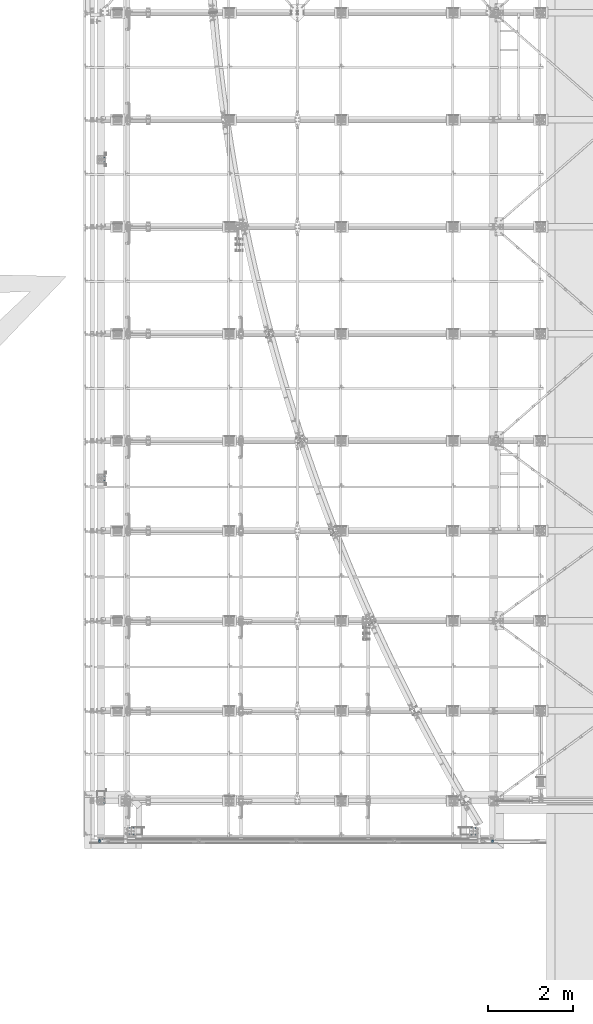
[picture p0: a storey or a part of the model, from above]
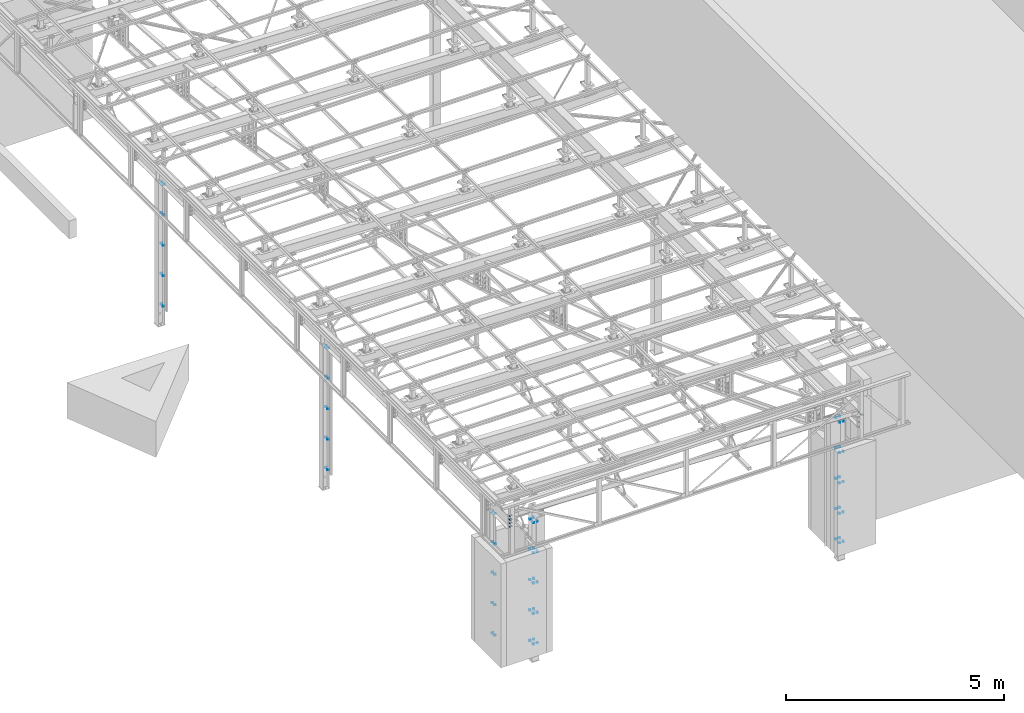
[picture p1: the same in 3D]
Properties of the parts of a building model (IFC2X3), part 1 of 13

# File
Description: ViewDefinition[CoordinationView_V2.0, QuantityTakeOffAddOnView], ExchangeRequirement[Structural, SurfaceGeometry], Option [BaseQuantities:On], Option [GridExport:On], Option [Assemblies:On], Option [Bolts:On], Option [Rebars:On], Option [PourObjects:Off], Option [Welds:On], Option [SurfaceTreatments:On], Option [LocationBy:0], Option [ViewColors:On], Option [SectionedSpine:Off], Option [PropertySets:On], Option [Export all:Off]
File name: VILQUIN_2021.ifc
Time: 2022-09-29T22:21:54
Author: BOINEAUP\Administrateur
Organization: Structural Designer
Written by: IFC Database Version: Work
Made in: Tekla Structures Educational 2021 Service Pack 6, IFC Export Version: 4.0.0.0 Dec 9 2021

# IfcBuildingStorey, Undefined
In: Undefined
Elevation: 0 mm

# IfcBeam: BLL100*50*2, LISSE
In: Undefined
Description: BLL100*50*2; Material: STEEL/E24-2
Tekla Commun - Finition: GALVA; Repère de pièce: L121; Repère d'assemblage: L121; Phase: 7; Profil: BLL100*50*2; Nom: LISSE; sets with these values: 2
Tekla Quantités - Poids: 4.6 kg; Volume: 0 m3; Surface supérieure totale: 0 m2; Surface par tonne: 129.2 m2; Surface nette: 0.6 m2; Hauteur: 100 mm; Largeur: 50 mm; Longueur: 2000 mm; sets with these values: 2
Pset_BeamCommon - LoadBearing: no; Reference: L121
BaseQuantities - Length: 2000 mm; OuterSurfaceArea: 0.600592 m2; NetVolume: 0.000592 m3; NetWeight: 4.6472 kg

# IfcBeam: BLL300*60*1.5 (2)
In: Undefined
Description: BLL300*60*1.5; Material: STEEL/E24-2
Tekla Commun - Finition: GALVA; Phase: 7; Profil: BLL300*60*1.5; Nom: LISSE; sets with these values: 2
Tekla Quantités - Volume: 0 m3; Surface supérieure totale: 0 m2; Hauteur: 300 mm; Largeur: 60 mm; sets with these values: 2
Pset_BeamCommon - LoadBearing: no
Name | Repère de pièce = Repère d'assemblage = Reference | Poids (kg) | Surface par tonne (m2) | Surface nette (m2) | Longueur (mm) | Length (mm) | OuterSurfaceArea (m2) | NetVolume (m3) | NetWeight (kg)
LISSE | L120 | 12.7 | 170.6 | 2.2 | 3000 | 3000 | 2.16108 | 0.00161325 | 12.664
LISSE | L119 | 14.4 | 170.8 | 2.5 | 3781.8 | 3781.82 | 2.46101 | 0.0018357 | 14.4102

# IfcBeam: BLU300*80*5 (6)
In: Undefined
Description: BLU300*80*5; Material: STEEL/E24-2
Tekla Commun - Finition: GRENAILLE-PEINT; Phase: 1; Profil: BLU300*80*5; sets with these values: 2
Tekla Quantités - Volume: 0 m3; Surface supérieure totale: 0 m2; Surface par tonne: 51.6 m2; Hauteur: 300 mm; Largeur: 80 mm; sets with these values: 2
Pset_BeamCommon - LoadBearing: no
Name | Repère de pièce = Reference | Repère d'assemblage | Nom | Poids (kg) | Surface nette (m2) | Longueur (mm) | Length (mm) | OuterSurfaceArea (m2) | NetVolume (m3) | NetWeight (kg)
LINTEAU | 889 | L5 | LINTEAU | 61.6 | 3.2 | 3488 | 3488 | 3.17858 | 0.007848 | 61.6068
LINTEAU | 888 | L4 | LINTEAU | 49.2 | 2.5 | 2788 | 2788 | 2.54158 | 0.006273 | 49.243
POTEAUX | 887 | P112 | POTEAUX | 87.9 | 4.4 | 4978.5 | 4978.52 | 4.53495 | 0.0112017 | 87.9331
POTEAUX | 886 | P111 | POTEAUX | 89.5 | 4.6 | 5067 | 5067.02 | 4.61549 | 0.0114008 | 89.4962
POTEAUX | 885 | P109 | POTEAUX | 89.7 | 4.6 | 5076.4 | 5076.4 | 4.62402 | 0.0114219 | 89.6619
POTEAUX | 884 | P110 | POTEAUX | 90.1 | 4.6 | 5099.1 | 5099.11 | 4.64469 | 0.011473 | 90.063

# IfcBeam: FPL255*8 (4)
In: Undefined
Description: FPL255*8; Material: STEEL/E24-2
Tekla Commun - Finition: GRENAILLE-PEINT; Phase: 1; Profil: FPL255*8; Nom: ATTACHE; sets with these values: 2
Tekla Quantités - Volume: 0 m3; Surface supérieure totale: 0 m2; Surface nette: 0.1 m2; Hauteur: 8 mm; Largeur: 255 mm; sets with these values: 2
Pset_BeamCommon - LoadBearing: no
Name | Repère de pièce = Repère d'assemblage = Reference | Poids (kg) | Surface par tonne (m2) | Longueur (mm) | Length (mm) | OuterSurfaceArea (m2) | NetVolume (m3) | NetWeight (kg)
ATTACHE | H54 | 3.2 | 34.1 | 78.3 | 78.2518 | 0.109281 | 0.000408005 | 3.20284
ATTACHE | H53 | 3 | 34.3 | 112.4 | 112.412 | 0.0987614 | 0.000367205 | 2.88256
ATTACHE | H52 | 3.2 | 34.1 | 132.4 | 132.412 | 0.109281 | 0.000408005 | 3.20284
ATTACHE | H51 | 3.4 | 34.1 | 132.4 | 132.376 | 0.114888 | 0.00042975 | 3.37354

# IfcBeam: FPL3*3600 (6)
In: Undefined
Description: FPL3*3600; Material: STEEL/S235JR
Tekla Commun - Finition: TOLGALVA; Phase: 5; Profil: FPL3*3600; Nom: FEUILLURE; sets with these values: 2
Tekla Quantités - Volume: 0 m3; Surface supérieure totale: 0 m2; Hauteur: 3 mm; Largeur: 3600 mm; sets with these values: 2
Pset_BeamCommon - LoadBearing: no
Name | Repère de pièce = Reference | Repère d'assemblage | Poids (kg) | Surface par tonne (m2) | Surface nette (m2) | Longueur (mm) = Length (mm) | OuterSurfaceArea (m2) | NetVolume (m3) | NetWeight (kg)
FEUILLURE | 1373 | F2 | 39.5 | 85.5 | 3.4 | 275 | 3.3796 | 0.0050328 | 39.5075
FEUILLURE | 1374 | F1 | 36.1 | 85.6 | 3.1 | 235 | 3.09136 | 0.0046008 | 36.1163
FEUILLURE | 1376 | F3 | 19.2 | 86.1 | 1.7 | 207 | 1.65736 | 0.0024516 | 19.2451
FEUILLURE | 1375 | F3 | 39.9 | 85.5 | 3.4 | 260 | 3.41563 | 0.0050868 | 39.9314
2 x FEUILLURE | F4 | F4 | 41.5 | 85.5 | 3.4 | 320 | 3.53813 | 0.0052704 | 41.3726

# IfcBeam: FPL370*6, ATTACHE
In: Undefined
Description: FPL370*6; Material: STEEL/E24-2
Tekla Commun - Finition: GRENAILLE-PEINT; Repère de pièce: H48; Repère d'assemblage: H48; Phase: 7; Profil: FPL370*6; Nom: ATTACHE; sets with these values: 2
Tekla Quantités - Poids: 3.4 kg; Volume: 0 m3; Surface supérieure totale: 0 m2; Surface par tonne: 44.5 m2; Surface nette: 0.2 m2; Hauteur: 6 mm; Largeur: 370 mm; Longueur: 83.9 mm; sets with these values: 2
Pset_BeamCommon - LoadBearing: no; Reference: H48
BaseQuantities - Length: 83.9094 mm; OuterSurfaceArea: 0.150577 m2; NetVolume: 0.000431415 m3; NetWeight: 3.38661 kg

# IfcBeam: FPL6*1050 (3)
In: Undefined
Description: FPL6*1050; Material: STEEL/E24-2
Tekla Commun - Finition: GRENAILLE-PEINT; Profil: FPL6*1050; sets with these values: 2
Tekla Quantités - Poids: 4.8 kg; Volume: 0 m3; Surface supérieure totale: 0 m2; Surface par tonne: 45.3 m2; Surface nette: 0.2 m2; Hauteur: 6 mm; Largeur: 1050 mm; Longueur: 55 mm; sets with these values: 2
Pset_BeamCommon - LoadBearing: no
BaseQuantities - Length: 55 mm; OuterSurfaceArea: 0.21852 m2; NetVolume: 0.00061425 m3; NetWeight: 4.82186 kg
Name | Repère de pièce = Reference | Repère d'assemblage | Phase
Unnamed | 862 | P32 | 3
2 x Unnamed | 863 | P36 | 1

# IfcBeam: FPL6*120 (18)
In: Undefined
Description: FPL6*120; Material: STEEL/E24-2
Tekla Commun - Finition: GRENAILLE-PEINT; Profil: FPL6*120; Nom: ATTACHE; sets with these values: 2
Tekla Quantités - Poids: 0.9 kg; Volume: 0 m3; Surface supérieure totale: 0 m2; Surface par tonne: 46.4 m2; Surface nette: 0 m2; Hauteur: 6 mm; Largeur: 120 mm; Longueur: 75 mm; sets with these values: 2
Pset_BeamCommon - LoadBearing: no
BaseQuantities - Length: 75.0488 mm
Name | Repère de pièce = Repère d'assemblage = Reference | Phase | OuterSurfaceArea (m2) | NetVolume (m3) | NetWeight (kg)
7 x ATTACHE | H49 | 3 | 0.0367986 | 0.000101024 | 0.793042
10 x ATTACHE | H49 | 1 | 0.0367986 | 0.000101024 | 0.793042
ATTACHE | H46 | 1 | 0.0361478 | 0.0000993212 | 0.779671

# IfcBeam: FPL6*50 (92)
In: Undefined
Description: FPL6*50; Material: STEEL/E24-2
Tekla Commun - Finition: GRENAILLE-PEINT; Repère de pièce: H47; Repère d'assemblage: H47; Profil: FPL6*50; Nom: ATTACHE; sets with these values: 2
Tekla Quantités - Poids: 0.3 kg; Volume: 0 m3; Surface supérieure totale: 0 m2; Surface par tonne: 49.1 m2; Surface nette: 0 m2; Hauteur: 6 mm; Largeur: 50 mm; sets with these values: 2
Pset_BeamCommon - LoadBearing: no; Reference: H47
BaseQuantities - OuterSurfaceArea: 0.0192984 m2; NetVolume: 0.000050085 m3; NetWeight: 0.393167 kg
Name | Phase | Longueur (mm) | Length (mm)
14 x ATTACHE | 2 | 111.9 | 111.95
14 x ATTACHE | 2 | 61 | 61
32 x ATTACHE | 1 | 61 | 61
32 x ATTACHE | 1 | 111.9 | 111.95

# IfcBeam: FPL6*86 (16)
In: Undefined
Description: FPL6*86; Material: STEEL/S235JR
Tekla Commun - Finition: GRENAILLE-PEINT; Repère de pièce: 861; Profil: FPL6*86; Nom: PLAT; sets with these values: 2
Tekla Quantités - Poids: 0.6 kg; Volume: 0 m3; Surface supérieure totale: 0 m2; Surface par tonne: 47 m2; Surface nette: 0 m2; Hauteur: 6 mm; Largeur: 86 mm; Longueur: 101 mm; sets with these values: 2
Pset_BeamCommon - LoadBearing: no; Reference: 861
BaseQuantities - Length: 101 mm; OuterSurfaceArea: 0.030656 m2; NetVolume: 0.000083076 m3; NetWeight: 0.652147 kg
Name | Repère d'assemblage | Phase
2 x PLAT | L22 | 3
2 x PLAT | L23 | 1
4 x PLAT | L22 | 1
2 x PLAT | L24 | 3
4 x PLAT | L21 | 1
2 x PLAT | L21 | 3

# IfcBeam: FPL6*90 (32)
In: Undefined
Description: FPL6*90; Material: STEEL/E24-2
Tekla Commun - Finition: GRENAILLE-PEINT; Repère de pièce: H45; Repère d'assemblage: H45; Phase: 1; Profil: FPL6*90; Nom: ATTACHE; sets with these values: 2
Tekla Quantités - Poids: 0.6 kg; Volume: 0 m3; Surface supérieure totale: 0 m2; Surface par tonne: 46.8 m2; Surface nette: 0 m2; Hauteur: 6 mm; Largeur: 90 mm; sets with these values: 2
Pset_BeamCommon - LoadBearing: no; Reference: H45
BaseQuantities - OuterSurfaceArea: 0.0331344 m2; NetVolume: 0.000090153 m3; NetWeight: 0.707701 kg
Name | Longueur (mm) | Length (mm)
16 x ATTACHE | 61 | 61
16 x ATTACHE | 111.9 | 111.95

# IfcBeam: FPL60*5 (8)
In: Undefined
Description: FPL60*5; Material: STEEL/S235JR
Tekla Commun - Finition: GRENAILLE-PEINT; Repère de pièce: H93; Repère d'assemblage: H93; Phase: 3; Profil: FPL60*5; Nom: ATTACHE; sets with these values: 2
Tekla Quantités - Poids: 0.5 kg; Volume: 0 m3; Surface supérieure totale: 0 m2; Surface par tonne: 56.4 m2; Surface nette: 0 m2; Hauteur: 5 mm; Largeur: 60 mm; Longueur: 110 mm; sets with these values: 2
Pset_BeamCommon - LoadBearing: no; Reference: H93
BaseQuantities - Length: 110 mm; OuterSurfaceArea: 0.02855 m2; NetVolume: 0.0000645 m3; NetWeight: 0.506325 kg

# IfcBeam: FPL8*140 (2)
In: Undefined
Description: FPL8*140; Material: STEEL/E24-2
Tekla Commun - Finition: GRENAILLE-PEINT; Repère de pièce: 1020; Phase: 1; Profil: FPL8*140; Nom: ATTACHE; sets with these values: 2
Tekla Quantités - Poids: 1.2 kg; Volume: 0 m3; Surface supérieure totale: 0 m2; Surface par tonne: 35.3 m2; Surface nette: 0 m2; Hauteur: 8 mm; Largeur: 140 mm; Longueur: 100 mm; sets with these values: 2
Pset_BeamCommon - LoadBearing: no; Reference: 1020
BaseQuantities - Length: 99.9683 mm; OuterSurfaceArea: 0.0445821 m2; NetVolume: 0.000160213 m3; NetWeight: 1.25767 kg
Name | Repère d'assemblage
ATTACHE | M13
ATTACHE | M14

# IfcBeam: FPL8*210 (15)
In: Undefined
Description: FPL8*210; Material: STEEL/S235JR
Tekla Commun - Finition: GRENAILLE-PEINT; Phase: 2; Profil: FPL8*210; Nom: GOUSSET; sets with these values: 2
Tekla Quantités - Volume: 0 m3; Surface supérieure totale: 0 m2; Surface nette: 0.1 m2; Hauteur: 8 mm; Largeur: 210 mm; sets with these values: 2
Pset_BeamCommon - LoadBearing: no
Name | Repère de pièce = Repère d'assemblage = Reference | Poids (kg) | Surface par tonne (m2) | Longueur (mm) | Length (mm) | OuterSurfaceArea (m2) | NetVolume (m3) | NetWeight (kg)
GOUSSET | G83 | 3.1 | 34.3 | 292.1 | 292.114 | 0.1071 | 0.000397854 | 3.12316
GOUSSET | G69 | 2.4 | 34.3 | 200.5 | 200.457 | 0.0822747 | 0.000304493 | 2.39027
GOUSSET | G80 | 2.1 | 34.9 | 200.5 | 200.457 | 0.0746716 | 0.000272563 | 2.13962
GOUSSET | G79 | 2.1 | 34.9 | 200.5 | 200.457 | 0.0746716 | 0.000272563 | 2.13962
GOUSSET | G82 | 2.1 | 34.9 | 200.5 | 200.457 | 0.0736308 | 0.000268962 | 2.11135
GOUSSET | G81 | 2.4 | 34.3 | 200.5 | 200.457 | 0.0812341 | 0.000300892 | 2.362
GOUSSET | G70 | 2.4 | 34.3 | 200.5 | 200.457 | 0.0822747 | 0.000304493 | 2.39027
GOUSSET | G78 | 2.1 | 34.9 | 200.5 | 200.457 | 0.0746716 | 0.000272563 | 2.13962
GOUSSET | G77 | 2.1 | 34.9 | 200.5 | 200.457 | 0.0746716 | 0.000272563 | 2.13962
GOUSSET | G71 | 2.4 | 34.3 | 200.5 | 200.457 | 0.0822747 | 0.000304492 | 2.39026
GOUSSET | G72 | 2.4 | 34.3 | 200.5 | 200.457 | 0.0822747 | 0.000304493 | 2.39027
GOUSSET | G73 | 2.4 | 34.3 | 200.5 | 200.457 | 0.0822747 | 0.000304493 | 2.39027
GOUSSET | G74 | 2.4 | 34.3 | 200.5 | 200.457 | 0.0822747 | 0.000304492 | 2.39026
GOUSSET | G76 | 2.1 | 34.9 | 200.5 | 200.457 | 0.0746716 | 0.000272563 | 2.13962
GOUSSET | G75 | 2.1 | 34.9 | 200.5 | 200.457 | 0.0746716 | 0.000272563 | 2.13962

# IfcBeam: FPL8*366, GOUSSET
In: Undefined
Description: FPL8*366; Material: STEEL/E24-2
Tekla Commun - Finition: GRENAILLE-PEINT; Repère de pièce: 1038; Repère d'assemblage: N36; Phase: 1; Profil: FPL8*366; Nom: GOUSSET; sets with these values: 2
Tekla Quantités - Poids: 4.8 kg; Volume: 0 m3; Surface supérieure totale: 0 m2; Surface par tonne: 33.8 m2; Surface nette: 0.2 m2; Hauteur: 8 mm; Largeur: 366 mm; Longueur: 210.1 mm; sets with these values: 2
Pset_BeamCommon - LoadBearing: no; Reference: 1038
BaseQuantities - Length: 210.089 mm; OuterSurfaceArea: 0.162949 m2; NetVolume: 0.000614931 m3; NetWeight: 4.8272 kg

# IfcBeam: HEA100 (70)
In: Undefined
Description: HEA100; Material: STEEL/E24-2
Tekla Commun - Finition: GRENAILLE-PEINT; Profil: HEA100; sets with these values: 2
Tekla Quantités - Volume: 0 m3; Surface supérieure totale: 0 m2; Surface par tonne: 33.7 m2; Largeur: 100 mm; sets with these values: 2
Pset_BeamCommon - LoadBearing: no
Name | Repère de pièce = Reference | Repère d'assemblage | Phase | Nom | Poids (kg) | Surface nette (m2) | Hauteur (mm) | Longueur (mm) | Length (mm) | OuterSurfaceArea (m2) | NetVolume (m3) | NetWeight (kg)
LISSE | 1322 | L32 | 5 | LISSE | 21.4 | 0.8 | 96 | 1286 | 1286 | 0.721446 | 0.002572 | 20.1902
LISSE | 1322 | L117 | 5 | LISSE | 21.4 | 0.8 | 96 | 1286 | 1286 | 0.721446 | 0.002572 | 20.1902
2 x SUPPORT | 1323 | E6 | 4 | SUPPORT | 12.7 | 0.3 | 96 | 758.4 | 758.381 | 0.425452 | 0.00150504 | 11.8145
2 x SUPPORT | 1324 | E7 | 4 | SUPPORT | 28.7 | 1 | 96 | 1724.6 | 1724.64 | 0.967523 | 0.00343756 | 26.9848
12 x ATTACHE | H79 | H79 | 2 | ATTACHE | 5 | 0.1 | 76 | 300 | 299.999 | 0.168299 | 0.000341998 | 2.68469
9 x LISSE | 1327 | L118 | 2 | LISSE | 21.4 | 0.8 | 96 | 1286 | 1286 | 0.721446 | 0.002572 | 20.1902
9 x ATTACHE | H80 | H80 | 2 | ATTACHE | 5 | 0.2 | 96 | 300 | 299.999 | 0.168299 | 0.000599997 | 4.70998
TRAVERSE | N62 | N62 | 2 | TRAVERSE | 34.9 | 1.2 | 96 | 2095 | 2095 | 1.1753 | 0.00404585 | 31.7599
TRAVERSE | N61 | N61 | 2 | TRAVERSE | 45.3 | 1.6 | 96 | 2723.3 | 2723.33 | 1.52779 | 0.00530257 | 41.6251
3 x TRAVERSE | N60 | N60 | 2 | TRAVERSE | 44.4 | 1.5 | 96 | 2669.3 | 2669.3 | 1.49748 | 0.00518293 | 40.686
4 x TRAVERSE | N56 | N56 | 2 | TRAVERSE | 44.4 | 1.5 | 96 | 2669.3 | 2669.3 | 1.49748 | 0.00518293 | 40.686
TRAVERSE | N59 | N59 | 2 | TRAVERSE | 43.6 | 1.5 | 96 | 2619.3 | 2619.3 | 1.46943 | 0.00508293 | 39.901
TRAVERSE | N58 | N58 | 2 | TRAVERSE | 44.4 | 1.5 | 96 | 2669.3 | 2669.3 | 1.49748 | 0.00518293 | 40.686
TRAVERSE | N57 | N57 | 2 | TRAVERSE | 43.6 | 1.5 | 96 | 2619.3 | 2619.3 | 1.46943 | 0.00508293 | 39.901
LISSE | 1343 | L52 | 2 | LISSE | 21.7 | 0.8 | 96 | 1310 | 1310 | 0.73491 | 0.00262 | 20.567
4 x LISSE | 1326 | L52 | 2 | LISSE | 21.7 | 0.8 | 96 | 1310 | 1310 | 0.73491 | 0.00262 | 20.567
LISSE | 1342 | L52 | 2 | LISSE | 21.7 | 0.8 | 96 | 1310 | 1310 | 0.73491 | 0.00262 | 20.567
TRAVERSE | N55 | N55 | 1 | TRAVERSE | 42.8 | 1.5 | 96 | 2570 | 2570 | 1.44177 | 0.00500001 | 39.2501
3 x TRAVERSE | N54 | N54 | 1 | TRAVERSE | 19.5 | 0.6 | 96 | 1170 | 1170 | 0.65637 | 0.00220876 | 17.3388
3 x TRAVERSE | N54 | N54 | 1 | TRAVERSE | 19.5 | 0.6 | 96 | 1170 | 1170 | 0.65637 | 0.00220876 | 17.3387
TRAVERSE | N53 | N53 | 1 | TRAVERSE | 42.8 | 1.5 | 96 | 2570 | 2570 | 1.44177 | 0.00500877 | 39.3188
TRAVERSE | N52 | N52 | 1 | TRAVERSE | 42.8 | 1.5 | 96 | 2570 | 2570 | 1.44177 | 0.00500877 | 39.3188
TRAVERSE | N51 | N51 | 1 | TRAVERSE | 35.9 | 1.2 | 96 | 2152.1 | 2152.05 | 1.2073 | 0.00417783 | 32.7959
TRAVERSE | N51 | N51 | 1 | TRAVERSE | 35.9 | 1.2 | 96 | 2152.1 | 2152.05 | 1.2073 | 0.00417764 | 32.7945
4 x TRAVERSE | N50 | N50 | 1 | TRAVERSE | 41.9 | 1.5 | 96 | 2520 | 2520 | 1.41372 | 0.00490877 | 38.5339
TRAVERSE | N50 | N50 | 1 | TRAVERSE | 41.9 | 1.5 | 96 | 2520 | 2520 | 1.41372 | 0.00490878 | 38.5339

# IfcBeam: HEA120 (24)
In: Undefined
Description: HEA120; Material: STEEL/E24-2
Tekla Commun - Finition: GRENAILLE-PEINT; Profil: HEA120; sets with these values: 2
Tekla Quantités - Volume: 0 m3; Surface supérieure totale: 0 m2; Surface par tonne: 33.6 m2; Hauteur: 114 mm; Largeur: 120 mm; sets with these values: 2
Pset_BeamCommon - LoadBearing: no
Name | Repère de pièce = Reference | Repère d'assemblage | Phase | Nom | Poids (kg) | Surface nette (m2) | Longueur (mm) | Length (mm) | OuterSurfaceArea (m2) | NetVolume (m3) | NetWeight (kg)
LISSE | 590 | L1 | 3 | LISSE | 28.3 | 1 | 1424.2 | 1424.21 | 0.949948 | 0.00343234 | 26.9439
LISSE | 591 | L2 | 3 | LISSE | 23.3 | 0.8 | 1175 | 1175.05 | 0.783758 | 0.00283187 | 22.2302
LISSE | 592 | L3 | 3 | LISSE | 33.2 | 1.2 | 1673.4 | 1673.38 | 1.11614 | 0.00403284 | 31.6578
LISSE | 589 | L116 | 3 | LISSE | 9.7 | 0.3 | 490 | 490 | 0.32683 | 0.0011809 | 9.27006
2 x LISSE | 584 | L80 | 3 | LISSE | 9.7 | 0.3 | 490 | 490 | 0.32683 | 0.0011809 | 9.27006
2 x LISSE | 584 | L80 | 3 | LISSE | 9.7 | 0.3 | 490 | 490 | 0.32683 | 0.0011809 | 9.27007
3 x LISSE | 584 | L115 | 3 | LISSE | 9.7 | 0.3 | 490 | 490 | 0.32683 | 0.0011809 | 9.27007
LISSE | 588 | L80 | 3 | LISSE | 9.7 | 0.3 | 490 | 490 | 0.32683 | 0.0011809 | 9.27007
LISSE | 587 | L80 | 3 | LISSE | 9.7 | 0.3 | 490 | 490 | 0.32683 | 0.0011809 | 9.27006
LISSE | 586 | L115 | 3 | LISSE | 9.7 | 0.3 | 490 | 490 | 0.32683 | 0.0011809 | 9.27007
LISSE | 585 | L115 | 3 | LISSE | 9.7 | 0.3 | 490 | 490 | 0.32683 | 0.0011809 | 9.27007
LISSE | 585 | L115 | 3 | LISSE | 9.7 | 0.3 | 490 | 490 | 0.32683 | 0.0011809 | 9.27006
MONTANT | 583 | M13 | 1 | MONTANT | 29.9 | 1.1 | 1509.5 | 1509.49 | 1.00683 | 0.00363787 | 28.5573
MONTANT | 580 | M14 | 1 | MONTANT | 37.3 | 1.2 | 1878 | 1878 | 1.25263 | 0.00452598 | 35.5289
MONTANT | 579 | M5 | 1 | MONTANT | 38.3 | 1.5 | 1930.7 | 1930.71 | 1.28778 | 0.00464853 | 36.4909
MONTANT | 581 | M3 | 1 | MONTANT | 37.3 | 1.2 | 1878 | 1878 | 1.25263 | 0.00452598 | 35.5289
MONTANT | 581 | M2 | 1 | MONTANT | 37.3 | 1.2 | 1878 | 1878 | 1.25263 | 0.00452598 | 35.5289
2 x MONTANT | 582 | M4 | 1 | MONTANT | 37.3 | 1.2 | 1878 | 1878 | 1.25263 | 0.00452598 | 35.5289
MONTANT | 581 | M1 | 1 | MONTANT | 37.3 | 1.2 | 1878 | 1878 | 1.25263 | 0.00452598 | 35.5289

# IfcBeam: HEA140 (18)
In: Undefined
Description: HEA140; Material: STEEL/E24-2
Tekla Commun - Finition: GRENAILLE-PEINT; Profil: HEA140; sets with these values: 2
Tekla Quantités - Volume: 0 m3; Surface supérieure totale: 0 m2; Surface par tonne: 32.2 m2; Hauteur: 133 mm; Largeur: 140 mm; sets with these values: 2
Pset_BeamCommon - LoadBearing: no
Name | Repère de pièce = Reference | Repère d'assemblage | Phase | Nom | Poids (kg) | Surface nette (m2) | Longueur (mm) | Length (mm) | OuterSurfaceArea (m2) | NetVolume (m3) | NetWeight (kg)
ATTACHE | 873 | P21 | 3 | ATTACHE | 29.9 | 1 | 1215.4 | 1215.43 | 0.965051 | 0.00366817 | 28.7951
ATTACHE | 873 | P18 | 1 | ATTACHE | 29.9 | 1 | 1215.4 | 1215.43 | 0.965051 | 0.00366817 | 28.7951
TRAVERSE | N32 | N32 | 1 | TRAVERSE | 50.6 | 1.6 | 2053.3 | 2053.33 | 1.63034 | 0.00600637 | 47.15
TRAVERSE | N33 | N33 | 1 | TRAVERSE | 50.6 | 1.6 | 2053.3 | 2053.34 | 1.63035 | 0.00600639 | 47.1502
TRAVERSE | N34 | N34 | 1 | TRAVERSE | 50.6 | 1.6 | 2053.3 | 2053.33 | 1.63034 | 0.00600639 | 47.1502
TRAVERSE | N34 | N34 | 1 | TRAVERSE | 50.6 | 1.6 | 2053.3 | 2053.33 | 1.63034 | 0.00600627 | 47.1492
TRAVERSE | N32 | N32 | 1 | TRAVERSE | 50.6 | 1.6 | 2053.3 | 2053.33 | 1.63034 | 0.0060062 | 47.1487
2 x TRAVERSE | N35 | N35 | 1 | TRAVERSE | 50.6 | 1.6 | 2053.3 | 2053.33 | 1.63034 | 0.00600627 | 47.1492
TRAVERSE | N33 | N33 | 1 | TRAVERSE | 50.6 | 1.6 | 2053.3 | 2053.34 | 1.63035 | 0.00600622 | 47.1488
ATTACHE | 873 | P20 | 1 | ATTACHE | 29.9 | 1 | 1215.4 | 1215.43 | 0.965051 | 0.00366817 | 28.7951
ATTACHE | 873 | P19 | 1 | ATTACHE | 29.9 | 1 | 1215.4 | 1215.43 | 0.965051 | 0.00366817 | 28.7951
ATTACHE | 871 | P120 | 3 | ATTACHE | 24.1 | 0.8 | 977.8 | 977.8 | 0.776373 | 0.002951 | 23.1654
ATTACHE | 870 | P121 | 3 | ATTACHE | 35.9 | 1.2 | 1453.1 | 1453.06 | 1.15373 | 0.00438534 | 34.4249
ATTACHE | 869 | P114 | 3 | ATTACHE | 29.9 | 1 | 1215.4 | 1215.43 | 0.965051 | 0.00366817 | 28.7951
ATTACHE | 873 | P115 | 1 | ATTACHE | 29.9 | 1 | 1215.4 | 1215.43 | 0.965051 | 0.00366817 | 28.7951
ATTACHE | 873 | P116 | 1 | ATTACHE | 29.9 | 1 | 1215.4 | 1215.43 | 0.965051 | 0.00366817 | 28.7951
ATTACHE | 872 | P117 | 1 | ATTACHE | 24.7 | 0.8 | 1003.4 | 1003.37 | 0.796676 | 0.00302817 | 23.7711

# IfcBeam: HEA160 (26)
In: Undefined
Description: HEA160
Tekla Commun - Profil: HEA160; sets with these values: 2
Tekla Quantités - Volume: 0 m3; Surface supérieure totale: 0 m2; Surface par tonne: 29.8 m2; Hauteur: 152 mm; Largeur: 160 mm; sets with these values: 2
Pset_BeamCommon - LoadBearing: no
Name | Material | Finition | Repère de pièce = Reference | Repère d'assemblage | Phase | Nom | Poids (kg) | Surface nette (m2) | Longueur (mm) | Length (mm) | OuterSurfaceArea (m2) | NetVolume (m3) | NetWeight (kg)
2 x SUPPORT | STEEL/S235JR | GALVANISE | 1361 | E3 | 4 | SUPPORT | 49.9 | 1.5 | 1640 | 1640 | 1.48584 | 0.00604176 | 47.4278
ATTACHE | STEEL/E24-2 | GRENAILLE-PEINT | 1352 | H83 | 2 | ATTACHE | 12.7 | 0.3 | 415.7 | 415.659 | 0.376587 | 0.00151743 | 11.9118
ATTACHE | STEEL/E24-2 | GRENAILLE-PEINT | 1353 | H84 | 2 | ATTACHE | 13.9 | 0.3 | 456.7 | 456.712 | 0.413781 | 0.00166887 | 13.1006
ATTACHE | STEEL/E24-2 | GRENAILLE-PEINT | 1354 | H85 | 2 | ATTACHE | 15 | 0.5 | 492.7 | 492.651 | 0.446342 | 0.0018015 | 14.1417
ATTACHE | STEEL/E24-2 | GRENAILLE-PEINT | 1355 | H86 | 2 | ATTACHE | 16 | 0.5 | 523.9 | 523.858 | 0.474615 | 0.00191672 | 15.0463
ATTACHE | STEEL/E24-2 | GRENAILLE-PEINT | 1356 | H87 | 2 | ATTACHE | 17.6 | 0.5 | 577 | 577.015 | 0.522775 | 0.00211323 | 16.5888
ATTACHE | STEEL/E24-2 | GRENAILLE-PEINT | 1357 | H88 | 2 | ATTACHE | 18.2 | 0.6 | 597.8 | 597.781 | 0.54159 | 0.00219015 | 17.1927
ATTACHE | STEEL/E24-2 | GRENAILLE-PEINT | 1358 | H89 | 2 | ATTACHE | 18.7 | 0.6 | 613.2 | 613.162 | 0.555524 | 0.00224727 | 17.6411
ATTACHE | STEEL/E24-2 | GRENAILLE-PEINT | 1351 | H82 | 2 | ATTACHE | 19 | 0.6 | 625.2 | 625.188 | 0.56642 | 0.00228025 | 17.9
ATTACHE | STEEL/E24-2 | GRENAILLE-PEINT | 1359 | H90 | 2 | ATTACHE | 19 | 0.6 | 623.3 | 623.317 | 0.564725 | 0.00228517 | 17.9386
ATTACHE | STEEL/E24-2 | GRENAILLE-PEINT | 1350 | H81 | 2 | ATTACHE | 19.1 | 0.6 | 628.2 | 628.185 | 0.569136 | 0.0023036 | 18.0832
ATTACHE | STEEL/E24-2 | GRENAILLE-PEINT | 1360 | H91 | 2 | ATTACHE | 16.8 | 0.5 | 550.9 | 550.925 | 0.499138 | 0.00201674 | 15.8314
2 x EMPANNON | STEEL/E24-2 | GRENAILLE-PEINT | 1349 | N46 | 2 | EMPANNON | 13.6 | 0.3 | 446.2 | 446.169 | 0.404229 | 0.00164369 | 12.9029
2 x EMPANNON | STEEL/E24-2 | GRENAILLE-PEINT | 1349 | N44 | 2 | EMPANNON | 13.6 | 0.3 | 446.2 | 446.169 | 0.404229 | 0.00164369 | 12.9029
4 x EMPANNON | STEEL/E24-2 | GRENAILLE-PEINT | 1349 | N49 | 2 | EMPANNON | 13.6 | 0.3 | 446.2 | 446.169 | 0.404229 | 0.00164369 | 12.9029
3 x EMPANNON | STEEL/E24-2 | GRENAILLE-PEINT | 1349 | N45 | 2 | EMPANNON | 13.6 | 0.3 | 446.2 | 446.169 | 0.404229 | 0.00164369 | 12.9029
2 x EMPANNON | STEEL/E24-2 | GRENAILLE-PEINT | 1348 | N44 | 2 | EMPANNON | 13.9 | 0.3 | 451.7 | 451.669 | 0.409212 | 0.00166395 | 13.062

# IfcBeam: HEA180 (11)
In: Undefined
Description: HEA180; Material: STEEL/E24-2
Tekla Commun - Finition: GRENAILLE-PEINT; Profil: HEA180; sets with these values: 2
Tekla Quantités - Volume: 0 m3; Surface supérieure totale: 0 m2; Surface par tonne: 28.8 m2; Hauteur: 171 mm; Largeur: 180 mm; sets with these values: 2
Pset_BeamCommon - LoadBearing: no
Name | Repère de pièce = Reference | Repère d'assemblage | Phase | Nom | Poids (kg) | Surface nette (m2) | Longueur (mm) | Length (mm) | OuterSurfaceArea (m2) | NetVolume (m3) | NetWeight (kg)
POTEAUX | 382 | P130 | 2 | POTEAUX | 143.2 | 4.1 | 4028 | 4028 | 4.10856 | 0.0174493 | 136.977
POTEAUX | 383 | P131 | 2 | POTEAUX | 153.5 | 4.4 | 4316 | 4316 | 4.40232 | 0.0186969 | 146.771
3 x POTEAUX | 384 | P125 | 2 | POTEAUX | 142.8 | 4.1 | 4016 | 4016 | 4.09632 | 0.0173973 | 136.569
2 x ATTACHE | H10 | H10 | 1 | ATTACHE | 5 | 0.2 | 140 | 140 | 0.1428 | 0.00060648 | 4.76087
POTEAUX | 380 | P129 | 2 | POTEAUX | 127.7 | 3.8 | 3590.7 | 3590.67 | 3.66248 | 0.0155548 | 122.105
POTEAUX | 379 | P128 | 2 | POTEAUX | 127.7 | 3.8 | 3590.7 | 3590.67 | 3.66248 | 0.0155548 | 122.105
POTEAUX | 378 | P127 | 2 | POTEAUX | 142.8 | 4.1 | 4016 | 4016 | 4.09632 | 0.0173973 | 136.569
POTEAUX | 377 | P126 | 2 | POTEAUX | 142.8 | 4.1 | 4016 | 4016 | 4.09632 | 0.0173973 | 136.569

# IfcBeam: HEA200 (3)
In: Undefined
Description: HEA200; Material: STEEL/E24-2
Tekla Commun - Finition: GRENAILLE-PEINT; Repère de pièce: 376; Repère d'assemblage: P124; Phase: 2; Profil: HEA200; Nom: POTEAUX; sets with these values: 2
Tekla Quantités - Poids: 151.6 kg; Volume: 0 m3; Surface supérieure totale: 0 m2; Surface par tonne: 27 m2; Surface nette: 4.1 m2; Hauteur: 190 mm; Largeur: 200 mm; Longueur: 3590.7 mm; sets with these values: 2
Pset_BeamCommon - LoadBearing: no; Reference: 376
BaseQuantities - Length: 3590.67 mm; OuterSurfaceArea: 4.09336 m2; NetVolume: 0.0183304 m3; NetWeight: 143.893 kg

# IfcBeam: HEA220 (3)
In: Undefined
Description: HEA220; Material: STEEL/E24-2
Tekla Commun - Finition: GRENAILLE-PEINT; Phase: 1; Profil: HEA220; Nom: POTEAUX; sets with these values: 2
Tekla Quantités - Volume: 0 m3; Surface supérieure totale: 0 m2; Surface par tonne: 25 m2; Hauteur: 210 mm; Largeur: 220 mm; sets with these values: 2
Pset_BeamCommon - LoadBearing: no
Name | Repère de pièce = Reference | Repère d'assemblage | Poids (kg) | Surface nette (m2) | Longueur (mm) = Length (mm) | OuterSurfaceArea (m2) | NetVolume (m3) | NetWeight (kg)
POTEAUX | 131 | P118 | 195.6 | 5 | 3876 | 4.88376 | 0.0238607 | 187.306
POTEAUX | 130 | N5 | 91.3 | 2.3 | 1808 | 2.27808 | 0.01113 | 87.3709
POTEAUX | 129 | P123 | 316.8 | 8.1 | 6276 | 7.90776 | 0.038032 | 298.551

# IfcBeam: IPE120 (5)
In: Undefined
Description: IPE120; Material: STEEL/E24-2
Tekla Commun - Finition: GRENAILLE-PEINT; Phase: 3; Profil: IPE120; Nom: PANNE; sets with these values: 2
Tekla Quantités - Volume: 0 m3; Surface supérieure totale: 0 m2; Surface par tonne: 45.8 m2; Hauteur: 120 mm; Largeur: 64 mm; sets with these values: 2
Pset_BeamCommon - LoadBearing: no
Name | Repère de pièce = Repère d'assemblage = Reference | Poids (kg) | Surface nette (m2) | Longueur (mm) | Length (mm) | OuterSurfaceArea (m2) | NetVolume (m3) | NetWeight (kg)
2 x PANNE | K106 | 60.2 | 2.8 | 5811.4 | 5811.41 | 2.76042 | 0.00736395 | 57.807
2 x PANNE | K107 | 40.1 | 1.9 | 3865.9 | 3865.91 | 1.83631 | 0.00487574 | 38.2745
PANNE | K107 | 39.9 | 1.9 | 3864.9 | 3864.91 | 1.83583 | 0.00487446 | 38.2645

# IfcBeam: IPE200 (18)
In: Undefined
Description: IPE200; Material: STEEL/E24-2
Tekla Commun - Finition: GRENAILLE-PEINT; Profil: IPE200; Nom: POTEAUX; sets with these values: 2
Tekla Quantités - Volume: 0 m3; Surface supérieure totale: 0 m2; Surface par tonne: 34.3 m2; Hauteur: 200 mm; Largeur: 100 mm; sets with these values: 2
Pset_BeamCommon - LoadBearing: no
Name | Repère de pièce = Reference | Repère d'assemblage | Phase | Poids (kg) | Surface nette (m2) | Longueur (mm) | Length (mm) | OuterSurfaceArea (m2) | NetVolume (m3) | NetWeight (kg)
POTEAUX | 113 | P21 | 3 | 114.7 | 4.1 | 5127.6 | 5127.57 | 3.93798 | 0.0139716 | 109.677
POTEAUX | 112 | P20 | 1 | 114.7 | 4.1 | 5127.6 | 5127.57 | 3.93798 | 0.0139716 | 109.677
POTEAUX | 111 | P19 | 1 | 114.7 | 4.1 | 5127.6 | 5127.57 | 3.93798 | 0.0139716 | 109.677
POTEAUX | 110 | P18 | 1 | 105.8 | 3.7 | 4727.6 | 4727.57 | 3.63078 | 0.0128817 | 101.121
POTEAUX | 109 | P17 | 1 | 134.6 | 4.8 | 6018 | 6018 | 4.62182 | 0.0163978 | 128.723
POTEAUX | 108 | P15 | 1 | 132.5 | 4.6 | 5923 | 5923 | 4.54886 | 0.016139 | 126.691
POTEAUX | 108 | P14 | 1 | 132.5 | 4.6 | 5923 | 5923 | 4.54886 | 0.016139 | 126.691
POTEAUX | 108 | P16 | 1 | 132.5 | 4.6 | 5923 | 5923 | 4.54886 | 0.016139 | 126.691
3 x POTEAUX | 107 | P13 | 1 | 140.1 | 4.8 | 6263 | 6263 | 4.80998 | 0.0170654 | 133.964
POTEAUX | 106 | P12 | 1 | 140.1 | 4.8 | 6263 | 6263 | 4.80998 | 0.0170654 | 133.964
POTEAUX | 105 | P11 | 1 | 140.1 | 4.8 | 6263 | 6263 | 4.80998 | 0.0170654 | 133.964
POTEAUX | 104 | P10 | 1 | 140.1 | 4.8 | 6263 | 6263 | 4.80998 | 0.0170654 | 133.964
POTEAUX | 103 | P9 | 1 | 140.1 | 4.8 | 6263 | 6263 | 4.80998 | 0.0170654 | 133.964
POTEAUX | 102 | P8 | 1 | 140.1 | 4.8 | 6263 | 6263 | 4.80998 | 0.0170654 | 133.964
POTEAUX | 101 | P7 | 1 | 140.1 | 4.8 | 6263 | 6263 | 4.80998 | 0.0170654 | 133.964
POTEAUX | 100 | P6 | 1 | 140.1 | 4.8 | 6263 | 6263 | 4.80998 | 0.0170654 | 133.964

# IfcBeam: IPE220 (6)
In: Undefined
Description: IPE220; Material: STEEL/S235JR
Tekla Commun - Finition: GALVANISE; Phase: 2; Profil: IPE220; Nom: SOLIVE; sets with these values: 2
Tekla Quantités - Volume: 0 m3; Surface supérieure totale: 0.4 m2; Surface par tonne: 32.3 m2; Hauteur: 220 mm; Largeur: 110 mm; sets with these values: 2
Pset_BeamCommon - LoadBearing: no
Name | Repère de pièce = Repère d'assemblage = Reference | Poids (kg) | Surface nette (m2) | Longueur (mm) = Length (mm) | OuterSurfaceArea (m2) | NetVolume (m3) | NetWeight (kg)
3 x SOLIVE | S95 | 64.6 | 2.1 | 2465 | 2.09032 | 0.00792113 | 62.1809
SOLIVE | S97 | 100.5 | 3.3 | 3832.5 | 3.24996 | 0.012205 | 95.8091
SOLIVE | S98 | 100.9 | 3.3 | 3847.5 | 3.26268 | 0.0121427 | 95.3199
SOLIVE | S96 | 129.7 | 4.3 | 4945 | 4.19336 | 0.0157799 | 123.873

# IfcBeam: IPE240 (8)
In: Undefined
Description: IPE240; Material: STEEL/E24-2
Tekla Commun - Finition: GRENAILLE-PEINT; Profil: IPE240; Nom: EMPANNON; sets with these values: 2
Tekla Quantités - Volume: 0 m3; Surface supérieure totale: 0 m2; Surface par tonne: 30 m2; Hauteur: 240 mm; Largeur: 120 mm; sets with these values: 2
Pset_BeamCommon - LoadBearing: no
Name | Repère de pièce = Reference | Repère d'assemblage | Phase | Poids (kg) | Surface nette (m2) | Longueur (mm) | Length (mm) | OuterSurfaceArea (m2) | NetVolume (m3) | NetWeight (kg)
EMPANNON | 375 | K86 | 2 | 284.7 | 8.7 | 9278.3 | 9278.27 | 8.55457 | 0.0342159 | 268.595
EMPANNON | K92 | K92 | 1 | 230 | 7.1 | 7496 | 7496.01 | 6.91132 | 0.0277686 | 217.983
EMPANNON | 373 | K89 | 1 | 230.4 | 7.1 | 7507.2 | 7507.21 | 6.92165 | 0.0277775 | 218.053
EMPANNON | K91 | K91 | 1 | 230 | 7.1 | 7496 | 7496.01 | 6.91132 | 0.0277686 | 217.983
EMPANNON | 371 | K88 | 1 | 230.4 | 7.1 | 7507.2 | 7507.21 | 6.92165 | 0.0277775 | 218.053
EMPANNON | 369 | K58 | 1 | 230 | 7.1 | 7496 | 7496.01 | 6.91132 | 0.0277686 | 217.983
EMPANNON | 368 | K57 | 1 | 223.8 | 6.8 | 7293.4 | 7293.4 | 6.72452 | 0.0269986 | 211.939
EMPANNON | 370 | K87 | 1 | 230.4 | 7.1 | 7507.2 | 7507.21 | 6.92165 | 0.0277775 | 218.053

# IfcBeam: IPE270 (7)
In: Undefined
Description: IPE270
Tekla Commun - Finition: GRENAILLE-PEINT; Profil: IPE270; sets with these values: 2
Tekla Quantités - Volume: 0 m3; Surface supérieure totale: 0 m2; Surface par tonne: 28.9 m2; Hauteur: 270 mm; Largeur: 135 mm; sets with these values: 2
Pset_BeamCommon - LoadBearing: no
Name | Material | Repère de pièce = Reference | Repère d'assemblage | Phase | Nom | Poids (kg) | Surface nette (m2) | Longueur (mm) | Length (mm) | OuterSurfaceArea (m2) | NetVolume (m3) | NetWeight (kg)
SUPPORT | STEEL/S235JR | 1014 | L32 | 5 | SUPPORT | 5.2 | 0.2 | 144.7 | 144.7 | 0.150633 | 0.000636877 | 4.99948
PANNE | STEEL/E24-2 | 1015 | K94 | 3 | PANNE | 5.5 | 0.1 | 152.1 | 152.07 | 0.158305 | 0.000564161 | 4.42867
EMPANNON | STEEL/E24-2 | 1016 | K95 | 1 | EMPANNON | 268.6 | 8.1 | 7454.5 | 7454.47 | 7.7601 | 0.0327979 | 257.464
EMPANNON | STEEL/E24-2 | K96 | K96 | 1 | EMPANNON | 344 | 10.1 | 9548.4 | 9548.44 | 9.93992 | 0.0418122 | 328.226
2 x EMPANNON | STEEL/E24-2 | K97 | K97 | 1 | EMPANNON | 344 | 10.1 | 9548.4 | 9548.44 | 9.93992 | 0.0418122 | 328.226
EMPANNON | STEEL/E24-2 | K98 | K98 | 1 | EMPANNON | 344 | 10.1 | 9548.4 | 9548.44 | 9.93992 | 0.0418122 | 328.226

# IfcBeam: IPE330 (13)
In: Undefined
Description: IPE330
Tekla Commun - Profil: IPE330; sets with these values: 2
Tekla Quantités - Surface par tonne: 25.5 m2; Hauteur: 330 mm; Largeur: 160 mm; sets with these values: 2
Pset_BeamCommon - LoadBearing: no
Name | Material | Finition | Repère de pièce = Reference | Repère d'assemblage | Phase | Nom | Poids (kg) | Volume (m3) | Surface supérieure totale (m2) | Surface nette (m2) | Longueur (mm) = Length (mm) | OuterSurfaceArea (m2) | NetVolume (m3) | NetWeight (kg)
2 x SUPPORT | STEEL/S235JR | GALVANISE | 170 | E3 | 4 | SUPPORT | 19.9 | 0 | 0.1 | 0.5 | 407.5 | 0.511005 | 0.00243787 | 19.1373
EMPANNON | STEEL/S235JR | GRENAILLE-PEINT | 169 | K36 | 2 | EMPANNON | 633.5 | 0.1 | 0 | 16.6 | 12891.4 | 16.1658 | 0.0770617 | 604.934
EMPANNON | STEEL/S235JR | GRENAILLE-PEINT | 169 | K35 | 2 | EMPANNON | 633.5 | 0.1 | 0 | 16.6 | 12891.4 | 16.1658 | 0.0770617 | 604.934
2 x EMPANNON | STEEL/S235JR | GRENAILLE-PEINT | 168 | K33 | 2 | EMPANNON | 633.5 | 0.1 | 0 | 16.6 | 12891.4 | 16.1658 | 0.0770617 | 604.934
EMPANNON | STEEL/S235JR | GRENAILLE-PEINT | 168 | K34 | 2 | EMPANNON | 633.5 | 0.1 | 0 | 16.6 | 12891.4 | 16.1658 | 0.0770617 | 604.934
EMPANNON | STEEL/E24-2 | GRENAILLE-PEINT | K32 | K32 | 3 | EMPANNON | 564.9 | 0.1 | 0 | 14.7 | 11494.8 | 14.4145 | 0.0685265 | 537.933
EMPANNON | STEEL/E24-2 | GRENAILLE-PEINT | K31 | K31 | 3 | EMPANNON | 564.7 | 0.1 | 0 | 14.7 | 11491.1 | 14.4099 | 0.0683817 | 536.797
3 x EMPANNON | STEEL/E24-2 | GRENAILLE-PEINT | K30 | K30 | 3 | EMPANNON | 564.9 | 0.1 | 0 | 14.7 | 11494.8 | 14.4145 | 0.0685265 | 537.933
EMPANNON | STEEL/E24-2 | GRENAILLE-PEINT | K29 | K29 | 3 | EMPANNON | 564.9 | 0.1 | 0 | 14.7 | 11494.8 | 14.4145 | 0.0685265 | 537.933

# IfcBeam: IPE360, EMPANNON
In: Undefined
Description: IPE360; Material: STEEL/E24-2
Tekla Commun - Finition: GRENAILLE-PEINT; Repère de pièce: 578; Repère d'assemblage: K99; Phase: 1; Profil: IPE360; Nom: EMPANNON; sets with these values: 2
Tekla Quantités - Poids: 672.6 kg; Volume: 0.1 m3; Surface supérieure totale: 0 m2; Surface par tonne: 23.8 m2; Surface nette: 16.1 m2; Hauteur: 360 mm; Largeur: 170 mm; Longueur: 11786.1 mm; sets with these values: 2
Pset_BeamCommon - LoadBearing: no; Reference: 578
BaseQuantities - Length: 11786.1 mm; OuterSurfaceArea: 15.9466 m2; NetVolume: 0.0811331 m3; NetWeight: 636.895 kg

# IfcBeam: IPE400 (13)
In: Undefined
Description: IPE400; Material: STEEL/E24-2
Tekla Commun - Finition: GRENAILLE-PEINT; Profil: IPE400; sets with these values: 2
Tekla Quantités - Volume: 0.1 m3; Surface par tonne: 22.1 m2; Hauteur: 400 mm; Largeur: 180 mm; sets with these values: 2
Pset_BeamCommon - LoadBearing: no
Name | Repère de pièce = Reference | Repère d'assemblage | Phase | Nom | Poids (kg) | Surface supérieure totale (m2) | Surface nette (m2) | Longueur (mm) = Length (mm) | OuterSurfaceArea (m2) | NetVolume (m3) | NetWeight (kg)
POTEAUX | 13 | P5 | 3 | POTEAUX | 415.6 | 0 | 9.4 | 6265 | 9.19076 | 0.0501375 | 393.579
POTEAUX | 12 | P4 | 1 | POTEAUX | 415.6 | 0 | 9.4 | 6265 | 9.19076 | 0.0501375 | 393.579
POTEAUX | 8 | P38 | 1 | POTEAUX | 415.6 | 0 | 9.1 | 6265 | 9.19076 | 0.0488011 | 383.088
POTEAUX | 7 | P37 | 1 | POTEAUX | 398.7 | 0 | 8.9 | 6010 | 8.81667 | 0.0477629 | 374.939
POUTRES | 6 | N22 | 2 | POUTRES | 609.3 | 1.8 | 13.7 | 9185 | 13.4744 | 0.0741027 | 581.707
POUTRES | 5 | N21 | 2 | POUTRES | 937.9 | 2.5 | 21.3 | 14140 | 20.7434 | 0.114079 | 895.518
POUTRES | 4 | N19 | 2 | POUTRES | 499.5 | 1.4 | 11.3 | 7530 | 11.0465 | 0.0607505 | 476.892
POUTRES | 3 | N20 | 2 | POUTRES | 565.1 | 1.4 | 12.8 | 8519 | 12.4974 | 0.0687296 | 539.527
EMPANNON | 2 | K1 | 3 | EMPANNON | 757 | 0 | 17.1 | 11412.7 | 16.7424 | 0.0916811 | 719.697
POTEAUX | 1 | P39 | 2 | POTEAUX | 415.6 | 0 | 9.4 | 6265 | 9.19076 | 0.0501375 | 393.579
POTEAUX | 11 | P3 | 1 | POTEAUX | 428.7 | 0 | 9.6 | 6465 | 9.48416 | 0.0517511 | 406.246
POTEAUX | 10 | P2 | 1 | POTEAUX | 421.2 | 0 | 9.4 | 6350 | 9.31545 | 0.050506 | 396.472
POTEAUX | 9 | P1 | 1 | POTEAUX | 421.2 | 0 | 9.4 | 6350 | 9.31545 | 0.050506 | 396.472

# IfcBeam: IPE450 (8)
In: Undefined
Description: IPE450; Material: STEEL/E24-2
Tekla Commun - Finition: GRENAILLE-PEINT; Repère de pièce: 868; Profil: IPE450; Nom: EMPANNON; sets with these values: 2
Tekla Quantités - Poids: 873.5 kg; Volume: 0.1 m3; Surface supérieure totale: 0 m2; Surface par tonne: 20.7 m2; Surface nette: 18.4 m2; Hauteur: 450 mm; Largeur: 190 mm; Longueur: 11262.6 mm; sets with these values: 2
Pset_BeamCommon - LoadBearing: no; Reference: 868
BaseQuantities - Length: 11262.6 mm; OuterSurfaceArea: 18.0765 m2; NetVolume: 0.106512 m3; NetWeight: 836.122 kg
Name | Repère d'assemblage | Phase
2 x EMPANNON | K21 | 1
EMPANNON | K22 | 1
EMPANNON | K24 | 1
EMPANNON | K22 | 3
EMPANNON | K23 | 3
2 x EMPANNON | K21 | 3

# IfcBeam: IPE500 (23)
In: Undefined
Description: IPE500; Material: STEEL/E24-2
Tekla Commun - Finition: GRENAILLE-PEINT; Profil: IPE500; sets with these values: 2
Tekla Quantités - Surface par tonne: 19.2 m2; Hauteur: 500 mm; Largeur: 200 mm; sets with these values: 2
Pset_BeamCommon - LoadBearing: no
Name | Repère de pièce = Reference | Repère d'assemblage | Phase | Nom | Poids (kg) | Volume (m3) | Surface supérieure totale (m2) | Surface nette (m2) | Longueur (mm) = Length (mm) | OuterSurfaceArea (m2) | NetVolume (m3) | NetWeight (kg)
POTEAUX | P34 | P34 | 1 | POTEAUX | 570.5 | 0.1 | 0 | 11.1 | 6265 | 10.9262 | 0.0692992 | 543.998
POTEAUX | 127 | P33 | 1 | POTEAUX | 570.5 | 0.1 | 0 | 11.1 | 6265 | 10.9262 | 0.0692992 | 543.998
2 x POTEAUX | 128 | P35 | 1 | POTEAUX | 570.5 | 0.1 | 0 | 11.1 | 6265 | 10.9262 | 0.0692992 | 543.998
POUTRES | 125 | N5 | 1 | POUTRES | 1227.5 | 0.2 | 2.7 | 23.9 | 13480 | 23.5091 | 0.15062 | 1182.37
POUTRES | 124 | N4 | 2 | POUTRES | 856.8 | 0.1 | 1.8 | 16.4 | 9409 | 16.4093 | 0.103192 | 810.057
POUTRES | 123 | N3 | 2 | POUTRES | 921.1 | 0.1 | 1.9 | 18 | 10115 | 17.6406 | 0.113021 | 887.215
POUTRES | 122 | N2 | 2 | POUTRES | 971.2 | 0.1 | 2.1 | 19 | 10665 | 18.5998 | 0.119166 | 935.457
POUTRES | 121 | N1 | 2 | POUTRES | 836.4 | 0.1 | 1.8 | 16.1 | 9185 | 16.0186 | 0.100639 | 790.014
POTEAUX | 120 | P33 | 1 | POTEAUX | 570.5 | 0.1 | 0 | 11.1 | 6265 | 10.9262 | 0.0692992 | 543.998
POTEAUX | 119 | P31 | 3 | POTEAUX | 570.5 | 0.1 | 0 | 11.1 | 6265 | 10.9262 | 0.0692992 | 543.998
POTEAUX | 118 | P30 | 2 | POTEAUX | 570.5 | 0.1 | 0 | 11.1 | 6265 | 10.9262 | 0.0692992 | 543.998
POTEAUX | 117 | P28 | 1 | POTEAUX | 570.5 | 0.1 | 0 | 11.1 | 6265 | 10.9262 | 0.0692992 | 543.998
2 x POTEAUX | 128 | P36 | 1 | POTEAUX | 570.5 | 0.1 | 0 | 11.1 | 6265 | 10.9262 | 0.0692992 | 543.998
POTEAUX | 118 | P29 | 2 | POTEAUX | 570.5 | 0.1 | 0 | 11.1 | 6265 | 10.9262 | 0.0692992 | 543.998
POTEAUX | 119 | P32 | 3 | POTEAUX | 570.5 | 0.1 | 0 | 11.1 | 6265 | 10.9262 | 0.0692992 | 543.998
POTEAUX | 116 | P24 | 1 | POTEAUX | 569.6 | 0.1 | 0 | 11.1 | 6255 | 10.9087 | 0.0698909 | 548.643
POTEAUX | 116 | P25 | 1 | POTEAUX | 569.6 | 0.1 | 0 | 11.1 | 6255 | 10.9087 | 0.0698909 | 548.643
POTEAUX | 114 | P22 | 1 | POTEAUX | 587.8 | 0.1 | 0 | 11.5 | 6455 | 11.2575 | 0.0721256 | 566.186
POTEAUX | 116 | P26 | 1 | POTEAUX | 569.6 | 0.1 | 0 | 11.1 | 6255 | 10.9087 | 0.0698909 | 548.643
POTEAUX | 116 | P27 | 1 | POTEAUX | 569.6 | 0.1 | 0 | 11.1 | 6255 | 10.9087 | 0.0698909 | 548.643
POTEAUX | 115 | P23 | 1 | POTEAUX | 538.6 | 0.1 | 0 | 10.5 | 5915 | 10.3158 | 0.0660918 | 518.821

# IfcBeam: IPEA300 (323)
In: Undefined
Description: IPEA300; Material: STEEL/E36-3
Tekla Commun - Finition: GRENAILLE-PEINT; Profil: IPEA300; sets with these values: 2
Tekla Quantités - Surface par tonne: 31.8 m2; Hauteur: 297 mm; Largeur: 150 mm; sets with these values: 2
Pset_BeamCommon - LoadBearing: no
Name | Repère de pièce = Reference | Repère d'assemblage | Phase | Nom | Poids (kg) | Volume (m3) | Surface supérieure totale (m2) | Surface nette (m2) | Longueur (mm) | Length (mm) | OuterSurfaceArea (m2) | NetVolume (m3) | NetWeight (kg)
EMPANNON | 96 | K51 | 3 | EMPANNON | 40.7 | 0 | 0 | 1.2 | 1114.2 | 1114.23 | 1.29251 | 0.00490849 | 38.5316
EMPANNON | 97 | K52 | 3 | EMPANNON | 66.6 | 0 | 0 | 2.2 | 1824.6 | 1824.57 | 2.1165 | 0.00809481 | 63.5442
EMPANNON | 94 | K50 | 3 | EMPANNON | 71.5 | 0 | 0 | 2.3 | 1958.2 | 1958.17 | 2.27147 | 0.00869797 | 68.2791
EMPANNON | 98 | K53 | 3 | EMPANNON | 58.6 | 0 | 0 | 1.9 | 1605.1 | 1605.09 | 1.8619 | 0.00710864 | 55.8028
EMPANNON | 95 | K94 | 3 | EMPANNON | 73.2 | 0 | 0 | 2.5 | 2006.2 | 2006.15 | 2.32714 | 0.00891924 | 70.016
4 x EMPANNON | 93 | K83 | 2 | EMPANNON | 338.8 | 0 | 0 | 10.9 | 9280.3 | 9280.27 | 10.7651 | 0.0410468 | 322.217
EMPANNON | 91 | K67 | 2 | EMPANNON | 418.4 | 0.1 | 0 | 13.5 | 11462.7 | 11462.7 | 13.2968 | 0.0508556 | 399.217
EMPANNON | 89 | K64 | 2 | EMPANNON | 416.3 | 0.1 | 0 | 13.5 | 11403.7 | 11403.7 | 13.2283 | 0.0505924 | 397.15
EMPANNON | 91 | K70 | 2 | EMPANNON | 418.4 | 0.1 | 0 | 13.5 | 11462.7 | 11462.7 | 13.2968 | 0.0508556 | 399.217
EMPANNON | 88 | K63 | 2 | EMPANNON | 418.4 | 0.1 | 0 | 13.5 | 11462.7 | 11462.7 | 13.2968 | 0.0508556 | 399.217
EMPANNON | 86 | K81 | 2 | EMPANNON | 338.8 | 0 | 0 | 10.9 | 9280.3 | 9280.27 | 10.7651 | 0.0410468 | 322.217
EMPANNON | 91(?) | K68(?) | 2 | EMPANNON | 418.4 | 0.1 | 0 | 13.5 | 11462.7 | 11462.7 | 13.2968 | 0.0508556 | 399.217
EMPANNON | 85 | K80 | 2 | EMPANNON | 338.8 | 0 | 0 | 10.9 | 9280.3 | 9280.27 | 10.7651 | 0.0410468 | 322.217
EMPANNON | 89 | K66 | 2 | EMPANNON | 416.3 | 0.1 | 0 | 13.5 | 11403.7 | 11403.7 | 13.2283 | 0.0505924 | 397.15
EMPANNON | 84 | K79 | 2 | EMPANNON | 338.8 | 0 | 0 | 10.9 | 9280.3 | 9280.27 | 10.7651 | 0.0410468 | 322.217
2 x EMPANNON | 91 | K71 | 2 | EMPANNON | 418.4 | 0.1 | 0 | 13.5 | 11462.7 | 11462.7 | 13.2968 | 0.0508556 | 399.217
EMPANNON | 83 | K78 | 2 | EMPANNON | 338.8 | 0 | 0 | 10.9 | 9280.3 | 9280.27 | 10.7651 | 0.0410468 | 322.217
EMPANNON | 82 | K77 | 2 | EMPANNON | 338.8 | 0 | 0 | 10.9 | 9280.3 | 9280.27 | 10.7651 | 0.0410468 | 322.217
EMPANNON | 81 | K76 | 2 | EMPANNON | 338.8 | 0 | 0 | 10.9 | 9280.3 | 9280.27 | 10.7651 | 0.0410468 | 322.217
EMPANNON | 88 | K65 | 2 | EMPANNON | 418.4 | 0.1 | 0 | 13.5 | 11462.7 | 11462.7 | 13.2968 | 0.0508556 | 399.217
EMPANNON | 91 | K69 | 2 | EMPANNON | 418.4 | 0.1 | 0 | 13.5 | 11462.7 | 11462.7 | 13.2968 | 0.0508556 | 399.217
EMPANNON | 78 | K73 | 2 | EMPANNON | 338.8 | 0 | 0 | 10.9 | 9280.3 | 9280.27 | 10.7651 | 0.0410468 | 322.217
EMPANNON | 77 | K85 | 2 | EMPANNON | 338.8 | 0 | 0 | 10.9 | 9280.3 | 9280.27 | 10.7651 | 0.0410468 | 322.217
EMPANNON | 75 | K61 | 2 | EMPANNON | 418.4 | 0.1 | 0 | 13.5 | 11462.7 | 11462.7 | 13.2968 | 0.0508556 | 399.217
EMPANNON | K19 | K19 | 3 | EMPANNON | 424.3 | 0.1 | 0 | 13.7 | 11623.7 | 11623.7 | 13.4835 | 0.051445 | 403.844
EMPANNON | K17 | K17 | 3 | EMPANNON | 424.4 | 0.1 | 0 | 13.7 | 11626.8 | 11626.8 | 13.4871 | 0.0516874 | 405.746
EMPANNON | 99 | K20 | 3 | EMPANNON | 15.6 | 0 | 0 | 0.5 | 427.8 | 427.796 | 0.496244 | 0.00183622 | 14.4143
EMPANNON | 73 | K27 | 3 | EMPANNON | 423.3 | 0.1 | 0 | 13.7 | 11597.7 | 11597.7 | 13.4534 | 0.0513514 | 403.108
14 x EMPANNON | K16 | K16 | 3 | EMPANNON | 424.4 | 0.1 | 0 | 13.7 | 11626.8 | 11626.8 | 13.4871 | 0.0516874 | 405.746
11 x EMPANNON | K14 | K14 | 3 | EMPANNON | 424.4 | 0.1 | 0 | 13.7 | 11626.8 | 11626.8 | 13.4871 | 0.0515757 | 404.869
2 x EMPANNON | 67 | K42 | 3 | EMPANNON | 415.2 | 0.1 | 0 | 13.5 | 11374.9 | 11374.9 | 13.1949 | 0.0505642 | 396.929
2 x EMPANNON | K12 | K12 | 3 | EMPANNON | 424.3 | 0.1 | 0 | 13.7 | 11623.7 | 11623.7 | 13.4835 | 0.0514674 | 404.019
2 x EMPANNON | K11 | K11 | 3 | EMPANNON | 424.4 | 0.1 | 0 | 13.7 | 11626.8 | 11626.8 | 13.4871 | 0.0516874 | 405.746
2 x EMPANNON | K18 | K18 | 1 | EMPANNON | 422.5 | 0.1 | 0 | 13.7 | 11573.4 | 11573.4 | 13.4251 | 0.0512427 | 402.256
4 x EMPANNON | K11 | K11 | 1 | EMPANNON | 424.4 | 0.1 | 0 | 13.7 | 11626.8 | 11626.8 | 13.4871 | 0.0516874 | 405.746
2 x EMPANNON | K12 | K12 | 1 | EMPANNON | 424.3 | 0.1 | 0 | 13.7 | 11623.7 | 11623.7 | 13.4835 | 0.0514674 | 404.019
15 x EMPANNON | K14 | K14 | 1 | EMPANNON | 424.4 | 0.1 | 0 | 13.7 | 11626.8 | 11626.8 | 13.4871 | 0.0515757 | 404.869
20 x EMPANNON | K16 | K16 | 1 | EMPANNON | 424.4 | 0.1 | 0 | 13.7 | 11626.8 | 11626.8 | 13.4871 | 0.0516874 | 405.746
EMPANNON | K15 | K15 | 1 | EMPANNON | 424.4 | 0.1 | 0 | 13.7 | 11626.8 | 11626.8 | 13.4871 | 0.0515757 | 404.869
2 x EMPANNON | K13 | K13 | 1 | EMPANNON | 424.3 | 0.1 | 0 | 13.7 | 11623.7 | 11623.7 | 13.4835 | 0.0514674 | 404.019
2 x EMPANNON | 67 | K42 | 1 | EMPANNON | 415.2 | 0.1 | 0 | 13.5 | 11374.9 | 11374.9 | 13.1949 | 0.0505642 | 396.929
2 x EMPANNON | 62 | K41 | 1 | EMPANNON | 415.2 | 0.1 | 0 | 13.5 | 11374.9 | 11374.9 | 13.1949 | 0.0505642 | 396.929
EMPANNON | 61 | K43 | 1 | EMPANNON | 141.9 | 0 | 0 | 4.6 | 3887.7 | 3887.69 | 4.50972 | 0.0171752 | 134.825
EMPANNON | 60 | K49 | 1 | EMPANNON | 154.5 | 0 | 0 | 5 | 4233.7 | 4233.74 | 4.91114 | 0.0186067 | 146.063
EMPANNON | 58 | K48 | 1 | EMPANNON | 152.6 | 0 | 0 | 5 | 4179.8 | 4179.84 | 4.84862 | 0.0183664 | 144.176
EMPANNON | 57 | K47 | 1 | EMPANNON | 152.6 | 0 | 0 | 5 | 4179.8 | 4179.84 | 4.84862 | 0.0184781 | 145.053
EMPANNON | K10 | K10 | 1 | EMPANNON | 78.8 | 0 | 0 | 2.5 | 2159.6 | 2159.65 | 2.50519 | 0.00915153 | 71.8395
EMPANNON | K9 | K9 | 1 | EMPANNON | 430.2 | 0.1 | 0 | 13.9 | 11786.1 | 11786.1 | 13.6719 | 0.0524789 | 411.959
EMPANNON | 54 | K8 | 1 | EMPANNON | 430.2 | 0.1 | 0 | 13.9 | 11786.1 | 11786.1 | 13.6719 | 0.0523672 | 411.082
EMPANNON | 53 | K40 | 1 | EMPANNON | 416.9 | 0.1 | 0 | 13.5 | 11420.3 | 11420.3 | 13.2475 | 0.0507664 | 398.516
5 x EMPANNON | K7 | K7 | 1 | EMPANNON | 430.2 | 0.1 | 0 | 13.9 | 11786.1 | 11786.1 | 13.6719 | 0.0524789 | 411.959
3 x EMPANNON | K6 | K6 | 1 | EMPANNON | 423.9 | 0.1 | 0 | 13.7 | 11611.7 | 11611.7 | 13.4695 | 0.0515083 | 404.34
EMPANNON | 52 | K39 | 1 | EMPANNON | 413.2 | 0.1 | 0 | 13.2 | 11319.5 | 11319.5 | 13.1306 | 0.0503171 | 394.989
EMPANNON | K5 | K5 | 1 | EMPANNON | 423.9 | 0.1 | 0 | 13.7 | 11611.7 | 11611.7 | 13.4695 | 0.0515083 | 404.34
POUTRES | 47 | N36 | 1 | POUTRES | 188.1 | 0 | 0.7 | 6 | 5152.9 | 5152.94 | 5.97741 | 0.0224264 | 176.047
EMPANNON | 80 | K75 | 2 | EMPANNON | 338.8 | 0 | 0 | 10.9 | 9280.3 | 9280.27 | 10.7651 | 0.0410468 | 322.217
EMPANNON | 90 | K102 | 2 | EMPANNON | 418.4 | 0.1 | 0 | 13.5 | 11462.7 | 11462.7 | 13.2968 | 0.0508556 | 399.217
EMPANNON | 79 | K74 | 2 | EMPANNON | 338.8 | 0 | 0 | 10.9 | 9280.3 | 9280.27 | 10.7651 | 0.0410468 | 322.217
EMPANNON | 87 | K72 | 2 | EMPANNON | 418.4 | 0.1 | 0 | 13.5 | 11462.7 | 11462.7 | 13.2968 | 0.0508556 | 399.217
EMPANNON | 46 | K60 | 2 | EMPANNON | 418.4 | 0.1 | 0 | 13.5 | 11462.7 | 11462.7 | 13.2968 | 0.0508556 | 399.217
EMPANNON | 59 | K101 | 2 | EMPANNON | 409.5 | 0.1 | 0 | 13.2 | 11218.5 | 11218.5 | 13.0135 | 0.0497665 | 390.667
EMPANNON | 92 | K82 | 2 | EMPANNON | 338.8 | 0 | 0 | 10.9 | 9280.3 | 9280.27 | 10.7651 | 0.0410468 | 322.217
EMPANNON | 76 | K84 | 2 | EMPANNON | 338.8 | 0 | 0 | 10.9 | 9280.3 | 9280.27 | 10.7651 | 0.0410468 | 322.217
EMPANNON | 75 | K62 | 2 | EMPANNON | 418.4 | 0.1 | 0 | 13.5 | 11462.7 | 11462.7 | 13.2968 | 0.0508556 | 399.217
EMPANNON | 45 | K54 | 1 | EMPANNON | 429.3 | 0.1 | 0 | 13.7 | 11760.9 | 11760.9 | 13.6427 | 0.0520395 | 408.51
EMPANNON | 72 | K55 | 1 | EMPANNON | 422.5 | 0.1 | 0 | 13.7 | 11573.4 | 11573.4 | 13.4251 | 0.0512427 | 402.256
EMPANNON | K4 | K4 | 3 | EMPANNON | 418.4 | 0.1 | 0 | 13.5 | 11462.5 | 11462.5 | 13.2965 | 0.0508603 | 399.253
EMPANNON | 48 | K46 | 1 | EMPANNON | 153 | 0 | 0 | 5 | 4191.2 | 4191.17 | 4.86175 | 0.0185088 | 145.294
EMPANNON | 64 | K44 | 1 | EMPANNON | 153.2 | 0 | 0 | 5 | 4196.2 | 4196.17 | 4.86755 | 0.0186716 | 146.572
EMPANNON | 43 | K45 | 1 | EMPANNON | 429.9 | 0.1 | 0 | 13.9 | 11777.6 | 11777.6 | 13.662 | 0.052501 | 412.133
EMPANNON | 42 | K59 | 1 | EMPANNON | 429.7 | 0.1 | 0 | 13.9 | 11772.6 | 11772.6 | 13.6562 | 0.0523382 | 410.855
EMPANNON | 41 | K28 | 1 | EMPANNON | 422.9 | 0.1 | 0 | 13.7 | 11584.7 | 11584.7 | 13.4382 | 0.0514798 | 404.116
EMPANNON | 40 | K38 | 1 | EMPANNON | 429.9 | 0.1 | 0 | 13.9 | 11777.6 | 11777.6 | 13.662 | 0.052501 | 412.133
EMPANNON | 39 | K3 | 1 | EMPANNON | 429.7 | 0.1 | 0 | 13.9 | 11772.6 | 11772.6 | 13.6562 | 0.0523382 | 410.855
EMPANNON | 38 | K37 | 1 | EMPANNON | 413 | 0.1 | 0 | 13.5 | 11314.6 | 11314.6 | 13.125 | 0.0504161 | 395.766
POUTRES | 37 | N46 | 2 | POUTRES | 207.7 | 0 | 1 | 6.6 | 5691.3 | 5691.34 | 6.60195 | 0.0253803 | 199.235
2 x POUTRES | 34 | N46 | 2 | POUTRES | 49.5 | 0 | 0 | 1.6 | 1356 | 1356 | 1.57296 | 0.00604703 | 47.4692
POUTRES | 36 | N46 | 2 | POUTRES | 285.6 | 0 | 1.3 | 9.2 | 7825 | 7824.9 | 9.07688 | 0.0348948 | 273.924
POUTRES | 29 | N43 | 3 | POUTRES | 347.1 | 0 | 1.4 | 11.1 | 9509.9 | 9509.9 | 11.0315 | 0.042409 | 332.911
POUTRES | 28 | N43 | 3 | POUTRES | 343.8 | 0 | 1.4 | 11.1 | 9419.9 | 9419.9 | 10.9271 | 0.0420077 | 329.76
3 x POUTRES | 34 | N43 | 3 | POUTRES | 49.5 | 0 | 0 | 1.6 | 1356 | 1356 | 1.57296 | 0.00604703 | 47.4692
POUTRES | 31 | N49 | 2 | POUTRES | 428.9 | 0.1 | 1.8 | 13.9 | 11750.6 | 11750.6 | 13.6307 | 0.0524013 | 411.35
POUTRES | 32 | N49 | 2 | POUTRES | 428.7 | 0.1 | 1.8 | 13.9 | 11745.6 | 11745.6 | 13.6249 | 0.052379 | 411.175
POUTRES | 24 | N45 | 2 | POUTRES | 322.9 | 0 | 1.3 | 10.5 | 8844.8 | 8844.8 | 10.26 | 0.039443 | 309.628
POUTRES | 25 | N44 | 2 | POUTRES | 434.2 | 0.1 | 1.8 | 14.1 | 11895 | 11895 | 13.7982 | 0.0530453 | 416.405
POUTRES | 26 | N44 | 2 | POUTRES | 434 | 0.1 | 1.8 | 14.1 | 11890 | 11890 | 13.7924 | 0.053023 | 416.23
POUTRES | 27 | N45 | 2 | POUTRES | 322.7 | 0 | 1.3 | 10.5 | 8839.8 | 8839.8 | 10.2542 | 0.0394207 | 309.453
4 x POUTRES | 34 | N44 | 2 | POUTRES | 49.5 | 0 | 0 | 1.6 | 1356 | 1356 | 1.57296 | 0.00604703 | 47.4692
3 x POUTRES | 34 | N45 | 2 | POUTRES | 49.5 | 0 | 0 | 1.6 | 1356 | 1356 | 1.57296 | 0.00604703 | 47.4692
4 x POUTRES | 34 | N49 | 2 | POUTRES | 49.5 | 0 | 0 | 1.6 | 1356 | 1356 | 1.57296 | 0.00604703 | 47.4692
2 x POUTRES | 30 | N14 | 1 | POUTRES | 267.6 | 0 | 1.1 | 8.7 | 7330.7 | 7330.7 | 8.50361 | 0.032691 | 256.624
POUTRES | 31 | N12 | 1 | POUTRES | 428.9 | 0.1 | 1.8 | 13.9 | 11750.6 | 11750.6 | 13.6307 | 0.0524013 | 411.35
POUTRES | 32 | N12 | 1 | POUTRES | 428.7 | 0.1 | 1.8 | 13.9 | 11745.6 | 11745.6 | 13.6249 | 0.052379 | 411.175
POUTRES | 24 | N11 | 1 | POUTRES | 322.9 | 0 | 1.3 | 10.5 | 8844.8 | 8844.8 | 10.26 | 0.039443 | 309.628
POUTRES | 25 | N6 | 1 | POUTRES | 434.2 | 0.1 | 1.8 | 14.1 | 11895 | 11895 | 13.7982 | 0.0530453 | 416.405
POUTRES | 25 | N7 | 1 | POUTRES | 434.2 | 0.1 | 1.8 | 14.1 | 11895 | 11895 | 13.7982 | 0.0530453 | 416.405
POUTRES | 26 | N7 | 1 | POUTRES | 434 | 0.1 | 1.8 | 14.1 | 11890 | 11890 | 13.7924 | 0.053023 | 416.23
POUTRES | 27 | N11 | 1 | POUTRES | 322.7 | 0 | 1.3 | 10.5 | 8839.8 | 8839.8 | 10.2542 | 0.0394207 | 309.453
POUTRES | 26 | N6 | 1 | POUTRES | 434 | 0.1 | 1.8 | 14.1 | 11890 | 11890 | 13.7924 | 0.053023 | 416.23
2 x POUTRES | 33 | N17 | 1 | POUTRES | 284 | 0 | 1.3 | 9.2 | 7780.7 | 7780.7 | 9.02561 | 0.0346977 | 272.377
4 x POUTRES | 24 | N13 | 1 | POUTRES | 322.9 | 0 | 1.3 | 10.5 | 8845.6 | 8845.6 | 10.2609 | 0.0394466 | 309.656
2 x POUTRES | 34 | N17 | 1 | POUTRES | 49.5 | 0 | 0 | 1.6 | 1356 | 1356 | 1.57296 | 0.00604703 | 47.4692
6 x POUTRES | 34 | N13 | 1 | POUTRES | 49.5 | 0 | 0 | 1.6 | 1356 | 1356 | 1.57296 | 0.00604703 | 47.4692
4 x POUTRES | 34 | N6 | 1 | POUTRES | 49.5 | 0 | 0 | 1.6 | 1356 | 1356 | 1.57296 | 0.00604703 | 47.4692
4 x POUTRES | 34 | N7 | 1 | POUTRES | 49.5 | 0 | 0 | 1.6 | 1356 | 1356 | 1.57296 | 0.00604703 | 47.4692
3 x POUTRES | 34 | N11 | 1 | POUTRES | 49.5 | 0 | 0 | 1.6 | 1356 | 1356 | 1.57296 | 0.00604703 | 47.4692
2 x POUTRES | 23 | N12 | 1 | POUTRES | 49.5 | 0 | 0 | 1.6 | 1356 | 1356 | 1.57296 | 0.00604703 | 47.4692
2 x POUTRES | 34 | N12 | 1 | POUTRES | 49.5 | 0 | 0 | 1.6 | 1356 | 1356 | 1.57296 | 0.00604703 | 47.4692
POUTRES | 34 | N14 | 1 | POUTRES | 49.5 | 0 | 0 | 1.6 | 1356 | 1356 | 1.57296 | 0.00604703 | 47.4692
POUTRES | 23 | N14 | 1 | POUTRES | 49.5 | 0 | 0 | 1.6 | 1356 | 1356 | 1.57296 | 0.00604703 | 47.4692
4 x POUTRES | 30 | N16 | 1 | POUTRES | 267.6 | 0 | 1.1 | 8.7 | 7330.7 | 7330.7 | 8.50361 | 0.032691 | 256.624
2 x POUTRES | 31 | N47 | 1 | POUTRES | 428.9 | 0.1 | 1.8 | 13.9 | 11750.6 | 11750.6 | 13.6307 | 0.0524013 | 411.35
2 x POUTRES | 32 | N47 | 1 | POUTRES | 428.7 | 0.1 | 1.8 | 13.9 | 11745.6 | 11745.6 | 13.6249 | 0.052379 | 411.175
2 x POUTRES | 24 | N10 | 1 | POUTRES | 322.9 | 0 | 1.3 | 10.5 | 8844.8 | 8844.8 | 10.26 | 0.039443 | 309.628
2 x POUTRES | 25 | N41 | 1 | POUTRES | 434.2 | 0.1 | 1.8 | 14.1 | 11895 | 11895 | 13.7982 | 0.0530453 | 416.405
2 x POUTRES | 25 | N8 | 1 | POUTRES | 434.2 | 0.1 | 1.8 | 14.1 | 11895 | 11895 | 13.7982 | 0.0530453 | 416.405
2 x POUTRES | 26 | N8 | 1 | POUTRES | 434 | 0.1 | 1.8 | 14.1 | 11890 | 11890 | 13.7924 | 0.053023 | 416.23
2 x POUTRES | 27 | N10 | 1 | POUTRES | 322.7 | 0 | 1.3 | 10.5 | 8839.8 | 8839.8 | 10.2542 | 0.0394207 | 309.453
2 x POUTRES | 26 | N41 | 1 | POUTRES | 434 | 0.1 | 1.8 | 14.1 | 11890 | 11890 | 13.7924 | 0.053023 | 416.23
2 x POUTRES | 33 | N38 | 1 | POUTRES | 284 | 0 | 1.3 | 9.2 | 7780.7 | 7780.7 | 9.02561 | 0.0346977 | 272.377
2 x POUTRES | 34 | N38 | 1 | POUTRES | 49.5 | 0 | 0 | 1.6 | 1356 | 1356 | 1.57296 | 0.00604703 | 47.4692
8 x POUTRES | 34 | N41 | 1 | POUTRES | 49.5 | 0 | 0 | 1.6 | 1356 | 1356 | 1.57296 | 0.00604703 | 47.4692
8 x POUTRES | 34 | N8 | 1 | POUTRES | 49.5 | 0 | 0 | 1.6 | 1356 | 1356 | 1.57296 | 0.00604703 | 47.4692
6 x POUTRES | 34 | N10 | 1 | POUTRES | 49.5 | 0 | 0 | 1.6 | 1356 | 1356 | 1.57296 | 0.00604703 | 47.4692
8 x POUTRES | 34 | N47 | 1 | POUTRES | 49.5 | 0 | 0 | 1.6 | 1356 | 1356 | 1.57296 | 0.00604703 | 47.4692
4 x POUTRES | 34 | N16 | 1 | POUTRES | 49.5 | 0 | 0 | 1.6 | 1356 | 1356 | 1.57296 | 0.00604703 | 47.4692
POUTRES | 31 | N48 | 3 | POUTRES | 428.9 | 0.1 | 1.8 | 13.9 | 11750.6 | 11750.6 | 13.6307 | 0.0524013 | 411.35
POUTRES | 32 | N48 | 3 | POUTRES | 428.7 | 0.1 | 1.8 | 13.9 | 11745.6 | 11745.6 | 13.6249 | 0.052379 | 411.175
POUTRES | 24 | N9 | 3 | POUTRES | 322.9 | 0 | 1.3 | 10.5 | 8844.8 | 8844.8 | 10.26 | 0.039443 | 309.628
POUTRES | 25 | N40 | 3 | POUTRES | 434.2 | 0.1 | 1.8 | 14.1 | 11895 | 11895 | 13.7982 | 0.0530453 | 416.405
POUTRES | 26 | N40 | 3 | POUTRES | 434 | 0.1 | 1.8 | 14.1 | 11890 | 11890 | 13.7924 | 0.053023 | 416.23
POUTRES | 27 | N9 | 3 | POUTRES | 322.7 | 0 | 1.3 | 10.5 | 8839.8 | 8839.8 | 10.2542 | 0.0394207 | 309.453
4 x POUTRES | 34 | N40 | 3 | POUTRES | 49.5 | 0 | 0 | 1.6 | 1356 | 1356 | 1.57296 | 0.00604703 | 47.4692
3 x POUTRES | 34 | N9 | 3 | POUTRES | 49.5 | 0 | 0 | 1.6 | 1356 | 1356 | 1.57296 | 0.00604703 | 47.4692
4 x POUTRES | 34 | N48 | 3 | POUTRES | 49.5 | 0 | 0 | 1.6 | 1356 | 1356 | 1.57296 | 0.00604703 | 47.4692
2 x POUTRES | 34 | N15 | 3 | POUTRES | 49.5 | 0 | 0 | 1.6 | 1356 | 1356 | 1.57296 | 0.00604703 | 47.4692
2 x POUTRES | 35 | N15 | 3 | POUTRES | 275 | 0 | 1.1 | 8.9 | 7533.7 | 7533.7 | 8.73909 | 0.0335962 | 263.73
EMPANNON | K2 | K2 | 3 | EMPANNON | 424.4 | 0.1 | 0 | 13.7 | 11626.8 | 11626.8 | 13.4871 | 0.0515757 | 404.869
2 x POUTRES | 35 | N18 | 2 | POUTRES | 275 | 0 | 1.1 | 8.9 | 7533.7 | 7533.7 | 8.73909 | 0.0335962 | 263.73
2 x POUTRES | 34 | N18 | 2 | POUTRES | 49.5 | 0 | 0 | 1.6 | 1356 | 1356 | 1.57296 | 0.00604703 | 47.4692
3 x POUTRES | 34 | N42 | 1 | POUTRES | 49.5 | 0 | 0 | 1.6 | 1356 | 1356 | 1.57296 | 0.00604703 | 47.4692
2 x POUTRES | 34 | N39 | 1 | POUTRES | 49.5 | 0 | 0 | 1.6 | 1356 | 1356 | 1.57296 | 0.00604703 | 47.4692
2 x POUTRES | 24 | N42 | 1 | POUTRES | 322.9 | 0 | 1.3 | 10.5 | 8845.6 | 8845.6 | 10.2609 | 0.0394466 | 309.656
2 x POUTRES | 33 | N39 | 1 | POUTRES | 284 | 0 | 1.3 | 9.2 | 7780.7 | 7780.7 | 9.02561 | 0.0346977 | 272.377
EMPANNON | 72 | K26 | 1 | EMPANNON | 422.5 | 0.1 | 0 | 13.7 | 11573.4 | 11573.4 | 13.4251 | 0.0512427 | 402.256
EMPANNON | 21 | K25 | 3 | EMPANNON | 423.3 | 0.1 | 0 | 13.7 | 11597.7 | 11597.7 | 13.4534 | 0.0513514 | 403.108
POTEAUX | 20 | P122 | 1 | POTEAUX | 228.8 | 0 | 0 | 7.4 | 6268 | 6268 | 7.27088 | 0.0279519 | 219.422
POTEAUX | 19 | P117 | 1 | POTEAUX | 191.6 | 0 | 0 | 6.2 | 5249.6 | 5249.63 | 6.08957 | 0.0234105 | 183.773
POTEAUX | 18 | P116 | 1 | POTEAUX | 187.2 | 0 | 0 | 6.2 | 5127.6 | 5127.57 | 5.94798 | 0.0228662 | 179.5
POTEAUX | 18 | P115 | 1 | POTEAUX | 187.2 | 0 | 0 | 6.2 | 5127.6 | 5127.57 | 5.94798 | 0.0228662 | 179.5
POTEAUX | 17 | P114 | 3 | POTEAUX | 187.2 | 0 | 0 | 6.2 | 5127.6 | 5127.57 | 5.94798 | 0.0228662 | 179.5
POTEAUX | 14 | P113 | 3 | POTEAUX | 228.8 | 0 | 0 | 7.4 | 6268 | 6268 | 7.27088 | 0.0279519 | 219.422
POTEAUX | 16 | P121 | 3 | POTEAUX | 178.5 | 0 | 0 | 5.8 | 4889.9 | 4889.94 | 5.67233 | 0.0218065 | 171.181
POTEAUX | 15 | P120 | 3 | POTEAUX | 195.8 | 0 | 0 | 6.3 | 5365.2 | 5365.2 | 6.22364 | 0.0239259 | 187.818
POTEAUX | 14 | P119 | 2 | POTEAUX | 228.8 | 0 | 0 | 7.4 | 6268 | 6268 | 7.27088 | 0.0279519 | 219.422

# IfcBeam: L100*10 (41)
In: Undefined
Description: L100*10
Tekla Commun - Finition: GRENAILLE-PEINT; Profil: L100*10; sets with these values: 2
Tekla Quantités - Volume: 0 m3; Surface supérieure totale: 0 m2; Surface par tonne: 187.1 m2; Surface nette: 0.1 m2; Hauteur: 100 mm; Largeur: 100 mm; sets with these values: 2
Pset_BeamCommon - LoadBearing: no
Name | Material | Repère de pièce = Reference | Repère d'assemblage | Phase | Nom | Poids (kg) | Longueur (mm) | Length (mm) | OuterSurfaceArea (m2) | NetVolume (m3) | NetWeight (kg)
ATTACHE | STEEL/E24-2 | H72 | H72 | 2 | ATTACHE | 3.2 | 210 | 210 | 0.5922 | 0.000399 | 3.13215
14 x ATTACHE | STEEL/E24-2 | H71 | H71 | 3 | ATTACHE | 3.2 | 210 | 210 | 0.5922 | 0.000399 | 3.13215
2 x ATTACHE | STEEL/E24-2 | 1229 | L52 | 2 | ATTACHE | 2.7 | 180.1 | 180.11 | 0.507911 | 0.000342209 | 2.68634
12 x ATTACHE | STEEL/S235JR | H73 | H73 | 2 | ATTACHE | 3.2 | 210 | 210 | 0.5922 | 0.000399 | 3.13215
2 x Unnamed | STEEL/E24-2 | 1232 | B12 | 1 |  | 1.7 | 120 | 119.998 | 0.338396 | 0.000227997 | 1.78978
2 x Unnamed | STEEL/E24-2 | 1232 | B13 | 1 |  | 1.7 | 120 | 119.998 | 0.338396 | 0.000227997 | 1.78978
2 x Unnamed | STEEL/E24-2 | 1232 | B15 | 1 |  | 1.7 | 120 | 119.998 | 0.338396 | 0.000227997 | 1.78978
2 x Unnamed | STEEL/E24-2 | 1232 | B14 | 1 |  | 1.7 | 120 | 119.998 | 0.338396 | 0.000227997 | 1.78978
Unnamed | STEEL/E24-2 | 1230 | P40 | 1 |  | 2 | 130 | 130 | 0.3666 | 0.000247 | 1.93895
Unnamed | STEEL/E24-2 | 1230 | P41 | 1 |  | 2 | 130 | 130 | 0.3666 | 0.000247 | 1.93895
Unnamed | STEEL/E24-2 | 1230 | P49 | 1 |  | 2 | 130 | 130 | 0.3666 | 0.000247 | 1.93895
Unnamed | STEEL/E24-2 | 1230 | P48 | 1 |  | 2 | 130 | 130 | 0.3666 | 0.000247 | 1.93895

# IfcBeam: L120*12, Unnamed
In: Undefined
Description: L120*12; Material: STEEL/E24-2
Tekla Commun - Finition: GRENAILLE-PEINT; Repère de pièce: 1159; Repère d'assemblage: K99; Phase: 1; Profil: L120*12; sets with these values: 2
Tekla Quantités - Poids: 3.7 kg; Volume: 0 m3; Surface supérieure totale: 0 m2; Surface par tonne: 21.7 m2; Surface nette: 0.1 m2; Hauteur: 75 mm; Largeur: 120 mm; Longueur: 170 mm; sets with these values: 2
Pset_BeamCommon - LoadBearing: no; Reference: 1159
BaseQuantities - Length: 170 mm; OuterSurfaceArea: 0.07973 m2; NetVolume: 0.00037332 m3; NetWeight: 2.93056 kg

# IfcBeam: L40*4 (24)
In: Undefined
Description: L40*4; Material: STEEL/S235JR
Tekla Commun - Finition: GALVANISE; Profil: L40*4; sets with these values: 2
Tekla Quantités - Volume: 0 m3; Surface supérieure totale: 0 m2; Surface par tonne: 64.1 m2; Hauteur: 40 mm; Largeur: 40 mm; sets with these values: 2
Pset_BeamCommon - LoadBearing: no
Name | Repère de pièce = Repère d'assemblage = Reference | Phase | Nom | Poids (kg) | Surface nette (m2) | Longueur (mm) = Length (mm) | OuterSurfaceArea (m2) | NetVolume (m3) | NetWeight (kg)
4 x CV | W3 | 4 | CV | 10 | 0.6 | 4149.9 | 0.643234 | 0.00126278 | 9.91286
2 x CV | W2 | 4 | CV | 1.2 | 0.1 | 526 | 0.08153 | 0.00016112 | 1.26479
18 x ATTACHE | H55 | 1 | ATTACHE | 1.6 | 0.1 | 660 | 0.1023 | 0.00020064 | 1.57502

# IfcBeam: L50*5 (437)
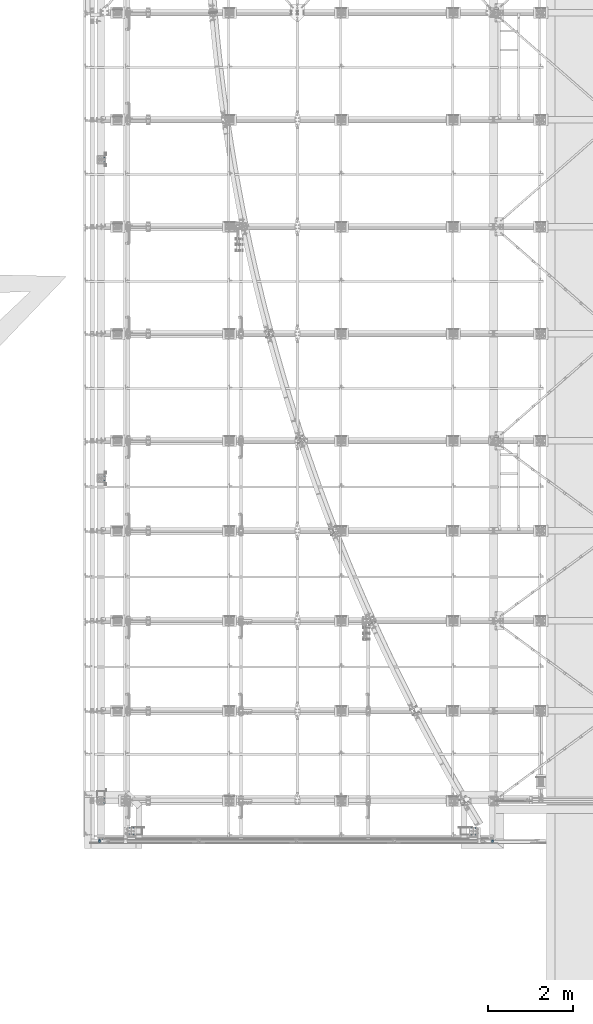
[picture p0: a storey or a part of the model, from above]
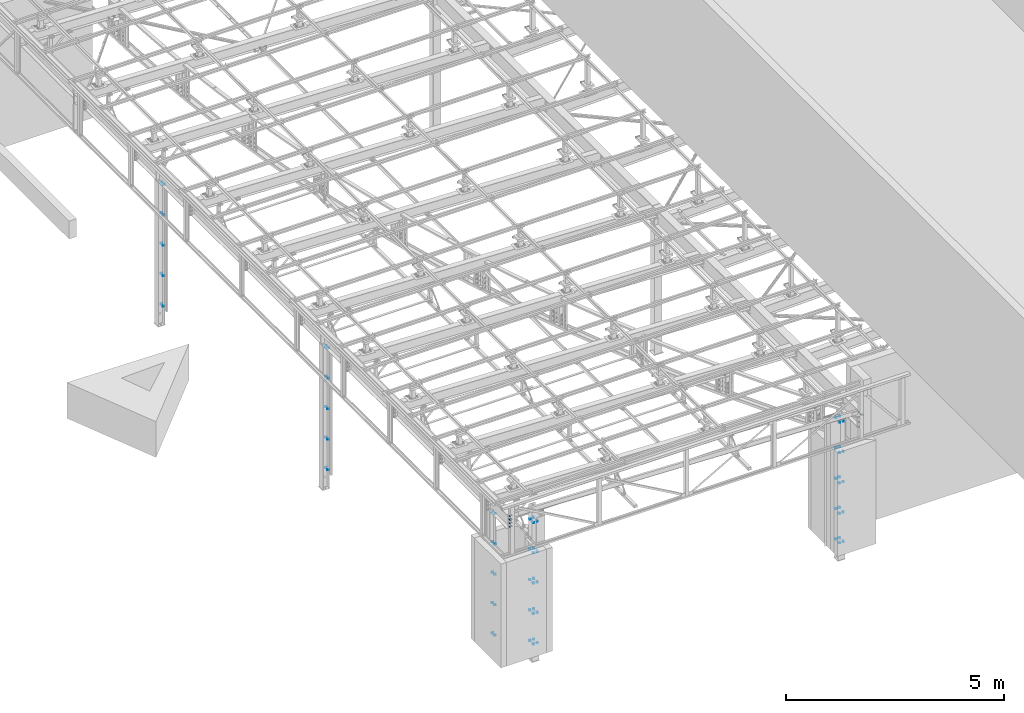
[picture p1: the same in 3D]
Properties of the parts of a building model (IFC2X3), part 2 of 13

# IfcBeam: L50*5 (437)
In: Undefined
Description: L50*5; Material: STEEL/E24-2
Tekla Commun - Finition: GRENAILLE-PEINT; Profil: L50*5; sets with these values: 2
Tekla Quantités - Volume: 0 m3; Surface supérieure totale: 0 m2; Surface par tonne: 51.5 m2; Hauteur: 50 mm; Largeur: 50 mm; sets with these values: 2
Pset_BeamCommon - LoadBearing: no
Name | Repère de pièce = Reference | Repère d'assemblage | Phase | Nom | Poids (kg) | Surface nette (m2) | Longueur (mm) | Length (mm) | OuterSurfaceArea (m2) | NetVolume (m3) | NetWeight (kg)
LISSE | 497 | K20 | 3 | LISSE | 0.9 | 0 | 201.6 | 201.614 | 0.0391132 | 0.0000957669 | 0.75177
CSV | C42 | C42 | 3 | CSV | 13.5 | 0.6 | 3578.7 | 3578.74 | 0.694276 | 0.0017018 | 13.3592
2 x CSV | C43 | C43 | 3 | CSV | 13.5 | 0.6 | 3575.8 | 3575.83 | 0.693711 | 0.00170042 | 13.3483
CSV | C44 | C44 | 3 | CSV | 13.5 | 0.6 | 3580.8 | 3580.83 | 0.694681 | 0.00170279 | 13.3669
CSV | C45 | C45 | 3 | CSV | 23.3 | 1.2 | 6188.4 | 6188.41 | 1.20055 | 0.0029414 | 23.09
CSV | C46 | C46 | 3 | CSV | 22.9 | 1.2 | 6088.4 | 6088.41 | 1.18115 | 0.0028939 | 22.7171
CSV | C47 | C47 | 3 | CSV | 23.3 | 1.2 | 6156.2 | 6156.21 | 1.1943 | 0.0029261 | 22.9699
CSV | C48 | C48 | 3 | CSV | 23.5 | 1.2 | 6225.9 | 6225.94 | 1.20783 | 0.00295922 | 23.2299
14 x CSV | C25 | C25 | 3 | CSV | 13.6 | 0.6 | 3601.1 | 3601.07 | 0.698608 | 0.00171241 | 13.4424
5 x CSV | C29 | C29 | 3 | CSV | 13.9 | 0.6 | 3661.1 | 3661.07 | 0.710248 | 0.00174091 | 13.6661
14 x CSV | C28 | C28 | 3 | CSV | 13.9 | 0.6 | 3671.1 | 3671.07 | 0.712188 | 0.00174566 | 13.7034
5 x CSV | C36 | C36 | 3 | CSV | 13.6 | 0.6 | 3636.1 | 3636.07 | 0.705398 | 0.00172903 | 13.5729
10 x CSV | C24 | C24 | 3 | CSV | 13.1 | 0.6 | 3496.4 | 3496.38 | 0.678298 | 0.00166268 | 13.0521
8 x CSV | C30 | C30 | 3 | CSV | 12.9 | 0.6 | 3426.4 | 3426.38 | 0.664718 | 0.00162943 | 12.791
2 x CSV | C35 | C35 | 3 | CSV | 13.1 | 0.6 | 3471.4 | 3471.38 | 0.673448 | 0.00165081 | 12.9588
6 x CSV | C23 | C23 | 3 | CSV | 13.3 | 0.6 | 3568.1 | 3568.13 | 0.692218 | 0.00169676 | 13.3196
6 x CSV | C22 | C22 | 3 | CSV | 13.6 | 0.6 | 3638.1 | 3638.13 | 0.705798 | 0.00173001 | 13.5806
8 x CSV | C54 | C54 | 3 | CSV | 13.3 | 0.6 | 3568.1 | 3568.13 | 0.692218 | 0.00169676 | 13.3196
2 x CSV | C70 | C70 | 3 | CSV | 13.3 | 0.6 | 3568.1 | 3568.13 | 0.692218 | 0.00169676 | 13.3196
4 x CSV | C56 | C56 | 3 | CSV | 13.6 | 0.6 | 3608.1 | 3608.13 | 0.699978 | 0.00171576 | 13.4687
2 x CSV | C49 | C49 | 2 | CSV | 14.2 | 0.8 | 3789.8 | 3789.84 | 0.73523 | 0.00180208 | 14.1463
2 x CSV | C50 | C50 | 2 | CSV | 13.9 | 0.6 | 3679.8 | 3679.84 | 0.71389 | 0.00174983 | 13.7361
8 x CSV | C71 | C71 | 2 | CSV | 12.3 | 0.6 | 3255.6 | 3255.58 | 0.631583 | 0.0015483 | 12.1542
4 x CSV | C51 | C51 | 2 | CSV | 12.3 | 0.6 | 3255.6 | 3255.58 | 0.631583 | 0.0015483 | 12.1542
8 x CSV | C72 | C72 | 2 | CSV | 14.2 | 0.8 | 3789.8 | 3789.84 | 0.73523 | 0.00180208 | 14.1463
4 x CSV | C73 | C73 | 2 | CSV | 14.2 | 0.6 | 3739.8 | 3739.84 | 0.72553 | 0.00177833 | 13.9599
2 x CSV | C81 | C81 | 2 | CSV | 22.9 | 1.2 | 6080.7 | 6080.68 | 1.17965 | 0.00289022 | 22.6883
4 x CSV | C74 | C74 | 2 | CSV | 14.2 | 0.6 | 3741.2 | 3741.16 | 0.725786 | 0.00177895 | 13.9648
2 x CSV | C75 | C75 | 2 | CSV | 14.4 | 0.8 | 3851.2 | 3851.16 | 0.747126 | 0.0018312 | 14.3749
4 x CSV | C76 | C76 | 2 | CSV | 13.9 | 0.6 | 3679.8 | 3679.84 | 0.71389 | 0.00174983 | 13.7361
2 x CSV | C52 | C52 | 2 | CSV | 13.5 | 0.6 | 3587.9 | 3587.89 | 0.696051 | 0.00170615 | 13.3933
2 x CSV | C53 | C53 | 2 | CSV | 13.9 | 0.6 | 3697.9 | 3697.89 | 0.717391 | 0.0017584 | 13.8034
4 x CSV | C77 | C77 | 2 | CSV | 13.5 | 0.6 | 3587.9 | 3587.89 | 0.696051 | 0.00170615 | 13.3933
4 x CSV | C78 | C78 | 2 | CSV | 13.9 | 0.6 | 3697.9 | 3697.89 | 0.717391 | 0.0017584 | 13.8034
8 x CSV | C79 | C79 | 2 | CSV | 12.7 | 0.6 | 3356.2 | 3356.24 | 0.65111 | 0.00159611 | 12.5295
6 x CSV | C80 | C80 | 2 | CSV | 12.9 | 0.6 | 3446.2 | 3446.24 | 0.66857 | 0.00163886 | 12.8651
2 x CSV | C69 | C69 | 1 | CSV | 11.3 | 0.6 | 2995.6 | 2995.57 | 0.58114 | 0.00142479 | 11.1846
CSV | C68 | C68 | 1 | CSV | 12.1 | 0.6 | 3227.3 | 3227.28 | 0.626093 | 0.00153486 | 12.0486
CSV | C67 | C67 | 1 | CSV | 12.1 | 0.6 | 3227.3 | 3227.28 | 0.626093 | 0.00153486 | 12.0486
CSV | C66 | C66 | 1 | CSV | 12 | 0.6 | 3178.7 | 3178.74 | 0.616676 | 0.0015118 | 11.8677
CSV | C65 | C65 | 1 | CSV | 12 | 0.6 | 3178.7 | 3178.74 | 0.616676 | 0.0015118 | 11.8677
CSV | C64 | C64 | 1 | CSV | 11.8 | 0.6 | 3120.6 | 3120.62 | 0.605401 | 0.0014842 | 11.6509
CSV | C63 | C63 | 1 | CSV | 11.8 | 0.6 | 3120.6 | 3120.62 | 0.605401 | 0.0014842 | 11.6509
CSV | C62 | C62 | 1 | CSV | 11.8 | 0.6 | 3130.6 | 3130.62 | 0.607341 | 0.00148895 | 11.6882
CSV | C61 | C61 | 1 | CSV | 11.8 | 0.6 | 3130.6 | 3130.62 | 0.607341 | 0.00148895 | 11.6882
CSV | C83 | C83 | 1 | CSV | 15.8 | 0.8 | 4222.7 | 4222.69 | 0.819203 | 0.00200768 | 15.7603
CSV | C82 | C82 | 1 | CSV | 15.8 | 0.8 | 4222.7 | 4222.69 | 0.819203 | 0.00200768 | 15.7603
2 x CSV | C92 | C92 | 1 | CSV | 5.8 | 0.3 | 1571.6 | 1571.63 | 0.304897 | 0.000748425 | 5.87514
2 x CSV | C91 | C91 | 1 | CSV | 5.8 | 0.3 | 1561.6 | 1561.65 | 0.30296 | 0.000743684 | 5.83792
2 x CSV | C90 | C90 | 1 | CSV | 6 | 0.3 | 1604.1 | 1604.14 | 0.311203 | 0.000763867 | 5.99636
2 x CSV | C89 | C89 | 1 | CSV | 5.8 | 0.3 | 1529.1 | 1529.14 | 0.296653 | 0.000728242 | 5.7167
4 x CSV | C88 | C88 | 1 | CSV | 5.5 | 0.3 | 1450.8 | 1450.78 | 0.281452 | 0.000691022 | 5.42452
2 x CSV | C87 | C87 | 1 | CSV | 5.8 | 0.3 | 1546.9 | 1546.86 | 0.30009 | 0.000736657 | 5.78276
2 x CSV | C86 | C86 | 1 | CSV | 5.8 | 0.3 | 1537.9 | 1537.89 | 0.29835 | 0.000732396 | 5.74931
2 x CSV | C85 | C85 | 1 | CSV | 5.8 | 0.3 | 1553.3 | 1553.31 | 0.301342 | 0.000739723 | 5.80682
2 x CSV | C84 | C84 | 1 | CSV | 5.7 | 0.3 | 1473.3 | 1473.31 | 0.285822 | 0.000701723 | 5.50852
2 x CSV | C94 | C94 | 1 | CSV | 7.8 | 0.3 | 2071.8 | 2071.85 | 0.401938 | 0.000986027 | 7.74032
2 x CSV | C93 | C93 | 1 | CSV | 7.8 | 0.3 | 2056.8 | 2056.85 | 0.399028 | 0.000978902 | 7.68438
12 x CSV | C41 | C41 | 1 | CSV | 14.4 | 0.8 | 3817.2 | 3817.16 | 0.74053 | 0.00181505 | 14.2482
2 x CSV | C59 | C59 | 1 | CSV | 13.9 | 0.6 | 3711.1 | 3711.07 | 0.719948 | 0.00176466 | 13.8526
12 x CSV | C58 | C58 | 1 | CSV | 13.6 | 0.6 | 3601.1 | 3601.07 | 0.698608 | 0.00171241 | 13.4424
6 x CSV | C57 | C57 | 1 | CSV | 13.9 | 0.6 | 3671.1 | 3671.07 | 0.712188 | 0.00174566 | 13.7034
4 x CSV | C60 | C60 | 1 | CSV | 13.6 | 0.6 | 3636.1 | 3636.07 | 0.705398 | 0.00172903 | 13.5729
30 x CSV | C25 | C25 | 1 | CSV | 13.6 | 0.6 | 3601.1 | 3601.07 | 0.698608 | 0.00171241 | 13.4424
28 x CSV | C28 | C28 | 1 | CSV | 13.9 | 0.6 | 3671.1 | 3671.07 | 0.712188 | 0.00174566 | 13.7034
3 x CSV | C95 | C95 | 1 | CSV | 23.1 | 1.2 | 6127.1 | 6127.08 | 1.18865 | 0.00291226 | 22.8613
3 x CSV | C96 | C96 | 1 | CSV | 22.4 | 1.2 | 5947.1 | 5947.07 | 1.15373 | 0.00282676 | 22.1901
2 x CSV | C40 | C40 | 1 | CSV | 13.5 | 0.6 | 3578 | 3578.02 | 0.694135 | 0.00170146 | 13.3564
12 x CSV | C27 | C27 | 1 | CSV | 13.9 | 0.6 | 3668 | 3668.02 | 0.711595 | 0.00174421 | 13.692
10 x CSV | C26 | C26 | 1 | CSV | 14.2 | 0.6 | 3738 | 3738.02 | 0.725175 | 0.00177746 | 13.953
CSV | C39 | C39 | 3 | CSV | 12.9 | 0.6 | 3433.3 | 3433.25 | 0.666051 | 0.00163269 | 12.8167
CSV | C38 | C38 | 3 | CSV | 13.6 | 0.6 | 3596.1 | 3596.07 | 0.697638 | 0.00171003 | 13.4238
2 x CSV | C55 | C55 | 3 | CSV | 13.6 | 0.6 | 3638.1 | 3638.13 | 0.705798 | 0.00173001 | 13.5806
6 x CSV | C22 | C22 | 1 | CSV | 13.6 | 0.6 | 3638.1 | 3638.13 | 0.705798 | 0.00173001 | 13.5806
6 x CSV | C23 | C23 | 1 | CSV | 13.3 | 0.6 | 3568.1 | 3568.13 | 0.692218 | 0.00169676 | 13.3196
10 x CSV | C24 | C24 | 1 | CSV | 13.1 | 0.6 | 3496.4 | 3496.38 | 0.678298 | 0.00166268 | 13.0521
6 x CSV | C29 | C29 | 1 | CSV | 13.9 | 0.6 | 3661.1 | 3661.07 | 0.710248 | 0.00174091 | 13.6661
8 x CSV | C30 | C30 | 1 | CSV | 12.9 | 0.6 | 3426.4 | 3426.38 | 0.664718 | 0.00162943 | 12.791
8 x CSV | C54 | C54 | 1 | CSV | 13.3 | 0.6 | 3568.1 | 3568.13 | 0.692218 | 0.00169676 | 13.3196
8 x CSV | C55 | C55 | 1 | CSV | 13.6 | 0.6 | 3638.1 | 3638.13 | 0.705798 | 0.00173001 | 13.5806
2 x CSV | C35 | C35 | 1 | CSV | 13.1 | 0.6 | 3471.4 | 3471.38 | 0.673448 | 0.00165081 | 12.9588
6 x CSV | C36 | C36 | 1 | CSV | 13.6 | 0.6 | 3636.1 | 3636.07 | 0.705398 | 0.00172903 | 13.5729
2 x CSV | C37 | C37 | 1 | CSV | 13.9 | 0.6 | 3711.1 | 3711.07 | 0.719948 | 0.00176466 | 13.8526
6 x CSV | C20 | C20 | 1 | CSV | 11.6 | 0.6 | 3072.1 | 3072.11 | 0.59599 | 0.00146115 | 11.47
2 x CSV | C21 | C21 | 1 | CSV | 11.8 | 0.6 | 3142.1 | 3142.11 | 0.60957 | 0.0014944 | 11.7311
CSV | C9 | C9 | 1 | CSV | 16.4 | 0.8 | 4368.1 | 4368.13 | 0.847418 | 0.00207676 | 16.3026
CSV | C8 | C8 | 1 | CSV | 16.4 | 0.8 | 4368.1 | 4368.13 | 0.847418 | 0.00207676 | 16.3026
8 x CSV | C13 | C13 | 1 | CSV | 10.8 | 0.6 | 2861.3 | 2861.27 | 0.555086 | 0.001361 | 10.6839
8 x CSV | C11 | C11 | 1 | CSV | 11.1 | 0.6 | 2936.3 | 2936.27 | 0.569635 | 0.00139663 | 10.9635
2 x CSV | C19 | C19 | 1 | CSV | 11.3 | 0.6 | 3012.6 | 3012.6 | 0.584445 | 0.00143289 | 11.2482
2 x CSV | C18 | C18 | 1 | CSV | 12 | 0.6 | 3194.2 | 3194.19 | 0.619673 | 0.00151914 | 11.9253
2 x CSV | C17 | C17 | 1 | CSV | 11.6 | 0.6 | 3089.2 | 3089.19 | 0.599303 | 0.00146927 | 11.5337
2 x CSV | C16 | C16 | 1 | CSV | 11.6 | 0.6 | 3089.2 | 3089.19 | 0.599303 | 0.00146927 | 11.5337
2 x CSV | C15 | C15 | 1 | CSV | 11.3 | 0.6 | 3034.2 | 3034.16 | 0.588627 | 0.00144313 | 11.3285
2 x CSV | C14 | C14 | 1 | CSV | 11.6 | 0.6 | 3080.8 | 3080.78 | 0.597672 | 0.00146527 | 11.5024
2 x CSV | C12 | C12 | 1 | CSV | 11.1 | 0.6 | 2971.3 | 2971.27 | 0.576426 | 0.00141325 | 11.094
2 x CSV | C10 | C10 | 1 | CSV | 10.8 | 0.6 | 2871.3 | 2871.27 | 0.557026 | 0.00136575 | 10.7211
2 x CSV | C7 | C7 | 1 | CSV | 15.6 | 0.8 | 4149.6 | 4149.64 | 0.805031 | 0.00197298 | 15.4879
CSV | C5 | C5 | 1 | CSV | 15.4 | 0.8 | 4089.6 | 4089.64 | 0.793391 | 0.00194448 | 15.2642
CSV | C4 | C4 | 1 | CSV | 15.4 | 0.8 | 4089.6 | 4089.64 | 0.793391 | 0.00194448 | 15.2642
2 x CSV | C6 | C6 | 1 | CSV | 15.4 | 0.8 | 4089.6 | 4089.65 | 0.793393 | 0.00194449 | 15.2642
CSV | C34 | C34 | 3 | CSV | 13.9 | 0.6 | 3658 | 3658.02 | 0.709655 | 0.00173946 | 13.6547
CSV | C33 | C33 | 3 | CSV | 14.2 | 0.6 | 3733 | 3733.02 | 0.724205 | 0.00177508 | 13.9344
CSV | C32 | C32 | 3 | CSV | 13.9 | 0.6 | 3663 | 3663.02 | 0.710625 | 0.00174183 | 13.6734
CSV | C31 | C31 | 3 | CSV | 14.2 | 0.6 | 3736 | 3736.02 | 0.724787 | 0.00177651 | 13.9456

# IfcBeam: L60*6 (938)
In: Undefined
Description: L60*6
Tekla Commun - Profil: L60*6; sets with these values: 2
Tekla Quantités - Volume: 0 m3; Surface par tonne: 43 m2; Hauteur: 60 mm; Largeur: 60 mm; sets with these values: 2
Pset_BeamCommon - LoadBearing: no
Name | Material | Finition | Repère de pièce = Reference | Repère d'assemblage | Phase | Nom | Poids (kg) | Surface supérieure totale (m2) | Surface nette (m2) | Longueur (mm) | Length (mm) | OuterSurfaceArea (m2) | NetVolume (m3) | NetWeight (kg)
2 x ATTACHE | STEEL/E24-2 | GRENAILLE-PEINT | H16 | H16 | 7 | ATTACHE | 0.9 | 0 | 0 | 150 | 150 | 0.03495 | 0.0001026 | 0.80541
ATTACHE | STEEL/E24-2 | GRENAILLE-PEINT | 398 | L40 | 7 | ATTACHE | 0.3 | 0 | 0 | 80 | 80 | 0.01864 | 0.00005472 | 0.429552
2 x ATTACHE | STEEL/E24-2 | GRENAILLE-PEINT | 399 | P53 | 7 | ATTACHE | 0.3 | 0 | 0 | 50 | 50 | 0.01165 | 0.0000342 | 0.26847
6 x ATTACHE | STEEL/E24-2 | GRENAILLE-PEINT | 399 | P52 | 7 | ATTACHE | 0.3 | 0 | 0 | 50 | 50 | 0.01165 | 0.0000342 | 0.26847
LIEN | STEEL/E24-2 | GRENAILLE-PEINT | L17 | L17 | 6 | LIEN | 14.4 | 0.2 | 0.6 | 2635 | 2635 | 0.613955 | 0.00180234 | 14.1484
3 x LIEN | STEEL/E24-2 | GRENAILLE-PEINT | L16 | L16 | 6 | LIEN | 14.7 | 0.2 | 0.6 | 2715 | 2715 | 0.632595 | 0.00185706 | 14.5779
LIEN | STEEL/E24-2 | GRENAILLE-PEINT | L14 | L14 | 6 | LIEN | 15.2 | 0.2 | 0.6 | 2800 | 2800 | 0.6524 | 0.0019152 | 15.0343
3 x LIEN | STEEL/E24-2 | GRENAILLE-PEINT | L13 | L13 | 6 | LIEN | 15.4 | 0.2 | 0.6 | 2840 | 2840 | 0.66172 | 0.00194256 | 15.2491
2 x LIEN | STEEL/E24-2 | GRENAILLE-PEINT | L15 | L15 | 6 | LIEN | 15.6 | 0.2 | 0.6 | 2880 | 2880 | 0.67104 | 0.00196992 | 15.4639
ATTACHE | STEEL/E24-2 | GRENAILLE-PEINT | 402 | L18 | 4 | ATTACHE | 0.9 | 0 | 0 | 165 | 165 | 0.0384449 | 0.00011286 | 0.885949
ATTACHE | STEEL/E24-2 | GRENAILLE-PEINT | 401 | L18 | 4 | ATTACHE | 0.9 | 0 | 0 | 165 | 165 | 0.0384449 | 0.00011286 | 0.885949
2 x ATTACHE | STEEL/E24-2 | GRENAILLE-PEINT | H15 | H15 | 4 | ATTACHE | 1.7 | 0 | 0.1 | 330 | 330 | 0.07689 | 0.00022572 | 1.7719
2 x ATTACHE | STEEL/E24-2 | GRENAILLE-PEINT | H14 | H14 | 4 | ATTACHE | 1.7 | 0 | 0.1 | 330 | 330 | 0.07689 | 0.00022572 | 1.7719
2 x ATTACHE | STEEL/E24-2 | GRENAILLE-PEINT | 400 | L18 | 4 | ATTACHE | 0.3 | 0 | 0 | 60 | 60.0001 | 0.01398 | 0.00004104 | 0.322164
2 x ATTACHE | STEEL/E24-2 | GRENAILLE-PEINT | 400 | L19 | 4 | ATTACHE | 0.3 | 0 | 0 | 60 | 60.0001 | 0.01398 | 0.00004104 | 0.322164
ATTACHE | STEEL/E24-2 | GRENAILLE-PEINT | H13 | H13 | 4 | ATTACHE | 2 | 0 | 0.1 | 345 | 345 | 0.080385 | 0.00023598 | 1.85244
2 x MONTANT | STEEL/E24-2 | GRENAILLE-PEINT | 404 | M6 | 4 | MONTANT | 3.3 | 0 | 0.1 | 600 | 600 | 0.1398 | 0.0004104 | 3.22164
57 x ATTACHE | STEEL/E24-2 | GRENAILLE-PEINT | H17 | H17 | 4 | ATTACHE | 1.4 | 0 | 0.1 | 265 | 265 | 0.061745 | 0.00018126 | 1.42289
MONTANT | STEEL/E24-2 | GRENAILLE-PEINT | 407 | M6 | 4 | MONTANT | 9.4 | 0 | 0.3 | 1728 | 1728 | 0.402624 | 0.00118195 | 9.27832
57 x ATTACHE | STEEL/E24-2 | GRENAILLE-PEINT | H18 | H18 | 4 | ATTACHE | 1.4 | 0 | 0.1 | 265 | 265 | 0.061745 | 0.00018126 | 1.42289
MONTANT | STEEL/E24-2 | GRENAILLE-PEINT | 408 | M6 | 4 | MONTANT | 9.4 | 0 | 0.3 | 1728 | 1728 | 0.402624 | 0.00118195 | 9.27832
13 x MONTANT | STEEL/E24-2 | GRENAILLE-PEINT | M9 | M9 | 4 | MONTANT | 0.6 | 0 | 0 | 136 | 136 | 0.0316879 | 0.0000930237 | 0.730236
MONTANT | STEEL/E24-2 | GRENAILLE-PEINT | M10 | M10 | 4 | MONTANT | 3.8 | 0 | 0.2 | 707 | 707 | 0.164731 | 0.000483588 | 3.79616
7 x MONTANT | STEEL/E24-2 | GRENAILLE-PEINT | M8 | M8 | 4 | MONTANT | 3.8 | 0 | 0.2 | 707 | 707 | 0.164731 | 0.000483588 | 3.79616
12 x MONTANT | STEEL/E24-2 | GRENAILLE-PEINT | M11 | M11 | 4 | MONTANT | 4.2 | 0 | 0.2 | 777 | 777 | 0.181041 | 0.000531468 | 4.17202
34 x MONTANT | STEEL/E24-2 | GRENAILLE-PEINT | M7 | M7 | 4 | MONTANT | 4.2 | 0 | 0.2 | 777 | 777 | 0.181041 | 0.000531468 | 4.17202
2 x Unnamed | STEEL/E24-2 | GRENAILLE-PEINT | 414 | L46 | 3 |  | 0.6 | 0 | 0 | 120 | 120 | 0.02796 | 0.00008208 | 0.644328
26 x ATTACHE | STEEL/S235JR | GALVANISE | H20 | H20 | 2 | ATTACHE | 1.1 | 0 | 0.1 | 210 | 210 | 0.04893 | 0.00014364 | 1.12757
8 x ATTACHE | STEEL/S235JR | GALVANISE | H28 | H28 | 2 | ATTACHE | 0.9 | 0 | 0 | 170 | 170 | 0.03961 | 0.00011628 | 0.912798
ATTACHE | STEEL/S235JR | GRENAILLE-PEINT | H30 | H30 | 2 | ATTACHE | 0.9 | 0 | 0 | 190 | 190 | 0.04427 | 0.00012996 | 1.02019
14 x ATTACHE | STEEL/S235JR | GRENAILLE-PEINT | H31 | H31 | 2 | ATTACHE | 0.6 | 0 | 0 | 110 | 110 | 0.02563 | 0.00007524 | 0.590634
7 x ATTACHE | STEEL/S235JR | GALVANISE | 430 | S53 | 2 | ATTACHE | 0.5 | 0 | 0 | 96 | 96 | 0.022368 | 0.000065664 | 0.515462
64 x ATTACHE | STEEL/S235JR | GALVANISE | H24 | H24 | 2 | ATTACHE | 1.1 | 0 | 0.1 | 210 | 210 | 0.04893 | 0.00014364 | 1.12757
69 x ATTACHE | STEEL/S235JR | GALVANISE | H26 | H26 | 2 | ATTACHE | 0.5 | 0 | 0 | 92 | 92 | 0.021436 | 0.000062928 | 0.493985
33 x ATTACHE | STEEL/S235JR | GALVANISE | H21 | H21 | 2 | ATTACHE | 0.9 | 0 | 0 | 192 | 192 | 0.044736 | 0.000131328 | 1.03092
103 x ATTACHE | STEEL/S235JR | GALVANISE | H25 | H25 | 2 | ATTACHE | 0.9 | 0 | 0 | 192 | 192 | 0.044736 | 0.000131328 | 1.03092
2 x ATTACHE | STEEL/S235JR | GALVANISE | 429 | S65 | 2 | ATTACHE | 0.5 | 0 | 0 | 100 | 100 | 0.0233 | 0.0000684 | 0.53694
4 x ATTACHE | STEEL/S235JR | GALVANISE | 429 | S67 | 2 | ATTACHE | 0.5 | 0 | 0 | 100 | 100 | 0.0233 | 0.0000684 | 0.53694
ATTACHE | STEEL/S235JR | GALVANISE | 429 | S44 | 2 | ATTACHE | 0.5 | 0 | 0 | 100 | 100 | 0.0233 | 0.0000684 | 0.53694
4 x ATTACHE | STEEL/S235JR | GALVANISE | 429 | S66 | 2 | ATTACHE | 0.5 | 0 | 0 | 100 | 100 | 0.0233 | 0.0000684 | 0.53694
2 x ATTACHE | STEEL/S235JR | GALVANISE | 429 | S68 | 2 | ATTACHE | 0.5 | 0 | 0 | 100 | 100 | 0.0233 | 0.0000684 | 0.53694
ATTACHE | STEEL/S235JR | GALVANISE | 429 | S49 | 2 | ATTACHE | 0.5 | 0 | 0 | 100 | 100 | 0.0233 | 0.0000684 | 0.53694
2 x ATTACHE | STEEL/S235JR | GALVANISE | 428 | P94 | 2 | ATTACHE | 1.1 | 0 | 0.1 | 210 | 210 | 0.04893 | 0.00014364 | 1.12757
17 x ATTACHE | STEEL/S235JR | GALVANISE | H27 | H27 | 2 | ATTACHE | 0.9 | 0 | 0 | 192 | 192 | 0.044736 | 0.000131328 | 1.03092
15 x CSV | STEEL/E24-2 | GRENAILLE-PEINT | C1 | C1 | 2 | CSV | 21.9 | 0 | 1 | 4059 | 4058.96 | 0.945737 | 0.00277906 | 21.8156
CSV | STEEL/E24-2 | GRENAILLE-PEINT | C2 | C2 | 2 | CSV | 21.6 | 0 | 1 | 3982.7 | 3982.68 | 0.927966 | 0.00272689 | 21.4061
8 x CSV | STEEL/E24-2 | GRENAILLE-PEINT | C3 | C3 | 2 | CSV | 22.2 | 0 | 1 | 4084 | 4083.97 | 0.951564 | 0.00279617 | 21.9499
ATTACHE | STEEL/S235JR | GALVANISE | 428 | P108 | 2 | ATTACHE | 1.1 | 0 | 0.1 | 210 | 210 | 0.04893 | 0.00014364 | 1.12757
ATTACHE | STEEL/S235JR | GALVANISE | 428 | P107 | 2 | ATTACHE | 1.1 | 0 | 0.1 | 210 | 210 | 0.04893 | 0.00014364 | 1.12757
3 x ATTACHE | STEEL/S235JR | GALVANISE | H22 | H22 | 2 | ATTACHE | 0.9 | 0 | 0 | 192 | 192 | 0.044736 | 0.000131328 | 1.03092
5 x ATTACHE | STEEL/S235JR | GALVANISE | 428 | P95 | 2 | ATTACHE | 1.1 | 0 | 0.1 | 210 | 210 | 0.04893 | 0.00014364 | 1.12757
ATTACHE | STEEL/S235JR | GALVANISE | 428 | P100 | 2 | ATTACHE | 1.1 | 0 | 0.1 | 210 | 210 | 0.04893 | 0.00014364 | 1.12757
ATTACHE | STEEL/S235JR | GALVANISE | 428 | P101 | 2 | ATTACHE | 1.1 | 0 | 0.1 | 210 | 210 | 0.04893 | 0.00014364 | 1.12757
14 x ATTACHE | STEEL/S235JR | GALVANISE | 428 | P96 | 2 | ATTACHE | 1.1 | 0 | 0.1 | 210 | 210 | 0.04893 | 0.00014364 | 1.12757
ATTACHE | STEEL/E24-2 | GRENAILLE-PEINT | 399 | L90 | 1 | ATTACHE | 0.3 | 0 | 0 | 50 | 50 | 0.01165 | 0.0000342 | 0.26847
ATTACHE | STEEL/E24-2 | GRENAILLE-PEINT | 434 | L88 | 1 | ATTACHE | 0.9 | 0 | 0 | 165 | 164.98 | 0.0384403 | 0.000104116 | 0.817313
ATTACHE | STEEL/E24-2 | GRENAILLE-PEINT | 399 | L88 | 1 | ATTACHE | 0.3 | 0 | 0 | 50 | 50 | 0.01165 | 0.0000342 | 0.26847
ATTACHE | STEEL/E24-2 | GRENAILLE-PEINT | 399 | L89 | 1 | ATTACHE | 0.3 | 0 | 0 | 50 | 50 | 0.01165 | 0.0000342 | 0.26847
POTEAUX | STEEL/E24-2 | GRENAILLE-PEINT | 435 | P15 | 1 | POTEAUX | 12.9 | 0 | 0.6 | 2395 | 2395 | 0.558035 | 0.00163818 | 12.8597
POTEAUX | STEEL/E24-2 | GRENAILLE-PEINT | 435 | P14 | 1 | POTEAUX | 12.9 | 0 | 0.6 | 2395 | 2395 | 0.558035 | 0.00163818 | 12.8597
6 x ATTACHE | STEEL/S235JR | GALVANISE | H29 | H29 | 1 | ATTACHE | 1.2 | 0 | 0.1 | 226 | 226 | 0.052658 | 0.000154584 | 1.21348
2 x ATTACHE | STEEL/S235JR | GALVANISE | 428 | P103 | 1 | ATTACHE | 1.1 | 0 | 0.1 | 210 | 210 | 0.04893 | 0.00014364 | 1.12757
19 x ATTACHE | STEEL/S235JR | GALVANISE | H26 | H26 | 1 | ATTACHE | 0.5 | 0 | 0 | 92 | 92 | 0.021436 | 0.000062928 | 0.493985
45 x ATTACHE | STEEL/S235JR | GALVANISE | H25 | H25 | 1 | ATTACHE | 0.9 | 0 | 0 | 192 | 192 | 0.044736 | 0.000131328 | 1.03092
2 x ATTACHE | STEEL/S235JR | GALVANISE | H23 | H23 | 1 | ATTACHE | 1.2 | 0 | 0.1 | 226 | 226 | 0.052658 | 0.000154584 | 1.21348
5 x ATTACHE | STEEL/S235JR | GALVANISE | H27 | H27 | 1 | ATTACHE | 0.9 | 0 | 0 | 192 | 192 | 0.044736 | 0.000131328 | 1.03092
2 x Unnamed | STEEL/E24-2 | GRENAILLE-PEINT | 436 | N17 | 1 |  | 8 | 0 | 0.3 | 1473 | 1473 | 0.343209 | 0.00100753 | 7.90913
4 x Unnamed | STEEL/E24-2 | GRENAILLE-PEINT | 436 | N43 | 3 |  | 8 | 0 | 0.3 | 1473 | 1473 | 0.343209 | 0.00100753 | 7.90913
4 x Unnamed | STEEL/E24-2 | GRENAILLE-PEINT | 436 | N40 | 3 |  | 8 | 0 | 0.3 | 1473 | 1473 | 0.343209 | 0.00100753 | 7.90913
3 x Unnamed | STEEL/E24-2 | GRENAILLE-PEINT | 436 | N9 | 3 |  | 8 | 0 | 0.3 | 1473 | 1473 | 0.343209 | 0.00100753 | 7.90913
2 x Unnamed | STEEL/E24-2 | GRENAILLE-PEINT | 441 | P32 | 3 |  | 0.3 | 0 | 0 | 50 | 50 | 0.01165 | 0.0000342 | 0.26847
4 x Unnamed | STEEL/E24-2 | GRENAILLE-PEINT | 441 | N9 | 3 |  | 0.3 | 0 | 0 | 50 | 50 | 0.01165 | 0.0000342 | 0.26847
4 x Unnamed | STEEL/E24-2 | GRENAILLE-PEINT | 436 | N48 | 3 |  | 8 | 0 | 0.3 | 1473 | 1473 | 0.343209 | 0.00100753 | 7.90913
2 x Unnamed | STEEL/E24-2 | GRENAILLE-PEINT | 440 | N39 | 1 |  | 0.3 | 0 | 0 | 50 | 50 | 0.01165 | 0.0000342 | 0.26847
2 x Unnamed | STEEL/E24-2 | GRENAILLE-PEINT | 436 | N39 | 1 |  | 8 | 0 | 0.3 | 1473 | 1473 | 0.343209 | 0.00100753 | 7.90913
8 x Unnamed | STEEL/E24-2 | GRENAILLE-PEINT | 436 | N41 | 1 |  | 8 | 0 | 0.3 | 1473 | 1473 | 0.343209 | 0.00100753 | 7.90913
6 x Unnamed | STEEL/E24-2 | GRENAILLE-PEINT | 436 | N10 | 1 |  | 8 | 0 | 0.3 | 1473 | 1473 | 0.343209 | 0.00100753 | 7.90913
8 x Unnamed | STEEL/E24-2 | GRENAILLE-PEINT | 436 | N8 | 1 |  | 8 | 0 | 0.3 | 1473 | 1473 | 0.343209 | 0.00100753 | 7.90913
4 x Unnamed | STEEL/E24-2 | GRENAILLE-PEINT | 442 | N8 | 1 |  | 0.3 | 0 | 0 | 50 | 50 | 0.01165 | 0.0000342 | 0.26847
8 x Unnamed | STEEL/E24-2 | GRENAILLE-PEINT | 442 | N10 | 1 |  | 0.3 | 0 | 0 | 50 | 50 | 0.01165 | 0.0000342 | 0.26847
4 x Unnamed | STEEL/E24-2 | GRENAILLE-PEINT | 442 | P36 | 1 |  | 0.3 | 0 | 0 | 50 | 50 | 0.01165 | 0.0000342 | 0.26847
8 x Unnamed | STEEL/E24-2 | GRENAILLE-PEINT | 436 | N47 | 1 |  | 8 | 0 | 0.3 | 1473 | 1473 | 0.343209 | 0.00100753 | 7.90913
2 x Unnamed | STEEL/E24-2 | GRENAILLE-PEINT | 436 | N38 | 1 |  | 8 | 0 | 0.3 | 1473 | 1473 | 0.343209 | 0.00100753 | 7.90913
2 x Unnamed | STEEL/E24-2 | GRENAILLE-PEINT | 440 | N38 | 1 |  | 0.3 | 0 | 0 | 50 | 50 | 0.01165 | 0.0000342 | 0.26847
2 x ATTACHE | STEEL/S235JR | GALVANISE | 428 | P106 | 1 | ATTACHE | 1.1 | 0 | 0.1 | 210 | 210 | 0.04893 | 0.00014364 | 1.12757
3 x ATTACHE | STEEL/S235JR | GALVANISE | 428 | P99 | 1 | ATTACHE | 1.1 | 0 | 0.1 | 210 | 210 | 0.04893 | 0.00014364 | 1.12757
2 x ATTACHE | STEEL/S235JR | GALVANISE | 428 | P105 | 1 | ATTACHE | 1.1 | 0 | 0.1 | 210 | 210 | 0.04893 | 0.00014364 | 1.12757
3 x ATTACHE | STEEL/S235JR | GALVANISE | 428 | P98 | 1 | ATTACHE | 1.1 | 0 | 0.1 | 210 | 210 | 0.04893 | 0.00014364 | 1.12757
2 x ATTACHE | STEEL/S235JR | GALVANISE | 428 | P104 | 1 | ATTACHE | 1.1 | 0 | 0.1 | 210 | 210 | 0.04893 | 0.00014364 | 1.12757
3 x ATTACHE | STEEL/S235JR | GALVANISE | 428 | P97 | 1 | ATTACHE | 1.1 | 0 | 0.1 | 210 | 210 | 0.04893 | 0.00014364 | 1.12757
33 x ATTACHE | STEEL/S235JR | GALVANISE | H24 | H24 | 1 | ATTACHE | 1.1 | 0 | 0.1 | 210 | 210 | 0.04893 | 0.00014364 | 1.12757
2 x ATTACHE | STEEL/S235JR | GALVANISE | 428 | P102 | 1 | ATTACHE | 1.1 | 0 | 0.1 | 210 | 210 | 0.04893 | 0.00014364 | 1.12757
ATTACHE | STEEL/S235JR | GALVANISE | H32 | H32 | 1 | ATTACHE | 1.1 | 0 | 0.1 | 210 | 210 | 0.04893 | 0.00014364 | 1.12757
6 x ATTACHE | STEEL/S235JR | GALVANISE | H21 | H21 | 1 | ATTACHE | 0.9 | 0 | 0 | 192 | 192 | 0.044736 | 0.000131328 | 1.03092
ATTACHE | STEEL/S235JR | GALVANISE | H22 | H22 | 1 | ATTACHE | 0.9 | 0 | 0 | 192 | 192 | 0.044736 | 0.000131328 | 1.03092
4 x ATTACHE | STEEL/S235JR | GALVANISE | H20 | H20 | 1 | ATTACHE | 1.1 | 0 | 0.1 | 210 | 210 | 0.04893 | 0.00014364 | 1.12757
Unnamed | STEEL/E24-2 | GRENAILLE-PEINT | 445 | P15 | 1 |  | 1.1 | 0 | 0 | 198.7 | 198.741 | 0.0463065 | 0.000130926 | 1.02777
Unnamed | STEEL/E24-2 | GRENAILLE-PEINT | 444 | P15 | 1 |  | 1.1 | 0 | 0 | 198.7 | 198.741 | 0.0463065 | 0.000130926 | 1.02777
Unnamed | STEEL/E24-2 | GRENAILLE-PEINT | 445 | P14 | 1 |  | 1.1 | 0 | 0 | 198.7 | 198.741 | 0.0463065 | 0.000130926 | 1.02777
Unnamed | STEEL/E24-2 | GRENAILLE-PEINT | 444 | P14 | 1 |  | 1.1 | 0 | 0 | 198.7 | 198.741 | 0.0463065 | 0.000130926 | 1.02777
Unnamed | STEEL/E24-2 | GRENAILLE-PEINT | 445 | P16 | 1 |  | 1.1 | 0 | 0 | 198.7 | 198.741 | 0.0463065 | 0.000130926 | 1.02777
Unnamed | STEEL/E24-2 | GRENAILLE-PEINT | 444 | P16 | 1 |  | 1.1 | 0 | 0 | 198.7 | 198.741 | 0.0463065 | 0.000130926 | 1.02777
3 x Unnamed | STEEL/E24-2 | GRENAILLE-PEINT | 445 | P13 | 1 |  | 1.1 | 0 | 0 | 198.7 | 198.741 | 0.0463065 | 0.000130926 | 1.02777
3 x Unnamed | STEEL/E24-2 | GRENAILLE-PEINT | 444 | P13 | 1 |  | 1.1 | 0 | 0 | 198.7 | 198.741 | 0.0463065 | 0.000130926 | 1.02777
ATTACHE | STEEL/E24-2 | GRENAILLE-PEINT | H33 | H33 | 1 | ATTACHE | 1.1 | 0 | 0 | 195 | 195 | 0.045435 | 0.00013338 | 1.04703
2 x Unnamed | STEEL/E24-2 | GRENAILLE-PEINT | 439 | P7 | 1 |  | 0.9 | 0 | 0 | 190.1 | 190.096 | 0.0442924 | 0.000130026 | 1.0207
Unnamed | STEEL/E24-2 | GRENAILLE-PEINT | 445 | P12 | 1 |  | 1.1 | 0 | 0 | 198.7 | 198.741 | 0.0463065 | 0.000130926 | 1.02777
Unnamed | STEEL/E24-2 | GRENAILLE-PEINT | 444 | P12 | 1 |  | 1.1 | 0 | 0 | 198.7 | 198.741 | 0.0463065 | 0.000130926 | 1.02777
2 x Unnamed | STEEL/E24-2 | GRENAILLE-PEINT | 439 | P11 | 1 |  | 0.9 | 0 | 0 | 190 | 190.04 | 0.0442793 | 0.000129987 | 1.0204
2 x Unnamed | STEEL/E24-2 | GRENAILLE-PEINT | 439 | P10 | 1 |  | 0.9 | 0 | 0 | 190.1 | 190.096 | 0.0442924 | 0.000130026 | 1.0207
2 x Unnamed | STEEL/E24-2 | GRENAILLE-PEINT | 439 | P9 | 1 |  | 0.9 | 0 | 0 | 190.1 | 190.096 | 0.0442924 | 0.000130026 | 1.0207
Unnamed | STEEL/E24-2 | GRENAILLE-PEINT | 439 | P8 | 1 |  | 0.9 | 0 | 0 | 190.1 | 190.096 | 0.0442924 | 0.000130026 | 1.0207
2 x Unnamed | STEEL/E24-2 | GRENAILLE-PEINT | 439 | P6 | 1 |  | 0.9 | 0 | 0 | 190.1 | 190.096 | 0.0442924 | 0.000130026 | 1.0207
3 x Unnamed | STEEL/E24-2 | GRENAILLE-PEINT | 436 | N11 | 1 |  | 8 | 0 | 0.3 | 1473 | 1473 | 0.343209 | 0.00100753 | 7.90913
2 x Unnamed | STEEL/E24-2 | GRENAILLE-PEINT | 436 | N14 | 1 |  | 8 | 0 | 0.3 | 1473 | 1473 | 0.343209 | 0.00100753 | 7.90913
4 x Unnamed | STEEL/E24-2 | GRENAILLE-PEINT | 436 | N12 | 1 |  | 8 | 0 | 0.3 | 1473 | 1473 | 0.343209 | 0.00100753 | 7.90913
4 x Unnamed | STEEL/E24-2 | GRENAILLE-PEINT | 436 | N7 | 1 |  | 8 | 0 | 0.3 | 1473 | 1473 | 0.343209 | 0.00100753 | 7.90913
4 x Unnamed | STEEL/E24-2 | GRENAILLE-PEINT | 436 | N6 | 1 |  | 8 | 0 | 0.3 | 1473 | 1473 | 0.343209 | 0.00100753 | 7.90913
6 x Unnamed | STEEL/E24-2 | GRENAILLE-PEINT | 436 | N13 | 1 |  | 8 | 0 | 0.3 | 1473 | 1473 | 0.343209 | 0.00100753 | 7.90913
2 x ATTACHE | STEEL/E24-2 | GRENAILLE-PEINT | H12 | H12 | 1 | ATTACHE | 0.5 | 0 | 0 | 100 | 100 | 0.0233 | 0.0000684 | 0.53694
2 x ATTACHE | STEEL/E24-2 | GRENAILLE-PEINT | H11 | H11 | 1 | ATTACHE | 1.2 | 0 | 0.1 | 240 | 240 | 0.05592 | 0.00016416 | 1.28866
Unnamed | STEEL/E24-2 | GRENAILLE-PEINT | 436 | P113 | 3 |  | 8 | 0 | 0.3 | 1473 | 1473 | 0.343209 | 0.00100753 | 7.90913
2 x Unnamed | STEEL/E24-2 | GRENAILLE-PEINT | 441 | N40 | 3 |  | 0.3 | 0 | 0 | 50 | 50 | 0.01165 | 0.0000342 | 0.26847
2 x Unnamed | STEEL/E24-2 | GRENAILLE-PEINT | 441 | P30 | 2 |  | 0.3 | 0 | 0 | 50 | 50 | 0.01165 | 0.0000342 | 0.26847
4 x Unnamed | STEEL/E24-2 | GRENAILLE-PEINT | 441 | N44 | 2 |  | 0.3 | 0 | 0 | 50 | 50 | 0.01165 | 0.0000342 | 0.26847
2 x Unnamed | STEEL/E24-2 | GRENAILLE-PEINT | 441 | N45 | 2 |  | 0.3 | 0 | 0 | 50 | 50 | 0.01165 | 0.0000342 | 0.26847
3 x Unnamed | STEEL/E24-2 | GRENAILLE-PEINT | 437 | N45 | 2 |  | 11.1 | 0 | 0.5 | 2073 | 2073 | 0.483009 | 0.00141793 | 11.1308
4 x Unnamed | STEEL/E24-2 | GRENAILLE-PEINT | 437 | N44 | 2 |  | 11.1 | 0 | 0.5 | 2073 | 2073 | 0.483009 | 0.00141793 | 11.1308
3 x Unnamed | STEEL/E24-2 | GRENAILLE-PEINT | 437 | N49 | 2 |  | 11.1 | 0 | 0.5 | 2073 | 2073 | 0.483009 | 0.00141793 | 11.1308
2 x Unnamed | STEEL/E24-2 | GRENAILLE-PEINT | 437 | N46 | 2 |  | 11.1 | 0 | 0.5 | 2073 | 2073 | 0.483009 | 0.00141793 | 11.1308
Unnamed | STEEL/E24-2 | GRENAILLE-PEINT | 438 | P30 | 2 |  | 5.7 | 0 | 0.3 | 1050 | 1050 | 0.24465 | 0.0007182 | 5.63787
2 x Unnamed | STEEL/E24-2 | GRENAILLE-PEINT | 436 | N15 | 3 |  | 8 | 0 | 0.3 | 1473 | 1473 | 0.343209 | 0.00100753 | 7.90913
4 x Unnamed | STEEL/E24-2 | GRENAILLE-PEINT | 436 | N16 | 1 |  | 8 | 0 | 0.3 | 1473 | 1473 | 0.343209 | 0.00100753 | 7.90913
3 x Unnamed | STEEL/E24-2 | GRENAILLE-PEINT | 436 | N42 | 1 |  | 8 | 0 | 0.3 | 1473 | 1473 | 0.343209 | 0.00100753 | 7.90913
LISSE | STEEL/S235JR | GRENAILLE-PEINT | L12 | L12 | 1 | LISSE | 9.2 | 0 | 0.3 | 1718.1 | 1718.06 | 0.400308 | 0.00117515 | 9.22495

# IfcBeam: L60*80*7, LISSE
In: Undefined
Description: L60*80*7; Material: STEEL/S235JR
Tekla Commun - Finition: GRENAILLE-PEINT; Repère de pièce: 893; Repère d'assemblage: P123; Phase: 1; Profil: L60*80*7; Nom: LISSE; sets with these values: 2
Tekla Quantités - Poids: 13.1 kg; Volume: 0 m3; Surface supérieure totale: 0 m2; Surface par tonne: 38.5 m2; Surface nette: 0.5 m2; Hauteur: 60 mm; Largeur: 80 mm; Longueur: 1792.1 mm; sets with these values: 2
Pset_BeamCommon - LoadBearing: no; Reference: 893
BaseQuantities - Length: 1792.07 mm; OuterSurfaceArea: 0.503642 m2; NetVolume: 0.00166842 m3; NetWeight: 13.0971 kg

# IfcBeam: L70*50*6 (12)
In: Undefined
Description: L70*50*6; Material: STEEL/E24-2
Tekla Commun - Finition: GRENAILLE-PEINT; Repère de pièce: H92; Repère d'assemblage: H92; Phase: 2; Profil: L70*50*6; Nom: ATTACHE; sets with these values: 2
Tekla Quantités - Poids: 1.6 kg; Volume: 0 m3; Surface supérieure totale: 0 m2; Surface par tonne: 42.6 m2; Surface nette: 0.1 m2; Hauteur: 70 mm; Largeur: 50 mm; Longueur: 300 mm; sets with these values: 2
Pset_BeamCommon - LoadBearing: no; Reference: H92
BaseQuantities - Length: 299.999 mm; OuterSurfaceArea: 0.0689997 m2; NetVolume: 0.000205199 m3; NetWeight: 1.61081 kg

# IfcBeam: L70*7 (401)
In: Undefined
Description: L70*7
Tekla Commun - Profil: L70*7; sets with these values: 2
Tekla Quantités - Volume: 0 m3; Surface supérieure totale: 0 m2; Surface par tonne: 36.9 m2; Hauteur: 70 mm; sets with these values: 2
Pset_BeamCommon - LoadBearing: no
Name | Material | Finition | Repère de pièce = Reference | Repère d'assemblage | Phase | Nom | Poids (kg) | Surface nette (m2) | Largeur (mm) | Longueur (mm) | Length (mm) | OuterSurfaceArea (m2) | NetVolume (m3) | NetWeight (kg)
2 x ATTACHE | STEEL/E24-2 | GRENAILLE-PEINT | H43 | H43 | 7 | ATTACHE | 1.7 | 0.1 | 70 | 250 | 250 | 0.068 | 0.00023275 | 1.82709
ATTACHE | STEEL/E24-2 | GRENAILLE-PEINT | 671 | L109 | 7 | ATTACHE | 0.9 | 0 | 70 | 120 | 120 | 0.03264 | 0.00011172 | 0.877002
3 x ATTACHE | STEEL/E24-2 | GRENAILLE-PEINT | 670 | P132 | 7 | ATTACHE | 1.6 | 0.1 | 70 | 217.5 | 217.5 | 0.05916 | 0.000171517 | 1.34641
Unnamed | STEEL/E24-2 | GRENAILLE-PEINT | 668 | S87 | 6 |  | 0.3 | 0 | 70 | 60 | 60 | 0.01632 | 0.00005586 | 0.438501
2 x Unnamed | STEEL/E24-2 | GRENAILLE-PEINT | 668 | S88 | 6 |  | 0.3 | 0 | 70 | 60 | 60 | 0.01632 | 0.00005586 | 0.438501
10 x Unnamed | STEEL/E24-2 | GRENAILLE-PEINT | 669 | H42 | 6 |  | 0.6 | 0 | 70 | 80 | 80 | 0.02176 | 0.00007448 | 0.584668
4 x Unnamed | STEEL/E24-2 | GRENAILLE-PEINT | 668 | S10 | 6 |  | 0.3 | 0 | 70 | 60 | 60 | 0.01632 | 0.00005586 | 0.438501
Unnamed | STEEL/E24-2 | GRENAILLE-PEINT | 668 | L81 | 6 |  | 0.3 | 0 | 70 | 60 | 60 | 0.01632 | 0.00005586 | 0.438501
4 x Unnamed | STEEL/E24-2 | GRENAILLE-PEINT | 668 | L85 | 6 |  | 0.3 | 0 | 70 | 60 | 60 | 0.01632 | 0.00005586 | 0.438501
2 x Unnamed | STEEL/E24-2 | GRENAILLE-PEINT | 668 | S9 | 6 |  | 0.3 | 0 | 70 | 60 | 60 | 0.01632 | 0.00005586 | 0.438501
8 x Unnamed | STEEL/E24-2 | GRENAILLE-PEINT | 668 | S8 | 6 |  | 0.3 | 0 | 70 | 60 | 60 | 0.01632 | 0.00005586 | 0.438501
Unnamed | STEEL/E24-2 | GRENAILLE-PEINT | 668 | L83 | 6 |  | 0.3 | 0 | 70 | 60 | 60 | 0.01632 | 0.00005586 | 0.438501
3 x Unnamed | STEEL/E24-2 | GRENAILLE-PEINT | 668 | S5 | 6 |  | 0.3 | 0 | 70 | 60 | 60 | 0.01632 | 0.00005586 | 0.438501
6 x Unnamed | STEEL/E24-2 | GRENAILLE-PEINT | 668 | S7 | 6 |  | 0.3 | 0 | 70 | 60 | 60 | 0.01632 | 0.00005586 | 0.438501
4 x Unnamed | STEEL/E24-2 | GRENAILLE-PEINT | 668 | L84 | 6 |  | 0.3 | 0 | 70 | 60 | 60 | 0.01632 | 0.00005586 | 0.438501
3 x Unnamed | STEEL/E24-2 | GRENAILLE-PEINT | 668 | S6 | 6 |  | 0.3 | 0 | 70 | 60 | 60 | 0.01632 | 0.00005586 | 0.438501
3 x ATTACHE | STEEL/E24-2 | GRENAILLE-PEINT | H40 | H40 | 6 | ATTACHE | 1.4 | 0.1 | 70 | 205 | 205 | 0.05576 | 0.000190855 | 1.49821
3 x Unnamed | STEEL/E24-2 | GRENAILLE-PEINT | 668 | L86 | 6 |  | 0.3 | 0 | 70 | 60 | 60 | 0.01632 | 0.00005586 | 0.438501
3 x Unnamed | STEEL/E24-2 | GRENAILLE-PEINT | 668 | L87 | 6 |  | 0.3 | 0 | 70 | 60 | 60 | 0.01632 | 0.00005586 | 0.438501
2 x Unnamed | STEEL/E24-2 | GRENAILLE-PEINT | 668 | L82 | 6 |  | 0.3 | 0 | 70 | 60 | 60 | 0.01632 | 0.00005586 | 0.438501
2 x ATTACHE | STEEL/E24-2 | GRENAILLE-PEINT | 673 | L19 | 4 | ATTACHE | 0.3 | 0 | 70 | 60 | 60 | 0.01632 | 0.00005586 | 0.438501
ATTACHE | STEEL/E24-2 | GRENAILLE-PEINT | H41 | H41 | 4 | ATTACHE | 2.1 | 0.1 | 70 | 285 | 285 | 0.07752 | 0.000265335 | 2.08288
3 x CV | STEEL/E24-2 | GRENAILLE-PEINT | 675 | W6 | 3 | CV | 0.5 | 0 | 70 | 70 | 70 | 0.01904 | 0.00006517 | 0.511584
LISSE | STEEL/E24-2 | GRENAILLE-PEINT | 664 | L80 | 3 | LISSE | 14.4 | 0.6 | 70 | 1965.4 | 1965.43 | 0.534596 | 0.00182981 | 14.364
4 x LISSE | STEEL/E24-2 | GRENAILLE-PEINT | 661 | L80 | 3 | LISSE | 14.2 | 0.5 | 70 | 1926.6 | 1926.58 | 0.52403 | 0.00179365 | 14.0801
LISSE | STEEL/E24-2 | GRENAILLE-PEINT | 663 | L80 | 3 | LISSE | 14.4 | 0.5 | 70 | 1946.4 | 1946.41 | 0.529423 | 0.00181211 | 14.225
LISSE | STEEL/E24-2 | GRENAILLE-PEINT | 662 | L115 | 3 | LISSE | 14.2 | 0.5 | 70 | 1931.3 | 1931.29 | 0.525311 | 0.00179803 | 14.1145
LISSE | STEEL/E24-2 | GRENAILLE-PEINT | 661 | L115 | 3 | LISSE | 14.2 | 0.5 | 70 | 1926.6 | 1926.58 | 0.52403 | 0.00179365 | 14.0801
LISSE | STEEL/E24-2 | GRENAILLE-PEINT | 661 | L115 | 3 | LISSE | 14.2 | 0.5 | 70 | 1927.1 | 1927.06 | 0.52416 | 0.00179409 | 14.0836
LISSE | STEEL/E24-2 | GRENAILLE-PEINT | 660 | L115 | 3 | LISSE | 14.2 | 0.5 | 70 | 1926.6 | 1926.58 | 0.52403 | 0.00179365 | 14.0801
LISSE | STEEL/E24-2 | GRENAILLE-PEINT | 660 | L115 | 3 | LISSE | 14.2 | 0.5 | 70 | 1926 | 1926.02 | 0.523876 | 0.00179312 | 14.076
LISSE | STEEL/E24-2 | GRENAILLE-PEINT | 659 | L115 | 3 | LISSE | 15.4 | 0.6 | 70 | 2086.6 | 2086.58 | 0.567548 | 0.0019426 | 15.2494
ATTACHE | STEEL/E24-2 | GRENAILLE-PEINT | 658 | L52 | 2 | ATTACHE | 2.7 | 0.1 | 70 | 365.5 | 365.5 | 0.099416 | 0.00034028 | 2.6712
ATTACHE | STEEL/E24-2 | GRENAILLE-PEINT | 656 | L52 | 2 | ATTACHE | 2.7 | 0.1 | 70 | 365.5 | 365.5 | 0.099416 | 0.00034028 | 2.6712
SOLIVE | STEEL/S235JR | GALVANISE | 655 | S2 | 2 | SOLIVE | 0.9 | 0 | 70 | 110 | 110 | 0.02992 | 0.00010241 | 0.803918
20 x SOLIVE | STEEL/S235JR | GALVANISE | 655 | S1 | 2 | SOLIVE | 0.9 | 0 | 70 | 110 | 110 | 0.02992 | 0.00010241 | 0.803918
7 x ATTACHE | STEEL/E24-2 | GRENAILLE-PEINT | H39 | H39 | 3 | ATTACHE | 0.9 | 0 | 70 | 120 | 120 | 0.03264 | 0.00011172 | 0.877002
CSV | STEEL/E24-2 | GRENAILLE-PEINT | C128 | C128 | 3 | CSV | 19 | 0.6 | 70 | 2563 | 2563 | 0.697136 | 0.00238615 | 18.7313
4 x CSV | STEEL/E24-2 | GRENAILLE-PEINT | C117 | C117 | 3 | CSV | 37.6 | 1.5 | 70 | 5100 | 5100 | 1.3872 | 0.0047481 | 37.2726
4 x CSV | STEEL/E24-2 | GRENAILLE-PEINT | C118 | C118 | 3 | CSV | 37.1 | 1.5 | 70 | 5030 | 5030 | 1.36816 | 0.00468293 | 36.761
2 x CSV | STEEL/E24-2 | GRENAILLE-PEINT | C119 | C119 | 3 | CSV | 37.6 | 1.5 | 70 | 5100 | 5100 | 1.3872 | 0.0047481 | 37.2726
2 x CSV | STEEL/E24-2 | GRENAILLE-PEINT | C116 | C116 | 3 | CSV | 34.1 | 1.2 | 70 | 4620 | 4620 | 1.25664 | 0.00430122 | 33.7646
2 x CSV | STEEL/E24-2 | GRENAILLE-PEINT | C115 | C115 | 3 | CSV | 33.6 | 1.2 | 70 | 4550 | 4550 | 1.2376 | 0.00423605 | 33.253
2 x CSV | STEEL/E24-2 | GRENAILLE-PEINT | C113 | C113 | 3 | CSV | 35 | 1.2 | 70 | 4740 | 4740 | 1.28928 | 0.00441294 | 34.6416
8 x CSV | STEEL/E24-2 | GRENAILLE-PEINT | C103 | C103 | 3 | CSV | 17.6 | 0.6 | 70 | 2380 | 2380 | 0.64736 | 0.00221578 | 17.3939
2 x ATTACHE | STEEL/S235JR | GRENAILLE-PEINT | H37 | H37 | 2 | ATTACHE | 1.2 | 0 | 70 | 160 | 160.003 | 0.0435207 | 0.000148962 | 1.16936
54 x ATTACHE | STEEL/S235JR | GRENAILLE-PEINT | H35 | H35 | 2 | ATTACHE | 1.2 | 0.1 | 70 | 180 | 180.003 | 0.0489607 | 0.000167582 | 1.31552
2 x CSV | STEEL/E24-2 | GRENAILLE-PEINT | C129 | C129 | 2 | CSV | 19.1 | 0.6 | 70 | 2588.3 | 2588.33 | 0.704026 | 0.00240974 | 18.9164
CSV | STEEL/E24-2 | GRENAILLE-PEINT | C129 | C129 | 2 | CSV | 19.1 | 0.6 | 70 | 2588.3 | 2588.34 | 0.704029 | 0.00240974 | 18.9165
2 x CSV | STEEL/E24-2 | GRENAILLE-PEINT | C130 | C130 | 2 | CSV | 18.4 | 0.6 | 70 | 2498.8 | 2498.75 | 0.67966 | 0.00232634 | 18.2617
4 x CSV | STEEL/E24-2 | GRENAILLE-PEINT | C110 | C110 | 2 | CSV | 18.4 | 0.6 | 70 | 2498.8 | 2498.75 | 0.67966 | 0.00232634 | 18.2617
4 x CSV | STEEL/E24-2 | GRENAILLE-PEINT | C131 | C131 | 2 | CSV | 17.4 | 0.6 | 70 | 2361.3 | 2361.25 | 0.64226 | 0.00219832 | 17.2568
4 x CSV | STEEL/E24-2 | GRENAILLE-PEINT | C132 | C132 | 2 | CSV | 14.4 | 0.6 | 70 | 1960 | 1960 | 0.53312 | 0.00182476 | 14.3244
8 x CSV | STEEL/E24-2 | GRENAILLE-PEINT | C111 | C111 | 2 | CSV | 19.5 | 0.6 | 70 | 2638.8 | 2638.75 | 0.71774 | 0.00245668 | 19.2849
CSV | STEEL/E24-2 | GRENAILLE-PEINT | C133 | C133 | 2 | CSV | 20.1 | 0.8 | 70 | 2728.3 | 2728.33 | 0.742106 | 0.00254008 | 19.9396
CSV | STEEL/E24-2 | GRENAILLE-PEINT | C133 | C133 | 2 | CSV | 20.1 | 0.8 | 70 | 2728.3 | 2728.34 | 0.742109 | 0.00254008 | 19.9397
8 x CSV | STEEL/E24-2 | GRENAILLE-PEINT | C112 | C112 | 2 | CSV | 18.4 | 0.6 | 70 | 2501.3 | 2501.25 | 0.68034 | 0.00232866 | 18.28
3 x CSV | STEEL/E24-2 | GRENAILLE-PEINT | C134 | C134 | 2 | CSV | 15.4 | 0.6 | 70 | 2100 | 2100 | 0.5712 | 0.0019551 | 15.3475
ATTACHE | STEEL/E24-2 | GRENAILLE-PEINT | 674 | M5 | 1 | ATTACHE | 0.9 | 0 | 70 | 104 | 104 | 0.028288 | 0.000096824 | 0.760068
Unnamed | STEEL/E24-2 | GRENAILLE-PEINT | 614 | L45 | 3 |  | 0.9 | 0 | 70 | 116.9 | 116.891 | 0.0317942 | 0.000108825 | 0.854277
Unnamed | STEEL/E24-2 | GRENAILLE-PEINT | 613 | P26 | 1 |  | 2 | 0.1 | 70 | 274 | 274 | 0.074528 | 0.000255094 | 2.00249
6 x CSV | STEEL/E24-2 | GRENAILLE-PEINT | C107 | C107 | 1 | CSV | 17.9 | 0.6 | 70 | 2430 | 2430 | 0.66096 | 0.00226233 | 17.7593
4 x CSV | STEEL/E24-2 | GRENAILLE-PEINT | C109 | C109 | 1 | CSV | 17.9 | 0.6 | 70 | 2420 | 2420 | 0.65824 | 0.00225302 | 17.6862
2 x CSV | STEEL/E24-2 | GRENAILLE-PEINT | C102 | C102 | 1 | CSV | 24.2 | 0.8 | 70 | 3294.8 | 3294.77 | 0.896178 | 0.00306743 | 24.0794
20 x CSV | STEEL/E24-2 | GRENAILLE-PEINT | C108 | C108 | 1 | CSV | 17.9 | 0.6 | 70 | 2430 | 2430 | 0.66096 | 0.00226233 | 17.7593
14 x CSV | STEEL/E24-2 | GRENAILLE-PEINT | C104 | C104 | 1 | CSV | 18.7 | 0.6 | 70 | 2530 | 2530 | 0.68816 | 0.00235543 | 18.4901
2 x ATTACHE | STEEL/E24-2 | GRENAILLE-PEINT | H38 | H38 | 1 | ATTACHE | 0.9 | 0 | 70 | 120 | 120 | 0.03264 | 0.00011172 | 0.877002
Unnamed | STEEL/E24-2 | GRENAILLE-PEINT | 616 | P109 | 1 |  | 0.9 | 0 | 30 | 123.6 | 123.6 | 0.0336192 | 0.0000804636 | 0.631639
3 x Unnamed | STEEL/E24-2 | GRENAILLE-PEINT | 615 | K28 | 1 |  | 2.1 | 0.1 | 70 | 278 | 277.902 | 0.0755895 | 0.000256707 | 2.01515
2 x STABILITE | STEEL/E24-2 | GRENAILLE-PEINT | V12 | V12 | 1 | STABILITE | 43.3 | 1.6 | 70 | 5871.6 | 5871.65 | 1.59709 | 0.00547023 | 42.9413
Unnamed | STEEL/E24-2 | GRENAILLE-PEINT | 613 | P27 | 1 |  | 2 | 0.1 | 70 | 274 | 274 | 0.074528 | 0.000255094 | 2.00249
2 x Unnamed | STEEL/E24-2 | GRENAILLE-PEINT | 614 | L44 | 1 |  | 0.9 | 0 | 70 | 116.9 | 116.891 | 0.0317942 | 0.000108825 | 0.854277
Unnamed | STEEL/E24-2 | GRENAILLE-PEINT | 613 | P23 | 1 |  | 2 | 0.1 | 70 | 274 | 274 | 0.074528 | 0.000255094 | 2.00249
Unnamed | STEEL/E24-2 | GRENAILLE-PEINT | 613 | P24 | 1 |  | 2 | 0.1 | 70 | 274 | 274 | 0.074528 | 0.000255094 | 2.00249
2 x Unnamed | STEEL/E24-2 | GRENAILLE-PEINT | 614 | L42 | 1 |  | 0.9 | 0 | 70 | 116.9 | 116.891 | 0.0317942 | 0.000108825 | 0.854277
Unnamed | STEEL/E24-2 | GRENAILLE-PEINT | 613 | P25 | 1 |  | 2 | 0.1 | 70 | 274 | 274 | 0.074528 | 0.000255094 | 2.00249
Unnamed | STEEL/E24-2 | GRENAILLE-PEINT | 614 | L43 | 3 |  | 0.9 | 0 | 70 | 116.9 | 116.891 | 0.0317942 | 0.000108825 | 0.854277
Unnamed | STEEL/E24-2 | GRENAILLE-PEINT | 613 | P22 | 1 |  | 2 | 0.1 | 70 | 274 | 274 | 0.074528 | 0.000255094 | 2.00249
FEUILLURE | STEEL/E24-2 | GRENAILLE-PEINT | L20 | L20 | 2 | FEUILLURE | 6.2 | 0.2 | 70 | 833 | 833 | 0.226576 | 0.000775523 | 6.08786
16 x ATTACHE | STEEL/S235JR | GRENAILLE-PEINT | H36 | H36 | 1 | ATTACHE | 1.6 | 0.1 | 70 | 220 | 220 | 0.05984 | 0.00020482 | 1.60784
LISSE | STEEL/S235JR | GRENAILLE-PEINT | 601 | L11 | 1 | LISSE | 13.6 | 0.5 | 70 | 1841.2 | 1841.17 | 0.500798 | 0.00171413 | 13.4559
CSV | STEEL/E24-2 | GRENAILLE-PEINT | C120 | C120 | 3 | CSV | 37.1 | 1.5 | 70 | 5025 | 5025 | 1.3668 | 0.00467828 | 36.7245
2 x STABILITE | STEEL/E24-2 | GRENAILLE-PEINT | V4 | V4 | 1 | STABILITE | 43.3 | 1.6 | 70 | 5871.6 | 5871.65 | 1.59709 | 0.00547023 | 42.9413
2 x CSV | STEEL/E24-2 | GRENAILLE-PEINT | C113 | C113 | 1 | CSV | 35 | 1.2 | 70 | 4740 | 4740 | 1.28928 | 0.00441294 | 34.6416
2 x CSV | STEEL/E24-2 | GRENAILLE-PEINT | C121 | C121 | 1 | CSV | 18.7 | 0.6 | 70 | 2530 | 2530 | 0.68816 | 0.00235543 | 18.4901
12 x CSV | STEEL/E24-2 | GRENAILLE-PEINT | C103 | C103 | 1 | CSV | 17.6 | 0.6 | 70 | 2380 | 2380 | 0.64736 | 0.00221578 | 17.3939
2 x CSV | STEEL/E24-2 | GRENAILLE-PEINT | C115 | C115 | 1 | CSV | 33.6 | 1.2 | 70 | 4550 | 4550 | 1.2376 | 0.00423605 | 33.253
2 x CSV | STEEL/E24-2 | GRENAILLE-PEINT | C116 | C116 | 1 | CSV | 34.1 | 1.2 | 70 | 4620 | 4620 | 1.25664 | 0.00430122 | 33.7646
4 x CSV | STEEL/E24-2 | GRENAILLE-PEINT | C117 | C117 | 1 | CSV | 37.6 | 1.5 | 70 | 5100 | 5100 | 1.3872 | 0.0047481 | 37.2726
10 x CSV | STEEL/E24-2 | GRENAILLE-PEINT | C118 | C118 | 1 | CSV | 37.1 | 1.5 | 70 | 5030 | 5030 | 1.36816 | 0.00468293 | 36.761
2 x CSV | STEEL/E24-2 | GRENAILLE-PEINT | C119 | C119 | 1 | CSV | 37.6 | 1.5 | 70 | 5100 | 5100 | 1.3872 | 0.0047481 | 37.2726
9 x ATTACHE | STEEL/E24-2 | GRENAILLE-PEINT | H39 | H39 | 1 | ATTACHE | 0.9 | 0 | 70 | 120 | 120 | 0.03264 | 0.00011172 | 0.877002
2 x CSV | STEEL/E24-2 | GRENAILLE-PEINT | C100 | C100 | 1 | CSV | 25.8 | 1 | 70 | 3490.9 | 3490.85 | 0.949512 | 0.00324998 | 25.5124
CSV | STEEL/E24-2 | GRENAILLE-PEINT | C99 | C99 | 1 | CSV | 17.6 | 0.6 | 70 | 2395 | 2395 | 0.65144 | 0.00222975 | 17.5035
CSV | STEEL/E24-2 | GRENAILLE-PEINT | C98 | C98 | 1 | CSV | 17.6 | 0.6 | 70 | 2395 | 2395 | 0.65144 | 0.00222975 | 17.5035
8 x CSV | STEEL/E24-2 | GRENAILLE-PEINT | C106 | C106 | 1 | CSV | 16.2 | 0.6 | 70 | 2190 | 2190 | 0.59568 | 0.00203889 | 16.0053
4 x CSV | STEEL/E24-2 | GRENAILLE-PEINT | C97 | C97 | 1 | CSV | 7.2 | 0.3 | 70 | 975 | 975 | 0.2652 | 0.000907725 | 7.12564
2 x CSV | STEEL/E24-2 | GRENAILLE-PEINT | C105 | C105 | 1 | CSV | 17.8 | 0.6 | 70 | 2410 | 2410 | 0.65552 | 0.00224371 | 17.6131
4 x CSV | STEEL/E24-2 | GRENAILLE-PEINT | C127 | C127 | 3 | CSV | 18.4 | 0.6 | 70 | 2512 | 2512 | 0.683265 | 0.00233868 | 18.3586
2 x CSV | STEEL/E24-2 | GRENAILLE-PEINT | C101 | C101 | 1 | CSV | 24.2 | 0.8 | 70 | 3297.7 | 3297.66 | 0.896963 | 0.00307012 | 24.1004
2 x CSV | STEEL/E24-2 | GRENAILLE-PEINT | C114 | C114 | 1 | CSV | 16.2 | 0.6 | 70 | 2202.1 | 2202.07 | 0.598963 | 0.00205013 | 16.0935
CSV | STEEL/E24-2 | GRENAILLE-PEINT | C126 | C126 | 3 | CSV | 18.7 | 0.6 | 70 | 2525 | 2525 | 0.6868 | 0.00235078 | 18.4536
CSV | STEEL/E24-2 | GRENAILLE-PEINT | C126 | C126 | 3 | CSV | 18.7 | 0.6 | 70 | 2525 | 2525 | 0.6868 | 0.00235077 | 18.4536
2 x CSV | STEEL/E24-2 | GRENAILLE-PEINT | C125 | C125 | 3 | CSV | 18.7 | 0.6 | 70 | 2520 | 2520 | 0.68544 | 0.00234612 | 18.417
CSV | STEEL/E24-2 | GRENAILLE-PEINT | C124 | C124 | 3 | CSV | 18.7 | 0.6 | 70 | 2515 | 2515 | 0.68408 | 0.00234147 | 18.3805
CSV | STEEL/E24-2 | GRENAILLE-PEINT | C123 | C123 | 3 | CSV | 17.8 | 0.6 | 70 | 2415 | 2415 | 0.65688 | 0.00224837 | 17.6497
3 x CSV | STEEL/E24-2 | GRENAILLE-PEINT | C122 | C122 | 3 | CSV | 17.9 | 0.6 | 70 | 2420 | 2420 | 0.65824 | 0.00225302 | 17.6862

# IfcBeam: L80*8 (238)
In: Undefined
Description: L80*8; Material: STEEL/E24-2
Tekla Commun - Finition: GRENAILLE-PEINT; Profil: L80*8; sets with these values: 2
Tekla Quantités - Volume: 0 m3; Surface supérieure totale: 0 m2; Surface par tonne: 32.2 m2; sets with these values: 2
Pset_BeamCommon - LoadBearing: no
Name | Repère de pièce = Reference | Repère d'assemblage | Phase | Nom | Poids (kg) | Surface nette (m2) | Hauteur (mm) | Largeur (mm) | Longueur (mm) | Length (mm) | OuterSurfaceArea (m2) | NetVolume (m3) | NetWeight (kg)
2 x ATTACHE | 1211 | M15 | 7 | ATTACHE | 1.4 | 0.1 | 80 | 80 | 150 | 150 | 0.04665 | 0.0001824 | 1.43184
2 x ATTACHE | H62 | H62 | 7 | ATTACHE | 0.9 | 0 | 17.8 | 80 | 100 | 100 | 0.0311 | 0.0000718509 | 0.56403
2 x ATTACHE | H60 | H60 | 7 | ATTACHE | 0.9 | 0 | 80 | 80 | 100 | 100 | 0.0311 | 0.0001216 | 0.95456
2 x ATTACHE | H57 | H57 | 7 | ATTACHE | 0.9 | 0 | 80 | 80 | 100 | 100 | 0.0311 | 0.0001216 | 0.95456
60 x CRAPAUD | H56 | H56 | 6 | CRAPAUD | 1.1 | 0 | 17.2 | 80 | 110 | 110 | 0.03421 | 0.000078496 | 0.616193
61 x CRAPAUD | C136 | C136 | 4 | CRAPAUD | 0.9 | 0 | 80 | 18 | 90 | 90.0003 | 0.0279901 | 0.0000648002 | 0.508682
58 x ATTACHE | H63 | H63 | 4 | ATTACHE | 0.9 | 0 | 80 | 18 | 90 | 90.0003 | 0.0279901 | 0.0000648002 | 0.508682
8 x ATTACHE | H61 | H61 | 4 | ATTACHE | 1.2 | 0 | 18 | 80 | 120 | 120 | 0.03732 | 0.0000864 | 0.67824
ATTACHE | H64 | H64 | 4 | ATTACHE | 1.2 | 0 | 80 | 80 | 129 | 129 | 0.040119 | 0.000151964 | 1.19292
ATTACHE | H66 | H66 | 4 | ATTACHE | 0.9 | 0 | 80 | 80 | 105 | 105 | 0.032655 | 0.00012768 | 1.00229
ATTACHE | H67 | H67 | 4 | ATTACHE | 0.9 | 0 | 80 | 80 | 105 | 105 | 0.032655 | 0.00012768 | 1.00229
ATTACHE | H65 | H65 | 4 | ATTACHE | 1.2 | 0 | 80 | 80 | 129 | 129 | 0.040119 | 0.000151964 | 1.19292
8 x ATTACHE | H68 | H68 | 4 | ATTACHE | 1.4 | 0 | 80 | 80 | 140 | 140 | 0.04354 | 0.00017024 | 1.33638
8 x ATTACHE | H69 | H69 | 4 | ATTACHE | 1.4 | 0 | 80 | 80 | 140 | 140 | 0.04354 | 0.00017024 | 1.33638
Unnamed | 1219 | W7 | 3 |  | 0.9 | 0 | 80 | 80 | 80 | 80 | 0.02488 | 0.00009228 | 0.724398
Unnamed | 1220 | W7 | 3 |  | 0.9 | 0 | 80 | 80 | 80 | 80 | 0.02488 | 0.00009178 | 0.720473
Unnamed | 1221 | M16 | 3 |  | 0.9 | 0 | 80 | 80 | 100 | 100 | 0.0311 | 0.0001216 | 0.95456
ATTACHE | H59 | H59 | 2 | ATTACHE | 1.4 | 0.1 | 80 | 80 | 150 | 150 | 0.04665 | 0.0001824 | 1.43184
ATTACHE | H58 | H58 | 1 | ATTACHE | 1.4 | 0.1 | 80 | 80 | 150 | 150 | 0.04665 | 0.0001824 | 1.43184
ATTACHE | H70 | H70 | 1 | ATTACHE | 1.7 | 0.1 | 80 | 80 | 177 | 177 | 0.055047 | 0.000215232 | 1.68957
Unnamed | 1226 | L45 | 3 |  | 1.1 | 0 | 80 | 80 | 116.9 | 116.891 | 0.036353 | 0.000142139 | 1.11579
Unnamed | 1227 | P17 | 1 |  | 2.7 | 0.1 | 80 | 80 | 278 | 278 | 0.086458 | 0.000338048 | 2.65368
Unnamed | 1221 | P49 | 1 |  | 0.9 | 0 | 80 | 80 | 100 | 100 | 0.0311 | 0.0001216 | 0.95456
Unnamed | 1221 | P48 | 1 |  | 0.9 | 0 | 80 | 80 | 100 | 100 | 0.0311 | 0.0001216 | 0.95456
Unnamed | 1221 | P112 | 1 |  | 0.9 | 0 | 80 | 80 | 100 | 100 | 0.0311 | 0.0001216 | 0.95456
Unnamed | 1221 | P111 | 1 |  | 0.9 | 0 | 80 | 80 | 100 | 100 | 0.0311 | 0.0001216 | 0.95456
Unnamed | 1221 | P110 | 1 |  | 0.9 | 0 | 80 | 80 | 100 | 100 | 0.0311 | 0.0001216 | 0.95456
Unnamed | 1221 | P109 | 1 |  | 0.9 | 0 | 80 | 80 | 100 | 100 | 0.0311 | 0.0001216 | 0.95456
Unnamed | 1221 | P45 | 1 |  | 0.9 | 0 | 80 | 80 | 100 | 100 | 0.0311 | 0.0001216 | 0.95456
Unnamed | 1221 | P44 | 1 |  | 0.9 | 0 | 80 | 80 | 100 | 100 | 0.0311 | 0.0001216 | 0.95456
2 x Unnamed | 1226 | L44 | 1 |  | 1.1 | 0 | 80 | 80 | 116.9 | 116.891 | 0.036353 | 0.000142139 | 1.11579
Unnamed | 1225 | L55 | 1 |  | 0.9 | 0 | 80 | 80 | 95.1 | 95.09 | 0.029573 | 0.000115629 | 0.907691
Unnamed | 1224 | P113 | 3 |  | 1.2 | 0 | 80 | 80 | 127 | 126.951 | 0.0394816 | 0.000154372 | 1.21182
2 x Unnamed | 1223 | L42 | 1 |  | 1.1 | 0 | 80 | 80 | 116.9 | 116.891 | 0.036353 | 0.000142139 | 1.11579
Unnamed | 1223 | L43 | 3 |  | 1.1 | 0 | 80 | 80 | 116.9 | 116.891 | 0.036353 | 0.000142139 | 1.11579

# IfcBeam: L90*9 (3)
In: Undefined
Description: L90*9; Material: STEEL/E24-2
Tekla Commun - Finition: GRENAILLE-PEINT; Phase: 1; Profil: L90*9; sets with these values: 2
Tekla Quantités - Volume: 0 m3; Surface supérieure totale: 0 m2; Surface par tonne: 28.8 m2; Surface nette: 0.1 m2; Hauteur: 90 mm; Largeur: 90 mm; sets with these values: 2
Pset_BeamCommon - LoadBearing: no
Name | Repère de pièce = Reference | Repère d'assemblage | Nom | Poids (kg) | Longueur (mm) = Length (mm) | OuterSurfaceArea (m2) | NetVolume (m3) | NetWeight (kg)
PLATINE | 1236 | P17 | PLATINE | 2.6 | 216 | 0.075816 | 0.000332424 | 2.60953
ATTACHE | H75 | H75 | ATTACHE | 3.3 | 270 | 0.09477 | 0.00041553 | 3.26191
ATTACHE | H74 | H74 | ATTACHE | 3.3 | 270 | 0.09477 | 0.00041553 | 3.26191

# IfcBeam: PL10*120 (17)
In: Undefined
Description: PL10*120
Tekla Commun - Phase: 1; Profil: PL10*120; Nom: PLAT; sets with these values: 2
Tekla Quantités - Volume: 0 m3; Surface supérieure totale: 0 m2; Surface nette: 0.1 m2; Hauteur: 120 mm; Largeur: 10 mm; sets with these values: 2
Pset_BeamCommon - LoadBearing: no
Name | Material | Finition | Repère de pièce = Reference | Repère d'assemblage | Poids (kg) | Surface par tonne (m2) | Longueur (mm) = Length (mm) | OuterSurfaceArea (m2) | NetVolume (m3) | NetWeight (kg)
PLAT | STEEL/E24-2 | GRENAILLE-PEINT | 177 | K95 | 2 | 28.8 | 210 | 0.057 | 0.000252 | 1.9782
2 x PLAT | STEEL/S235JR | GALVANISE | 234 | P56 | 2.1 | 28.8 | 220 | 0.0596 | 0.000264 | 2.0724
2 x PLAT | STEEL/S235JR | GALVANISE | 234 | P57 | 2.1 | 28.8 | 220 | 0.0596 | 0.000264 | 2.0724
2 x PLAT | STEEL/S235JR | GALVANISE | 234 | P55 | 2.1 | 28.8 | 220 | 0.0596 | 0.000264 | 2.0724
2 x PLAT | STEEL/S235JR | GALVANISE | 234 | P54 | 2.1 | 28.8 | 220 | 0.0596 | 0.000264 | 2.0724
PLAT | STEEL/E24-2 | GRENAILLE-PEINT | 280 | K87 | 1.7 | 28.9 | 195 | 0.0531 | 0.000234 | 1.8369
PLAT | STEEL/E24-2 | GRENAILLE-PEINT | 280 | K88 | 1.7 | 28.9 | 195 | 0.0531 | 0.000234 | 1.8369
PLAT | STEEL/E24-2 | GRENAILLE-PEINT | 280 | K89 | 1.7 | 28.9 | 195 | 0.0531 | 0.000234 | 1.8369
PLAT | STEEL/E24-2 | GRENAILLE-PEINT | 177 | K48 | 2 | 28.8 | 210 | 0.057 | 0.000252 | 1.9782
PLAT | STEEL/E24-2 | GRENAILLE-PEINT | 177 | K43 | 2 | 28.8 | 210 | 0.057 | 0.000252 | 1.9782
PLAT | STEEL/E24-2 | GRENAILLE-PEINT | 177 | K46 | 2 | 28.8 | 210 | 0.057 | 0.000252 | 1.9782
PLAT | STEEL/E24-2 | GRENAILLE-PEINT | 177 | K47 | 2 | 28.8 | 210 | 0.057 | 0.000252 | 1.9782
PLAT | STEEL/E24-2 | GRENAILLE-PEINT | 177 | K44 | 2 | 28.8 | 210 | 0.057 | 0.000252 | 1.9782

# IfcBeam: PL10*130 (4)
In: Undefined
Description: PL10*130; Material: STEEL/S235JR
Tekla Commun - Finition: GALVANISE; Repère de pièce: 235; Phase: 1; Profil: PL10*130; Nom: PLAT; sets with these values: 2
Tekla Quantités - Poids: 2.2 kg; Volume: 0 m3; Surface supérieure totale: 0 m2; Surface par tonne: 28.6 m2; Surface nette: 0.1 m2; Hauteur: 130 mm; Largeur: 10 mm; Longueur: 220 mm; sets with these values: 2
Pset_BeamCommon - LoadBearing: no; Reference: 235
BaseQuantities - Length: 220 mm; OuterSurfaceArea: 0.0642 m2; NetVolume: 0.000286 m3; NetWeight: 2.2451 kg
Name | Repère d'assemblage
PLAT | P59
PLAT | P61
PLAT | P58
PLAT | P60

# IfcBeam: PL10*150 (75)
In: Undefined
Description: PL10*150
Tekla Commun - Finition: GRENAILLE-PEINT; Profil: PL10*150; sets with these values: 2
Tekla Quantités - Volume: 0 m3; Hauteur: 150 mm; Largeur: 10 mm; sets with these values: 2
Pset_BeamCommon - LoadBearing: no
Name | Material | Repère de pièce = Reference | Repère d'assemblage | Phase | Nom | Poids (kg) | Surface supérieure totale (m2) | Surface par tonne (m2) | Surface nette (m2) | Longueur (mm) | Length (mm) | OuterSurfaceArea (m2) | NetVolume (m3) | NetWeight (kg)
PLATINE | STEEL/E24-2 | 226 | N43 | 3 | PLATINE | 3.4 | 0 | 28.1 | 0.1 | 287 | 287 | 0.09484 | 0.0004305 | 3.37942
4 x PLAT | STEEL/E24-2 | 176 | K42 | 3 | PLAT | 2.4 | 0 | 28.5 | 0.1 | 210 | 210 | 0.0702 | 0.000315 | 2.47275
PLAT | STEEL/E24-2 | 178 | K49 | 1 | PLAT | 2.4 | 0 | 28.5 | 0.1 | 210 | 210 | 0.0702 | 0.000315 | 2.47275
TOLE | STEEL/E36-3 | 208 | P119 | 2 | TOLE | 3.4 | 0 | 28.1 | 0.1 | 287 | 287 | 0.09484 | 0.0004305 | 3.37942
TOLE | STEEL/E36-3 | 209 | P113 | 3 | TOLE | 3.4 | 0 | 28.1 | 0.1 | 287 | 287 | 0.09484 | 0.0004305 | 3.37942
4 x PLAT | STEEL/E24-2 | 176 | K41 | 1 | PLAT | 2.4 | 0 | 28.5 | 0.1 | 210 | 210 | 0.0702 | 0.000315 | 2.47275
4 x PLAT | STEEL/E24-2 | 176 | K42 | 1 | PLAT | 2.4 | 0 | 28.5 | 0.1 | 210 | 210 | 0.0702 | 0.000315 | 2.47275
PLAT | STEEL/E24-2 | 176 | K39 | 1 | PLAT | 2.4 | 0 | 28.5 | 0.1 | 210 | 210 | 0.0702 | 0.000315 | 2.47275
PLAT | STEEL/E24-2 | 176 | K43 | 1 | PLAT | 2.4 | 0 | 28.5 | 0.1 | 210 | 210 | 0.0702 | 0.000315 | 2.47275
PLAT | STEEL/E24-2 | 176 | K40 | 1 | PLAT | 2.4 | 0 | 28.5 | 0.1 | 210 | 210 | 0.0702 | 0.000315 | 2.47275
PLAT | STEEL/E24-2 | 176 | K44 | 1 | PLAT | 2.4 | 0 | 28.5 | 0.1 | 210 | 210 | 0.0702 | 0.000315 | 2.47275
PLAT | STEEL/E24-2 | 176 | K45 | 1 | PLAT | 2.4 | 0 | 28.5 | 0.1 | 210 | 210 | 0.0702 | 0.000315 | 2.47275
PLAT | STEEL/E24-2 | 176 | K38 | 1 | PLAT | 2.4 | 0 | 28.5 | 0.1 | 210 | 210 | 0.0702 | 0.000315 | 2.47275
PLAT | STEEL/E24-2 | 176 | K37 | 1 | PLAT | 2.4 | 0 | 28.5 | 0.1 | 210 | 210 | 0.0702 | 0.000315 | 2.47275
PLAT | STEEL/E36-3 | 298 | N46 | 2 | PLAT | 9.7 | 0 | 27.4 | 0.3 | 815.6 | 815.584 | 0.263987 | 0.00122338 | 9.60351
PLAT | STEEL/E36-3 | 301 | N43 | 3 | PLAT | 9.7 | 0 | 27.4 | 0.3 | 815.6 | 815.584 | 0.263987 | 0.00122338 | 9.60351
4 x ECLISSE | STEEL/E36-3 | H3 | H3 | 2 | ECLISSE | 6 | 0.1 | 27.8 | 0.2 | 510 | 510 | 0.1662 | 0.000765 | 6.00525
PLAT | STEEL/E36-3 | 298 | N44 | 2 | PLAT | 9.7 | 0 | 27.4 | 0.3 | 815.6 | 815.584 | 0.263987 | 0.00122338 | 9.60351
PLAT | STEEL/E36-3 | 298 | N45 | 2 | PLAT | 9.7 | 0 | 27.4 | 0.3 | 815.6 | 815.584 | 0.263987 | 0.00122338 | 9.60351
PLAT | STEEL/E36-3 | 298 | N49 | 2 | PLAT | 9.7 | 0 | 27.4 | 0.3 | 815.6 | 815.584 | 0.263987 | 0.00122338 | 9.60351
24 x ECLISSE | STEEL/E36-3 | H3 | H3 | 1 | ECLISSE | 6 | 0.1 | 27.8 | 0.2 | 510 | 510 | 0.1662 | 0.000765 | 6.00525
PLAT | STEEL/E36-3 | 298 | N7 | 1 | PLAT | 9.7 | 0 | 27.4 | 0.3 | 815.6 | 815.584 | 0.263987 | 0.00122338 | 9.60351
PLAT | STEEL/E36-3 | 298 | N6 | 1 | PLAT | 9.7 | 0 | 27.4 | 0.3 | 815.6 | 815.584 | 0.263987 | 0.00122338 | 9.60351
PLAT | STEEL/E36-3 | 298 | N11 | 1 | PLAT | 9.7 | 0 | 27.4 | 0.3 | 815.6 | 815.584 | 0.263987 | 0.00122338 | 9.60351
PLAT | STEEL/E36-3 | 298 | N12 | 1 | PLAT | 9.7 | 0 | 27.4 | 0.3 | 815.6 | 815.584 | 0.263987 | 0.00122338 | 9.60351
2 x PLAT | STEEL/E36-3 | 298 | N8 | 1 | PLAT | 9.7 | 0 | 27.4 | 0.3 | 815.6 | 815.584 | 0.263987 | 0.00122338 | 9.60351
2 x PLAT | STEEL/E36-3 | 298 | N41 | 1 | PLAT | 9.7 | 0 | 27.4 | 0.3 | 815.6 | 815.584 | 0.263987 | 0.00122338 | 9.60351
2 x PLAT | STEEL/E36-3 | 298 | N10 | 1 | PLAT | 9.7 | 0 | 27.4 | 0.3 | 815.6 | 815.584 | 0.263987 | 0.00122338 | 9.60351
2 x PLAT | STEEL/E36-3 | 298 | N47 | 1 | PLAT | 9.7 | 0 | 27.4 | 0.3 | 815.6 | 815.584 | 0.263987 | 0.00122338 | 9.60351
4 x ECLISSE | STEEL/E36-3 | H3 | H3 | 3 | ECLISSE | 6 | 0.1 | 27.8 | 0.2 | 510 | 510 | 0.1662 | 0.000765 | 6.00525
PLAT | STEEL/E36-3 | 298 | N40 | 3 | PLAT | 9.7 | 0 | 27.4 | 0.3 | 815.6 | 815.584 | 0.263987 | 0.00122338 | 9.60351
PLAT | STEEL/E36-3 | 298 | N9 | 3 | PLAT | 9.7 | 0 | 27.4 | 0.3 | 815.6 | 815.584 | 0.263987 | 0.00122338 | 9.60351
PLAT | STEEL/E36-3 | 298 | N48 | 3 | PLAT | 9.7 | 0 | 27.4 | 0.3 | 815.6 | 815.584 | 0.263987 | 0.00122338 | 9.60351

# IfcBeam: PL10*180 (8)
In: Undefined
Description: PL10*180; Material: STEEL/E24-2
Tekla Commun - Finition: GRENAILLE-PEINT; Profil: PL10*180; Nom: POUTRE; sets with these values: 2
Tekla Quantités - Poids: 2.2 kg; Volume: 0 m3; Surface supérieure totale: 0 m2; Surface par tonne: 28.5 m2; Surface nette: 0.1 m2; Hauteur: 180 mm; Largeur: 10 mm; sets with these values: 2
Pset_BeamCommon - LoadBearing: no
Name | Repère de pièce = Reference | Repère d'assemblage | Phase | Longueur (mm) | Length (mm) | OuterSurfaceArea (m2) | NetVolume (m3) | NetWeight (kg)
POUTRE | 297 | P39 | 2 | 156.2 | 156.227 | 0.0629662 | 0.000281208 | 2.20748
POUTRE | 297 | P5 | 3 | 156.2 | 156.227 | 0.0629662 | 0.000281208 | 2.20748
POUTRE | 203 | P1 | 1 | 156.2 | 156.227 | 0.0629662 | 0.000281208 | 2.20748
POUTRE | 203 | P3 | 1 | 156.2 | 156.227 | 0.0629662 | 0.000281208 | 2.20748
POUTRE | 204 | P38 | 1 | 155.1 | 155.079 | 0.0625301 | 0.000279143 | 2.19127
POUTRE | 203 | P4 | 1 | 156.2 | 156.227 | 0.0629662 | 0.000281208 | 2.20748
POUTRE | 203 | P37 | 1 | 156.2 | 156.227 | 0.0629662 | 0.000281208 | 2.20748
POUTRE | 203 | P2 | 1 | 156.2 | 156.227 | 0.0629662 | 0.000281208 | 2.20748

# IfcBeam: PL10*200 (18)
In: Undefined
Description: PL10*200
Tekla Commun - Phase: 1; Profil: PL10*200; Nom: TOLE; sets with these values: 2
Tekla Quantités - Volume: 0 m3; Hauteur: 200 mm; Largeur: 10 mm; sets with these values: 2
Pset_BeamCommon - LoadBearing: no
Name | Material | Finition | Repère de pièce = Reference | Repère d'assemblage | Poids (kg) | Surface supérieure totale (m2) | Surface par tonne (m2) | Surface nette (m2) | Longueur (mm) = Length (mm) | OuterSurfaceArea (m2) | NetVolume (m3) | NetWeight (kg)
2 x TOLE | STEEL/S235JR | GALVANISE | 232 | P56 | 3.1 | 0 | 28 | 0.1 | 200 | 0.088 | 0.0004 | 3.14
2 x TOLE | STEEL/S235JR | GALVANISE | 232 | P57 | 3.1 | 0 | 28 | 0.1 | 200 | 0.088 | 0.0004 | 3.14
2 x TOLE | STEEL/S235JR | GALVANISE | 232 | P55 | 3.1 | 0 | 28 | 0.1 | 200 | 0.088 | 0.0004 | 3.14
2 x TOLE | STEEL/S235JR | GALVANISE | 232 | P54 | 3.1 | 0 | 28 | 0.1 | 200 | 0.088 | 0.0004 | 3.14
TOLE | STEEL/S235JR | GALVANISE | 233 | P59 | 3.1 | 0 | 28 | 0.1 | 200 | 0.088 | 0.0004 | 3.14
TOLE | STEEL/S235JR | GALVANISE | 233 | P61 | 3.1 | 0 | 28 | 0.1 | 200 | 0.088 | 0.0004 | 3.14
TOLE | STEEL/S235JR | GALVANISE | 233 | P58 | 3.1 | 0 | 28 | 0.1 | 200 | 0.088 | 0.0004 | 3.14
TOLE | STEEL/S235JR | GALVANISE | 233 | P60 | 3.1 | 0 | 28 | 0.1 | 200 | 0.088 | 0.0004 | 3.14
TOLE | STEEL/E36-3 | GRENAILLE-PEINT | 207 | P26 | 7.5 | 0.1 | 27.3 | 0.2 | 480 | 0.2056 | 0.00096 | 7.536
TOLE | STEEL/E36-3 | GRENAILLE-PEINT | 207 | P27 | 7.5 | 0.1 | 27.3 | 0.2 | 480 | 0.2056 | 0.00096 | 7.536
TOLE | STEEL/E36-3 | GRENAILLE-PEINT | 207 | P23 | 7.5 | 0.1 | 27.3 | 0.2 | 480 | 0.2056 | 0.00096 | 7.536
TOLE | STEEL/E36-3 | GRENAILLE-PEINT | 207 | P22 | 7.5 | 0.1 | 27.3 | 0.2 | 480 | 0.2056 | 0.00096 | 7.536
TOLE | STEEL/E36-3 | GRENAILLE-PEINT | 207 | P25 | 7.5 | 0.1 | 27.3 | 0.2 | 480 | 0.2056 | 0.00096 | 7.536
TOLE | STEEL/E36-3 | GRENAILLE-PEINT | 207 | P24 | 7.5 | 0.1 | 27.3 | 0.2 | 480 | 0.2056 | 0.00096 | 7.536

# IfcBeam: PL10*225 (7)
In: Undefined
Description: PL10*225; Material: STEEL/E24-2
Tekla Commun - Finition: GRENAILLE-PEINT; Repère de pièce: 172; Phase: 1; Profil: PL10*225; Nom: PLATINE; sets with these values: 2
Tekla Quantités - Poids: 3 kg; Volume: 0 m3; Surface supérieure totale: 0 m2; Surface par tonne: 28.1 m2; Surface nette: 0.1 m2; Hauteur: 225 mm; Largeur: 10 mm; Longueur: 170 mm; sets with these values: 2
Pset_BeamCommon - LoadBearing: no; Reference: 172
BaseQuantities - Length: 170 mm; OuterSurfaceArea: 0.0844 m2; NetVolume: 0.0003825 m3; NetWeight: 3.00263 kg
Name | Repère d'assemblage
PLATINE | P47
PLATINE | P46
PLATINE | P42
PLATINE | P43
PLATINE | P41
PLATINE | P50
PLATINE | P40

# IfcBeam: PL10*55 (64)
In: Undefined
Description: PL10*55; Material: STEEL/E36-3
Tekla Commun - Finition: GRENAILLE-PEINT; Repère de pièce: H4; Repère d'assemblage: H4; Profil: PL10*55; Nom: ECLISSE; sets with these values: 2
Tekla Quantités - Poids: 2.2 kg; Volume: 0 m3; Surface supérieure totale: 0 m2; Surface par tonne: 30.6 m2; Surface nette: 0.1 m2; Hauteur: 55 mm; Largeur: 10 mm; Longueur: 510 mm; sets with these values: 2
Pset_BeamCommon - LoadBearing: no; Reference: H4
BaseQuantities - Length: 510 mm; OuterSurfaceArea: 0.0674 m2; NetVolume: 0.0002805 m3; NetWeight: 2.20193 kg
Name | Phase
8 x ECLISSE | 2
48 x ECLISSE | 1
8 x ECLISSE | 3

# IfcBeam: PL10*80, PLATINE
In: Undefined
Description: PL10*80; Material: STEEL/E24-2
Tekla Commun - Finition: GRENAILLE-PEINT; Repère de pièce: 173; Repère d'assemblage: P51; Phase: 1; Profil: PL10*80; Nom: PLATINE; sets with these values: 2
Tekla Quantités - Poids: 1.1 kg; Volume: 0 m3; Surface supérieure totale: 0 m2; Surface par tonne: 30.3 m2; Surface nette: 0 m2; Hauteur: 80 mm; Largeur: 10 mm; Longueur: 170 mm; sets with these values: 2
Pset_BeamCommon - LoadBearing: no; Reference: 173
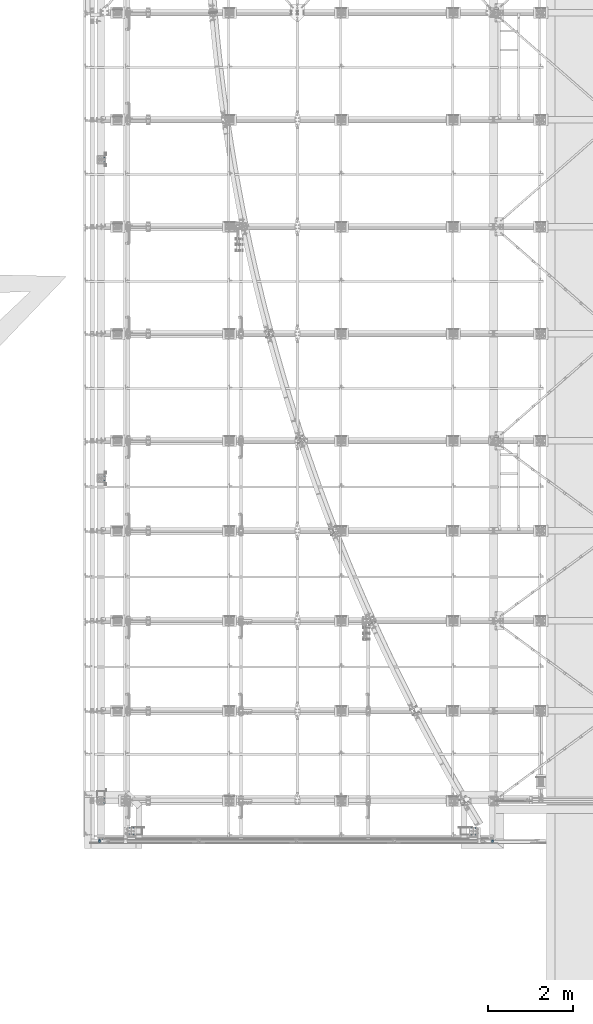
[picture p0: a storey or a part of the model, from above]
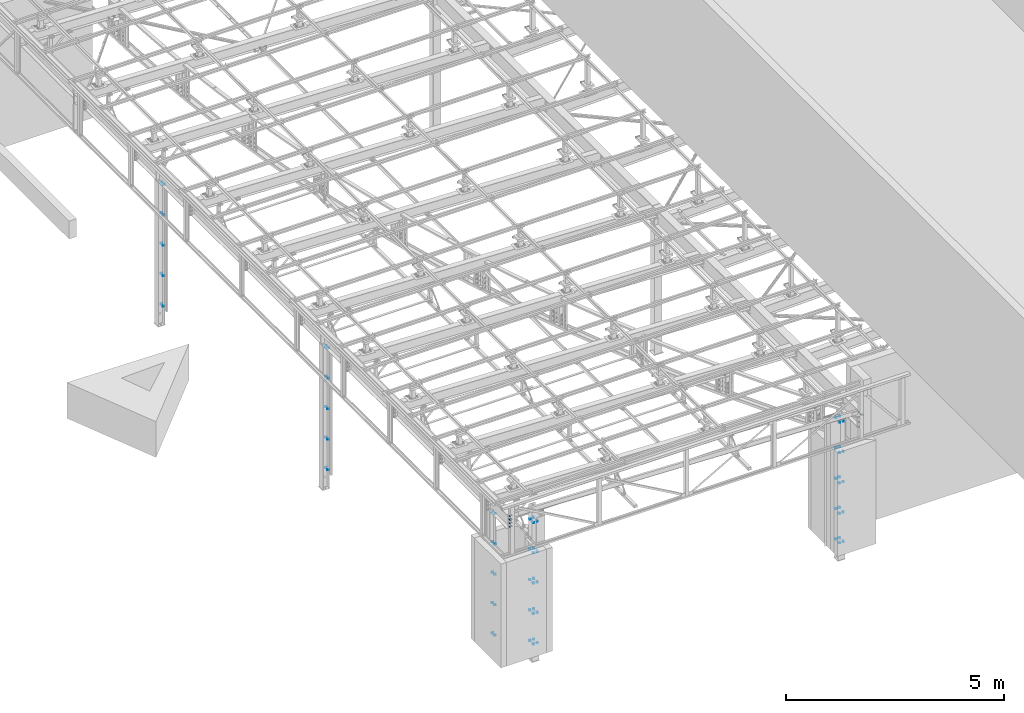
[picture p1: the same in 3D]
Properties of the parts of a building model (IFC2X3), part 3 of 13

# IfcBeam: PL10*80, PLATINE
BaseQuantities - Length: 170 mm; OuterSurfaceArea: 0.0322 m2; NetVolume: 0.000136 m3; NetWeight: 1.0676 kg

# IfcBeam: PL100*10 (11)
In: Undefined
Description: PL100*10; Material: STEEL/E24-2
Tekla Commun - Finition: GRENAILLE-PEINT; Profil: PL100*10; sets with these values: 2
Tekla Quantités - Volume: 0 m3; Surface supérieure totale: 0 m2; Surface nette: 0 m2; Hauteur: 100 mm; Largeur: 10 mm; sets with these values: 2
Pset_BeamCommon - LoadBearing: no
Name | Repère de pièce = Reference | Repère d'assemblage | Phase | Poids (kg) | Surface par tonne (m2) | Longueur (mm) = Length (mm) | OuterSurfaceArea (m2) | NetVolume (m3) | NetWeight (kg)
Unnamed | 190 | M16 | 3 | 0.9 | 30.6 | 100 | 0.024 | 0.0001 | 0.785
2 x PLATINE | 243 | B4 | 1 | 1.6 | 29.2 | 200 | 0.046 | 0.0002 | 1.57 | Tekla Commun - Nom: PLATINE
Unnamed | 190 | P49 | 1 | 0.9 | 30.6 | 100 | 0.024 | 0.0001 | 0.785
Unnamed | 190 | P48 | 1 | 0.9 | 30.6 | 100 | 0.024 | 0.0001 | 0.785
Unnamed | 190 | P112 | 1 | 0.9 | 30.6 | 100 | 0.024 | 0.0001 | 0.785
Unnamed | 190 | P111 | 1 | 0.9 | 30.6 | 100 | 0.024 | 0.0001 | 0.785
Unnamed | 190 | P110 | 1 | 0.9 | 30.6 | 100 | 0.024 | 0.0001 | 0.785
Unnamed | 190 | P109 | 1 | 0.9 | 30.6 | 100 | 0.024 | 0.0001 | 0.785
Unnamed | 190 | P45 | 1 | 0.9 | 30.6 | 100 | 0.024 | 0.0001 | 0.785
Unnamed | 190 | P44 | 1 | 0.9 | 30.6 | 100 | 0.024 | 0.0001 | 0.785

# IfcBeam: PL100*5 (22)
In: Undefined
Description: PL100*5; Material: STEEL/S235JR
Tekla Commun - Finition: GALVANISE; Repère de pièce: 1201; Phase: 4; Profil: PL100*5; Nom: SUPPORT; sets with these values: 2
Tekla Quantités - Poids: 0.6 kg; Volume: 0 m3; Surface supérieure totale: 0 m2; Surface par tonne: 57.1 m2; Surface nette: 0 m2; Hauteur: 100 mm; Largeur: 5 mm; Longueur: 200 mm; sets with these values: 2
Pset_BeamCommon - LoadBearing: no; Reference: 1201
BaseQuantities - Length: 200 mm; OuterSurfaceArea: 0.04069 m2; NetVolume: 0.000090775 m3; NetWeight: 0.712584 kg
Name | Repère d'assemblage
6 x SUPPORT | E1
16 x SUPPORT | E2

# IfcBeam: PL100*6 (10)
In: Undefined
Description: PL100*6
Tekla Commun - Phase: 1; Profil: PL100*6; sets with these values: 2
Tekla Quantités - Volume: 0 m3; Surface supérieure totale: 0 m2; Surface nette: 0 m2; Hauteur: 100 mm; Largeur: 6 mm; sets with these values: 2
Pset_BeamCommon - LoadBearing: no
Name | Material | Finition | Repère de pièce = Reference | Repère d'assemblage | Poids (kg) | Surface par tonne (m2) | Longueur (mm) = Length (mm) | OuterSurfaceArea (m2) | NetVolume (m3) | NetWeight (kg)
8 x Unnamed | STEEL/S235JR | GALVANISE | 343 | S29 | 0.3 | 47.7 | 90 | 0.0197246 | 0.00005265 | 0.413302
Unnamed | STEEL/E24-2 | GRENAILLE-PEINT | 338 | M2 | 0.6 | 47.1 | 120 | 0.02664 | 0.000072 | 0.5652
Unnamed | STEEL/E24-2 | GRENAILLE-PEINT | 338 | M1 | 0.6 | 47.1 | 120 | 0.02664 | 0.000072 | 0.5652

# IfcBeam: PL100*8 (12)
In: Undefined
Description: PL100*8; Material: STEEL/E24-2
Tekla Commun - Finition: GRENAILLE-PEINT; Phase: 2; Profil: PL100*8; sets with these values: 2
Tekla Quantités - Volume: 0 m3; Surface supérieure totale: 0 m2; Surface nette: 0 m2; Hauteur: 100 mm; Largeur: 8 mm; sets with these values: 2
Pset_BeamCommon - LoadBearing: no
Name | Repère de pièce = Reference | Repère d'assemblage | Poids (kg) | Surface par tonne (m2) | Longueur (mm) = Length (mm) | OuterSurfaceArea (m2) | NetVolume (m3) | NetWeight (kg)
8 x Unnamed | 677 | L52 | 0.6 | 36.9 | 100 | 0.0232 | 0.00008 | 0.628
2 x Unnamed | 678 | L52 | 0.9 | 36 | 160 | 0.03616 | 0.000128 | 1.0048
2 x GOUSSET | 728 | B6 | 0.9 | 36.5 | 120 | 0.02752 | 0.000096 | 0.7536 | Tekla Commun - Nom: GOUSSET

# IfcBeam: PL1000*2353, GOUSSET
In: Undefined
Description: PL1000*2353; Material: STEEL/S235JR
Tekla Commun - Repère de pièce: G99; Repère d'assemblage: G99; Phase: 1; Profil: PL1000*2353; Nom: GOUSSET; sets with these values: 2
Tekla Quantités - Poids: 25878.2 kg; Volume: 3.3 m3; Surface supérieure totale: 3.3 m2; Surface par tonne: 0.7 m2; Surface nette: 18.8 m2; Hauteur: 2353.3 mm; Largeur: 1000 mm; Longueur: 3193.1 mm; sets with these values: 2
Pset_BeamCommon - LoadBearing: no; Reference: G99
BaseQuantities - Length: 3193.1 mm; OuterSurfaceArea: 18.7658 m2; NetVolume: 3.29659 m3; NetWeight: 25878.2 kg

# IfcBeam: PL110*6 (44)
In: Undefined
Description: PL110*6; Material: STEEL/E24-2
Tekla Commun - Finition: GRENAILLE-PEINT; Profil: PL110*6; Nom: PLAT; sets with these values: 2
Tekla Quantités - Volume: 0 m3; Surface supérieure totale: 0 m2; Surface nette: 0 m2; Hauteur: 110 mm; Largeur: 6 mm; sets with these values: 2
Pset_BeamCommon - LoadBearing: no
Name | Repère de pièce = Reference | Repère d'assemblage | Phase | Poids (kg) | Surface par tonne (m2) | Longueur (mm) = Length (mm) | OuterSurfaceArea (m2) | NetVolume (m3) | NetWeight (kg)
6 x PLAT | 348 | L54 | 5 | 0.5 | 47.6 | 90 | 0.0222 | 0.0000594 | 0.46629
2 x PLAT | 347 | L32 | 5 | 0.3 | 47.7 | 86 | 0.021272 | 0.00005676 | 0.445566
2 x PLAT | 347 | L53 | 5 | 0.3 | 47.7 | 86 | 0.021272 | 0.00005676 | 0.445566
2 x PLAT | 347 | L117 | 5 | 0.3 | 47.7 | 86 | 0.021272 | 0.00005676 | 0.445566
18 x PLAT | 347 | L118 | 2 | 0.3 | 47.7 | 86 | 0.021272 | 0.00005676 | 0.445566
4 x PLAT | 348 | L51 | 2 | 0.5 | 47.6 | 90 | 0.0222 | 0.0000594 | 0.46629
4 x PLAT | 348 | L50 | 2 | 0.5 | 47.6 | 90 | 0.0222 | 0.0000594 | 0.46629
6 x PLAT | 348 | L49 | 2 | 0.5 | 47.6 | 90 | 0.0222 | 0.0000594 | 0.46629

# IfcBeam: PL110*8 (2)
In: Undefined
Description: PL110*8; Material: STEEL/S235JR
Tekla Commun - Finition: GALVANISE; Repère de pièce: 721; Repère d'assemblage: S99; Phase: 2; Profil: PL110*8; Nom: SOLIVE; sets with these values: 2
Tekla Quantités - Poids: 0.9 kg; Volume: 0 m3; Surface supérieure totale: 0 m2; Surface par tonne: 36.5 m2; Surface nette: 0 m2; Hauteur: 110 mm; Largeur: 8 mm; Longueur: 110 mm; sets with these values: 2
Pset_BeamCommon - LoadBearing: no; Reference: 721
BaseQuantities - Length: 110 mm; OuterSurfaceArea: 0.02772 m2; NetVolume: 0.0000968 m3; NetWeight: 0.75988 kg

# IfcBeam: PL114*6, PLAT
In: Undefined
Description: PL114*6; Material: STEEL/S235JR
Tekla Commun - Finition: GRENAILLE-PEINT; Repère de pièce: 354; Repère d'assemblage: L11; Phase: 1; Profil: PL114*6; Nom: PLAT; sets with these values: 2
Tekla Quantités - Poids: 0.3 kg; Volume: 0 m3; Surface supérieure totale: 0 m2; Surface par tonne: 48.4 m2; Surface nette: 0 m2; Hauteur: 114 mm; Largeur: 6 mm; Longueur: 67 mm; sets with these values: 2
Pset_BeamCommon - LoadBearing: no; Reference: 354
BaseQuantities - Length: 67 mm; OuterSurfaceArea: 0.017448 m2; NetVolume: 0.000045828 m3; NetWeight: 0.35975 kg

# IfcBeam: PL115*8 (11)
In: Undefined
Description: PL115*8; Material: STEEL/S235JR
Tekla Commun - Finition: GALVANISE; Phase: 2; Profil: PL115*8; Nom: SOLIVE; sets with these values: 2
Tekla Quantités - Volume: 0 m3; Surface supérieure totale: 0 m2; Hauteur: 115 mm; Largeur: 8 mm; sets with these values: 2
Pset_BeamCommon - LoadBearing: no
Name | Repère de pièce = Reference | Repère d'assemblage | Poids (kg) | Surface par tonne (m2) | Surface nette (m2) | Longueur (mm) = Length (mm) | OuterSurfaceArea (m2) | NetVolume (m3) | NetWeight (kg)
10 x SOLIVE | 722 | S1 | 1.7 | 35.1 | 0.1 | 240 | 0.06088 | 0.0002208 | 1.73328
SOLIVE | 828 | S2 | 1.2 | 35.3 | 0 | 185 | 0.04735 | 0.0001702 | 1.33607

# IfcBeam: PL12*130, PLATINE
In: Undefined
Description: PL12*130; Material: STEEL/E24-2
Tekla Commun - Finition: GRENAILLE-PEINT; Repère de pièce: 1257; Repère d'assemblage: H76; Phase: 3; Profil: PL12*130; Nom: PLATINE; sets with these values: 2
Tekla Quantités - Poids: 3.9 kg; Volume: 0 m3; Surface supérieure totale: 0 m2; Surface par tonne: 23.9 m2; Surface nette: 0.1 m2; Hauteur: 130 mm; Largeur: 12 mm; Longueur: 320 mm; sets with these values: 2
Pset_BeamCommon - LoadBearing: no; Reference: 1257
BaseQuantities - Length: 320 mm; OuterSurfaceArea: 0.094 m2; NetVolume: 0.0004992 m3; NetWeight: 3.91872 kg

# IfcBeam: PL12*160 (2)
In: Undefined
Description: PL12*160; Material: STEEL/E24-2
Tekla Commun - Finition: GRENAILLE-PEINT; Repère de pièce: 1275; Phase: 2; Profil: PL12*160; Nom: PLATINE; sets with these values: 2
Tekla Quantités - Poids: 2.7 kg; Volume: 0 m3; Surface supérieure totale: 0 m2; Surface par tonne: 24.2 m2; Surface nette: 0.1 m2; Hauteur: 160 mm; Largeur: 12 mm; Longueur: 180 mm; sets with these values: 2
Pset_BeamCommon - LoadBearing: no; Reference: 1275
BaseQuantities - Length: 180 mm; OuterSurfaceArea: 0.06576 m2; NetVolume: 0.0003456 m3; NetWeight: 2.71296 kg
Name | Repère d'assemblage
PLATINE | P129
PLATINE | P128

# IfcBeam: PL12*180 (35)
In: Undefined
Description: PL12*180; Material: STEEL/E24-2
Tekla Commun - Finition: GRENAILLE-PEINT; Profil: PL12*180; Nom: PLATINE; sets with these values: 2
Tekla Quantités - Volume: 0 m3; Surface nette: 0.1 m2; Hauteur: 180 mm; Largeur: 12 mm; sets with these values: 2
Pset_BeamCommon - LoadBearing: no
Name | Repère de pièce = Reference | Repère d'assemblage | Phase | Poids (kg) | Surface supérieure totale (m2) | Surface par tonne (m2) | Longueur (mm) = Length (mm) | OuterSurfaceArea (m2) | NetVolume (m3) | NetWeight (kg)
PLATINE | 1254 | P21 | 3 | 3.7 | 0 | 23.8 | 220 | 0.0888 | 0.0004752 | 3.73032
3 x PLATINE | 1276 | P124 | 2 | 3.1 | 0 | 24.1 | 180 | 0.07344 | 0.0003888 | 3.05208
3 x PLATINE | 1275 | P125 | 2 | 2.7 | 0 | 24.2 | 160 | 0.06576 | 0.0003456 | 2.71296
PLATINE | 1275 | P126 | 2 | 2.7 | 0 | 24.2 | 160 | 0.06576 | 0.0003456 | 2.71296
PLATINE | 1275 | P127 | 2 | 2.7 | 0 | 24.2 | 160 | 0.06576 | 0.0003456 | 2.71296
PLATINE | 1256 | P15 | 1 | 3.7 | 0 | 23.8 | 220 | 0.0888 | 0.0004752 | 3.73032
PLATINE | 1274 | P17 | 1 | 3.7 | 0 | 23.8 | 220 | 0.0888 | 0.0004752 | 3.73032
PLATINE | 1254 | P18 | 1 | 3.7 | 0 | 23.8 | 220 | 0.0888 | 0.0004752 | 3.73032
PLATINE | 1254 | P20 | 1 | 3.7 | 0 | 23.8 | 220 | 0.0888 | 0.0004752 | 3.73032
PLATINE | 1256 | P14 | 1 | 3.7 | 0 | 23.8 | 220 | 0.0888 | 0.0004752 | 3.73032
PLATINE | 1256 | P16 | 1 | 3.7 | 0 | 23.8 | 220 | 0.0888 | 0.0004752 | 3.73032
3 x PLATINE | 1256 | P13 | 1 | 3.7 | 0 | 23.8 | 220 | 0.0888 | 0.0004752 | 3.73032
PLATINE | 1256 | P12 | 1 | 3.7 | 0 | 23.8 | 220 | 0.0888 | 0.0004752 | 3.73032
PLATINE | 1271 | P11 | 1 | 3.7 | 0 | 23.8 | 220 | 0.0888 | 0.0004752 | 3.73032
PLATINE | 1271 | P10 | 1 | 3.7 | 0 | 23.8 | 220 | 0.0888 | 0.0004752 | 3.73032
PLATINE | 1271 | P9 | 1 | 3.7 | 0 | 23.8 | 220 | 0.0888 | 0.0004752 | 3.73032
PLATINE | 1277 | P8 | 1 | 3.7 | 0 | 23.8 | 220 | 0.0888 | 0.0004752 | 3.73032
PLATINE | 1277 | P6 | 1 | 3.7 | 0 | 23.8 | 220 | 0.0888 | 0.0004752 | 3.73032
PLATINE | 1270 | P122 | 1 | 5.5 | 0.1 | 23.4 | 320 | 0.1272 | 0.0006912 | 5.42592
PLATINE | 1255 | P117 | 1 | 5.5 | 0.1 | 23.4 | 320 | 0.1272 | 0.0006912 | 5.42592
PLATINE | 1255 | P116 | 1 | 5.5 | 0.1 | 23.4 | 320 | 0.1272 | 0.0006912 | 5.42592
PLATINE | 1255 | P115 | 1 | 5.5 | 0.1 | 23.4 | 320 | 0.1272 | 0.0006912 | 5.42592
PLATINE | 1255 | P114 | 3 | 5.5 | 0.1 | 23.4 | 320 | 0.1272 | 0.0006912 | 5.42592
PLATINE | 1270 | P113 | 3 | 5.5 | 0.1 | 23.4 | 320 | 0.1272 | 0.0006912 | 5.42592
PLATINE | 1270 | P121 | 3 | 5.5 | 0.1 | 23.4 | 320 | 0.1272 | 0.0006912 | 5.42592
PLATINE | 1270 | P120 | 3 | 5.5 | 0.1 | 23.4 | 320 | 0.1272 | 0.0006912 | 5.42592
PLATINE | 1254 | P19 | 1 | 3.7 | 0 | 23.8 | 220 | 0.0888 | 0.0004752 | 3.73032
PLATINE | 1271 | P7 | 1 | 3.7 | 0 | 23.8 | 220 | 0.0888 | 0.0004752 | 3.73032
PLATINE | 1270 | P119 | 2 | 5.5 | 0.1 | 23.4 | 320 | 0.1272 | 0.0006912 | 5.42592

# IfcBeam: PL12*200 (8)
In: Undefined
Description: PL12*200; Material: STEEL/E24-2
Tekla Commun - Finition: GRENAILLE-PEINT; Phase: 2; Profil: PL12*200; Nom: PLATINE; sets with these values: 2
Tekla Quantités - Poids: 3.8 kg; Volume: 0 m3; Surface supérieure totale: 0 m2; Surface par tonne: 23.8 m2; Surface nette: 0.1 m2; Hauteur: 200 mm; Largeur: 12 mm; Longueur: 200 mm; sets with these values: 2
Pset_BeamCommon - LoadBearing: no
BaseQuantities - Length: 200 mm; OuterSurfaceArea: 0.0896 m2; NetVolume: 0.00048 m3; NetWeight: 3.768 kg
Name | Repère de pièce = Reference | Repère d'assemblage
PLATINE | 1278 | P128
PLATINE | 1280 | P130
3 x PLATINE | 1273 | P125
PLATINE | 1280 | P131
PLATINE | 1278 | P127
PLATINE | 1278 | P126

# IfcBeam: PL12*220, PLATINE
In: Undefined
Description: PL12*220; Material: STEEL/E24-2
Tekla Commun - Finition: GRENAILLE-PEINT; Repère de pièce: 1265; Repère d'assemblage: P118; Phase: 1; Profil: PL12*220; Nom: PLATINE; sets with these values: 2
Tekla Quantités - Poids: 4.8 kg; Volume: 0 m3; Surface supérieure totale: 0.1 m2; Surface par tonne: 23.4 m2; Surface nette: 0.1 m2; Hauteur: 220 mm; Largeur: 12 mm; Longueur: 230 mm; sets with these values: 2
Pset_BeamCommon - LoadBearing: no; Reference: 1265
BaseQuantities - Length: 230 mm; OuterSurfaceArea: 0.112 m2; NetVolume: 0.0006072 m3; NetWeight: 4.76652 kg

# IfcBeam: PL12*250 (6)
In: Undefined
Description: PL12*250; Material: STEEL/E24-2
Tekla Commun - Finition: GRENAILLE-PEINT; Profil: PL12*250; Nom: PLATINE; sets with these values: 2
Tekla Quantités - Poids: 5.5 kg; Volume: 0 m3; Surface supérieure totale: 0.1 m2; Surface par tonne: 23.4 m2; Surface nette: 0.1 m2; Hauteur: 250 mm; Largeur: 12 mm; Longueur: 230 mm; sets with these values: 2
Pset_BeamCommon - LoadBearing: no
BaseQuantities - Length: 230 mm; OuterSurfaceArea: 0.12652 m2; NetVolume: 0.00069 m3; NetWeight: 5.4165 kg
Name | Repère de pièce = Reference | Repère d'assemblage | Phase
PLATINE | 1279 | P129 | 2
3 x PLATINE | 1272 | P124 | 2
PLATINE | 1272 | P118 | 1
PLATINE | 1272 | P123 | 1

# IfcBeam: PL12*80, PLATINE
In: Undefined
Description: PL12*80; Material: STEEL/E24-2
Tekla Commun - Finition: GRENAILLE-PEINT; Repère de pièce: H77; Repère d'assemblage: H77; Phase: 3; Profil: PL12*80; Nom: PLATINE; sets with these values: 2
Tekla Quantités - Poids: 2.4 kg; Volume: 0 m3; Surface supérieure totale: 0 m2; Surface par tonne: 25.2 m2; Surface nette: 0.1 m2; Hauteur: 80 mm; Largeur: 12 mm; Longueur: 320 mm; sets with these values: 2
Pset_BeamCommon - LoadBearing: no; Reference: H77
BaseQuantities - Length: 320 mm; OuterSurfaceArea: 0.0608 m2; NetVolume: 0.0003072 m3; NetWeight: 2.41152 kg

# IfcBeam: PL120*10 (28)
In: Undefined
Description: PL120*10; Material: STEEL/E24-2
Tekla Commun - Finition: GRENAILLE-PEINT; Profil: PL120*10; sets with these values: 2
Tekla Quantités - Volume: 0 m3; Surface supérieure totale: 0 m2; Hauteur: 120 mm; Largeur: 10 mm; sets with these values: 2
Pset_BeamCommon - LoadBearing: no
Name | Repère de pièce = Reference | Repère d'assemblage | Phase | Poids (kg) | Surface par tonne (m2) | Surface nette (m2) | Longueur (mm) | Length (mm) | OuterSurfaceArea (m2) | NetVolume (m3) | NetWeight (kg) | Nom
Unnamed | 228 | K94 | 3 | 2.4 | 28.6 | 0.1 | 260 | 260.048 | 0.0700125 | 0.000312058 | 2.44965
PLAT | 293 | N4 | 2 | 4.5 | 28.1 | 0.1 | 480 | 480 | 0.1272 | 0.000576 | 4.5216 | PLAT
5 x PLAT | 294 | N20 | 2 | 3.6 | 28.3 | 0.1 | 380 | 380 | 0.1012 | 0.000456 | 3.5796 | PLAT
9 x PLAT | 294 | L118 | 2 | 3.6 | 28.3 | 0.1 | 380 | 380 | 0.1012 | 0.000456 | 3.5796 | PLAT
3 x PLAT | 294 | N19 | 2 | 3.6 | 28.3 | 0.1 | 380 | 380 | 0.1012 | 0.000456 | 3.5796 | PLAT
2 x PLAT | 294 | N21 | 2 | 3.6 | 28.3 | 0.1 | 380 | 380 | 0.1012 | 0.000456 | 3.5796 | PLAT
2 x PLATINE | 242 | B1 | 1 | 2.3 | 28.8 | 0.1 | 240 | 240 | 0.0648 | 0.000288 | 2.2608 | PLATINE
2 x PLATINE | 242 | B2 | 1 | 2.3 | 28.8 | 0.1 | 240 | 240 | 0.0648 | 0.000288 | 2.2608 | PLATINE
2 x PLATINE | 242 | B3 | 1 | 2.3 | 28.8 | 0.1 | 240 | 240 | 0.0648 | 0.000288 | 2.2608 | PLATINE
Unnamed | 229 | M13 | 1 | 0.9 | 30.1 | 0 | 104 | 104 | 0.02944 | 0.0001248 | 0.97968

# IfcBeam: PL120*12 (22)
In: Undefined
Description: PL120*12; Material: STEEL/S235JR
Tekla Commun - Finition: GALVANISE; Phase: 4; Profil: PL120*12; Nom: SUPPORT; sets with these values: 2
Tekla Quantités - Volume: 0 m3; Surface supérieure totale: 0 m2; Surface nette: 0.1 m2; Hauteur: 120 mm; Largeur: 12 mm; sets with these values: 2
Pset_BeamCommon - LoadBearing: no
Name | Repère de pièce = Reference | Repère d'assemblage | Poids (kg) | Surface par tonne (m2) | Longueur (mm) = Length (mm) | OuterSurfaceArea (m2) | NetVolume (m3) | NetWeight (kg)
6 x SUPPORT | 1261 | E1 | 5.5 | 23.9 | 490 | 0.13224 | 0.0007056 | 5.53896
16 x SUPPORT | 1262 | E2 | 6.2 | 23.8 | 550 | 0.14808 | 0.000792 | 6.2172

# IfcBeam: PL120*8 (10)
In: Undefined
Description: PL120*8; Material: STEEL/E24-2
Tekla Commun - Finition: GRENAILLE-PEINT; Repère de pièce: 819; Phase: 2; Profil: PL120*8; Nom: PLAT; sets with these values: 2
Tekla Quantités - Poids: 1.6 kg; Volume: 0 m3; Surface supérieure totale: 0 m2; Surface par tonne: 35.2 m2; Surface nette: 0.1 m2; Hauteur: 120 mm; Largeur: 8 mm; Longueur: 210 mm; sets with these values: 2
Pset_BeamCommon - LoadBearing: no; Reference: 819
BaseQuantities - Length: 210 mm; OuterSurfaceArea: 0.05568 m2; NetVolume: 0.0002016 m3; NetWeight: 1.58256 kg
Name | Repère d'assemblage
2 x PLAT | B6
8 x PLAT | B9

# IfcBeam: PL140*10 (24)
In: Undefined
Description: PL140*10
Tekla Commun - Finition: GRENAILLE-PEINT; Profil: PL140*10; sets with these values: 2
Tekla Quantités - Volume: 0 m3; Surface supérieure totale: 0 m2; Surface nette: 0.1 m2; Hauteur: 140 mm; Largeur: 10 mm; sets with these values: 2
Pset_BeamCommon - LoadBearing: no
Name | Material | Repère de pièce = Reference | Repère d'assemblage | Phase | Nom | Poids (kg) | Surface par tonne (m2) | Longueur (mm) | Length (mm) | OuterSurfaceArea (m2) | NetVolume (m3) | NetWeight (kg)
2 x ATTACHE | STEEL/E24-2 | 183 | H1 | 3 | ATTACHE | 2 | 28.8 | 170 | 169.997 | 0.0537992 | 0.000237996 | 1.86827
PLAT | STEEL/E24-2 | 184 | P21 | 3 | PLAT | 2.1 | 28.6 | 190 | 190 | 0.0598 | 0.000266 | 2.0881
12 x ATTACHE | STEEL/S235JR | 210 | H6 | 1 | ATTACHE | 2 | 28.8 | 170 | 169.997 | 0.0537992 | 0.000237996 | 1.86827
PLAT | STEEL/S235JR | 212 | P18 | 1 | PLAT | 2.1 | 28.6 | 190 | 190 | 0.0598 | 0.000266 | 2.0881
PLAT | STEEL/S235JR | 212 | P20 | 1 | PLAT | 2.1 | 28.6 | 190 | 190 | 0.0598 | 0.000266 | 2.0881
PLAT | STEEL/S235JR | 212 | P19 | 1 | PLAT | 2.1 | 28.6 | 190 | 190 | 0.0598 | 0.000266 | 2.0881
6 x ATTACHE | STEEL/S235JR | 202 | H5 | 3 | ATTACHE | 2 | 28.8 | 170 | 169.997 | 0.0537992 | 0.000237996 | 1.86827

# IfcBeam: PL15*190 (16)
In: Undefined
Description: PL15*190; Material: STEEL/E24-2
Tekla Commun - Finition: GRENAILLE-PEINT; Profil: PL15*190; Nom: POUTRE; sets with these values: 2
Tekla Quantités - Volume: 0 m3; Surface supérieure totale: 0 m2; Hauteur: 190 mm; Largeur: 15 mm; sets with these values: 2
Pset_BeamCommon - LoadBearing: no
Name | Repère de pièce = Reference | Repère d'assemblage | Phase | Poids (kg) | Surface par tonne (m2) | Surface nette (m2) | Longueur (mm) | Length (mm) | OuterSurfaceArea (m2) | NetVolume (m3) | NetWeight (kg)
2 x POUTRE | 152 | K21 | 1 | 44.2 | 18.5 | 0.8 | 1976.6 | 1976.57 | 0.816095 | 0.00563323 | 44.2209
2 x POUTRE | 150 | K21 | 1 | 11.3 | 18.8 | 0.2 | 510.5 | 510.352 | 0.214944 | 0.0014545 | 11.4178
POUTRE | 152 | K22 | 1 | 44.2 | 18.5 | 0.8 | 1976.6 | 1976.57 | 0.816095 | 0.00563323 | 44.2209
POUTRE | 150 | K22 | 1 | 11.3 | 18.8 | 0.2 | 510.5 | 510.352 | 0.214944 | 0.0014545 | 11.4178
POUTRE | 150 | K24 | 1 | 11.3 | 18.8 | 0.2 | 510.5 | 510.352 | 0.214944 | 0.0014545 | 11.4178
POUTRE | 152 | K24 | 1 | 44.2 | 18.5 | 0.8 | 1976.6 | 1976.57 | 0.816095 | 0.00563323 | 44.2209
POUTRE | 150 | K22 | 3 | 11.3 | 18.8 | 0.2 | 510.5 | 510.352 | 0.214944 | 0.0014545 | 11.4178
POUTRE | 152 | K22 | 3 | 44.2 | 18.5 | 0.8 | 1976.6 | 1976.57 | 0.816095 | 0.00563323 | 44.2209
POUTRE | 150 | K23 | 3 | 11.3 | 18.8 | 0.2 | 510.5 | 510.352 | 0.214944 | 0.0014545 | 11.4178
POUTRE | 152 | K23 | 3 | 44.2 | 18.5 | 0.8 | 1976.6 | 1976.57 | 0.816095 | 0.00563323 | 44.2209
2 x POUTRE | 152 | K21 | 3 | 44.2 | 18.5 | 0.8 | 1976.6 | 1976.57 | 0.816095 | 0.00563323 | 44.2209
2 x POUTRE | 150 | K21 | 3 | 11.3 | 18.8 | 0.2 | 510.5 | 510.352 | 0.214944 | 0.0014545 | 11.4178

# IfcBeam: PL15*200 (10)
In: Undefined
Description: PL15*200; Material: STEEL/E24-2
Tekla Commun - Finition: GRENAILLE-PEINT; Profil: PL15*200; Nom: POUTRE; sets with these values: 2
Tekla Quantités - Poids: 6.2 kg; Volume: 0 m3; Surface supérieure totale: 0 m2; Surface par tonne: 19.2 m2; Surface nette: 0.1 m2; Hauteur: 200 mm; Largeur: 15 mm; Longueur: 257 mm; sets with these values: 2
Pset_BeamCommon - LoadBearing: no
BaseQuantities - Length: 256.969 mm; OuterSurfaceArea: 0.116497 m2; NetVolume: 0.000770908 m3; NetWeight: 6.05163 kg
Name | Repère de pièce = Reference | Repère d'assemblage | Phase
POUTRE | 151 | P33 | 1
2 x POUTRE | 151 | P35 | 1
POUTRE | 162 | P31 | 3
POUTRE | 162 | P30 | 2
POUTRE | 151 | P28 | 1
2 x POUTRE | 151 | P36 | 1
POUTRE | 162 | P29 | 2
POUTRE | 162 | P32 | 3

# IfcBeam: PL15*230, PLATINE
In: Undefined
Description: PL15*230; Material: STEEL/E24-2
Tekla Commun - Finition: GRENAILLE-PEINT; Repère de pièce: 153; Repère d'assemblage: P122; Phase: 1; Profil: PL15*230; Nom: PLATINE; sets with these values: 2
Tekla Quantités - Poids: 7.7 kg; Volume: 0 m3; Surface supérieure totale: 0 m2; Surface par tonne: 19 m2; Surface nette: 0.1 m2; Hauteur: 230 mm; Largeur: 15 mm; Longueur: 283 mm; sets with these values: 2
Pset_BeamCommon - LoadBearing: no; Reference: 153
BaseQuantities - Length: 283 mm; OuterSurfaceArea: 0.14557 m2; NetVolume: 0.00097635 m3; NetWeight: 7.66435 kg

# IfcBeam: PL150*10 (52)
In: Undefined
Description: PL150*10
Tekla Commun - Finition: GRENAILLE-PEINT; Profil: PL150*10; sets with these values: 2
Tekla Quantités - Volume: 0 m3; Surface supérieure totale: 0 m2; Hauteur: 150 mm; Largeur: 10 mm; sets with these values: 2
Pset_BeamCommon - LoadBearing: no
Name | Material | Repère de pièce = Reference | Repère d'assemblage | Phase | Poids (kg) | Surface par tonne (m2) | Surface nette (m2) | Longueur (mm) | Length (mm) | OuterSurfaceArea (m2) | NetVolume (m3) | NetWeight (kg) | Nom
Unnamed | STEEL/E24-2 | 194 | P132 | 7 | 2.3 | 28.5 | 0.1 | 195 | 195 | 0.0654 | 0.0002925 | 2.29612
Unnamed | STEEL/E24-2 | 194 | P133 | 7 | 2.3 | 28.5 | 0.1 | 195 | 195 | 0.0654 | 0.0002925 | 2.29612
Unnamed | STEEL/E24-2 | 227 | K53 | 3 | 3.4 | 28.1 | 0.1 | 287.1 | 287.059 | 0.094859 | 0.000430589 | 3.38012
Unnamed | STEEL/E24-2 | 227 | K20 | 3 | 3.4 | 28.1 | 0.1 | 287.1 | 287.059 | 0.094859 | 0.000430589 | 3.38012
Unnamed | STEEL/E24-2 | 227 | K51 | 3 | 3.4 | 28.1 | 0.1 | 287.1 | 287.059 | 0.094859 | 0.000430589 | 3.38012
Unnamed | STEEL/E24-2 | 227 | K52 | 3 | 3.4 | 28.1 | 0.1 | 287.1 | 287.059 | 0.094859 | 0.000430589 | 3.38012
Unnamed | STEEL/E24-2 | 227 | K94 | 3 | 3.4 | 28.1 | 0.1 | 287.1 | 287.059 | 0.094859 | 0.000430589 | 3.38012
Unnamed | STEEL/E24-2 | 227 | K50 | 3 | 3.4 | 28.1 | 0.1 | 287.1 | 287.059 | 0.094859 | 0.000430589 | 3.38012
PLAT | STEEL/S235JR | 279 | K86 | 2 | 2.3 | 28.5 | 0.1 | 192.9 | 192.973 | 0.0647515 | 0.00028946 | 2.27226 | PLAT
PLAT | STEEL/S235JR | 258 | K101 | 2 | 3 | 28.3 | 0.1 | 256 | 255.999 | 0.0849198 | 0.000383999 | 3.01439 | PLAT
PLAT | STEEL/S235JR | 259 | K82 | 2 | 3 | 28.3 | 0.1 | 250 | 249.953 | 0.0829851 | 0.00037493 | 2.9432 | PLAT
PLAT | STEEL/S235JR | 258 | K60 | 2 | 3 | 28.3 | 0.1 | 256 | 255.999 | 0.0849198 | 0.000383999 | 3.01439 | PLAT
4 x PLAT | STEEL/S235JR | 259 | K83 | 2 | 3 | 28.3 | 0.1 | 250 | 249.953 | 0.0829851 | 0.00037493 | 2.9432 | PLAT
PLAT | STEEL/S235JR | 258 | K67 | 2 | 3 | 28.3 | 0.1 | 256 | 255.999 | 0.0849198 | 0.000383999 | 3.01439 | PLAT
PLAT | STEEL/S235JR | 258 | K64 | 2 | 3 | 28.3 | 0.1 | 256 | 255.999 | 0.0849198 | 0.000383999 | 3.01439 | PLAT
PLAT | STEEL/S235JR | 258 | K70 | 2 | 3 | 28.3 | 0.1 | 256 | 255.999 | 0.0849198 | 0.000383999 | 3.01439 | PLAT
PLAT | STEEL/S235JR | 259 | K75 | 2 | 3 | 28.3 | 0.1 | 250 | 249.953 | 0.0829851 | 0.00037493 | 2.9432 | PLAT
PLAT | STEEL/S235JR | 258 | K102 | 2 | 3 | 28.3 | 0.1 | 256 | 255.999 | 0.0849198 | 0.000383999 | 3.01439 | PLAT
PLAT | STEEL/S235JR | 259 | K74 | 2 | 3 | 28.3 | 0.1 | 250 | 249.953 | 0.0829851 | 0.00037493 | 2.9432 | PLAT
PLAT | STEEL/S235JR | 258 | K72 | 2 | 3 | 28.3 | 0.1 | 256 | 255.999 | 0.0849198 | 0.000383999 | 3.01439 | PLAT
PLAT | STEEL/S235JR | 259 | K81 | 2 | 3 | 28.3 | 0.1 | 250 | 249.953 | 0.0829851 | 0.00037493 | 2.9432 | PLAT
PLAT | STEEL/S235JR | 258 | K63 | 2 | 3 | 28.3 | 0.1 | 256 | 255.999 | 0.0849198 | 0.000383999 | 3.01439 | PLAT
PLAT | STEEL/S235JR | 259 | K80 | 2 | 3 | 28.3 | 0.1 | 250 | 249.953 | 0.0829851 | 0.00037493 | 2.9432 | PLAT
PLAT | STEEL/S235JR | 258 | K68(?) | 2 | 3 | 28.3 | 0.1 | 256 | 255.999 | 0.0849198 | 0.000383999 | 3.01439 | PLAT
PLAT | STEEL/S235JR | 259 | K79 | 2 | 3 | 28.3 | 0.1 | 250 | 249.953 | 0.0829851 | 0.00037493 | 2.9432 | PLAT
PLAT | STEEL/S235JR | 258 | K66 | 2 | 3 | 28.3 | 0.1 | 256 | 255.999 | 0.0849198 | 0.000383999 | 3.01439 | PLAT
PLAT | STEEL/S235JR | 259 | K78 | 2 | 3 | 28.3 | 0.1 | 250 | 249.953 | 0.0829851 | 0.00037493 | 2.9432 | PLAT
2 x PLAT | STEEL/S235JR | 258 | K71 | 2 | 3 | 28.3 | 0.1 | 256 | 255.999 | 0.0849198 | 0.000383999 | 3.01439 | PLAT
PLAT | STEEL/S235JR | 259 | K76 | 2 | 3 | 28.3 | 0.1 | 250 | 249.953 | 0.0829851 | 0.00037493 | 2.9432 | PLAT
PLAT | STEEL/S235JR | 259 | K77 | 2 | 3 | 28.3 | 0.1 | 250 | 249.953 | 0.0829851 | 0.00037493 | 2.9432 | PLAT
PLAT | STEEL/S235JR | 258 | K65 | 2 | 3 | 28.3 | 0.1 | 256 | 255.999 | 0.0849198 | 0.000383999 | 3.01439 | PLAT
PLAT | STEEL/S235JR | 258 | K69 | 2 | 3 | 28.3 | 0.1 | 256 | 255.999 | 0.0849198 | 0.000383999 | 3.01439 | PLAT
PLAT | STEEL/S235JR | 259 | K73 | 2 | 3 | 28.3 | 0.1 | 250 | 249.953 | 0.0829851 | 0.00037493 | 2.9432 | PLAT
PLAT | STEEL/S235JR | 261 | K85 | 2 | 3 | 28.3 | 0.1 | 250 | 249.953 | 0.0829851 | 0.00037493 | 2.9432 | PLAT
PLAT | STEEL/S235JR | 261 | K84 | 2 | 3 | 28.3 | 0.1 | 250 | 249.953 | 0.0829851 | 0.00037493 | 2.9432 | PLAT
PLAT | STEEL/S235JR | 259 | K85 | 2 | 3 | 28.3 | 0.1 | 250 | 249.953 | 0.0829851 | 0.00037493 | 2.9432 | PLAT
PLAT | STEEL/S235JR | 258 | K61 | 2 | 3 | 28.3 | 0.1 | 256 | 255.999 | 0.0849198 | 0.000383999 | 3.01439 | PLAT
PLAT | STEEL/S235JR | 260 | K61 | 2 | 2.4 | 28.5 | 0.1 | 210 | 210 | 0.0702 | 0.000315 | 2.47275 | PLAT
PLAT | STEEL/S235JR | 260 | K62 | 2 | 2.4 | 28.5 | 0.1 | 210 | 210 | 0.0702 | 0.000315 | 2.47275 | PLAT
PLAT | STEEL/S235JR | 259 | K84 | 2 | 3 | 28.3 | 0.1 | 250 | 249.953 | 0.0829851 | 0.00037493 | 2.9432 | PLAT
PLAT | STEEL/S235JR | 258 | K62 | 2 | 3 | 28.3 | 0.1 | 256 | 255.999 | 0.0849198 | 0.000383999 | 3.01439 | PLAT
Unnamed | STEEL/E24-2 | 246 | K28 | 1 | 1.2 | 29.8 | 0 | 100 | 100.002 | 0.0350005 | 0.000150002 | 1.17752
PLAT | STEEL/S235JR | 201 | P120 | 3 | 3.4 | 28.1 | 0.1 | 287 | 287 | 0.09484 | 0.0004305 | 3.37942 | PLAT
PLAT | STEEL/S235JR | 201 | P121 | 3 | 3.4 | 28.1 | 0.1 | 287 | 287 | 0.09484 | 0.0004305 | 3.37942 | PLAT
PLAT | STEEL/S235JR | 201 | P114 | 3 | 3.4 | 28.1 | 0.1 | 287 | 287 | 0.09484 | 0.0004305 | 3.37942 | PLAT
PLAT | STEEL/S235JR | 211 | P115 | 1 | 3.4 | 28.1 | 0.1 | 287 | 287 | 0.09484 | 0.0004305 | 3.37942 | PLAT
PLAT | STEEL/S235JR | 211 | P117 | 1 | 3.4 | 28.1 | 0.1 | 287 | 287 | 0.09484 | 0.0004305 | 3.37942 | PLAT
PLAT | STEEL/S235JR | 211 | P116 | 1 | 3.4 | 28.1 | 0.1 | 287 | 287 | 0.09484 | 0.0004305 | 3.37942 | PLAT

# IfcBeam: PL150*6 (11)
In: Undefined
Description: PL150*6; Material: STEEL/E24-2
Tekla Commun - Finition: GRENAILLE-PEINT; Profil: PL150*6; sets with these values: 2
Tekla Quantités - Volume: 0 m3; Surface supérieure totale: 0 m2; Hauteur: 150 mm; Largeur: 6 mm; sets with these values: 2
Pset_BeamCommon - LoadBearing: no
Name | Repère de pièce = Reference | Repère d'assemblage | Phase | Poids (kg) | Surface par tonne (m2) | Surface nette (m2) | Longueur (mm) = Length (mm) | OuterSurfaceArea (m2) | NetVolume (m3) | NetWeight (kg)
Unnamed | 341 | L113 | 7 | 0.3 | 48.4 | 0 | 60 | 0.02052 | 0.000054 | 0.4239
Unnamed | 339 | M15 | 7 | 0.3 | 48.4 | 0 | 60 | 0.02052 | 0.000054 | 0.4239
Unnamed | 341 | M15 | 7 | 0.3 | 48.4 | 0 | 60 | 0.02052 | 0.000054 | 0.4239
Unnamed | 339 | P133 | 7 | 0.3 | 48.4 | 0 | 60 | 0.02052 | 0.000054 | 0.4239
2 x Unnamed | 339 | M23 | 7 | 0.3 | 48.4 | 0 | 60 | 0.02052 | 0.000054 | 0.4239
2 x Unnamed | 339 | L113 | 7 | 0.3 | 48.4 | 0 | 60 | 0.02052 | 0.000054 | 0.4239
Unnamed | 339 | L114 | 7 | 0.3 | 48.4 | 0 | 60 | 0.02052 | 0.000054 | 0.4239
Unnamed | 327 | L106 | 3 | 1.4 | 45.5 | 0.1 | 200 | 0.0642 | 0.00018 | 1.413
Unnamed | 339 | M16 | 3 | 0.3 | 48.4 | 0 | 60 | 0.02052 | 0.000054 | 0.4239

# IfcBeam: PL160*10 (3)
In: Undefined
Description: PL160*10; Material: STEEL/E24-2
Tekla Commun - Finition: GRENAILLE-PEINT; Profil: PL160*10; sets with these values: 2
Tekla Quantités - Volume: 0 m3; Surface supérieure totale: 0 m2; Surface nette: 0.1 m2; Hauteur: 160 mm; Largeur: 10 mm; sets with these values: 2
Pset_BeamCommon - LoadBearing: no
Name | Repère de pièce = Reference | Repère d'assemblage | Phase | Nom | Poids (kg) | Surface par tonne (m2) | Longueur (mm) = Length (mm) | OuterSurfaceArea (m2) | NetVolume (m3) | NetWeight (kg)
PLAT | 237 | L32 | 5 | PLAT | 3.3 | 28 | 260 | 0.0916 | 0.000416 | 3.2656
PLAT | 238 | L53 | 5 | PLAT | 3.1 | 28.1 | 250 | 0.0882 | 0.0004 | 3.14
Unnamed | 249 | M5 | 1 |  | 1.7 | 28.9 | 140 | 0.0508 | 0.000224 | 1.7584

# IfcBeam: PL160*12 (2)
In: Undefined
Description: PL160*12; Material: STEEL/S235JR
Tekla Commun - Finition: GALVANISE; Repère de pièce: 1260; Repère d'assemblage: E3; Phase: 4; Profil: PL160*12; Nom: SUPPORT; sets with these values: 2
Tekla Quantités - Poids: 4.8 kg; Volume: 0 m3; Surface supérieure totale: 0 m2; Surface par tonne: 23.6 m2; Surface nette: 0.1 m2; Hauteur: 160 mm; Largeur: 12 mm; Longueur: 318 mm; sets with these values: 2
Pset_BeamCommon - LoadBearing: no; Reference: 1260
BaseQuantities - Length: 318 mm; OuterSurfaceArea: 0.113232 m2; NetVolume: 0.00061056 m3; NetWeight: 4.7929 kg

# IfcBeam: PL160*20 (6)
In: Undefined
Description: PL160*20; Material: STEEL/E36-3
Tekla Commun - Finition: GRENAILLE-PEINT; Repère de pièce: 306; Phase: 3; Profil: PL160*20; sets with these values: 2
Tekla Quantités - Poids: 7.2 kg; Volume: 0 m3; Surface supérieure totale: 0 m2; Surface par tonne: 15.2 m2; Surface nette: 0.1 m2; Hauteur: 160 mm; Largeur: 20 mm; Longueur: 287.1 mm; sets with these values: 2
Pset_BeamCommon - LoadBearing: no; Reference: 306
BaseQuantities - Length: 287.059 mm; OuterSurfaceArea: 0.109741 m2; NetVolume: 0.00091859 m3; NetWeight: 7.21093 kg
Name | Repère d'assemblage
Unnamed | K20
Unnamed | K51
Unnamed | K53
Unnamed | K52
Unnamed | K50
Unnamed | K94

# IfcBeam: PL1620*200 (2)
In: Undefined
Description: PL1620*200; Material: CONCRETE/BETON COURANT
Tekla Commun - Phase: 10; Profil: PL1620*200; Nom: MACONNERIE; sets with these values: 2
Tekla Quantités - Hauteur: 1620 mm; Largeur: 200 mm; sets with these values: 2
Pset_BeamCommon - LoadBearing: no
Name | Repère de pièce = Repère d'assemblage = Reference | Poids (kg) | Volume (m3) | Surface supérieure totale (m2) | Surface par tonne (m2) | Surface nette (m2) | Longueur (mm) = Length (mm) | OuterSurfaceArea (m2) | NetVolume (m3) | NetWeight (kg)
MACONNERIE | Z24 | 1928.9 | 0.9 | 0.7 | 5.7 | 10.9 | 2835 | 10.9674 | 0.91854 | 1928.93
MACONNERIE | Z44 | 7768.3 | 3.7 | 1.1 | 5.4 | 42.9 | 13165 | 42.9058 | 3.69918 | 7768.28

# IfcBeam: PL170*10, PLAT
In: Undefined
Description: PL170*10; Material: STEEL/E24-2
Tekla Commun - Finition: GRENAILLE-PEINT; Repère de pièce: 270; Repère d'assemblage: K99; Phase: 1; Profil: PL170*10; Nom: PLAT; sets with these values: 2
Tekla Quantités - Poids: 0.9 kg; Volume: 0 m3; Surface supérieure totale: 0 m2; Surface par tonne: 30.5 m2; Surface nette: 0 m2; Hauteur: 170 mm; Largeur: 10 mm; Longueur: 75 mm; sets with these values: 2
Pset_BeamCommon - LoadBearing: no; Reference: 270
BaseQuantities - Length: 75 mm; OuterSurfaceArea: 0.0304 m2; NetVolume: 0.0001275 m3; NetWeight: 1.00087 kg

# IfcBeam: PL170*6 (16)
In: Undefined
Description: PL170*6; Material: STEEL/E24-2
Tekla Commun - Finition: GRENAILLE-PEINT; Phase: 1; Profil: PL170*6; sets with these values: 2
Tekla Quantités - Volume: 0 m3; Surface supérieure totale: 0 m2; Surface nette: 0 m2; Hauteur: 170 mm; Largeur: 6 mm; sets with these values: 2
Pset_BeamCommon - LoadBearing: no
Name | Repère de pièce = Reference | Repère d'assemblage | Poids (kg) | Surface par tonne (m2) | Longueur (mm) = Length (mm) | OuterSurfaceArea (m2) | NetVolume (m3) | NetWeight (kg)
2 x Unnamed | 322 | L28 | 0.5 | 48.2 | 60 | 0.02316 | 0.0000612 | 0.48042
Unnamed | 322 | L27 | 0.5 | 48.2 | 60 | 0.02316 | 0.0000612 | 0.48042
Unnamed | 322 | L26 | 0.5 | 48.2 | 60 | 0.02316 | 0.0000612 | 0.48042
Unnamed | 320 | L27 | 0.6 | 47.6 | 70 | 0.02668 | 0.0000714 | 0.56049
Unnamed | 320 | L26 | 0.6 | 47.6 | 70 | 0.02668 | 0.0000714 | 0.56049
Unnamed | 320 | P51 | 0.6 | 47.6 | 70 | 0.02668 | 0.0000714 | 0.56049
Unnamed | 320 | P50 | 0.6 | 47.6 | 70 | 0.02668 | 0.0000714 | 0.56049
2 x Unnamed | 320 | L25 | 0.6 | 47.6 | 70 | 0.02668 | 0.0000714 | 0.56049
Unnamed | 320 | P43 | 0.6 | 47.6 | 70 | 0.02668 | 0.0000714 | 0.56049
Unnamed | 320 | P42 | 0.6 | 47.6 | 70 | 0.02668 | 0.0000714 | 0.56049
Unnamed | 320 | P47 | 0.6 | 47.6 | 70 | 0.02668 | 0.0000714 | 0.56049
Unnamed | 320 | P46 | 0.6 | 47.6 | 70 | 0.02668 | 0.0000714 | 0.56049
Unnamed | 320 | P45 | 0.6 | 47.6 | 70 | 0.02668 | 0.0000714 | 0.56049
Unnamed | 320 | P44 | 0.6 | 47.6 | 70 | 0.02668 | 0.0000714 | 0.56049

# IfcBeam: PL1760*400, MACONNERIE
In: Undefined
Description: PL1760*400; Material: CONCRETE/BETON COURANT
Tekla Commun - Repère de pièce: Z80; Repère d'assemblage: Z80; Phase: 10; Profil: PL1760*400; Nom: MACONNERIE; sets with these values: 2
Tekla Quantités - Poids: 5144.8 kg; Volume: 2.4 m3; Surface supérieure totale: 1.4 m2; Surface par tonne: 3.2 m2; Surface nette: 16.4 m2; Hauteur: 1760 mm; Largeur: 400 mm; Longueur: 3480 mm; sets with these values: 2
Pset_BeamCommon - LoadBearing: no; Reference: Z80
BaseQuantities - Length: 3480 mm; OuterSurfaceArea: 16.4416 m2; NetVolume: 2.44992 m3; NetWeight: 5144.83 kg

# IfcBeam: PL180*12 (4)
In: Undefined
Description: PL180*12; Material: STEEL/E24-2
Tekla Commun - Finition: GRENAILLE-PEINT; Repère de pièce: 1267; Repère d'assemblage: B18; Phase: 2; Profil: PL180*12; Nom: ATTACHE; sets with these values: 2
Tekla Quantités - Poids: 2.3 kg; Volume: 0 m3; Surface supérieure totale: 0 m2; Surface par tonne: 24.5 m2; Surface nette: 0.1 m2; Hauteur: 180 mm; Largeur: 12 mm; Longueur: 135 mm; sets with these values: 2
Pset_BeamCommon - LoadBearing: no; Reference: 1267
BaseQuantities - Length: 135 mm; OuterSurfaceArea: 0.05616 m2; NetVolume: 0.0002916 m3; NetWeight: 2.28906 kg

# IfcBeam: PL2*240 (8)
In: Undefined
Description: PL2*240; Material: STEEL/S235JR
Tekla Commun - Finition: GALVANISE; Repère de pièce: Y8; Repère d'assemblage: Y8; Phase: 1; Profil: PL2*240; Nom: CALE; sets with these values: 2
Tekla Quantités - Poids: 1.2 kg; Volume: 0 m3; Surface supérieure totale: 0 m2; Surface par tonne: 129.2 m2; Surface nette: 0.2 m2; Hauteur: 240 mm; Largeur: 2 mm; Longueur: 340 mm; sets with these values: 2
Pset_BeamCommon - LoadBearing: no; Reference: Y8
BaseQuantities - Length: 340 mm; OuterSurfaceArea: 0.16552 m2; NetVolume: 0.0001632 m3; NetWeight: 1.28112 kg

# IfcBeam: PL2*250 (4)
In: Undefined
Description: PL2*250; Material: STEEL/S235JR
Tekla Commun - Finition: GALVANISE; Repère de pièce: Y9; Repère d'assemblage: Y9; Phase: 1; Profil: PL2*250; Nom: CALE; sets with these values: 2
Tekla Quantités - Poids: 1.2 kg; Volume: 0 m3; Surface supérieure totale: 0 m2; Surface par tonne: 129.2 m2; Surface nette: 0.2 m2; Hauteur: 250 mm; Largeur: 2 mm; Longueur: 340 mm; sets with these values: 2
Pset_BeamCommon - LoadBearing: no; Reference: Y9
BaseQuantities - Length: 340 mm; OuterSurfaceArea: 0.17236 m2; NetVolume: 0.00017 m3; NetWeight: 1.3345 kg

# IfcBeam: PL2*340 (171)
In: Undefined
Description: PL2*340; Material: STEEL/S235JR
Tekla Commun - Finition: GALVANISE; Profil: PL2*340; Nom: CALE; sets with these values: 2
Tekla Quantités - Volume: 0 m3; Surface supérieure totale: 0 m2; Surface nette: 0.2 m2; Hauteur: 340 mm; Largeur: 2 mm; sets with these values: 2
Pset_BeamCommon - LoadBearing: no
Name | Repère de pièce = Repère d'assemblage = Reference | Phase | Poids (kg) | Surface par tonne (m2) | Longueur (mm) = Length (mm) | OuterSurfaceArea (m2) | NetVolume (m3) | NetWeight (kg)
12 x CALE | Y7 | 2 | 1.2 | 129.2 | 236 | 0.162784 | 0.00016048 | 1.25977
103 x CALE | Y6 | 2 | 1.4 | 129.1 | 270 | 0.18604 | 0.0001836 | 1.44126
16 x CALE | Y7 | 1 | 1.2 | 129.2 | 236 | 0.162784 | 0.00016048 | 1.25977
40 x CALE | Y6 | 1 | 1.4 | 129.1 | 270 | 0.18604 | 0.0001836 | 1.44126

# IfcBeam: PL20*110, CALAGE
In: Undefined
Description: PL20*110; Material: STEEL/E24-2
Tekla Commun - Finition: GRENAILLE-PEINT; Repère de pièce: Y1; Repère d'assemblage: Y1; Phase: 1; Profil: PL20*110; Nom: CALAGE; sets with these values: 2
Tekla Quantités - Poids: 3.6 kg; Volume: 0 m3; Surface supérieure totale: 0 m2; Surface par tonne: 16.3 m2; Surface nette: 0.1 m2; Hauteur: 110 mm; Largeur: 20 mm; Longueur: 210 mm; sets with these values: 2
Pset_BeamCommon - LoadBearing: no; Reference: Y1
BaseQuantities - Length: 210 mm; OuterSurfaceArea: 0.059 m2; NetVolume: 0.000462 m3; NetWeight: 3.6267 kg

# IfcBeam: PL20*160 (68)
In: Undefined
Description: PL20*160; Material: STEEL/E36-3
Tekla Commun - Finition: GRENAILLE-PEINT; Profil: PL20*160; Nom: PLATINE; sets with these values: 2
Tekla Quantités - Volume: 0 m3; Surface supérieure totale: 0 m2; Hauteur: 160 mm; Largeur: 20 mm; sets with these values: 2
Pset_BeamCommon - LoadBearing: no
Name | Repère de pièce = Reference | Repère d'assemblage | Phase | Poids (kg) | Surface par tonne (m2) | Surface nette (m2) | Longueur (mm) = Length (mm) | OuterSurfaceArea (m2) | NetVolume (m3) | NetWeight (kg)
PLATINE | 315 | N46 | 2 | 11.1 | 14.9 | 0.2 | 440 | 0.1648 | 0.001408 | 11.0528
PLATINE | 316 | N43 | 3 | 11.1 | 14.9 | 0.2 | 440 | 0.1648 | 0.001408 | 11.0528
PLATINE | 314 | N49 | 2 | 11.3 | 14.9 | 0.2 | 450 | 0.1684 | 0.00144 | 11.304
PLATINE | 315 | N49 | 2 | 11.1 | 14.9 | 0.2 | 440 | 0.1648 | 0.001408 | 11.0528
PLATINE | 315 | N45 | 2 | 11.1 | 14.9 | 0.2 | 440 | 0.1648 | 0.001408 | 11.0528
PLATINE | 315 | N44 | 2 | 11.1 | 14.9 | 0.2 | 440 | 0.1648 | 0.001408 | 11.0528
PLATINE | 308 | N49 | 2 | 8 | 15.2 | 0.1 | 320 | 0.1216 | 0.001024 | 8.0384
2 x PLATINE | 308 | N14 | 1 | 8 | 15.2 | 0.1 | 320 | 0.1216 | 0.001024 | 8.0384
2 x PLATINE | 314 | N14 | 1 | 11.3 | 14.9 | 0.2 | 450 | 0.1684 | 0.00144 | 11.304
PLATINE | 314 | N12 | 1 | 11.3 | 14.9 | 0.2 | 450 | 0.1684 | 0.00144 | 11.304
PLATINE | 315 | N12 | 1 | 11.1 | 14.9 | 0.2 | 440 | 0.1648 | 0.001408 | 11.0528
PLATINE | 315 | N11 | 1 | 11.1 | 14.9 | 0.2 | 440 | 0.1648 | 0.001408 | 11.0528
PLATINE | 309 | N7 | 1 | 11.1 | 14.9 | 0.2 | 440 | 0.1648 | 0.001408 | 11.0528
PLATINE | 309 | N6 | 1 | 11.1 | 14.9 | 0.2 | 440 | 0.1648 | 0.001408 | 11.0528
2 x PLATINE | 308 | N17 | 1 | 8 | 15.2 | 0.1 | 320 | 0.1216 | 0.001024 | 8.0384
2 x PLATINE | 314 | N17 | 1 | 11.3 | 14.9 | 0.2 | 450 | 0.1684 | 0.00144 | 11.304
2 x PLATINE | 314 | N13 | 1 | 11.3 | 14.9 | 0.2 | 450 | 0.1684 | 0.00144 | 11.304
2 x PLATINE | 308 | N13 | 1 | 8 | 15.2 | 0.1 | 320 | 0.1216 | 0.001024 | 8.0384
PLATINE | 308 | N12 | 1 | 8 | 15.2 | 0.1 | 320 | 0.1216 | 0.001024 | 8.0384
4 x PLATINE | 308 | N16 | 1 | 8 | 15.2 | 0.1 | 320 | 0.1216 | 0.001024 | 8.0384
4 x PLATINE | 314 | N16 | 1 | 11.3 | 14.9 | 0.2 | 450 | 0.1684 | 0.00144 | 11.304
2 x PLATINE | 314 | N47 | 1 | 11.3 | 14.9 | 0.2 | 450 | 0.1684 | 0.00144 | 11.304
2 x PLATINE | 315 | N47 | 1 | 11.1 | 14.9 | 0.2 | 440 | 0.1648 | 0.001408 | 11.0528
2 x PLATINE | 315 | N10 | 1 | 11.1 | 14.9 | 0.2 | 440 | 0.1648 | 0.001408 | 11.0528
2 x PLATINE | 315 | N8 | 1 | 11.1 | 14.9 | 0.2 | 440 | 0.1648 | 0.001408 | 11.0528
2 x PLATINE | 315 | N41 | 1 | 11.1 | 14.9 | 0.2 | 440 | 0.1648 | 0.001408 | 11.0528
2 x PLATINE | 308 | N38 | 1 | 8 | 15.2 | 0.1 | 320 | 0.1216 | 0.001024 | 8.0384
2 x PLATINE | 314 | N38 | 1 | 11.3 | 14.9 | 0.2 | 450 | 0.1684 | 0.00144 | 11.304
2 x PLATINE | 308 | N47 | 1 | 8 | 15.2 | 0.1 | 320 | 0.1216 | 0.001024 | 8.0384
PLATINE | 314 | N48 | 3 | 11.3 | 14.9 | 0.2 | 450 | 0.1684 | 0.00144 | 11.304
PLATINE | 315 | N48 | 3 | 11.1 | 14.9 | 0.2 | 440 | 0.1648 | 0.001408 | 11.0528
PLATINE | 315 | N9 | 3 | 11.1 | 14.9 | 0.2 | 440 | 0.1648 | 0.001408 | 11.0528
PLATINE | 315 | N40 | 3 | 11.1 | 14.9 | 0.2 | 440 | 0.1648 | 0.001408 | 11.0528
PLATINE | 308 | N48 | 3 | 8 | 15.2 | 0.1 | 320 | 0.1216 | 0.001024 | 8.0384
PLATINE | 307 | N15 | 3 | 8 | 15.2 | 0.1 | 320 | 0.1216 | 0.001024 | 8.0384
PLATINE | 313 | N15 | 3 | 11.3 | 14.9 | 0.2 | 450 | 0.1684 | 0.00144 | 11.304
PLATINE | 314 | N15 | 3 | 11.3 | 14.9 | 0.2 | 450 | 0.1684 | 0.00144 | 11.304
PLATINE | 308 | N15 | 3 | 8 | 15.2 | 0.1 | 320 | 0.1216 | 0.001024 | 8.0384
PLATINE | 308 | N18 | 2 | 8 | 15.2 | 0.1 | 320 | 0.1216 | 0.001024 | 8.0384
PLATINE | 314 | N18 | 2 | 11.3 | 14.9 | 0.2 | 450 | 0.1684 | 0.00144 | 11.304
2 x PLATINE | 308 | N39 | 1 | 8 | 15.2 | 0.1 | 320 | 0.1216 | 0.001024 | 8.0384
PLATINE | 308 | N42 | 1 | 8 | 15.2 | 0.1 | 320 | 0.1216 | 0.001024 | 8.0384
PLATINE | 314 | N42 | 1 | 11.3 | 14.9 | 0.2 | 450 | 0.1684 | 0.00144 | 11.304
2 x PLATINE | 314 | N39 | 1 | 11.3 | 14.9 | 0.2 | 450 | 0.1684 | 0.00144 | 11.304
PLATINE | 313 | N18 | 2 | 11.3 | 14.9 | 0.2 | 450 | 0.1684 | 0.00144 | 11.304
PLATINE | 307 | N18 | 2 | 8 | 15.2 | 0.1 | 320 | 0.1216 | 0.001024 | 8.0384

# IfcBeam: PL20*200, PLATINE
In: Undefined
Description: PL20*200; Material: STEEL/E24-2
Tekla Commun - Finition: GRENAILLE-PEINT; Repère de pièce: 304; Repère d'assemblage: K1; Phase: 3; Profil: PL20*200; Nom: PLATINE; sets with these values: 2
Tekla Quantités - Poids: 13.3 kg; Volume: 0 m3; Surface supérieure totale: 0 m2; Surface par tonne: 14.6 m2; Surface nette: 0.2 m2; Hauteur: 200 mm; Largeur: 20 mm; Longueur: 423 mm; sets with these values: 2
Pset_BeamCommon - LoadBearing: no; Reference: 304
BaseQuantities - Length: 422.973 mm; OuterSurfaceArea: 0.194108 m2; NetVolume: 0.00169189 m3; NetWeight: 13.2813 kg

# IfcBeam: PL20*300, PLATINE
In: Undefined
Description: PL20*300; Material: STEEL/E24-2
Tekla Commun - Finition: GRENAILLE-PEINT; Repère de pièce: 305; Repère d'assemblage: H76; Phase: 3; Profil: PL20*300; Nom: PLATINE; sets with these values: 2
Tekla Quantités - Poids: 18.8 kg; Volume: 0 m3; Surface supérieure totale: 0 m2; Surface par tonne: 14.2 m2; Surface nette: 0.3 m2; Hauteur: 300 mm; Largeur: 20 mm; Longueur: 400 mm; sets with these values: 2
Pset_BeamCommon - LoadBearing: no; Reference: 305
BaseQuantities - Length: 400 mm; OuterSurfaceArea: 0.268 m2; NetVolume: 0.0024 m3; NetWeight: 18.84 kg

# IfcBeam: PL200*20 (2)
In: Undefined
Description: PL200*20; Material: STEEL/E24-2
Tekla Commun - Finition: GRENAILLE-PEINT; Repère de pièce: 312; Repère d'assemblage: H78; Phase: 2; Profil: PL200*20; Nom: ATTACHE; sets with these values: 2
Tekla Quantités - Poids: 15.6 kg; Volume: 0 m3; Surface supérieure totale: 0.1 m2; Surface par tonne: 14.5 m2; Surface nette: 0.2 m2; Hauteur: 200 mm; Largeur: 20 mm; Longueur: 496 mm; sets with these values: 2
Pset_BeamCommon - LoadBearing: no; Reference: 312
BaseQuantities - Length: 496 mm; OuterSurfaceArea: 0.22624 m2; NetVolume: 0.001984 m3; NetWeight: 15.5744 kg

# IfcBeam: PL200*300, CHEMIN_CABLES
In: Undefined
Description: PL200*300; Material: STEEL/E24-2
Tekla Commun - Repère de pièce: Z13; Repère d'assemblage: Z13; Phase: 7; Profil: PL200*300; Nom: CHEMIN_CABLES; sets with these values: 2
Tekla Quantités - Poids: 3053.9 kg; Volume: 0.5 m3; Surface supérieure totale: 1.9 m2; Surface par tonne: 2.2 m2; Surface nette: 6.6 m2; Hauteur: 300 mm; Largeur: 200 mm; Longueur: 6483.9 mm; sets with these values: 2
Pset_BeamCommon - LoadBearing: no; Reference: Z13
BaseQuantities - Length: 6483.94 mm; OuterSurfaceArea: 6.60394 m2; NetVolume: 0.389036 m3; NetWeight: 3053.94 kg

# IfcBeam: PL200*6, Unnamed
In: Undefined
Description: PL200*6; Material: STEEL/S235JR
Tekla Commun - Finition: GRENAILLE-PEINT; Repère de pièce: 352; Repère d'assemblage: P123; Phase: 1; Profil: PL200*6; sets with these values: 2
Tekla Quantités - Poids: 1.1 kg; Volume: 0 m3; Surface supérieure totale: 0 m2; Surface par tonne: 46 m2; Surface nette: 0 m2; Hauteur: 200 mm; Largeur: 6 mm; Longueur: 114 mm; sets with these values: 2
Pset_BeamCommon - LoadBearing: no; Reference: 352
BaseQuantities - Length: 114 mm; OuterSurfaceArea: 0.049368 m2; NetVolume: 0.0001368 m3; NetWeight: 1.07388 kg

# IfcBeam: PL210*10 (3)
In: Undefined
Description: PL210*10; Material: STEEL/E24-2
Tekla Commun - Finition: GRENAILLE-PEINT; Repère de pièce: 224; Phase: 3; Profil: PL210*10; Nom: LISSE; sets with these values: 2
Tekla Quantités - Poids: 3.4 kg; Volume: 0 m3; Surface supérieure totale: 0 m2; Surface par tonne: 28 m2; Surface nette: 0.1 m2; Hauteur: 210 mm; Largeur: 10 mm; Longueur: 210 mm; sets with these values: 2
Pset_BeamCommon - LoadBearing: no; Reference: 224
BaseQuantities - Length: 210 mm; OuterSurfaceArea: 0.0966 m2; NetVolume: 0.000441 m3; NetWeight: 3.46185 kg
Name | Repère d'assemblage
LISSE | L3
LISSE | L1
LISSE | L2

# IfcBeam: PL210*6 (11)
In: Undefined
Description: PL210*6
Tekla Commun - Finition: GRENAILLE-PEINT; Phase: 1; Profil: PL210*6; sets with these values: 2
Tekla Quantités - Volume: 0 m3; Surface supérieure totale: 0 m2; Hauteur: 210 mm; Largeur: 6 mm; sets with these values: 2
Pset_BeamCommon - LoadBearing: no
Name | Material | Repère de pièce = Reference | Repère d'assemblage | Poids (kg) | Surface par tonne (m2) | Surface nette (m2) | Longueur (mm) = Length (mm) | OuterSurfaceArea (m2) | NetVolume (m3) | NetWeight (kg)
2 x Unnamed | STEEL/S235JR | 342 | L8 | 1.1 | 46 | 0.1 | 116 | 0.052632 | 0.00014616 | 1.14736
Unnamed | STEEL/E24-2 | 326 | M14 | 0.9 | 46.1 | 0 | 104 | 0.047448 | 0.00013104 | 1.02866
Unnamed | STEEL/E24-2 | 326 | M5 | 0.9 | 46.1 | 0 | 104 | 0.047448 | 0.00013104 | 1.02866
2 x Unnamed | STEEL/E24-2 | 326 | M4 | 0.9 | 46.1 | 0 | 104 | 0.047448 | 0.00013104 | 1.02866
Unnamed | STEEL/S235JR | 342 | L10 | 1.1 | 46 | 0.1 | 116 | 0.052632 | 0.00014616 | 1.14736
Unnamed | STEEL/E24-2 | 326 | M3 | 0.9 | 46.1 | 0 | 104 | 0.047448 | 0.00013104 | 1.02866
Unnamed | STEEL/E24-2 | 326 | M1 | 0.9 | 46.1 | 0 | 104 | 0.047448 | 0.00013104 | 1.02866
Unnamed | STEEL/E24-2 | 326 | M2 | 0.9 | 46.1 | 0 | 104 | 0.047448 | 0.00013104 | 1.02866
Unnamed | STEEL/S235JR | 342 | L9 | 1.1 | 46 | 0.1 | 116 | 0.052632 | 0.00014616 | 1.14736

# IfcBeam: PL220*20 (5)
In: Undefined
Description: PL220*20; Material: STEEL/S235JR
Tekla Commun - Finition: GRENAILLE-PEINT; Repère de pièce: 311; Phase: 2; Profil: PL220*20; Nom: PLAT; sets with these values: 2
Tekla Quantités - Poids: 15.2 kg; Volume: 0 m3; Surface supérieure totale: 0 m2; Surface par tonne: 14.5 m2; Surface nette: 0.2 m2; Hauteur: 220 mm; Largeur: 20 mm; Longueur: 443.2 mm; sets with these values: 2
Pset_BeamCommon - LoadBearing: no; Reference: 311
BaseQuantities - Length: 443.221 mm; OuterSurfaceArea: 0.221546 m2; NetVolume: 0.00195017 m3; NetWeight: 15.3089 kg
Name | Repère d'assemblage
PLAT | K36
2 x PLAT | K33
PLAT | K34
PLAT | K35

# IfcBeam: PL220*5 (183)
In: Undefined
Description: PL220*5; Material: STEEL/S235JR
Tekla Commun - Finition: GALVANISE; Profil: PL220*5; Nom: COLLERETTE; sets with these values: 2
Tekla Quantités - Poids: 3.9 kg; Volume: 0 m3; Surface supérieure totale: 0 m2; Surface par tonne: 52.1 m2; Surface nette: 0.2 m2; Hauteur: 220 mm; Largeur: 65 mm; Longueur: 220 mm; sets with these values: 2
Pset_BeamCommon - LoadBearing: no
BaseQuantities - Length: 220 mm; OuterSurfaceArea: 0.2044 m2; NetVolume: 0.0005 m3; NetWeight: 3.925 kg
Name | Repère de pièce = Reference | Repère d'assemblage | Phase
2 x COLLERETTE | 1196 | P83 | 2
14 x COLLERETTE | 1196 | P76 | 2
2 x COLLERETTE | 1198 | P94 | 2
2 x COLLERETTE | 1196 | P77 | 2
14 x COLLERETTE | 1196 | P62 | 2
COLLERETTE | 1199 | P108 | 2
COLLERETTE | 1199 | P107 | 2
COLLERETTE | 1197 | P91 | 2
COLLERETTE | 1197 | P92 | 2
COLLERETTE | 1197 | P93 | 2
5 x COLLERETTE | 1198 | P95 | 2
5 x COLLERETTE | 1196 | P63 | 2
5 x COLLERETTE | 1196 | P64 | 2
5 x COLLERETTE | 1196 | P72 | 2
5 x COLLERETTE | 1196 | P65 | 2
COLLERETTE | 1196 | P84 | 2
COLLERETTE | 1196 | P85 | 2
COLLERETTE | 1196 | P86 | 2
COLLERETTE | 1198 | P100 | 2
COLLERETTE | 1198 | P101 | 2
2 x COLLERETTE | 1196 | P78 | 2
2 x COLLERETTE | 1196 | P79 | 2
14 x COLLERETTE | 1196 | P67 | 2
14 x COLLERETTE | 1198 | P96 | 2
14 x COLLERETTE | 1196 | P66 | 2
2 x COLLERETTE | 1196 | P56 | 1
2 x COLLERETTE | 1196 | P57 | 1
2 x COLLERETTE | 1196 | P55 | 1
2 x COLLERETTE | 1196 | P54 | 1
COLLERETTE | 1196 | P59 | 1
COLLERETTE | 1196 | P61 | 1
COLLERETTE | 1196 | P58 | 1
COLLERETTE | 1196 | P60 | 1
2 x COLLERETTE | 1198 | P103 | 1
2 x COLLERETTE | 1198 | P106 | 1
3 x COLLERETTE | 1198 | P99 | 1
3 x COLLERETTE | 1198 | P98 | 1
2 x COLLERETTE | 1198 | P105 | 1
2 x COLLERETTE | 1198 | P104 | 1
3 x COLLERETTE | 1198 | P97 | 1
COLLERETTE | 1196 | P75 | 1
2 x COLLERETTE | 1196 | P74 | 1
2 x COLLERETTE | 1198 | P102 | 1
2 x COLLERETTE | 1196 | P87 | 1
7 x COLLERETTE | 1196 | P71 | 1
7 x COLLERETTE | 1196 | P73 | 1
COLLERETTE | 1196 | P90 | 1
COLLERETTE | 1196 | P89 | 1
COLLERETTE | 1196 | P88 | 1
COLLERETTE | 1196 | P82 | 1
COLLERETTE | 1196 | P81 | 1
COLLERETTE | 1196 | P80 | 1
4 x COLLERETTE | 1196 | P68 | 1
4 x COLLERETTE | 1196 | P69 | 1
4 x COLLERETTE | 1196 | P70 | 1

# IfcBeam: PL2270*200, MACONNERIE
In: Undefined
Description: PL2270*200; Material: CONCRETE/BETON COURANT
Tekla Commun - Repère de pièce: Z30; Repère d'assemblage: Z30; Phase: 10; Profil: PL2270*200; Nom: MACONNERIE; sets with these values: 2
Tekla Quantités - Poids: 2702.9 kg; Volume: 1.3 m3; Surface supérieure totale: 0.7 m2; Surface par tonne: 5.4 m2; Surface nette: 14.9 m2; Hauteur: 2270 mm; Largeur: 200 mm; Longueur: 2835 mm; sets with these values: 2
Pset_BeamCommon - LoadBearing: no; Reference: Z30
BaseQuantities - Length: 2835 mm; OuterSurfaceArea: 14.9129 m2; NetVolume: 1.28709 m3; NetWeight: 2702.89 kg

# IfcBeam: PL240*10 (7)
In: Undefined
Description: PL240*10; Material: STEEL/E24-2
Tekla Commun - Finition: GRENAILLE-PEINT; Repère de pièce: 230; Phase: 1; Profil: PL240*10; sets with these values: 2
Tekla Quantités - Poids: 2.8 kg; Volume: 0 m3; Surface supérieure totale: 0 m2; Surface par tonne: 28.3 m2; Surface nette: 0.1 m2; Hauteur: 240 mm; Largeur: 10 mm; Longueur: 150 mm; sets with these values: 2
Pset_BeamCommon - LoadBearing: no; Reference: 230
BaseQuantities - Length: 150 mm; OuterSurfaceArea: 0.0798 m2; NetVolume: 0.00036 m3; NetWeight: 2.826 kg
Name | Repère d'assemblage
Unnamed | M13
Unnamed | M14
Unnamed | M3
Unnamed | M2
Unnamed | M1
2 x Unnamed | M4

# IfcBeam: PL240*8 (30)
In: Undefined
Description: PL240*8; Material: STEEL/E24-2
Tekla Commun - Finition: GRENAILLE-PEINT; Phase: 6; Profil: PL240*8; sets with these values: 2
Tekla Quantités - Poids: 1.7 kg; Volume: 0 m3; Surface supérieure totale: 0 m2; Surface par tonne: 35.2 m2; Surface nette: 0.1 m2; Hauteur: 240 mm; Largeur: 8 mm; Longueur: 110 mm; sets with these values: 2
Pset_BeamCommon - LoadBearing: no
BaseQuantities - Length: 110 mm; OuterSurfaceArea: 0.0584 m2; NetVolume: 0.0002112 m3; NetWeight: 1.65792 kg
Name | Repère de pièce = Reference | Repère d'assemblage | Nom
SUSPENTE | 736 | S88 | SUSPENTE
SUSPENTE | 736 | S87 | SUSPENTE
10 x ATTACHE | 737 | H42 | ATTACHE
2 x SUSPENTE | 736 | S10 | SUSPENTE
SUSPENTE | 736 | S9 | SUSPENTE
4 x SUSPENTE | 736 | S8 | SUSPENTE
3 x SUSPENTE | 736 | S5 | SUSPENTE
3 x SUSPENTE | 736 | S7 | SUSPENTE
3 x SUSPENTE | 736 | S6 | SUSPENTE
SUSPENTE | 736 | S4 | SUSPENTE
SUSPENTE | 736 | S3 | SUSPENTE

# IfcBeam: PL25*160 (20)
In: Undefined
Description: PL25*160; Material: STEEL/E36-3
Tekla Commun - Finition: GRENAILLE-PEINT; Profil: PL25*160; Nom: PLAT; sets with these values: 2
Tekla Quantités - Poids: 16.6 kg; Volume: 0 m3; Surface supérieure totale: 0 m2; Surface par tonne: 12.3 m2; Surface nette: 0.2 m2; Hauteur: 160 mm; Largeur: 25 mm; Longueur: 530 mm; sets with these values: 2
Pset_BeamCommon - LoadBearing: no
BaseQuantities - Length: 530 mm; OuterSurfaceArea: 0.2041 m2; NetVolume: 0.00212 m3; NetWeight: 16.642 kg
Name | Repère de pièce = Reference | Repère d'assemblage | Phase
PLAT | 142 | N46 | 2
PLAT | 143 | N43 | 3
PLAT | 142 | N44 | 2
PLAT | 142 | N45 | 2
PLAT | 142 | N49 | 2
PLAT | 132 | N7 | 1
PLAT | 132 | N6 | 1
PLAT | 142 | N11 | 1
PLAT | 142 | N12 | 1
2 x PLAT | 142 | N8 | 1
2 x PLAT | 142 | N41 | 1
2 x PLAT | 142 | N10 | 1
2 x PLAT | 142 | N47 | 1
PLAT | 142 | N40 | 3
PLAT | 142 | N9 | 3
PLAT | 142 | N48 | 3

# IfcBeam: PL25*190 (16)
In: Undefined
Description: PL25*190; Material: STEEL/E24-2
Tekla Commun - Finition: GRENAILLE-PEINT; Profil: PL25*190; Nom: PLATINE; sets with these values: 2
Tekla Quantités - Volume: 0 m3; Surface supérieure totale: 0 m2; Surface par tonne: 11.9 m2; Surface nette: 0.3 m2; Hauteur: 190 mm; Largeur: 25 mm; sets with these values: 2
Pset_BeamCommon - LoadBearing: no
Name | Repère de pièce = Reference | Repère d'assemblage | Phase | Poids (kg) | Longueur (mm) = Length (mm) | OuterSurfaceArea (m2) | NetVolume (m3) | NetWeight (kg)
2 x PLATINE | 134 | K21 | 1 | 29.1 | 780 | 0.3449 | 0.003705 | 29.0843
2 x PLATINE | 133 | K21 | 1 | 27.2 | 730 | 0.3234 | 0.0034675 | 27.2199
PLATINE | 134 | K22 | 1 | 29.1 | 780 | 0.3449 | 0.003705 | 29.0843
PLATINE | 133 | K22 | 1 | 27.2 | 730 | 0.3234 | 0.0034675 | 27.2199
PLATINE | 135 | K24 | 1 | 27.2 | 730 | 0.3234 | 0.0034675 | 27.2199
PLATINE | 134 | K24 | 1 | 29.1 | 780 | 0.3449 | 0.003705 | 29.0843
PLATINE | 133 | K22 | 3 | 27.2 | 730 | 0.3234 | 0.0034675 | 27.2199
PLATINE | 134 | K22 | 3 | 29.1 | 780 | 0.3449 | 0.003705 | 29.0843
PLATINE | 133 | K23 | 3 | 27.2 | 730 | 0.3234 | 0.0034675 | 27.2199
PLATINE | 134 | K23 | 3 | 29.1 | 780 | 0.3449 | 0.003705 | 29.0843
2 x PLATINE | 134 | K21 | 3 | 29.1 | 780 | 0.3449 | 0.003705 | 29.0843
2 x PLATINE | 133 | K21 | 3 | 27.2 | 730 | 0.3234 | 0.0034675 | 27.2199

# IfcBeam: PL25*200 (8)
In: Undefined
Description: PL25*200; Material: STEEL/E24-2
Tekla Commun - Finition: GRENAILLE-PEINT; Profil: PL25*200; sets with these values: 2
Tekla Quantités - Poids: 8.7 kg; Volume: 0 m3; Surface supérieure totale: 0 m2; Surface par tonne: 12.6 m2; Surface nette: 0.1 m2; Hauteur: 200 mm; Largeur: 25 mm; Longueur: 225 mm; sets with these values: 2
Pset_BeamCommon - LoadBearing: no
BaseQuantities - Length: 225 mm; OuterSurfaceArea: 0.11125 m2; NetVolume: 0.001125 m3; NetWeight: 8.83125 kg
Name | Repère de pièce = Reference | Repère d'assemblage | Phase | Nom
PLATINE | 138 | P37 | 1 | PLATINE
PLATINE | 138 | P2 | 1 | PLATINE
PLATINE | 138 | P1 | 1 | PLATINE
PLAT | 139 | P38 | 1 | PLAT
PLATINE | 138 | P3 | 1 | PLATINE
PLATINE | 140 | P5 | 3 | PLATINE
PLATINE | 140 | P39 | 2 | PLATINE
PLAT | 139 | P4 | 1 | PLAT

# IfcBeam: PL25*250 (16)
In: Undefined
Description: PL25*250; Material: STEEL/E24-2
Tekla Commun - Finition: GRENAILLE-PEINT; Profil: PL25*250; Nom: PLATINE; sets with these values: 2
Tekla Quantités - Volume: 0 m3; Surface supérieure totale: 0.1 m2; Surface par tonne: 12.3 m2; Surface nette: 0.2 m2; Hauteur: 250 mm; Largeur: 25 mm; sets with these values: 2
Pset_BeamCommon - LoadBearing: no
Name | Repère de pièce = Reference | Repère d'assemblage | Phase | Poids (kg) | Longueur (mm) = Length (mm) | OuterSurfaceArea (m2) | NetVolume (m3) | NetWeight (kg)
PLATINE | 136 | P33 | 1 | 12.3 | 250 | 0.15 | 0.0015625 | 12.2656
2 x PLATINE | 136 | P35 | 1 | 12.3 | 250 | 0.15 | 0.0015625 | 12.2656
PLATINE | 137 | P31 | 3 | 12.3 | 250 | 0.15 | 0.0015625 | 12.2656
PLATINE | 137 | P30 | 2 | 12.3 | 250 | 0.15 | 0.0015625 | 12.2656
PLATINE | 136 | P28 | 1 | 12.3 | 250 | 0.15 | 0.0015625 | 12.2656
2 x PLATINE | 136 | P36 | 1 | 12.3 | 250 | 0.15 | 0.0015625 | 12.2656
PLATINE | 137 | P29 | 2 | 12.3 | 250 | 0.15 | 0.0015625 | 12.2656
PLATINE | 137 | P32 | 3 | 12.3 | 250 | 0.15 | 0.0015625 | 12.2656
PLATINE | 141 | P23 | 1 | 13.1 | 270 | 0.161 | 0.0016875 | 13.2469
PLATINE | 141 | P26 | 1 | 13.1 | 270 | 0.161 | 0.0016875 | 13.2469
PLATINE | 141 | P27 | 1 | 13.1 | 270 | 0.161 | 0.0016875 | 13.2469
PLATINE | 141 | P24 | 1 | 13.1 | 270 | 0.161 | 0.0016875 | 13.2469
PLATINE | 141 | P22 | 1 | 13.1 | 270 | 0.161 | 0.0016875 | 13.2469
PLATINE | 141 | P25 | 1 | 13.1 | 270 | 0.161 | 0.0016875 | 13.2469

# IfcBeam: PL250*10 (4)
In: Undefined
Description: PL250*10; Material: STEEL/E24-2
Tekla Commun - Finition: GRENAILLE-PEINT; Repère de pièce: 236; Phase: 4; Profil: PL250*10; Nom: ATTACHE; sets with these values: 2
Tekla Quantités - Poids: 2.4 kg; Volume: 0 m3; Surface supérieure totale: 0 m2; Surface par tonne: 28.6 m2; Surface nette: 0.1 m2; Hauteur: 250 mm; Largeur: 10 mm; Longueur: 120 mm; sets with these values: 2
Pset_BeamCommon - LoadBearing: no; Reference: 236
BaseQuantities - Length: 120 mm; OuterSurfaceArea: 0.0674 m2; NetVolume: 0.0003 m3; NetWeight: 2.355 kg
Name | Repère d'assemblage
2 x ATTACHE | E6
2 x ATTACHE | E7

# IfcBeam: PL260*10 (22)
In: Undefined
Description: PL260*10; Material: STEEL/S235JR
Tekla Commun - Phase: 2; Profil: PL260*10; Nom: PLAT; sets with these values: 2
Tekla Quantités - Volume: 0 m3; Surface supérieure totale: 0 m2; Surface nette: 0.2 m2; Hauteur: 260 mm; Largeur: 10 mm; sets with these values: 2
Pset_BeamCommon - LoadBearing: no
Name | Finition | Repère de pièce = Reference | Repère d'assemblage | Poids (kg) | Surface par tonne (m2) | Longueur (mm) = Length (mm) | OuterSurfaceArea (m2) | NetVolume (m3) | NetWeight (kg)
PLAT | GALVANISE | 257 | S2 | 5.7 | 27.4 | 278.6 | 0.155644 | 0.00072436 | 5.68623
2 x PLAT | GRENAILLE-PEINT | 262 | N18 | 6 | 27.3 | 288.6 | 0.161044 | 0.00075036 | 5.89033
10 x PLAT | GALVANISE | 257 | S1 | 5.7 | 27.4 | 278.6 | 0.155644 | 0.00072436 | 5.68623
2 x PLAT | GRENAILLE-PEINT | 262 | N46 | 6 | 27.3 | 288.6 | 0.161044 | 0.00075036 | 5.89033
2 x PLAT | GRENAILLE-PEINT | 262 | N44 | 6 | 27.3 | 288.6 | 0.161044 | 0.00075036 | 5.89033
2 x PLAT | GRENAILLE-PEINT | 262 | N45 | 6 | 27.3 | 288.6 | 0.161044 | 0.00075036 | 5.89033
3 x PLAT | GRENAILLE-PEINT | 262 | N49 | 6 | 27.3 | 288.6 | 0.161044 | 0.00075036 | 5.89033

# IfcBeam: PL2600*150 (5)
In: Undefined
Description: PL2600*150; Material: CONCRETE/BETON COURANT
Tekla Commun - Phase: 10; Profil: PL2600*150; Nom: MACONNERIE; sets with these values: 2
Tekla Quantités - Hauteur: 2600 mm; Largeur: 150 mm; sets with these values: 2
Pset_BeamCommon - LoadBearing: no
Name | Repère de pièce = Repère d'assemblage = Reference | Poids (kg) | Volume (m3) | Surface supérieure totale (m2) | Surface par tonne (m2) | Surface nette (m2) | Longueur (mm) = Length (mm) | OuterSurfaceArea (m2) | NetVolume (m3) | NetWeight (kg)
MACONNERIE | Z72 | 4884.2 | 2.3 | 1 | 7 | 34.4 | 6680 | 34.425 | 2.32583 | 4884.24
MACONNERIE | Z73 | 1721.6 | 0.9 | 0.4 | 7.6 | 13.2 | 2820 | 13.1866 | 0.819796 | 1721.57
MACONNERIE | Z74 | 3054.9 | 1.5 | 0.7 | 7 | 21.3 | 3730 | 21.295 | 1.4547 | 3054.87
MACONNERIE | Z75 | 397.2 | 0.2 | 0.1 | 8.8 | 3.4 | 485 | 3.4475 | 0.18915 | 397.215
MACONNERIE | Z76 | 1122 | 0.5 | 0.2 | 7.4 | 8.3 | 1370 | 8.315 | 0.5343 | 1122.03

# IfcBeam: PL2600*200 (6)
In: Undefined
Description: PL2600*200; Material: CONCRETE/BETON COURANT
Tekla Commun - Phase: 10; Profil: PL2600*200; Nom: MACONNERIE; sets with these values: 2
Tekla Quantités - Hauteur: 2600 mm; Largeur: 200 mm; sets with these values: 2
Pset_BeamCommon - LoadBearing: no
Name | Repère de pièce = Repère d'assemblage = Reference | Poids (kg) | Volume (m3) | Surface supérieure totale (m2) | Surface par tonne (m2) | Surface nette (m2) | Longueur (mm) = Length (mm) | OuterSurfaceArea (m2) | NetVolume (m3) | NetWeight (kg)
2 x MACONNERIE | Z22 | 3718.3 | 1.8 | 0.7 | 5.4 | 20.1 | 3405 | 20.108 | 1.7706 | 3718.26
MACONNERIE | Z26 | 1381.4 | 0.6 | 0.4 | 5.9 | 8.1 | 1265 | 8.124 | 0.6578 | 1381.38
MACONNERIE | Z27 | 1310.4 | 0.6 | 0.2 | 5.9 | 7.8 | 1200 | 7.76 | 0.624 | 1310.4
MACONNERIE | Z28 | 1796.3 | 0.9 | 0.4 | 5.7 | 10.3 | 1645 | 10.252 | 0.8554 | 1796.34
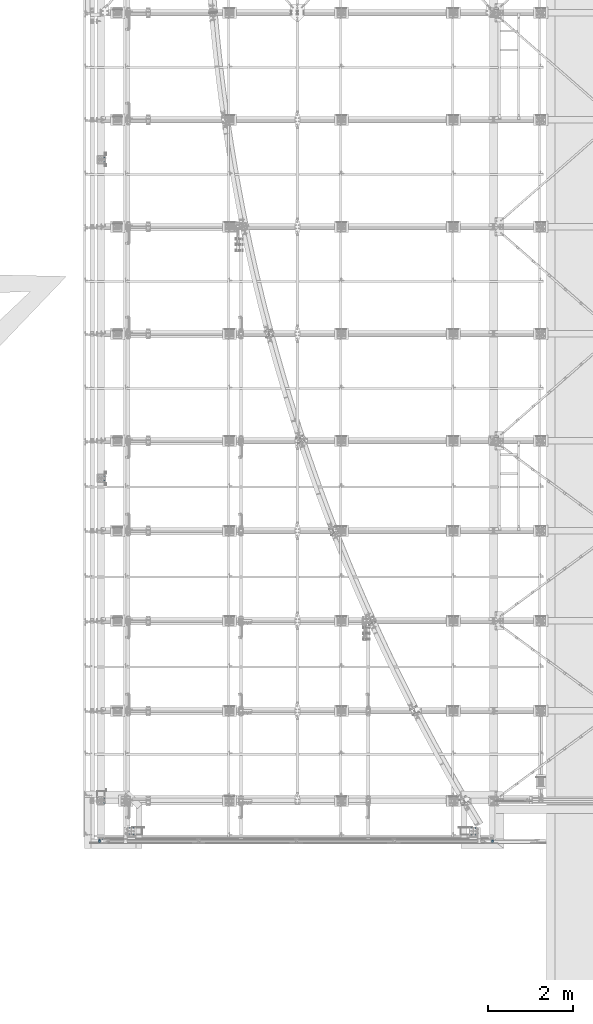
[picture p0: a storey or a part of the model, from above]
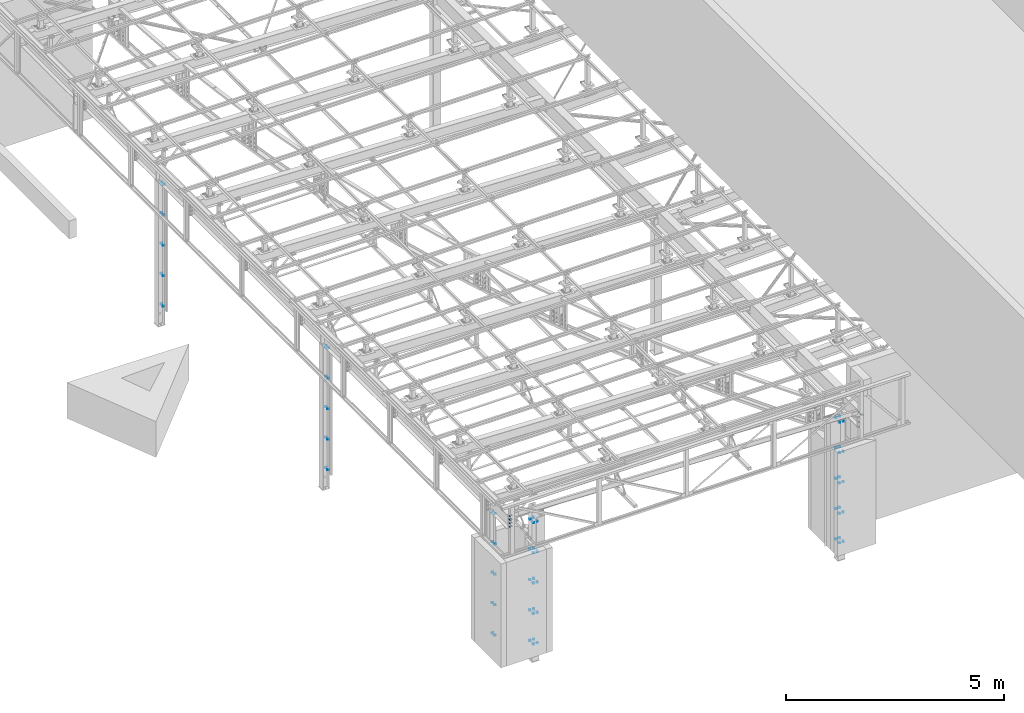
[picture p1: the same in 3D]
Properties of the parts of a building model (IFC2X3), part 4 of 13

# IfcBeam: PL2600*200 (6)
Name | Repère de pièce = Repère d'assemblage = Reference | Poids (kg) | Volume (m3) | Surface supérieure totale (m2) | Surface par tonne (m2) | Surface nette (m2) | Longueur (mm) = Length (mm) | OuterSurfaceArea (m2) | NetVolume (m3) | NetWeight (kg)
MACONNERIE | Z29 | 2140.3 | 0.9 | 0.4 | 5.7 | 12 | 1960 | 12.016 | 1.0192 | 2140.32

# IfcBeam: PL2780*200 (3)
In: Undefined
Description: PL2780*200; Material: CONCRETE/BETON COURANT
Tekla Commun - Phase: 10; Profil: PL2780*200; Nom: MACONNERIE; sets with these values: 2
Tekla Quantités - Hauteur: 2780 mm; Largeur: 200 mm; sets with these values: 2
Pset_BeamCommon - LoadBearing: no
Name | Repère de pièce = Repère d'assemblage = Reference | Poids (kg) | Volume (m3) | Surface supérieure totale (m2) | Surface par tonne (m2) | Surface nette (m2) | Longueur (mm) = Length (mm) | OuterSurfaceArea (m2) | NetVolume (m3) | NetWeight (kg)
MACONNERIE | Z31 | 2784.7 | 1.3 | 0.4 | 5.4 | 15.3 | 2385 | 15.3266 | 1.32606 | 2784.73
MACONNERIE | Z32 | 2055.1 | 0.9 | 0.4 | 5.7 | 11.6 | 1760.1 | 11.6022 | 0.978616 | 2055.09
MACONNERIE | Z33 | 4933.1 | 2.3 | 0.7 | 5.4 | 26.3 | 4225 | 26.293 | 2.3491 | 4933.11

# IfcBeam: PL2800*200, MACONNERIE
In: Undefined
Description: PL2800*200; Material: CONCRETE/BETON COURANT
Tekla Commun - Repère de pièce: Z58; Repère d'assemblage: Z58; Phase: 10; Profil: PL2800*200; Nom: MACONNERIE; sets with these values: 2
Tekla Quantités - Poids: 23629.2 kg; Volume: 11.3 m3; Surface supérieure totale: 4.3 m2; Surface par tonne: 5.4 m2; Surface nette: 124.7 m2; Hauteur: 2800 mm; Largeur: 200 mm; Longueur: 21250 mm; sets with these values: 2
Pset_BeamCommon - LoadBearing: no; Reference: Z58
BaseQuantities - Length: 21250 mm; OuterSurfaceArea: 124.66 m2; NetVolume: 11.252 m3; NetWeight: 23629.2 kg

# IfcBeam: PL2900*150 (8)
In: Undefined
Description: PL2900*150; Material: CONCRETE/BETON COURANT
Tekla Commun - Phase: 10; Profil: PL2900*150; Nom: PREFA; sets with these values: 2
Tekla Quantités - Hauteur: 2900 mm; Largeur: 150 mm; sets with these values: 2
Pset_BeamCommon - LoadBearing: no
Name | Repère de pièce = Repère d'assemblage = Reference | Poids (kg) | Volume (m3) | Surface supérieure totale (m2) | Surface par tonne (m2) | Surface nette (m2) | Longueur (mm) | Length (mm) | OuterSurfaceArea (m2) | NetVolume (m3) | NetWeight (kg)
3 x PREFA | Z68 | 1242.4 | 0.6 | 0.2 | 7.4 | 9.2 | 1360 | 1360 | 9.166 | 0.5916 | 1242.36
2 x PREFA | Z70 | 959.2 | 0.5 | 0.2 | 7.6 | 7.4 | 1050 | 1050 | 7.275 | 0.45675 | 959.175
PREFA | Z71 | 400.5 | 0.2 | 0.1 | 8.8 | 3.4 | 438.4 | 438.406 | 3.54428 | 0.190707 | 400.484
PREFA | Z69 | 794.7 | 0.5 | 0.1 | 7.8 | 6.2 | 870 | 870 | 6.177 | 0.37845 | 794.745
PREFA | Z67 | 845 | 0.5 | 0.1 | 8.1 | 6.8 | 1025 | 1025 | 6.8025 | 0.402375 | 844.987

# IfcBeam: PL2920*200, MACONNERIE
In: Undefined
Description: PL2920*200; Material: CONCRETE/BETON COURANT
Tekla Commun - Repère de pièce: Z34; Repère d'assemblage: Z34; Phase: 10; Profil: PL2920*200; Nom: MACONNERIE; sets with these values: 2
Tekla Quantités - Poids: 2403.7 kg; Volume: 1.1 m3; Surface supérieure totale: 0.4 m2; Surface par tonne: 5.7 m2; Surface nette: 13.5 m2; Hauteur: 2920 mm; Largeur: 200 mm; Longueur: 1960 mm; sets with these values: 2
Pset_BeamCommon - LoadBearing: no; Reference: Z34
BaseQuantities - Length: 1960 mm; OuterSurfaceArea: 13.3984 m2; NetVolume: 1.14464 m3; NetWeight: 2403.74 kg

# IfcBeam: PL3*116 (2)
In: Undefined
Description: PL3*116; Material: STEEL/S235JR
Tekla Commun - Finition: GRENAILLE-PEINT; Repère de pièce: 1249; Repère d'assemblage: L104; Phase: 1; Profil: PL3*116; Nom: TOLE; sets with these values: 2
Tekla Quantités - Poids: 0.3 kg; Volume: 0 m3; Surface supérieure totale: 0 m2; Surface par tonne: 89.3 m2; Surface nette: 0 m2; Hauteur: 116 mm; Largeur: 3 mm; Longueur: 116 mm; sets with these values: 2
Pset_BeamCommon - LoadBearing: no; Reference: 1249
BaseQuantities - Length: 116 mm; OuterSurfaceArea: 0.028304 m2; NetVolume: 0.000040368 m3; NetWeight: 0.316889 kg

# IfcBeam: PL3*3600 (5)
In: Undefined
Description: PL3*3600; Material: STEEL/S235JR
Tekla Commun - Finition: TOLGALVA; Phase: 5; Profil: PL3*3600; Nom: FEUILLURE; sets with these values: 2
Tekla Quantités - Volume: 0 m3; Surface supérieure totale: 0 m2; Hauteur: 3600 mm; Largeur: 3 mm; sets with these values: 2
Pset_BeamCommon - LoadBearing: no
Name | Repère de pièce = Reference | Repère d'assemblage | Poids (kg) | Surface par tonne (m2) | Surface nette (m2) | Longueur (mm) = Length (mm) | OuterSurfaceArea (m2) | NetVolume (m3) | NetWeight (kg)
FEUILLURE | 1237 | F2 | 14.4 | 86.5 | 1.2 | 171 | 1.25383 | 0.0018468 | 14.4974
FEUILLURE | 1239 | F2 | 27.6 | 85.8 | 2.5 | 325 | 2.36355 | 0.00351 | 27.5535
FEUILLURE | 1237 | F1 | 14.4 | 86.5 | 1.2 | 171 | 1.25383 | 0.0018468 | 14.4974
FEUILLURE | 1238 | F1 | 24.2 | 85.8 | 2.1 | 285 | 2.07531 | 0.003078 | 24.1623
FEUILLURE | 1237 | F3 | 14.4 | 86.5 | 1.2 | 171 | 1.25383 | 0.0018468 | 14.4974

# IfcBeam: PL3*50, Unnamed
In: Undefined
Description: PL3*50; Material: STEEL/E24-2
Tekla Commun - Finition: GRENAILLE-PEINT; Repère de pièce: 1244; Repère d'assemblage: L80; Phase: 3; Profil: PL3*50; sets with these values: 2
Tekla Quantités - Poids: 0.1 kg; Volume: 0 m3; Surface supérieure totale: 0 m2; Surface par tonne: 92.3 m2; Surface nette: 0 m2; Hauteur: 50 mm; Largeur: 3 mm; Longueur: 111.1 mm; sets with these values: 2
Pset_BeamCommon - LoadBearing: no; Reference: 1244
BaseQuantities - Length: 111.085 mm; OuterSurfaceArea: 0.012075 m2; NetVolume: 0.0000166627 m3; NetWeight: 0.130803 kg

# IfcBeam: PL3*56 (28)
In: Undefined
Description: PL3*56; Material: STEEL/S235JR
Tekla Commun - Finition: GRENAILLE-PEINT; Profil: PL3*56; Nom: TOLE; sets with these values: 2
Tekla Quantités - Poids: 0.1 kg; Volume: 0 m3; Surface supérieure totale: 0 m2; Surface par tonne: 94 m2; Surface nette: 0 m2; Hauteur: 56 mm; Largeur: 3 mm; Longueur: 56 mm; sets with these values: 2
Pset_BeamCommon - LoadBearing: no
BaseQuantities - Length: 56 mm; OuterSurfaceArea: 0.006944 m2; NetVolume: 0.000009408 m3; NetWeight: 0.0738528 kg
Name | Repère de pièce = Reference | Repère d'assemblage | Phase
TOLE | 1251 | P52 | 7
TOLE | 1251 | P53 | 7
4 x TOLE | 1251 | L41 | 7
2 x TOLE | 1251 | L39 | 7
2 x TOLE | 1251 | L38 | 7
2 x TOLE | 1251 | L40 | 7
2 x TOLE | 1251 | L45 | 3
2 x TOLE | 1251 | N39 | 1
2 x TOLE | 1251 | N38 | 1
4 x TOLE | 1246 | L44 | 1
4 x TOLE | 1246 | L42 | 1
2 x TOLE | 1251 | L43 | 3

# IfcBeam: PL3*66 (8)
In: Undefined
Description: PL3*66; Material: STEEL/S235JR
Tekla Commun - Finition: GRENAILLE-PEINT; Repère de pièce: 1253; Phase: 7; Profil: PL3*66; Nom: TOLE; sets with these values: 2
Tekla Quantités - Poids: 0.1 kg; Volume: 0 m3; Surface supérieure totale: 0 m2; Surface par tonne: 92.6 m2; Surface nette: 0 m2; Hauteur: 66 mm; Largeur: 3 mm; Longueur: 66 mm; sets with these values: 2
Pset_BeamCommon - LoadBearing: no; Reference: 1253
BaseQuantities - Length: 66 mm; OuterSurfaceArea: 0.00950399 m2; NetVolume: 0.000013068 m3; NetWeight: 0.102584 kg
Name | Repère d'assemblage
6 x TOLE | L110
2 x TOLE | L109

# IfcBeam: PL3*76 (20)
In: Undefined
Description: PL3*76; Material: STEEL/E24-2
Tekla Commun - Finition: GRENAILLE-PEINT; Repère de pièce: 1245; Phase: 6; Profil: PL3*76; Nom: TOLE; sets with these values: 2
Tekla Quantités - Poids: 0.1 kg; Volume: 0 m3; Surface supérieure totale: 0 m2; Surface par tonne: 91.6 m2; Surface nette: 0 m2; Hauteur: 76 mm; Largeur: 3 mm; Longueur: 76 mm; sets with these values: 2
Pset_BeamCommon - LoadBearing: no; Reference: 1245
BaseQuantities - Length: 76 mm; OuterSurfaceArea: 0.012464 m2; NetVolume: 0.000017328 m3; NetWeight: 0.136025 kg
Name | Repère d'assemblage
2 x TOLE | L82
TOLE | S87
2 x TOLE | L83
4 x TOLE | L84
2 x TOLE | L86
TOLE | S88
2 x TOLE | L81
4 x TOLE | L85
2 x TOLE | L87

# IfcBeam: PL3*86 (41)
In: Undefined
Description: PL3*86; Material: STEEL/S235JR
Tekla Commun - Finition: GRENAILLE-PEINT; Profil: PL3*86; Nom: TOLE; sets with these values: 2
Tekla Quantités - Poids: 0.2 kg; Volume: 0 m3; Surface supérieure totale: 0 m2; Surface par tonne: 90.9 m2; Surface nette: 0 m2; Hauteur: 86 mm; Largeur: 3 mm; Longueur: 86 mm; sets with these values: 2
Pset_BeamCommon - LoadBearing: no
BaseQuantities - Length: 86 mm; OuterSurfaceArea: 0.015824 m2; NetVolume: 0.000022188 m3; NetWeight: 0.174176 kg
Name | Repère de pièce = Reference | Repère d'assemblage | Phase
2 x TOLE | 1247 | L91 | 1
2 x TOLE | 1247 | L90 | 1
2 x TOLE | 1247 | L88 | 1
2 x TOLE | 1247 | L89 | 1
2 x TOLE | 1247 | L92 | 1
2 x TOLE | 1247 | L95 | 1
2 x TOLE | 1252 | L106 | 3
2 x TOLE | 1247 | L96 | 1
4 x TOLE | 1247 | L98 | 1
6 x TOLE | 1247 | L94 | 1
2 x TOLE | 1247 | L99 | 1
4 x TOLE | 1247 | L93 | 1
TOLE | 1247 | L55 | 1
2 x TOLE | 1252 | L108 | 3
4 x TOLE | 1247 | L97 | 1
2 x TOLE | 1252 | L107 | 3

# IfcBeam: PL3*96 (8)
In: Undefined
Description: PL3*96; Material: STEEL/S235JR
Tekla Quantités - Poids: 0.2 kg; Volume: 0 m3; Surface supérieure totale: 0 m2; Surface par tonne: 90.2 m2; Surface nette: 0 m2; Hauteur: 96 mm; Largeur: 3 mm; Longueur: 96 mm; sets with these values: 2
BaseQuantities - Length: 96 mm; OuterSurfaceArea: 0.019584 m2; NetVolume: 0.000027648 m3; NetWeight: 0.217037 kg
Tekla Commun - Finition: GRENAILLE-PEINT; Repère de pièce: 1248; Phase: 1; Profil: PL3*96; Nom: TOLE; sets with these values: 2
Pset_BeamCommon - LoadBearing: no; Reference: 1248
Name | Repère d'assemblage
2 x TOLE | L103
2 x TOLE | L101
4 x TOLE | L102

# IfcBeam: PL30*152, GOUSSET
In: Undefined
Description: PL30*152; Material: STEEL/S235JR
Tekla Commun - Repère de pièce: G84; Repère d'assemblage: G84; Phase: 1; Profil: PL30*152; Nom: GOUSSET; sets with these values: 2
Tekla Quantités - Poids: 2.3 kg; Volume: 0 m3; Surface supérieure totale: 0 m2; Surface par tonne: 26.2 m2; Surface nette: 0.1 m2; Hauteur: 151.7 mm; Largeur: 30 mm; Longueur: 177.5 mm; sets with these values: 2
Pset_BeamCommon - LoadBearing: no; Reference: G84
BaseQuantities - Length: 177.47 mm; OuterSurfaceArea: 0.0596052 m2; NetVolume: 0.000290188 m3; NetWeight: 2.27797 kg

# IfcBeam: PL30*158, GOUSSET
In: Undefined
Description: PL30*158; Material: STEEL/S235JR
Tekla Commun - Repère de pièce: G88; Repère d'assemblage: G88; Phase: 1; Profil: PL30*158; Nom: GOUSSET; sets with these values: 2
Tekla Quantités - Poids: 2 kg; Volume: 0 m3; Surface supérieure totale: 0 m2; Surface par tonne: 26 m2; Surface nette: 0.1 m2; Hauteur: 158.4 mm; Largeur: 30 mm; Longueur: 177.5 mm; sets with these values: 2
Pset_BeamCommon - LoadBearing: no; Reference: G88
BaseQuantities - Length: 177.47 mm; OuterSurfaceArea: 0.0518057 m2; NetVolume: 0.000253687 m3; NetWeight: 1.99145 kg

# IfcBeam: PL30*16 (12)
In: Undefined
Description: PL30*16; Material: STEEL/S235JR
Tekla Commun - Phase: 1; Profil: PL30*16; Nom: GOUSSET; sets with these values: 2
Tekla Quantités - Volume: 0 m3; Surface supérieure totale: 0 m2; Surface par tonne: 27.3 m2; Surface nette: 0 m2; Hauteur: 16 mm; Largeur: 30 mm; sets with these values: 2
Pset_BeamCommon - LoadBearing: no
Name | Repère de pièce = Repère d'assemblage = Reference | Poids (kg) | Longueur (mm) | Length (mm) | OuterSurfaceArea (m2) | NetVolume (m3) | NetWeight (kg)
GOUSSET | G98(?) | 0.6 | 162.2 | 162.22 | 0.0157486 | 0.0000734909 | 0.576904
10 x GOUSSET | G94 | 0.3 | 81.1 | 81.11 | 0.00787429 | 0.0000367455 | 0.288452
GOUSSET | G98 | 0.6 | 162.2 | 162.22 | 0.0157486 | 0.0000734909 | 0.576904

# IfcBeam: PL30*160 (2)
In: Undefined
Description: PL30*160; Material: STEEL/S235JR
Tekla Commun - Phase: 1; Profil: PL30*160; Nom: GOUSSET; sets with these values: 2
Tekla Quantités - Volume: 0 m3; Surface supérieure totale: 0 m2; Hauteur: 160.3 mm; Largeur: 30 mm; sets with these values: 2
Pset_BeamCommon - LoadBearing: no
Name | Repère de pièce = Repère d'assemblage = Reference | Poids (kg) | Surface par tonne (m2) | Surface nette (m2) | Longueur (mm) | Length (mm) | OuterSurfaceArea (m2) | NetVolume (m3) | NetWeight (kg)
GOUSSET | G90 | 1.4 | 26.4 | 0 | 162.9 | 162.88 | 0.0377011 | 0.000181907 | 1.42797
GOUSSET | G87 | 2 | 26 | 0.1 | 177.5 | 177.47 | 0.0517826 | 0.000253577 | 1.99058

# IfcBeam: PL30*170, GOUSSET
In: Undefined
Description: PL30*170; Material: STEEL/S235JR
Tekla Commun - Repère de pièce: G92; Repère d'assemblage: G92; Phase: 1; Profil: PL30*170; Nom: GOUSSET; sets with these values: 2
Tekla Quantités - Poids: 0.9 kg; Volume: 0 m3; Surface supérieure totale: 0 m2; Surface par tonne: 26.6 m2; Surface nette: 0 m2; Hauteur: 170.1 mm; Largeur: 30 mm; Longueur: 89.1 mm; sets with these values: 2
Pset_BeamCommon - LoadBearing: no; Reference: G92
BaseQuantities - Length: 89.1069 mm; OuterSurfaceArea: 0.0228084 m2; NetVolume: 0.000109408 m3; NetWeight: 0.858856 kg

# IfcBeam: PL30*177 (5)
In: Undefined
Description: PL30*177; Material: STEEL/S235JR
Tekla Commun - Phase: 1; Profil: PL30*177; Nom: GOUSSET; sets with these values: 2
Tekla Quantités - Volume: 0 m3; Surface supérieure totale: 0 m2; Hauteur: 177.5 mm; Largeur: 30 mm; sets with these values: 2
Pset_BeamCommon - LoadBearing: no
Name | Repère de pièce = Repère d'assemblage = Reference | Poids (kg) | Surface par tonne (m2) | Surface nette (m2) | Longueur (mm) | Length (mm) | OuterSurfaceArea (m2) | NetVolume (m3) | NetWeight (kg)
GOUSSET | G97(?) | 1.7 | 25 | 0 | 97.1 | 97.11 | 0.0422921 | 0.000215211 | 1.68941
GOUSSET | G96 | 1.7 | 25 | 0 | 96.7 | 96.74 | 0.0422267 | 0.000214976 | 1.68756
GOUSSET | G89 | 2 | 27.3 | 0.1 | 96.9 | 96.9 | 0.05512 | 0.000257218 | 2.01916
GOUSSET | G97 | 1.7 | 25 | 0 | 97.1 | 97.11 | 0.0422921 | 0.000215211 | 1.68941
GOUSSET | G91 | 1.4 | 25.5 | 0 | 96.9 | 96.79 | 0.036006 | 0.000180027 | 1.41321

# IfcBeam: PL30*97, GOUSSET
In: Undefined
Description: PL30*97; Material: STEEL/S235JR
Tekla Commun - Repère de pièce: G93; Repère d'assemblage: G93; Phase: 1; Profil: PL30*97; Nom: GOUSSET; sets with these values: 2
Tekla Quantités - Poids: 0.9 kg; Volume: 0 m3; Surface supérieure totale: 0 m2; Surface par tonne: 25.8 m2; Surface nette: 0 m2; Hauteur: 96.8 mm; Largeur: 30 mm; Longueur: 162 mm; sets with these values: 2
Pset_BeamCommon - LoadBearing: no; Reference: G93
BaseQuantities - Length: 162.04 mm; OuterSurfaceArea: 0.0219605 m2; NetVolume: 0.000108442 m3; NetWeight: 0.851267 kg

# IfcBeam: PL30*99, GOUSSET
In: Undefined
Description: PL30*99; Material: STEEL/S235JR
Tekla Commun - Repère de pièce: G95; Repère d'assemblage: G95; Phase: 1; Profil: PL30*99; Nom: GOUSSET; sets with these values: 2
Tekla Quantités - Poids: 1.2 kg; Volume: 0 m3; Surface supérieure totale: 0 m2; Surface par tonne: 27.3 m2; Surface nette: 0 m2; Hauteur: 99.3 mm; Largeur: 30 mm; Longueur: 162.2 mm; sets with these values: 2
Pset_BeamCommon - LoadBearing: no; Reference: G95
BaseQuantities - Length: 162.22 mm; OuterSurfaceArea: 0.0314971 m2; NetVolume: 0.000146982 m3; NetWeight: 1.15381 kg

# IfcBeam: PL300*250, CHEMIN_CABLES
In: Undefined
Description: PL300*250; Material: STEEL/E24-2
Tekla Commun - Repère de pièce: Z59; Repère d'assemblage: Z59; Phase: 7; Profil: PL300*250; Nom: CHEMIN_CABLES; sets with these values: 2
Tekla Quantités - Poids: 3893.5 kg; Volume: 0.5 m3; Surface supérieure totale: 0 m2; Surface par tonne: 1.9 m2; Surface nette: 7.4 m2; Hauteur: 300 mm; Largeur: 250 mm; Longueur: 6613.2 mm; sets with these values: 2
Pset_BeamCommon - LoadBearing: no; Reference: Z59
BaseQuantities - Length: 6613.18 mm; OuterSurfaceArea: 7.42449 m2; NetVolume: 0.495988 m3; NetWeight: 3893.51 kg

# IfcBeam: PL300*6 (16)
In: Undefined
Description: PL300*6
Tekla Commun - Phase: 1; Profil: PL300*6; sets with these values: 2
Tekla Quantités - Volume: 0 m3; Surface supérieure totale: 0 m2; Hauteur: 300 mm; Largeur: 6 mm; sets with these values: 2
Pset_BeamCommon - LoadBearing: no
Name | Material | Finition | Repère de pièce = Reference | Repère d'assemblage | Nom | Poids (kg) | Surface par tonne (m2) | Surface nette (m2) | Longueur (mm) | Length (mm) | OuterSurfaceArea (m2) | NetVolume (m3) | NetWeight (kg)
4 x PLAT | STEEL/S235JR | GALVANISE | 357 | S39 | PLAT | 6.8 | 43.8 | 0.3 | 483.9 | 483.923 | 0.299761 | 0.000871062 | 6.83783
PLAT | STEEL/S235JR | GALVANISE | 357 | S11 | PLAT | 6.8 | 43.8 | 0.3 | 483.9 | 483.923 | 0.299761 | 0.000871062 | 6.83783
4 x PLAT | STEEL/S235JR | GALVANISE | 357 | S38 | PLAT | 6.8 | 43.8 | 0.3 | 483.9 | 483.923 | 0.299761 | 0.000871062 | 6.83783
2 x PLAT | STEEL/S235JR | GALVANISE | 357 | S37 | PLAT | 6.8 | 43.8 | 0.3 | 483.9 | 483.923 | 0.299761 | 0.000871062 | 6.83783
PLAT | STEEL/S235JR | GALVANISE | 357 | S28 | PLAT | 6.8 | 43.8 | 0.3 | 483.9 | 483.923 | 0.299761 | 0.000871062 | 6.83783
2 x Unnamed | STEEL/E24-2 | GRENAILLE-PEINT | 321 | L5 |  | 1.1 | 46.4 | 0.1 | 80 | 80 | 0.05256 | 0.000144 | 1.1304
2 x Unnamed | STEEL/E24-2 | GRENAILLE-PEINT | 321 | L4 |  | 1.1 | 46.4 | 0.1 | 80 | 80 | 0.05256 | 0.000144 | 1.1304

# IfcBeam: PL320*6 (11)
In: Undefined
Description: PL320*6; Material: STEEL/S235JR
Tekla Commun - Finition: GALVANISE; Repère de pièce: 356; Phase: 2; Profil: PL320*6; Nom: PLAT; sets with these values: 2
Tekla Quantités - Poids: 4.2 kg; Volume: 0 m3; Surface supérieure totale: 0 m2; Surface par tonne: 45.1 m2; Surface nette: 0.2 m2; Hauteur: 320 mm; Largeur: 6 mm; Longueur: 320 mm; sets with these values: 2
Pset_BeamCommon - LoadBearing: no; Reference: 356
BaseQuantities - Length: 320 mm; OuterSurfaceArea: 0.184704 m2; NetVolume: 0.000522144 m3; NetWeight: 4.09883 kg
Name | Repère d'assemblage
PLAT | S2
10 x PLAT | S1

# IfcBeam: PL3450*200 (2)
In: Undefined
Description: PL3450*200; Material: CONCRETE/BETON COURANT
Tekla Commun - Phase: 10; Profil: PL3450*200; Nom: MACONNERIE; sets with these values: 2
Tekla Quantités - Surface supérieure totale: 1.4 m2; Surface par tonne: 5.1 m2; Hauteur: 3450 mm; Largeur: 200 mm; sets with these values: 2
Pset_BeamCommon - LoadBearing: no
Name | Repère de pièce = Repère d'assemblage = Reference | Poids (kg) = NetWeight (kg) | Volume (m3) | Surface nette (m2) | Longueur (mm) = Length (mm) | OuterSurfaceArea (m2) | NetVolume (m3)
MACONNERIE | Z20 | 10461.8 | 5 | 54.1 | 7220 | 54.086 | 4.9818
MACONNERIE | Z18 | 10751.6 | 5.1 | 55.5 | 7420 | 55.546 | 5.1198

# IfcBeam: PL3860*200, MACONNERIE
In: Undefined
Description: PL3860*200; Material: CONCRETE/BETON COURANT
Tekla Commun - Repère de pièce: Z48; Repère d'assemblage: Z48; Phase: 10; Profil: PL3860*200; Nom: MACONNERIE; sets with these values: 2
Tekla Quantités - Poids: 10740.9 kg; Volume: 5.1 m3; Surface supérieure totale: 1.4 m2; Surface par tonne: 5.1 m2; Surface nette: 56.3 m2; Hauteur: 3860 mm; Largeur: 200 mm; Longueur: 6905.1 mm; sets with these values: 2
Pset_BeamCommon - LoadBearing: no; Reference: Z48
BaseQuantities - Length: 6905.1 mm; OuterSurfaceArea: 56.2934 m2; NetVolume: 5.11474 m3; NetWeight: 10740.9 kg

# IfcBeam: PL3920*180, MACONNERIE
In: Undefined
Description: PL3920*180; Material: CONCRETE/BETON COURANT
Tekla Commun - Repère de pièce: Z3; Repère d'assemblage: Z3; Phase: 10; Profil: PL3920*180; Nom: MACONNERIE; sets with these values: 2
Tekla Quantités - Poids: 29287.1 kg; Volume: 13.9 m3; Surface supérieure totale: 3.6 m2; Surface par tonne: 5.7 m2; Surface nette: 163.5 m2; Hauteur: 3920 mm; Largeur: 180 mm; Longueur: 19765.1 mm; sets with these values: 2
Pset_BeamCommon - LoadBearing: no; Reference: Z3
BaseQuantities - Length: 19765.1 mm; OuterSurfaceArea: 163.485 m2; NetVolume: 13.9462 m3; NetWeight: 29287.1 kg

# IfcBeam: PL3920*200, MACONNERIE
In: Undefined
Description: PL3920*200; Material: CONCRETE/BETON COURANT
Tekla Commun - Repère de pièce: Z21; Repère d'assemblage: Z21; Phase: 10; Profil: PL3920*200; Nom: MACONNERIE; sets with these values: 2
Tekla Quantités - Poids: 12841.9 kg; Volume: 6.1 m3; Surface supérieure totale: 1.6 m2; Surface par tonne: 5.1 m2; Surface nette: 65.8 m2; Hauteur: 3920 mm; Largeur: 200 mm; Longueur: 7800 mm; sets with these values: 2
Pset_BeamCommon - LoadBearing: no; Reference: Z21
BaseQuantities - Length: 7800 mm; OuterSurfaceArea: 65.84 m2; NetVolume: 6.1152 m3; NetWeight: 12841.9 kg

# IfcBeam: PL4340*200, PREFA
In: Undefined
Description: PL4340*200; Material: CONCRETE/BETON COURANT
Tekla Commun - Repère de pièce: Z38; Repère d'assemblage: Z38; Phase: 10; Profil: PL4340*200; Nom: PREFA; sets with these values: 2
Tekla Quantités - Poids: 29916.1 kg; Volume: 14.2 m3; Surface supérieure totale: 3.2 m2; Surface par tonne: 5.1 m2; Surface nette: 152.1 m2; Hauteur: 4340 mm; Largeur: 200 mm; Longueur: 19885 mm; sets with these values: 2
Pset_BeamCommon - LoadBearing: no; Reference: Z38
BaseQuantities - Length: 19885 mm; OuterSurfaceArea: 152.148 m2; NetVolume: 14.2458 m3; NetWeight: 29916.1 kg

# IfcBeam: PL4450*200, MACONNERIE
In: Undefined
Description: PL4450*200; Material: CONCRETE/BETON COURANT
Tekla Commun - Repère de pièce: Z19; Repère d'assemblage: Z19; Phase: 10; Profil: PL4450*200; Nom: MACONNERIE; sets with these values: 2
Tekla Quantités - Poids: 18176 kg; Volume: 8.7 m3; Surface supérieure totale: 1.9 m2; Surface par tonne: 5.1 m2; Surface nette: 92.2 m2; Hauteur: 4450 mm; Largeur: 200 mm; Longueur: 9725 mm; sets with these values: 2
Pset_BeamCommon - LoadBearing: no; Reference: Z19
BaseQuantities - Length: 9725 mm; OuterSurfaceArea: 92.2225 m2; NetVolume: 8.65525 m3; NetWeight: 18176 kg

# IfcBeam: PL4500*200 (4)
In: Undefined
Description: PL4500*200; Material: CONCRETE/BETON COURANT
Tekla Commun - Phase: 10; Profil: PL4500*200; sets with these values: 2
Tekla Quantités - Hauteur: 4500 mm; Largeur: 200 mm; sets with these values: 2
Pset_BeamCommon - LoadBearing: no
Name | Repère de pièce = Repère d'assemblage = Reference | Nom | Poids (kg) | Volume (m3) | Surface supérieure totale (m2) | Surface par tonne (m2) | Surface nette (m2) | Longueur (mm) = Length (mm) | OuterSurfaceArea (m2) | NetVolume (m3) | NetWeight (kg)
2 x PREFA | Z54 | PREFA | 137150 | 65.3 | 14.5 | 4.9 | 683.9 | 72566.4 | 683.924 | 65.3098 | 137150
PREFA | Z39 | PREFA | 1423.6 | 0.6 | 0.1 | 6.3 | 8.9 | 835 | 8.913 | 0.6779 | 1423.59
MACONNERIE | Z16 | MACONNERIE | 1597.1 | 0.9 | 0.2 | 6.1 | 9.6 | 845 | 9.743 | 0.7605 | 1597.05

# IfcBeam: PL4860*200 (3)
In: Undefined
Description: PL4860*200; Material: CONCRETE/BETON COURANT
Tekla Commun - Phase: 10; Profil: PL4860*200; Nom: MACONNERIE; sets with these values: 2
Tekla Quantités - Surface par tonne: 5.1 m2; Hauteur: 4860 mm; Largeur: 200 mm; sets with these values: 2
Pset_BeamCommon - LoadBearing: no
Name | Repère de pièce = Repère d'assemblage = Reference | Poids (kg) = NetWeight (kg) | Volume (m3) | Surface supérieure totale (m2) | Surface nette (m2) | Longueur (mm) = Length (mm) | OuterSurfaceArea (m2) | NetVolume (m3)
MACONNERIE | Z17 | 14686.4 | 7 | 1.4 | 74.8 | 7195 | 74.7574 | 6.99354
MACONNERIE | Z49 | 33490.8 | 15.9 | 3.4 | 169.7 | 17000 | 169.664 | 15.948
MACONNERIE | Z45 | 25593.7 | 12.2 | 2.6 | 130.4 | 12915 | 130.435 | 12.1875

# IfcBeam: PL4860*250 (2)
In: Undefined
Description: PL4860*250; Material: CONCRETE/BETON COURANT
Tekla Commun - Phase: 10; Profil: PL4860*250; Nom: MACONNERIE; sets with these values: 2
Tekla Quantités - Hauteur: 4860 mm; Largeur: 250 mm; sets with these values: 2
Pset_BeamCommon - LoadBearing: no
Name | Repère de pièce = Repère d'assemblage = Reference | Poids (kg) = NetWeight (kg) | Volume (m3) | Surface supérieure totale (m2) | Surface par tonne (m2) | Surface nette (m2) | Longueur (mm) = Length (mm) | OuterSurfaceArea (m2) | NetVolume (m3)
MACONNERIE | Z60 | 11943 | 5.7 | 1.4 | 4.5 | 54 | 5720 | 53.9943 | 5.68714
MACONNERIE | Z61 | 25836.6 | 12.4 | 4.3 | 4.9 | 123 | 17000 | 123.003 | 12.3031

# IfcBeam: PL5*200 (12)
In: Undefined
Description: PL5*200; Material: STEEL/S235JR
Tekla Commun - Finition: GALVANISE; Repère de pièce: Y5; Repère d'assemblage: Y5; Phase: 1; Profil: PL5*200; Nom: CALE; sets with these values: 2
Tekla Quantités - Poids: 1.6 kg; Volume: 0 m3; Surface supérieure totale: 0 m2; Surface par tonne: 53.5 m2; Surface nette: 0.1 m2; Hauteur: 200 mm; Largeur: 5 mm; Longueur: 200 mm; sets with these values: 2
Pset_BeamCommon - LoadBearing: no; Reference: Y5
BaseQuantities - Length: 200 mm; OuterSurfaceArea: 0.084 m2; NetVolume: 0.0002 m3; NetWeight: 1.57 kg

# IfcBeam: PL50*5 (14)
In: Undefined
Description: PL50*5; Material: STEEL/S235JR
Tekla Commun - Finition: GALVANISE; Repère de pièce: Y4; Repère d'assemblage: Y4; Phase: 4; Profil: PL50*5; Nom: CALLE; sets with these values: 2
Tekla Quantités - Poids: 0.1 kg; Volume: 0 m3; Surface supérieure totale: 0 m2; Surface par tonne: 61.1 m2; Surface nette: 0 m2; Hauteur: 50 mm; Largeur: 5 mm; Longueur: 50 mm; sets with these values: 2
Pset_BeamCommon - LoadBearing: no; Reference: Y4
BaseQuantities - Length: 50 mm; OuterSurfaceArea: 0.006 m2; NetVolume: 0.0000125 m3; NetWeight: 0.098125 kg

# IfcBeam: PL50*6 (8)
In: Undefined
Description: PL50*6; Material: STEEL/E24-2
Tekla Commun - Finition: GRENAILLE-PEINT; Repère de pièce: 330; Phase: 2; Profil: PL50*6; Nom: PLAT; sets with these values: 2
Tekla Quantités - Poids: 0.2 kg; Volume: 0 m3; Surface supérieure totale: 0 m2; Surface par tonne: 50.4 m2; Surface nette: 0 m2; Hauteur: 50 mm; Largeur: 6 mm; Longueur: 90 mm; sets with these values: 2
Pset_BeamCommon - LoadBearing: no; Reference: 330
BaseQuantities - Length: 90 mm; OuterSurfaceArea: 0.01068 m2; NetVolume: 0.000027 m3; NetWeight: 0.21195 kg
Name | Repère d'assemblage
2 x PLAT | L49
4 x PLAT | L50
2 x PLAT | L51

# IfcBeam: PL50*8 (518)
In: Undefined
Description: PL50*8; Material: STEEL/E24-2
Tekla Commun - Finition: GRENAILLE-PEINT; Repère de pièce: Y3; Repère d'assemblage: Y3; Profil: PL50*8; Nom: CALE; sets with these values: 2
Tekla Quantités - Poids: 0.2 kg; Volume: 0 m3; Surface supérieure totale: 0 m2; Surface par tonne: 42 m2; Surface nette: 0 m2; Hauteur: 50 mm; Largeur: 8 mm; Longueur: 50 mm; sets with these values: 2
Pset_BeamCommon - LoadBearing: no; Reference: Y3
BaseQuantities - Length: 50 mm; OuterSurfaceArea: 0.0066 m2; NetVolume: 0.00002 m3; NetWeight: 0.157 kg
Name | Phase
48 x CALE | 3
167 x CALE | 2
303 x CALE | 1

# IfcBeam: PL56*3 (33)
In: Undefined
Description: PL56*3; Material: STEEL/E24-2
BaseQuantities - Length: 56 mm; OuterSurfaceArea: 0.006944 m2; NetVolume: 0.000009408 m3; NetWeight: 0.0738528 kg
Tekla Commun - Finition: GRENAILLE-PEINT; Repère de pièce: 1241; Profil: PL56*3; sets with these values: 2
Tekla Quantités - Poids: 0.1 kg; Volume: 0 m3; Surface supérieure totale: 0 m2; Surface par tonne: 94 m2; Surface nette: 0 m2; Hauteur: 56 mm; Largeur: 3 mm; Longueur: 56 mm; sets with these values: 2
Pset_BeamCommon - LoadBearing: no; Reference: 1241
Name | Repère d'assemblage | Phase
Unnamed | N46 | 2
8 x Unnamed | L47 | 3
16 x Unnamed | L47 | 1
4 x Unnamed | L48 | 2
4 x Unnamed | L47 | 2

# IfcBeam: PL5680*200 (2)
In: Undefined
Description: PL5680*200; Material: CONCRETE/BETON COURANT
Tekla Commun - Phase: 10; Profil: PL5680*200; sets with these values: 2
Tekla Quantités - Surface supérieure totale: 0.2 m2; Surface par tonne: 5.1 m2; Hauteur: 5680 mm; Largeur: 200 mm; sets with these values: 2
Pset_BeamCommon - LoadBearing: no
Name | Repère de pièce = Repère d'assemblage = Reference | Nom | Poids (kg) = NetWeight (kg) | Volume (m3) | Surface nette (m2) | Longueur (mm) = Length (mm) | OuterSurfaceArea (m2) | NetVolume (m3)
MACONNERIE | Z40 | MACONNERIE | 21663.4 | 10.3 | 109.9 | 11199.9 | 109.911 | 10.3159
PREFA | Z37 | PREFA | 22080.8 | 10.5 | 112 | 11374.9 | 111.969 | 10.5147

# IfcBeam: PL5920*200, MACONNERIE
In: Undefined
Description: PL5920*200; Material: CONCRETE/BETON COURANT
Tekla Commun - Repère de pièce: Z47; Repère d'assemblage: Z47; Phase: 10; Profil: PL5920*200; Nom: MACONNERIE; sets with these values: 2
Tekla Quantités - Poids: 15126.3 kg; Volume: 7.2 m3; Surface supérieure totale: 1 m2; Surface par tonne: 5.1 m2; Surface nette: 78.1 m2; Hauteur: 5920 mm; Largeur: 200 mm; Longueur: 6630 mm; sets with these values: 2
Pset_BeamCommon - LoadBearing: no; Reference: Z47
BaseQuantities - Length: 6630 mm; OuterSurfaceArea: 78.1176 m2; NetVolume: 7.203 m3; NetWeight: 15126.3 kg

# IfcBeam: PL5940*200, MACONNERIE
In: Undefined
Description: PL5940*200; Material: CONCRETE/BETON COURANT
Tekla Commun - Repère de pièce: Z15; Repère d'assemblage: Z15; Phase: 10; Profil: PL5940*200; Nom: MACONNERIE; sets with these values: 2
Tekla Quantités - Poids: 52889.8 kg; Volume: 25.2 m3; Surface supérieure totale: 4.3 m2; Surface par tonne: 4.9 m2; Surface nette: 262.7 m2; Hauteur: 5940 mm; Largeur: 200 mm; Longueur: 21200 mm; sets with these values: 2
Pset_BeamCommon - LoadBearing: no; Reference: Z15
BaseQuantities - Length: 21200 mm; OuterSurfaceArea: 262.712 m2; NetVolume: 25.1856 m3; NetWeight: 52889.8 kg

# IfcBeam: PL5950*200 (4)
In: Undefined
Description: PL5950*200; Material: CONCRETE/BETON COURANT
Tekla Commun - Phase: 10; Profil: PL5950*200; Nom: MACONNERIE; sets with these values: 2
Tekla Quantités - Largeur: 200 mm; sets with these values: 2
Pset_BeamCommon - LoadBearing: no
Name | Repère de pièce = Repère d'assemblage = Reference | Poids (kg) | Volume (m3) | Surface supérieure totale (m2) | Surface par tonne (m2) | Surface nette (m2) | Hauteur (mm) | Longueur (mm) | Length (mm) | OuterSurfaceArea (m2) | NetVolume (m3) | NetWeight (kg)
MACONNERIE | Z50 | 4499.1 | 2.1 | 0 | 5.7 | 25.4 | 5573.8 | 2270.2 | 2270.2 | 25.393 | 2.14244 | 4499.12
MACONNERIE | Z42 | 8119.2 | 3.9 | 0.4 | 5.4 | 42.8 | 5950 | 4324.4 | 4324.37 | 42.7725 | 3.86628 | 8119.18
MACONNERIE | Z51 | 25773.3 | 12.4 | 0 | 5.1 | 131.6 | 5528.4 | 13620 | 13620 | 131.589 | 12.273 | 25773.3
MACONNERIE | Z41 | 64027.7 | 30.5 | 0 | 4.9 | 318.2 | 5560.7 | 27680 | 27680 | 318.221 | 30.4894 | 64027.7

# IfcBeam: PL5960*200, MACONNERIE
In: Undefined
Description: PL5960*200; Material: CONCRETE/BETON COURANT
Tekla Commun - Repère de pièce: Z14; Repère d'assemblage: Z14; Phase: 10; Profil: PL5960*200; Nom: MACONNERIE; sets with these values: 2
Tekla Quantités - Poids: 28999.8 kg; Volume: 13.9 m3; Surface supérieure totale: 2.3 m2; Surface par tonne: 4.9 m2; Surface nette: 145.1 m2; Hauteur: 5960 mm; Largeur: 200 mm; Longueur: 11585.1 mm; sets with these values: 2
Pset_BeamCommon - LoadBearing: no; Reference: Z14
BaseQuantities - Length: 11585.1 mm; OuterSurfaceArea: 145.112 m2; NetVolume: 13.8094 m3; NetWeight: 28999.8 kg

# IfcBeam: PL6*115, CV
In: Undefined
Description: PL6*115; Material: STEEL/S235JR
Tekla Commun - Finition: GALVANISE; Repère de pièce: 323; Repère d'assemblage: L6; Phase: 4; Profil: PL6*115; Nom: CV; sets with these values: 2
Tekla Quantités - Poids: 0.5 kg; Volume: 0 m3; Surface supérieure totale: 0 m2; Surface par tonne: 47.5 m2; Surface nette: 0 m2; Hauteur: 115 mm; Largeur: 6 mm; Longueur: 150 mm; sets with these values: 2
Pset_BeamCommon - LoadBearing: no; Reference: 323
BaseQuantities - Length: 150 mm; OuterSurfaceArea: 0.0257048 m2; NetVolume: 0.000069 m3; NetWeight: 0.54165 kg

# IfcBeam: PL6*210 (127)
In: Undefined
Description: PL6*210; Material: STEEL/S235JR
Tekla Commun - Finition: GALVANISE; Repère de pièce: 334; Profil: PL6*210; Nom: TOLE; sets with these values: 2
Tekla Quantités - Poids: 1.2 kg; Volume: 0 m3; Surface supérieure totale: 0 m2; Surface par tonne: 45.8 m2; Surface nette: 0.1 m2; Hauteur: 210 mm; Largeur: 6 mm; Longueur: 120 mm; sets with these values: 2
Pset_BeamCommon - LoadBearing: no; Reference: 334
BaseQuantities - Length: 120 mm; OuterSurfaceArea: 0.05436 m2; NetVolume: 0.0001512 m3; NetWeight: 1.18692 kg
Name | Repère d'assemblage | Phase
2 x TOLE | P83 | 2
14 x TOLE | P76 | 2
2 x TOLE | P77 | 2
14 x TOLE | P62 | 2
TOLE | P91 | 2
TOLE | P92 | 2
TOLE | P93 | 2
5 x TOLE | P63 | 2
5 x TOLE | P64 | 2
5 x TOLE | P72 | 2
5 x TOLE | P65 | 2
TOLE | P84 | 2
TOLE | P85 | 2
TOLE | P86 | 2
2 x TOLE | P78 | 2
2 x TOLE | P79 | 2
14 x TOLE | P66 | 2
14 x TOLE | P67 | 2
TOLE | P75 | 1
2 x TOLE | P74 | 1
2 x TOLE | P87 | 1
7 x TOLE | P71 | 1
7 x TOLE | P73 | 1
TOLE | P80 | 1
TOLE | P81 | 1
TOLE | P82 | 1
TOLE | P90 | 1
TOLE | P89 | 1
TOLE | P88 | 1
4 x TOLE | P68 | 1
4 x TOLE | P69 | 1
4 x TOLE | P70 | 1

# IfcBeam: PL6*240 (32)
In: Undefined
Description: PL6*240; Material: STEEL/E36-3
Tekla Commun - Finition: GRENAILLE-PEINT; Repère de pièce: H8; Repère d'assemblage: H8; Profil: PL6*240; Nom: ECLISSE; sets with these values: 2
Tekla Quantités - Poids: 3.7 kg; Volume: 0 m3; Surface supérieure totale: 0 m2; Surface par tonne: 44.3 m2; Surface nette: 0.2 m2; Hauteur: 240 mm; Largeur: 6 mm; Longueur: 330 mm; sets with these values: 2
Pset_BeamCommon - LoadBearing: no; Reference: H8
BaseQuantities - Length: 330 mm; OuterSurfaceArea: 0.16524 m2; NetVolume: 0.0004752 m3; NetWeight: 3.73032 kg
Name | Phase
4 x ECLISSE | 2
24 x ECLISSE | 1
4 x ECLISSE | 3

# IfcBeam: PL6*86, TOLE
In: Undefined
Description: PL6*86; Material: STEEL/S235JR
Tekla Commun - Finition: GRENAILLE-PEINT; Repère de pièce: 333; Repère d'assemblage: L55; Phase: 1; Profil: PL6*86; Nom: TOLE; sets with these values: 2
Tekla Quantités - Poids: 0.3 kg; Volume: 0 m3; Surface supérieure totale: 0 m2; Surface par tonne: 48.4 m2; Surface nette: 0 m2; Hauteur: 86 mm; Largeur: 6 mm; Longueur: 86 mm; sets with these values: 2
Pset_BeamCommon - LoadBearing: no; Reference: 333
BaseQuantities - Length: 86 mm; OuterSurfaceArea: 0.016856 m2; NetVolume: 0.000044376 m3; NetWeight: 0.348352 kg

# IfcBeam: PL60*10 (6)
In: Undefined
Description: PL60*10; Material: STEEL/E24-2
Tekla Commun - Finition: GRENAILLE-PEINT; Phase: 2; Profil: PL60*10; sets with these values: 2
Tekla Quantités - Volume: 0 m3; Surface supérieure totale: 0 m2; Surface nette: 0 m2; Hauteur: 60 mm; Largeur: 10 mm; sets with these values: 2
Pset_BeamCommon - LoadBearing: no
Name | Repère de pièce = Reference | Repère d'assemblage | Nom | Poids (kg) | Surface par tonne (m2) | Longueur (mm) = Length (mm) | OuterSurfaceArea (m2) | NetVolume (m3) | NetWeight (kg)
2 x PLAT | 291 | N19 | PLAT | 0.3 | 34 | 60 | 0.0096 | 0.000036 | 0.2826
2 x ATTACHE | H7 | H7 | ATTACHE | 0.6 | 31.5 | 142 | 0.02108 | 0.0000852 | 0.66882
PLAT | 291 | N20 | PLAT | 0.3 | 34 | 60 | 0.0096 | 0.000036 | 0.2826
PLAT | 291 | N21 | PLAT | 0.3 | 34 | 60 | 0.0096 | 0.000036 | 0.2826

# IfcBeam: PL60*6 (114)
In: Undefined
Description: PL60*6
Tekla Commun - Finition: GRENAILLE-PEINT; Profil: PL60*6; sets with these values: 2
Tekla Quantités - Volume: 0 m3; Surface supérieure totale: 0 m2; Surface nette: 0 m2; Hauteur: 60 mm; Largeur: 6 mm; sets with these values: 2
Pset_BeamCommon - LoadBearing: no
Name | Material | Repère de pièce = Reference | Repère d'assemblage | Phase | Nom | Poids (kg) | Surface par tonne (m2) | Longueur (mm) = Length (mm) | OuterSurfaceArea (m2) | NetVolume (m3) | NetWeight (kg)
4 x PLAT | STEEL/E24-2 | 346 | U7 | 4 | PLAT | 0.3 | 48.8 | 120 | 0.01656 | 0.0000432 | 0.33912
8 x ATTACHE | STEEL/S235JR | H9 | H9 | 3 | ATTACHE | 0.5 | 48.2 | 175 | 0.02382 | 0.000063 | 0.49455
8 x PLAT | STEEL/S235JR | 336 | U11 | 3 | PLAT | 0.3 | 48.8 | 120 | 0.01656 | 0.0000432 | 0.33912
16 x PLAT | STEEL/S235JR | 336 | U12 | 3 | PLAT | 0.3 | 48.8 | 120 | 0.01656 | 0.0000432 | 0.33912
4 x PLAT | STEEL/S235JR | 336 | U13 | 3 | PLAT | 0.3 | 48.8 | 120 | 0.01656 | 0.0000432 | 0.33912
4 x PLAT | STEEL/E24-2 | 346 | U6 | 2 | PLAT | 0.3 | 48.8 | 120 | 0.01656 | 0.0000432 | 0.33912
4 x PLAT | STEEL/E24-2 | 346 | U5 | 2 | PLAT | 0.3 | 48.8 | 120 | 0.01656 | 0.0000432 | 0.33912
4 x PLAT | STEEL/E24-2 | 346 | U1 | 2 | PLAT | 0.3 | 48.8 | 120 | 0.01656 | 0.0000432 | 0.33912
4 x PLAT | STEEL/E24-2 | 346 | U16 | 2 | PLAT | 0.3 | 48.8 | 120 | 0.01656 | 0.0000432 | 0.33912
4 x PLAT | STEEL/E24-2 | 346 | U15 | 2 | PLAT | 0.3 | 48.8 | 120 | 0.01656 | 0.0000432 | 0.33912
4 x PLAT | STEEL/E24-2 | 346 | U14 | 2 | PLAT | 0.3 | 48.8 | 120 | 0.01656 | 0.0000432 | 0.33912
12 x PLAT | STEEL/E24-2 | 346 | U2 | 1 | PLAT | 0.3 | 48.8 | 120 | 0.01656 | 0.0000432 | 0.33912
16 x PLAT | STEEL/E24-2 | 346 | U3 | 1 | PLAT | 0.3 | 48.8 | 120 | 0.01656 | 0.0000432 | 0.33912
16 x PLAT | STEEL/E24-2 | 346 | U4 | 1 | PLAT | 0.3 | 48.8 | 120 | 0.01656 | 0.0000432 | 0.33912
Unnamed | STEEL/S235JR | 351 | L10 | 1 |  | 0.3 | 48.9 | 116 | 0.016032 | 0.00004176 | 0.327816
Unnamed | STEEL/E24-2 | 345 | M1 | 1 |  | 0.3 | 48.8 | 120 | 0.01656 | 0.0000432 | 0.33912
2 x Unnamed | STEEL/S235JR | 350 | L9 | 1 |  | 0.3 | 48.9 | 116 | 0.016032 | 0.00004176 | 0.327816
Unnamed | STEEL/S235JR | 350 | L8 | 1 |  | 0.3 | 48.9 | 116 | 0.016032 | 0.00004176 | 0.327816
Unnamed | STEEL/S235JR | 350 | L10 | 1 |  | 0.3 | 48.9 | 116 | 0.016032 | 0.00004176 | 0.327816

# IfcBeam: PL60*8 (177)
In: Undefined
Description: PL60*8
Tekla Commun - Finition: GRENAILLE-PEINT; Profil: PL60*8; sets with these values: 2
Tekla Quantités - Volume: 0 m3; Surface supérieure totale: 0 m2; Surface nette: 0 m2; Hauteur: 60 mm; Largeur: 8 mm; sets with these values: 2
Pset_BeamCommon - LoadBearing: no
Name | Material | Repère de pièce = Reference | Repère d'assemblage | Phase | Nom | Poids (kg) | Surface par tonne (m2) | Longueur (mm) = Length (mm) | OuterSurfaceArea (m2) | NetVolume (m3) | NetWeight (kg)
12 x CALE | STEEL/E24-2 | Y2 | Y2 | 3 | CALE | 0.2 | 40.3 | 60 | 0.00912 | 0.0000288 | 0.22608
30 x CALE | STEEL/E24-2 | Y2 | Y2 | 2 | CALE | 0.2 | 40.3 | 60 | 0.00912 | 0.0000288 | 0.22608
2 x Unnamed | STEEL/S235JR | 801 | P123 | 1 |  | 0.9 | 37.4 | 200 | 0.02816 | 0.000096 | 0.7536
133 x CALE | STEEL/E24-2 | Y2 | Y2 | 1 | CALE | 0.2 | 40.3 | 60 | 0.00912 | 0.0000288 | 0.22608

# IfcBeam: PL6000*180 (3)
In: Undefined
Description: PL6000*180; Material: CONCRETE/BETON COURANT
Tekla Commun - Phase: 10; Profil: PL6000*180; Nom: PREFA; sets with these values: 2
Tekla Quantités - Hauteur: 6000 mm; Largeur: 180 mm; sets with these values: 2
Pset_BeamCommon - LoadBearing: no
Name | Repère de pièce = Repère d'assemblage = Reference | Poids (kg) | Volume (m3) | Surface supérieure totale (m2) | Surface par tonne (m2) | Surface nette (m2) | Longueur (mm) = Length (mm) | OuterSurfaceArea (m2) | NetVolume (m3) | NetWeight (kg)
PREFA | Z12 | 105712 | 50.3 | 8.4 | 5.4 | 578.3 | 46610 | 578.26 | 50.3388 | 105711
PREFA | Z1 | 156946 | 74.7 | 12.6 | 5.4 | 859.5 | 70000 | 859.488 | 74.736 | 156946
PREFA | Z2 | 109855 | 52.3 | 10.6 | 5.7 | 609.9 | 59030 | 609.911 | 52.312 | 109855

# IfcBeam: PL6000*200 (4)
In: Undefined
Description: PL6000*200; Material: CONCRETE/BETON COURANT
Tekla Commun - Phase: 10; Profil: PL6000*200; Nom: PREFA; sets with these values: 2
Tekla Quantités - Largeur: 200 mm; sets with these values: 2
Pset_BeamCommon - LoadBearing: no
Name | Repère de pièce = Repère d'assemblage = Reference | Poids (kg) | Volume (m3) | Surface supérieure totale (m2) | Surface par tonne (m2) | Surface nette (m2) | Hauteur (mm) | Longueur (mm) = Length (mm) | OuterSurfaceArea (m2) | NetVolume (m3) | NetWeight (kg)
PREFA | Z55 | 4501.9 | 2.1 | 0 | 5.4 | 24.1 | 4046.5 | 2680 | 24.1099 | 2.14377 | 4501.92
PREFA | Z56 | 17196.8 | 8.2 | 0 | 5.1 | 87.6 | 3959.7 | 10349.6 | 87.6132 | 8.18896 | 17196.8
PREFA | Z57 | 4842.1 | 2.3 | 0 | 5.4 | 25.8 | 4053.5 | 2880 | 25.8113 | 2.30577 | 4842.12
PREFA | Z52 | 27417.6 | 13.1 | 2.2 | 4.9 | 137.3 | 6000 | 10880 | 137.312 | 13.056 | 27417.6

# IfcBeam: PL6140*200 (4)
In: Undefined
Description: PL6140*200; Material: CONCRETE/BETON COURANT
Tekla Commun - Phase: 10; Profil: PL6140*200; Nom: MACONNERIE; sets with these values: 2
Tekla Quantités - Hauteur: 6140 mm; Largeur: 200 mm; sets with these values: 2
Pset_BeamCommon - LoadBearing: no
Name | Repère de pièce = Repère d'assemblage = Reference | Poids (kg) | Volume (m3) | Surface supérieure totale (m2) | Surface par tonne (m2) | Surface nette (m2) | Longueur (mm) = Length (mm) | OuterSurfaceArea (m2) | NetVolume (m3) | NetWeight (kg)
3 x MACONNERIE | Z35 | 2063 | 0.9 | 0.2 | 6.1 | 12.6 | 800 | 12.6 | 0.9824 | 2063.04
MACONNERIE | Z36 | 4492.5 | 2.1 | 0.4 | 5.4 | 24.5 | 1742.1 | 24.5458 | 2.1393 | 4492.53

# IfcBeam: PL6140*400 (3)
In: Undefined
Description: PL6140*400; Material: CONCRETE/BETON COURANT
Tekla Commun - Phase: 10; Profil: PL6140*400; Nom: MACONNERIE; sets with these values: 2
Tekla Quantités - Hauteur: 6140 mm; Largeur: 400 mm; sets with these values: 2
Pset_BeamCommon - LoadBearing: no
Name | Repère de pièce = Repère d'assemblage = Reference | Poids (kg) | Volume (m3) | Surface supérieure totale (m2) | Surface par tonne (m2) | Surface nette (m2) | Longueur (mm) = Length (mm) | OuterSurfaceArea (m2) | NetVolume (m3) | NetWeight (kg)
2 x MACONNERIE | Z77 | 2063 | 0.9 | 0.2 | 4.9 | 10.1 | 400 | 10.144 | 0.9824 | 2063.04
MACONNERIE | Z78 | 4126.1 | 1.9 | 0.4 | 3.7 | 15.3 | 800 | 15.376 | 1.9648 | 4126.08

# IfcBeam: PL66*3 (92)
In: Undefined
Description: PL66*3; Material: STEEL/E24-2
Tekla Commun - Finition: GRENAILLE-PEINT; Repère de pièce: 1242; Phase: 4; Profil: PL66*3; sets with these values: 2
Tekla Quantités - Poids: 0.1 kg; Volume: 0 m3; Surface supérieure totale: 0 m2; Surface par tonne: 92.6 m2; Surface nette: 0 m2; Hauteur: 66 mm; Largeur: 3 mm; Longueur: 66 mm; sets with these values: 2
Pset_BeamCommon - LoadBearing: no; Reference: 1242
BaseQuantities - Length: 66 mm; OuterSurfaceArea: 0.00950399 m2; NetVolume: 0.000013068 m3; NetWeight: 0.102584 kg
Name | Repère d'assemblage
Unnamed | M18
2 x Unnamed | M21
4 x Unnamed | M19
2 x Unnamed | M22
Unnamed | M17
2 x Unnamed | L79
2 x Unnamed | L78
2 x Unnamed | L77
2 x Unnamed | L76
24 x Unnamed | L72
2 x Unnamed | L75
2 x Unnamed | L74
2 x Unnamed | L73
2 x Unnamed | L71
6 x Unnamed | L70
2 x Unnamed | L65
2 x Unnamed | L64
4 x Unnamed | L62
8 x Unnamed | L61
2 x Unnamed | L63
2 x Unnamed | L60
2 x Unnamed | L59
2 x Unnamed | L58
2 x Unnamed | L57
2 x Unnamed | L69
2 x Unnamed | L68
2 x Unnamed | L67
2 x Unnamed | L66
2 x Unnamed | L56

# IfcBeam: PL70*10 (8)
In: Undefined
Description: PL70*10; Material: STEEL/E24-2
Tekla Commun - Finition: GRENAILLE-PEINT; Repère de pièce: 195; Phase: 2; Profil: PL70*10; Nom: PLAT; sets with these values: 2
Tekla Quantités - Poids: 0.9 kg; Volume: 0 m3; Surface supérieure totale: 0 m2; Surface par tonne: 30.5 m2; Surface nette: 0 m2; Hauteur: 70 mm; Largeur: 10 mm; Longueur: 190 mm; sets with these values: 2
Pset_BeamCommon - LoadBearing: no; Reference: 195
BaseQuantities - Length: 190 mm; OuterSurfaceArea: 0.0318 m2; NetVolume: 0.000133 m3; NetWeight: 1.04405 kg
Name | Repère d'assemblage
PLAT | L35
2 x PLAT | L36
2 x PLAT | L34
2 x PLAT | L37
PLAT | L33

# IfcBeam: PL70*6 (187)
In: Undefined
Description: PL70*6
Tekla Commun - Profil: PL70*6; sets with these values: 2
Tekla Quantités - Volume: 0 m3; Surface supérieure totale: 0 m2; Surface nette: 0 m2; Hauteur: 70 mm; Largeur: 6 mm; sets with these values: 2
Pset_BeamCommon - LoadBearing: no
Name | Material | Finition | Repère de pièce = Reference | Repère d'assemblage | Phase | Poids (kg) | Surface par tonne (m2) | Longueur (mm) = Length (mm) | OuterSurfaceArea (m2) | NetVolume (m3) | NetWeight (kg) | Nom
Unnamed | STEEL/E24-2 | GRENAILLE-PEINT | 332 | S87 | 6 | 0.2 | 49.7 | 70 | 0.01148 | 0.0000294 | 0.23079
Unnamed | STEEL/E24-2 | GRENAILLE-PEINT | 332 | S4 | 6 | 0.2 | 49.7 | 70 | 0.01148 | 0.0000294 | 0.23079
Unnamed | STEEL/E24-2 | GRENAILLE-PEINT | 332 | S3 | 6 | 0.2 | 49.7 | 70 | 0.01148 | 0.0000294 | 0.23079
MONTANT | STEEL/E24-2 | GRENAILLE-PEINT | 328 | M18 | 4 | 0.3 | 48.3 | 115 | 0.01832 | 0.0000483 | 0.379155 | MONTANT
MONTANT | STEEL/E24-2 | GRENAILLE-PEINT | 328 | M17 | 4 | 0.3 | 48.3 | 115 | 0.01832 | 0.0000483 | 0.379155 | MONTANT
28 x ATTACHE | STEEL/S235JR | GALVANISE | 331 | P62 | 2 | 0.3 | 48.8 | 94 | 0.0150854 | 0.000039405 | 0.309329 | ATTACHE
6 x ATTACHE | STEEL/S235JR | GALVANISE | 355 | P72 | 2 | 0.3 | 48.7 | 94 | 0.0150429 | 0.00003933 | 0.30874 | ATTACHE
10 x ATTACHE | STEEL/S235JR | GALVANISE | 331 | P64 | 2 | 0.3 | 48.8 | 94 | 0.0150854 | 0.000039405 | 0.309329 | ATTACHE
10 x ATTACHE | STEEL/S235JR | GALVANISE | 331 | P65 | 2 | 0.3 | 48.8 | 94 | 0.0150854 | 0.000039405 | 0.309329 | ATTACHE
10 x ATTACHE | STEEL/S235JR | GALVANISE | 331 | P63 | 2 | 0.3 | 48.8 | 94 | 0.0150854 | 0.000039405 | 0.309329 | ATTACHE
4 x ATTACHE | STEEL/S235JR | GALVANISE | 355 | P72 | 2 | 0.3 | 48.7 | 94 | 0.0150429 | 0.00003933 | 0.308741 | ATTACHE
28 x ATTACHE | STEEL/S235JR | GALVANISE | 331 | P66 | 2 | 0.3 | 48.8 | 94 | 0.0150854 | 0.000039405 | 0.309329 | ATTACHE
28 x ATTACHE | STEEL/S235JR | GALVANISE | 331 | P67 | 2 | 0.3 | 48.8 | 94 | 0.0150854 | 0.000039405 | 0.309329 | ATTACHE
2 x ATTACHE | STEEL/S235JR | GALVANISE | 355 | P75 | 1 | 0.3 | 48.7 | 94 | 0.0150429 | 0.00003933 | 0.30874 | ATTACHE
4 x ATTACHE | STEEL/S235JR | GALVANISE | 355 | P74 | 1 | 0.3 | 48.7 | 94 | 0.0150429 | 0.00003933 | 0.30874 | ATTACHE
14 x ATTACHE | STEEL/S235JR | GALVANISE | 331 | P71 | 1 | 0.3 | 48.8 | 94 | 0.0150854 | 0.000039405 | 0.309329 | ATTACHE
14 x ATTACHE | STEEL/S235JR | GALVANISE | 355 | P73 | 1 | 0.3 | 48.7 | 94 | 0.0150429 | 0.00003933 | 0.30874 | ATTACHE
8 x ATTACHE | STEEL/S235JR | GALVANISE | 331 | P70 | 1 | 0.3 | 48.8 | 94 | 0.0150854 | 0.000039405 | 0.309329 | ATTACHE
8 x ATTACHE | STEEL/S235JR | GALVANISE | 331 | P69 | 1 | 0.3 | 48.8 | 94 | 0.0150854 | 0.000039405 | 0.309329 | ATTACHE
8 x ATTACHE | STEEL/S235JR | GALVANISE | 331 | P68 | 1 | 0.3 | 48.8 | 94 | 0.0150854 | 0.000039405 | 0.309329 | ATTACHE

# IfcBeam: PL70*8 (4)
In: Undefined
Description: PL70*8; Material: STEEL/E24-2
Tekla Commun - Finition: GRENAILLE-PEINT; Phase: 3; Profil: PL70*8; sets with these values: 2
Tekla Quantités - Volume: 0 m3; Surface supérieure totale: 0 m2; Surface par tonne: 37 m2; Surface nette: 0 m2; Hauteur: 70 mm; Largeur: 8 mm; sets with these values: 2
Pset_BeamCommon - LoadBearing: no
Name | Repère de pièce = Reference | Repère d'assemblage | Nom | Poids (kg) | Longueur (mm) | Length (mm) | OuterSurfaceArea (m2) | NetVolume (m3) | NetWeight (kg)
3 x CV | 743 | W6 | CV | 0.6 | 170 | 169.997 | 0.0276395 | 0.0000951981 | 0.747305
LISSE | 759 | K93 | LISSE | 0.9 | 171.3 | 171.338 | 0.0278487 | 0.0000959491 | 0.7532

# IfcBeam: PL75*8, PLAT
In: Undefined
Description: PL75*8; Material: STEEL/E24-2
Tekla Commun - Finition: GRENAILLE-PEINT; Repère de pièce: 851; Repère d'assemblage: K100; Phase: 1; Profil: PL75*8; Nom: PLAT; sets with these values: 2
Tekla Quantités - Poids: 0.9 kg; Volume: 0 m3; Surface supérieure totale: 0 m2; Surface par tonne: 36.5 m2; Surface nette: 0 m2; Hauteur: 75 mm; Largeur: 8 mm; Longueur: 210 mm; sets with these values: 2
Pset_BeamCommon - LoadBearing: no; Reference: 851
BaseQuantities - Length: 210.044 mm; OuterSurfaceArea: 0.0360673 m2; NetVolume: 0.000126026 m3; NetWeight: 0.989307 kg

# IfcBeam: PL8*220 (171)
In: Undefined
Description: PL8*220; Material: STEEL/S235JR
Tekla Commun - Finition: GALVANISE; Profil: PL8*220; Nom: PLAT; sets with these values: 2
Tekla Quantités - Volume: 0 m3; Surface supérieure totale: 0 m2; Surface nette: 0.1 m2; Hauteur: 220 mm; Largeur: 8 mm; sets with these values: 2
Pset_BeamCommon - LoadBearing: no
Name | Repère de pièce = Reference | Repère d'assemblage | Phase | Poids (kg) | Surface par tonne (m2) | Longueur (mm) = Length (mm) | OuterSurfaceArea (m2) | NetVolume (m3) | NetWeight (kg)
2 x PLAT | 740 | P83 | 2 | 1.6 | 35.2 | 116 | 0.056416 | 0.00020416 | 1.60266
14 x PLAT | 739 | P76 | 2 | 2.1 | 34.7 | 150 | 0.07192 | 0.000264 | 2.0724
2 x PLAT | 739 | P94 | 2 | 2.1 | 34.7 | 150 | 0.07192 | 0.000264 | 2.0724
14 x PLAT | 739 | P62 | 2 | 2.1 | 34.7 | 150 | 0.07192 | 0.000264 | 2.0724
2 x PLAT | 739 | P77 | 2 | 2.1 | 34.7 | 150 | 0.07192 | 0.000264 | 2.0724
PLAT | 740 | P108 | 2 | 1.6 | 35.2 | 116 | 0.056416 | 0.00020416 | 1.60266
PLAT | 740 | P107 | 2 | 1.6 | 35.2 | 116 | 0.056416 | 0.00020416 | 1.60266
PLAT | 740 | P91 | 2 | 1.6 | 35.2 | 116 | 0.056416 | 0.00020416 | 1.60266
PLAT | 740 | P92 | 2 | 1.6 | 35.2 | 116 | 0.056416 | 0.00020416 | 1.60266
PLAT | 740 | P93 | 2 | 1.6 | 35.2 | 116 | 0.056416 | 0.00020416 | 1.60266
5 x PLAT | 739 | P95 | 2 | 2.1 | 34.7 | 150 | 0.07192 | 0.000264 | 2.0724
5 x PLAT | 739 | P63 | 2 | 2.1 | 34.7 | 150 | 0.07192 | 0.000264 | 2.0724
5 x PLAT | 739 | P65 | 2 | 2.1 | 34.7 | 150 | 0.07192 | 0.000264 | 2.0724
5 x PLAT | 739 | P64 | 2 | 2.1 | 34.7 | 150 | 0.07192 | 0.000264 | 2.0724
5 x PLAT | 739 | P72 | 2 | 2.1 | 34.7 | 150 | 0.07192 | 0.000264 | 2.0724
PLAT | 740 | P86 | 2 | 1.6 | 35.2 | 116 | 0.056416 | 0.00020416 | 1.60266
PLAT | 740 | P85 | 2 | 1.6 | 35.2 | 116 | 0.056416 | 0.00020416 | 1.60266
PLAT | 740 | P84 | 2 | 1.6 | 35.2 | 116 | 0.056416 | 0.00020416 | 1.60266
PLAT | 740 | P100 | 2 | 1.6 | 35.2 | 116 | 0.056416 | 0.00020416 | 1.60266
PLAT | 740 | P101 | 2 | 1.6 | 35.2 | 116 | 0.056416 | 0.00020416 | 1.60266
2 x PLAT | 739 | P78 | 2 | 2.1 | 34.7 | 150 | 0.07192 | 0.000264 | 2.0724
2 x PLAT | 739 | P79 | 2 | 2.1 | 34.7 | 150 | 0.07192 | 0.000264 | 2.0724
14 x PLAT | 739 | P96 | 2 | 2.1 | 34.7 | 150 | 0.07192 | 0.000264 | 2.0724
14 x PLAT | 739 | P66 | 2 | 2.1 | 34.7 | 150 | 0.07192 | 0.000264 | 2.0724
14 x PLAT | 739 | P67 | 2 | 2.1 | 34.7 | 150 | 0.07192 | 0.000264 | 2.0724
2 x PLAT | 740 | P103 | 1 | 1.6 | 35.2 | 116 | 0.056416 | 0.00020416 | 1.60266
2 x PLAT | 740 | P106 | 1 | 1.6 | 35.2 | 116 | 0.056416 | 0.00020416 | 1.60266
3 x PLAT | 739 | P99 | 1 | 2.1 | 34.7 | 150 | 0.07192 | 0.000264 | 2.0724
2 x PLAT | 740 | P105 | 1 | 1.6 | 35.2 | 116 | 0.056416 | 0.00020416 | 1.60266
3 x PLAT | 739 | P98 | 1 | 2.1 | 34.7 | 150 | 0.07192 | 0.000264 | 2.0724
2 x PLAT | 740 | P104 | 1 | 1.6 | 35.2 | 116 | 0.056416 | 0.00020416 | 1.60266
3 x PLAT | 739 | P97 | 1 | 2.1 | 34.7 | 150 | 0.07192 | 0.000264 | 2.0724
PLAT | 740 | P75 | 1 | 1.6 | 35.2 | 116 | 0.056416 | 0.00020416 | 1.60266
2 x PLAT | 739 | P74 | 1 | 2.1 | 34.7 | 150 | 0.07192 | 0.000264 | 2.0724
2 x PLAT | 740 | P102 | 1 | 1.6 | 35.2 | 116 | 0.056416 | 0.00020416 | 1.60266
2 x PLAT | 740 | P87 | 1 | 1.6 | 35.2 | 116 | 0.056416 | 0.00020416 | 1.60266
7 x PLAT | 739 | P71 | 1 | 2.1 | 34.7 | 150 | 0.07192 | 0.000264 | 2.0724
7 x PLAT | 739 | P73 | 1 | 2.1 | 34.7 | 150 | 0.07192 | 0.000264 | 2.0724
PLAT | 740 | P90 | 1 | 1.6 | 35.2 | 116 | 0.056416 | 0.00020416 | 1.60266
PLAT | 740 | P89 | 1 | 1.6 | 35.2 | 116 | 0.056416 | 0.00020416 | 1.60266
PLAT | 740 | P88 | 1 | 1.6 | 35.2 | 116 | 0.056416 | 0.00020416 | 1.60266
4 x PLAT | 739 | P70 | 1 | 2.1 | 34.7 | 150 | 0.07192 | 0.000264 | 2.0724
PLAT | 739 | P82 | 1 | 2.1 | 34.7 | 150 | 0.07192 | 0.000264 | 2.0724
PLAT | 739 | P81 | 1 | 2.1 | 34.7 | 150 | 0.07192 | 0.000264 | 2.0724
PLAT | 739 | P80 | 1 | 2.1 | 34.7 | 150 | 0.07192 | 0.000264 | 2.0724
4 x PLAT | 739 | P68 | 1 | 2.1 | 34.7 | 150 | 0.07192 | 0.000264 | 2.0724
4 x PLAT | 739 | P69 | 1 | 2.1 | 34.7 | 150 | 0.07192 | 0.000264 | 2.0724

# IfcBeam: PL80*10, Unnamed
In: Undefined
Description: PL80*10; Material: STEEL/E24-2
Tekla Commun - Finition: GRENAILLE-PEINT; Repère de pièce: 231; Repère d'assemblage: P11; Phase: 1; Profil: PL80*10; sets with these values: 2
Tekla Quantités - Poids: 1.6 kg; Volume: 0 m3; Surface supérieure totale: 0 m2; Surface par tonne: 29.6 m2; Surface nette: 0 m2; Hauteur: 80 mm; Largeur: 10 mm; Longueur: 260 mm; sets with these values: 2
Pset_BeamCommon - LoadBearing: no; Reference: 231
BaseQuantities - Length: 260 mm; OuterSurfaceArea: 0.0484 m2; NetVolume: 0.000208 m3; NetWeight: 1.6328 kg

# IfcBeam: PL80*6, Unnamed
In: Undefined
Description: PL80*6; Material: STEEL/E24-2
Tekla Commun - Finition: GRENAILLE-PEINT; Repère de pièce: 344; Repère d'assemblage: N37; Phase: 1; Profil: PL80*6; sets with these values: 2
Tekla Quantités - Poids: 10.6 kg; Volume: 0 m3; Surface supérieure totale: 0 m2; Surface par tonne: 45.7 m2; Surface nette: 0.5 m2; Hauteur: 80 mm; Largeur: 6 mm; Longueur: 2830 mm; sets with these values: 2
Pset_BeamCommon - LoadBearing: no; Reference: 344
BaseQuantities - Length: 2830 mm; OuterSurfaceArea: 0.48772 m2; NetVolume: 0.0013584 m3; NetWeight: 10.6635 kg

# IfcBeam: PL80*8 (53)
In: Undefined
Description: PL80*8
Tekla Commun - Finition: GRENAILLE-PEINT; Profil: PL80*8; sets with these values: 2
Tekla Quantités - Volume: 0 m3; Surface supérieure totale: 0 m2; Surface nette: 0 m2; Hauteur: 80 mm; Largeur: 8 mm; sets with these values: 2
Pset_BeamCommon - LoadBearing: no
Name | Material | Repère de pièce = Reference | Repère d'assemblage | Phase | Nom | Poids (kg) | Surface par tonne (m2) | Longueur (mm) = Length (mm) | OuterSurfaceArea (m2) | NetVolume (m3) | NetWeight (kg)
2 x SUSPENTE | STEEL/E24-2 | 762 | S10 | 6 | SUSPENTE | 0.9 | 36.4 | 190 | 0.03472 | 0.0001216 | 0.95456
SUSPENTE | STEEL/E24-2 | 762 | S9 | 6 | SUSPENTE | 0.9 | 36.4 | 190 | 0.03472 | 0.0001216 | 0.95456
4 x SUSPENTE | STEEL/E24-2 | 762 | S8 | 6 | SUSPENTE | 0.9 | 36.4 | 190 | 0.03472 | 0.0001216 | 0.95456
3 x SUSPENTE | STEEL/E24-2 | 762 | S7 | 6 | SUSPENTE | 0.9 | 36.4 | 190 | 0.03472 | 0.0001216 | 0.95456
3 x SUSPENTE | STEEL/E24-2 | 762 | S5 | 6 | SUSPENTE | 0.9 | 36.4 | 190 | 0.03472 | 0.0001216 | 0.95456
3 x SUSPENTE | STEEL/E24-2 | 762 | S6 | 6 | SUSPENTE | 0.9 | 36.4 | 190 | 0.03472 | 0.0001216 | 0.95456
SUSPENTE | STEEL/E24-2 | 762 | S4 | 6 | SUSPENTE | 0.9 | 36.4 | 190 | 0.03472 | 0.0001216 | 0.95456
SUSPENTE | STEEL/E24-2 | 762 | S3 | 6 | SUSPENTE | 0.9 | 36.4 | 190 | 0.03472 | 0.0001216 | 0.95456
2 x ATTACHE | STEEL/E24-2 | H44 | H44 | 4 | ATTACHE | 0.6 | 37.2 | 116 | 0.021696 | 0.00007424 | 0.582784
ATTACHE | STEEL/E24-2 | 760 | P130 | 2 | ATTACHE | 0.9 | 36.6 | 161 | 0.029616 | 0.00010304 | 0.808864
ATTACHE | STEEL/E24-2 | 683 | P131 | 2 | ATTACHE | 0.9 | 36.6 | 161 | 0.029616 | 0.00010304 | 0.808864
6 x GOUSSET | STEEL/E24-2 | 726 | B10 | 2 | GOUSSET | 0.3 | 38.2 | 80 | 0.01536 | 0.0000512 | 0.40192
6 x GOUSSET | STEEL/E24-2 | 727 | B10 | 2 | GOUSSET | 0.3 | 38.2 | 80 | 0.01536 | 0.0000512 | 0.40192
2 x GOUSSET | STEEL/E24-2 | 726 | B11 | 2 | GOUSSET | 0.3 | 38.2 | 80 | 0.01536 | 0.0000512 | 0.40192
2 x GOUSSET | STEEL/E24-2 | 727 | B11 | 2 | GOUSSET | 0.3 | 38.2 | 80 | 0.01536 | 0.0000512 | 0.40192
2 x GOUSSET | STEEL/E24-2 | 706 | B6 | 2 | GOUSSET | 0.6 | 37.2 | 120 | 0.0224 | 0.0000768 | 0.60288
Unnamed | STEEL/S235JR | 800 | P123 | 1 |  | 0.9 | 36.4 | 200 | 0.03648 | 0.000128 | 1.0048
2 x Unnamed | STEEL/E24-2 | 676 | L45 | 3 |  | 0.6 | 37 | 130 | 0.02416 | 0.0000832 | 0.65312
4 x Unnamed | STEEL/E24-2 | 676 | L44 | 1 |  | 0.6 | 37 | 130 | 0.02416 | 0.0000832 | 0.65312
4 x Unnamed | STEEL/E24-2 | 676 | L42 | 1 |  | 0.6 | 37 | 130 | 0.02416 | 0.0000832 | 0.65312
2 x Unnamed | STEEL/E24-2 | 676 | L43 | 3 |  | 0.6 | 37 | 130 | 0.02416 | 0.0000832 | 0.65312

# IfcBeam: PL800*400, MACONNERIE
In: Undefined
Description: PL800*400; Material: CONCRETE/BETON COURANT
Tekla Commun - Repère de pièce: Z79; Repère d'assemblage: Z79; Phase: 10; Profil: PL800*400; Nom: MACONNERIE; sets with these values: 2
Tekla Quantités - Poids: 13204.4 kg; Volume: 6.3 m3; Surface supérieure totale: 7.9 m2; Surface par tonne: 3.6 m2; Surface nette: 47.8 m2; Hauteur: 800 mm; Largeur: 400 mm; Longueur: 19649.4 mm; sets with these values: 2
Pset_BeamCommon - LoadBearing: no; Reference: Z79
BaseQuantities - Length: 19649.4 mm; OuterSurfaceArea: 47.7986 m2; NetVolume: 6.28781 m3; NetWeight: 13204.4 kg

# IfcBeam: PL860*200 (2)
In: Undefined
Description: PL860*200; Material: CONCRETE/BETON COURANT
Tekla Commun - Repère de pièce: Z23; Repère d'assemblage: Z23; Phase: 10; Profil: PL860*200; Nom: MACONNERIE; sets with these values: 2
Tekla Quantités - Poids: 576.1 kg; Volume: 0.3 m3; Surface supérieure totale: 0.4 m2; Surface par tonne: 6.5 m2; Surface nette: 3.7 m2; Hauteur: 860 mm; Largeur: 200 mm; Longueur: 1595 mm; sets with these values: 2
Pset_BeamCommon - LoadBearing: no; Reference: Z23
BaseQuantities - Length: 1595 mm; OuterSurfaceArea: 3.7254 m2; NetVolume: 0.27434 m3; NetWeight: 576.114 kg

# IfcBeam: PL9000*200, PREFA
In: Undefined
Description: PL9000*200; Material: CONCRETE/BETON COURANT
Tekla Commun - Repère de pièce: Z53; Repère d'assemblage: Z53; Phase: 10; Profil: PL9000*200; Nom: PREFA; sets with these values: 2
Tekla Quantités - Poids: 274301 kg; Volume: 130.6 m3; Surface supérieure totale: 653.1 m2; Surface par tonne: 4.9 m2; Surface nette: 1338.8 m2; Hauteur: 9000 mm; Largeur: 200 mm; Longueur: 72566.4 mm; sets with these values: 2
Pset_BeamCommon - LoadBearing: no; Reference: Z53
BaseQuantities - Length: 72566.4 mm; OuterSurfaceArea: 1338.82 m2; NetVolume: 130.62 m3; NetWeight: 274301 kg

# IfcBeam: PL96*3 (20)
In: Undefined
Description: PL96*3; Material: STEEL/E24-2
Tekla Commun - Finition: GRENAILLE-PEINT; Repère de pièce: 1243; Phase: 4; Profil: PL96*3; sets with these values: 2
Tekla Quantités - Poids: 0.2 kg; Volume: 0 m3; Surface supérieure totale: 0 m2; Surface par tonne: 90.2 m2; Surface nette: 0 m2; Hauteur: 96 mm; Largeur: 3 mm; Longueur: 96 mm; sets with these values: 2
Pset_BeamCommon - LoadBearing: no; Reference: 1243
BaseQuantities - Length: 96 mm; OuterSurfaceArea: 0.019584 m2; NetVolume: 0.000027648 m3; NetWeight: 0.217037 kg
Name | Repère d'assemblage
16 x Unnamed | E4
4 x Unnamed | E5

# IfcBeam: TUBE-168.3*4.5 (2)
In: Undefined
Description: TUBE-168.3*4.5; Material: STEEL/E24-2
Tekla Commun - Finition: GRENAILLE-PEINT; Repère de pièce: 1362; Repère d'assemblage: B18; Phase: 2; Profil: TUBE-168.3*4.5; Nom: BUTON; sets with these values: 2
Tekla Quantités - Poids: 175.7 kg; Volume: 0 m3; Surface supérieure totale: 0 m2; Surface par tonne: 30.6 m2; Surface nette: 5.3 m2; Hauteur: 160.1 mm; Largeur: 168.3 mm; Longueur: 10334.8 mm; sets with these values: 2
Pset_BeamCommon - LoadBearing: no; Reference: 1362
BaseQuantities - Length: 10334.8 mm; OuterSurfaceArea: 5.37709 m2; NetVolume: 0.022388 m3; NetWeight: 175.746 kg

# IfcBeam: TUBE-C-100*100*3 (10)
In: Undefined
Description: TUBE-C-100*100*3
Tekla Commun - Finition: GRENAILLE-PEINT; Phase: 1; Profil: TUBE-C-100*100*3; sets with these values: 2
Tekla Quantités - Volume: 0 m3; Surface par tonne: 43.1 m2; Hauteur: 100 mm; Largeur: 100 mm; sets with these values: 2
Pset_BeamCommon - LoadBearing: no
Name | Material | Repère de pièce = Reference | Repère d'assemblage | Nom | Poids (kg) | Surface supérieure totale (m2) | Surface nette (m2) | Longueur (mm) | Length (mm) | OuterSurfaceArea (m2) | NetVolume (m3) | NetWeight (kg)
MONTANT | STEEL/S235JR | M12 | M12 | MONTANT | 11.5 | 0 | 0.5 | 1269.6 | 1269.6 | 0.493874 | 0.00147781 | 11.6008
2 x BUTON | STEEL/E24-2 | 972 | B16 | BUTON | 44.8 | 0 | 1.9 | 4965.8 | 4965.81 | 1.9317 | 0.0057802 | 45.3746
LISSE | STEEL/S235JR | 974 | L101 | LISSE | 47.3 | 0.4 | 2.1 | 5248 | 5248 | 2.04147 | 0.00610867 | 47.9531
LISSE | STEEL/S235JR | 976 | L103 | LISSE | 73 | 0.7 | 3.2 | 8089 | 8089 | 3.14662 | 0.0094156 | 73.9124
2 x LISSE | STEEL/S235JR | 975 | L102 | LISSE | 93.7 | 1 | 4.1 | 10390 | 10390 | 4.04171 | 0.012094 | 94.9376
BUTON | STEEL/E24-2 | 971 | B3 | BUTON | 47.7 | 0 | 2.1 | 5290.4 | 5290.44 | 2.05798 | 0.00613547 | 48.1635
BUTON | STEEL/E24-2 | 970 | B2 | BUTON | 46.7 | 0.4 | 2.1 | 5174.4 | 5174.4 | 2.01284 | 0.006023 | 47.2806
BUTON | STEEL/E24-2 | 969 | B1 | BUTON | 53.4 | 0 | 2.5 | 5924.7 | 5924.67 | 2.3047 | 0.00688293 | 54.031

# IfcBeam: TUBE-C-100*100*4 (10)
In: Undefined
Description: TUBE-C-100*100*4; Material: STEEL/E24-2
Tekla Commun - Finition: GRENAILLE-PEINT; Phase: 4; Profil: TUBE-C-100*100*4; Nom: SUPPORT; sets with these values: 2
Tekla Quantités - Volume: 0 m3; Surface supérieure totale: 0 m2; Surface par tonne: 32.6 m2; Hauteur: 100 mm; Largeur: 100 mm; sets with these values: 2
Pset_BeamCommon - LoadBearing: no
Name | Repère de pièce = Reference | Repère d'assemblage | Poids (kg) | Surface nette (m2) | Longueur (mm) = Length (mm) | OuterSurfaceArea (m2) | NetVolume (m3) | NetWeight (kg)
2 x SUPPORT | 1372 | E5 | 22.2 | 0.8 | 1872 | 0.722592 | 0.00287539 | 22.5718
8 x SUPPORT | 1371 | E4 | 15.8 | 0.5 | 1336 | 0.515696 | 0.0020521 | 16.109

# IfcBeam: TUBE-C-120*120*4 (16)
In: Undefined
Description: TUBE-C-120*120*4
Tekla Commun - Profil: TUBE-C-120*120*4; sets with these values: 2
Tekla Quantités - Volume: 0 m3; Surface par tonne: 32.5 m2; Hauteur: 120 mm; Largeur: 120 mm; sets with these values: 2
Pset_BeamCommon - LoadBearing: no
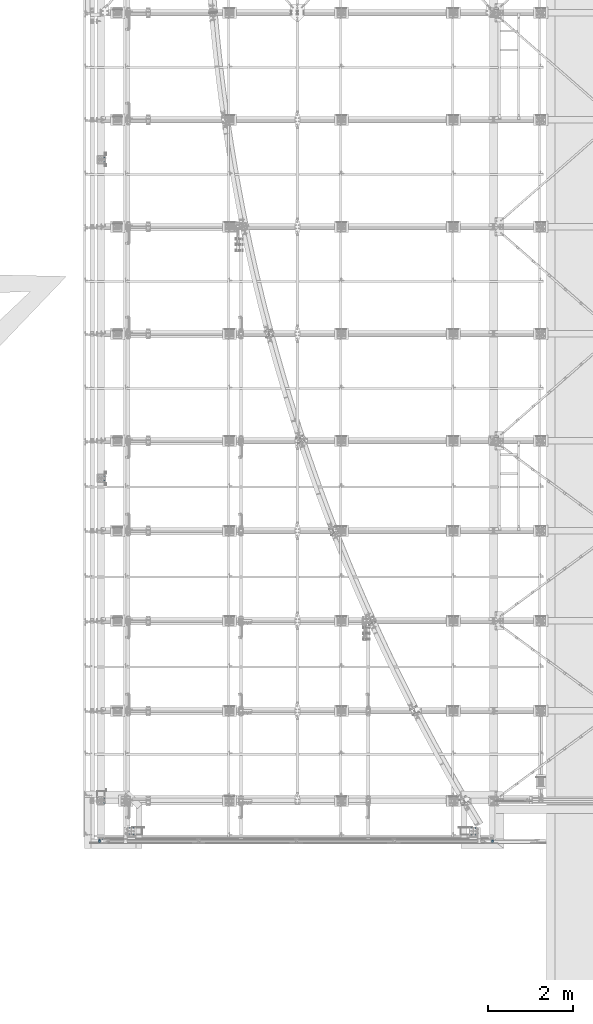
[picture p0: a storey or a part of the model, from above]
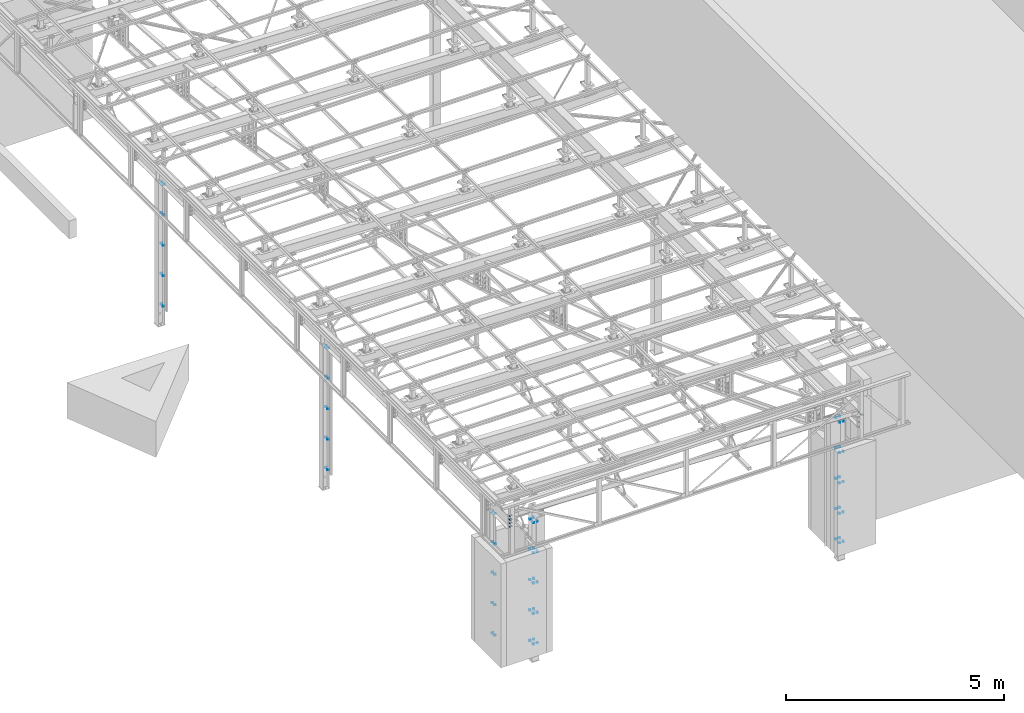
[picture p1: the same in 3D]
Properties of the parts of a building model (IFC2X3), part 5 of 13

# IfcBeam: TUBE-C-120*120*4 (16)
Name | Material | Finition | Repère de pièce = Reference | Repère d'assemblage | Phase | Nom | Poids (kg) | Surface supérieure totale (m2) | Surface nette (m2) | Longueur (mm) | Length (mm) | OuterSurfaceArea (m2) | NetVolume (m3) | NetWeight (kg)
SOLIVE | STEEL/S235JR | GALVANISE | 881 | S2 | 2 | SOLIVE | 16.2 | 0.1 | 0.5 | 1130 | 1130 | 0.52658 | 0.00209728 | 16.4636
10 x SOLIVE | STEEL/S235JR | GALVANISE | 880 | S1 | 2 | SOLIVE | 16.3 | 0.1 | 0.5 | 1135 | 1135 | 0.52891 | 0.00210656 | 16.5365
LISSE | STEEL/S235JR | GRENAILLE-PEINT | 882 | L104 | 1 | LISSE | 101.9 | 1 | 3.4 | 7100 | 7100 | 3.3086 | 0.0131776 | 103.444
BUTON | STEEL/E24-2 | GRENAILLE-PEINT | 879 | B8 | 1 | BUTON | 42.7 | 0 | 1.5 | 2974.4 | 2974.41 | 1.38608 | 0.00552051 | 43.336
BUTON | STEEL/E24-2 | GRENAILLE-PEINT | 878 | B7 | 1 | BUTON | 46 | 0 | 1.5 | 3204.6 | 3204.59 | 1.49334 | 0.00594772 | 46.6896
2 x BUTON | STEEL/E24-2 | GRENAILLE-PEINT | 878 | B7 | 3 | BUTON | 46 | 0 | 1.5 | 3204.6 | 3204.59 | 1.49334 | 0.00594772 | 46.6896

# IfcBeam: TUBE-C-150*150*4 (3)
In: Undefined
Description: TUBE-C-150*150*4
Tekla Commun - Profil: TUBE-C-150*150*4; sets with these values: 2
Tekla Quantités - Volume: 0 m3; Surface par tonne: 32.3 m2; Hauteur: 150 mm; Largeur: 150 mm; sets with these values: 2
Pset_BeamCommon - LoadBearing: no
Name | Material | Finition | Repère de pièce = Reference | Repère d'assemblage | Phase | Nom | Poids (kg) | Surface supérieure totale (m2) | Surface nette (m2) | Longueur (mm) | Length (mm) | OuterSurfaceArea (m2) | NetVolume (m3) | NetWeight (kg)
LISSE | STEEL/S235JR | GALVANISE | 477 | L7 | 4 | LISSE | 152.8 | 1.3 | 5.1 | 8435 | 8435 | 4.94291 | 0.0197042 | 154.678
LISSE | STEEL/S235JR | GALVANISE | 477 | L6 | 4 | LISSE | 152.8 | 1.3 | 5.1 | 8435 | 8435 | 4.94291 | 0.0197042 | 154.678
BUTON | STEEL/E24-2 | GRENAILLE-PEINT | 476 | B5 | 1 | BUTON | 101.9 | 0 | 3.4 | 5619.9 | 5619.89 | 3.29326 | 0.0131281 | 103.055

# IfcBeam: TUBE-C-60*60*3 (71)
In: Undefined
Description: TUBE-C-60*60*3; Material: STEEL/E24-2
Tekla Commun - Finition: GRENAILLE-PEINT; Profil: TUBE-C-60*60*3; sets with these values: 2
Tekla Quantités - Volume: 0 m3; Surface par tonne: 43 m2; Hauteur: 60 mm; Largeur: 60 mm; sets with these values: 2
Pset_BeamCommon - LoadBearing: no
Name | Repère de pièce = Reference | Repère d'assemblage | Phase | Nom | Poids (kg) | Surface supérieure totale (m2) | Surface nette (m2) | Longueur (mm) | Length (mm) | OuterSurfaceArea (m2) | NetVolume (m3) | NetWeight (kg)
2 x LINTEAU | 1172 | L41 | 7 | LINTEAU | 3.6 | 0 | 0.2 | 679 | 679 | 0.155491 | 0.000464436 | 3.64582
LINTEAU | 1171 | L40 | 7 | LINTEAU | 5 | 0.1 | 0.2 | 934 | 934 | 0.213886 | 0.000638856 | 5.01502
LINTEAU | 1169 | L38 | 7 | LINTEAU | 4.6 | 0.1 | 0.2 | 874 | 874 | 0.200146 | 0.000597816 | 4.69286
LINTEAU | 1170 | L39 | 7 | LINTEAU | 4.6 | 0.1 | 0.2 | 874 | 874 | 0.200146 | 0.000597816 | 4.69286
POTEAUX | 1168 | P53 | 7 | POTEAUX | 17.4 | 0 | 0.8 | 3264 | 3263.96 | 0.747447 | 0.00223255 | 17.5255
POTEAUX | 1167 | P52 | 7 | POTEAUX | 19.9 | 0 | 0.8 | 3721.3 | 3721.29 | 0.852175 | 0.00254536 | 19.9811
3 x CV | 1173 | W6 | 3 | CV | 9 | 0 | 0.3 | 1678.9 | 1678.95 | 0.38448 | 0.0011484 | 9.01495
LISSE | 1176 | L46 | 3 | LISSE | 9 | 0 | 0.3 | 1682 | 1682.04 | 0.385187 | 0.00115052 | 9.03155
Unnamed | 1180 | N49 | 2 |  | 11.1 | 0 | 0.5 | 2073 | 2073 | 0.474717 | 0.00141793 | 11.1308
Unnamed | 1179 | N46 | 2 |  | 6 | 0 | 0.3 | 1100 | 1100 | 0.2519 | 0.0007524 | 5.90634
LISSE | 1181 | N46 | 2 | LISSE | 13.3 | 0.2 | 0.6 | 2503.5 | 2503.5 | 0.573302 | 0.00171239 | 13.4423
3 x BUTON | 1182 | B10 | 2 | BUTON | 13.5 | 0 | 0.6 | 2520.7 | 2520.67 | 0.577233 | 0.00172414 | 13.5345
BUTON | 1183 | B11 | 2 | BUTON | 13.1 | 0 | 0.6 | 2470.7 | 2470.67 | 0.565783 | 0.00168994 | 13.266
LISSE | 1174 | L45 | 3 | LISSE | 6.2 | 0 | 0.3 | 1165 | 1165 | 0.266785 | 0.00079686 | 6.25535
4 x Unnamed | 1177 | N43 | 3 |  | 12.3 | 0.1 | 0.6 | 2303 | 2303 | 0.527387 | 0.00157525 | 12.3657
2 x Unnamed | 1177 | N40 | 3 |  | 12.3 | 0.1 | 0.6 | 2303 | 2303 | 0.527387 | 0.00157525 | 12.3657
4 x LISSE | 1184 | L47 | 3 | LISSE | 12.1 | 0.1 | 0.5 | 2287 | 2287 | 0.523723 | 0.00156431 | 12.2798
2 x Unnamed | 1178 | N48 | 3 |  | 11 | 0.1 | 0.5 | 2063 | 2063 | 0.472427 | 0.00141109 | 11.0771
2 x Unnamed | 1177 | N39 | 1 |  | 12.3 | 0.1 | 0.6 | 2303 | 2303 | 0.527387 | 0.00157525 | 12.3657
LISSE | 1175 | N39 | 1 | LISSE | 7.7 | 0 | 0.3 | 1415 | 1415 | 0.324035 | 0.00096786 | 7.5977
4 x Unnamed | 1177 | N41 | 1 |  | 12.3 | 0.1 | 0.6 | 2303 | 2303 | 0.527387 | 0.00157525 | 12.3657
8 x LISSE | 1184 | L47 | 1 | LISSE | 12.1 | 0.1 | 0.5 | 2287 | 2287 | 0.523723 | 0.00156431 | 12.2798
4 x Unnamed | 1178 | N47 | 1 |  | 11 | 0.1 | 0.5 | 2063 | 2063 | 0.472427 | 0.00141109 | 11.0771
2 x Unnamed | 1177 | N38 | 1 |  | 12.3 | 0.1 | 0.6 | 2303 | 2303 | 0.527387 | 0.00157525 | 12.3657
LISSE | 1175 | N38 | 1 | LISSE | 7.7 | 0 | 0.3 | 1415 | 1415 | 0.324035 | 0.00096786 | 7.5977
2 x LISSE | 1174 | L44 | 1 | LISSE | 6.2 | 0 | 0.3 | 1165 | 1165 | 0.266785 | 0.00079686 | 6.25535
2 x LISSE | 1174 | L42 | 1 | LISSE | 6.2 | 0 | 0.3 | 1165 | 1165 | 0.266785 | 0.00079686 | 6.25535
LISSE | 1174 | L43 | 3 | LISSE | 6.2 | 0 | 0.3 | 1165 | 1165 | 0.266785 | 0.00079686 | 6.25535
2 x LISSE | 1185 | L48 | 2 | LISSE | 12.1 | 0.1 | 0.5 | 2275.5 | 2275.5 | 0.521089 | 0.00155644 | 12.2181
2 x LISSE | 1184 | L47 | 2 | LISSE | 12.1 | 0.1 | 0.5 | 2287 | 2287 | 0.523723 | 0.00156431 | 12.2798
2 x Unnamed | 1178 | N49 | 2 |  | 11 | 0.1 | 0.5 | 2063 | 2063 | 0.472427 | 0.00141109 | 11.0771
Unnamed | 1177 | N46 | 2 |  | 12.3 | 0.1 | 0.6 | 2303 | 2303 | 0.527387 | 0.00157525 | 12.3657
2 x Unnamed | 1177 | N44 | 2 |  | 12.3 | 0.1 | 0.6 | 2303 | 2303 | 0.527387 | 0.00157525 | 12.3657
2 x Unnamed | 1177 | N45 | 2 |  | 12.3 | 0.1 | 0.6 | 2303 | 2303 | 0.527387 | 0.00157525 | 12.3657
2 x Unnamed | 1177 | N42 | 1 |  | 12.3 | 0.1 | 0.6 | 2303 | 2303 | 0.527387 | 0.00157525 | 12.3657

# IfcBeam: TUBE-C-70*70*3 (65)
In: Undefined
Description: TUBE-C-70*70*3
Tekla Commun - Finition: GRENAILLE-PEINT; Profil: TUBE-C-70*70*3; sets with these values: 2
Tekla Quantités - Volume: 0 m3; Surface par tonne: 42.8 m2; Hauteur: 70 mm; Largeur: 70 mm; sets with these values: 2
Pset_BeamCommon - LoadBearing: no
Name | Material | Repère de pièce = Reference | Repère d'assemblage | Phase | Nom | Poids (kg) | Surface supérieure totale (m2) | Surface nette (m2) | Longueur (mm) | Length (mm) | OuterSurfaceArea (m2) | NetVolume (m3) | NetWeight (kg)
3 x LISSE | STEEL/E24-2 | 929 | L110 | 7 | LISSE | 7.2 | 0.1 | 0.3 | 1144 | 1144 | 0.307736 | 0.000919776 | 7.22024
LISSE | STEEL/E24-2 | 930 | L109 | 7 | LISSE | 12.7 | 0.1 | 0.6 | 2021.1 | 2021.13 | 0.543684 | 0.00162499 | 12.7562
2 x MONTANT | STEEL/E24-2 | 913 | M20 | 4 | MONTANT | 14.7 | 0 | 0.6 | 2342.2 | 2342.17 | 0.630043 | 0.0018831 | 14.7823
MONTANT | STEEL/E24-2 | 911 | M21 | 4 | MONTANT | 8.2 | 0 | 0.3 | 1308.7 | 1308.71 | 0.352044 | 0.00104877 | 8.23283
MONTANT | STEEL/E24-2 | 914 | M21 | 4 | MONTANT | 2.6 | 0 | 0.1 | 417 | 417 | 0.112173 | 0.000335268 | 2.63185
MONTANT | STEEL/E24-2 | 909 | M18 | 4 | MONTANT | 10.8 | 0 | 0.5 | 1722.2 | 1722.2 | 0.463272 | 0.00138465 | 10.8695
2 x MONTANT | STEEL/E24-2 | 910 | M19 | 4 | MONTANT | 24.2 | 0.4 | 1.1 | 3850 | 3850 | 1.03565 | 0.0030954 | 24.2989
MONTANT | STEEL/E24-2 | 912 | M22 | 4 | MONTANT | 8.2 | 0 | 0.3 | 1308.7 | 1308.71 | 0.352044 | 0.00104877 | 8.23283
MONTANT | STEEL/E24-2 | 914 | M22 | 4 | MONTANT | 2.6 | 0 | 0.1 | 417 | 417 | 0.112173 | 0.000335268 | 2.63185
MONTANT | STEEL/E24-2 | 909 | M17 | 4 | MONTANT | 10.8 | 0 | 0.5 | 1722.2 | 1722.2 | 0.463272 | 0.00138465 | 10.8695
2 x LISSE | STEEL/E24-2 | 908 | L18 | 4 | LISSE | 10.3 | 0 | 0.3 | 1648 | 1648 | 0.443312 | 0.00126871 | 9.95939
2 x LISSE | STEEL/E24-2 | 907 | L18 | 4 | LISSE | 25.1 | 0.4 | 1.1 | 4000 | 4000 | 1.076 | 0.00315972 | 24.8038
2 x LISSE | STEEL/E24-2 | 905 | L19 | 4 | LISSE | 4.6 | 0 | 0.2 | 738 | 738 | 0.198522 | 0.000537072 | 4.21602
2 x LISSE | STEEL/E24-2 | 907 | L19 | 4 | LISSE | 25.1 | 0.4 | 1.1 | 4000 | 4000 | 1.076 | 0.00315972 | 24.8038
LISSE | STEEL/E24-2 | 928 | L79 | 4 | LISSE | 16.4 | 0.2 | 0.6 | 2606.5 | 2606.55 | 0.701162 | 0.00209567 | 16.451
LISSE | STEEL/E24-2 | 927 | L78 | 4 | LISSE | 16 | 0.2 | 0.6 | 2540.1 | 2540.05 | 0.683273 | 0.0020422 | 16.0313
LISSE | STEEL/E24-2 | 926 | L77 | 4 | LISSE | 15.2 | 0.2 | 0.6 | 2419 | 2418.95 | 0.650698 | 0.00194484 | 15.267
LISSE | STEEL/E24-2 | 925 | L76 | 4 | LISSE | 16.4 | 0.2 | 0.6 | 2606.5 | 2606.55 | 0.701162 | 0.00209567 | 16.451
12 x LISSE | STEEL/E24-2 | 921 | L72 | 4 | LISSE | 15.6 | 0.2 | 0.6 | 2506.5 | 2506.55 | 0.674262 | 0.00201527 | 15.8198
LISSE | STEEL/E24-2 | 924 | L75 | 4 | LISSE | 15.2 | 0.2 | 0.6 | 2423.9 | 2423.95 | 0.652042 | 0.00194886 | 15.2985
LISSE | STEEL/E24-2 | 923 | L74 | 4 | LISSE | 15.2 | 0.2 | 0.6 | 2423.9 | 2423.95 | 0.652042 | 0.00194886 | 15.2985
LISSE | STEEL/E24-2 | 922 | L73 | 4 | LISSE | 15.2 | 0.2 | 0.6 | 2437.1 | 2437.05 | 0.655566 | 0.00195939 | 15.3812
LISSE | STEEL/E24-2 | 920 | L71 | 4 | LISSE | 13.6 | 0.2 | 0.6 | 2186.5 | 2186.5 | 0.588169 | 0.00175795 | 13.7999
3 x LISSE | STEEL/E24-2 | 919 | L70 | 4 | LISSE | 14.2 | 0.2 | 0.6 | 2266.5 | 2266.55 | 0.609702 | 0.00182231 | 14.3051
LISSE | STEEL/E24-2 | 906 | L65 | 4 | LISSE | 33.6 | 0.4 | 1.5 | 5348.1 | 5348.06 | 1.43863 | 0.00429984 | 33.7537
LISSE | STEEL/E24-2 | 904 | L64 | 4 | LISSE | 30.9 | 0.4 | 1.5 | 4916.1 | 4916.06 | 1.32242 | 0.00395251 | 31.0272
2 x LISSE | STEEL/E24-2 | 902 | L62 | 4 | LISSE | 34.9 | 0.4 | 1.6 | 5551.9 | 5551.94 | 1.49347 | 0.00446376 | 35.0405
4 x LISSE | STEEL/E24-2 | 901 | L61 | 4 | LISSE | 32.6 | 0.4 | 1.5 | 5184 | 5184 | 1.3945 | 0.00416794 | 32.7183
LISSE | STEEL/E24-2 | 903 | L63 | 4 | LISSE | 30.2 | 0.4 | 1.2 | 4816.1 | 4816.06 | 1.29552 | 0.00387211 | 30.3961
LISSE | STEEL/E24-2 | 900 | L60 | 4 | LISSE | 30.9 | 0.4 | 1.5 | 4944 | 4944 | 1.32994 | 0.00397498 | 31.2036
LISSE | STEEL/E24-2 | 899 | L59 | 4 | LISSE | 29.5 | 0.4 | 1.2 | 4704 | 4704 | 1.26538 | 0.00378202 | 29.6888
LISSE | STEEL/E24-2 | 898 | L58 | 4 | LISSE | 29.9 | 0.4 | 1.2 | 4762.5 | 4762.5 | 1.28111 | 0.00382905 | 30.058
LISSE | STEEL/E24-2 | 918 | L69 | 4 | LISSE | 13.9 | 0.2 | 0.6 | 2211.5 | 2211.5 | 0.594894 | 0.00177805 | 13.9577
LISSE | STEEL/E24-2 | 917 | L68 | 4 | LISSE | 15 | 0.2 | 0.6 | 2386.5 | 2386.5 | 0.641969 | 0.00191875 | 15.0622
LISSE | STEEL/E24-2 | 916 | L67 | 4 | LISSE | 15.4 | 0.2 | 0.6 | 2458 | 2458 | 0.661202 | 0.00197623 | 15.5134
LISSE | STEEL/E24-2 | 897 | L57 | 4 | LISSE | 31.6 | 0.4 | 1.5 | 5025.5 | 5025.5 | 1.35186 | 0.0040405 | 31.7179
LISSE | STEEL/E24-2 | 915 | L66 | 4 | LISSE | 15.4 | 0.2 | 0.6 | 2470 | 2470 | 0.66443 | 0.00198588 | 15.5892
LISSE | STEEL/E24-2 | 896 | L56 | 4 | LISSE | 19 | 0.2 | 0.8 | 3027.5 | 3027.5 | 0.814397 | 0.00243411 | 19.1078
CV | STEEL/E24-2 | 895 | W7 | 3 | CV | 25.1 | 0 | 1.1 | 3989.3 | 3989.28 | 1.07312 | 0.00320738 | 25.1779
LISSE | STEEL/S235JR | 894 | L105 | 1 | LISSE | 21.6 | 0 | 1 | 3436.7 | 3436.69 | 0.924468 | 0.00276309 | 21.6903

# IfcBeam: TUBE-C-80*80*3 (36)
In: Undefined
Description: TUBE-C-80*80*3; Material: STEEL/E24-2
Tekla Commun - Finition: GRENAILLE-PEINT; Profil: TUBE-C-80*80*3; sets with these values: 2
Tekla Quantités - Volume: 0 m3; Surface par tonne: 42.8 m2; Hauteur: 80 mm; Largeur: 80 mm; sets with these values: 2
Pset_BeamCommon - LoadBearing: no
Name | Repère de pièce = Reference | Repère d'assemblage | Phase | Nom | Poids (kg) | Surface supérieure totale (m2) | Surface nette (m2) | Longueur (mm) | Length (mm) | OuterSurfaceArea (m2) | NetVolume (m3) | NetWeight (kg)
LISSE | 462 | S87 | 6 | LISSE | 3.6 | 0 | 0.1 | 502 | 502 | 0.155118 | 0.000426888 | 3.35107
LISSE | 463 | S88 | 6 | LISSE | 4.6 | 0 | 0.2 | 632 | 632 | 0.195288 | 0.000547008 | 4.29401
SUSPENTE | 468 | S88 | 6 | SUSPENTE | 3.4 | 0 | 0.1 | 477.6 | 477.635 | 0.147589 | 0.000403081 | 3.16419
SUSPENTE | 468 | S87 | 6 | SUSPENTE | 3.4 | 0 | 0.1 | 477.6 | 477.635 | 0.147589 | 0.000403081 | 3.16419
2 x SUSPENTE | 469 | S10 | 6 | SUSPENTE | 4.2 | 0 | 0.2 | 585.5 | 585.465 | 0.180909 | 0.000539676 | 4.23646
SUSPENTE | 469 | S9 | 6 | SUSPENTE | 4.2 | 0 | 0.2 | 585.5 | 585.465 | 0.180909 | 0.000539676 | 4.23646
4 x SUSPENTE | 467 | S8 | 6 | SUSPENTE | 4.2 | 0 | 0.2 | 585.5 | 585.465 | 0.180909 | 0.000539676 | 4.23646
3 x SUSPENTE | 466 | S5 | 6 | SUSPENTE | 3.6 | 0 | 0.2 | 492.2 | 492.185 | 0.152085 | 0.000453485 | 3.55986
3 x SUSPENTE | 467 | S7 | 6 | SUSPENTE | 4.2 | 0 | 0.2 | 585.5 | 585.465 | 0.180909 | 0.000539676 | 4.23646
3 x SUSPENTE | 466 | S6 | 6 | SUSPENTE | 3.6 | 0 | 0.2 | 492.2 | 492.185 | 0.152085 | 0.000453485 | 3.55986
SUSPENTE | 465 | S4 | 6 | SUSPENTE | 2.8 | 0 | 0.1 | 386.8 | 386.835 | 0.119532 | 0.000356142 | 2.79571
SUSPENTE | 465 | S3 | 6 | SUSPENTE | 2.8 | 0 | 0.1 | 386.8 | 386.835 | 0.119532 | 0.000356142 | 2.79571
LISSE | 470 | L82 | 6 | LISSE | 36.3 | 0.4 | 1.6 | 5029 | 5029 | 1.55396 | 0.0046468 | 36.4773
LISSE | 471 | L83 | 6 | LISSE | 34.6 | 0.4 | 1.5 | 4796.5 | 4796.5 | 1.48212 | 0.00443197 | 34.7909
2 x LISSE | 472 | L84 | 6 | LISSE | 30.6 | 0.4 | 1.5 | 4244 | 4244 | 1.3114 | 0.00392146 | 30.7834
LISSE | 474 | L86 | 6 | LISSE | 37.1 | 0.4 | 1.6 | 5149 | 5149 | 1.59104 | 0.00475768 | 37.3478
LISSE | 464 | L81 | 6 | LISSE | 28.1 | 0.4 | 1.2 | 3889 | 3889 | 1.2017 | 0.00359344 | 28.2085
2 x LISSE | 473 | L85 | 6 | LISSE | 36.3 | 0.4 | 1.6 | 5046.5 | 5046.5 | 1.55937 | 0.00466297 | 36.6043
LISSE | 475 | L87 | 6 | LISSE | 35 | 0.4 | 1.6 | 4849 | 4849 | 1.49834 | 0.00448048 | 35.1717
BUTON | 461 | B15 | 1 | BUTON | 28 | 0 | 1.2 | 3883.6 | 3883.62 | 1.20004 | 0.00358764 | 28.163
BUTON | 460 | B14 | 1 | BUTON | 28.5 | 0 | 1.2 | 3956.1 | 3956.08 | 1.22243 | 0.00365541 | 28.695
BUTON | 459 | B13 | 1 | BUTON | 6.2 | 0 | 0.3 | 843.5 | 843.451 | 0.260626 | 0.000779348 | 6.11788
BUTON | 458 | B12 | 1 | BUTON | 13.3 | 0 | 0.6 | 1857.2 | 1857.19 | 0.573872 | 0.00171604 | 13.4709
BUTON | 457 | B4 | 1 | BUTON | 42.4 | 0.4 | 1.9 | 5874.4 | 5874.4 | 1.81519 | 0.00539712 | 42.3674

# IfcBeam: TUBE-C-90*90*3 (37)
In: Undefined
Description: TUBE-C-90*90*3
Tekla Commun - Finition: GRENAILLE-PEINT; Profil: TUBE-C-90*90*3; sets with these values: 2
Tekla Quantités - Volume: 0 m3; Surface par tonne: 42.7 m2; Hauteur: 90 mm; Largeur: 90 mm; sets with these values: 2
Pset_BeamCommon - LoadBearing: no
Name | Material | Repère de pièce = Reference | Repère d'assemblage | Phase | Nom | Poids (kg) | Surface supérieure totale (m2) | Surface nette (m2) | Longueur (mm) | Length (mm) | OuterSurfaceArea (m2) | NetVolume (m3) | NetWeight (kg)
LISSE | STEEL/S235JR | 977 | L106 | 3 | LISSE | 1.1 | 0 | 0 | 139.5 | 139.462 | 0.0486721 | 0.00013986 | 1.0979
2 x BUTON | STEEL/E24-2 | 978 | B6 | 2 | BUTON | 21 | 0 | 0.8 | 2565.2 | 2565.25 | 0.895272 | 0.00267812 | 21.0232
4 x BUTON | STEEL/E24-2 | 979 | B9 | 2 | BUTON | 22.4 | 0 | 1 | 2741.5 | 2741.5 | 0.956784 | 0.00286213 | 22.4677
LISSE | STEEL/S235JR | 981 | L22 | 3 | LISSE | 69.7 | 0 | 3.1 | 8525 | 8525 | 2.97522 | 0.00888862 | 69.7757
LISSE | STEEL/S235JR | 987 | L106 | 3 | LISSE | 91.9 | 1 | 4 | 11244 | 11244 | 3.92416 | 0.0117387 | 92.1491
LISSE | STEEL/S235JR | 989 | L96 | 1 | LISSE | 94.5 | 1 | 4.1 | 11569 | 11569 | 4.03758 | 0.012078 | 94.8126
LISSE | STEEL/S235JR | 982 | L23 | 1 | LISSE | 69.3 | 0 | 3.1 | 8483.7 | 8483.69 | 2.96081 | 0.0088455 | 69.4372
2 x LISSE | STEEL/S235JR | 991 | L98 | 1 | LISSE | 95.3 | 1 | 4.1 | 11659 | 11659 | 4.06899 | 0.012172 | 95.5502
2 x LISSE | STEEL/S235JR | 981 | L22 | 1 | LISSE | 69.7 | 0 | 3.1 | 8525 | 8525 | 2.97522 | 0.00888862 | 69.7757
LISSE | STEEL/S235JR | 992 | L108 | 3 | LISSE | 95.3 | 1 | 4.1 | 11659 | 11659 | 4.06899 | 0.012172 | 95.5502
LISSE | STEEL/S235JR | 997 | L24 | 3 | LISSE | 69.7 | 0 | 3.1 | 8525 | 8525 | 2.97522 | 0.00888862 | 69.7757
2 x LISSE | STEEL/S235JR | 980 | L21 | 1 | LISSE | 69.7 | 0 | 3.1 | 8525 | 8525 | 2.97522 | 0.00888862 | 69.7757
2 x LISSE | STEEL/S235JR | 990 | L97 | 1 | LISSE | 95.3 | 1 | 4.1 | 11659 | 11659 | 4.06899 | 0.012172 | 95.5502
3 x LISSE | STEEL/S235JR | 986 | L94 | 1 | LISSE | 84.9 | 1 | 3.7 | 10390 | 10390 | 3.62611 | 0.0108472 | 85.1502
LISSE | STEEL/S235JR | 990 | L107 | 3 | LISSE | 95.3 | 1 | 4.1 | 11659 | 11659 | 4.06899 | 0.012172 | 95.5502
LISSE | STEEL/S235JR | 980 | L21 | 3 | LISSE | 69.7 | 0 | 3.1 | 8525 | 8525 | 2.97522 | 0.00888862 | 69.7757
LISSE | STEEL/S235JR | 996 | L100 | 1 | LISSE | 43.3 | 0 | 1.9 | 5295.6 | 5295.64 | 1.84818 | 0.00552865 | 43.3999
LISSE | STEEL/S235JR | 998 | L55 | 1 | LISSE | 94.5 | 1 | 4.1 | 11546 | 11546 | 4.02954 | 0.012054 | 94.6237
LISSE | STEEL/S235JR | 995 | L99 | 1 | LISSE | 42.4 | 0.4 | 1.9 | 5190 | 5190 | 1.81131 | 0.00541836 | 42.5341
LISSE | STEEL/S235JR | 988 | L95 | 1 | LISSE | 66.9 | 0.7 | 2.9 | 8182 | 8182 | 2.85552 | 0.00854201 | 67.0548
2 x LISSE | STEEL/S235JR | 985 | L93 | 1 | LISSE | 62.4 | 0.7 | 2.7 | 7634 | 7634 | 2.66427 | 0.0079699 | 62.5637
LISSE | STEEL/S235JR | 994 | L88 | 1 | LISSE | 48.1 | 0.4 | 2.1 | 5890 | 5890 | 2.05561 | 0.00614916 | 48.2709
LISSE | STEEL/S235JR | 994 | L90 | 1 | LISSE | 48.1 | 0.4 | 2.1 | 5890 | 5890 | 2.05561 | 0.00614916 | 48.2709
LISSE | STEEL/S235JR | 993 | L89 | 1 | LISSE | 48.7 | 0.4 | 2.1 | 5955 | 5955 | 2.07829 | 0.00621702 | 48.8036
LISSE | STEEL/S235JR | 984 | L92 | 1 | LISSE | 54.5 | 0.7 | 2.5 | 6670 | 6670 | 2.32783 | 0.00696348 | 54.6633
LISSE | STEEL/S235JR | 983 | L91 | 1 | LISSE | 90.6 | 1 | 4 | 11090 | 11090 | 3.87041 | 0.011578 | 90.887

# IfcBeam: UPF-100*50*4 (392)
In: Undefined
Description: UPF-100*50*4
Tekla Commun - Profil: UPF-100*50*4; sets with these values: 2
Tekla Quantités - Volume: 0 m3; Hauteur: 100 mm; sets with these values: 2
Pset_BeamCommon - LoadBearing: no
Name | Material | Finition | Repère de pièce = Reference | Repère d'assemblage | Phase | Nom | Poids (kg) | Surface supérieure totale (m2) | Surface par tonne (m2) | Surface nette (m2) | Largeur (mm) | Longueur (mm) | Length (mm) | OuterSurfaceArea (m2) | NetVolume (m3) | NetWeight (kg)
CHEVETRE | STEEL/E24-2 | GRENAILLE-PEINT | 1148 | U7 | 4 | CHEVETRE | 6 | 0 | 65.3 | 0.3 | 50 | 1000 | 999.998 | 0.393535 | 0.000767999 | 6.02879
2 x CHEVETRE | STEEL/E24-2 | GRENAILLE-PEINT | 1147 | U7 | 4 | CHEVETRE | 15.6 | 0 | 65.1 | 1 | 50 | 2605 | 2605 | 1.0227 | 0.00200064 | 15.705
2 x CHEVETRE | STEEL/E24-2 | GRENAILLE-PEINT | 1145 | U6 | 2 | CHEVETRE | 4.8 | 0 | 65.3 | 0.3 | 50 | 800 | 799.999 | 0.315136 | 0.000614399 | 4.82304
4 x CHEVETRE | STEEL/S235JR | GRENAILLE-PEINT | U8 | U8 | 3 | CHEVETRE | 3 | 0 | 65.5 | 0.2 | 50 | 490 | 489.996 | 0.193614 | 0.000376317 | 2.95409
2 x CHEVETRE | STEEL/S235JR | GRENAILLE-PEINT | U9 | U9 | 3 | CHEVETRE | 14.4 | 0 | 65.1 | 0.8 | 50 | 2390 | 2390 | 0.938416 | 0.00183552 | 14.4088
2 x CHEVETRE | STEEL/S235JR | GRENAILLE-PEINT | U10 | U10 | 3 | CHEVETRE | 14.4 | 0 | 65.1 | 0.8 | 50 | 2390 | 2390 | 0.938416 | 0.00183552 | 14.4088
2 x CHEVETRE | STEEL/S235JR | GRENAILLE-PEINT | 1155 | U11 | 3 | CHEVETRE | 1.7 | 0 | 65.9 | 0.1 | 50 | 300 | 300 | 0.119136 | 0.0002304 | 1.80864
4 x CHEVETRE | STEEL/S235JR | GRENAILLE-PEINT | 1156 | U11 | 3 | CHEVETRE | 14.4 | 0 | 65.1 | 0.8 | 50 | 2390 | 2390 | 0.938416 | 0.00183552 | 14.4088
4 x CHEVETRE | STEEL/S235JR | GRENAILLE-PEINT | 1155 | U12 | 3 | CHEVETRE | 1.7 | 0 | 65.9 | 0.1 | 50 | 300 | 300 | 0.119136 | 0.0002304 | 1.80864
8 x CHEVETRE | STEEL/S235JR | GRENAILLE-PEINT | 1157 | U12 | 3 | CHEVETRE | 14.7 | 0 | 65.1 | 1 | 50 | 2420 | 2420 | 0.950176 | 0.00185856 | 14.5897
2 x CHEVETRE | STEEL/S235JR | GRENAILLE-PEINT | 1157 | U13 | 3 | CHEVETRE | 14.7 | 0 | 65.1 | 1 | 50 | 2420 | 2420 | 0.950176 | 0.00185856 | 14.5897
CHEVETRE | STEEL/S235JR | GRENAILLE-PEINT | 1158 | U13 | 3 | CHEVETRE | 2.4 | 0 | 65.7 | 0.2 | 50 | 400 | 399.997 | 0.158335 | 0.000307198 | 2.4115
2 x CHEVETRE | STEEL/E24-2 | GRENAILLE-PEINT | 1146 | U6 | 2 | CHEVETRE | 15.6 | 0 | 65.1 | 1 | 50 | 2598.3 | 2598.33 | 1.02008 | 0.00199552 | 15.6648
2 x CHEVETRE | STEEL/E24-2 | GRENAILLE-PEINT | 1143 | U5 | 2 | CHEVETRE | 15.6 | 0 | 65.1 | 1 | 50 | 2595 | 2595 | 1.01878 | 0.00199296 | 15.6447
CHEVETRE | STEEL/E24-2 | GRENAILLE-PEINT | 1144 | U5 | 2 | CHEVETRE | 2.1 | 0 | 65.7 | 0.1 | 50 | 350 | 349.996 | 0.138734 | 0.000268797 | 2.11006
2 x CHEVETRE | STEEL/E24-2 | GRENAILLE-PEINT | 1143 | U1 | 2 | CHEVETRE | 15.6 | 0 | 65.1 | 1 | 50 | 2595 | 2595 | 1.01878 | 0.00199296 | 15.6447
2 x CHEVETRE | STEEL/E24-2 | GRENAILLE-PEINT | 1142 | U1 | 2 | CHEVETRE | 1.7 | 0 | 65.9 | 0.1 | 50 | 300 | 300 | 0.119136 | 0.0002304 | 1.80864
ATTACHE | STEEL/E24-2 | GRENAILLE-PEINT | 1141 | L35 | 2 | ATTACHE | 4.2 | 0 | 65.5 | 0.3 | 50 | 757.5 | 757.499 | 0.280179 | 0.000545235 | 4.2801
ATTACHE | STEEL/E24-2 | GRENAILLE-PEINT | 1137 | L34 | 2 | ATTACHE | 1.7 | 0 | 65.9 | 0.1 | 50 | 300.4 | 300.503 | 0.113824 | 0.000219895 | 1.72618
ATTACHE | STEEL/E24-2 | GRENAILLE-PEINT | 1136 | L33 | 2 | ATTACHE | 0.9 | 0 | 66.9 | 0.1 | 50 | 150.9 | 150.86 | 0.0551811 | 0.000105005 | 0.824286
ATTACHE | STEEL/E24-2 | GRENAILLE-PEINT | 1136 | L33 | 2 | ATTACHE | 0.9 | 0 | 66.9 | 0.1 | 50 | 150.6 | 150.64 | 0.055095 | 0.000104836 | 0.822963
ATTACHE | STEEL/E24-2 | GRENAILLE-PEINT | 1140 | L34 | 2 | ATTACHE | 5.2 | 0 | 65.5 | 0.3 | 50 | 917.5 | 917.499 | 0.342899 | 0.000668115 | 5.2447
ATTACHE | STEEL/E24-2 | GRENAILLE-PEINT | 1139 | L33 | 2 | ATTACHE | 5.5 | 0 | 65.5 | 0.3 | 50 | 967.5 | 967.499 | 0.362498 | 0.000706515 | 5.54614
ATTACHE | STEEL/E24-2 | GRENAILLE-PEINT | 1138 | L33 | 2 | ATTACHE | 5.5 | 0 | 65.5 | 0.3 | 50 | 967.5 | 967.499 | 0.362499 | 0.000706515 | 5.54614
LISSE | STEEL/E24-2 | GRENAILLE-PEINT | 1125 | L33 | 2 | LISSE | 15 | 0.2 | 65.1 | 1 | 4 | 2488.7 | 2488.72 | 0.977112 | 0.00191133 | 15.0039
LISSE | STEEL/E24-2 | GRENAILLE-PEINT | 1126 | L33 | 2 | LISSE | 15 | 0.2 | 65.1 | 1 | 4 | 2485.3 | 2485.31 | 0.975775 | 0.00190871 | 14.9834
LISSE | STEEL/E24-2 | GRENAILLE-PEINT | 1127 | L37 | 2 | LISSE | 14.2 | 0.2 | 65.1 | 0.8 | 4 | 2360.6 | 2360.57 | 0.926878 | 0.00181291 | 14.2314
LISSE | STEEL/E24-2 | GRENAILLE-PEINT | 1128 | L37 | 2 | LISSE | 14.2 | 0.2 | 65.1 | 0.8 | 4 | 2372.1 | 2372.07 | 0.931384 | 0.00182174 | 14.3007
LISSE | STEEL/E24-2 | GRENAILLE-PEINT | 1129 | L34 | 2 | LISSE | 14.4 | 0.2 | 65.1 | 0.8 | 4 | 2403 | 2402.99 | 0.943504 | 0.00184549 | 14.4871
LISSE | STEEL/E24-2 | GRENAILLE-PEINT | 1130 | L34 | 2 | LISSE | 14.7 | 0.2 | 65.1 | 1 | 4 | 2427.7 | 2427.67 | 0.95318 | 0.00186444 | 14.6359
LISSE | STEEL/E24-2 | GRENAILLE-PEINT | 1131 | L36 | 2 | LISSE | 12.3 | 0.2 | 65.1 | 0.8 | 4 | 2042.7 | 2042.74 | 0.802287 | 0.00156882 | 12.3152
LISSE | STEEL/E24-2 | GRENAILLE-PEINT | 1132 | L36 | 2 | LISSE | 12.5 | 0.2 | 65.1 | 0.8 | 4 | 2072 | 2071.98 | 0.813752 | 0.00159128 | 12.4915
LISSE | STEEL/E24-2 | GRENAILLE-PEINT | 1133 | L35 | 2 | LISSE | 12.7 | 0.2 | 65.1 | 0.8 | 4 | 2117.5 | 2117.54 | 0.831609 | 0.00162626 | 12.7662
LISSE | STEEL/E24-2 | GRENAILLE-PEINT | 1134 | L35 | 2 | LISSE | 13.1 | 0.2 | 65.1 | 0.8 | 4 | 2174.6 | 2174.6 | 0.853976 | 0.00167008 | 13.1102
LISSE | STEEL/E24-2 | GRENAILLE-PEINT | 1135 | L35 | 2 | LISSE | 3.4 | 0.1 | 65.5 | 0.2 | 4 | 558.3 | 558.34 | 0.220405 | 0.000428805 | 3.36612
ATTACHE | STEEL/E24-2 | GRENAILLE-PEINT | 1116 | L35 | 2 | ATTACHE | 4.2 | 0 | 65.5 | 0.3 | 50 | 757.5 | 757.499 | 0.280178 | 0.000545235 | 4.28009
2 x ATTACHE | STEEL/E24-2 | GRENAILLE-PEINT | 1117 | L35 | 2 | ATTACHE | 4.5 | 0 | 65.5 | 0.3 | 50 | 787.5 | 787.499 | 0.291939 | 0.000568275 | 4.46096
2 x ATTACHE | STEEL/E24-2 | GRENAILLE-PEINT | 1118 | L35 | 2 | ATTACHE | 4.5 | 0 | 65.5 | 0.3 | 50 | 787.5 | 787.499 | 0.291938 | 0.000568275 | 4.46096
2 x ATTACHE | STEEL/E24-2 | GRENAILLE-PEINT | 1119 | L36 | 2 | ATTACHE | 4.8 | 0 | 65.5 | 0.3 | 50 | 857.5 | 857.499 | 0.319379 | 0.000622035 | 4.88298
2 x ATTACHE | STEEL/E24-2 | GRENAILLE-PEINT | 1120 | L36 | 2 | ATTACHE | 4.8 | 0 | 65.5 | 0.3 | 50 | 857.5 | 857.499 | 0.319378 | 0.000622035 | 4.88297
2 x ATTACHE | STEEL/E24-2 | GRENAILLE-PEINT | 1121 | L34 | 2 | ATTACHE | 5.2 | 0 | 65.5 | 0.3 | 50 | 917.5 | 917.499 | 0.342898 | 0.000668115 | 5.2447
ATTACHE | STEEL/E24-2 | GRENAILLE-PEINT | 1122 | L34 | 2 | ATTACHE | 5.2 | 0 | 65.5 | 0.3 | 50 | 917.5 | 917.499 | 0.342899 | 0.000668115 | 5.2447
2 x ATTACHE | STEEL/E24-2 | GRENAILLE-PEINT | 1123 | L37 | 2 | ATTACHE | 5.5 | 0 | 65.5 | 0.3 | 50 | 967.5 | 967.499 | 0.362499 | 0.000706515 | 5.54614
2 x ATTACHE | STEEL/E24-2 | GRENAILLE-PEINT | 1124 | L37 | 2 | ATTACHE | 5.5 | 0 | 65.5 | 0.3 | 50 | 967.5 | 967.499 | 0.362498 | 0.000706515 | 5.54614
ATTACHE | STEEL/E24-2 | GRENAILLE-PEINT | 1114 | L33 | 2 | ATTACHE | 2.7 | 0 | 65.7 | 0.2 | 50 | 481.5 | 481.499 | 0.176806 | 0.000343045 | 2.69291
ATTACHE | STEEL/E24-2 | GRENAILLE-PEINT | 1115 | L33 | 2 | ATTACHE | 2.7 | 0 | 65.7 | 0.2 | 50 | 481.5 | 481.499 | 0.176806 | 0.000343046 | 2.69291
ATTACHE | STEEL/E24-2 | GRENAILLE-PEINT | 1123 | L33 | 2 | ATTACHE | 5.5 | 0 | 65.5 | 0.3 | 50 | 967.5 | 967.499 | 0.362499 | 0.000706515 | 5.54614
ATTACHE | STEEL/E24-2 | GRENAILLE-PEINT | 1124 | L33 | 2 | ATTACHE | 5.5 | 0 | 65.5 | 0.3 | 50 | 967.5 | 967.499 | 0.362498 | 0.000706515 | 5.54614
ATTACHE | STEEL/E24-2 | GRENAILLE-PEINT | 1115 | L34 | 2 | ATTACHE | 2.7 | 0 | 65.7 | 0.2 | 50 | 481.5 | 481.499 | 0.176791 | 0.000343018 | 2.69269
17 x SOLIVE | STEEL/S235JR | GALVANISE | S81 | S81 | 2 | SOLIVE | 28.7 | 0.2 | 65.1 | 1.9 | 50 | 4768.3 | 4768.33 | 1.87072 | 0.00366208 | 28.7473
19 x SOLIVE | STEEL/S235JR | GALVANISE | S54 | S54 | 2 | SOLIVE | 36.5 | 0.4 | 65.1 | 2.5 | 50 | 6046.7 | 6046.67 | 2.37183 | 0.00464384 | 36.4542
2 x SOLIVE | STEEL/S235JR | GALVANISE | S72 | S72 | 2 | SOLIVE | 30.5 | 0.4 | 65.1 | 1.9 | 50 | 5052.5 | 5052.5 | 1.98212 | 0.00388032 | 30.4605
SOLIVE | STEEL/S235JR | GALVANISE | S71 | S71 | 2 | SOLIVE | 25.6 | 0.2 | 65.1 | 1.7 | 50 | 4250 | 4250 | 1.66754 | 0.003264 | 25.6224
SOLIVE | STEEL/S235JR | GALVANISE | S48 | S48 | 2 | SOLIVE | 30.8 | 0.4 | 65.1 | 1.9 | 50 | 5105 | 5105 | 2.0027 | 0.00392064 | 30.777
2 x SOLIVE | STEEL/S235JR | GALVANISE | S70 | S70 | 2 | SOLIVE | 32.1 | 0.4 | 65.1 | 2.1 | 50 | 5327.5 | 5327.5 | 2.08992 | 0.00409152 | 32.1184
SOLIVE | STEEL/S235JR | GALVANISE | S69 | S69 | 2 | SOLIVE | 33.2 | 0.4 | 65.1 | 2.2 | 50 | 5506.7 | 5506.66 | 2.16015 | 0.00422911 | 33.1986
SOLIVE | STEEL/S235JR | GALVANISE | S43 | S43 | 2 | SOLIVE | 21.9 | 0.2 | 65.1 | 1.5 | 50 | 3638.3 | 3638.34 | 1.42777 | 0.00279425 | 21.9348
SOLIVE | STEEL/S235JR | GALVANISE | 1079 | S49 | 2 | SOLIVE | 25.2 | 0.2 | 65.1 | 1.6 | 50 | 4175 | 4174.97 | 1.63812 | 0.00320638 | 25.1701
SOLIVE | STEEL/S235JR | GALVANISE | 1097 | S68 | 2 | SOLIVE | 25.6 | 0.2 | 65.1 | 1.7 | 50 | 4250 | 4250 | 1.66754 | 0.003264 | 25.6224
2 x SOLIVE | STEEL/S235JR | GALVANISE | 1096 | S67 | 2 | SOLIVE | 30.5 | 0.4 | 65.1 | 1.9 | 50 | 5052.5 | 5052.5 | 1.98212 | 0.00388032 | 30.4605
2 x SOLIVE | STEEL/S235JR | GALVANISE | 1095 | S66 | 2 | SOLIVE | 32.1 | 0.4 | 65.1 | 2.1 | 50 | 5327.5 | 5327.5 | 2.08992 | 0.00409152 | 32.1184
SOLIVE | STEEL/S235JR | GALVANISE | 1094 | S65 | 2 | SOLIVE | 33.2 | 0.4 | 65.1 | 2.2 | 50 | 5506.7 | 5506.66 | 2.16015 | 0.00422911 | 33.1986
SOLIVE | STEEL/S235JR | GALVANISE | 1074 | S44 | 2 | SOLIVE | 15.8 | 0.1 | 65.1 | 1 | 50 | 2625 | 2625 | 1.03054 | 0.002016 | 15.8256
SOLIVE | STEEL/S235JR | GALVANISE | S42 | S42 | 2 | SOLIVE | 30.8 | 0.4 | 65.1 | 1.9 | 50 | 5105 | 5105 | 2.0027 | 0.00392064 | 30.777
SOLIVE | STEEL/S235JR | GALVANISE | S64 | S64 | 2 | SOLIVE | 25.6 | 0.2 | 65.1 | 1.7 | 50 | 4250 | 4250 | 1.66754 | 0.003264 | 25.6224
2 x SOLIVE | STEEL/S235JR | GALVANISE | S63 | S63 | 2 | SOLIVE | 30.5 | 0.4 | 65.1 | 1.9 | 50 | 5052.5 | 5052.5 | 1.98212 | 0.00388032 | 30.4605
2 x SOLIVE | STEEL/S235JR | GALVANISE | S62 | S62 | 2 | SOLIVE | 32.1 | 0.4 | 65.1 | 2.1 | 50 | 5327.5 | 5327.5 | 2.08992 | 0.00409152 | 32.1184
9 x SOLIVE | STEEL/S235JR | GALVANISE | S77 | S77 | 2 | SOLIVE | 12.1 | 0.1 | 65.1 | 0.8 | 50 | 2000 | 2000 | 0.785536 | 0.001536 | 12.0576
3 x SOLIVE | STEEL/S235JR | GALVANISE | S55 | S55 | 2 | SOLIVE | 17.6 | 0.1 | 65.1 | 1.1 | 50 | 2915 | 2915 | 1.14422 | 0.00223872 | 17.574
12 x SOLIVE | STEEL/S235JR | GALVANISE | S76 | S76 | 2 | SOLIVE | 14.4 | 0.1 | 65.1 | 0.8 | 50 | 2401.3 | 2401.25 | 0.942826 | 0.00184416 | 14.4767
12 x SOLIVE | STEEL/S235JR | GALVANISE | S78 | S78 | 2 | SOLIVE | 15.2 | 0.1 | 65.1 | 1 | 50 | 2538.8 | 2538.75 | 0.996726 | 0.00194976 | 15.3056
6 x SOLIVE | STEEL/S235JR | GALVANISE | S82 | S82 | 2 | SOLIVE | 15.8 | 0.1 | 65.1 | 1 | 50 | 2628.3 | 2628.33 | 1.03184 | 0.00201856 | 15.8457
3 x SOLIVE | STEEL/S235JR | GALVANISE | S58 | S58 | 2 | SOLIVE | 21.6 | 0.2 | 65.1 | 1.5 | 50 | 3578.3 | 3578.34 | 1.40425 | 0.00274817 | 21.5731
SOLIVE | STEEL/S235JR | GALVANISE | S84 | S84 | 2 | SOLIVE | 20.4 | 0.2 | 65.1 | 1.2 | 50 | 3381 | 3381 | 1.32689 | 0.00259661 | 20.3834
8 x SOLIVE | STEEL/S235JR | GALVANISE | S74 | S74 | 2 | SOLIVE | 37.1 | 0.4 | 65.1 | 2.5 | 50 | 6154 | 6154 | 2.4139 | 0.00472627 | 37.1012
8 x SOLIVE | STEEL/S235JR | GALVANISE | S73 | S73 | 2 | SOLIVE | 40.1 | 0.4 | 65.1 | 2.6 | 50 | 6651 | 6651 | 2.60873 | 0.00510797 | 40.0975
SOLIVE | STEEL/S235JR | GALVANISE | S50 | S50 | 2 | SOLIVE | 32.7 | 0.4 | 65.1 | 2.1 | 50 | 5430 | 5430 | 2.1301 | 0.00417024 | 32.7364
SOLIVE | STEEL/S235JR | GALVANISE | S61 | S61 | 2 | SOLIVE | 33.3 | 0.4 | 65.1 | 2.2 | 50 | 5520 | 5520 | 2.16538 | 0.00423936 | 33.279
SOLIVE | STEEL/S235JR | GALVANISE | S51 | S51 | 2 | SOLIVE | 33 | 0.4 | 65.1 | 2.1 | 50 | 5480 | 5480 | 2.1497 | 0.00420864 | 33.0378
3 x SOLIVE | STEEL/S235JR | GALVANISE | S45 | S45 | 2 | SOLIVE | 15.6 | 0.1 | 65.1 | 1 | 50 | 2605 | 2605 | 1.0227 | 0.00200064 | 15.705
SOLIVE | STEEL/S235JR | GALVANISE | S60 | S60 | 2 | SOLIVE | 15.6 | 0.1 | 65.1 | 1 | 50 | 2605 | 2605 | 1.0227 | 0.00200064 | 15.705
5 x SOLIVE | STEEL/S235JR | GALVANISE | S46 | S46 | 2 | SOLIVE | 37.1 | 0.4 | 65.1 | 2.5 | 50 | 6154 | 6154 | 2.4139 | 0.00472627 | 37.1012
5 x SOLIVE | STEEL/S235JR | GALVANISE | S79 | S79 | 2 | SOLIVE | 40.1 | 0.4 | 65.1 | 2.6 | 50 | 6651 | 6651 | 2.60873 | 0.00510797 | 40.0975
16 x SOLIVE | STEEL/S235JR | GALVANISE | S80 | S80 | 2 | SOLIVE | 15.8 | 0.1 | 65.1 | 1 | 50 | 2635 | 2635 | 1.03446 | 0.00202368 | 15.8859
SOLIVE | STEEL/S235JR | GALVANISE | S83 | S83 | 2 | SOLIVE | 20.4 | 0.2 | 65.1 | 1.2 | 50 | 3381 | 3381 | 1.32689 | 0.00259661 | 20.3834
SOLIVE | STEEL/S235JR | GALVANISE | S59 | S59 | 2 | SOLIVE | 16 | 0.1 | 65.1 | 1 | 50 | 2655 | 2655 | 1.0423 | 0.00203904 | 16.0065
3 x SOLIVE | STEEL/S235JR | GALVANISE | S47 | S47 | 2 | SOLIVE | 16 | 0.1 | 65.1 | 1 | 50 | 2655 | 2655 | 1.0423 | 0.00203904 | 16.0065
14 x SOLIVE | STEEL/S235JR | GALVANISE | S75 | S75 | 2 | SOLIVE | 28.7 | 0.2 | 65.1 | 1.9 | 50 | 4768.3 | 4768.33 | 1.87072 | 0.00366208 | 28.7473
SOLIVE | STEEL/S235JR | GALVANISE | S41 | S41 | 2 | SOLIVE | 21.7 | 0.2 | 65.1 | 1.5 | 50 | 3598.3 | 3598.33 | 1.41208 | 0.00276352 | 21.6936
7 x SOLIVE | STEEL/S235JR | GALVANISE | 1082 | S53 | 2 | SOLIVE | 36.5 | 0.4 | 65.1 | 2.5 | 50 | 6046.7 | 6046.67 | 2.37183 | 0.00464384 | 36.4542
SOLIVE | STEEL/S235JR | GALVANISE | S57 | S57 | 2 | SOLIVE | 21.9 | 0.2 | 65.1 | 1.5 | 50 | 3638.3 | 3638.34 | 1.42777 | 0.00279425 | 21.9348
7 x SOLIVE | STEEL/S235JR | GALVANISE | S52 | S52 | 2 | SOLIVE | 36.5 | 0.4 | 65.1 | 2.5 | 50 | 6046.7 | 6046.67 | 2.37183 | 0.00464384 | 36.4542
SOLIVE | STEEL/S235JR | GALVANISE | S56 | S56 | 2 | SOLIVE | 33.2 | 0.4 | 65.1 | 2.2 | 50 | 5506.7 | 5506.66 | 2.16015 | 0.00422911 | 33.1986
SOLIVE | STEEL/S235JR | GALVANISE | S40 | S40 | 2 | SOLIVE | 21.7 | 0.2 | 65.1 | 1.5 | 50 | 3593.3 | 3593.33 | 1.41012 | 0.00275968 | 21.6635
6 x CHEVETRE | STEEL/E24-2 | GRENAILLE-PEINT | 1149 | U2 | 1 | CHEVETRE | 14.4 | 0 | 65.1 | 0.8 | 50 | 2390 | 2390 | 0.938416 | 0.00183552 | 14.4088
3 x CHEVETRE | STEEL/E24-2 | GRENAILLE-PEINT | 1142 | U2 | 1 | CHEVETRE | 1.7 | 0 | 65.9 | 0.1 | 50 | 300 | 300 | 0.119136 | 0.0002304 | 1.80864
8 x CHEVETRE | STEEL/E24-2 | GRENAILLE-PEINT | 1150 | U3 | 1 | CHEVETRE | 14.7 | 0 | 65.1 | 1 | 50 | 2420 | 2420 | 0.950176 | 0.00185856 | 14.5897
4 x CHEVETRE | STEEL/E24-2 | GRENAILLE-PEINT | 1142 | U3 | 1 | CHEVETRE | 1.7 | 0 | 65.9 | 0.1 | 50 | 300 | 300 | 0.119136 | 0.0002304 | 1.80864
8 x CHEVETRE | STEEL/E24-2 | GRENAILLE-PEINT | 1151 | U4 | 1 | CHEVETRE | 14.7 | 0 | 65.1 | 1 | 50 | 2440 | 2440 | 0.958016 | 0.00187392 | 14.7103
4 x CHEVETRE | STEEL/E24-2 | GRENAILLE-PEINT | 1142 | U4 | 1 | CHEVETRE | 1.7 | 0 | 65.9 | 0.1 | 50 | 300 | 300 | 0.119136 | 0.0002304 | 1.80864
4 x SOLIVE | STEEL/S235JR | GALVANISE | 1069 | S39 | 1 | SOLIVE | 24.4 | 0.2 | 65.1 | 1.6 | 50 | 4253.7 | 4253.73 | 1.59924 | 0.00312513 | 24.5323
4 x SOLIVE | STEEL/S235JR | GALVANISE | S36 | S36 | 1 | SOLIVE | 15.8 | 0.1 | 65.1 | 1 | 50 | 2640 | 2640 | 1.03642 | 0.00202752 | 15.916
4 x SOLIVE | STEEL/S235JR | GALVANISE | S32 | S32 | 1 | SOLIVE | 22.8 | 0.2 | 65.1 | 1.5 | 50 | 3941.3 | 3941.27 | 1.48079 | 0.00289546 | 22.7293
SOLIVE | STEEL/S235JR | GALVANISE | S30 | S30 | 1 | SOLIVE | 35.9 | 0.4 | 65.1 | 2.3 | 50 | 5955 | 5955 | 2.3359 | 0.00457344 | 35.9015
2 x SOLIVE | STEEL/S235JR | GALVANISE | 1059 | S29 | 1 | SOLIVE | 35.3 | 0.4 | 65.1 | 2.3 | 50 | 5855 | 5855 | 2.2967 | 0.00449664 | 35.2986
SOLIVE | STEEL/S235JR | GALVANISE | 1058 | S28 | 1 | SOLIVE | 63.9 | 0.4 | 65.1 | 4.1 | 50 | 10955 | 10955 | 4.16042 | 0.00814026 | 63.9011
4 x SOLIVE | STEEL/S235JR | GALVANISE | 1068 | S38 | 1 | SOLIVE | 19.2 | 0.2 | 65.1 | 1.2 | 50 | 3362 | 3362 | 1.24968 | 0.00244028 | 19.1562
SOLIVE | STEEL/S235JR | GALVANISE | S27 | S27 | 1 | SOLIVE | 10.6 | 0.1 | 65.1 | 0.6 | 50 | 1765 | 1765 | 0.693416 | 0.00135552 | 10.6408
SOLIVE | STEEL/S235JR | GALVANISE | S20 | S20 | 1 | SOLIVE | 15.2 | 0.1 | 65.1 | 1 | 50 | 2535 | 2535 | 0.995256 | 0.00194688 | 15.283
SOLIVE | STEEL/S235JR | GALVANISE | S26 | S26 | 1 | SOLIVE | 15 | 0.1 | 65.1 | 1 | 50 | 2470 | 2470 | 0.969776 | 0.00189696 | 14.8911
SOLIVE | STEEL/S235JR | GALVANISE | S25 | S25 | 1 | SOLIVE | 23.9 | 0.2 | 65.1 | 1.6 | 50 | 3962 | 3962 | 1.55464 | 0.00304282 | 23.8861
2 x SOLIVE | STEEL/S235JR | GALVANISE | S19 | S19 | 1 | SOLIVE | 12.5 | 0.1 | 65.1 | 0.8 | 50 | 2075 | 2075 | 0.814936 | 0.0015936 | 12.5098
SOLIVE | STEEL/S235JR | GALVANISE | S35 | S35 | 1 | SOLIVE | 15.2 | 0.1 | 65.1 | 1 | 50 | 2520 | 2520 | 0.989376 | 0.00193536 | 15.1926
10 x SOLIVE | STEEL/S235JR | GALVANISE | S23 | S23 | 1 | SOLIVE | 13.3 | 0.1 | 65.1 | 0.8 | 50 | 2230 | 2230 | 0.875696 | 0.00171264 | 13.4442
SOLIVE | STEEL/S235JR | GALVANISE | S18 | S18 | 1 | SOLIVE | 13.3 | 0.1 | 65.1 | 0.8 | 50 | 2230 | 2230 | 0.875696 | 0.00171264 | 13.4442
6 x SOLIVE | STEEL/S235JR | GALVANISE | S15 | S15 | 1 | SOLIVE | 36.5 | 0.4 | 65.1 | 2.5 | 50 | 6225 | 6225 | 2.37602 | 0.00464936 | 36.4975
6 x SOLIVE | STEEL/S235JR | GALVANISE | S24 | S24 | 1 | SOLIVE | 32.1 | 0.4 | 65.1 | 2.1 | 50 | 5320 | 5320 | 2.08698 | 0.00408576 | 32.0732
SOLIVE | STEEL/S235JR | GALVANISE | S16 | S16 | 1 | SOLIVE | 36.5 | 0.4 | 65.1 | 2.5 | 50 | 6225 | 6225 | 2.37602 | 0.00464936 | 36.4975
SOLIVE | STEEL/S235JR | GALVANISE | S31 | S31 | 1 | SOLIVE | 36.5 | 0.4 | 65.1 | 2.5 | 50 | 6225 | 6225 | 2.37602 | 0.00464936 | 36.4975
2 x SOLIVE | STEEL/S235JR | GALVANISE | S13 | S13 | 1 | SOLIVE | 19.7 | 0.2 | 65.1 | 1.2 | 50 | 3264 | 3264 | 1.28102 | 0.00250675 | 19.678
5 x SOLIVE | STEEL/S235JR | GALVANISE | S21 | S21 | 1 | SOLIVE | 32.1 | 0.4 | 65.1 | 2.1 | 50 | 5320 | 5320 | 2.08698 | 0.00408576 | 32.0732
SOLIVE | STEEL/S235JR | GALVANISE | S12 | S12 | 1 | SOLIVE | 19.7 | 0.2 | 65.1 | 1.2 | 50 | 3264 | 3264 | 1.28102 | 0.00250675 | 19.678
4 x SOLIVE | STEEL/S235JR | GALVANISE | S14 | S14 | 1 | SOLIVE | 36.5 | 0.4 | 65.1 | 2.5 | 50 | 6225 | 6225 | 2.37602 | 0.00464936 | 36.4975
10 x SOLIVE | STEEL/S235JR | GALVANISE | S22 | S22 | 1 | SOLIVE | 14.7 | 0.1 | 65.1 | 1 | 50 | 2420 | 2420 | 0.950176 | 0.00185856 | 14.5897
5 x SOLIVE | STEEL/S235JR | GALVANISE | S17 | S17 | 1 | SOLIVE | 14.4 | 0.1 | 65.1 | 0.8 | 50 | 2385 | 2385 | 0.936456 | 0.00183168 | 14.3787
2 x SOLIVE | STEEL/S235JR | GALVANISE | 1067 | S37 | 1 | SOLIVE | 19.2 | 0.2 | 65.1 | 1.2 | 50 | 3362 | 3362 | 1.24968 | 0.00244028 | 19.1562
SOLIVE | STEEL/S235JR | GALVANISE | 1041 | S11 | 1 | SOLIVE | 63.9 | 0.4 | 65.1 | 4.1 | 50 | 10955 | 10955 | 4.16042 | 0.00814026 | 63.9011
3 x SOLIVE | STEEL/S235JR | GALVANISE | S33 | S33 | 1 | SOLIVE | 23.9 | 0.2 | 65.1 | 1.6 | 50 | 3962 | 3962 | 1.55464 | 0.00304282 | 23.8861
2 x SOLIVE | STEEL/S235JR | GALVANISE | S34 | S34 | 1 | SOLIVE | 23.9 | 0.2 | 65.1 | 1.6 | 50 | 3962 | 3962 | 1.55464 | 0.00304282 | 23.8861

# IfcBeam: UPF-120*50*4 (3)
In: Undefined
Description: UPF-120*50*4; Material: STEEL/S235JR
Tekla Commun - Finition: GRENAILLE-PEINT; Phase: 1; Profil: UPF-120*50*4; Nom: LISSE; sets with these values: 2
Tekla Quantités - Volume: 0 m3; Surface par tonne: 65 m2; Hauteur: 120 mm; Largeur: 50 mm; sets with these values: 2
Pset_BeamCommon - LoadBearing: no
Name | Repère de pièce = Reference | Repère d'assemblage | Poids (kg) | Surface supérieure totale (m2) | Surface nette (m2) | Longueur (mm) = Length (mm) | OuterSurfaceArea (m2) | NetVolume (m3) | NetWeight (kg)
LISSE | 892 | L8 | 28.5 | 0.4 | 1.9 | 4285 | 1.85282 | 0.00363368 | 28.5244
LISSE | 891 | L9 | 33 | 0.7 | 2.1 | 4950 | 2.1401 | 0.0041976 | 32.9512
LISSE | 890 | L10 | 24.2 | 0.4 | 1.6 | 3635 | 1.57202 | 0.00308248 | 24.1975

# IfcBeam: UPF-80*50*4 (12)
In: Undefined
Description: UPF-80*50*4; Material: STEEL/E24-2
Tekla Commun - Finition: GRENAILLE-PEINT; Phase: 2; Profil: UPF-80*50*4; Nom: CHEVETRE; sets with these values: 2
Tekla Quantités - Volume: 0 m3; Surface supérieure totale: 0 m2; Surface par tonne: 6.5 m2; Hauteur: 80 mm; Largeur: 50 mm; sets with these values: 2
Pset_BeamCommon - LoadBearing: no
Name | Repère de pièce = Reference | Repère d'assemblage | Poids (kg) | Surface nette (m2) | Longueur (mm) | Length (mm) | OuterSurfaceArea (m2) | NetVolume (m3) | NetWeight (kg)
2 x CHEVETRE | 1366 | U16 | 106.4 | 0.6 | 1970 | 1970 | 0.6895 | 0.00135536 | 10.6396
2 x CHEVETRE | 1364 | U16 | 21.6 | 0.1 | 400 | 400 | 0.14 | 0.0002752 | 2.16032
2 x CHEVETRE | 1365 | U15 | 128.1 | 0.8 | 2371.3 | 2371.25 | 0.829937 | 0.00163142 | 12.8066
2 x CHEVETRE | 1364 | U15 | 21.6 | 0.1 | 400 | 400 | 0.14 | 0.0002752 | 2.16032
2 x CHEVETRE | 1364 | U14 | 21.6 | 0.1 | 400 | 400 | 0.14 | 0.0002752 | 2.16032
2 x CHEVETRE | 1363 | U14 | 135.5 | 0.8 | 2508.8 | 2508.75 | 0.878062 | 0.00172602 | 13.5493

# IfcBeam: UPN100 (12)
In: Undefined
Description: UPN100
Tekla Commun - Profil: UPN100; sets with these values: 2
Tekla Quantités - Volume: 0 m3; Surface par tonne: 34.9 m2; Hauteur: 100 mm; Largeur: 50 mm; sets with these values: 2
Pset_BeamCommon - LoadBearing: no
Name | Material | Finition | Repère de pièce = Reference | Repère d'assemblage | Phase | Nom | Poids (kg) | Surface supérieure totale (m2) | Surface nette (m2) | Longueur (mm) | Length (mm) | OuterSurfaceArea (m2) | NetVolume (m3) | NetWeight (kg)
LISSE | STEEL/E24-2 | GRENAILLE-PEINT | 1190 | L53 | 5 | LISSE | 13.6 | 0 | 0.5 | 1286 | 1286 | 0.47582 | 0.00173353 | 13.6082
LISSE | STEEL/E24-2 | GRENAILLE-PEINT | 1191 | L54 | 5 | LISSE | 41.5 | 0.4 | 1.5 | 3915 | 3915 | 1.44855 | 0.00527742 | 41.4277
LISSE | STEEL/E24-2 | GRENAILLE-PEINT | 1191 | L54 | 5 | LISSE | 41.5 | 0.1 | 1.5 | 3915 | 3915 | 1.44855 | 0.00527742 | 41.4277
LISSE | STEEL/E24-2 | GRENAILLE-PEINT | 1189 | L52 | 2 | LISSE | 114.2 | 0.2 | 4.1 | 10775 | 10775 | 3.98675 | 0.0145247 | 114.019
LISSE | STEEL/E24-2 | GRENAILLE-PEINT | 1189 | L52 | 2 | LISSE | 114.2 | 1.1 | 4.1 | 10775 | 10775 | 3.98675 | 0.0145247 | 114.019
LISSE | STEEL/E24-2 | GRENAILLE-PEINT | 1188 | L51 | 2 | LISSE | 54.6 | 0.4 | 1.9 | 5150 | 5150 | 1.9055 | 0.0069422 | 54.4963
LISSE | STEEL/E24-2 | GRENAILLE-PEINT | 1188 | L51 | 2 | LISSE | 54.6 | 0.1 | 1.9 | 5150 | 5150 | 1.9055 | 0.0069422 | 54.4963
LISSE | STEEL/E24-2 | GRENAILLE-PEINT | 1187 | L50 | 2 | LISSE | 71.9 | 0.1 | 2.6 | 6781.3 | 6781.25 | 2.50906 | 0.00914113 | 71.7578
LISSE | STEEL/E24-2 | GRENAILLE-PEINT | 1186 | L49 | 2 | LISSE | 80.2 | 0.1 | 2.9 | 7568.8 | 7568.75 | 2.80044 | 0.0102027 | 80.091
LISSE | STEEL/E24-2 | GRENAILLE-PEINT | 1187 | L50 | 2 | LISSE | 71.9 | 0.7 | 2.6 | 6781.3 | 6781.25 | 2.50906 | 0.00914113 | 71.7578
LISSE | STEEL/E24-2 | GRENAILLE-PEINT | 1186 | L49 | 2 | LISSE | 80.2 | 0.7 | 2.9 | 7568.8 | 7568.75 | 2.80044 | 0.0102027 | 80.091
SOLIVE | STEEL/S235JR | GALVANISE | S85 | S85 | 1 | SOLIVE | 65.2 | 0.4 | 2.5 | 6155 | 6155 | 2.27735 | 0.00829694 | 65.131

# IfcBeam: UPN120 (35)
In: Undefined
Description: UPN120
Tekla Commun - Profil: UPN120; sets with these values: 2
Tekla Quantités - Volume: 0 m3; Surface par tonne: 32.2 m2; Hauteur: 120 mm; sets with these values: 2
Pset_BeamCommon - LoadBearing: no
Name | Material | Finition | Repère de pièce = Reference | Repère d'assemblage | Phase | Nom | Poids (kg) | Surface supérieure totale (m2) | Surface nette (m2) | Largeur (mm) | Longueur (mm) | Length (mm) | OuterSurfaceArea (m2) | NetVolume (m3) | NetWeight (kg)
LISSE | STEEL/E24-2 | GRENAILLE-PEINT | 1320 | L116 | 3 | LISSE | 8 | 0 | 0.3 | 55 | 600 | 600 | 0.258 | 0.000964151 | 7.56859
LISSE | STEEL/E24-2 | GRENAILLE-PEINT | 1321 | L115 | 3 | LISSE | 8 | 0 | 0.3 | 55 | 600 | 600 | 0.258 | 0.000962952 | 7.55917
LISSE | STEEL/E24-2 | GRENAILLE-PEINT | 1318 | L115 | 3 | LISSE | 6.5 | 0 | 0.2 | 55 | 490 | 490 | 0.2107 | 0.00083496 | 6.55444
LISSE | STEEL/E24-2 | GRENAILLE-PEINT | 1319 | L80 | 3 | LISSE | 6.5 | 0 | 0.2 | 55 | 490 | 490 | 0.2107 | 0.00083496 | 6.55444
LISSE | STEEL/E24-2 | GRENAILLE-PEINT | 1315 | L80 | 3 | LISSE | 3 | 0 | 0.1 | 55 | 227.8 | 227.835 | 0.0979689 | 0.000374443 | 2.93938
LISSE | STEEL/E24-2 | GRENAILLE-PEINT | 1316 | L116 | 3 | LISSE | 24.4 | 0.2 | 0.8 | 55 | 1830.1 | 1830.06 | 0.786926 | 0.00308766 | 24.2381
LISSE | STEEL/E24-2 | GRENAILLE-PEINT | 1317 | L116 | 3 | LISSE | 24.4 | 0 | 0.8 | 55 | 1830 | 1829.97 | 0.786886 | 0.00308854 | 24.245
LISSE | STEEL/E24-2 | GRENAILLE-PEINT | 1314 | L80 | 3 | LISSE | 157.6 | 0.2 | 5.3 | 7 | 11808.5 | 11808.5 | 5.07765 | 0.0201078 | 157.846
LISSE | STEEL/E24-2 | GRENAILLE-PEINT | 1313 | L80 | 3 | LISSE | 157.6 | 1.4 | 5.3 | 7 | 11808.5 | 11808.5 | 5.07765 | 0.0201078 | 157.846
LISSE | STEEL/E24-2 | GRENAILLE-PEINT | 1312 | L115 | 3 | LISSE | 159.7 | 1.4 | 5.3 | 7 | 11968.4 | 11968.4 | 5.1464 | 0.0203644 | 159.86
LISSE | STEEL/E24-2 | GRENAILLE-PEINT | 1311 | L115 | 3 | LISSE | 159.7 | 0.2 | 5.3 | 7 | 11968.4 | 11968.4 | 5.1464 | 0.0203644 | 159.86
2 x SOLIVE | STEEL/S235JR | GALVANISE | S100 | S100 | 2 | SOLIVE | 32.8 | 0.1 | 1.1 | 55 | 2460 | 2460 | 1.0578 | 0.00419184 | 32.9059
8 x SOLIVE | STEEL/S235JR | GALVANISE | S101 | S101 | 2 | SOLIVE | 67.5 | 0.4 | 2.3 | 55 | 5060 | 5060 | 2.1758 | 0.00862224 | 67.6846
2 x SOLIVE | STEEL/S235JR | GALVANISE | S102 | S102 | 2 | SOLIVE | 60.5 | 0.2 | 1.9 | 55 | 4533 | 4533 | 1.94919 | 0.00772423 | 60.6352
2 x SOLIVE | STEEL/S235JR | GALVANISE | S103 | S103 | 2 | SOLIVE | 61.1 | 0.4 | 1.9 | 55 | 4580 | 4580 | 1.9694 | 0.00780432 | 61.2639
2 x SOLIVE | STEEL/S235JR | GALVANISE | S104 | S104 | 2 | SOLIVE | 33.5 | 0.1 | 1.1 | 55 | 2507 | 2507 | 1.07801 | 0.00427193 | 33.5346
2 x SOLIVE | STEEL/S235JR | GALVANISE | S105 | S105 | 2 | SOLIVE | 63.7 | 0.4 | 2.1 | 55 | 4770 | 4770 | 2.0511 | 0.00812808 | 63.8054
2 x SOLIVE | STEEL/S235JR | GALVANISE | S106 | S106 | 2 | SOLIVE | 63.2 | 0.4 | 2.1 | 55 | 4734.5 | 4734.5 | 2.03584 | 0.00806759 | 63.3306
2 x SOLIVE | STEEL/S235JR | GALVANISE | S107 | S107 | 2 | SOLIVE | 42.4 | 0.2 | 1.5 | 55 | 3173.5 | 3173.5 | 1.36461 | 0.00540764 | 42.45
SOLIVE | STEEL/S235JR | GALVANISE | 1302 | S99 | 2 | SOLIVE | 11.3 | 0 | 0.3 | 55 | 845 | 845 | 0.36335 | 0.00143988 | 11.3031
EMPANNON | STEEL/E24-2 | GRENAILLE-PEINT | 1301 | L52 | 2 | EMPANNON | 121 | 0 | 4 | 55 | 9070.7 | 9070.69 | 3.9004 | 0.0154565 | 121.333

# IfcBeam: UPN140 (2)
In: Undefined
Description: UPN140
Tekla Commun - Phase: 1; Profil: UPN140; sets with these values: 2
Tekla Quantités - Volume: 0 m3; Surface par tonne: 30.6 m2; Hauteur: 140 mm; Largeur: 60 mm; sets with these values: 2
Pset_BeamCommon - LoadBearing: no
Name | Material | Finition | Repère de pièce = Reference | Repère d'assemblage | Nom | Poids (kg) | Surface supérieure totale (m2) | Surface nette (m2) | Longueur (mm) | Length (mm) | OuterSurfaceArea (m2) | NetVolume (m3) | NetWeight (kg)
EMPANNON | STEEL/E24-2 | GRENAILLE-PEINT | 1193 | K100 | EMPANNON | 30.8 | 0 | 1 | 1919.7 | 1919.73 | 0.940668 | 0.00385833 | 30.2879
SOLIVE | STEEL/S235JR | GALVANISE | S86 | S86 | SOLIVE | 119.9 | 0.4 | 3.8 | 7485 | 7485 | 3.66765 | 0.0152694 | 119.865

# IfcBeam: UPN160 (21)
In: Undefined
Description: UPN160
Tekla Commun - Profil: UPN160; sets with these values: 2
Tekla Quantités - Volume: 0 m3; Surface par tonne: 29.2 m2; Hauteur: 160 mm; Largeur: 65 mm; sets with these values: 2
Pset_BeamCommon - LoadBearing: no
Name | Material | Finition | Repère de pièce = Reference | Repère d'assemblage | Phase | Nom | Poids (kg) | Surface supérieure totale (m2) | Surface nette (m2) | Longueur (mm) | Length (mm) | OuterSurfaceArea (m2) | NetVolume (m3) | NetWeight (kg)
MONTANT | STEEL/E24-2 | GRENAILLE-PEINT | 1296 | M15 | 7 | MONTANT | 6 | 0 | 0.2 | 317 | 317 | 0.17435 | 0.000763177 | 5.99094
POTEAUX | STEEL/E24-2 | GRENAILLE-PEINT | 1294 | L114 | 7 | POTEAUX | 3.2 | 0 | 0.1 | 169.2 | 169.17 | 0.0930435 | 0.000327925 | 2.57421
LINTEAU | STEEL/E24-2 | GRENAILLE-PEINT | 1293 | L114 | 7 | LINTEAU | 70.7 | 0.1 | 2.1 | 3754 | 3754 | 2.0647 | 0.00903775 | 70.9464
MONTANT | STEEL/E24-2 | GRENAILLE-PEINT | 1296 | M23 | 7 | MONTANT | 6 | 0 | 0.2 | 317 | 317 | 0.17435 | 0.000763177 | 5.99094
LINTEAU | STEEL/E24-2 | GRENAILLE-PEINT | 1292 | L113 | 7 | LINTEAU | 70.7 | 0.1 | 2.1 | 3754 | 3754 | 2.0647 | 0.00903775 | 70.9464
POTEAUX | STEEL/E24-2 | GRENAILLE-PEINT | 1291 | P133 | 7 | POTEAUX | 56.2 | 0 | 1.7 | 2984 | 2984 | 1.6412 | 0.00718398 | 56.3942
POTEAUX | STEEL/E24-2 | GRENAILLE-PEINT | 1290 | P132 | 7 | POTEAUX | 70.9 | 0 | 2.1 | 3765.3 | 3765.32 | 2.07093 | 0.00906501 | 71.1603
EMPANNON | STEEL/E24-2 | GRENAILLE-PEINT | 1289 | N43 | 3 | EMPANNON | 3 | 0 | 0.1 | 161.8 | 161.751 | 0.0889629 | 0.000389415 | 3.05691
MONTANT | STEEL/E24-2 | GRENAILLE-PEINT | 1295 | M16 | 3 | MONTANT | 60.2 | 0 | 1.7 | 3194 | 3194 | 1.7567 | 0.00768955 | 60.363
LINTEAU | STEEL/E24-2 | GRENAILLE-PEINT | L112 | L112 | 3 | LINTEAU | 72.4 | 0.1 | 2.2 | 3842 | 3842 | 2.1131 | 0.00915916 | 71.8994
LINTEAU | STEEL/E24-2 | GRENAILLE-PEINT | L111 | L111 | 3 | LINTEAU | 71.3 | 0.1 | 2.1 | 3782 | 3782 | 2.0801 | 0.00905994 | 71.1205
LINTEAU | STEEL/E24-2 | GRENAILLE-PEINT | L112 | L112 | 3 | LINTEAU | 72.4 | 0.1 | 2.2 | 3841 | 3841 | 2.11255 | 0.00915676 | 71.8805
SOLIVE | STEEL/S235JR | GALVANISE | 1286 | S94 | 2 | SOLIVE | 46.4 | 0.2 | 1.5 | 2465 | 2465 | 1.35575 | 0.00593449 | 46.5857
SOLIVE | STEEL/S235JR | GALVANISE | 1285 | S92 | 2 | SOLIVE | 147.4 | 0.4 | 4.4 | 7825 | 7825 | 4.30375 | 0.0188387 | 147.884
SOLIVE | STEEL/S235JR | GALVANISE | 1285 | S91 | 2 | SOLIVE | 147.4 | 0.4 | 4.4 | 7825 | 7825 | 4.30375 | 0.0188387 | 147.884
SOLIVE | STEEL/S235JR | GALVANISE | 1284 | S90 | 2 | SOLIVE | 95.3 | 0.4 | 2.9 | 5060 | 5060 | 2.783 | 0.0121819 | 95.6283
SOLIVE | STEEL/S235JR | GALVANISE | 1284 | S89 | 2 | SOLIVE | 95.3 | 0.4 | 2.9 | 5060 | 5060 | 2.783 | 0.0121819 | 95.6283
SOLIVE | STEEL/S235JR | GALVANISE | 1286 | S93 | 2 | SOLIVE | 46.4 | 0.2 | 1.5 | 2465 | 2465 | 1.35575 | 0.00593449 | 46.5857
EMPANNON | STEEL/S235JR | GRENAILLE-PEINT | 1283 | K105 | 2 | EMPANNON | 107.1 | 0 | 3.2 | 5682.7 | 5682.75 | 3.12551 | 0.0136812 | 107.398
EMPANNON | STEEL/S235JR | GRENAILLE-PEINT | 1282 | K104 | 2 | EMPANNON | 134.9 | 0 | 4 | 7158.5 | 7158.46 | 3.93715 | 0.017234 | 135.287
EMPANNON | STEEL/S235JR | GRENAILLE-PEINT | 1281 | K103 | 2 | EMPANNON | 242.7 | 0 | 7.4 | 12881.2 | 12881.2 | 7.08466 | 0.0310115 | 243.44

# IfcBeam: UPN180 (21)
In: Undefined
Description: UPN180; Material: STEEL/E24-2
Tekla Commun - Finition: GRENAILLE-PEINT; Profil: UPN180; sets with these values: 2
Tekla Quantités - Volume: 0 m3; Surface par tonne: 27.8 m2; Hauteur: 180 mm; Largeur: 70 mm; sets with these values: 2
Pset_BeamCommon - LoadBearing: no
Name | Repère de pièce = Reference | Repère d'assemblage | Phase | Nom | Poids (kg) | Surface supérieure totale (m2) | Surface nette (m2) | Longueur (mm) | Length (mm) | OuterSurfaceArea (m2) | NetVolume (m3) | NetWeight (kg)
EMPANNON | 999 | K93 | 3 | EMPANNON | 101.6 | 0 | 2.9 | 4622.9 | 4622.93 | 2.81998 | 0.012901 | 101.273
LINTEAU | 1003 | L28 | 1 | LINTEAU | 73.7 | 0.1 | 2.1 | 3355 | 3355 | 2.04655 | 0.00940742 | 73.8482
LINTEAU | 1002 | L27 | 1 | LINTEAU | 22.8 | 0 | 0.6 | 1039 | 1039 | 0.63379 | 0.00291336 | 22.8698
LINTEAU | 1001 | L26 | 1 | LINTEAU | 44.9 | 0 | 1.2 | 2044 | 2044 | 1.24684 | 0.00573138 | 44.9913
LINTEAU | 1000 | L25 | 1 | LINTEAU | 30.5 | 0 | 0.8 | 1388 | 1388 | 0.84668 | 0.00389195 | 30.5518
POTEAUX | 1005 | P43 | 1 | POTEAUX | 76.8 | 0 | 2.2 | 3496 | 3496 | 2.13256 | 0.00980278 | 76.9519
POTEAUX | 1005 | P42 | 1 | POTEAUX | 76.8 | 0 | 2.2 | 3496 | 3496 | 2.13256 | 0.00980278 | 76.9519
LINTEAU | L31 | L31 | 1 | LINTEAU | 124.7 | 0.1 | 3.4 | 5672.4 | 5672.4 | 3.46016 | 0.0159054 | 124.857
POTEAUX | 1004 | P41 | 1 | POTEAUX | 87.9 | 0 | 2.5 | 3999.8 | 3999.78 | 2.43987 | 0.0112154 | 88.0408
POTEAUX | 1012 | P51 | 1 | POTEAUX | 52.4 | 0 | 1.5 | 2384 | 2384 | 1.45424 | 0.00668474 | 52.4752
POTEAUX | 1012 | P50 | 1 | POTEAUX | 52.4 | 0 | 1.5 | 2384 | 2384 | 1.45424 | 0.00668474 | 52.4752
POTEAUX | 1004 | P40 | 1 | POTEAUX | 87.9 | 0 | 2.5 | 3999.8 | 3999.78 | 2.43987 | 0.0112154 | 88.0408
POTEAUX | 1011 | P49 | 1 | POTEAUX | 113.8 | 0 | 3.2 | 5179.4 | 5179.38 | 3.15942 | 0.014523 | 114.005
POTEAUX | 1011 | P48 | 1 | POTEAUX | 113.8 | 0 | 3.2 | 5179.4 | 5179.38 | 3.15942 | 0.014523 | 114.005
LINTEAU | L30 | L30 | 1 | LINTEAU | 124.7 | 0.1 | 3.4 | 5672.4 | 5672.4 | 3.46016 | 0.0159054 | 124.857
POTEAUX | 1010 | P47 | 1 | POTEAUX | 53.7 | 0 | 1.5 | 2444 | 2444 | 1.49084 | 0.00685298 | 53.7959
POTEAUX | 1010 | P46 | 1 | POTEAUX | 53.7 | 0 | 1.5 | 2444 | 2444 | 1.49084 | 0.00685298 | 53.7959
POTEAUX | 1009 | P45 | 1 | POTEAUX | 57 | 0 | 1.6 | 2594 | 2594 | 1.58234 | 0.00727358 | 57.0976
POTEAUX | 1009 | P44 | 1 | POTEAUX | 57 | 0 | 1.6 | 2594 | 2594 | 1.58234 | 0.00727358 | 57.0976
LINTEAU | L29 | L29 | 1 | LINTEAU | 124.2 | 0.1 | 3.4 | 5649.4 | 5649.35 | 3.4461 | 0.0158408 | 124.35
ATTACHE | H50 | H50 | 1 | ATTACHE | 3.4 | 0 | 0.1 | 160 | 160 | 0.0976 | 0.00044864 | 3.52182

# IfcBeam: UPN200 (7)
In: Undefined
Description: UPN200; Material: STEEL/E24-2
Tekla Commun - Finition: GRENAILLE-PEINT; Profil: UPN200; sets with these values: 2
Tekla Quantités - Volume: 0 m3; Surface par tonne: 26.1 m2; Hauteur: 200 mm; sets with these values: 2
Pset_BeamCommon - LoadBearing: no
Name | Repère de pièce = Reference | Repère d'assemblage | Phase | Nom | Poids (kg) | Surface supérieure totale (m2) | Surface nette (m2) | Largeur (mm) | Longueur (mm) | Length (mm) | OuterSurfaceArea (m2) | NetVolume (m3) | NetWeight (kg)
LISSE | 363 | L35 | 2 | LISSE | 137.9 | 0.1 | 3.7 | 8.5 | 5453.7 | 5453.65 | 3.59941 | 0.0176121 | 138.255
LISSE | 364 | L36 | 2 | LISSE | 115.7 | 0.1 | 3.1 | 8.5 | 4579 | 4579.03 | 3.02216 | 0.0147877 | 116.084
LISSE | 365 | L34 | 2 | LISSE | 131.3 | 0.1 | 3.6 | 8.5 | 5194.4 | 5194.4 | 3.4283 | 0.0167749 | 131.683
LISSE | 366 | L37 | 2 | LISSE | 128.8 | 0.1 | 3.4 | 8.5 | 5096.5 | 5096.49 | 3.36368 | 0.0164587 | 129.201
LISSE | 367 | L33 | 2 | LISSE | 134.7 | 0.1 | 3.6 | 8.5 | 5327.6 | 5327.63 | 3.51624 | 0.0172052 | 135.061
EMPANNON | 362 | K56 | 1 | EMPANNON | 192.7 | 0 | 5.1 | 75 | 7623.6 | 7623.56 | 5.03155 | 0.0246203 | 193.269
EMPANNON | K90 | K90 | 1 | EMPANNON | 104.2 | 0 | 2.8 | 75 | 4121.2 | 4121.18 | 2.71998 | 0.0132893 | 104.321

# IfcBeam: UPN220, EMPANNON
In: Undefined
Description: UPN220; Material: STEEL/E24-2
Tekla Commun - Finition: GRENAILLE-PEINT; Repère de pièce: 1202; Repère d'assemblage: K100; Phase: 1; Profil: UPN220; Nom: EMPANNON; sets with these values: 2
Tekla Quantités - Poids: 13.1 kg; Volume: 0 m3; Surface supérieure totale: 0 m2; Surface par tonne: 24.5 m2; Surface nette: 0.3 m2; Hauteur: 220 mm; Largeur: 80 mm; Longueur: 447 mm; sets with these values: 2
Pset_BeamCommon - LoadBearing: no; Reference: 1202
BaseQuantities - Length: 447.032 mm; OuterSurfaceArea: 0.321863 m2; NetVolume: 0.00167035 m3; NetWeight: 13.1122 kg

# IfcBeam: UPN260 (10)
In: Undefined
Description: UPN260
Tekla Commun - Finition: GRENAILLE-PEINT; Profil: UPN260; sets with these values: 2
Tekla Quantités - Surface par tonne: 21.9 m2; Hauteur: 260 mm; Largeur: 90 mm; sets with these values: 2
Pset_BeamCommon - LoadBearing: no
Name | Material | Repère de pièce = Reference | Repère d'assemblage | Phase | Nom | Poids (kg) | Volume (m3) | Surface supérieure totale (m2) | Surface nette (m2) | Longueur (mm) = Length (mm) | OuterSurfaceArea (m2) | NetVolume (m3) | NetWeight (kg)
SUPPORT | STEEL/S235JR | 455 | L53 | 5 | SUPPORT | 8.7 | 0 | 0 | 0.2 | 230.7 | 0.191481 | 0.00111659 | 8.76522
POUTRES | STEEL/E24-2 | N31 | N31 | 1 | POUTRES | 196.9 | 0 | 0.4 | 4.4 | 5192 | 4.30936 | 0.0251293 | 197.265
POUTRES | STEEL/E24-2 | N30 | N30 | 1 | POUTRES | 310.2 | 0 | 0.7 | 7 | 8181 | 6.79023 | 0.039596 | 310.829
POUTRES | STEEL/E24-2 | N29 | N29 | 1 | POUTRES | 394 | 0.1 | 1 | 8.9 | 10392 | 8.62536 | 0.0502973 | 394.834
POUTRES | STEEL/E24-2 | N28 | N28 | 1 | POUTRES | 394 | 0.1 | 1 | 8.9 | 10392 | 8.62536 | 0.0502973 | 394.834
POUTRES | STEEL/E24-2 | N27 | N27 | 1 | POUTRES | 306.8 | 0 | 0.7 | 7 | 8091 | 6.71553 | 0.0391604 | 307.409
POUTRES | STEEL/E24-2 | N26 | N26 | 1 | POUTRES | 225.6 | 0 | 0.4 | 5.1 | 5950 | 4.9385 | 0.028798 | 226.064
POUTRES | STEEL/E24-2 | N25 | N25 | 1 | POUTRES | 293.1 | 0 | 0.7 | 6.6 | 7731 | 6.41673 | 0.037418 | 293.732
POUTRES | STEEL/E24-2 | N24 | N24 | 1 | POUTRES | 199.1 | 0 | 0.4 | 4.4 | 5250 | 4.3575 | 0.02541 | 199.469
POUTRES | STEEL/E24-2 | N23 | N23 | 1 | POUTRES | 423.1 | 0.1 | 1 | 9.6 | 11159 | 9.26197 | 0.0540096 | 423.975

# IfcBeam: UPN300, POUTRES
In: Undefined
Description: UPN300; Material: STEEL/E24-2
Tekla Commun - Finition: GRENAILLE-PEINT; Repère de pièce: 1160; Repère d'assemblage: N37; Phase: 1; Profil: UPN300; Nom: POUTRES; sets with these values: 2
Tekla Quantités - Poids: 242.3 kg; Volume: 0 m3; Surface supérieure totale: 0.4 m2; Surface par tonne: 20.6 m2; Surface nette: 5.1 m2; Hauteur: 300 mm; Largeur: 100 mm; Longueur: 5250 mm; sets with these values: 2
Pset_BeamCommon - LoadBearing: no; Reference: 1160
BaseQuantities - Length: 5250 mm; OuterSurfaceArea: 4.9875 m2; NetVolume: 0.0305939 m3; NetWeight: 240.162 kg

# IfcColumn: TUBE-C-100*100*3 (183)
In: Undefined
Description: TUBE-C-100*100*3; Material: STEEL/S235JR
Tekla Commun - Finition: GALVANISE; Profil: TUBE-C-100*100*3; Nom: POTEAU; sets with these values: 2
Tekla Quantités - Volume: 0 m3; Surface supérieure totale: 0 m2; Surface par tonne: 43.1 m2; Hauteur: 100 mm; Largeur: 100 mm; sets with these values: 2
Pset_ColumnCommon - LoadBearing: no
Name | Repère de pièce = Reference | Repère d'assemblage | Phase | Poids (kg) | Surface nette (m2) | Longueur (mm) | Length (mm) | OuterSurfaceArea (m2) | NetVolume (m3) | NetWeight (kg)
POTEAU | 931 | P107 | 2 | 2.4 | 0.1 | 271.4 | 271.362 | 0.10556 | 0.000314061 | 2.46538
2 x POTEAU | 932 | P83 | 2 | 7.8 | 0.3 | 863.3 | 863.335 | 0.335837 | 0.00100312 | 7.87447
14 x POTEAU | 932 | P76 | 2 | 7.8 | 0.3 | 863.3 | 863.335 | 0.335837 | 0.00100312 | 7.87447
2 x POTEAU | 933 | P94 | 2 | 2.1 | 0.1 | 232.2 | 232.212 | 0.0903305 | 0.000268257 | 2.10582
2 x POTEAU | 934 | P77 | 2 | 3 | 0.1 | 317.3 | 317.251 | 0.12341 | 0.000367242 | 2.88285
14 x POTEAU | 935 | P62 | 2 | 3.8 | 0.2 | 417.3 | 417.251 | 0.16231 | 0.000483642 | 3.79659
POTEAU | 936 | P108 | 2 | 2.6 | 0.1 | 283.6 | 283.59 | 0.110317 | 0.000328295 | 2.57711
POTEAU | 937 | P91 | 2 | 3.2 | 0.1 | 358 | 358.022 | 0.139271 | 0.000414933 | 3.25723
POTEAU | 938 | P92 | 2 | 3.9 | 0.2 | 445.7 | 445.7 | 0.173377 | 0.000516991 | 4.05838
POTEAU | 939 | P93 | 2 | 4.8 | 0.2 | 533.4 | 533.36 | 0.207477 | 0.000619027 | 4.85936
5 x POTEAU | 936 | P95 | 2 | 2.6 | 0.1 | 283.6 | 283.59 | 0.110317 | 0.000328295 | 2.57711
5 x POTEAU | 940 | P63 | 2 | 5.7 | 0.3 | 633.4 | 633.36 | 0.246377 | 0.000735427 | 5.7731
5 x POTEAU | 941 | P64 | 2 | 4.2 | 0.2 | 458 | 458.022 | 0.178171 | 0.000531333 | 4.17097
5 x POTEAU | 942 | P72 | 2 | 3.3 | 0.1 | 370.4 | 370.362 | 0.144071 | 0.000429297 | 3.36998
5 x POTEAU | 943 | P65 | 2 | 4.8 | 0.2 | 545.7 | 545.7 | 0.212277 | 0.000633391 | 4.97212
POTEAU | 937 | P84 | 2 | 3.2 | 0.1 | 358 | 358.022 | 0.139271 | 0.000414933 | 3.25723
POTEAU | 938 | P85 | 2 | 3.9 | 0.2 | 445.7 | 445.7 | 0.173377 | 0.000516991 | 4.05838
POTEAU | 939 | P86 | 2 | 4.8 | 0.2 | 533.4 | 533.36 | 0.207477 | 0.000619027 | 4.85936
POTEAU | 931 | P100 | 2 | 2.4 | 0.1 | 271.4 | 271.362 | 0.10556 | 0.000314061 | 2.46538
POTEAU | 936 | P101 | 2 | 2.6 | 0.1 | 283.6 | 283.59 | 0.110317 | 0.000328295 | 2.57711
2 x POTEAU | 944 | P78 | 2 | 3.7 | 0.2 | 410 | 409.958 | 0.159474 | 0.000475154 | 3.72996
2 x POTEAU | 945 | P79 | 2 | 4.5 | 0.2 | 502.7 | 502.651 | 0.195531 | 0.000583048 | 4.57693
14 x POTEAU | 946 | P96 | 2 | 3 | 0.1 | 325.6 | 325.56 | 0.126643 | 0.000376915 | 2.95878
14 x POTEAU | 947 | P66 | 2 | 4.6 | 0.2 | 510 | 509.958 | 0.198374 | 0.000591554 | 4.6437
14 x POTEAU | 948 | P67 | 2 | 5.5 | 0.2 | 602.7 | 602.651 | 0.234431 | 0.000699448 | 5.49067
2 x POTEAU | 951 | P56 | 1 | 5.7 | 0.2 | 615.4 | 615.396 | 0.239389 | 0.000714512 | 5.60892
2 x POTEAU | 952 | P57 | 1 | 5.8 | 0.3 | 644.6 | 644.567 | 0.250737 | 0.000748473 | 5.87552
2 x POTEAU | 949 | P54 | 1 | 4.6 | 0.2 | 517 | 517.009 | 0.201117 | 0.000599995 | 4.70996
2 x POTEAU | 950 | P55 | 1 | 5.2 | 0.2 | 578.8 | 578.791 | 0.22515 | 0.000671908 | 5.27447
POTEAU | 949 | P59 | 1 | 4.6 | 0.2 | 517 | 517.009 | 0.201117 | 0.000599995 | 4.70996
POTEAU | 950 | P61 | 1 | 5.2 | 0.2 | 578.8 | 578.791 | 0.22515 | 0.000671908 | 5.27447
POTEAU | 949 | P58 | 1 | 4.6 | 0.2 | 517 | 517.009 | 0.201117 | 0.000599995 | 4.70996
POTEAU | 950 | P60 | 1 | 5.2 | 0.2 | 578.8 | 578.791 | 0.22515 | 0.000671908 | 5.27447
2 x POTEAU | 964 | P103 | 1 | 3 | 0.1 | 331.5 | 331.496 | 0.128952 | 0.000378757 | 2.97324
2 x POTEAU | 967 | P106 | 1 | 3 | 0.1 | 329.8 | 329.75 | 0.128273 | 0.000382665 | 3.00392
3 x POTEAU | 967 | P99 | 1 | 3 | 0.1 | 329.8 | 329.75 | 0.128273 | 0.000382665 | 3.00392
3 x POTEAU | 966 | P98 | 1 | 3.4 | 0.2 | 376 | 376.02 | 0.146272 | 0.000436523 | 3.42671
2 x POTEAU | 966 | P105 | 1 | 3.4 | 0.2 | 376 | 376.02 | 0.146272 | 0.000436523 | 3.42671
2 x POTEAU | 965 | P104 | 1 | 3 | 0.1 | 322 | 322.03 | 0.12527 | 0.000373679 | 2.93338
3 x POTEAU | 965 | P97 | 1 | 3 | 0.1 | 322 | 322.03 | 0.12527 | 0.000373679 | 2.93338
POTEAU | 963 | P75 | 1 | 3.9 | 0.2 | 430.5 | 430.496 | 0.167463 | 0.000493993 | 3.87785
2 x POTEAU | 963 | P74 | 1 | 3.9 | 0.2 | 430.5 | 430.496 | 0.167463 | 0.000493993 | 3.87785
2 x POTEAU | 958 | P102 | 1 | 2.8 | 0.1 | 314.4 | 314.368 | 0.122289 | 0.00036412 | 2.85834
2 x POTEAU | 959 | P87 | 1 | 3.4 | 0.2 | 390.1 | 390.098 | 0.151748 | 0.00045227 | 3.55032
7 x POTEAU | 956 | P71 | 1 | 4.5 | 0.2 | 490.1 | 490.098 | 0.190648 | 0.00056867 | 4.46406
7 x POTEAU | 957 | P73 | 1 | 3.7 | 0.2 | 413.4 | 413.368 | 0.1608 | 0.000479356 | 3.76295
POTEAU | 960 | P80 | 1 | 4.2 | 0.2 | 466.8 | 466.818 | 0.181592 | 0.000541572 | 4.25134
POTEAU | 961 | P81 | 1 | 4.8 | 0.2 | 543.5 | 543.548 | 0.21144 | 0.000630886 | 4.95245
POTEAU | 962 | P82 | 1 | 5.7 | 0.2 | 620.3 | 620.268 | 0.241284 | 0.000720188 | 5.65348
POTEAU | 962 | P90 | 1 | 5.7 | 0.2 | 620.3 | 620.268 | 0.241284 | 0.000720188 | 5.65348
POTEAU | 961 | P89 | 1 | 4.8 | 0.2 | 543.5 | 543.548 | 0.21144 | 0.000630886 | 4.95245
POTEAU | 960 | P88 | 1 | 4.2 | 0.2 | 466.8 | 466.818 | 0.181592 | 0.000541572 | 4.25134
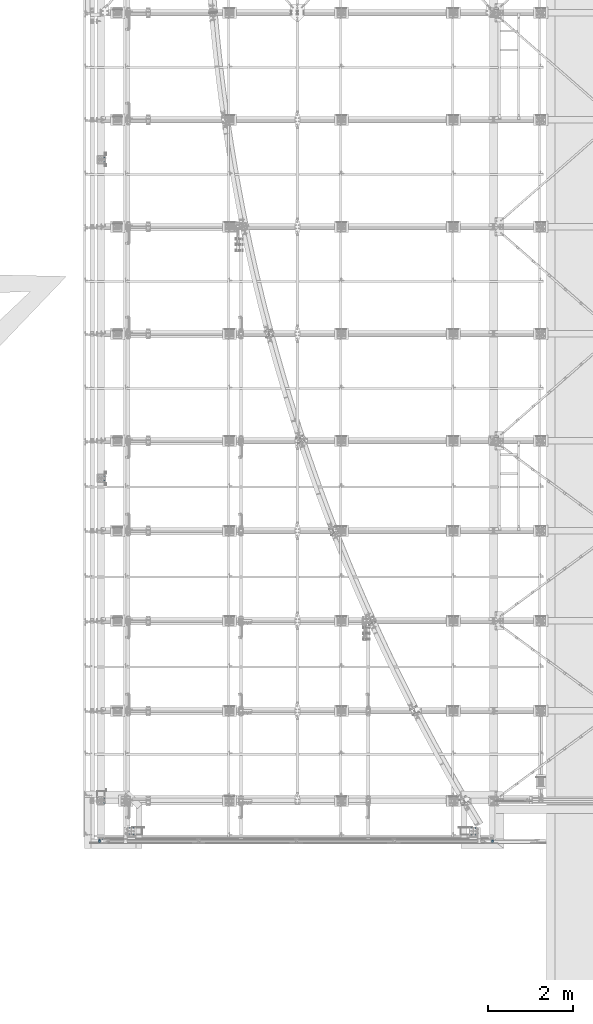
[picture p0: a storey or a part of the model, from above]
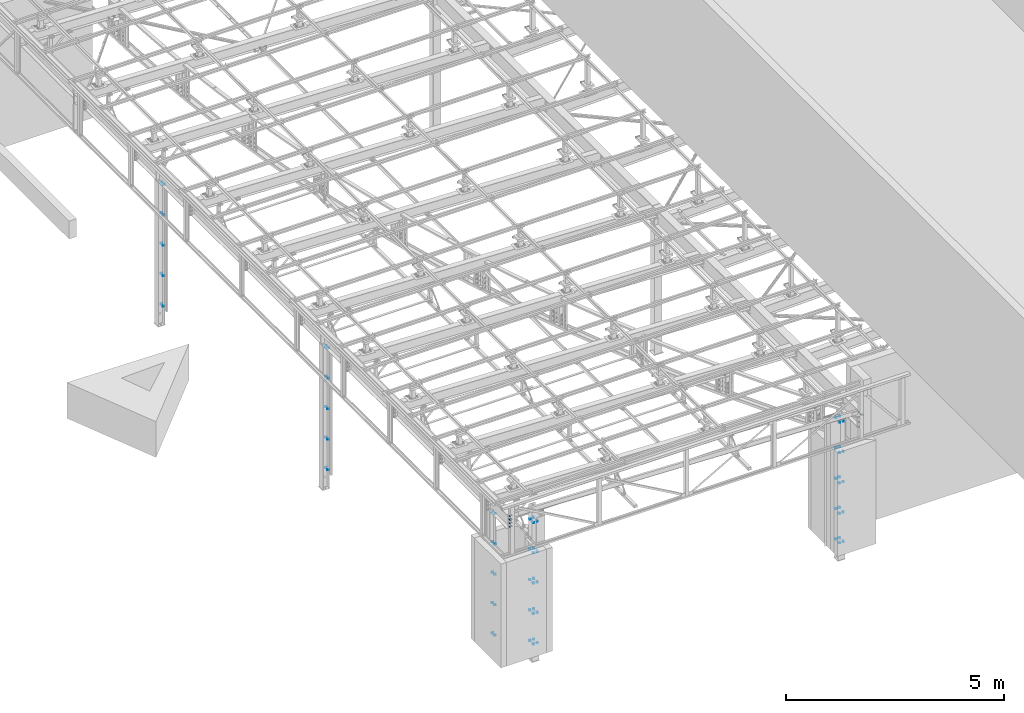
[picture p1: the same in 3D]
Properties of the parts of a building model (IFC2X3), part 6 of 13

# IfcColumn: TUBE-C-100*100*3 (183)
Name | Repère de pièce = Reference | Repère d'assemblage | Phase | Poids (kg) | Surface nette (m2) | Longueur (mm) | Length (mm) | OuterSurfaceArea (m2) | NetVolume (m3) | NetWeight (kg)
4 x POTEAU | 953 | P68 | 1 | 6.5 | 0.3 | 720.3 | 720.268 | 0.280184 | 0.000836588 | 6.56722
4 x POTEAU | 954 | P69 | 1 | 5.8 | 0.3 | 643.5 | 643.548 | 0.25034 | 0.000747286 | 5.86619
4 x POTEAU | 955 | P70 | 1 | 5.2 | 0.2 | 566.8 | 566.818 | 0.220492 | 0.000657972 | 5.16508

# IfcCovering: GALVA (3)
In: Undefined
Material: Undefined/Undefined

# IfcCovering: GALVANISE (2112)
In: Undefined
Material: Undefined/Undefined

# IfcCovering: GRENAILLE-PEINT (6898)
In: Undefined
Material: Undefined/Undefined

# IfcCovering: TOLGALVA (11)
In: Undefined
Material: Undefined/Undefined

# IfcElementAssembly (4667)
In: Undefined
Tekla Assemblages - sets with these values: 2
Name | PredefinedType | Poids Assemblage/Elément béton (kg) | Nom Assemblage/Elément béton | Repère Assemblage/Elément béton | Width (mm)
GOUSSET | RIGID_FRAME | 1.68941 | GOUSSET | G97(?) | 30
GOUSSET | RIGID_FRAME | 0.5769 | GOUSSET | G98(?) | 30
PL1000 | RIGID_FRAME | 25878.2 | PL1000 | G99 | 1000
IPE500 | RIGID_FRAME | 570.491 | IPE500 | P34 | 200
IPE450 | RIGID_FRAME | 1015.79 | IPE450 | K24 | 280
IPE500 | RIGID_FRAME | 1189.81 | IPE500 | P33 | 250
IPEA300 | RIGID_FRAME | 1274.18 | IPEA300 | N6 | 369.003
2 x IPE450 | RIGID_FRAME | 1015.79 | IPE450 | K22 | 280
2 x IPE500 | RIGID_FRAME | 629.138 | IPE500 | P35 | 250
2 x IPEA300 | RIGID_FRAME | 1298.77 | IPEA300 | N41 | 369.003
PL30 | RIGID_FRAME | 0 | PL30 | G86 | 0
PL30 | RIGID_FRAME | 1.42797 | PL30 | G90 | 30
PL30 | RIGID_FRAME | 1.99058 | PL30 | G87 | 30
PL30 | RIGID_FRAME | 0.85127 | PL30 | G93 | 30
10 x PL30 | RIGID_FRAME | 0.28845 | PL30 | G94 | 30
PL30 | RIGID_FRAME | 1.99145 | PL30 | G88 | 30
PL30 | RIGID_FRAME | 1.15381 | PL30 | G95 | 30
PL30 | RIGID_FRAME | 2.27797 | PL30 | G84 | 30
PL30 | RIGID_FRAME | 1.68756 | PL30 | G96 | 30
PL30 | RIGID_FRAME | 2.01916 | PL30 | G89 | 30
PL30 | RIGID_FRAME | 0.85886 | PL30 | G92 | 30
PL30 | RIGID_FRAME | 1.68941 | PL30 | G97 | 30
PL30 | RIGID_FRAME | 1.41321 | PL30 | G91 | 30
PL30 | RIGID_FRAME | 0.5769 | PL30 | G98 | 30
BLL300*60*1.5 | RIGID_FRAME | 12.664 | BLL300*60*1.5 | L120 | 60
TUBE-C-60*60*3 | RIGID_FRAME | 22.2483 | TUBE-C-60*60*3 | P52 | 190
TUBE-C-60*60*3 | RIGID_FRAME | 18.5763 | TUBE-C-60*60*3 | P53 | 120
3 x TUBE-C-70*70*3 | RIGID_FRAME | 7.38949 | TUBE-C-70*70*3 | L110 | 70
TUBE-C-70*70*3 | RIGID_FRAME | 13.7833 | TUBE-C-70*70*3 | L109 | 140
2 x TUBE-C-60*60*3 | RIGID_FRAME | 3.77221 | TUBE-C-60*60*3 | L41 | 60
TUBE-C-60*60*3 | RIGID_FRAME | 4.81312 | TUBE-C-60*60*3 | L39 | 60
TUBE-C-60*60*3 | RIGID_FRAME | 4.81312 | TUBE-C-60*60*3 | L38 | 60
TUBE-C-60*60*3 | RIGID_FRAME | 5.56735 | TUBE-C-60*60*3 | L40 | 60.0048
2 x L70*7 | RIGID_FRAME | 1.84475 | L70*7 | H43 | 70
UPN160 | RIGID_FRAME | 9.71673 | UPN160 | M15 | 215
UPN160 | RIGID_FRAME | 71.9971 | UPN160 | L113 | 71
UPN160 | RIGID_FRAME | 74.3364 | UPN160 | L114 | 178.17
2 x L60*6 | RIGID_FRAME | 0.81365 | L60*6 | H16 | 60
FPL370*6 | RIGID_FRAME | 3.38661 | FPL370*6 | H48 | 370
2 x L80*8 | RIGID_FRAME | 0.96555 | L80*8 | H62 | 80
UPN160 | RIGID_FRAME | 78.0495 | UPN160 | P132 | 225
2 x L80*8 | RIGID_FRAME | 0.96555 | L80*8 | H60 | 80
2 x L80*8 | RIGID_FRAME | 0.96555 | L80*8 | H57 | 80
UPN160 | RIGID_FRAME | 58.9386 | UPN160 | P133 | 200
UPN160 | RIGID_FRAME | 6.82008 | UPN160 | M23 | 65
BLL100*50*2 | RIGID_FRAME | 4.6472 | BLL100*50*2 | L121 | 50
BLL300*60*1.5 | RIGID_FRAME | 14.4102 | BLL300*60*1.5 | L119 | 60.0043
PL300*250 | RIGID_FRAME | 3893.51 | PL300*250 | Z59 | 250
PL200*300 | RIGID_FRAME | 3053.94 | PL200*300 | Z13 | 200
TUBE-C-80*80*3 | RIGID_FRAME | 10.6845 | TUBE-C-80*80*3 | S88 | 110.276
4 x TUBE-C-80*80*3 | RIGID_FRAME | 7.72159 | TUBE-C-80*80*3 | S8 | 180
TUBE-C-80*80*3 | RIGID_FRAME | 9.53471 | TUBE-C-80*80*3 | S87 | 110.276
TUBE-C-80*80*3 | RIGID_FRAME | 37.4375 | TUBE-C-80*80*3 | L82 | 150
TUBE-C-80*80*3 | RIGID_FRAME | 35.3175 | TUBE-C-80*80*3 | L83 | 150
2 x TUBE-C-80*80*3 | RIGID_FRAME | 31.7744 | TUBE-C-80*80*3 | L84 | 150
TUBE-C-80*80*3 | RIGID_FRAME | 38.7459 | TUBE-C-80*80*3 | L86 | 150
TUBE-C-80*80*3 | RIGID_FRAME | 28.7706 | TUBE-C-80*80*3 | L81 | 150
2 x TUBE-C-80*80*3 | RIGID_FRAME | 37.5637 | TUBE-C-80*80*3 | L85 | 150
TUBE-C-80*80*3 | RIGID_FRAME | 36.5817 | TUBE-C-80*80*3 | L87 | 150
20 x L40*4 | RIGID_FRAME | 1.15841 | L40*4 | W5 | 40
L60*6 | RIGID_FRAME | 14.2932 | L60*6 | L17 | 60
60 x L80*8 | RIGID_FRAME | 1.0621 | L80*8 | H56 | 80
10 x PL240*8 | RIGID_FRAME | 2.24824 | PL240*8 | H42 | 77.9981
2 x TUBE-C-80*80*3 | RIGID_FRAME | 7.72159 | TUBE-C-80*80*3 | S10 | 180
10 x L60*6 | RIGID_FRAME | 3.1919 | L60*6 | W1 | 60
TUBE-C-80*80*3 | RIGID_FRAME | 7.72159 | TUBE-C-80*80*3 | S9 | 180
3 x TUBE-C-80*80*3 | RIGID_FRAME | 6.60592 | TUBE-C-80*80*3 | S5 | 125.246
3 x TUBE-C-80*80*3 | RIGID_FRAME | 7.72159 | TUBE-C-80*80*3 | S7 | 180
3 x L60*6 | RIGID_FRAME | 14.7271 | L60*6 | L16 | 60
3 x TUBE-C-80*80*3 | RIGID_FRAME | 6.60592 | TUBE-C-80*80*3 | S6 | 125.246
3 x L60*6 | RIGID_FRAME | 15.4052 | L60*6 | L13 | 60
L60*6 | RIGID_FRAME | 15.1882 | L60*6 | L14 | 60
3 x L70*7 | RIGID_FRAME | 1.5127 | L70*7 | H40 | 70
TUBE-C-80*80*3 | RIGID_FRAME | 5.63396 | TUBE-C-80*80*3 | S4 | 110.213
2 x L60*6 | RIGID_FRAME | 15.6221 | L60*6 | L15 | 60
TUBE-C-80*80*3 | RIGID_FRAME | 5.63396 | TUBE-C-80*80*3 | S3 | 110.213
HEA100 | RIGID_FRAME | 30.7721 | HEA100 | L32 | 160
UPN100 | RIGID_FRAME | 26.4066 | UPN100 | L53 | 200
HEA100 | RIGID_FRAME | 22.2927 | HEA100 | L117 | 110
L40*4 | RIGID_FRAME | 3.90053 | L40*4 | W4 | 40
2 x UPN100 | RIGID_FRAME | 42.8881 | UPN100 | L54 | 56
PL3*3600 | RIGID_FRAME | 81.5584 | PL3*3600 | F2 | 325
PL3*3600 | RIGID_FRAME | 73.6738 | PL3*3600 | F3 | 260
PL3*3600 | RIGID_FRAME | 74.776 | PL3*3600 | F1 | 285
2 x FPL3*3600 | RIGID_FRAME | 41.3726 | FPL3*3600 | F4 | 3600
4 x L40*4 | RIGID_FRAME | 10.0336 | L40*4 | W3 | 40
2 x HEA160 | RIGID_FRAME | 80.6284 | HEA160 | E3 | 260
8 x TUBE-C-100*100*4 | RIGID_FRAME | 16.2494 | TUBE-C-100*100*4 | E4 | 100
2 x TUBE-C-100*100*4 | RIGID_FRAME | 22.5944 | TUBE-C-100*100*4 | E5 | 100
TUBE-C-70*70*3 | RIGID_FRAME | 11.2972 | TUBE-C-70*70*3 | M18 | 115
TUBE-C-150*150*4 | RIGID_FRAME | 154.184 | TUBE-C-150*150*4 | L7 | 150
TUBE-C-150*150*4 | RIGID_FRAME | 154.312 | TUBE-C-150*150*4 | L6 | 150
14 x PL50*5 | RIGID_FRAME | 0.09812 | PL50*5 | Y4 | 5
2 x L40*4 | RIGID_FRAME | 1.27176 | L40*4 | W2 | 40
HEA180 | RIGID_FRAME | 154.726 | HEA180 | P127 | 319.845
2 x TUBE-C-70*70*3 | RIGID_FRAME | 14.914 | TUBE-C-70*70*3 | M20 | 70
TUBE-C-70*70*3 | RIGID_FRAME | 73.3798 | TUBE-C-70*70*3 | L18 | 1813
8 x L80*8 | RIGID_FRAME | 1.35177 | L80*8 | H68 | 80
TUBE-C-70*70*3 | RIGID_FRAME | 61.0457 | TUBE-C-70*70*3 | L19 | 808
TUBE-C-70*70*3 | RIGID_FRAME | 11.1452 | TUBE-C-70*70*3 | M21 | 427.881
2 x L60*6 | RIGID_FRAME | 1.79004 | L60*6 | H15 | 60
2 x L60*6 | RIGID_FRAME | 1.79004 | L60*6 | H14 | 60
2 x TUBE-C-70*70*3 | RIGID_FRAME | 24.3832 | TUBE-C-70*70*3 | M19 | 70
61 x L80*8 | RIGID_FRAME | 0.869 | L80*8 | C136 | 18
58 x L80*8 | RIGID_FRAME | 0.869 | L80*8 | H63 | 18
L70*7 | RIGID_FRAME | 2.10302 | L70*7 | H41 | 70
2 x L50*5 | RIGID_FRAME | 8.28633 | L50*5 | H34 | 50
TUBE-C-70*70*3 | RIGID_FRAME | 11.2972 | TUBE-C-70*70*3 | M17 | 115
TUBE-C-70*70*3 | RIGID_FRAME | 11.1452 | TUBE-C-70*70*3 | M22 | 427.881
L60*6 | RIGID_FRAME | 1.8714 | L60*6 | H13 | 60
L60*6 | RIGID_FRAME | 25.2558 | L60*6 | M6 | 60
57 x L60*6 | RIGID_FRAME | 1.43745 | L60*6 | H17 | 60
57 x L60*6 | RIGID_FRAME | 1.43745 | L60*6 | H18 | 60
2 x HEA100 | RIGID_FRAME | 14.976 | HEA100 | E6 | 250
2 x HEA100 | RIGID_FRAME | 31.0565 | HEA100 | E7 | 250
8 x L80*8 | RIGID_FRAME | 1.15866 | L80*8 | H61 | 80
UPF-100*50*4 | RIGID_FRAME | 38.7953 | UPF-100*50*4 | U7 | 1110
UPF-100*50*4 | RIGID_FRAME | 42.3322 | UPF-100*50*4 | U6 | 910
6 x PL120*12 | RIGID_FRAME | 6.25154 | PL120*12 | E1 | 100
2 x PL80*8 | RIGID_FRAME | 0.58278 | PL80*8 | H44 | 8
TUBE-C-70*70*3 | RIGID_FRAME | 16.5743 | TUBE-C-70*70*3 | L79 | 70
34 x L60*6 | RIGID_FRAME | 4.21472 | L60*6 | M7 | 60
TUBE-C-70*70*3 | RIGID_FRAME | 16.5743 | TUBE-C-70*70*3 | L76 | 70
TUBE-C-70*70*3 | RIGID_FRAME | 16.1567 | TUBE-C-70*70*3 | L78 | 70
TUBE-C-70*70*3 | RIGID_FRAME | 15.3962 | TUBE-C-70*70*3 | L77 | 70
7 x L60*6 | RIGID_FRAME | 3.83501 | L60*6 | M8 | 60
L60*6 | RIGID_FRAME | 3.83501 | L60*6 | M10 | 60
12 x L60*6 | RIGID_FRAME | 4.21472 | L60*6 | M11 | 60
12 x TUBE-C-70*70*3 | RIGID_FRAME | 15.9463 | TUBE-C-70*70*3 | L72 | 70
TUBE-C-70*70*3 | RIGID_FRAME | 15.4276 | TUBE-C-70*70*3 | L75 | 70
TUBE-C-70*70*3 | RIGID_FRAME | 15.4276 | TUBE-C-70*70*3 | L74 | 70
4 x TUBE-C-70*70*3 | RIGID_FRAME | 32.7607 | TUBE-C-70*70*3 | L61 | 70
TUBE-C-70*70*3 | RIGID_FRAME | 15.5098 | TUBE-C-70*70*3 | L73 | 70
TUBE-C-70*70*3 | RIGID_FRAME | 13.9364 | TUBE-C-70*70*3 | L71 | 70
3 x TUBE-C-70*70*3 | RIGID_FRAME | 14.4391 | TUBE-C-70*70*3 | L70 | 70
TUBE-C-70*70*3 | RIGID_FRAME | 33.791 | TUBE-C-70*70*3 | L65 | 70
TUBE-C-70*70*3 | RIGID_FRAME | 31.078 | TUBE-C-70*70*3 | L64 | 70
13 x L60*6 | RIGID_FRAME | 0.73771 | L60*6 | M9 | 60
2 x TUBE-C-70*70*3 | RIGID_FRAME | 35.0714 | TUBE-C-70*70*3 | L62 | 70
TUBE-C-70*70*3 | RIGID_FRAME | 30.45 | TUBE-C-70*70*3 | L63 | 70
TUBE-C-70*70*3 | RIGID_FRAME | 31.2535 | TUBE-C-70*70*3 | L60 | 70
TUBE-C-70*70*3 | RIGID_FRAME | 29.7463 | TUBE-C-70*70*3 | L59 | 70
TUBE-C-70*70*3 | RIGID_FRAME | 30.1137 | TUBE-C-70*70*3 | L58 | 70
TUBE-C-70*70*3 | RIGID_FRAME | 31.7653 | TUBE-C-70*70*3 | L57 | 70
TUBE-C-70*70*3 | RIGID_FRAME | 14.0934 | TUBE-C-70*70*3 | L69 | 70
TUBE-C-70*70*3 | RIGID_FRAME | 15.1924 | TUBE-C-70*70*3 | L68 | 70
TUBE-C-70*70*3 | RIGID_FRAME | 15.6414 | TUBE-C-70*70*3 | L67 | 70
TUBE-C-70*70*3 | RIGID_FRAME | 15.7168 | TUBE-C-70*70*3 | L66 | 70
TUBE-C-70*70*3 | RIGID_FRAME | 19.2179 | TUBE-C-70*70*3 | L56 | 70
L80*8 | RIGID_FRAME | 1.24556 | L80*8 | H64 | 80
L80*8 | RIGID_FRAME | 1.24556 | L80*8 | H65 | 80
L80*8 | RIGID_FRAME | 1.01383 | L80*8 | H66 | 80
L80*8 | RIGID_FRAME | 1.01383 | L80*8 | H67 | 80
8 x L80*8 | RIGID_FRAME | 1.35177 | L80*8 | H69 | 80
16 x PL120*12 | RIGID_FRAME | 6.92978 | PL120*12 | E2 | 100
2 x UPF-100*50*4 | RIGID_FRAME | 14.4088 | UPF-100*50*4 | U10 | 50
2 x UPF-100*50*4 | RIGID_FRAME | 14.4088 | UPF-100*50*4 | U9 | 50
8 x PL60*6 | RIGID_FRAME | 0.49455 | PL60*6 | H9 | 6
4 x UPF-100*50*4 | RIGID_FRAME | 2.95409 | UPF-100*50*4 | U8 | 50
8 x FPL60*5 | RIGID_FRAME | 0.50633 | FPL60*5 | H93 | 60
2 x UPF-100*50*4 | RIGID_FRAME | 31.9828 | UPF-100*50*4 | U11 | 410
4 x UPF-100*50*4 | RIGID_FRAME | 32.3445 | UPF-100*50*4 | U12 | 410
UPF-100*50*4 | RIGID_FRAME | 32.9474 | UPF-100*50*4 | U13 | 509.997
3 x TUBE-C-60*60*3 | RIGID_FRAME | 10.2261 | TUBE-C-60*60*3 | W6 | 70.007
UPN180 | RIGID_FRAME | 102.365 | UPN180 | K93 | 75
HEA120 | RIGID_FRAME | 36.6829 | HEA120 | L3 | 210
HEA120 | RIGID_FRAME | 31.7362 | HEA120 | L1 | 210
HEA120 | RIGID_FRAME | 26.7897 | HEA120 | L2 | 210
12 x L100*10 | RIGID_FRAME | 3.16512 | L100*10 | H73 | 100
L100*10 | RIGID_FRAME | 3.16512 | L100*10 | H72 | 100
IPEA300 | RIGID_FRAME | 1120.72 | IPEA300 | N43 | 437.997
TUBE-C-60*60*3 | RIGID_FRAME | 10.2806 | TUBE-C-60*60*3 | L46 | 120
TUBE-C-70*70*3 | RIGID_FRAME | 26.5975 | TUBE-C-70*70*3 | W7 | 80.0002
IPEA300 | RIGID_FRAME | 82.069 | IPEA300 | K50 | 160
IPEA300 | RIGID_FRAME | 91.7496 | IPEA300 | K94 | 245.12
UPN120 | RIGID_FRAME | 66.5779 | UPN120 | L116 | 600
UPN120 | RIGID_FRAME | 478.861 | UPN120 | L115 | 600
IPEA300 | RIGID_FRAME | 26.9664 | IPEA300 | K20 | 160
2 x IPE120 | RIGID_FRAME | 60.2178 | IPE120 | K106 | 64
20 x L60*6 | RIGID_FRAME | 0.45565 | L60*6 | H19 | 60
IPEA300 | RIGID_FRAME | 51.2633 | IPEA300 | K51 | 160
IPEA300 | RIGID_FRAME | 69.1808 | IPEA300 | K53 | 160
2 x IPE120 | RIGID_FRAME | 40.0586 | IPE120 | K107 | 64
IPEA300 | RIGID_FRAME | 77.1923 | IPEA300 | K52 | 160
IPE120 | RIGID_FRAME | 40.0482 | IPE120 | K107 | 64
UPN120 | RIGID_FRAME | 469.107 | UPN120 | L80 | 600
TUBE-C-90*90*3 | RIGID_FRAME | 94.7853 | TUBE-C-90*90*3 | L106 | 155
IPEA300 | RIGID_FRAME | 418.411 | IPEA300 | K4 | 150
UPN160 | RIGID_FRAME | 62.3494 | UPN160 | M16 | 245
UPN160 | RIGID_FRAME | 71.2529 | UPN160 | L111 | 65
UPN160 | RIGID_FRAME | 72.3833 | UPN160 | L112 | 65
UPN160 | RIGID_FRAME | 72.3644 | UPN160 | L112 | 65
IPEA300 | RIGID_FRAME | 263.219 | IPEA300 | P119 | 309.803
IPE400 | RIGID_FRAME | 433.49 | IPE400 | P5 | 200
4 x IPEA300 | RIGID_FRAME | 420.158 | IPEA300 | K42 | 150
IPE400 | RIGID_FRAME | 433.49 | IPE400 | P39 | 200
2 x L50*5 | RIGID_FRAME | 13.4737 | L50*5 | C43 | 50
PL8 | RIGID_FRAME | 6.72677 | PL8 | G6 | 8
4 x L70*7 | RIGID_FRAME | 18.5361 | L70*7 | C127 | 70
2 x PL8 | RIGID_FRAME | 3.33836 | PL8 | G8 | 8
IPEA300 | RIGID_FRAME | 429.982 | IPEA300 | K25 | 150
2 x PL8 | RIGID_FRAME | 9.69651 | PL8 | G11 | 8
IPEA300 | RIGID_FRAME | 231.965 | IPEA300 | P114 | 180
PL8 | RIGID_FRAME | 4.77768 | PL8 | G13 | 8
2 x PL8 | RIGID_FRAME | 2.89301 | PL8 | G15 | 8
L50*5 | RIGID_FRAME | 13.4847 | L50*5 | C42 | 50
3 x PL8 | RIGID_FRAME | 2.63006 | PL8 | G20 | 8
3 x IPE330 | RIGID_FRAME | 564.866 | IPE330 | K30 | 160
3 x L70*7 | RIGID_FRAME | 17.8572 | L70*7 | C122 | 70
IPE400 | RIGID_FRAME | 773.672 | IPE400 | K1 | 420
L70*7 | RIGID_FRAME | 17.8203 | L70*7 | C123 | 70
L70*7 | RIGID_FRAME | 18.5582 | L70*7 | C124 | 70
2 x L70*7 | RIGID_FRAME | 18.5951 | L70*7 | C125 | 70
2 x L70*7 | RIGID_FRAME | 18.632 | L70*7 | C126 | 70
IPE330 | RIGID_FRAME | 564.686 | IPE330 | K31 | 160
14 x L70*7 | RIGID_FRAME | 18.6689 | L70*7 | C104 | 70
26 x PL8 | RIGID_FRAME | 2.57354 | PL8 | G18 | 8
PL8 | RIGID_FRAME | 2.63006 | PL8 | G19 | 8
IPE330 | RIGID_FRAME | 564.866 | IPE330 | K32 | 160
L50*5 | RIGID_FRAME | 13.8023 | L50*5 | C32 | 50
PL8 | RIGID_FRAME | 9.49466 | PL8 | G23 | 8
L50*5 | RIGID_FRAME | 14.0773 | L50*5 | C31 | 50
PL8 | RIGID_FRAME | 9.51463 | PL8 | G22 | 8
PL8 | RIGID_FRAME | 2.93801 | PL8 | G16 | 8
IPE330 | RIGID_FRAME | 564.866 | IPE330 | K29 | 160
PL8 | RIGID_FRAME | 6.82104 | PL8 | G7 | 8
PL8 | RIGID_FRAME | 9.30651 | PL8 | G68 | 8
L50*5 | RIGID_FRAME | 13.4926 | L50*5 | C44 | 50
IPEA300 | RIGID_FRAME | 797.007 | IPEA300 | N39 | 556.478
IPEA300 | RIGID_FRAME | 279.009 | IPEA300 | P113 | 463.798
IPE200 | RIGID_FRAME | 150.494 | IPE200 | P21 | 180
PL140*10 | RIGID_FRAME | 4.47264 | PL140*10 | H1 | 88.95
14 x L100*10 | RIGID_FRAME | 3.16512 | L100*10 | H71 | 100
IPEA300 | RIGID_FRAME | 229.148 | IPEA300 | P121 | 180
IPEA300 | RIGID_FRAME | 234.781 | IPEA300 | P120 | 180
IPEA300 | RIGID_FRAME | 979.089 | IPEA300 | N42 | 369.003
IPE400 | RIGID_FRAME | 443.508 | IPE400 | P1 | 218.09
PL20*300 | RIGID_FRAME | 22.7587 | PL20*300 | H76 | 150
PL12*80 | RIGID_FRAME | 2.41152 | PL12*80 | H77 | 12
2 x PL10 | RIGID_FRAME | 5.67839 | PL10 | H2 | 146.95
UPF-100*50*4 | RIGID_FRAME | 16.368 | UPF-100*50*4 | S44 | 100
UPF-100*50*4 | RIGID_FRAME | 34.2834 | UPF-100*50*4 | S65 | 100
30 x L60*6 | RIGID_FRAME | 1.13911 | L60*6 | H20 | 60
2 x UPF-100*50*4 | RIGID_FRAME | 33.2033 | UPF-100*50*4 | S66 | 100
2 x UPF-100*50*4 | RIGID_FRAME | 31.5454 | UPF-100*50*4 | S67 | 100
UPF-100*50*4 | RIGID_FRAME | 26.7073 | UPF-100*50*4 | S68 | 100
14 x TUBE-C-100*100*3 | RIGID_FRAME | 14.9713 | TUBE-C-100*100*3 | P76 | 220.255
UPN100 | RIGID_FRAME | 548.027 | UPN100 | L52 | 1410
UPN160 | RIGID_FRAME | 96.7474 | UPN160 | S90 | 147.5
UPN160 | RIGID_FRAME | 96.7474 | UPN160 | S89 | 147.502
UPN160 | RIGID_FRAME | 150.257 | UPN160 | S92 | 147.5
UPN160 | RIGID_FRAME | 150.257 | UPN160 | S91 | 147.502
UPN160 | RIGID_FRAME | 47.8576 | UPN160 | S94 | 147.5
UPN160 | RIGID_FRAME | 47.8576 | UPN160 | S93 | 147.5
3 x IPE220 | RIGID_FRAME | 64.6299 | IPE220 | S95 | 110
IPE220 | RIGID_FRAME | 100.484 | IPE220 | S97 | 110
8 x L60*6 | RIGID_FRAME | 0.92214 | L60*6 | H28 | 60
IPE220 | RIGID_FRAME | 100.878 | IPE220 | S98 | 110
IPE220 | RIGID_FRAME | 129.653 | IPE220 | S96 | 110
12 x L70*50*6 | RIGID_FRAME | 1.62023 | L70*50*6 | H92 | 50
HEA160 | RIGID_FRAME | 15.7063 | HEA160 | H83 | 253.633
12 x HEA100 | RIGID_FRAME | 4.99258 | HEA100 | H79 | 100
HEA160 | RIGID_FRAME | 16.9985 | HEA160 | H84 | 258.955
HEA160 | RIGID_FRAME | 17.7362 | HEA160 | H86 | 160.33
HEA160 | RIGID_FRAME | 19.3548 | HEA160 | H87 | 160.341
HEA160 | RIGID_FRAME | 20.4555 | HEA160 | H89 | 160.348
HEA160 | RIGID_FRAME | 20.8217 | HEA160 | H82 | 160.7
UPF-100*50*4 | RIGID_FRAME | 34.756 | UPF-100*50*4 | U5 | 459.997
UPF-100*50*4 | RIGID_FRAME | 36.2632 | UPF-100*50*4 | U1 | 410.003
UPF-80*50*4 | RIGID_FRAME | 257.354 | UPF-80*50*4 | U16 | 510.001
UPF-80*50*4 | RIGID_FRAME | 300.696 | UPF-80*50*4 | U15 | 510.001
UPF-80*50*4 | RIGID_FRAME | 315.548 | UPF-80*50*4 | U14 | 510.001
HEA180 | RIGID_FRAME | 147.815 | HEA180 | P130 | 200
HEA180 | RIGID_FRAME | 158.056 | HEA180 | P131 | 200
9 x HEA100 | RIGID_FRAME | 27.0417 | HEA100 | L118 | 120
2 x UPN100 | RIGID_FRAME | 81.8207 | UPN100 | L49 | 56
2 x UPN100 | RIGID_FRAME | 73.2208 | UPN100 | L50 | 56
2 x UPN100 | RIGID_FRAME | 55.7217 | UPN100 | L51 | 56
UPN200 | RIGID_FRAME | 194.542 | UPN200 | L35 | 800
UPN200 | RIGID_FRAME | 187.907 | UPN200 | L34 | 930
UPN200 | RIGID_FRAME | 194.916 | UPN200 | L33 | 980
UPN200 | RIGID_FRAME | 162.171 | UPN200 | L36 | 870
UPN200 | RIGID_FRAME | 181.629 | UPN200 | L37 | 980
3 x HEA180 | RIGID_FRAME | 149.292 | HEA180 | P125 | 200
HEA180 | RIGID_FRAME | 134.167 | HEA180 | P128 | 200
UPN120 | RIGID_FRAME | 12.7963 | UPN120 | S99 | 115
TUBE-C-120*120*4 | RIGID_FRAME | 31.6648 | TUBE-C-120*120*4 | S2 | 320
10 x TUBE-C-120*120*4 | RIGID_FRAME | 32.9455 | TUBE-C-120*120*4 | S1 | 320
2 x UPN120 | RIGID_FRAME | 63.1819 | UPN120 | S106 | 55
2 x UPN120 | RIGID_FRAME | 63.6557 | UPN120 | S105 | 55
2 x UPN120 | RIGID_FRAME | 33.4559 | UPN120 | S104 | 55
2 x UPN120 | RIGID_FRAME | 61.1201 | UPN120 | S103 | 55
2 x UPN120 | RIGID_FRAME | 60.4929 | UPN120 | S102 | 55
8 x UPN120 | RIGID_FRAME | 67.5257 | UPN120 | S101 | 55
2 x UPN120 | RIGID_FRAME | 32.8287 | UPN120 | S100 | 55
2 x UPN120 | RIGID_FRAME | 42.3504 | UPN120 | S107 | 55
IPEA300 | RIGID_FRAME | 732.357 | IPEA300 | N18 | 309.005
IPEA300 | RIGID_FRAME | 865.451 | IPEA300 | N46 | 354.003
IPEA300 | RIGID_FRAME | 1369.05 | IPEA300 | N44 | 354.003
IPEA300 | RIGID_FRAME | 1052.81 | IPEA300 | N45 | 354.003
IPEA300 | RIGID_FRAME | 1331.16 | IPEA300 | N49 | 354.003
IPE500 | RIGID_FRAME | 839.275 | IPE500 | N1 | 200
IPE500 | RIGID_FRAME | 973.081 | IPE500 | N2 | 200
IPE500 | RIGID_FRAME | 864.194 | IPE500 | N4 | 220
IPE500 | RIGID_FRAME | 922.998 | IPE500 | N3 | 200
L70*7 | RIGID_FRAME | 6.14671 | L70*7 | L20 | 70
L80*8 | RIGID_FRAME | 1.44832 | L80*8 | H59 | 80
PL8 | RIGID_FRAME | 10.0751 | PL8 | G37 | 8
IPEA300 | RIGID_FRAME | 424.295 | IPEA300 | K19 | 150
L50*5 | RIGID_FRAME | 22.9411 | L50*5 | C46 | 50
PL8 | RIGID_FRAME | 2.19791 | PL8 | G63 | 8
IPEA300 | RIGID_FRAME | 424.406 | IPEA300 | K2 | 150
IPE450 | RIGID_FRAME | 1015.79 | IPE450 | K23 | 280
L50*5 | RIGID_FRAME | 23.3179 | L50*5 | C45 | 50
L50*5 | RIGID_FRAME | 23.1966 | L50*5 | C47 | 50
L50*5 | RIGID_FRAME | 23.4593 | L50*5 | C48 | 50
L70*7 | RIGID_FRAME | 18.9124 | L70*7 | C128 | 70
13 x PL8 | RIGID_FRAME | 2.02629 | PL8 | G34 | 8
17 x FPL6*120 | RIGID_FRAME | 0.79304 | FPL6*120 | H49 | 120
16 x L70*7 | RIGID_FRAME | 0.88548 | L70*7 | H39 | 70
IPE500 | RIGID_FRAME | 615.745 | IPE500 | P30 | 345
IPEA300 | RIGID_FRAME | 424.406 | IPEA300 | K17 | 150
8 x L70*7 | RIGID_FRAME | 37.6329 | L70*7 | C117 | 70
4 x L50*5 | RIGID_FRAME | 13.0802 | L50*5 | C35 | 50
IPE500 | RIGID_FRAME | 609.507 | IPE500 | P29 | 250
4 x PL8 | RIGID_FRAME | 2.02629 | PL8 | G35 | 8
44 x L50*5 | RIGID_FRAME | 13.5688 | L50*5 | C25 | 50
34 x IPEA300 | RIGID_FRAME | 424.406 | IPEA300 | K16 | 150
30 x PL8 | RIGID_FRAME | 9.12418 | PL8 | G42 | 8
42 x L50*5 | RIGID_FRAME | 13.8326 | L50*5 | C28 | 50
23 x PL8 | RIGID_FRAME | 6.37364 | PL8 | G48 | 8
26 x IPEA300 | RIGID_FRAME | 424.406 | IPEA300 | K14 | 150
14 x L70*7 | RIGID_FRAME | 37.1164 | L70*7 | C118 | 70
4 x L70*7 | RIGID_FRAME | 37.6329 | L70*7 | C119 | 70
4 x IPE450 | RIGID_FRAME | 1015.69 | IPE450 | K21 | 275
11 x L50*5 | RIGID_FRAME | 13.7007 | L50*5 | C36 | 50
4 x L70*7 | RIGID_FRAME | 34.091 | L70*7 | C116 | 70
20 x L50*5 | RIGID_FRAME | 13.1744 | L50*5 | C24 | 50
16 x L50*5 | RIGID_FRAME | 12.9106 | L50*5 | C30 | 50
4 x L70*7 | RIGID_FRAME | 33.5744 | L70*7 | C115 | 70
8 x PL8 | RIGID_FRAME | 6.37364 | PL8 | G47 | 8
4 x L70*7 | RIGID_FRAME | 34.9765 | L70*7 | C113 | 70
12 x L50*5 | RIGID_FRAME | 13.7085 | L50*5 | C22 | 50
4 x PL8 | RIGID_FRAME | 9.43281 | PL8 | G40 | 8
12 x L50*5 | RIGID_FRAME | 13.4447 | L50*5 | C23 | 50
20 x L70*7 | RIGID_FRAME | 17.562 | L70*7 | C103 | 70
4 x PL8 | RIGID_FRAME | 8.43791 | PL8 | G9 | 8
16 x L50*5 | RIGID_FRAME | 13.4447 | L50*5 | C54 | 50
4 x IPEA300 | RIGID_FRAME | 424.295 | IPEA300 | K12 | 150
IPEA300 | RIGID_FRAME | 745.386 | IPEA300 | N15 | 437.999
2 x L50*5 | RIGID_FRAME | 13.4447 | L50*5 | C70 | 50
6 x IPEA300 | RIGID_FRAME | 424.406 | IPEA300 | K11 | 150
4 x PL8 | RIGID_FRAME | 6.82104 | PL8 | G2 | 8
4 x L50*5 | RIGID_FRAME | 13.5954 | L50*5 | C56 | 50
11 x L50*5 | RIGID_FRAME | 13.7949 | L50*5 | C29 | 50
8 x PL8 | RIGID_FRAME | 9.76032 | PL8 | G41 | 8
223 x PL60*8 | RIGID_FRAME | 0.22608 | PL60*8 | Y2 | 8
542 x PL50*8 | RIGID_FRAME | 0.157 | PL50*8 | Y3 | 8
IPE400 | RIGID_FRAME | 521.093 | IPE400 | N19 | 200
IPE400 | RIGID_FRAME | 594.553 | IPE400 | N20 | 200
2 x PL60*10 | RIGID_FRAME | 0.66882 | PL60*10 | H7 | 10
IPE400 | RIGID_FRAME | 952.744 | IPE400 | N21 | 200
HEA180 | RIGID_FRAME | 154.726 | HEA180 | P126 | 319.845
IPE400 | RIGID_FRAME | 613.19 | IPE400 | N22 | 180
4 x L60*6 | RIGID_FRAME | 23.9229 | L60*6 | V1 | 60
PL8 | RIGID_FRAME | 4.80149 | PL8 | G67 | 8
HEA180 | RIGID_FRAME | 135.815 | HEA180 | P129 | 250
3 x HEA200 | RIGID_FRAME | 160.113 | HEA200 | P124 | 250
IPEA300 | RIGID_FRAME | 421.98 | IPEA300 | K101 | 210
IPEA300 | RIGID_FRAME | 431.609 | IPEA300 | K102 | 210
UPN160 | RIGID_FRAME | 248.727 | UPN160 | K103 | 190.001
HEA160 | RIGID_FRAME | 16.7859 | HEA160 | H85 | 160.324
HEA160 | RIGID_FRAME | 19.0878 | HEA160 | H91 | 247.748
HEA160 | RIGID_FRAME | 19.9871 | HEA160 | H88 | 160.345
HEA160 | RIGID_FRAME | 20.7647 | HEA160 | H90 | 160.35
HEA160 | RIGID_FRAME | 20.9129 | HEA160 | H81 | 160.35
IPEA300 | RIGID_FRAME | 341.696 | IPEA300 | K75 | 150
IPEA300 | RIGID_FRAME | 341.696 | IPEA300 | K74 | 150
IPEA300 | RIGID_FRAME | 341.696 | IPEA300 | K81 | 150
IPEA300 | RIGID_FRAME | 341.696 | IPEA300 | K80 | 150
IPEA300 | RIGID_FRAME | 341.696 | IPEA300 | K79 | 150
IPEA300 | RIGID_FRAME | 341.696 | IPEA300 | K78 | 150
IPEA300 | RIGID_FRAME | 341.696 | IPEA300 | K77 | 150
IPEA300 | RIGID_FRAME | 341.696 | IPEA300 | K76 | 150
IPEA300 | RIGID_FRAME | 344.639 | IPEA300 | K84 | 150
IPEA300 | RIGID_FRAME | 341.696 | IPEA300 | K73 | 150
IPEA300 | RIGID_FRAME | 344.639 | IPEA300 | K85 | 150
9 x HEA100 | RIGID_FRAME | 4.99258 | HEA100 | H80 | 100
2 x L70*7 | RIGID_FRAME | 1.18066 | L70*7 | H37 | 70
IPE240 | RIGID_FRAME | 286.982 | IPE240 | K86 | 150
2 x PL200*20 | RIGID_FRAME | 22.5756 | PL200*20 | H78 | 234.611
2 x TUBE-168.3*4.5 | RIGID_FRAME | 186.428 | TUBE-168.3*4.5 | B18 | 180.005
8 x L50*5 | RIGID_FRAME | 12.267 | L50*5 | C71 | 50
4 x L70*7 | RIGID_FRAME | 18.4383 | L70*7 | C110 | 70
4 x PL8 | RIGID_FRAME | 2.41204 | PL8 | G17 | 8
2 x PL8 | RIGID_FRAME | 7.81314 | PL8 | G58 | 8
2 x PL8 | RIGID_FRAME | 7.66486 | PL8 | G59 | 8
3 x PL8 | RIGID_FRAME | 1.79922 | PL8 | G60 | 8
2 x L70*7 | RIGID_FRAME | 19.0993 | L70*7 | C129 | 70
IPEA300 | RIGID_FRAME | 341.696 | IPEA300 | K82 | 150
L70*7 | RIGID_FRAME | 19.0994 | L70*7 | C129 | 70
2 x L70*7 | RIGID_FRAME | 18.4383 | L70*7 | C130 | 70
4 x L70*7 | RIGID_FRAME | 14.4628 | L70*7 | C132 | 70
4 x L70*7 | RIGID_FRAME | 17.4237 | L70*7 | C131 | 70
8 x L70*7 | RIGID_FRAME | 19.4713 | L70*7 | C111 | 70
8 x L70*7 | RIGID_FRAME | 18.4567 | L70*7 | C112 | 70
4 x L50*5 | RIGID_FRAME | 14.0917 | L50*5 | C73 | 50
8 x L50*5 | RIGID_FRAME | 14.2801 | L50*5 | C72 | 50
2 x L50*5 | RIGID_FRAME | 22.912 | L50*5 | C81 | 50
4 x L50*5 | RIGID_FRAME | 14.0967 | L50*5 | C74 | 50
2 x L50*5 | RIGID_FRAME | 14.5112 | L50*5 | C75 | 50
4 x L50*5 | RIGID_FRAME | 13.8657 | L50*5 | C76 | 50
4 x L50*5 | RIGID_FRAME | 13.9337 | L50*5 | C78 | 50
4 x L50*5 | RIGID_FRAME | 13.5192 | L50*5 | C77 | 50
8 x L50*5 | RIGID_FRAME | 12.6463 | L50*5 | C79 | 50
IPEA300 | RIGID_FRAME | 430.603 | IPEA300 | K61 | 323.25
IPEA300 | RIGID_FRAME | 430.603 | IPEA300 | K62 | 323.25
FPL8*210 | RIGID_FRAME | 3.12316 | FPL8*210 | G83 | 210
54 x L70*7 | RIGID_FRAME | 1.32824 | L70*7 | H35 | 70
L60*6 | RIGID_FRAME | 1.03063 | L60*6 | H30 | 60
FPL8*210 | RIGID_FRAME | 2.39027 | FPL8*210 | G69 | 210
IPEA300 | RIGID_FRAME | 425.868 | IPEA300 | K60 | 270.001
14 x L60*6 | RIGID_FRAME | 0.59668 | L60*6 | H31 | 60
FPL8*210 | RIGID_FRAME | 2.13962 | FPL8*210 | G80 | 210
IPEA300 | RIGID_FRAME | 421.787 | IPEA300 | K64 | 210.001
FPL8*210 | RIGID_FRAME | 2.13962 | FPL8*210 | G79 | 210
FPL8*210 | RIGID_FRAME | 2.11135 | FPL8*210 | G82 | 210
FPL8*210 | RIGID_FRAME | 2.362 | FPL8*210 | G81 | 210
FPL8*210 | RIGID_FRAME | 2.39027 | FPL8*210 | G70 | 210
IPEA300 | RIGID_FRAME | 425.708 | IPEA300 | K63 | 270.001
FPL8*210 | RIGID_FRAME | 2.13962 | FPL8*210 | G77 | 210
FPL8*210 | RIGID_FRAME | 2.13962 | FPL8*210 | G78 | 210
IPEA300 | RIGID_FRAME | 421.787 | IPEA300 | K66 | 210
FPL8*210 | RIGID_FRAME | 2.39026 | FPL8*210 | G71 | 210
IPEA300 | RIGID_FRAME | 425.733 | IPEA300 | K65 | 270.001
FPL8*210 | RIGID_FRAME | 2.39027 | FPL8*210 | G72 | 210
FPL8*210 | RIGID_FRAME | 2.39027 | FPL8*210 | G73 | 210
2 x L50*5 | RIGID_FRAME | 13.8657 | L50*5 | C50 | 50
FPL8*210 | RIGID_FRAME | 2.39026 | FPL8*210 | G74 | 210
FPL8*210 | RIGID_FRAME | 2.13962 | FPL8*210 | G76 | 210
FPL8*210 | RIGID_FRAME | 2.13962 | FPL8*210 | G75 | 210
PL8 | RIGID_FRAME | 1.77226 | PL8 | 0(?) | 8
IPEA300 | RIGID_FRAME | 424.005 | IPEA300 | K68(?) | 245.09
IPEA300 | RIGID_FRAME | 427.849 | IPEA300 | K72 | 270
2 x IPEA300 | RIGID_FRAME | 427.887 | IPEA300 | K71 | 270
2 x L50*5 | RIGID_FRAME | 13.9337 | L50*5 | C53 | 50
IPEA300 | RIGID_FRAME | 431.471 | IPEA300 | K69 | 270
2 x L50*5 | RIGID_FRAME | 14.2801 | L50*5 | C49 | 50
IPEA300 | RIGID_FRAME | 425.771 | IPEA300 | K67 | 252.98
IPEA300 | RIGID_FRAME | 427.887 | IPEA300 | K70 | 270
4 x IPEA300 | RIGID_FRAME | 341.696 | IPEA300 | K83 | 150
14 x TUBE-C-100*100*3 | RIGID_FRAME | 11.5664 | TUBE-C-100*100*3 | P62 | 220.213
14 x TUBE-C-100*100*3 | RIGID_FRAME | 12.4026 | TUBE-C-100*100*3 | P66 | 220.203
14 x TUBE-C-100*100*3 | RIGID_FRAME | 13.2387 | TUBE-C-100*100*3 | P67 | 220.213
14 x TUBE-C-100*100*3 | RIGID_FRAME | 10.073 | TUBE-C-100*100*3 | P96 | 220.213
7 x UPF-100*50*4 | RIGID_FRAME | 36.9749 | UPF-100*50*4 | S53 | 110
UPF-100*50*4 | RIGID_FRAME | 30.777 | UPF-100*50*4 | S48 | 50
UPF-100*50*4 | RIGID_FRAME | 25.6224 | UPF-100*50*4 | S71 | 50
2 x UPF-100*50*4 | RIGID_FRAME | 30.4605 | UPF-100*50*4 | S72 | 50
2 x UPF-100*50*4 | RIGID_FRAME | 32.1184 | UPF-100*50*4 | S70 | 50
UPF-100*50*4 | RIGID_FRAME | 33.1985 | UPF-100*50*4 | S69 | 50
2 x TUBE-C-100*100*3 | RIGID_FRAME | 14.5015 | TUBE-C-100*100*3 | P83 | 220
19 x UPF-100*50*4 | RIGID_FRAME | 36.4542 | UPF-100*50*4 | S54 | 50
7 x UPF-100*50*4 | RIGID_FRAME | 36.4542 | UPF-100*50*4 | S52 | 50
28 x PL2*340 | RIGID_FRAME | 1.25977 | PL2*340 | Y7 | 2
92 x FPL6*50 | RIGID_FRAME | 0.39317 | FPL6*50 | H47 | 50
HEA100 | RIGID_FRAME | 34.865 | HEA100 | N62 | 100
HEA100 | RIGID_FRAME | 45.3217 | HEA100 | N61 | 100
TUBE-C-100*100*3 | RIGID_FRAME | 9.11436 | TUBE-C-100*100*3 | P107 | 220
97 x L60*6 | RIGID_FRAME | 1.13911 | L60*6 | H24 | 60
UPF-100*50*4 | RIGID_FRAME | 25.7125 | UPF-100*50*4 | S49 | 100
39 x L60*6 | RIGID_FRAME | 1.04148 | L60*6 | H21 | 60
88 x L60*6 | RIGID_FRAME | 0.49904 | L60*6 | H26 | 60
148 x L60*6 | RIGID_FRAME | 1.04148 | L60*6 | H25 | 60
UPF-100*50*4 | RIGID_FRAME | 21.9348 | UPF-100*50*4 | S43 | 50
17 x UPF-100*50*4 | RIGID_FRAME | 28.7473 | UPF-100*50*4 | S81 | 50
22 x L60*6 | RIGID_FRAME | 1.04148 | L60*6 | H27 | 60
143 x PL2*340 | RIGID_FRAME | 1.44126 | PL2*340 | Y6 | 2
2 x TUBE-C-100*100*3 | RIGID_FRAME | 9.23099 | TUBE-C-100*100*3 | P94 | 220.213
UPF-100*50*4 | RIGID_FRAME | 30.777 | UPF-100*50*4 | S42 | 50
UPF-100*50*4 | RIGID_FRAME | 25.6224 | UPF-100*50*4 | S64 | 50
2 x UPF-100*50*4 | RIGID_FRAME | 30.4605 | UPF-100*50*4 | S63 | 50
2 x UPF-100*50*4 | RIGID_FRAME | 32.1184 | UPF-100*50*4 | S62 | 50
2 x TUBE-C-100*100*3 | RIGID_FRAME | 10.0458 | TUBE-C-100*100*3 | P77 | 220.213
9 x UPF-100*50*4 | RIGID_FRAME | 12.0576 | UPF-100*50*4 | S77 | 50
12 x UPF-100*50*4 | RIGID_FRAME | 14.4767 | UPF-100*50*4 | S76 | 50
12 x UPF-100*50*4 | RIGID_FRAME | 15.3056 | UPF-100*50*4 | S78 | 50
6 x UPF-100*50*4 | RIGID_FRAME | 15.8457 | UPF-100*50*4 | S82 | 50
3 x UPF-100*50*4 | RIGID_FRAME | 21.5731 | UPF-100*50*4 | S58 | 50
3 x UPF-100*50*4 | RIGID_FRAME | 17.5739 | UPF-100*50*4 | S55 | 50
UPN160 | RIGID_FRAME | 109.481 | UPN160 | K105 | 190
4 x PL8 | RIGID_FRAME | 1.45892 | PL8 | G29 | 8
15 x L60*6 | RIGID_FRAME | 22.0172 | L60*6 | C1 | 60
3 x TUBE-C-60*60*3 | RIGID_FRAME | 15.063 | TUBE-C-60*60*3 | B10 | 80
2 x TUBE-C-90*90*3 | RIGID_FRAME | 23.9019 | TUBE-C-90*90*3 | B6 | 120
L60*6 | RIGID_FRAME | 21.6035 | L60*6 | C2 | 60
TUBE-C-60*60*3 | RIGID_FRAME | 14.7961 | TUBE-C-60*60*3 | B11 | 80
2 x PL8 | RIGID_FRAME | 3.5599 | PL8 | G30 | 8
2 x IPE330 | RIGID_FRAME | 654.297 | IPE330 | K33 | 301.963
IPE330 | RIGID_FRAME | 660.137 | IPE330 | K35 | 256.672
4 x TUBE-C-90*90*3 | RIGID_FRAME | 28.2386 | TUBE-C-90*90*3 | B9 | 120
8 x L60*6 | RIGID_FRAME | 22.1529 | L60*6 | C3 | 60
IPE330 | RIGID_FRAME | 660.137 | IPE330 | K36 | 256.672
IPE330 | RIGID_FRAME | 660.137 | IPE330 | K34 | 256.672
UPN160 | RIGID_FRAME | 138.492 | UPN160 | K104 | 190
3 x HEA100 | RIGID_FRAME | 44.4225 | HEA100 | N60 | 100
4 x HEA100 | RIGID_FRAME | 44.4225 | HEA100 | N56 | 100
HEA100 | RIGID_FRAME | 43.5904 | HEA100 | N59 | 100
HEA100 | RIGID_FRAME | 44.4225 | HEA100 | N58 | 100
HEA100 | RIGID_FRAME | 43.5904 | HEA100 | N57 | 100
TUBE-C-100*100*3 | RIGID_FRAME | 9.22466 | TUBE-C-100*100*3 | P108 | 220
TUBE-C-100*100*3 | RIGID_FRAME | 9.94381 | TUBE-C-100*100*3 | P91 | 220
TUBE-C-100*100*3 | RIGID_FRAME | 10.7346 | TUBE-C-100*100*3 | P92 | 220
TUBE-C-100*100*3 | RIGID_FRAME | 11.5253 | TUBE-C-100*100*3 | P93 | 220
UPF-100*50*4 | RIGID_FRAME | 20.3834 | UPF-100*50*4 | S84 | 50
8 x UPF-100*50*4 | RIGID_FRAME | 37.1012 | UPF-100*50*4 | S74 | 50
4 x L60*6 | RIGID_FRAME | 1.04148 | L60*6 | H22 | 60
8 x UPF-100*50*4 | RIGID_FRAME | 40.0975 | UPF-100*50*4 | S73 | 50
UPF-100*50*4 | RIGID_FRAME | 32.7364 | UPF-100*50*4 | S50 | 50
UPF-100*50*4 | RIGID_FRAME | 33.279 | UPF-100*50*4 | S61 | 50
UPF-100*50*4 | RIGID_FRAME | 33.0378 | UPF-100*50*4 | S51 | 50
5 x TUBE-C-100*100*3 | RIGID_FRAME | 9.6944 | TUBE-C-100*100*3 | P95 | 220
5 x TUBE-C-100*100*3 | RIGID_FRAME | 11.1423 | TUBE-C-100*100*3 | P72 | 220.255
UPF-100*50*4 | RIGID_FRAME | 15.705 | UPF-100*50*4 | S60 | 50
3 x UPF-100*50*4 | RIGID_FRAME | 15.705 | UPF-100*50*4 | S45 | 50
5 x TUBE-C-100*100*3 | RIGID_FRAME | 11.9342 | TUBE-C-100*100*3 | P64 | 220.255
5 x TUBE-C-100*100*3 | RIGID_FRAME | 12.725 | TUBE-C-100*100*3 | P65 | 220.195
5 x TUBE-C-100*100*3 | RIGID_FRAME | 13.5157 | TUBE-C-100*100*3 | P63 | 220.195
16 x UPF-100*50*4 | RIGID_FRAME | 15.8859 | UPF-100*50*4 | S80 | 50
5 x UPF-100*50*4 | RIGID_FRAME | 37.1012 | UPF-100*50*4 | S46 | 50
5 x UPF-100*50*4 | RIGID_FRAME | 40.0975 | UPF-100*50*4 | S79 | 50
TUBE-C-100*100*3 | RIGID_FRAME | 9.22466 | TUBE-C-100*100*3 | P101 | 220
TUBE-C-100*100*3 | RIGID_FRAME | 9.11436 | TUBE-C-100*100*3 | P100 | 220
TUBE-C-100*100*3 | RIGID_FRAME | 9.94381 | TUBE-C-100*100*3 | P84 | 220
TUBE-C-100*100*3 | RIGID_FRAME | 10.7346 | TUBE-C-100*100*3 | P85 | 220
TUBE-C-100*100*3 | RIGID_FRAME | 11.5253 | TUBE-C-100*100*3 | P86 | 220
IPEA300 | RIGID_FRAME | 448.233 | IPEA300 | K28 | 315
UPF-100*50*4 | RIGID_FRAME | 20.3834 | UPF-100*50*4 | S83 | 50
UPF-100*50*4 | RIGID_FRAME | 16.0065 | UPF-100*50*4 | S59 | 50
3 x UPF-100*50*4 | RIGID_FRAME | 16.0065 | UPF-100*50*4 | S47 | 50
14 x UPF-100*50*4 | RIGID_FRAME | 28.7473 | UPF-100*50*4 | S75 | 50
UPF-100*50*4 | RIGID_FRAME | 21.6936 | UPF-100*50*4 | S41 | 50
2 x TUBE-C-100*100*3 | RIGID_FRAME | 10.882 | TUBE-C-100*100*3 | P78 | 220.203
2 x TUBE-C-100*100*3 | RIGID_FRAME | 11.718 | TUBE-C-100*100*3 | P79 | 220.213
UPF-100*50*4 | RIGID_FRAME | 21.9348 | UPF-100*50*4 | S57 | 50
UPF-100*50*4 | RIGID_FRAME | 33.1985 | UPF-100*50*4 | S56 | 50
UPF-100*50*4 | RIGID_FRAME | 21.6635 | UPF-100*50*4 | S40 | 50
PL9000*200 | REINFORCEMENT_UNIT | 274301 | PL9000*200 | Z53 | 200 | Tekla Assemblages - Poids ferraillage Elément béton: 0 kg
2 x PL4500*200 | REINFORCEMENT_UNIT | 137150 | PL4500*200 | Z54 | 200 | Tekla Assemblages - Poids ferraillage Elément béton: 0 kg
4 x L50*5 | RIGID_FRAME | 12.267 | L50*5 | C51 | 50
2 x L50*5 | RIGID_FRAME | 13.5192 | L50*5 | C52 | 50
6 x L50*5 | RIGID_FRAME | 12.9854 | L50*5 | C80 | 50
L70*7 | RIGID_FRAME | 20.1323 | L70*7 | C133 | 70
L70*7 | RIGID_FRAME | 20.1324 | L70*7 | C133 | 70
3 x L70*7 | RIGID_FRAME | 15.4959 | L70*7 | C134 | 70
IPE500 | RIGID_FRAME | 629.138 | IPE500 | P31 | 250
PL4860*250 | REINFORCEMENT_UNIT | 11943 | PL4860*250 | Z60 | 250 | Tekla Assemblages - Poids ferraillage Elément béton: 0 kg
PL1760*400 | REINFORCEMENT_UNIT | 5144.83 | PL1760*400 | Z80 | 400 | Tekla Assemblages - Poids ferraillage Elément béton: 0 kg
PL3920*200 | REINFORCEMENT_UNIT | 12841.9 | PL3920*200 | Z21 | 200 | Tekla Assemblages - Poids ferraillage Elément béton: 0 kg
PL6000*200 | REINFORCEMENT_UNIT | 4501.92 | PL6000*200 | Z55 | 200 | Tekla Assemblages - Poids ferraillage Elément béton: 0 kg
PL6000*200 | REINFORCEMENT_UNIT | 17196.8 | PL6000*200 | Z56 | 200 | Tekla Assemblages - Poids ferraillage Elément béton: 0 kg
PL6000*200 | REINFORCEMENT_UNIT | 4842.12 | PL6000*200 | Z57 | 200 | Tekla Assemblages - Poids ferraillage Elément béton: 0 kg
PL4340*200 | REINFORCEMENT_UNIT | 29916.1 | PL4340*200 | Z38 | 200 | Tekla Assemblages - Poids ferraillage Elément béton: 0 kg
3 x PL2900*150 | REINFORCEMENT_UNIT | 1242.36 | PL2900*150 | Z68 | 150 | Tekla Assemblages - Poids ferraillage Elément béton: 0 kg
2 x PL2900*150 | REINFORCEMENT_UNIT | 959.175 | PL2900*150 | Z70 | 150 | Tekla Assemblages - Poids ferraillage Elément béton: 0 kg
PL2900*150 | REINFORCEMENT_UNIT | 400.484 | PL2900*150 | Z71 | 150 | Tekla Assemblages - Poids ferraillage Elément béton: 0 kg
PL2900*150 | REINFORCEMENT_UNIT | 794.745 | PL2900*150 | Z69 | 150 | Tekla Assemblages - Poids ferraillage Elément béton: 0 kg
PL2900*150 | REINFORCEMENT_UNIT | 844.987 | PL2900*150 | Z67 | 150 | Tekla Assemblages - Poids ferraillage Elément béton: 0 kg
PL4500*200 | REINFORCEMENT_UNIT | 1423.59 | PL4500*200 | Z39 | 200 | Tekla Assemblages - Poids ferraillage Elément béton: 0 kg
2 x PL2600*200 | REINFORCEMENT_UNIT | 3718.26 | PL2600*200 | Z22 | 200 | Tekla Assemblages - Poids ferraillage Elément béton: 0 kg
PL800*400 | REINFORCEMENT_UNIT | 13204.4 | PL800*400 | Z79 | 400 | Tekla Assemblages - Poids ferraillage Elément béton: 0 kg
2 x PL860*200 | REINFORCEMENT_UNIT | 576.114 | PL860*200 | Z23 | 200 | Tekla Assemblages - Poids ferraillage Elément béton: 0 kg
PL1620*200 | REINFORCEMENT_UNIT | 1928.93 | PL1620*200 | Z24 | 200 | Tekla Assemblages - Poids ferraillage Elément béton: 0 kg
PL200 | REINFORCEMENT_UNIT | 4893.65 | PL200 | Z25 | 200 | Tekla Assemblages - Poids ferraillage Elément béton: 0 kg
PL2600*200 | REINFORCEMENT_UNIT | 1381.38 | PL2600*200 | Z26 | 200 | Tekla Assemblages - Poids ferraillage Elément béton: 0 kg
PL2600*200 | REINFORCEMENT_UNIT | 1310.4 | PL2600*200 | Z27 | 200 | Tekla Assemblages - Poids ferraillage Elément béton: 0 kg
PL2600*200 | REINFORCEMENT_UNIT | 1796.34 | PL2600*200 | Z28 | 200 | Tekla Assemblages - Poids ferraillage Elément béton: 0 kg
PL2600*200 | REINFORCEMENT_UNIT | 2140.32 | PL2600*200 | Z29 | 200 | Tekla Assemblages - Poids ferraillage Elément béton: 0 kg
PL2600*150 | REINFORCEMENT_UNIT | 4884.24 | PL2600*150 | Z72 | 150 | Tekla Assemblages - Poids ferraillage Elément béton: 0 kg
PL2600*150 | REINFORCEMENT_UNIT | 1721.57 | PL2600*150 | Z73 | 150 | Tekla Assemblages - Poids ferraillage Elément béton: 0 kg
PL2600*150 | REINFORCEMENT_UNIT | 3054.87 | PL2600*150 | Z74 | 150 | Tekla Assemblages - Poids ferraillage Elément béton: 0 kg
PL2600*150 | REINFORCEMENT_UNIT | 397.215 | PL2600*150 | Z75 | 150 | Tekla Assemblages - Poids ferraillage Elément béton: 0 kg
PL2600*150 | REINFORCEMENT_UNIT | 1122.03 | PL2600*150 | Z76 | 150 | Tekla Assemblages - Poids ferraillage Elément béton: 0 kg
PL180 | REINFORCEMENT_UNIT | 38088 | PL180 | Z4 | 180 | Tekla Assemblages - Poids ferraillage Elément béton: 0 kg
PL1620*200 | REINFORCEMENT_UNIT | 7768.28 | PL1620*200 | Z44 | 200 | Tekla Assemblages - Poids ferraillage Elément béton: 0 kg
PL2270*200 | REINFORCEMENT_UNIT | 2702.89 | PL2270*200 | Z30 | 200 | Tekla Assemblages - Poids ferraillage Elément béton: 0 kg
PL2780*200 | REINFORCEMENT_UNIT | 2784.73 | PL2780*200 | Z31 | 200 | Tekla Assemblages - Poids ferraillage Elément béton: 0 kg
PL2780*200 | REINFORCEMENT_UNIT | 2055.09 | PL2780*200 | Z32 | 200 | Tekla Assemblages - Poids ferraillage Elément béton: 0 kg
PL2780*200 | REINFORCEMENT_UNIT | 4933.11 | PL2780*200 | Z33 | 200 | Tekla Assemblages - Poids ferraillage Elément béton: 0 kg
PL5920*200 | REINFORCEMENT_UNIT | 15126.3 | PL5920*200 | Z47 | 200 | Tekla Assemblages - Poids ferraillage Elément béton: 0 kg
PL2920*200 | REINFORCEMENT_UNIT | 2403.74 | PL2920*200 | Z34 | 200 | Tekla Assemblages - Poids ferraillage Elément béton: 0 kg
3 x PL6140*200 | REINFORCEMENT_UNIT | 2063.04 | PL6140*200 | Z35 | 200 | Tekla Assemblages - Poids ferraillage Elément béton: 0 kg
PL6140 | REINFORCEMENT_UNIT | 5157.6 | PL6140 | Z65 | 6140 | Tekla Assemblages - Poids ferraillage Elément béton: 0 kg
PL6140 | REINFORCEMENT_UNIT | 3842.41 | PL6140 | Z66 | 6140 | Tekla Assemblages - Poids ferraillage Elément béton: 0 kg
PL6140*200 | REINFORCEMENT_UNIT | 4492.53 | PL6140*200 | Z36 | 200 | Tekla Assemblages - Poids ferraillage Elément béton: 0 kg
3 x UPF-100*50*4 | RIGID_FRAME | 31.9828 | UPF-100*50*4 | U2 | 410
4 x UPF-100*50*4 | RIGID_FRAME | 32.3445 | UPF-100*50*4 | U3 | 410
4 x UPF-100*50*4 | RIGID_FRAME | 32.5857 | UPF-100*50*4 | U4 | 410
L80*8 | RIGID_FRAME | 1.44832 | L80*8 | H58 | 80
TUBE-C-90*90*3 | RIGID_FRAME | 54.8546 | TUBE-C-90*90*3 | L92 | 90
IPE500 | RIGID_FRAME | 1348.89 | IPE500 | N5 | 387.354
HEA220 | RIGID_FRAME | 205.826 | HEA220 | P118 | 250
TUBE-C-100*100*3 | RIGID_FRAME | 52.2395 | TUBE-C-100*100*3 | B3 | 240.48
TUBE-C-100*100*3 | RIGID_FRAME | 51.1929 | TUBE-C-100*100*3 | B2 | 240
TUBE-C-100*100*3 | RIGID_FRAME | 57.9601 | TUBE-C-100*100*3 | B1 | 241.356
IPE200 | RIGID_FRAME | 145.912 | IPE200 | P9 | 220
IPE200 | RIGID_FRAME | 151.82 | IPE200 | P8 | 319.929
IPE200 | RIGID_FRAME | 147.544 | IPE200 | P11 | 240
IPE200 | RIGID_FRAME | 145.912 | IPE200 | P10 | 220
4 x L50*5 | RIGID_FRAME | 13.8484 | L50*5 | V2 | 50
4 x L50*5 | RIGID_FRAME | 14.0745 | L50*5 | V3 | 50
TUBE-C-80*80*3 | RIGID_FRAME | 57.0574 | TUBE-C-80*80*3 | B4 | 377.635
IPE200 | RIGID_FRAME | 150.841 | IPE200 | P6 | 319.929
TUBE-C-100*100*3 | RIGID_FRAME | 27.7825 | TUBE-C-100*100*3 | B17 | 120.02
HEA220 | RIGID_FRAME | 347.782 | HEA220 | P123 | 441.582
UPF-120*50*4 | RIGID_FRAME | 26.0005 | UPF-120*50*4 | L10 | 56
TUBE-C-120*120*4 | RIGID_FRAME | 102.517 | TUBE-C-120*120*4 | L104 | 120
TUBE-C-70*70*3 | RIGID_FRAME | 21.7875 | TUBE-C-70*70*3 | L105 | 70
TUBE-C-90*90*3 | RIGID_FRAME | 49.6467 | TUBE-C-90*90*3 | L88 | 169.98
HEA120 | RIGID_FRAME | 41.8842 | HEA120 | M5 | 235
L70*7 | RIGID_FRAME | 13.9457 | L70*7 | L11 | 70
TUBE-C-90*90*3 | RIGID_FRAME | 48.7518 | TUBE-C-90*90*3 | L90 | 90
TUBE-C-90*90*3 | RIGID_FRAME | 90.9742 | TUBE-C-90*90*3 | L91 | 90
TUBE-C-90*90*3 | RIGID_FRAME | 49.2829 | TUBE-C-90*90*3 | L89 | 90
IPE200 | RIGID_FRAME | 143.68 | IPE200 | P17 | 220
TUBE-C-90*90*3 | RIGID_FRAME | 67.2104 | TUBE-C-90*90*3 | L95 | 90
TUBE-C-100*100*3 | RIGID_FRAME | 73.394 | TUBE-C-100*100*3 | L103 | 100
L80*8 | RIGID_FRAME | 1.70902 | L80*8 | H70 | 80
IPEA300 | RIGID_FRAME | 241.888 | IPEA300 | P122 | 180
IPE200 | RIGID_FRAME | 145.912 | IPE200 | P7 | 220
IPEA300 | RIGID_FRAME | 434.878 | IPEA300 | K54 | 330.136
IPE360 | RIGID_FRAME | 692.526 | IPE360 | K99 | 413.14
IPE240 | RIGID_FRAME | 231.504 | IPE240 | K58 | 153.101
IPE240 | RIGID_FRAME | 226.133 | IPE240 | K57 | 227.851
TUBE-C-80*80*3 | RIGID_FRAME | 17.0153 | TUBE-C-80*80*3 | B12 | 100.003
UPN200 | RIGID_FRAME | 194.184 | UPN200 | K56 | 98.5081
IPEA300 | RIGID_FRAME | 437.703 | IPEA300 | K45 | 233.546
TUBE-C-80*80*3 | RIGID_FRAME | 9.70202 | TUBE-C-80*80*3 | B13 | 100
IPEA300 | RIGID_FRAME | 433.565 | IPEA300 | K59 | 226.865
TUBE-C-80*80*3 | RIGID_FRAME | 32.157 | TUBE-C-80*80*3 | B14 | 100
TUBE-C-80*80*3 | RIGID_FRAME | 31.6343 | TUBE-C-80*80*3 | B15 | 100
2 x TUBE-C-100*100*3 | RIGID_FRAME | 48.4071 | TUBE-C-100*100*3 | B16 | 120.003
IPEA300 | RIGID_FRAME | 432.269 | IPEA300 | K8 | 330.137
IPEA300 | RIGID_FRAME | 160.203 | IPEA300 | K49 | 158.05
2 x L50*5 | RIGID_FRAME | 11.2873 | L50*5 | C69 | 50
L70*7 | RIGID_FRAME | 17.6727 | L70*7 | C99 | 70
2 x L70*7 | RIGID_FRAME | 24.3334 | L70*7 | C101 | 70
UPN260 | RIGID_FRAME | 423.099 | UPN260 | N23 | 90
UPN260 | RIGID_FRAME | 199.056 | UPN260 | N24 | 90
PL8 | RIGID_FRAME | 2.63972 | PL8 | G62 | 8
PL8 | RIGID_FRAME | 11.9341 | PL8 | G66 | 8
L90*9 | RIGID_FRAME | 3.28523 | L90*9 | H75 | 90
L90*9 | RIGID_FRAME | 3.28523 | L90*9 | H74 | 90
2 x L70*7 | RIGID_FRAME | 24.3121 | L70*7 | C102 | 70
L50*5 | RIGID_FRAME | 15.4098 | L50*5 | C5 | 50
2 x L50*5 | RIGID_FRAME | 15.4098 | L50*5 | C6 | 50
UPN260 | RIGID_FRAME | 293.125 | UPN260 | N25 | 90
IPEA300 | RIGID_FRAME | 431.527 | IPEA300 | K3 | 295.013
PL8 | RIGID_FRAME | 2.359 | PL8 | G61 | 8
PL8 | RIGID_FRAME | 9.733 | PL8 | G38 | 8
IPE240 | RIGID_FRAME | 230.02 | IPE240 | K91 | 120
32 x FPL6*90 | RIGID_FRAME | 0.7077 | FPL6*90 | H45 | 90
IPE240 | RIGID_FRAME | 233.894 | IPE240 | K88 | 335.716
IPE240 | RIGID_FRAME | 233.894 | IPE240 | K89 | 335.716
IPE240 | RIGID_FRAME | 230.02 | IPE240 | K92 | 120
IPE240 | RIGID_FRAME | 233.047 | IPE240 | K87 | 227.858
2 x IPE270 | RIGID_FRAME | 344.045 | IPE270 | K97 | 135
IPE270 | RIGID_FRAME | 270.574 | IPE270 | K95 | 135
IPE270 | RIGID_FRAME | 344.045 | IPE270 | K96 | 135
IPEA300 | RIGID_FRAME | 438.969 | IPEA300 | K38 | 298.817
UPN200 | RIGID_FRAME | 104.171 | UPN200 | K90 | 75
IPEA300 | RIGID_FRAME | 157.622 | IPEA300 | K44 | 150
IPEA300 | RIGID_FRAME | 146.361 | IPEA300 | K43 | 150
IPEA300 | RIGID_FRAME | 154.553 | IPEA300 | K47 | 150
IPEA300 | RIGID_FRAME | 154.553 | IPEA300 | K48 | 150
IPEA300 | RIGID_FRAME | 423.855 | IPEA300 | K5 | 150
TUBE-C-60*60*3 | RIGID_FRAME | 9.66389 | TUBE-C-60*60*3 | L45 | 129.9
3 x TUBE-C-90*90*3 | RIGID_FRAME | 70.9693 | TUBE-C-90*90*3 | L22 | 90
IPE500 | RIGID_FRAME | 638.843 | IPE500 | P26 | 494.502
IPE500 | RIGID_FRAME | 674.42 | IPE500 | P22 | 539.072
UPN180 | RIGID_FRAME | 57.2822 | UPN180 | P47 | 229.99
UPN180 | RIGID_FRAME | 57.2822 | UPN180 | P46 | 230
UPN180 | RIGID_FRAME | 80.4052 | UPN180 | P42 | 229.99
UPN180 | RIGID_FRAME | 80.4052 | UPN180 | P43 | 230
UPN180 | RIGID_FRAME | 54.0284 | UPN180 | P51 | 84.9903
UPN180 | RIGID_FRAME | 92.8772 | UPN180 | P41 | 329.99
UPN180 | RIGID_FRAME | 55.9634 | UPN180 | P50 | 230
UPN180 | RIGID_FRAME | 92.8772 | UPN180 | P40 | 330
IPE200 | RIGID_FRAME | 153.273 | IPE200 | P15 | 240
IPE200 | RIGID_FRAME | 153.273 | IPE200 | P14 | 240
UPN180 | RIGID_FRAME | 74.7037 | UPN180 | L28 | 76
UPN180 | RIGID_FRAME | 23.8781 | UPN180 | L27 | 76
UPN180 | RIGID_FRAME | 45.968 | UPN180 | L26 | 76
UPN260 | RIGID_FRAME | 394.018 | UPN260 | N29 | 90
UPN260 | RIGID_FRAME | 310.187 | UPN260 | N30 | 90
UPN300 | RIGID_FRAME | 254.159 | UPN300 | N37 | 100
UPN180 | RIGID_FRAME | 31.6292 | UPN180 | L25 | 70
IPE200 | RIGID_FRAME | 142.487 | IPE200 | P18 | 210
UPN180 | RIGID_FRAME | 124.679 | UPN180 | L31 | 70
IPE500 | RIGID_FRAME | 606.713 | IPE500 | P23 | 487.998
6 x PL140*10 | RIGID_FRAME | 4.47264 | PL140*10 | H6 | 88.95
TUBE-C-90*90*3 | RIGID_FRAME | 94.8885 | TUBE-C-90*90*3 | L96 | 90
TUBE-C-90*90*3 | RIGID_FRAME | 70.6318 | TUBE-C-90*90*3 | L23 | 90
UPN180 | RIGID_FRAME | 117.553 | UPN180 | P49 | 270
UPN180 | RIGID_FRAME | 117.553 | UPN180 | P48 | 270
UPN140 | RIGID_FRAME | 44.8563 | UPN140 | K100 | 80
IPEA300 | RIGID_FRAME | 202.305 | IPEA300 | N36 | 379.137
HEA120 | RIGID_FRAME | 35.0307 | HEA120 | M13 | 240
L70*7 | RIGID_FRAME | 17.6727 | L70*7 | C98 | 70
HEA120 | RIGID_FRAME | 42.3956 | HEA120 | M14 | 240
UPF-120*50*4 | RIGID_FRAME | 31.1469 | UPF-120*50*4 | L8 | 56
HEA120 | RIGID_FRAME | 41.1379 | HEA120 | M3 | 240
PL180 | RIGID_FRAME | 73455.8 | PL180 | Z5 | 180
PL180 | RIGID_FRAME | 131937 | PL180 | Z6 | 180
PL180 | RIGID_FRAME | 34657.8 | PL180 | Z7 | 180
PL180 | RIGID_FRAME | 225949 | PL180 | Z8 | 180
PL180 | RIGID_FRAME | 619072 | PL180 | Z9 | 180
PL180 | RIGID_FRAME | 15103.1 | PL180 | Z10 | 180
PL180 | RIGID_FRAME | 48125.1 | PL180 | Z11 | 180
2 x TUBE-C-100*100*3 | RIGID_FRAME | 10.2331 | TUBE-C-100*100*3 | P87 | 220
TUBE-C-100*100*3 | RIGID_FRAME | 12.7789 | TUBE-C-100*100*3 | P82 | 220.142
TUBE-C-100*100*3 | RIGID_FRAME | 12.0869 | TUBE-C-100*100*3 | P81 | 220.142
TUBE-C-100*100*3 | RIGID_FRAME | 11.3949 | TUBE-C-100*100*3 | P80 | 220.142
TUBE-C-100*100*3 | RIGID_FRAME | 12.3092 | TUBE-C-100*100*3 | P90 | 220
TUBE-C-100*100*3 | RIGID_FRAME | 11.6172 | TUBE-C-100*100*3 | P89 | 220
TUBE-C-100*100*3 | RIGID_FRAME | 10.9251 | TUBE-C-100*100*3 | P88 | 220
TUBE-C-100*100*3 | RIGID_FRAME | 11.215 | TUBE-C-100*100*3 | P75 | 220
2 x HEA140 | RIGID_FRAME | 50.6125 | HEA140 | N32 | 140
2 x HEA140 | RIGID_FRAME | 50.6128 | HEA140 | N33 | 140
2 x HEA140 | RIGID_FRAME | 50.6125 | HEA140 | N34 | 140
2 x HEA140 | RIGID_FRAME | 50.6125 | HEA140 | N35 | 140
2 x TUBE-C-100*100*3 | RIGID_FRAME | 14.6881 | TUBE-C-100*100*3 | P56 | 220
2 x TUBE-C-100*100*3 | RIGID_FRAME | 14.9512 | TUBE-C-100*100*3 | P57 | 220
8 x PL2*240 | RIGID_FRAME | 1.28112 | PL2*240 | Y8 | 2
12 x PL5*200 | RIGID_FRAME | 1.57 | PL5*200 | Y5 | 5
2 x TUBE-C-100*100*3 | RIGID_FRAME | 14.3579 | TUBE-C-100*100*3 | P55 | 220
2 x TUBE-C-100*100*3 | RIGID_FRAME | 13.8006 | TUBE-C-100*100*3 | P54 | 220
TUBE-C-100*100*3 | RIGID_FRAME | 13.9733 | TUBE-C-100*100*3 | P59 | 220.257
4 x PL2*250 | RIGID_FRAME | 1.3345 | PL2*250 | Y9 | 2
TUBE-C-100*100*3 | RIGID_FRAME | 14.5306 | TUBE-C-100*100*3 | P61 | 220.254
TUBE-C-100*100*3 | RIGID_FRAME | 13.9733 | TUBE-C-100*100*3 | P58 | 220.257
TUBE-C-100*100*3 | RIGID_FRAME | 14.5306 | TUBE-C-100*100*3 | P60 | 220.254
7 x TUBE-C-100*100*3 | RIGID_FRAME | 11.5302 | TUBE-C-100*100*3 | P73 | 220.142
7 x TUBE-C-100*100*3 | RIGID_FRAME | 12.2235 | TUBE-C-100*100*3 | P71 | 220.142
4 x TUBE-C-100*100*3 | RIGID_FRAME | 12.9155 | TUBE-C-100*100*3 | P70 | 220.142
4 x TUBE-C-100*100*3 | RIGID_FRAME | 13.6076 | TUBE-C-100*100*3 | P69 | 220.142
4 x TUBE-C-100*100*3 | RIGID_FRAME | 14.2995 | TUBE-C-100*100*3 | P68 | 220.142
2 x TUBE-C-100*100*3 | RIGID_FRAME | 11.6847 | TUBE-C-100*100*3 | P74 | 220.159
2 x TUBE-C-100*100*3 | RIGID_FRAME | 9.65675 | TUBE-C-100*100*3 | P103 | 220
2 x TUBE-C-100*100*3 | RIGID_FRAME | 9.641 | TUBE-C-100*100*3 | P106 | 220
3 x TUBE-C-100*100*3 | RIGID_FRAME | 10.1107 | TUBE-C-100*100*3 | P99 | 220.138
2 x TUBE-C-100*100*3 | RIGID_FRAME | 10.0583 | TUBE-C-100*100*3 | P105 | 220
3 x TUBE-C-100*100*3 | RIGID_FRAME | 10.5281 | TUBE-C-100*100*3 | P98 | 220.138
2 x TUBE-C-100*100*3 | RIGID_FRAME | 9.57137 | TUBE-C-100*100*3 | P104 | 220
3 x TUBE-C-100*100*3 | RIGID_FRAME | 10.0411 | TUBE-C-100*100*3 | P97 | 220.138
2 x TUBE-C-100*100*3 | RIGID_FRAME | 9.50226 | TUBE-C-100*100*3 | P102 | 220
2 x UPF-100*50*4 | RIGID_FRAME | 36.9518 | UPF-100*50*4 | S29 | 104
4 x UPF-100*50*4 | RIGID_FRAME | 15.916 | UPF-100*50*4 | S36 | 50
4 x UPF-100*50*4 | RIGID_FRAME | 31.3701 | UPF-100*50*4 | S39 | 300
UPN140 | RIGID_FRAME | 119.865 | UPN140 | S86 | 60
6 x L60*6 | RIGID_FRAME | 1.2259 | L60*6 | H29 | 60
HEA120 | RIGID_FRAME | 41.7031 | HEA120 | M2 | 240
HEA120 | RIGID_FRAME | 42.0423 | HEA120 | M1 | 240
HEA100 | RIGID_FRAME | 42.7699 | HEA100 | N55 | 100
UPN100 | RIGID_FRAME | 65.2276 | UPN100 | S85 | 50
2 x L60*6 | RIGID_FRAME | 1.2259 | L60*6 | H23 | 60
UPF-100*50*4 | RIGID_FRAME | 70.7389 | UPF-100*50*4 | S11 | 300
4 x UPF-100*50*4 | RIGID_FRAME | 25.994 | UPF-100*50*4 | S38 | 300
2 x UPF-100*50*4 | RIGID_FRAME | 25.994 | UPF-100*50*4 | S37 | 300
IPEA300 | RIGID_FRAME | 763.793 | IPEA300 | N17 | 556.478
L50*5 | RIGID_FRAME | 14.066 | L50*5 | C33 | 50
2 x IPEA300 | RIGID_FRAME | 424.295 | IPEA300 | K13 | 150
IPEA300 | RIGID_FRAME | 796.623 | IPEA300 | N38 | 556.478
IPEA300 | RIGID_FRAME | 1299.31 | IPEA300 | N40 | 369.003
IPEA300 | RIGID_FRAME | 974.173 | IPEA300 | N9 | 369.003
IPE500 | RIGID_FRAME | 634.502 | IPE500 | P32 | 333.5
14 x TUBE-C-60*60*3 | RIGID_FRAME | 12.3557 | TUBE-C-60*60*3 | L47 | 60
IPEA300 | RIGID_FRAME | 1256.59 | IPEA300 | N48 | 369.003
2 x IPEA300 | RIGID_FRAME | 974.173 | IPEA300 | N10 | 369.003
2 x IPEA300 | RIGID_FRAME | 1274.72 | IPEA300 | N8 | 369.003
2 x IPE500 | RIGID_FRAME | 634.502 | IPE500 | P36 | 333.5
2 x IPEA300 | RIGID_FRAME | 1256.59 | IPEA300 | N47 | 369.003
18 x L40*4 | RIGID_FRAME | 1.59575 | L40*4 | H55 | 40
4 x UPF-100*50*4 | RIGID_FRAME | 22.7293 | UPF-100*50*4 | S32 | 50
6 x HEA100 | RIGID_FRAME | 19.4711 | HEA100 | N54 | 100
IPE270 | RIGID_FRAME | 344.045 | IPE270 | K98 | 135
UPF-100*50*4 | RIGID_FRAME | 35.9015 | UPF-100*50*4 | S30 | 50
UPF-100*50*4 | RIGID_FRAME | 70.7389 | UPF-100*50*4 | S28 | 300
HEA100 | RIGID_FRAME | 42.7699 | HEA100 | N53 | 100
UPF-100*50*4 | RIGID_FRAME | 10.6408 | UPF-100*50*4 | S27 | 50
HEA100 | RIGID_FRAME | 42.7699 | HEA100 | N52 | 100
UPF-100*50*4 | RIGID_FRAME | 14.8911 | UPF-100*50*4 | S26 | 50
UPF-100*50*4 | RIGID_FRAME | 15.283 | UPF-100*50*4 | S20 | 50
2 x UPF-100*50*4 | RIGID_FRAME | 12.5098 | UPF-100*50*4 | S19 | 50
UPF-100*50*4 | RIGID_FRAME | 23.8861 | UPF-100*50*4 | S25 | 50
2 x HEA100 | RIGID_FRAME | 35.8144 | HEA100 | N51 | 100
UPF-100*50*4 | RIGID_FRAME | 15.1926 | UPF-100*50*4 | S35 | 50
10 x UPF-100*50*4 | RIGID_FRAME | 13.4442 | UPF-100*50*4 | S23 | 50
UPF-100*50*4 | RIGID_FRAME | 13.4442 | UPF-100*50*4 | S18 | 50
IPEA300 | RIGID_FRAME | 154.966 | IPEA300 | K46 | 150
UPF-100*50*4 | RIGID_FRAME | 19.678 | UPF-100*50*4 | S12 | 50
UPF-100*50*4 | RIGID_FRAME | 36.4975 | UPF-100*50*4 | S31 | 50
5 x UPF-100*50*4 | RIGID_FRAME | 32.0732 | UPF-100*50*4 | S21 | 50
L60*6 | RIGID_FRAME | 1.13911 | L60*6 | H32 | 60
6 x UPF-100*50*4 | RIGID_FRAME | 32.0732 | UPF-100*50*4 | S24 | 50
6 x UPF-100*50*4 | RIGID_FRAME | 36.4975 | UPF-100*50*4 | S15 | 50
UPF-100*50*4 | RIGID_FRAME | 36.4975 | UPF-100*50*4 | S16 | 50
5 x HEA100 | RIGID_FRAME | 41.9378 | HEA100 | N50 | 100
2 x UPF-100*50*4 | RIGID_FRAME | 19.678 | UPF-100*50*4 | S13 | 50
4 x UPF-100*50*4 | RIGID_FRAME | 36.4975 | UPF-100*50*4 | S14 | 50
10 x UPF-100*50*4 | RIGID_FRAME | 14.5897 | UPF-100*50*4 | S22 | 50
IPEA300 | RIGID_FRAME | 415.485 | IPEA300 | K37 | 150
5 x UPF-100*50*4 | RIGID_FRAME | 14.3787 | UPF-100*50*4 | S17 | 50
6 x L70*7 | RIGID_FRAME | 17.931 | L70*7 | C107 | 70
2 x L50*5 | RIGID_FRAME | 7.80672 | L50*5 | C94 | 50
2 x L50*5 | RIGID_FRAME | 7.7502 | L50*5 | C93 | 50
L50*5 | RIGID_FRAME | 15.9111 | L50*5 | C83 | 50
L50*5 | RIGID_FRAME | 15.9111 | L50*5 | C82 | 50
L50*5 | RIGID_FRAME | 11.7962 | L50*5 | C62 | 50
2 x L50*5 | RIGID_FRAME | 5.85288 | L50*5 | C85 | 50
2 x L50*5 | RIGID_FRAME | 5.55143 | L50*5 | C84 | 50
L50*5 | RIGID_FRAME | 11.7962 | L50*5 | C61 | 50
L50*5 | RIGID_FRAME | 11.7585 | L50*5 | C64 | 50
2 x L50*5 | RIGID_FRAME | 5.82856 | L50*5 | C87 | 50
2 x L50*5 | RIGID_FRAME | 5.79476 | L50*5 | C86 | 50
2 x L50*5 | RIGID_FRAME | 5.92191 | L50*5 | C92 | 50
L50*5 | RIGID_FRAME | 11.9775 | L50*5 | C66 | 50
2 x L50*5 | RIGID_FRAME | 5.8843 | L50*5 | C91 | 50
L50*5 | RIGID_FRAME | 12.1604 | L50*5 | C68 | 50
2 x L50*5 | RIGID_FRAME | 6.0444 | L50*5 | C90 | 50
2 x L50*5 | RIGID_FRAME | 5.7618 | L50*5 | C89 | 50
4 x L50*5 | RIGID_FRAME | 5.46655 | L50*5 | C88 | 50
4 x L70*7 | RIGID_FRAME | 17.8572 | L70*7 | C109 | 70
PL8 | RIGID_FRAME | 2.50236 | PL8 | G55 | 8
PL8 | RIGID_FRAME | 2.56961 | PL8 | G54 | 8
PL8 | RIGID_FRAME | 2.43946 | PL8 | G53 | 8
PL8 | RIGID_FRAME | 2.55846 | PL8 | G52 | 8
L50*5 | RIGID_FRAME | 11.7585 | L50*5 | C63 | 50
PL8 | RIGID_FRAME | 2.45814 | PL8 | G51 | 8
PL8 | RIGID_FRAME | 2.45814 | PL8 | G50 | 8
IPEA300 | RIGID_FRAME | 78.8326 | IPEA300 | K10 | 150
IPEA300 | RIGID_FRAME | 1278.05 | IPEA300 | N7 | 369.003
IPEA300 | RIGID_FRAME | 976.652 | IPEA300 | N11 | 369.007
L50*5 | RIGID_FRAME | 12.1604 | L50*5 | C67 | 50
PL8 | RIGID_FRAME | 4.40188 | PL8 | G12 | 8
PL8 | RIGID_FRAME | 5.49955 | PL8 | G56 | 8
PL8 | RIGID_FRAME | 5.21228 | PL8 | G57 | 8
L50*5 | RIGID_FRAME | 11.9775 | L50*5 | C65 | 50
UPN260 | RIGID_FRAME | 306.774 | UPN260 | N27 | 90
2 x L40*4 | RIGID_FRAME | 3.80188 | L40*4 | C135 | 40
TUBE-C-100*100*3 | RIGID_FRAME | 11.4513 | TUBE-C-100*100*3 | M12 | 100
IPE200 | RIGID_FRAME | 146.005 | IPE200 | P12 | 220
TUBE-C-100*100*3 | RIGID_FRAME | 47.7692 | TUBE-C-100*100*3 | L101 | 100
PL1385 | RIGID_FRAME | 41874.6 | PL1385 | Z64 | 1385
2 x PL1520 | RIGID_FRAME | 97382.3 | PL1520 | Z63 | 1520
PL8 | RIGID_FRAME | 2.20249 | PL8 | G14 | 8
2 x PL8 | RIGID_FRAME | 9.70969 | PL8 | G21 | 8
12 x L50*5 | RIGID_FRAME | 14.3831 | L50*5 | C41 | 50
2 x PL8 | RIGID_FRAME | 2.89787 | PL8 | G64 | 8
IPE200 | RIGID_FRAME | 138.399 | IPE200 | P16 | 220
3 x IPE200 | RIGID_FRAME | 146.005 | IPE200 | P13 | 220
2 x L60*6 | RIGID_FRAME | 1.30184 | L60*6 | H11 | 60
L60*6 | RIGID_FRAME | 1.05775 | L60*6 | H33 | 60
UPN260 | RIGID_FRAME | 394.018 | UPN260 | N28 | 90
UPN260 | RIGID_FRAME | 225.597 | UPN260 | N26 | 90
IPEA300 | RIGID_FRAME | 430.223 | IPEA300 | K9 | 150
IPEA300 | RIGID_FRAME | 419.341 | IPEA300 | K40 | 150
5 x IPEA300 | RIGID_FRAME | 430.223 | IPEA300 | K7 | 150
3 x IPEA300 | RIGID_FRAME | 423.855 | IPEA300 | K6 | 150
IPEA300 | RIGID_FRAME | 415.663 | IPEA300 | K39 | 150
UPN260 | RIGID_FRAME | 196.857 | UPN260 | N31 | 90
UPN180 | RIGID_FRAME | 3.5168 | UPN180 | H50 | 70
IPEA300 | RIGID_FRAME | 430.159 | IPEA300 | K27 | 150
IPEA300 | RIGID_FRAME | 1226.03 | IPEA300 | N12 | 322.973
3 x UPF-100*50*4 | RIGID_FRAME | 23.8861 | UPF-100*50*4 | S33 | 50
2 x UPF-100*50*4 | RIGID_FRAME | 23.8861 | UPF-100*50*4 | S34 | 50
IPE200 | RIGID_FRAME | 151.436 | IPE200 | P19 | 210
UPN180 | RIGID_FRAME | 124.679 | UPN180 | L30 | 70
IPE500 | RIGID_FRAME | 641.645 | IPE500 | P27 | 487.998
2 x L50*5 | RIGID_FRAME | 13.9833 | L50*5 | C59 | 50
12 x L50*5 | RIGID_FRAME | 13.5688 | L50*5 | C58 | 50
6 x L50*5 | RIGID_FRAME | 13.8326 | L50*5 | C57 | 50
2 x IPEA300 | RIGID_FRAME | 951.933 | IPEA300 | N13 | 369.003
4 x L50*5 | RIGID_FRAME | 13.7007 | L50*5 | C60 | 50
20 x L70*7 | RIGID_FRAME | 17.931 | L70*7 | C108 | 70
PL8 | RIGID_FRAME | 6.57196 | PL8 | G31 | 8
2 x L70*7 | RIGID_FRAME | 0.88548 | L70*7 | H38 | 70
3 x PL8 | RIGID_FRAME | 7.51422 | PL8 | G1 | 8
3 x L50*5 | RIGID_FRAME | 23.0868 | L50*5 | C95 | 50
3 x L50*5 | RIGID_FRAME | 22.4086 | L50*5 | C96 | 50
12 x L50*5 | RIGID_FRAME | 13.8211 | L50*5 | C27 | 50
10 x L50*5 | RIGID_FRAME | 14.0848 | L50*5 | C26 | 50
3 x PL8 | RIGID_FRAME | 10.1004 | PL8 | G32 | 8
2 x L50*5 | RIGID_FRAME | 13.482 | L50*5 | C40 | 50
3 x PL8 | RIGID_FRAME | 6.82104 | PL8 | G3 | 8
6 x PL8 | RIGID_FRAME | 9.15352 | PL8 | G43 | 8
BLU300*80*5 | RIGID_FRAME | 92.3245 | BLU300*80*5 | P109 | 260
BLU300*80*5 | RIGID_FRAME | 63.8676 | BLU300*80*5 | L5 | 80
BLU300*80*5 | RIGID_FRAME | 51.5038 | BLU300*80*5 | L4 | 80
BLU300*80*5 | RIGID_FRAME | 89.6837 | BLU300*80*5 | P112 | 260
FPL255*8 | RIGID_FRAME | 3.20284 | FPL255*8 | H54 | 255
FPL255*8 | RIGID_FRAME | 3.20284 | FPL255*8 | H52 | 255
FPL255*8 | RIGID_FRAME | 2.88256 | FPL255*8 | H53 | 255
FPL255*8 | RIGID_FRAME | 3.37354 | FPL255*8 | H51 | 255
IPEA300 | RIGID_FRAME | 227.055 | IPEA300 | P116 | 233.05
UPN180 | RIGID_FRAME | 124.173 | UPN180 | L29 | 70
IPE500 | RIGID_FRAME | 644.436 | IPE500 | P25 | 539.305
UPN180 | RIGID_FRAME | 59.3272 | UPN180 | P45 | 250
UPN180 | RIGID_FRAME | 59.3272 | UPN180 | P44 | 250
BLU300*80*5 | RIGID_FRAME | 91.2468 | BLU300*80*5 | P111 | 260
BLU300*80*5 | RIGID_FRAME | 91.8136 | BLU300*80*5 | P110 | 260
IPEA300 | RIGID_FRAME | 425.985 | IPEA300 | K55 | 150
PL20*110 | RIGID_FRAME | 3.6267 | PL20*110 | Y1 | 20
IPE200 | RIGID_FRAME | 150.494 | IPE200 | P20 | 180
2 x L70*7 | RIGID_FRAME | 45.6265 | L70*7 | V14 | 70
2 x L70*7 | RIGID_FRAME | 47.4981 | L70*7 | V13 | 70
2 x L70*7 | RIGID_FRAME | 45.4789 | L70*7 | V15 | 70
2 x L70*7 | RIGID_FRAME | 43.3269 | L70*7 | V12 | 70
PL8 | RIGID_FRAME | 5.6477 | PL8 | G33 | 8
IPEA300 | RIGID_FRAME | 241.229 | IPEA300 | P115 | 556.886
2 x TUBE-C-90*90*3 | RIGID_FRAME | 95.6239 | TUBE-C-90*90*3 | L98 | 90
2 x TUBE-C-60*60*3 | RIGID_FRAME | 9.66389 | TUBE-C-60*60*3 | L44 | 129.9
2 x IPEA300 | RIGID_FRAME | 422.456 | IPEA300 | K18 | 150
IPEA300 | RIGID_FRAME | 726.24 | IPEA300 | N14 | 391.967
PL200 | REINFORCEMENT_UNIT | 16981.4 | PL200 | Z43 | 200 | Tekla Assemblages - Poids ferraillage Elément béton: 0 kg
PL3450*200 | REINFORCEMENT_UNIT | 10461.8 | PL3450*200 | Z20 | 200 | Tekla Assemblages - Poids ferraillage Elément béton: 0 kg
PL5950*200 | REINFORCEMENT_UNIT | 4499.12 | PL5950*200 | Z50 | 200 | Tekla Assemblages - Poids ferraillage Elément béton: 0 kg
PL5950*200 | REINFORCEMENT_UNIT | 8119.18 | PL5950*200 | Z42 | 200 | Tekla Assemblages - Poids ferraillage Elément béton: 0 kg
PL5950*200 | REINFORCEMENT_UNIT | 25773.3 | PL5950*200 | Z51 | 200 | Tekla Assemblages - Poids ferraillage Elément béton: 0 kg
PL5950*200 | REINFORCEMENT_UNIT | 64027.7 | PL5950*200 | Z41 | 200 | Tekla Assemblages - Poids ferraillage Elément béton: 0 kg
2 x HEA120 | RIGID_FRAME | 41.1379 | HEA120 | M4 | 240
UPF-120*50*4 | RIGID_FRAME | 34.7542 | UPF-120*50*4 | L9 | 56
3 x TUBE-C-90*90*3 | RIGID_FRAME | 85.2539 | TUBE-C-90*90*3 | L94 | 90
2 x TUBE-C-100*100*3 | RIGID_FRAME | 94.1482 | TUBE-C-100*100*3 | L102 | 100
TUBE-C-90*90*3 | RIGID_FRAME | 42.7602 | TUBE-C-90*90*3 | L99 | 90
2 x TUBE-C-90*90*3 | RIGID_FRAME | 62.7323 | TUBE-C-90*90*3 | L93 | 90
TUBE-C-90*90*3 | RIGID_FRAME | 95.7924 | TUBE-C-90*90*3 | L55 | 90
TUBE-C-90*90*3 | RIGID_FRAME | 43.6235 | TUBE-C-90*90*3 | L100 | 90
2 x L60*6 | RIGID_FRAME | 0.54244 | L60*6 | H12 | 60
IPE500 | RIGID_FRAME | 635.855 | IPE500 | P24 | 419.016
TUBE-C-90*90*3 | RIGID_FRAME | 70.9693 | TUBE-C-90*90*3 | L24 | 90
TUBE-C-90*90*3 | RIGID_FRAME | 95.6239 | TUBE-C-90*90*3 | L108 | 90
3 x TUBE-C-90*90*3 | RIGID_FRAME | 70.9693 | TUBE-C-90*90*3 | L21 | 90
IPEA300 | RIGID_FRAME | 225.162 | IPEA300 | P117 | 180
2 x TUBE-C-90*90*3 | RIGID_FRAME | 95.6239 | TUBE-C-90*90*3 | L97 | 90
2 x TUBE-C-60*60*3 | RIGID_FRAME | 9.66389 | TUBE-C-60*60*3 | L42 | 129.9
TUBE-C-90*90*3 | RIGID_FRAME | 95.6239 | TUBE-C-90*90*3 | L107 | 90
TUBE-C-60*60*3 | RIGID_FRAME | 9.66389 | TUBE-C-60*60*3 | L43 | 129.9
2 x TUBE-C-60*60*3 | RIGID_FRAME | 12.2943 | TUBE-C-60*60*3 | L48 | 60
2 x IPEA300 | RIGID_FRAME | 730.566 | IPEA300 | N16 | 437.999
IPE400 | RIGID_FRAME | 420.955 | IPE400 | P37 | 218.09
16 x L70*7 | RIGID_FRAME | 1.62338 | L70*7 | H36 | 70
2 x L70*7 | RIGID_FRAME | 49.7287 | L70*7 | V8 | 70
2 x L70*7 | RIGID_FRAME | 51.2501 | L70*7 | V10 | 70
2 x L70*7 | RIGID_FRAME | 37.3213 | L70*7 | V9 | 70
2 x L70*7 | RIGID_FRAME | 38.2885 | L70*7 | V11 | 70
4 x PL8 | RIGID_FRAME | 2.035 | PL8 | G26 | 8
2 x PL8 | RIGID_FRAME | 4.00549 | PL8 | G28 | 8
4 x PL8 | RIGID_FRAME | 2.05316 | PL8 | G25 | 8
L60*6 | RIGID_FRAME | 9.31936 | L60*6 | L12 | 60
10 x L50*5 | RIGID_FRAME | 13.7085 | L50*5 | C55 | 50
L70*7 | RIGID_FRAME | 37.0795 | L70*7 | C120 | 70
IPE400 | RIGID_FRAME | 446.756 | IPE400 | P3 | 200
6 x PL8 | RIGID_FRAME | 9.10531 | PL8 | G39 | 8
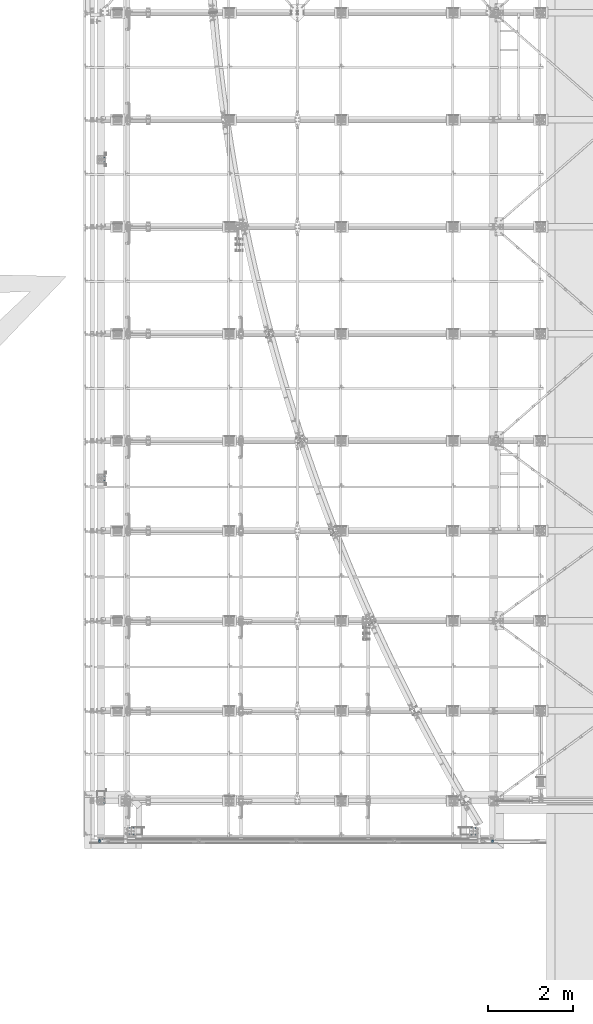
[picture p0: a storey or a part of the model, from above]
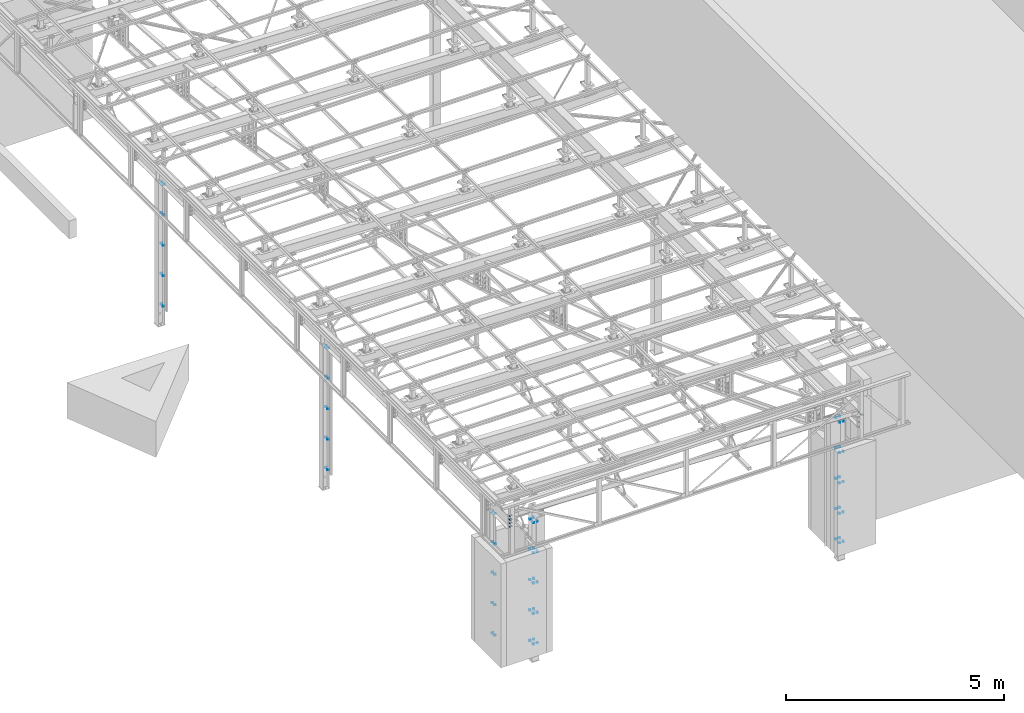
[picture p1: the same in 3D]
Properties of the parts of a building model (IFC2X3), part 7 of 13

# IfcElementAssembly (4667)
Name | PredefinedType | Poids Assemblage/Elément béton (kg) | Nom Assemblage/Elément béton | Repère Assemblage/Elément béton | Width (mm)
L50*5 | RIGID_FRAME | 12.9365 | L50*5 | C39 | 50
L50*5 | RIGID_FRAME | 13.55 | L50*5 | C38 | 50
2 x L70*7 | RIGID_FRAME | 47.1633 | L70*7 | V7 | 70
2 x L70*7 | RIGID_FRAME | 43.3269 | L70*7 | V4 | 70
2 x L70*7 | RIGID_FRAME | 45.4789 | L70*7 | V6 | 70
2 x L70*7 | RIGID_FRAME | 46.0215 | L70*7 | V5 | 70
TUBE-C-150*150*4 | RIGID_FRAME | 113.645 | TUBE-C-150*150*4 | B5 | 160.03
3 x TUBE-C-120*120*4 | RIGID_FRAME | 57.8104 | TUBE-C-120*120*4 | B7 | 160.022
TUBE-C-120*120*4 | RIGID_FRAME | 54.5074 | TUBE-C-120*120*4 | B8 | 160.025
IPEA300 | RIGID_FRAME | 429.269 | IPEA300 | K26 | 150
3 x PL140*10 | RIGID_FRAME | 4.47264 | PL140*10 | H5 | 88.95
IPEA300 | RIGID_FRAME | 424.406 | IPEA300 | K15 | 150
2 x L70*7 | RIGID_FRAME | 18.6689 | L70*7 | C121 | 70
2 x L50*5 | RIGID_FRAME | 13.9833 | L50*5 | C37 | 50
2 x IPEA300 | RIGID_FRAME | 420.158 | IPEA300 | K41 | 150
IPE400 | RIGID_FRAME | 443.508 | IPE400 | P2 | 218.09
IPE400 | RIGID_FRAME | 433.49 | IPE400 | P4 | 200
IPE500 | RIGID_FRAME | 620.698 | IPE500 | P28 | 250
2 x HEA180 | RIGID_FRAME | 4.97847 | HEA180 | H10 | 180
2 x L50*5 | RIGID_FRAME | 11.8395 | L50*5 | C21 | 50
6 x L50*5 | RIGID_FRAME | 11.5757 | L50*5 | C20 | 50
PL8 | RIGID_FRAME | 4.63098 | PL8 | G5 | 8
2 x PL8 | RIGID_FRAME | 2.57354 | PL8 | G27 | 8
PL8 | RIGID_FRAME | 7.12217 | PL8 | G46 | 8
PL8 | RIGID_FRAME | 2.02629 | PL8 | G36 | 8
PL8 | RIGID_FRAME | 4.37853 | PL8 | G4 | 8
2 x L50*5 | RIGID_FRAME | 10.8189 | L50*5 | C10 | 50
8 x L70*7 | RIGID_FRAME | 16.16 | L70*7 | C106 | 70
2 x L70*7 | RIGID_FRAME | 16.2491 | L70*7 | C114 | 70
4 x L70*7 | RIGID_FRAME | 7.19452 | L70*7 | C97 | 70
2 x L50*5 | RIGID_FRAME | 15.6359 | L50*5 | C7 | 50
FPL6*120 | RIGID_FRAME | 0.77967 | FPL6*120 | H46 | 120
2 x L50*5 | RIGID_FRAME | 11.1957 | L50*5 | C12 | 50
8 x L50*5 | RIGID_FRAME | 10.7812 | L50*5 | C13 | 50
8 x L50*5 | RIGID_FRAME | 11.0639 | L50*5 | C11 | 50
2 x L50*5 | RIGID_FRAME | 11.3515 | L50*5 | C19 | 50
2 x L50*5 | RIGID_FRAME | 11.6084 | L50*5 | C14 | 50
2 x L50*5 | RIGID_FRAME | 11.6401 | L50*5 | C17 | 50
2 x L50*5 | RIGID_FRAME | 11.4327 | L50*5 | C15 | 50
2 x L50*5 | RIGID_FRAME | 11.6401 | L50*5 | C16 | 50
2 x L70*7 | RIGID_FRAME | 17.7834 | L70*7 | C105 | 70
2 x L70*7 | RIGID_FRAME | 25.759 | L70*7 | C100 | 70
L50*5 | RIGID_FRAME | 16.4591 | L50*5 | C9 | 50
2 x L50*5 | RIGID_FRAME | 12.0357 | L50*5 | C18 | 50
L50*5 | RIGID_FRAME | 16.4591 | L50*5 | C8 | 50
PL8 | RIGID_FRAME | 7.94385 | PL8 | G10 | 8
PL8 | RIGID_FRAME | 10.6169 | PL8 | G65 | 8
PL8 | RIGID_FRAME | 7.9331 | PL8 | G45 | 8
2 x PL8 | RIGID_FRAME | 4.37716 | PL8 | G49 | 8
PL8 | RIGID_FRAME | 7.82778 | PL8 | G44 | 8
PL8 | RIGID_FRAME | 6.10912 | PL8 | G24 | 8
IPE400 | RIGID_FRAME | 433.474 | IPE400 | P38 | 200
PL220 | REINFORCEMENT_UNIT | 67546.4 | PL220 | Z62 | 220 | Tekla Assemblages - Poids ferraillage Elément béton: 0 kg
PL200 | REINFORCEMENT_UNIT | 64365.8 | PL200 | Z46 | 200 | Tekla Assemblages - Poids ferraillage Elément béton: 0 kg
PL3920*180 | REINFORCEMENT_UNIT | 29287.1 | PL3920*180 | Z3 | 180 | Tekla Assemblages - Poids ferraillage Elément béton: 0 kg
PL4450*200 | REINFORCEMENT_UNIT | 18176 | PL4450*200 | Z19 | 200 | Tekla Assemblages - Poids ferraillage Elément béton: 0 kg
L50*5 | RIGID_FRAME | 15.4098 | L50*5 | C4 | 50
L50*5 | RIGID_FRAME | 13.7834 | L50*5 | C34 | 50
PL3450*200 | REINFORCEMENT_UNIT | 10751.6 | PL3450*200 | Z18 | 200 | Tekla Assemblages - Poids ferraillage Elément béton: 0 kg
PL4860*250 | REINFORCEMENT_UNIT | 25836.6 | PL4860*250 | Z61 | 250 | Tekla Assemblages - Poids ferraillage Elément béton: 0 kg
PL4860*200 | REINFORCEMENT_UNIT | 14686.4 | PL4860*200 | Z17 | 200 | Tekla Assemblages - Poids ferraillage Elément béton: 0 kg
PL4860*200 | REINFORCEMENT_UNIT | 33490.8 | PL4860*200 | Z49 | 200 | Tekla Assemblages - Poids ferraillage Elément béton: 0 kg
PL4860*200 | REINFORCEMENT_UNIT | 25593.7 | PL4860*200 | Z45 | 200 | Tekla Assemblages - Poids ferraillage Elément béton: 0 kg
PL5680*200 | REINFORCEMENT_UNIT | 21663.4 | PL5680*200 | Z40 | 200 | Tekla Assemblages - Poids ferraillage Elément béton: 0 kg
PL4500*200 | REINFORCEMENT_UNIT | 1597.05 | PL4500*200 | Z16 | 200 | Tekla Assemblages - Poids ferraillage Elément béton: 0 kg
PL2800*200 | REINFORCEMENT_UNIT | 23629.2 | PL2800*200 | Z58 | 200 | Tekla Assemblages - Poids ferraillage Elément béton: 0 kg
PL3860*200 | REINFORCEMENT_UNIT | 10740.9 | PL3860*200 | Z48 | 200 | Tekla Assemblages - Poids ferraillage Elément béton: 0 kg
PL5940*200 | REINFORCEMENT_UNIT | 52889.8 | PL5940*200 | Z15 | 200 | Tekla Assemblages - Poids ferraillage Elément béton: 0 kg
2 x PL6140*400 | REINFORCEMENT_UNIT | 2063.04 | PL6140*400 | Z77 | 400 | Tekla Assemblages - Poids ferraillage Elément béton: 0 kg
PL6140*400 | REINFORCEMENT_UNIT | 4126.08 | PL6140*400 | Z78 | 400 | Tekla Assemblages - Poids ferraillage Elément béton: 0 kg
PL5960*200 | REINFORCEMENT_UNIT | 28999.8 | PL5960*200 | Z14 | 200 | Tekla Assemblages - Poids ferraillage Elément béton: 0 kg
PL6000*180 | REINFORCEMENT_UNIT | 105711 | PL6000*180 | Z12 | 180 | Tekla Assemblages - Poids ferraillage Elément béton: 0 kg
PL5680*200 | REINFORCEMENT_UNIT | 22080.8 | PL5680*200 | Z37 | 200 | Tekla Assemblages - Poids ferraillage Elément béton: 0 kg
PL6000*200 | REINFORCEMENT_UNIT | 27417.6 | PL6000*200 | Z52 | 200 | Tekla Assemblages - Poids ferraillage Elément béton: 0 kg
PL6000*180 | REINFORCEMENT_UNIT | 156946 | PL6000*180 | Z1 | 180 | Tekla Assemblages - Poids ferraillage Elément béton: 0 kg
PL6000*180 | REINFORCEMENT_UNIT | 109855 | PL6000*180 | Z2 | 180 | Tekla Assemblages - Poids ferraillage Elément béton: 0 kg
32 x PL6*240 | RIGID_FRAME | 3.73032 | PL6*240 | H8 | 6
32 x PL10*150 | RIGID_FRAME | 6.00525 | PL10*150 | H3 | 10
64 x PL10*55 | RIGID_FRAME | 2.20193 | PL10*55 | H4 | 10

# IfcFastener (6774)
In: Undefined
Tekla Soudure Commun - Type d'assemblage: ATELIER; Type de cordon: Continu; sets with these values: 2
Tekla Soudure dessus - Type1: W10; sets with these values: 2
Tekla Soudure dessous - sets with these values: 2
Name | N° soudure | Linéaire/Périphérique | Dimension1 (mm) | Dimension2 (mm) | Type2
Weld | 331 | Droit | 5 | 0 | Aucun
Weld | 330 | Droit | 6 | 6 | W10
Weld | 329 | Droit | 6 | 6 | W10
Weld | 328 | Droit | 8 | 8 | W10
Weld | 327 | Droit | 8 | 8 | W10
Weld | 326 | Droit | 8 | 8 | W10
2 x Weld | 325 | Droit | 8 | 8 | W10
Weld | 324 | Droit | 6 | 6 | W10
Weld | 323 | Droit | 6 | 6 | W10
2 x Weld | 322 | Droit | 8 | 8 | W10
Weld | 321 | Droit | 8 | 8 | W10
Weld | 320 | Droit | 8 | 8 | W10
2 x Weld | 319 | Droit | 8 | 8 | W10
2 x Weld | 318 | Droit | 8 | 8 | W10
2 x Weld | 317 | Droit | 8 | 8 | W10
2 x Weld | 316 | Droit | 8 | 8 | W10
2 x Weld | 315 | Droit | 8 | 8 | W10
Weld | 314 | Droit | 6 | 6 | W10
Weld | 313 | Droit | 8 | 8 | W10
Weld | 312 | Droit | 5 | 0 | Aucun
Weld | 311 | Droit | 6 | 6 | W10
Weld | 310 | Droit | 6 | 6 | W10
Weld | 309 | Droit | 8 | 8 | W10
Weld | 308 | Droit | 8 | 8 | W10
Weld | 307 | Droit | 8 | 8 | W10
Weld | 306 | Droit | 8 | 8 | W10
Weld | 305 | Droit | 6 | 6 | W10
Weld | 304 | Droit | 6 | 6 | W10
2 x Weld | 303 | Droit | 8 | 8 | W10
2 x Weld | 302 | Droit | 8 | 8 | W10
2 x Weld | 301 | Droit | 8 | 8 | W10
2 x Weld | 300 | Droit | 8 | 8 | W10
Weld | 299 | Droit | 6 | 6 | W10
Weld | 298 | Droit | 6 | 6 | W10
Weld | 297 | Droit | 8 | 8 | W10
Weld | 296 | Droit | 8 | 8 | W10
Weld | 295 | Droit | 8 | 8 | W10
Weld | 294 | Droit | 8 | 8 | W10
Weld | 293 | Droit | 8 | 8 | W10
Weld | 292 | Droit | 8 | 8 | W10
Weld | 291 | Droit | 8 | 8 | W10
Weld | 290 | Droit | 8 | 8 | W10
Weld | 289 | Droit | 6 | 6 | W10
2 x Weld | 288 | Droit | 8 | 8 | W10
Weld | 9298 | Autour | 6 | 0 | Aucun
Weld | 9297 | Autour | 6 | 0 | Aucun
Weld | 9295 | Droit | 2 | 2 | W10
Weld | 9294 | Droit | 2 | 2 | W10
Weld | 9292 | Droit | 2 | 2 | W10
Weld | 9291 | Droit | 2 | 2 | W10
Weld | 9289 | Droit | 2 | 2 | W10
Weld | 9288 | Droit | 2 | 2 | W10
Weld | 9286 | Droit | 2 | 2 | W10
Weld | 9285 | Droit | 2 | 2 | W10
Weld | 9283 | Droit | 2 | 2 | W10
Weld | 9282 | Droit | 2 | 2 | W10
Weld | 9280 | Droit | 2 | 2 | W10
Weld | 9279 | Droit | 2 | 2 | W10
Weld | 9277 | Droit | 2 | 2 | W10
Weld | 9276 | Droit | 2 | 2 | W10
Weld | 9274 | Droit | 2 | 2 | W10
Weld | 9273 | Droit | 2 | 2 | W10
Weld | 9271 | Droit | 2 | 2 | W10
Weld | 9270 | Droit | 2 | 2 | W10
Weld | 9268 | Droit | 2 | 2 | W10
Weld | 9267 | Droit | 2 | 2 | W10
Weld | 9265 | Droit | 2 | 2 | W10
Weld | 9264 | Droit | 2 | 2 | W10
Weld | 9262 | Droit | 2 | 2 | W10
Weld | 9261 | Droit | 2 | 2 | W10
Weld | 9259 | Droit | 2 | 2 | W10
Weld | 9258 | Droit | 2 | 2 | W10
Weld | 9256 | Droit | 2 | 2 | W10
Weld | 9255 | Droit | 2 | 2 | W10
Weld | 9253 | Droit | 2 | 2 | W10
Weld | 9252 | Droit | 2 | 2 | W10
Weld | 9250 | Droit | 2 | 2 | W10
Weld | 9249 | Droit | 2 | 2 | W10
Weld | 9247 | Droit | 2 | 2 | W10
Weld | 9246 | Droit | 2 | 2 | W10
Weld | 9244 | Droit | 2 | 2 | W10
Weld | 9243 | Droit | 2 | 2 | W10
Weld | 9241 | Droit | 2 | 2 | W10
Weld | 9240 | Droit | 2 | 2 | W10
Weld | 9238 | Droit | 2 | 2 | W10
Weld | 9237 | Droit | 2 | 2 | W10
Weld | 9234 | Autour | 6 | 0 | Aucun
Weld | 9233 | Autour | 6 | 0 | Aucun
Weld | 9232 | Autour | 6 | 0 | Aucun
Weld | 9231 | Autour | 6 | 0 | Aucun
Weld | 9230 | Autour | 6 | 0 | Aucun
Weld | 9224 | Autour | 6 | 0 | Aucun
Weld | 9220 | Autour | 6 | 0 | Aucun
Weld | 9218 | Autour | 6 | 0 | Aucun
Weld | 9217 | Autour | 6 | 0 | Aucun
Weld | 9215 | Autour | 6 | 0 | Aucun
Weld | 9213 | Autour | 6 | 0 | Aucun
Weld | 9212 | Autour | 6 | 0 | Aucun
Weld | 9211 | Autour | 6 | 0 | Aucun
Weld | 9210 | Autour | 6 | 0 | Aucun
Weld | 9209 | Autour | 6 | 0 | Aucun
Weld | 9207 | Autour | 6 | 0 | Aucun
Weld | 9206 | Autour | 6 | 0 | Aucun
Weld | 9205 | Autour | 6 | 0 | Aucun
Weld | 9178 | Autour | 6 | 0 | Aucun
Weld | 9177 | Autour | 6 | 0 | Aucun
Weld | 9171 | Autour | 6 | 0 | Aucun
Weld | 9170 | Autour | 6 | 0 | Aucun
Weld | 9168 | Autour | 6 | 0 | Aucun
Weld | 9165 | Autour | 6 | 0 | Aucun
Weld | 9164 | Autour | 6 | 0 | Aucun
Weld | 9163 | Autour | 6 | 0 | Aucun
Weld | 9150 | Autour | 6 | 0 | Aucun
Weld | 9129 | Autour | 6 | 0 | Aucun
Weld | 9101 | Autour | 6 | 0 | Aucun
Weld | 9100 | Autour | 6 | 0 | Aucun
Weld | 9097 | Droit | 2 | 2 | W10
Weld | 9096 | Droit | 2 | 2 | W10
Weld | 9094 | Droit | 2 | 2 | W10
Weld | 9093 | Droit | 2 | 2 | W10
Weld | 9091 | Droit | 2 | 2 | W10
Weld | 9090 | Droit | 2 | 2 | W10
Weld | 9088 | Droit | 2 | 2 | W10
Weld | 9087 | Droit | 2 | 2 | W10
Weld | 9085 | Droit | 2 | 2 | W10
Weld | 9084 | Droit | 2 | 2 | W10
Weld | 9082 | Droit | 2 | 2 | W10
Weld | 9081 | Droit | 2 | 2 | W10
Weld | 9079 | Droit | 2 | 2 | W10
Weld | 9078 | Droit | 2 | 2 | W10
Weld | 9076 | Droit | 2 | 2 | W10
Weld | 9075 | Droit | 2 | 2 | W10
Weld | 9073 | Droit | 2 | 2 | W10
Weld | 9072 | Droit | 2 | 2 | W10
Weld | 9070 | Droit | 2 | 2 | W10
Weld | 9069 | Droit | 2 | 2 | W10
Weld | 9067 | Droit | 2 | 2 | W10
Weld | 9066 | Droit | 2 | 2 | W10
Weld | 9064 | Droit | 2 | 2 | W10
Weld | 9063 | Droit | 2 | 2 | W10
Weld | 9061 | Droit | 2 | 2 | W10
Weld | 9060 | Droit | 2 | 2 | W10
Weld | 9058 | Droit | 2 | 2 | W10
Weld | 9057 | Droit | 2 | 2 | W10
Weld | 9055 | Droit | 2 | 2 | W10
Weld | 9054 | Droit | 2 | 2 | W10
Weld | 9052 | Droit | 2 | 2 | W10
Weld | 9051 | Droit | 2 | 2 | W10
Weld | 9049 | Droit | 2 | 2 | W10
Weld | 9048 | Droit | 2 | 2 | W10
Weld | 9046 | Droit | 2 | 2 | W10
Weld | 9045 | Droit | 2 | 2 | W10
Weld | 9043 | Droit | 2 | 2 | W10
Weld | 9042 | Droit | 2 | 2 | W10
Weld | 9040 | Droit | 2 | 2 | W10
Weld | 9039 | Droit | 2 | 2 | W10
Weld | 9036 | Autour | 6 | 0 | Aucun
Weld | 9035 | Autour | 6 | 0 | Aucun
Weld | 9034 | Autour | 6 | 0 | Aucun
Weld | 9033 | Autour | 6 | 0 | Aucun
Weld | 9029 | Autour | 6 | 0 | Aucun
Weld | 9027 | Autour | 6 | 0 | Aucun
Weld | 9026 | Autour | 6 | 0 | Aucun
Weld | 9025 | Autour | 6 | 0 | Aucun
Weld | 9024 | Autour | 6 | 0 | Aucun
Weld | 9023 | Autour | 6 | 0 | Aucun
Weld | 9022 | Autour | 6 | 0 | Aucun
Weld | 9021 | Autour | 6 | 0 | Aucun
Weld | 9020 | Autour | 6 | 0 | Aucun
Weld | 9019 | Autour | 6 | 0 | Aucun
Weld | 9018 | Autour | 6 | 0 | Aucun
Weld | 9017 | Autour | 6 | 0 | Aucun
Weld | 9016 | Autour | 6 | 0 | Aucun
Weld | 9015 | Autour | 6 | 0 | Aucun
Weld | 9014 | Autour | 6 | 0 | Aucun
Weld | 9013 | Autour | 6 | 0 | Aucun
Weld | 9012 | Autour | 6 | 0 | Aucun
Weld | 9011 | Autour | 6 | 0 | Aucun
Weld | 9010 | Autour | 6 | 0 | Aucun
Weld | 9009 | Autour | 6 | 0 | Aucun
Weld | 9008 | Autour | 6 | 0 | Aucun
Weld | 9007 | Autour | 6 | 0 | Aucun
Weld | 9006 | Autour | 6 | 0 | Aucun
Weld | 9005 | Autour | 6 | 0 | Aucun
Weld | 9004 | Autour | 6 | 0 | Aucun
Weld | 9003 | Autour | 6 | 0 | Aucun
Weld | 9002 | Autour | 6 | 0 | Aucun
Weld | 9001 | Autour | 6 | 0 | Aucun
Weld | 9000 | Autour | 6 | 0 | Aucun
Weld | 8999 | Autour | 6 | 0 | Aucun
Weld | 8998 | Autour | 6 | 0 | Aucun
Weld | 8997 | Autour | 6 | 0 | Aucun
Weld | 8996 | Autour | 6 | 0 | Aucun
Weld | 8995 | Autour | 6 | 0 | Aucun
Weld | 8994 | Autour | 6 | 0 | Aucun
Weld | 8993 | Autour | 6 | 0 | Aucun
Weld | 8991 | Autour | 6 | 0 | Aucun
Weld | 8990 | Autour | 6 | 0 | Aucun
Weld | 8989 | Autour | 6 | 0 | Aucun
Weld | 8988 | Autour | 6 | 0 | Aucun
Weld | 8987 | Autour | 6 | 0 | Aucun
Weld | 8986 | Autour | 6 | 0 | Aucun
Weld | 8985 | Autour | 6 | 0 | Aucun
Weld | 8984 | Autour | 6 | 0 | Aucun
Weld | 8983 | Autour | 6 | 0 | Aucun
Weld | 8982 | Autour | 6 | 0 | Aucun
Weld | 8981 | Autour | 6 | 0 | Aucun
Weld | 8980 | Autour | 6 | 0 | Aucun
Weld | 8979 | Autour | 6 | 0 | Aucun
Weld | 8978 | Autour | 6 | 0 | Aucun
Weld | 8977 | Autour | 6 | 0 | Aucun
Weld | 8976 | Autour | 6 | 0 | Aucun
Weld | 8975 | Autour | 6 | 0 | Aucun
Weld | 8974 | Autour | 6 | 0 | Aucun
Weld | 8973 | Autour | 6 | 0 | Aucun
Weld | 8972 | Autour | 6 | 0 | Aucun
Weld | 8971 | Autour | 6 | 0 | Aucun
Weld | 8970 | Autour | 6 | 0 | Aucun
Weld | 8969 | Autour | 6 | 0 | Aucun
Weld | 8967 | Autour | 6 | 0 | Aucun
Weld | 8966 | Autour | 6 | 0 | Aucun
Weld | 8965 | Autour | 6 | 0 | Aucun
Weld | 8964 | Autour | 6 | 0 | Aucun
Weld | 8963 | Autour | 6 | 0 | Aucun
Weld | 8962 | Autour | 6 | 0 | Aucun
Weld | 8959 | Autour | 6 | 0 | Aucun
Weld | 8958 | Autour | 6 | 0 | Aucun
Weld | 8957 | Autour | 6 | 0 | Aucun
Weld | 8956 | Autour | 6 | 0 | Aucun
Weld | 8952 | Autour | 6 | 0 | Aucun
Weld | 8951 | Autour | 6 | 0 | Aucun
Weld | 8950 | Autour | 6 | 0 | Aucun
Weld | 8949 | Autour | 6 | 0 | Aucun
Weld | 8948 | Autour | 6 | 0 | Aucun
Weld | 8947 | Autour | 6 | 0 | Aucun
Weld | 8946 | Autour | 6 | 0 | Aucun
Weld | 8945 | Autour | 6 | 0 | Aucun
Weld | 8944 | Autour | 6 | 0 | Aucun
Weld | 8943 | Autour | 6 | 0 | Aucun
Weld | 8942 | Autour | 6 | 0 | Aucun
Weld | 8941 | Autour | 6 | 0 | Aucun
Weld | 8940 | Autour | 6 | 0 | Aucun
Weld | 8939 | Autour | 6 | 0 | Aucun
Weld | 8938 | Autour | 6 | 0 | Aucun
Weld | 8937 | Autour | 6 | 0 | Aucun
Weld | 8935 | Autour | 6 | 0 | Aucun
Weld | 8934 | Autour | 6 | 0 | Aucun
Weld | 8933 | Autour | 6 | 0 | Aucun
Weld | 8932 | Autour | 6 | 0 | Aucun
Weld | 8928 | Autour | 6 | 0 | Aucun
Weld | 8927 | Autour | 6 | 0 | Aucun
Weld | 8925 | Autour | 6 | 0 | Aucun
Weld | 8924 | Autour | 6 | 0 | Aucun
Weld | 8504 | Autour | 6 | 0 | Aucun
Weld | 8503 | Autour | 6 | 0 | Aucun
Weld | 8502 | Autour | 6 | 0 | Aucun
Weld | 8501 | Autour | 6 | 0 | Aucun
Weld | 8495 | Autour | 6 | 0 | Aucun
Weld | 8494 | Autour | 6 | 0 | Aucun
Weld | 8493 | Autour | 6 | 0 | Aucun
Weld | 8492 | Autour | 6 | 0 | Aucun
Weld | 8491 | Autour | 6 | 0 | Aucun
Weld | 8490 | Autour | 6 | 0 | Aucun
Weld | 8489 | Autour | 6 | 0 | Aucun
Weld | 8488 | Autour | 6 | 0 | Aucun
Weld | 8486 | Autour | 6 | 0 | Aucun
2 x Weld | 8485 | Autour | 6 | 0 | Aucun
Weld | 8479 | Autour | 6 | 0 | Aucun
Weld | 8478 | Autour | 6 | 0 | Aucun
Weld | 8280 | Autour | 6 | 0 | Aucun
Weld | 8279 | Autour | 6 | 0 | Aucun
Weld | 8278 | Autour | 6 | 0 | Aucun
Weld | 8277 | Autour | 6 | 0 | Aucun
Weld | 8276 | Autour | 6 | 0 | Aucun
Weld | 8275 | Autour | 6 | 0 | Aucun
2 x Weld | 8170 | Autour | 6 | 0 | Aucun
2 x Weld | 8169 | Autour | 6 | 0 | Aucun
2 x Weld | 8168 | Autour | 6 | 0 | Aucun
2 x Weld | 8167 | Autour | 6 | 0 | Aucun
2 x Weld | 8152 | Autour | 6 | 0 | Aucun
2 x Weld | 8151 | Autour | 6 | 0 | Aucun
Weld | 8150 | Autour | 6 | 0 | Aucun
Weld | 8149 | Autour | 6 | 0 | Aucun
Weld | 8148 | Autour | 6 | 0 | Aucun
Weld | 8147 | Autour | 6 | 0 | Aucun
Weld | 8146 | Autour | 6 | 0 | Aucun
Weld | 8145 | Autour | 6 | 0 | Aucun
Weld | 8144 | Autour | 6 | 0 | Aucun
Weld | 8143 | Autour | 6 | 0 | Aucun
Weld | 8142 | Autour | 6 | 0 | Aucun
Weld | 8141 | Autour | 6 | 0 | Aucun
Weld | 8140 | Autour | 6 | 0 | Aucun
Weld | 8139 | Autour | 6 | 0 | Aucun
Weld | 8138 | Autour | 6 | 0 | Aucun
Weld | 8137 | Autour | 6 | 0 | Aucun
Weld | 8136 | Autour | 6 | 0 | Aucun
Weld | 8135 | Autour | 6 | 0 | Aucun
Weld | 8134 | Autour | 6 | 0 | Aucun
Weld | 8133 | Autour | 6 | 0 | Aucun
Weld | 8132 | Autour | 6 | 0 | Aucun
Weld | 8131 | Autour | 6 | 0 | Aucun
Weld | 8130 | Autour | 6 | 0 | Aucun
Weld | 8129 | Autour | 6 | 0 | Aucun
Weld | 8128 | Autour | 6 | 0 | Aucun
Weld | 897 | Autour | 6 | 0 | Aucun
Weld | 896 | Droit | 3 | 3 | W10
Weld | 895 | Droit | 5 | 5 | W10
Weld | 894 | Droit | 5 | 5 | W10
Weld | 893 | Droit | 3 | 3 | W10
Weld | 892 | Droit | 5 | 5 | W10
Weld | 891 | Droit | 5 | 5 | W10
Weld | 890 | Droit | 3 | 3 | W10
Weld | 889 | Droit | 5 | 5 | W10
Weld | 888 | Droit | 5 | 5 | W10
Weld | 887 | Droit | 3 | 3 | W10
Weld | 886 | Droit | 5 | 5 | W10
Weld | 885 | Droit | 5 | 5 | W10
Weld | 884 | Autour | 6 | 0 | Aucun
Weld | 883 | Autour | 6 | 0 | Aucun
Weld | 882 | Autour | 6 | 0 | Aucun
Weld | 880 | Droit | 3 | 3 | W10
Weld | 879 | Droit | 5 | 5 | W10
Weld | 878 | Droit | 5 | 5 | W10
Weld | 877 | Droit | 3 | 3 | W10
Weld | 876 | Droit | 5 | 5 | W10
Weld | 875 | Droit | 5 | 5 | W10
Weld | 868 | Droit | 3 | 3 | W10
Weld | 867 | Droit | 5 | 5 | W10
Weld | 866 | Droit | 5 | 5 | W10
Weld | 865 | Droit | 3 | 3 | W10
Weld | 864 | Droit | 5 | 5 | W10
Weld | 863 | Droit | 5 | 5 | W10
Weld | 861 | Autour | 6 | 0 | Aucun
Weld | 860 | Autour | 6 | 0 | Aucun
Weld | 859 | Autour | 6 | 0 | Aucun
Weld | 857 | Autour | 6 | 0 | Aucun
Weld | 856 | Autour | 6 | 0 | Aucun
Weld | 855 | Autour | 6 | 0 | Aucun
Weld | 852 | Autour | 6 | 0 | Aucun
Weld | 851 | Autour | 6 | 0 | Aucun
Weld | 850 | Autour | 6 | 0 | Aucun
Weld | 849 | Autour | 6 | 0 | Aucun
Weld | 848 | Autour | 6 | 0 | Aucun
Weld | 847 | Autour | 6 | 0 | Aucun
Weld | 845 | Autour | 6 | 0 | Aucun
Weld | 844 | Autour | 6 | 0 | Aucun
Weld | 843 | Autour | 6 | 0 | Aucun
Weld | 842 | Autour | 6 | 0 | Aucun
Weld | 839 | Autour | 6 | 0 | Aucun
Weld | 836 | Autour | 6 | 0 | Aucun
Weld | 835 | Autour | 6 | 0 | Aucun
Weld | 834 | Autour | 6 | 0 | Aucun
Weld | 833 | Autour | 6 | 0 | Aucun
Weld | 832 | Autour | 6 | 0 | Aucun
Weld | 830 | Autour | 6 | 0 | Aucun
Weld | 828 | Autour | 6 | 0 | Aucun
Weld | 826 | Autour | 6 | 0 | Aucun
Weld | 825 | Autour | 6 | 0 | Aucun
Weld | 824 | Autour | 6 | 0 | Aucun
Weld | 820 | Autour | 6 | 0 | Aucun
Weld | 819 | Autour | 6 | 0 | Aucun
Weld | 818 | Autour | 6 | 0 | Aucun
Weld | 815 | Autour | 6 | 0 | Aucun
Weld | 814 | Autour | 6 | 0 | Aucun
Weld | 813 | Autour | 6 | 0 | Aucun
Weld | 812 | Autour | 6 | 0 | Aucun
Weld | 811 | Autour | 6 | 0 | Aucun
Weld | 810 | Autour | 6 | 0 | Aucun
Weld | 806 | Autour | 6 | 0 | Aucun
Weld | 805 | Autour | 6 | 0 | Aucun
Weld | 804 | Autour | 6 | 0 | Aucun
Weld | 802 | Autour | 6 | 0 | Aucun
Weld | 800 | Autour | 6 | 0 | Aucun
Weld | 798 | Autour | 6 | 0 | Aucun
Weld | 797 | Autour | 6 | 0 | Aucun
Weld | 795 | Autour | 6 | 0 | Aucun
Weld | 794 | Autour | 6 | 0 | Aucun
Weld | 793 | Autour | 6 | 0 | Aucun
Weld | 791 | Autour | 6 | 0 | Aucun
Weld | 788 | Autour | 6 | 0 | Aucun
Weld | 787 | Autour | 6 | 0 | Aucun
Weld | 783 | Autour | 6 | 0 | Aucun
Weld | 782 | Autour | 6 | 0 | Aucun
Weld | 780 | Autour | 6 | 0 | Aucun
Weld | 779 | Autour | 6 | 0 | Aucun
Weld | 778 | Autour | 6 | 0 | Aucun
Weld | 777 | Autour | 6 | 0 | Aucun
Weld | 776 | Autour | 6 | 0 | Aucun
Weld | 775 | Autour | 6 | 0 | Aucun
Weld | 774 | Autour | 6 | 0 | Aucun
Weld | 773 | Autour | 6 | 0 | Aucun
Weld | 770 | Autour | 6 | 0 | Aucun
Weld | 769 | Autour | 6 | 0 | Aucun
Weld | 768 | Autour | 6 | 0 | Aucun
Weld | 767 | Autour | 6 | 0 | Aucun
Weld | 766 | Autour | 6 | 0 | Aucun
Weld | 765 | Autour | 6 | 0 | Aucun
Weld | 764 | Autour | 6 | 0 | Aucun
Weld | 763 | Autour | 6 | 0 | Aucun
Weld | 762 | Autour | 6 | 0 | Aucun
Weld | 761 | Autour | 6 | 0 | Aucun
Weld | 760 | Autour | 6 | 0 | Aucun
Weld | 759 | Autour | 6 | 0 | Aucun
Weld | 753 | Autour | 6 | 0 | Aucun
Weld | 752 | Autour | 6 | 0 | Aucun
Weld | 751 | Autour | 6 | 0 | Aucun
Weld | 750 | Autour | 6 | 0 | Aucun
Weld | 749 | Autour | 6 | 0 | Aucun
Weld | 748 | Autour | 6 | 0 | Aucun
Weld | 747 | Autour | 6 | 0 | Aucun
Weld | 746 | Autour | 6 | 0 | Aucun
Weld | 745 | Autour | 6 | 0 | Aucun
Weld | 744 | Autour | 6 | 0 | Aucun
Weld | 743 | Autour | 6 | 0 | Aucun
Weld | 742 | Autour | 6 | 0 | Aucun
Weld | 741 | Autour | 6 | 0 | Aucun
Weld | 740 | Autour | 6 | 0 | Aucun
Weld | 739 | Autour | 6 | 0 | Aucun
Weld | 738 | Autour | 6 | 0 | Aucun
Weld | 736 | Autour | 6 | 0 | Aucun
Weld | 735 | Autour | 6 | 0 | Aucun
Weld | 734 | Autour | 6 | 0 | Aucun
Weld | 733 | Autour | 6 | 0 | Aucun
Weld | 732 | Autour | 6 | 0 | Aucun
Weld | 731 | Autour | 6 | 0 | Aucun
Weld | 730 | Autour | 6 | 0 | Aucun
Weld | 729 | Autour | 6 | 0 | Aucun
Weld | 728 | Autour | 6 | 0 | Aucun
Weld | 727 | Autour | 6 | 0 | Aucun
Weld | 726 | Autour | 6 | 0 | Aucun
Weld | 725 | Autour | 6 | 0 | Aucun
Weld | 723 | Autour | 6 | 0 | Aucun
Weld | 722 | Autour | 6 | 0 | Aucun
Weld | 721 | Autour | 6 | 0 | Aucun
Weld | 720 | Autour | 6 | 0 | Aucun
Weld | 719 | Autour | 6 | 0 | Aucun
Weld | 718 | Autour | 6 | 0 | Aucun
Weld | 717 | Autour | 6 | 0 | Aucun
Weld | 716 | Autour | 6 | 0 | Aucun
Weld | 715 | Autour | 6 | 0 | Aucun
Weld | 713 | Autour | 6 | 0 | Aucun
Weld | 710 | Autour | 6 | 0 | Aucun
Weld | 709 | Autour | 6 | 0 | Aucun
Weld | 707 | Autour | 6 | 0 | Aucun
Weld | 706 | Autour | 6 | 0 | Aucun
Weld | 705 | Autour | 6 | 0 | Aucun
Weld | 704 | Autour | 6 | 0 | Aucun
Weld | 702 | Autour | 6 | 0 | Aucun
Weld | 701 | Autour | 6 | 0 | Aucun
Weld | 698 | Autour | 6 | 0 | Aucun
Weld | 697 | Autour | 6 | 0 | Aucun
Weld | 693 | Autour | 6 | 0 | Aucun
Weld | 691 | Autour | 6 | 0 | Aucun
Weld | 690 | Autour | 6 | 0 | Aucun
Weld | 689 | Autour | 6 | 0 | Aucun
Weld | 688 | Autour | 6 | 0 | Aucun
Weld | 687 | Autour | 6 | 0 | Aucun
Weld | 686 | Autour | 6 | 0 | Aucun
Weld | 685 | Autour | 6 | 0 | Aucun
Weld | 684 | Autour | 6 | 0 | Aucun
Weld | 682 | Autour | 6 | 0 | Aucun
Weld | 681 | Autour | 6 | 0 | Aucun
Weld | 680 | Autour | 6 | 0 | Aucun
Weld | 672 | Autour | 6 | 0 | Aucun
Weld | 671 | Autour | 6 | 0 | Aucun
Weld | 670 | Autour | 6 | 0 | Aucun
Weld | 669 | Autour | 6 | 0 | Aucun
Weld | 664 | Autour | 6 | 0 | Aucun
Weld | 663 | Autour | 6 | 0 | Aucun
Weld | 662 | Autour | 6 | 0 | Aucun
Weld | 661 | Autour | 6 | 0 | Aucun
Weld | 659 | Autour | 6 | 0 | Aucun
Weld | 658 | Autour | 6 | 0 | Aucun
Weld | 657 | Autour | 6 | 0 | Aucun
Weld | 656 | Autour | 6 | 0 | Aucun
Weld | 655 | Autour | 6 | 0 | Aucun
Weld | 654 | Autour | 6 | 0 | Aucun
Weld | 653 | Autour | 6 | 0 | Aucun
Weld | 652 | Autour | 6 | 0 | Aucun
Weld | 651 | Autour | 6 | 0 | Aucun
Weld | 650 | Autour | 6 | 0 | Aucun
Weld | 649 | Autour | 6 | 0 | Aucun
Weld | 648 | Autour | 6 | 0 | Aucun
Weld | 6687 | Autour | 6 | 0 | Aucun
Weld | 6686 | Autour | 6 | 0 | Aucun
Weld | 6685 | Autour | 6 | 0 | Aucun
Weld | 6684 | Autour | 6 | 0 | Aucun
Weld | 6683 | Autour | 6 | 0 | Aucun
Weld | 6682 | Autour | 6 | 0 | Aucun
Weld | 6681 | Autour | 6 | 0 | Aucun
Weld | 6680 | Autour | 6 | 0 | Aucun
Weld | 6679 | Autour | 6 | 0 | Aucun
Weld | 6678 | Autour | 6 | 0 | Aucun
Weld | 6677 | Autour | 6 | 0 | Aucun
Weld | 6676 | Autour | 6 | 0 | Aucun
Weld | 6675 | Autour | 6 | 0 | Aucun
Weld | 6674 | Autour | 6 | 0 | Aucun
Weld | 6673 | Autour | 6 | 0 | Aucun
Weld | 6672 | Autour | 6 | 0 | Aucun
Weld | 6671 | Autour | 6 | 0 | Aucun
Weld | 6670 | Autour | 6 | 0 | Aucun
Weld | 6669 | Autour | 6 | 0 | Aucun
Weld | 6668 | Autour | 6 | 0 | Aucun
Weld | 6667 | Autour | 6 | 0 | Aucun
Weld | 6666 | Autour | 6 | 0 | Aucun
Weld | 6665 | Autour | 6 | 0 | Aucun
Weld | 6664 | Autour | 6 | 0 | Aucun
Weld | 6663 | Autour | 6 | 0 | Aucun
Weld | 6662 | Autour | 6 | 0 | Aucun
Weld | 6661 | Autour | 6 | 0 | Aucun
Weld | 6660 | Autour | 6 | 0 | Aucun
Weld | 6659 | Autour | 6 | 0 | Aucun
Weld | 6658 | Autour | 6 | 0 | Aucun
Weld | 6657 | Autour | 6 | 0 | Aucun
Weld | 6656 | Autour | 6 | 0 | Aucun
Weld | 6655 | Autour | 6 | 0 | Aucun
Weld | 6654 | Autour | 6 | 0 | Aucun
Weld | 6653 | Autour | 6 | 0 | Aucun
Weld | 6652 | Autour | 6 | 0 | Aucun
Weld | 6651 | Autour | 6 | 0 | Aucun
Weld | 6650 | Autour | 6 | 0 | Aucun
Weld | 6649 | Autour | 6 | 0 | Aucun
Weld | 6648 | Autour | 6 | 0 | Aucun
Weld | 6647 | Autour | 6 | 0 | Aucun
Weld | 6646 | Autour | 6 | 0 | Aucun
Weld | 6644 | Autour | 6 | 0 | Aucun
Weld | 6643 | Autour | 6 | 0 | Aucun
Weld | 6642 | Autour | 6 | 0 | Aucun
Weld | 6641 | Autour | 6 | 0 | Aucun
Weld | 6640 | Autour | 6 | 0 | Aucun
Weld | 6639 | Autour | 6 | 0 | Aucun
Weld | 6637 | Autour | 6 | 0 | Aucun
Weld | 6636 | Autour | 6 | 0 | Aucun
Weld | 6633 | Autour | 6 | 0 | Aucun
Weld | 6629 | Autour | 6 | 0 | Aucun
Weld | 6628 | Autour | 6 | 0 | Aucun
Weld | 6626 | Autour | 6 | 0 | Aucun
Weld | 6623 | Autour | 6 | 0 | Aucun
Weld | 6618 | Autour | 6 | 0 | Aucun
Weld | 6614 | Autour | 6 | 0 | Aucun
Weld | 6613 | Autour | 6 | 0 | Aucun
Weld | 6610 | Autour | 6 | 0 | Aucun
Weld | 6609 | Autour | 6 | 0 | Aucun
Weld | 6608 | Autour | 6 | 0 | Aucun
Weld | 6607 | Autour | 6 | 0 | Aucun
Weld | 6606 | Autour | 6 | 0 | Aucun
Weld | 6605 | Autour | 6 | 0 | Aucun
Weld | 6597 | Autour | 6 | 0 | Aucun
Weld | 6596 | Autour | 6 | 0 | Aucun
Weld | 6595 | Autour | 6 | 0 | Aucun
Weld | 6594 | Autour | 6 | 0 | Aucun
Weld | 6593 | Autour | 6 | 0 | Aucun
Weld | 6592 | Autour | 6 | 0 | Aucun
Weld | 6591 | Autour | 6 | 0 | Aucun
Weld | 6590 | Autour | 6 | 0 | Aucun
Weld | 6589 | Autour | 6 | 0 | Aucun
Weld | 6588 | Autour | 6 | 0 | Aucun
Weld | 6587 | Autour | 6 | 0 | Aucun
2 x Weld | 6586 | Autour | 6 | 0 | Aucun
Weld | 6584 | Autour | 6 | 0 | Aucun
Weld | 6583 | Autour | 6 | 0 | Aucun
Weld | 6582 | Autour | 6 | 0 | Aucun
Weld | 6581 | Autour | 6 | 0 | Aucun
2 x Weld | 6580 | Autour | 6 | 0 | Aucun
Weld | 6579 | Autour | 6 | 0 | Aucun
Weld | 6578 | Autour | 6 | 0 | Aucun
Weld | 6577 | Autour | 6 | 0 | Aucun
Weld | 6575 | Autour | 6 | 0 | Aucun
Weld | 6574 | Autour | 6 | 0 | Aucun
Weld | 6573 | Autour | 6 | 0 | Aucun
2 x Weld | 6572 | Autour | 6 | 0 | Aucun
Weld | 6571 | Autour | 6 | 0 | Aucun
Weld | 6570 | Autour | 6 | 0 | Aucun
2 x Weld | 6569 | Autour | 6 | 0 | Aucun
Weld | 6568 | Autour | 6 | 0 | Aucun
Weld | 6567 | Autour | 6 | 0 | Aucun
Weld | 6566 | Autour | 6 | 0 | Aucun
2 x Weld | 6565 | Autour | 6 | 0 | Aucun
2 x Weld | 6564 | Autour | 6 | 0 | Aucun
Weld | 6563 | Autour | 6 | 0 | Aucun
Weld | 6562 | Autour | 6 | 0 | Aucun
Weld | 6561 | Autour | 6 | 0 | Aucun
2 x Weld | 6560 | Autour | 6 | 0 | Aucun
2 x Weld | 6559 | Autour | 6 | 0 | Aucun
Weld | 6554 | Autour | 6 | 0 | Aucun
Weld | 6545 | Autour | 6 | 0 | Aucun
2 x Weld | 6544 | Autour | 6 | 0 | Aucun
Weld | 6543 | Autour | 6 | 0 | Aucun
Weld | 6542 | Autour | 6 | 0 | Aucun
Weld | 6541 | Autour | 6 | 0 | Aucun
2 x Weld | 6540 | Autour | 6 | 0 | Aucun
2 x Weld | 6535 | Autour | 6 | 0 | Aucun
2 x Weld | 6534 | Autour | 6 | 0 | Aucun
Weld | 6530 | Autour | 6 | 0 | Aucun
Weld | 6521 | Autour | 6 | 0 | Aucun
Weld | 6520 | Autour | 6 | 0 | Aucun
Weld | 6450 | Autour | 6 | 0 | Aucun
Weld | 6449 | Autour | 6 | 0 | Aucun
Weld | 6430 | Droit | 4 | 4 | W10
Weld | 6429 | Droit | 5 | 5 | W10
Weld | 6428 | Droit | 5 | 5 | W10
Weld | 6427 | Droit | 4 | 4 | W10
Weld | 6426 | Droit | 5 | 5 | W10
Weld | 6425 | Droit | 5 | 5 | W10
Weld | 6424 | Droit | 4 | 4 | W10
Weld | 6423 | Droit | 5 | 5 | W10
Weld | 6422 | Droit | 5 | 5 | W10
Weld | 6421 | Droit | 4 | 4 | W10
Weld | 6420 | Droit | 5 | 5 | W10
Weld | 6419 | Droit | 5 | 5 | W10
Weld | 6416 | Autour | 6 | 0 | Aucun
Weld | 6415 | Autour | 6 | 0 | Aucun
Weld | 6404 | Autour | 6 | 0 | Aucun
Weld | 6402 | Autour | 6 | 0 | Aucun
Weld | 6401 | Autour | 6 | 0 | Aucun
Weld | 6400 | Autour | 6 | 0 | Aucun
Weld | 6399 | Autour | 6 | 0 | Aucun
Weld | 6398 | Droit | 5 | 0 | Aucun
Weld | 6394 | Droit | 4 | 4 | W10
Weld | 6393 | Droit | 5 | 5 | W10
Weld | 6392 | Droit | 5 | 5 | W10
Weld | 6391 | Droit | 4 | 4 | W10
Weld | 6390 | Droit | 5 | 5 | W10
Weld | 6389 | Droit | 5 | 5 | W10
Weld | 6388 | Droit | 4 | 4 | W10
Weld | 6387 | Droit | 5 | 5 | W10
Weld | 6386 | Droit | 5 | 5 | W10
Weld | 6385 | Droit | 4 | 4 | W10
Weld | 6384 | Droit | 5 | 5 | W10
Weld | 6383 | Droit | 5 | 5 | W10
Weld | 6382 | Droit | 4 | 4 | W10
Weld | 6381 | Droit | 5 | 5 | W10
Weld | 6380 | Droit | 5 | 5 | W10
Weld | 6379 | Droit | 4 | 4 | W10
Weld | 6378 | Droit | 5 | 5 | W10
Weld | 6377 | Droit | 5 | 5 | W10
Weld | 6376 | Droit | 4 | 4 | W10
Weld | 6375 | Droit | 5 | 5 | W10
Weld | 6374 | Droit | 5 | 5 | W10
Weld | 6373 | Droit | 4 | 4 | W10
Weld | 6372 | Droit | 5 | 5 | W10
Weld | 6371 | Droit | 5 | 5 | W10
Weld | 6370 | Droit | 4 | 4 | W10
Weld | 6369 | Droit | 5 | 5 | W10
Weld | 6368 | Droit | 5 | 5 | W10
Weld | 6361 | Droit | 4 | 4 | W10
Weld | 6360 | Droit | 5 | 5 | W10
Weld | 6359 | Droit | 5 | 5 | W10
Weld | 6358 | Droit | 4 | 4 | W10
Weld | 6357 | Droit | 5 | 5 | W10
Weld | 6356 | Droit | 5 | 5 | W10
Weld | 6355 | Droit | 4 | 4 | W10
Weld | 6354 | Droit | 5 | 5 | W10
Weld | 6353 | Droit | 5 | 5 | W10
Weld | 6350 | Droit | 5 | 0 | Aucun
Weld | 6349 | Droit | 5 | 0 | Aucun
Weld | 6344 | Autour | 6 | 0 | Aucun
Weld | 6340 | Autour | 6 | 0 | Aucun
Weld | 6218 | Autour | 6 | 0 | Aucun
Weld | 6087 | Autour | 6 | 0 | Aucun
2 x Weld | 6086 | Autour | 6 | 0 | Aucun
Weld | 6083 | Autour | 6 | 0 | Aucun
Weld | 6078 | Autour | 6 | 0 | Aucun
Weld | 6077 | Autour | 6 | 0 | Aucun
Weld | 6076 | Autour | 6 | 0 | Aucun
Weld | 6075 | Autour | 6 | 0 | Aucun
Weld | 6073 | Autour | 6 | 0 | Aucun
Weld | 6072 | Autour | 6 | 0 | Aucun
Weld | 6067 | Autour | 6 | 0 | Aucun
Weld | 6065 | Autour | 6 | 0 | Aucun
Weld | 6044 | Autour | 6 | 0 | Aucun
Weld | 6043 | Autour | 6 | 0 | Aucun
Weld | 6042 | Autour | 6 | 0 | Aucun
Weld | 6041 | Autour | 6 | 0 | Aucun
Weld | 6039 | Autour | 6 | 0 | Aucun
Weld | 6038 | Autour | 6 | 0 | Aucun
Weld | 6009 | Autour | 6 | 0 | Aucun
Weld | 6008 | Autour | 6 | 0 | Aucun
Weld | 6007 | Autour | 6 | 0 | Aucun
Weld | 6005 | Autour | 6 | 0 | Aucun
Weld | 6004 | Autour | 6 | 0 | Aucun
Weld | 6003 | Autour | 6 | 0 | Aucun
Weld | 6001 | Autour | 6 | 0 | Aucun
Weld | 6000 | Autour | 6 | 0 | Aucun
Weld | 5999 | Autour | 6 | 0 | Aucun
Weld | 5998 | Autour | 6 | 0 | Aucun
Weld | 5997 | Autour | 6 | 0 | Aucun
Weld | 5996 | Autour | 6 | 0 | Aucun
Weld | 5995 | Autour | 6 | 0 | Aucun
Weld | 5994 | Autour | 6 | 0 | Aucun
Weld | 5993 | Autour | 6 | 0 | Aucun
Weld | 5992 | Autour | 6 | 0 | Aucun
Weld | 5991 | Autour | 6 | 0 | Aucun
Weld | 5990 | Autour | 6 | 0 | Aucun
Weld | 5989 | Autour | 6 | 0 | Aucun
Weld | 5988 | Autour | 6 | 0 | Aucun
Weld | 5987 | Autour | 6 | 0 | Aucun
Weld | 5986 | Autour | 6 | 0 | Aucun
Weld | 5985 | Autour | 6 | 0 | Aucun
Weld | 5984 | Autour | 6 | 0 | Aucun
Weld | 5983 | Autour | 6 | 0 | Aucun
Weld | 5982 | Autour | 6 | 0 | Aucun
Weld | 5981 | Autour | 6 | 0 | Aucun
Weld | 5979 | Autour | 6 | 0 | Aucun
Weld | 5978 | Autour | 6 | 0 | Aucun
Weld | 5977 | Autour | 6 | 0 | Aucun
Weld | 5976 | Autour | 6 | 0 | Aucun
Weld | 5975 | Autour | 6 | 0 | Aucun
Weld | 5974 | Autour | 6 | 0 | Aucun
Weld | 5973 | Autour | 6 | 0 | Aucun
Weld | 5969 | Autour | 6 | 0 | Aucun
Weld | 5968 | Autour | 6 | 0 | Aucun
Weld | 5967 | Autour | 6 | 0 | Aucun
Weld | 5966 | Autour | 6 | 0 | Aucun
Weld | 5965 | Autour | 6 | 0 | Aucun
Weld | 5964 | Autour | 6 | 0 | Aucun
Weld | 5963 | Autour | 6 | 0 | Aucun
Weld | 5962 | Autour | 6 | 0 | Aucun
Weld | 5961 | Autour | 6 | 0 | Aucun
Weld | 5960 | Autour | 6 | 0 | Aucun
Weld | 5959 | Autour | 6 | 0 | Aucun
Weld | 5958 | Autour | 6 | 0 | Aucun
Weld | 5957 | Autour | 6 | 0 | Aucun
Weld | 5956 | Autour | 6 | 0 | Aucun
Weld | 5954 | Autour | 6 | 0 | Aucun
Weld | 5953 | Autour | 6 | 0 | Aucun
Weld | 5952 | Autour | 6 | 0 | Aucun
Weld | 5950 | Autour | 6 | 0 | Aucun
Weld | 5948 | Droit | 3 | 3 | W10
Weld | 5947 | Droit | 4 | 4 | W10
Weld | 5946 | Droit | 4 | 4 | W10
Weld | 5942 | Droit | 3 | 3 | W10
Weld | 5941 | Droit | 4 | 4 | W10
Weld | 5940 | Droit | 4 | 4 | W10
Weld | 5927 | Autour | 6 | 0 | Aucun
Weld | 5926 | Autour | 6 | 0 | Aucun
Weld | 5925 | Autour | 6 | 0 | Aucun
Weld | 5924 | Autour | 6 | 0 | Aucun
Weld | 5923 | Autour | 6 | 0 | Aucun
Weld | 5922 | Autour | 6 | 0 | Aucun
Weld | 5921 | Autour | 6 | 0 | Aucun
Weld | 5920 | Autour | 6 | 0 | Aucun
Weld | 5919 | Autour | 6 | 0 | Aucun
Weld | 5918 | Autour | 6 | 0 | Aucun
Weld | 5917 | Autour | 6 | 0 | Aucun
Weld | 5916 | Autour | 6 | 0 | Aucun
Weld | 5915 | Autour | 6 | 0 | Aucun
Weld | 5914 | Autour | 6 | 0 | Aucun
Weld | 5909 | Autour | 6 | 0 | Aucun
Weld | 5908 | Autour | 6 | 0 | Aucun
Weld | 5907 | Autour | 6 | 0 | Aucun
Weld | 5906 | Autour | 6 | 0 | Aucun
Weld | 5905 | Autour | 6 | 0 | Aucun
Weld | 5904 | Autour | 6 | 0 | Aucun
Weld | 5903 | Autour | 6 | 0 | Aucun
Weld | 5902 | Autour | 6 | 0 | Aucun
Weld | 5900 | Autour | 6 | 0 | Aucun
Weld | 5899 | Autour | 6 | 0 | Aucun
Weld | 5898 | Autour | 6 | 0 | Aucun
Weld | 5897 | Autour | 6 | 0 | Aucun
Weld | 5896 | Autour | 6 | 0 | Aucun
Weld | 5895 | Autour | 6 | 0 | Aucun
Weld | 5894 | Autour | 6 | 0 | Aucun
Weld | 5893 | Autour | 6 | 0 | Aucun
Weld | 5892 | Autour | 6 | 0 | Aucun
Weld | 5891 | Autour | 6 | 0 | Aucun
Weld | 5890 | Autour | 6 | 0 | Aucun
Weld | 5889 | Autour | 6 | 0 | Aucun
Weld | 5888 | Autour | 6 | 0 | Aucun
Weld | 5887 | Autour | 6 | 0 | Aucun
Weld | 5886 | Autour | 6 | 0 | Aucun
Weld | 5885 | Autour | 6 | 0 | Aucun
Weld | 5884 | Autour | 6 | 0 | Aucun
Weld | 5883 | Autour | 6 | 0 | Aucun
Weld | 5882 | Autour | 6 | 0 | Aucun
Weld | 5881 | Autour | 6 | 0 | Aucun
Weld | 5879 | Autour | 6 | 0 | Aucun
Weld | 5878 | Autour | 6 | 0 | Aucun
Weld | 5877 | Autour | 6 | 0 | Aucun
Weld | 5876 | Autour | 6 | 0 | Aucun
Weld | 5875 | Autour | 6 | 0 | Aucun
Weld | 5874 | Autour | 6 | 0 | Aucun
Weld | 5873 | Autour | 6 | 0 | Aucun
Weld | 5872 | Autour | 6 | 0 | Aucun
Weld | 5871 | Autour | 6 | 0 | Aucun
Weld | 5870 | Autour | 6 | 0 | Aucun
Weld | 5865 | Autour | 6 | 0 | Aucun
Weld | 5864 | Autour | 6 | 0 | Aucun
Weld | 5863 | Autour | 6 | 0 | Aucun
Weld | 5862 | Autour | 6 | 0 | Aucun
Weld | 5861 | Autour | 6 | 0 | Aucun
Weld | 5860 | Autour | 6 | 0 | Aucun
Weld | 5859 | Autour | 6 | 0 | Aucun
Weld | 5858 | Autour | 6 | 0 | Aucun
Weld | 5857 | Autour | 6 | 0 | Aucun
Weld | 5856 | Autour | 6 | 0 | Aucun
Weld | 5855 | Autour | 6 | 0 | Aucun
Weld | 5854 | Autour | 6 | 0 | Aucun
Weld | 5853 | Autour | 6 | 0 | Aucun
Weld | 5852 | Autour | 6 | 0 | Aucun
Weld | 5851 | Autour | 6 | 0 | Aucun
Weld | 5850 | Autour | 6 | 0 | Aucun
Weld | 5849 | Autour | 6 | 0 | Aucun
Weld | 5848 | Autour | 6 | 0 | Aucun
Weld | 5846 | Autour | 6 | 0 | Aucun
Weld | 5845 | Autour | 6 | 0 | Aucun
Weld | 5843 | Autour | 6 | 0 | Aucun
Weld | 5842 | Autour | 6 | 0 | Aucun
Weld | 5841 | Autour | 6 | 0 | Aucun
Weld | 5840 | Autour | 6 | 0 | Aucun
Weld | 5839 | Autour | 6 | 0 | Aucun
Weld | 5838 | Autour | 6 | 0 | Aucun
Weld | 5837 | Autour | 6 | 0 | Aucun
Weld | 5832 | Autour | 6 | 0 | Aucun
Weld | 5831 | Autour | 6 | 0 | Aucun
Weld | 5830 | Autour | 6 | 0 | Aucun
Weld | 5829 | Autour | 6 | 0 | Aucun
Weld | 5828 | Autour | 6 | 0 | Aucun
Weld | 5827 | Autour | 6 | 0 | Aucun
Weld | 5825 | Autour | 6 | 0 | Aucun
Weld | 5824 | Autour | 6 | 0 | Aucun
Weld | 5822 | Autour | 6 | 0 | Aucun
Weld | 5821 | Autour | 6 | 0 | Aucun
Weld | 5820 | Autour | 6 | 0 | Aucun
Weld | 5819 | Autour | 6 | 0 | Aucun
Weld | 5818 | Autour | 6 | 0 | Aucun
Weld | 5817 | Autour | 6 | 0 | Aucun
Weld | 5816 | Autour | 6 | 0 | Aucun
Weld | 5815 | Autour | 6 | 0 | Aucun
Weld | 5814 | Autour | 6 | 0 | Aucun
Weld | 5813 | Autour | 6 | 0 | Aucun
Weld | 5812 | Autour | 6 | 0 | Aucun
Weld | 5811 | Autour | 6 | 0 | Aucun
Weld | 5810 | Autour | 6 | 0 | Aucun
Weld | 5809 | Autour | 6 | 0 | Aucun
Weld | 5808 | Autour | 6 | 0 | Aucun
Weld | 5807 | Autour | 6 | 0 | Aucun
Weld | 5806 | Autour | 6 | 0 | Aucun
Weld | 5805 | Autour | 6 | 0 | Aucun
Weld | 5804 | Autour | 6 | 0 | Aucun
Weld | 5803 | Autour | 6 | 0 | Aucun
Weld | 5802 | Autour | 6 | 0 | Aucun
Weld | 5801 | Autour | 6 | 0 | Aucun
Weld | 5800 | Autour | 6 | 0 | Aucun
Weld | 5799 | Autour | 6 | 0 | Aucun
Weld | 5798 | Autour | 6 | 0 | Aucun
Weld | 5797 | Autour | 6 | 0 | Aucun
Weld | 5796 | Autour | 6 | 0 | Aucun
Weld | 5795 | Autour | 6 | 0 | Aucun
Weld | 5794 | Autour | 6 | 0 | Aucun
Weld | 5793 | Autour | 6 | 0 | Aucun
Weld | 5792 | Autour | 6 | 0 | Aucun
Weld | 5791 | Autour | 6 | 0 | Aucun
Weld | 5778 | Autour | 6 | 0 | Aucun
Weld | 5769 | Droit | 3 | 3 | W10
Weld | 5768 | Droit | 5 | 5 | W10
Weld | 5767 | Droit | 5 | 5 | W10
Weld | 5763 | Droit | 4 | 4 | W10
Weld | 5762 | Droit | 5 | 5 | W10
Weld | 5761 | Droit | 5 | 5 | W10
Weld | 5760 | Droit | 4 | 4 | W10
Weld | 5759 | Droit | 5 | 5 | W10
Weld | 5758 | Droit | 5 | 5 | W10
Weld | 5757 | Droit | 4 | 4 | W10
Weld | 5756 | Droit | 5 | 5 | W10
Weld | 5755 | Droit | 5 | 5 | W10
Weld | 5754 | Droit | 4 | 4 | W10
Weld | 5753 | Droit | 5 | 5 | W10
Weld | 5752 | Droit | 5 | 5 | W10
Weld | 5749 | Autour | 6 | 0 | Aucun
Weld | 5747 | Autour | 6 | 0 | Aucun
Weld | 5746 | Autour | 6 | 0 | Aucun
Weld | 5745 | Autour | 6 | 0 | Aucun
Weld | 5744 | Autour | 6 | 0 | Aucun
Weld | 5743 | Autour | 6 | 0 | Aucun
Weld | 5742 | Autour | 6 | 0 | Aucun
Weld | 5741 | Autour | 6 | 0 | Aucun
Weld | 5740 | Autour | 6 | 0 | Aucun
Weld | 5739 | Autour | 6 | 0 | Aucun
Weld | 5738 | Autour | 6 | 0 | Aucun
Weld | 5737 | Autour | 6 | 0 | Aucun
Weld | 5736 | Autour | 6 | 0 | Aucun
Weld | 5735 | Autour | 6 | 0 | Aucun
Weld | 5734 | Autour | 6 | 0 | Aucun
Weld | 5733 | Autour | 6 | 0 | Aucun
Weld | 5732 | Autour | 6 | 0 | Aucun
Weld | 5731 | Autour | 6 | 0 | Aucun
Weld | 5730 | Autour | 6 | 0 | Aucun
Weld | 5728 | Autour | 6 | 0 | Aucun
Weld | 5727 | Autour | 6 | 0 | Aucun
Weld | 5726 | Autour | 6 | 0 | Aucun
Weld | 5725 | Autour | 6 | 0 | Aucun
Weld | 5723 | Autour | 6 | 0 | Aucun
Weld | 5722 | Autour | 6 | 0 | Aucun
Weld | 5721 | Autour | 6 | 0 | Aucun
Weld | 5720 | Autour | 6 | 0 | Aucun
Weld | 5719 | Autour | 6 | 0 | Aucun
Weld | 5718 | Autour | 6 | 0 | Aucun
Weld | 5717 | Autour | 6 | 0 | Aucun
Weld | 5716 | Autour | 6 | 0 | Aucun
Weld | 5715 | Autour | 6 | 0 | Aucun
Weld | 5714 | Autour | 6 | 0 | Aucun
Weld | 5713 | Autour | 6 | 0 | Aucun
Weld | 5710 | Autour | 6 | 0 | Aucun
Weld | 5709 | Autour | 6 | 0 | Aucun
Weld | 5708 | Autour | 6 | 0 | Aucun
Weld | 5707 | Autour | 6 | 0 | Aucun
Weld | 5706 | Autour | 6 | 0 | Aucun
Weld | 5705 | Autour | 6 | 0 | Aucun
Weld | 5704 | Autour | 6 | 0 | Aucun
Weld | 5703 | Autour | 6 | 0 | Aucun
Weld | 5702 | Autour | 6 | 0 | Aucun
Weld | 5701 | Autour | 6 | 0 | Aucun
Weld | 5700 | Autour | 6 | 0 | Aucun
Weld | 5699 | Autour | 6 | 0 | Aucun
Weld | 5698 | Autour | 6 | 0 | Aucun
Weld | 5697 | Autour | 6 | 0 | Aucun
Weld | 5696 | Autour | 6 | 0 | Aucun
Weld | 5695 | Autour | 6 | 0 | Aucun
Weld | 5694 | Autour | 6 | 0 | Aucun
Weld | 5693 | Autour | 6 | 0 | Aucun
Weld | 5692 | Autour | 6 | 0 | Aucun
Weld | 5691 | Autour | 6 | 0 | Aucun
Weld | 5690 | Autour | 6 | 0 | Aucun
Weld | 5689 | Autour | 6 | 0 | Aucun
Weld | 5688 | Autour | 6 | 0 | Aucun
Weld | 5687 | Autour | 6 | 0 | Aucun
Weld | 5686 | Autour | 6 | 0 | Aucun
Weld | 5685 | Autour | 6 | 0 | Aucun
Weld | 5684 | Autour | 6 | 0 | Aucun
Weld | 5683 | Autour | 6 | 0 | Aucun
Weld | 5682 | Autour | 6 | 0 | Aucun
Weld | 5681 | Autour | 6 | 0 | Aucun
Weld | 5680 | Autour | 6 | 0 | Aucun
Weld | 5679 | Autour | 6 | 0 | Aucun
Weld | 5678 | Autour | 6 | 0 | Aucun
Weld | 5677 | Autour | 6 | 0 | Aucun
Weld | 5676 | Autour | 6 | 0 | Aucun
Weld | 5675 | Autour | 6 | 0 | Aucun
Weld | 5674 | Autour | 6 | 0 | Aucun
Weld | 5673 | Autour | 6 | 0 | Aucun
Weld | 5672 | Autour | 6 | 0 | Aucun
Weld | 5671 | Autour | 6 | 0 | Aucun
Weld | 5665 | Autour | 6 | 0 | Aucun
Weld | 5664 | Autour | 6 | 0 | Aucun
Weld | 5663 | Autour | 6 | 0 | Aucun
Weld | 5662 | Autour | 6 | 0 | Aucun
Weld | 5661 | Autour | 6 | 0 | Aucun
Weld | 5634 | Autour | 6 | 0 | Aucun
Weld | 5633 | Autour | 6 | 0 | Aucun
Weld | 5632 | Autour | 6 | 0 | Aucun
Weld | 5631 | Autour | 6 | 0 | Aucun
Weld | 5630 | Autour | 6 | 0 | Aucun
Weld | 5629 | Autour | 6 | 0 | Aucun
Weld | 5628 | Autour | 6 | 0 | Aucun
Weld | 5627 | Autour | 6 | 0 | Aucun
Weld | 5626 | Autour | 6 | 0 | Aucun
Weld | 5625 | Autour | 6 | 0 | Aucun
Weld | 5588 | Autour | 6 | 0 | Aucun
Weld | 5587 | Autour | 6 | 0 | Aucun
Weld | 5586 | Autour | 6 | 0 | Aucun
Weld | 5585 | Autour | 6 | 0 | Aucun
Weld | 5584 | Autour | 6 | 0 | Aucun
Weld | 5583 | Autour | 6 | 0 | Aucun
Weld | 5582 | Autour | 6 | 0 | Aucun
Weld | 5581 | Autour | 6 | 0 | Aucun
Weld | 5580 | Autour | 6 | 0 | Aucun
Weld | 5579 | Autour | 6 | 0 | Aucun
Weld | 5565 | Autour | 6 | 0 | Aucun
Weld | 5563 | Autour | 6 | 0 | Aucun
Weld | 5562 | Autour | 6 | 0 | Aucun
Weld | 5560 | Autour | 6 | 0 | Aucun
Weld | 5555 | Autour | 6 | 0 | Aucun
Weld | 5551 | Autour | 6 | 0 | Aucun
Weld | 5550 | Droit | 5 | 0 | Aucun
Weld | 5548 | Autour | 6 | 0 | Aucun
Weld | 5547 | Autour | 6 | 0 | Aucun
Weld | 5543 | Autour | 6 | 0 | Aucun
Weld | 5542 | Autour | 6 | 0 | Aucun
Weld | 5541 | Autour | 6 | 0 | Aucun
Weld | 5540 | Autour | 6 | 0 | Aucun
Weld | 5539 | Autour | 6 | 0 | Aucun
Weld | 5538 | Droit | 5 | 0 | Aucun
Weld | 5537 | Autour | 6 | 0 | Aucun
Weld | 5536 | Droit | 5 | 0 | Aucun
Weld | 5535 | Autour | 6 | 0 | Aucun
Weld | 5534 | Droit | 5 | 0 | Aucun
Weld | 5533 | Autour | 6 | 0 | Aucun
Weld | 5532 | Droit | 5 | 0 | Aucun
Weld | 5531 | Autour | 6 | 0 | Aucun
2 x Weld | 5530 | Droit | 5 | 0 | Aucun
Weld | 5529 | Autour | 6 | 0 | Aucun
Weld | 5528 | Droit | 5 | 0 | Aucun
Weld | 5527 | Autour | 6 | 0 | Aucun
Weld | 5526 | Droit | 5 | 0 | Aucun
Weld | 5525 | Autour | 6 | 0 | Aucun
Weld | 5524 | Autour | 6 | 0 | Aucun
Weld | 5522 | Autour | 6 | 0 | Aucun
Weld | 5521 | Autour | 6 | 0 | Aucun
Weld | 5520 | Autour | 6 | 0 | Aucun
Weld | 5519 | Autour | 6 | 0 | Aucun
Weld | 5517 | Autour | 6 | 0 | Aucun
Weld | 5515 | Autour | 6 | 0 | Aucun
Weld | 5511 | Autour | 6 | 0 | Aucun
Weld | 5510 | Droit | 5 | 5 | W10
Weld | 5509 | Droit | 7 | 7 | W10
Weld | 5508 | Droit | 7 | 7 | W10
Weld | 5505 | Autour | 6 | 0 | Aucun
Weld | 5504 | Droit | 5 | 5 | W10
Weld | 5503 | Droit | 7 | 7 | W10
Weld | 5502 | Droit | 7 | 7 | W10
Weld | 5499 | Autour | 6 | 0 | Aucun
Weld | 5498 | Droit | 5 | 5 | W10
Weld | 5497 | Droit | 7 | 7 | W10
Weld | 5496 | Droit | 7 | 7 | W10
Weld | 5493 | Autour | 6 | 0 | Aucun
Weld | 5492 | Droit | 5 | 5 | W10
Weld | 5491 | Droit | 7 | 7 | W10
Weld | 5490 | Droit | 7 | 7 | W10
Weld | 5487 | Autour | 6 | 0 | Aucun
2 x Weld | 5486 | Droit | 5 | 5 | W10
Weld | 5485 | Droit | 7 | 7 | W10
Weld | 5484 | Droit | 7 | 7 | W10
Weld | 5481 | Autour | 6 | 0 | Aucun
Weld | 5480 | Droit | 5 | 5 | W10
Weld | 5479 | Droit | 7 | 7 | W10
Weld | 5478 | Droit | 7 | 7 | W10
Weld | 5477 | Droit | 5 | 5 | W10
Weld | 5476 | Droit | 7 | 7 | W10
Weld | 5475 | Droit | 7 | 7 | W10
Weld | 5474 | Droit | 5 | 5 | W10
Weld | 5473 | Droit | 7 | 7 | W10
Weld | 5472 | Droit | 7 | 7 | W10
Weld | 5469 | Autour | 6 | 0 | Aucun
Weld | 5466 | Autour | 6 | 0 | Aucun
Weld | 5465 | Autour | 6 | 0 | Aucun
Weld | 5462 | Droit | 5 | 5 | W10
Weld | 5461 | Droit | 7 | 7 | W10
Weld | 5460 | Droit | 7 | 7 | W10
Weld | 5458 | Autour | 6 | 0 | Aucun
2 x Weld | 5457 | Droit | 5 | 5 | W10
Weld | 5456 | Droit | 7 | 7 | W10
Weld | 5455 | Droit | 7 | 7 | W10
2 x Weld | 5454 | Droit | 5 | 5 | W10
Weld | 5453 | Droit | 7 | 7 | W10
Weld | 5452 | Droit | 7 | 7 | W10
Weld | 5451 | Autour | 6 | 0 | Aucun
Weld | 5450 | Autour | 6 | 0 | Aucun
Weld | 5449 | Autour | 6 | 0 | Aucun
Weld | 5441 | Autour | 6 | 0 | Aucun
Weld | 5437 | Droit | 3 | 3 | W10
2 x Weld | 5436 | Droit | 5 | 5 | W10
2 x Weld | 5435 | Droit | 5 | 5 | W10
Weld | 5434 | Droit | 3 | 3 | W10
2 x Weld | 5433 | Droit | 5 | 5 | W10
Weld | 5432 | Droit | 5 | 5 | W10
2 x Weld | 5427 | Droit | 5 | 5 | W10
Weld | 5426 | Droit | 7 | 7 | W10
Weld | 5425 | Droit | 7 | 7 | W10
2 x Weld | 5424 | Droit | 5 | 5 | W10
Weld | 5423 | Droit | 7 | 7 | W10
Weld | 5422 | Droit | 7 | 7 | W10
2 x Weld | 5421 | Droit | 5 | 5 | W10
Weld | 5420 | Droit | 7 | 7 | W10
Weld | 5419 | Droit | 7 | 7 | W10
2 x Weld | 5412 | Droit | 5 | 5 | W10
Weld | 5411 | Droit | 7 | 7 | W10
Weld | 5410 | Droit | 7 | 7 | W10
Weld | 5403 | Droit | 5 | 5 | W10
Weld | 5402 | Droit | 7 | 7 | W10
Weld | 5401 | Droit | 7 | 7 | W10
Weld | 5394 | Autour | 6 | 0 | Aucun
Weld | 5393 | Autour | 6 | 0 | Aucun
Weld | 5391 | Autour | 6 | 0 | Aucun
Weld | 5390 | Autour | 6 | 0 | Aucun
Weld | 5388 | Autour | 6 | 0 | Aucun
Weld | 5387 | Autour | 6 | 0 | Aucun
Weld | 5386 | Autour | 6 | 0 | Aucun
Weld | 5385 | Autour | 6 | 0 | Aucun
Weld | 5384 | Autour | 6 | 0 | Aucun
Weld | 5382 | Autour | 6 | 0 | Aucun
Weld | 5381 | Autour | 6 | 0 | Aucun
Weld | 5380 | Autour | 6 | 0 | Aucun
Weld | 5379 | Autour | 6 | 0 | Aucun
Weld | 5377 | Autour | 6 | 0 | Aucun
Weld | 5376 | Autour | 6 | 0 | Aucun
Weld | 5374 | Autour | 6 | 0 | Aucun
Weld | 5373 | Autour | 6 | 0 | Aucun
Weld | 5372 | Autour | 6 | 0 | Aucun
Weld | 5371 | Autour | 6 | 0 | Aucun
Weld | 5370 | Autour | 6 | 0 | Aucun
Weld | 5369 | Autour | 6 | 0 | Aucun
Weld | 5368 | Autour | 6 | 0 | Aucun
Weld | 5367 | Autour | 6 | 0 | Aucun
Weld | 5366 | Autour | 6 | 0 | Aucun
Weld | 5365 | Autour | 6 | 0 | Aucun
Weld | 5364 | Autour | 6 | 0 | Aucun
Weld | 5322 | Autour | 6 | 0 | Aucun
Weld | 5321 | Autour | 6 | 0 | Aucun
Weld | 5318 | Autour | 6 | 0 | Aucun
Weld | 5317 | Autour | 6 | 0 | Aucun
Weld | 5316 | Autour | 6 | 0 | Aucun
Weld | 5315 | Autour | 6 | 0 | Aucun
Weld | 5314 | Autour | 6 | 0 | Aucun
Weld | 5313 | Autour | 6 | 0 | Aucun
Weld | 5312 | Autour | 6 | 0 | Aucun
Weld | 5311 | Autour | 6 | 0 | Aucun
Weld | 5310 | Autour | 6 | 0 | Aucun
Weld | 5309 | Autour | 6 | 0 | Aucun
Weld | 5308 | Autour | 6 | 0 | Aucun
Weld | 5307 | Autour | 6 | 0 | Aucun
Weld | 5296 | Autour | 6 | 0 | Aucun
Weld | 5293 | Autour | 6 | 0 | Aucun
Weld | 5292 | Autour | 6 | 0 | Aucun
Weld | 5291 | Autour | 6 | 0 | Aucun
Weld | 5290 | Autour | 6 | 0 | Aucun
Weld | 5289 | Autour | 6 | 0 | Aucun
Weld | 5288 | Autour | 6 | 0 | Aucun
Weld | 5286 | Autour | 6 | 0 | Aucun
Weld | 5285 | Autour | 6 | 0 | Aucun
Weld | 5284 | Autour | 6 | 0 | Aucun
Weld | 5283 | Autour | 6 | 0 | Aucun
Weld | 5282 | Autour | 6 | 0 | Aucun
Weld | 5281 | Autour | 6 | 0 | Aucun
Weld | 5179 | Autour | 6 | 0 | Aucun
Weld | 5177 | Autour | 6 | 0 | Aucun
Weld | 5161 | Autour | 6 | 0 | Aucun
Weld | 5160 | Autour | 6 | 0 | Aucun
Weld | 5159 | Autour | 6 | 0 | Aucun
Weld | 5157 | Autour | 6 | 0 | Aucun
Weld | 5155 | Autour | 6 | 0 | Aucun
Weld | 5154 | Autour | 6 | 0 | Aucun
Weld | 5153 | Autour | 6 | 0 | Aucun
Weld | 5152 | Autour | 6 | 0 | Aucun
Weld | 5150 | Autour | 6 | 0 | Aucun
Weld | 5149 | Autour | 6 | 0 | Aucun
Weld | 5148 | Autour | 6 | 0 | Aucun
Weld | 5147 | Autour | 6 | 0 | Aucun
Weld | 5145 | Autour | 6 | 0 | Aucun
Weld | 5144 | Autour | 6 | 0 | Aucun
Weld | 5141 | Autour | 6 | 0 | Aucun
Weld | 5140 | Autour | 6 | 0 | Aucun
Weld | 5136 | Autour | 6 | 0 | Aucun
Weld | 5135 | Autour | 6 | 0 | Aucun
Weld | 5134 | Autour | 6 | 0 | Aucun
Weld | 5133 | Autour | 6 | 0 | Aucun
Weld | 5132 | Autour | 6 | 0 | Aucun
Weld | 5131 | Autour | 6 | 0 | Aucun
Weld | 5130 | Autour | 6 | 0 | Aucun
Weld | 5129 | Autour | 6 | 0 | Aucun
Weld | 5128 | Autour | 6 | 0 | Aucun
Weld | 5127 | Autour | 6 | 0 | Aucun
Weld | 5126 | Autour | 6 | 0 | Aucun
Weld | 5124 | Autour | 6 | 0 | Aucun
Weld | 5123 | Autour | 6 | 0 | Aucun
Weld | 5118 | Autour | 6 | 0 | Aucun
Weld | 5117 | Autour | 6 | 0 | Aucun
Weld | 5115 | Autour | 6 | 0 | Aucun
Weld | 5114 | Autour | 6 | 0 | Aucun
Weld | 5112 | Autour | 6 | 0 | Aucun
Weld | 5109 | Autour | 6 | 0 | Aucun
Weld | 5106 | Autour | 6 | 0 | Aucun
Weld | 5105 | Autour | 6 | 0 | Aucun
Weld | 5102 | Autour | 6 | 0 | Aucun
Weld | 5101 | Autour | 6 | 0 | Aucun
Weld | 5099 | Autour | 6 | 0 | Aucun
Weld | 5098 | Autour | 6 | 0 | Aucun
Weld | 5095 | Autour | 6 | 0 | Aucun
Weld | 5094 | Autour | 6 | 0 | Aucun
Weld | 5093 | Autour | 6 | 0 | Aucun
Weld | 5092 | Autour | 6 | 0 | Aucun
Weld | 5091 | Autour | 6 | 0 | Aucun
Weld | 5090 | Autour | 6 | 0 | Aucun
Weld | 5089 | Autour | 6 | 0 | Aucun
Weld | 5088 | Autour | 6 | 0 | Aucun
Weld | 5087 | Autour | 6 | 0 | Aucun
Weld | 5086 | Autour | 6 | 0 | Aucun
Weld | 5085 | Autour | 6 | 0 | Aucun
Weld | 5084 | Autour | 6 | 0 | Aucun
Weld | 5083 | Autour | 6 | 0 | Aucun
Weld | 5081 | Autour | 6 | 0 | Aucun
Weld | 5080 | Autour | 6 | 0 | Aucun
Weld | 5079 | Autour | 6 | 0 | Aucun
Weld | 5078 | Autour | 6 | 0 | Aucun
Weld | 5077 | Autour | 6 | 0 | Aucun
Weld | 5075 | Autour | 6 | 0 | Aucun
Weld | 5074 | Autour | 6 | 0 | Aucun
Weld | 5073 | Autour | 6 | 0 | Aucun
Weld | 5072 | Autour | 6 | 0 | Aucun
Weld | 5071 | Autour | 6 | 0 | Aucun
Weld | 5070 | Autour | 6 | 0 | Aucun
Weld | 5069 | Autour | 6 | 0 | Aucun
Weld | 5068 | Autour | 6 | 0 | Aucun
Weld | 5067 | Autour | 6 | 0 | Aucun
Weld | 5066 | Autour | 6 | 0 | Aucun
Weld | 5065 | Autour | 6 | 0 | Aucun
Weld | 5064 | Autour | 6 | 0 | Aucun
Weld | 5063 | Autour | 6 | 0 | Aucun
Weld | 5062 | Autour | 6 | 0 | Aucun
Weld | 5060 | Autour | 6 | 0 | Aucun
Weld | 5059 | Autour | 6 | 0 | Aucun
Weld | 5058 | Autour | 6 | 0 | Aucun
Weld | 5057 | Autour | 6 | 0 | Aucun
Weld | 5056 | Autour | 6 | 0 | Aucun
Weld | 5055 | Autour | 6 | 0 | Aucun
Weld | 5054 | Autour | 6 | 0 | Aucun
Weld | 5052 | Autour | 6 | 0 | Aucun
Weld | 5051 | Autour | 6 | 0 | Aucun
Weld | 5050 | Autour | 6 | 0 | Aucun
Weld | 5049 | Autour | 6 | 0 | Aucun
Weld | 5048 | Autour | 6 | 0 | Aucun
Weld | 5047 | Autour | 6 | 0 | Aucun
Weld | 5045 | Autour | 6 | 0 | Aucun
Weld | 5044 | Autour | 6 | 0 | Aucun
Weld | 5040 | Autour | 6 | 0 | Aucun
Weld | 5039 | Autour | 6 | 0 | Aucun
Weld | 5038 | Autour | 6 | 0 | Aucun
Weld | 5037 | Autour | 6 | 0 | Aucun
Weld | 5036 | Autour | 6 | 0 | Aucun
Weld | 5035 | Autour | 6 | 0 | Aucun
Weld | 5034 | Autour | 6 | 0 | Aucun
Weld | 5033 | Autour | 6 | 0 | Aucun
Weld | 5032 | Autour | 6 | 0 | Aucun
Weld | 5031 | Autour | 6 | 0 | Aucun
Weld | 5030 | Autour | 6 | 0 | Aucun
Weld | 5029 | Autour | 6 | 0 | Aucun
Weld | 5028 | Autour | 6 | 0 | Aucun
Weld | 5027 | Autour | 6 | 0 | Aucun
Weld | 5026 | Autour | 6 | 0 | Aucun
Weld | 5025 | Autour | 6 | 0 | Aucun
Weld | 5024 | Autour | 6 | 0 | Aucun
Weld | 5023 | Autour | 6 | 0 | Aucun
Weld | 5022 | Autour | 6 | 0 | Aucun
Weld | 5021 | Autour | 6 | 0 | Aucun
Weld | 5020 | Autour | 6 | 0 | Aucun
Weld | 5019 | Autour | 6 | 0 | Aucun
Weld | 5014 | Autour | 6 | 0 | Aucun
Weld | 5012 | Autour | 6 | 0 | Aucun
Weld | 5011 | Autour | 6 | 0 | Aucun
Weld | 5010 | Autour | 6 | 0 | Aucun
Weld | 5009 | Autour | 6 | 0 | Aucun
Weld | 5003 | Autour | 6 | 0 | Aucun
Weld | 5002 | Autour | 6 | 0 | Aucun
Weld | 5001 | Autour | 6 | 0 | Aucun
Weld | 5000 | Autour | 6 | 0 | Aucun
Weld | 4995 | Autour | 6 | 0 | Aucun
Weld | 4994 | Autour | 6 | 0 | Aucun
Weld | 4993 | Autour | 6 | 0 | Aucun
Weld | 4992 | Autour | 6 | 0 | Aucun
Weld | 4990 | Autour | 6 | 0 | Aucun
Weld | 4989 | Autour | 6 | 0 | Aucun
Weld | 4988 | Autour | 6 | 0 | Aucun
Weld | 4987 | Autour | 6 | 0 | Aucun
Weld | 4986 | Autour | 6 | 0 | Aucun
Weld | 4985 | Autour | 6 | 0 | Aucun
Weld | 4984 | Autour | 6 | 0 | Aucun
Weld | 4983 | Autour | 6 | 0 | Aucun
Weld | 4982 | Autour | 6 | 0 | Aucun
Weld | 4981 | Autour | 6 | 0 | Aucun
Weld | 4980 | Autour | 6 | 0 | Aucun
Weld | 4979 | Autour | 6 | 0 | Aucun
Weld | 4978 | Autour | 6 | 0 | Aucun
Weld | 4977 | Autour | 6 | 0 | Aucun
Weld | 4976 | Autour | 6 | 0 | Aucun
Weld | 4975 | Autour | 6 | 0 | Aucun
Weld | 4974 | Autour | 6 | 0 | Aucun
Weld | 4973 | Autour | 6 | 0 | Aucun
Weld | 4972 | Autour | 6 | 0 | Aucun
Weld | 4971 | Autour | 6 | 0 | Aucun
Weld | 4970 | Autour | 6 | 0 | Aucun
Weld | 4969 | Autour | 6 | 0 | Aucun
Weld | 4968 | Autour | 6 | 0 | Aucun
Weld | 4967 | Autour | 6 | 0 | Aucun
Weld | 4966 | Autour | 6 | 0 | Aucun
Weld | 4965 | Autour | 6 | 0 | Aucun
Weld | 4964 | Autour | 6 | 0 | Aucun
Weld | 4963 | Autour | 6 | 0 | Aucun
Weld | 4962 | Autour | 6 | 0 | Aucun
Weld | 4961 | Autour | 6 | 0 | Aucun
Weld | 4960 | Autour | 6 | 0 | Aucun
Weld | 4959 | Autour | 6 | 0 | Aucun
Weld | 4958 | Autour | 6 | 0 | Aucun
Weld | 4957 | Autour | 6 | 0 | Aucun
Weld | 4955 | Autour | 6 | 0 | Aucun
Weld | 4944 | Autour | 6 | 0 | Aucun
Weld | 4943 | Autour | 6 | 0 | Aucun
Weld | 4937 | Autour | 6 | 0 | Aucun
Weld | 4935 | Autour | 6 | 0 | Aucun
Weld | 4934 | Autour | 6 | 0 | Aucun
Weld | 4933 | Autour | 6 | 0 | Aucun
Weld | 4932 | Autour | 6 | 0 | Aucun
Weld | 4931 | Autour | 6 | 0 | Aucun
Weld | 4930 | Autour | 6 | 0 | Aucun
Weld | 4929 | Autour | 6 | 0 | Aucun
Weld | 4928 | Autour | 6 | 0 | Aucun
Weld | 4927 | Autour | 6 | 0 | Aucun
Weld | 4926 | Autour | 6 | 0 | Aucun
Weld | 4925 | Autour | 6 | 0 | Aucun
Weld | 4924 | Autour | 6 | 0 | Aucun
Weld | 4923 | Autour | 6 | 0 | Aucun
Weld | 4922 | Autour | 6 | 0 | Aucun
Weld | 4921 | Autour | 6 | 0 | Aucun
Weld | 4920 | Autour | 6 | 0 | Aucun
Weld | 4919 | Autour | 6 | 0 | Aucun
Weld | 4915 | Autour | 6 | 0 | Aucun
Weld | 4914 | Autour | 6 | 0 | Aucun
Weld | 4905 | Autour | 6 | 0 | Aucun
Weld | 4904 | Autour | 6 | 0 | Aucun
Weld | 4903 | Autour | 6 | 0 | Aucun
Weld | 4901 | Autour | 6 | 0 | Aucun
Weld | 4900 | Autour | 6 | 0 | Aucun
Weld | 4899 | Autour | 6 | 0 | Aucun
Weld | 4897 | Autour | 6 | 0 | Aucun
Weld | 4896 | Autour | 6 | 0 | Aucun
Weld | 4893 | Autour | 6 | 0 | Aucun
Weld | 4892 | Autour | 6 | 0 | Aucun
Weld | 4891 | Autour | 6 | 0 | Aucun
Weld | 4889 | Autour | 6 | 0 | Aucun
Weld | 4881 | Autour | 6 | 0 | Aucun
Weld | 4880 | Autour | 6 | 0 | Aucun
Weld | 4874 | Autour | 6 | 0 | Aucun
Weld | 4873 | Autour | 6 | 0 | Aucun
Weld | 4866 | Autour | 6 | 0 | Aucun
Weld | 4865 | Autour | 6 | 0 | Aucun
Weld | 4864 | Autour | 6 | 0 | Aucun
Weld | 4863 | Autour | 6 | 0 | Aucun
Weld | 4862 | Autour | 6 | 0 | Aucun
Weld | 4861 | Autour | 6 | 0 | Aucun
Weld | 4860 | Autour | 6 | 0 | Aucun
Weld | 4859 | Autour | 6 | 0 | Aucun
Weld | 4858 | Autour | 6 | 0 | Aucun
Weld | 4857 | Autour | 6 | 0 | Aucun
Weld | 4856 | Autour | 6 | 0 | Aucun
Weld | 4855 | Autour | 6 | 0 | Aucun
Weld | 4854 | Autour | 6 | 0 | Aucun
Weld | 4853 | Autour | 6 | 0 | Aucun
Weld | 4852 | Autour | 6 | 0 | Aucun
Weld | 4851 | Autour | 6 | 0 | Aucun
Weld | 4850 | Autour | 6 | 0 | Aucun
Weld | 4849 | Autour | 6 | 0 | Aucun
Weld | 4848 | Autour | 6 | 0 | Aucun
Weld | 4847 | Autour | 6 | 0 | Aucun
Weld | 4846 | Autour | 6 | 0 | Aucun
Weld | 4845 | Autour | 6 | 0 | Aucun
Weld | 4844 | Autour | 6 | 0 | Aucun
Weld | 4843 | Autour | 6 | 0 | Aucun
Weld | 4842 | Autour | 6 | 0 | Aucun
Weld | 4841 | Autour | 6 | 0 | Aucun
Weld | 4840 | Autour | 6 | 0 | Aucun
Weld | 4839 | Autour | 6 | 0 | Aucun
Weld | 4838 | Autour | 6 | 0 | Aucun
Weld | 4837 | Autour | 6 | 0 | Aucun
Weld | 4836 | Autour | 6 | 0 | Aucun
Weld | 4835 | Autour | 6 | 0 | Aucun
Weld | 4834 | Autour | 6 | 0 | Aucun
Weld | 4833 | Autour | 6 | 0 | Aucun
Weld | 4832 | Autour | 6 | 0 | Aucun
Weld | 4831 | Autour | 6 | 0 | Aucun
Weld | 4830 | Autour | 6 | 0 | Aucun
Weld | 4829 | Autour | 6 | 0 | Aucun
Weld | 4828 | Autour | 6 | 0 | Aucun
Weld | 4827 | Autour | 6 | 0 | Aucun
Weld | 4826 | Autour | 6 | 0 | Aucun
Weld | 4825 | Autour | 6 | 0 | Aucun
Weld | 4824 | Autour | 6 | 0 | Aucun
Weld | 4823 | Autour | 6 | 0 | Aucun
Weld | 4822 | Autour | 6 | 0 | Aucun
Weld | 4821 | Autour | 6 | 0 | Aucun
Weld | 4820 | Autour | 6 | 0 | Aucun
Weld | 4819 | Autour | 6 | 0 | Aucun
Weld | 4818 | Autour | 6 | 0 | Aucun
Weld | 4817 | Autour | 6 | 0 | Aucun
Weld | 4816 | Autour | 6 | 0 | Aucun
Weld | 4815 | Autour | 6 | 0 | Aucun
Weld | 4814 | Autour | 6 | 0 | Aucun
Weld | 4813 | Autour | 6 | 0 | Aucun
Weld | 4812 | Autour | 6 | 0 | Aucun
Weld | 4811 | Autour | 6 | 0 | Aucun
Weld | 4810 | Autour | 6 | 0 | Aucun
Weld | 4809 | Autour | 6 | 0 | Aucun
Weld | 4808 | Autour | 6 | 0 | Aucun
Weld | 4807 | Autour | 6 | 0 | Aucun
Weld | 4806 | Autour | 6 | 0 | Aucun
Weld | 4805 | Autour | 6 | 0 | Aucun
Weld | 4804 | Autour | 6 | 0 | Aucun
Weld | 4803 | Autour | 6 | 0 | Aucun
Weld | 4802 | Autour | 6 | 0 | Aucun
Weld | 4801 | Autour | 6 | 0 | Aucun
Weld | 4800 | Autour | 6 | 0 | Aucun
Weld | 4799 | Autour | 6 | 0 | Aucun
Weld | 4798 | Autour | 6 | 0 | Aucun
Weld | 4797 | Autour | 6 | 0 | Aucun
Weld | 4796 | Autour | 6 | 0 | Aucun
Weld | 4795 | Autour | 6 | 0 | Aucun
Weld | 4794 | Autour | 6 | 0 | Aucun
Weld | 4793 | Autour | 6 | 0 | Aucun
Weld | 4792 | Autour | 6 | 0 | Aucun
Weld | 4791 | Autour | 6 | 0 | Aucun
Weld | 4786 | Autour | 6 | 0 | Aucun
Weld | 4785 | Autour | 6 | 0 | Aucun
Weld | 4784 | Autour | 6 | 0 | Aucun
Weld | 4783 | Autour | 6 | 0 | Aucun
Weld | 4782 | Autour | 6 | 0 | Aucun
Weld | 4781 | Autour | 6 | 0 | Aucun
Weld | 4780 | Autour | 6 | 0 | Aucun
Weld | 4779 | Autour | 6 | 0 | Aucun
Weld | 4778 | Autour | 6 | 0 | Aucun
Weld | 4777 | Autour | 6 | 0 | Aucun
Weld | 4776 | Autour | 6 | 0 | Aucun
Weld | 4774 | Autour | 6 | 0 | Aucun
Weld | 4773 | Autour | 6 | 0 | Aucun
Weld | 4771 | Autour | 6 | 0 | Aucun
Weld | 4770 | Autour | 6 | 0 | Aucun
Weld | 4769 | Autour | 6 | 0 | Aucun
Weld | 4768 | Autour | 6 | 0 | Aucun
Weld | 4766 | Autour | 6 | 0 | Aucun
Weld | 4765 | Autour | 6 | 0 | Aucun
Weld | 4764 | Autour | 6 | 0 | Aucun
Weld | 4763 | Autour | 6 | 0 | Aucun
Weld | 4761 | Autour | 6 | 0 | Aucun
Weld | 4760 | Autour | 6 | 0 | Aucun
Weld | 4759 | Autour | 6 | 0 | Aucun
Weld | 4758 | Autour | 6 | 0 | Aucun
Weld | 4757 | Autour | 6 | 0 | Aucun
Weld | 4755 | Autour | 6 | 0 | Aucun
Weld | 4752 | Autour | 6 | 0 | Aucun
Weld | 4751 | Autour | 6 | 0 | Aucun
Weld | 4750 | Autour | 6 | 0 | Aucun
Weld | 4749 | Autour | 6 | 0 | Aucun
Weld | 4748 | Autour | 6 | 0 | Aucun
Weld | 4747 | Autour | 6 | 0 | Aucun
Weld | 4746 | Autour | 6 | 0 | Aucun
Weld | 4745 | Autour | 6 | 0 | Aucun
Weld | 4744 | Autour | 6 | 0 | Aucun
Weld | 4743 | Autour | 6 | 0 | Aucun
Weld | 4742 | Autour | 6 | 0 | Aucun
Weld | 4739 | Autour | 6 | 0 | Aucun
Weld | 4738 | Autour | 6 | 0 | Aucun
Weld | 4737 | Autour | 6 | 0 | Aucun
Weld | 4736 | Autour | 6 | 0 | Aucun
Weld | 4735 | Autour | 6 | 0 | Aucun
Weld | 4734 | Autour | 6 | 0 | Aucun
Weld | 4732 | Autour | 6 | 0 | Aucun
Weld | 4731 | Autour | 6 | 0 | Aucun
Weld | 4730 | Autour | 6 | 0 | Aucun
Weld | 4727 | Autour | 6 | 0 | Aucun
Weld | 4726 | Autour | 6 | 0 | Aucun
Weld | 4725 | Autour | 6 | 0 | Aucun
Weld | 4724 | Autour | 6 | 0 | Aucun
Weld | 4721 | Autour | 6 | 0 | Aucun
Weld | 4720 | Autour | 6 | 0 | Aucun
Weld | 4719 | Autour | 6 | 0 | Aucun
Weld | 4717 | Autour | 6 | 0 | Aucun
Weld | 4716 | Autour | 6 | 0 | Aucun
Weld | 4715 | Autour | 6 | 0 | Aucun
Weld | 4714 | Autour | 6 | 0 | Aucun
Weld | 4711 | Autour | 6 | 0 | Aucun
Weld | 4710 | Autour | 6 | 0 | Aucun
Weld | 4709 | Autour | 6 | 0 | Aucun
Weld | 4708 | Autour | 6 | 0 | Aucun
Weld | 4706 | Autour | 6 | 0 | Aucun
Weld | 4701 | Autour | 6 | 0 | Aucun
Weld | 4700 | Autour | 6 | 0 | Aucun
Weld | 4699 | Autour | 6 | 0 | Aucun
Weld | 4698 | Autour | 6 | 0 | Aucun
Weld | 4697 | Autour | 6 | 0 | Aucun
Weld | 4696 | Autour | 6 | 0 | Aucun
Weld | 4695 | Autour | 6 | 0 | Aucun
Weld | 4694 | Autour | 6 | 0 | Aucun
Weld | 4693 | Autour | 6 | 0 | Aucun
Weld | 4690 | Autour | 6 | 0 | Aucun
Weld | 4680 | Autour | 6 | 0 | Aucun
Weld | 4679 | Autour | 6 | 0 | Aucun
Weld | 4678 | Autour | 6 | 0 | Aucun
Weld | 4674 | Autour | 6 | 0 | Aucun
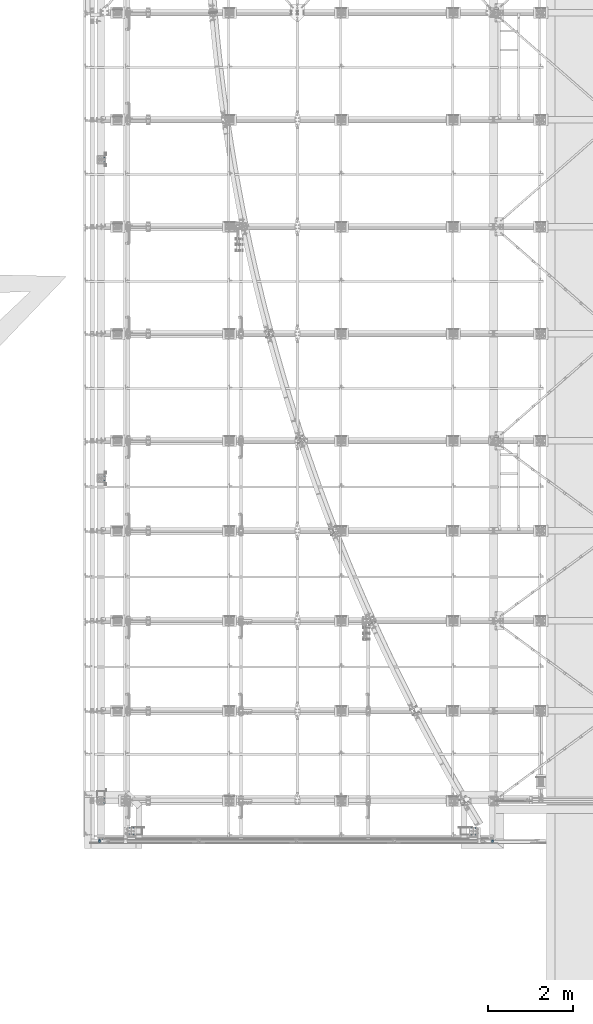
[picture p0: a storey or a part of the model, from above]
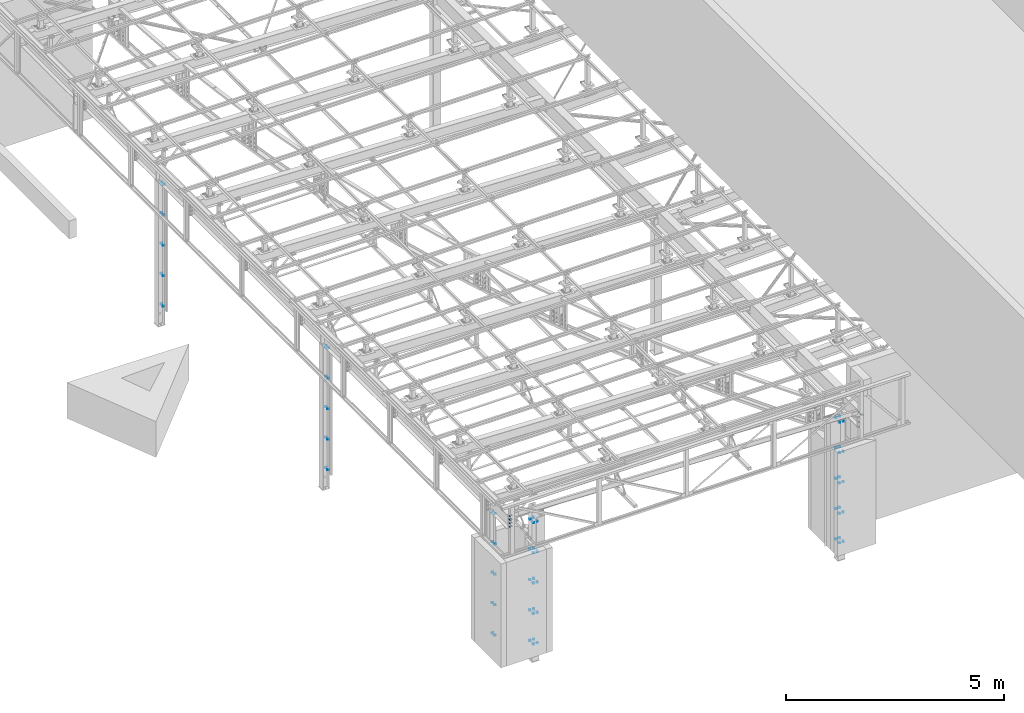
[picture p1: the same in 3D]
Properties of the parts of a building model (IFC2X3), part 8 of 13

# IfcFastener (6774)
Name | N° soudure | Linéaire/Périphérique | Dimension1 (mm) | Dimension2 (mm) | Type2
Weld | 4673 | Autour | 6 | 0 | Aucun
Weld | 4672 | Autour | 6 | 0 | Aucun
Weld | 4671 | Autour | 6 | 0 | Aucun
Weld | 4670 | Autour | 6 | 0 | Aucun
Weld | 4669 | Autour | 6 | 0 | Aucun
Weld | 4668 | Autour | 6 | 0 | Aucun
Weld | 4667 | Autour | 6 | 0 | Aucun
Weld | 4666 | Autour | 6 | 0 | Aucun
Weld | 4664 | Autour | 6 | 0 | Aucun
Weld | 4663 | Autour | 6 | 0 | Aucun
Weld | 4662 | Autour | 6 | 0 | Aucun
Weld | 4661 | Autour | 6 | 0 | Aucun
Weld | 4660 | Autour | 6 | 0 | Aucun
Weld | 4659 | Autour | 6 | 0 | Aucun
Weld | 4658 | Autour | 6 | 0 | Aucun
Weld | 4657 | Autour | 6 | 0 | Aucun
Weld | 4656 | Autour | 6 | 0 | Aucun
Weld | 4655 | Autour | 6 | 0 | Aucun
Weld | 4654 | Autour | 6 | 0 | Aucun
Weld | 4653 | Autour | 6 | 0 | Aucun
Weld | 4650 | Autour | 6 | 0 | Aucun
Weld | 4649 | Autour | 6 | 0 | Aucun
Weld | 4648 | Autour | 6 | 0 | Aucun
Weld | 4647 | Autour | 6 | 0 | Aucun
Weld | 4616 | Autour | 6 | 0 | Aucun
Weld | 4615 | Autour | 6 | 0 | Aucun
Weld | 4613 | Autour | 6 | 0 | Aucun
Weld | 4612 | Autour | 6 | 0 | Aucun
Weld | 4611 | Autour | 6 | 0 | Aucun
Weld | 4610 | Autour | 6 | 0 | Aucun
Weld | 4609 | Autour | 6 | 0 | Aucun
Weld | 4608 | Autour | 6 | 0 | Aucun
Weld | 4606 | Autour | 6 | 0 | Aucun
Weld | 4605 | Autour | 6 | 0 | Aucun
Weld | 4604 | Autour | 6 | 0 | Aucun
Weld | 4603 | Autour | 6 | 0 | Aucun
Weld | 4602 | Autour | 6 | 0 | Aucun
Weld | 4600 | Autour | 6 | 0 | Aucun
Weld | 4599 | Autour | 6 | 0 | Aucun
Weld | 4597 | Autour | 6 | 0 | Aucun
Weld | 4596 | Autour | 6 | 0 | Aucun
Weld | 4595 | Autour | 6 | 0 | Aucun
Weld | 4594 | Autour | 6 | 0 | Aucun
Weld | 4593 | Autour | 6 | 0 | Aucun
Weld | 4592 | Autour | 6 | 0 | Aucun
Weld | 4591 | Autour | 6 | 0 | Aucun
Weld | 4590 | Autour | 6 | 0 | Aucun
Weld | 4589 | Autour | 6 | 0 | Aucun
Weld | 4588 | Autour | 6 | 0 | Aucun
Weld | 4587 | Autour | 6 | 0 | Aucun
Weld | 4586 | Autour | 6 | 0 | Aucun
Weld | 4585 | Autour | 6 | 0 | Aucun
Weld | 4584 | Autour | 6 | 0 | Aucun
Weld | 4583 | Autour | 6 | 0 | Aucun
Weld | 4582 | Autour | 6 | 0 | Aucun
Weld | 4581 | Autour | 6 | 0 | Aucun
Weld | 4580 | Autour | 6 | 0 | Aucun
Weld | 4579 | Autour | 6 | 0 | Aucun
Weld | 4578 | Autour | 6 | 0 | Aucun
Weld | 4577 | Autour | 6 | 0 | Aucun
Weld | 4576 | Autour | 6 | 0 | Aucun
Weld | 4575 | Autour | 6 | 0 | Aucun
Weld | 4574 | Autour | 6 | 0 | Aucun
Weld | 4573 | Autour | 6 | 0 | Aucun
Weld | 4572 | Autour | 6 | 0 | Aucun
Weld | 4571 | Autour | 6 | 0 | Aucun
Weld | 4570 | Autour | 6 | 0 | Aucun
Weld | 4569 | Autour | 6 | 0 | Aucun
Weld | 4568 | Autour | 6 | 0 | Aucun
Weld | 4567 | Autour | 6 | 0 | Aucun
Weld | 4566 | Autour | 6 | 0 | Aucun
Weld | 4565 | Autour | 6 | 0 | Aucun
Weld | 4564 | Autour | 6 | 0 | Aucun
Weld | 4563 | Autour | 6 | 0 | Aucun
Weld | 4562 | Autour | 6 | 0 | Aucun
Weld | 4561 | Autour | 6 | 0 | Aucun
Weld | 4560 | Autour | 6 | 0 | Aucun
Weld | 4559 | Autour | 6 | 0 | Aucun
Weld | 4558 | Autour | 6 | 0 | Aucun
Weld | 4557 | Autour | 6 | 0 | Aucun
Weld | 4556 | Autour | 6 | 0 | Aucun
Weld | 4555 | Autour | 6 | 0 | Aucun
Weld | 4554 | Autour | 6 | 0 | Aucun
Weld | 4553 | Autour | 6 | 0 | Aucun
Weld | 4552 | Autour | 6 | 0 | Aucun
Weld | 4551 | Autour | 6 | 0 | Aucun
Weld | 4550 | Autour | 6 | 0 | Aucun
Weld | 4549 | Autour | 6 | 0 | Aucun
Weld | 4548 | Autour | 6 | 0 | Aucun
Weld | 4547 | Autour | 6 | 0 | Aucun
Weld | 4546 | Autour | 6 | 0 | Aucun
Weld | 4545 | Autour | 6 | 0 | Aucun
Weld | 4544 | Autour | 6 | 0 | Aucun
Weld | 4543 | Autour | 6 | 0 | Aucun
Weld | 4542 | Autour | 6 | 0 | Aucun
Weld | 4541 | Autour | 6 | 0 | Aucun
Weld | 4540 | Autour | 6 | 0 | Aucun
Weld | 4539 | Autour | 6 | 0 | Aucun
Weld | 4538 | Autour | 6 | 0 | Aucun
Weld | 4537 | Autour | 6 | 0 | Aucun
Weld | 4455 | Autour | 6 | 0 | Aucun
Weld | 4454 | Autour | 6 | 0 | Aucun
Weld | 4453 | Autour | 6 | 0 | Aucun
Weld | 4452 | Autour | 6 | 0 | Aucun
Weld | 4451 | Autour | 6 | 0 | Aucun
Weld | 4450 | Autour | 6 | 0 | Aucun
Weld | 4449 | Autour | 6 | 0 | Aucun
Weld | 4448 | Autour | 6 | 0 | Aucun
Weld | 4447 | Autour | 6 | 0 | Aucun
Weld | 4446 | Autour | 6 | 0 | Aucun
Weld | 4445 | Autour | 6 | 0 | Aucun
Weld | 4443 | Autour | 6 | 0 | Aucun
Weld | 4441 | Autour | 6 | 0 | Aucun
Weld | 4440 | Autour | 6 | 0 | Aucun
Weld | 4439 | Autour | 6 | 0 | Aucun
Weld | 4433 | Autour | 6 | 0 | Aucun
Weld | 4432 | Autour | 6 | 0 | Aucun
Weld | 4431 | Autour | 6 | 0 | Aucun
Weld | 4430 | Autour | 6 | 0 | Aucun
Weld | 4429 | Autour | 6 | 0 | Aucun
Weld | 4428 | Autour | 6 | 0 | Aucun
Weld | 4427 | Autour | 6 | 0 | Aucun
Weld | 4426 | Autour | 6 | 0 | Aucun
Weld | 4419 | Autour | 6 | 0 | Aucun
Weld | 4418 | Autour | 6 | 0 | Aucun
Weld | 4414 | Autour | 6 | 0 | Aucun
Weld | 4413 | Autour | 6 | 0 | Aucun
Weld | 4401 | Autour | 6 | 0 | Aucun
Weld | 4400 | Autour | 6 | 0 | Aucun
Weld | 4399 | Autour | 6 | 0 | Aucun
Weld | 4398 | Autour | 6 | 0 | Aucun
Weld | 4397 | Autour | 6 | 0 | Aucun
Weld | 4396 | Autour | 6 | 0 | Aucun
Weld | 4390 | Autour | 6 | 0 | Aucun
Weld | 4389 | Autour | 6 | 0 | Aucun
Weld | 4388 | Autour | 6 | 0 | Aucun
Weld | 4387 | Autour | 6 | 0 | Aucun
Weld | 4386 | Autour | 6 | 0 | Aucun
Weld | 4353 | Autour | 6 | 0 | Aucun
Weld | 4352 | Autour | 6 | 0 | Aucun
Weld | 4351 | Autour | 6 | 0 | Aucun
Weld | 4350 | Autour | 6 | 0 | Aucun
Weld | 4349 | Autour | 6 | 0 | Aucun
Weld | 4348 | Autour | 6 | 0 | Aucun
Weld | 4345 | Autour | 6 | 0 | Aucun
Weld | 4344 | Autour | 6 | 0 | Aucun
Weld | 4342 | Autour | 6 | 0 | Aucun
Weld | 4341 | Autour | 6 | 0 | Aucun
Weld | 4340 | Autour | 6 | 0 | Aucun
Weld | 4339 | Autour | 6 | 0 | Aucun
Weld | 4338 | Autour | 6 | 0 | Aucun
Weld | 4337 | Autour | 6 | 0 | Aucun
Weld | 4336 | Autour | 6 | 0 | Aucun
Weld | 4335 | Autour | 6 | 0 | Aucun
Weld | 4334 | Autour | 6 | 0 | Aucun
Weld | 4333 | Autour | 6 | 0 | Aucun
Weld | 4330 | Autour | 6 | 0 | Aucun
Weld | 4329 | Autour | 6 | 0 | Aucun
Weld | 4327 | Autour | 6 | 0 | Aucun
Weld | 4326 | Autour | 6 | 0 | Aucun
Weld | 4325 | Autour | 6 | 0 | Aucun
Weld | 4324 | Autour | 6 | 0 | Aucun
Weld | 4323 | Autour | 6 | 0 | Aucun
Weld | 4322 | Autour | 6 | 0 | Aucun
Weld | 4321 | Autour | 6 | 0 | Aucun
Weld | 4320 | Autour | 6 | 0 | Aucun
Weld | 4319 | Autour | 6 | 0 | Aucun
Weld | 4318 | Autour | 6 | 0 | Aucun
Weld | 4302 | Autour | 6 | 0 | Aucun
Weld | 4301 | Autour | 6 | 0 | Aucun
Weld | 4300 | Autour | 6 | 0 | Aucun
Weld | 4299 | Autour | 6 | 0 | Aucun
Weld | 4298 | Autour | 6 | 0 | Aucun
Weld | 4297 | Autour | 6 | 0 | Aucun
Weld | 4296 | Autour | 6 | 0 | Aucun
Weld | 4295 | Autour | 6 | 0 | Aucun
Weld | 4294 | Autour | 6 | 0 | Aucun
Weld | 4291 | Autour | 6 | 0 | Aucun
Weld | 4290 | Autour | 6 | 0 | Aucun
Weld | 4289 | Autour | 6 | 0 | Aucun
Weld | 4287 | Autour | 6 | 0 | Aucun
Weld | 4286 | Autour | 6 | 0 | Aucun
Weld | 4285 | Autour | 6 | 0 | Aucun
Weld | 4284 | Autour | 6 | 0 | Aucun
Weld | 4283 | Autour | 6 | 0 | Aucun
Weld | 4282 | Autour | 6 | 0 | Aucun
Weld | 4281 | Autour | 6 | 0 | Aucun
Weld | 4280 | Autour | 6 | 0 | Aucun
Weld | 4279 | Autour | 6 | 0 | Aucun
Weld | 4276 | Autour | 6 | 0 | Aucun
Weld | 4275 | Autour | 6 | 0 | Aucun
Weld | 4274 | Autour | 6 | 0 | Aucun
Weld | 4272 | Autour | 6 | 0 | Aucun
Weld | 4271 | Autour | 6 | 0 | Aucun
Weld | 4270 | Autour | 6 | 0 | Aucun
Weld | 4269 | Autour | 6 | 0 | Aucun
Weld | 4268 | Autour | 6 | 0 | Aucun
Weld | 4267 | Autour | 6 | 0 | Aucun
Weld | 4266 | Autour | 6 | 0 | Aucun
Weld | 4265 | Autour | 6 | 0 | Aucun
Weld | 4264 | Autour | 6 | 0 | Aucun
Weld | 4261 | Autour | 6 | 0 | Aucun
Weld | 4260 | Autour | 6 | 0 | Aucun
Weld | 4259 | Autour | 6 | 0 | Aucun
Weld | 4225 | Autour | 6 | 0 | Aucun
Weld | 4224 | Autour | 6 | 0 | Aucun
Weld | 4222 | Autour | 6 | 0 | Aucun
Weld | 4221 | Autour | 6 | 0 | Aucun
Weld | 4220 | Autour | 6 | 0 | Aucun
Weld | 4219 | Autour | 6 | 0 | Aucun
Weld | 4218 | Autour | 6 | 0 | Aucun
Weld | 4217 | Autour | 6 | 0 | Aucun
Weld | 4216 | Autour | 6 | 0 | Aucun
Weld | 4215 | Autour | 6 | 0 | Aucun
Weld | 4214 | Autour | 6 | 0 | Aucun
Weld | 4213 | Autour | 6 | 0 | Aucun
Weld | 4212 | Autour | 6 | 0 | Aucun
Weld | 4211 | Autour | 6 | 0 | Aucun
Weld | 4210 | Autour | 6 | 0 | Aucun
Weld | 4209 | Autour | 6 | 0 | Aucun
Weld | 4207 | Autour | 6 | 0 | Aucun
Weld | 4206 | Autour | 6 | 0 | Aucun
Weld | 4205 | Autour | 6 | 0 | Aucun
Weld | 4204 | Autour | 6 | 0 | Aucun
Weld | 4202 | Autour | 6 | 0 | Aucun
Weld | 4201 | Autour | 6 | 0 | Aucun
Weld | 4200 | Autour | 6 | 0 | Aucun
Weld | 4199 | Autour | 6 | 0 | Aucun
Weld | 4197 | Autour | 6 | 0 | Aucun
Weld | 4196 | Autour | 6 | 0 | Aucun
Weld | 4195 | Autour | 6 | 0 | Aucun
Weld | 4194 | Autour | 6 | 0 | Aucun
Weld | 4192 | Autour | 6 | 0 | Aucun
Weld | 4191 | Autour | 6 | 0 | Aucun
Weld | 4190 | Autour | 6 | 0 | Aucun
Weld | 4189 | Autour | 6 | 0 | Aucun
Weld | 4187 | Autour | 6 | 0 | Aucun
Weld | 4186 | Autour | 6 | 0 | Aucun
Weld | 4185 | Autour | 6 | 0 | Aucun
Weld | 4184 | Autour | 6 | 0 | Aucun
Weld | 4182 | Autour | 6 | 0 | Aucun
Weld | 4181 | Autour | 6 | 0 | Aucun
Weld | 4180 | Autour | 6 | 0 | Aucun
Weld | 4179 | Autour | 6 | 0 | Aucun
Weld | 4177 | Autour | 6 | 0 | Aucun
Weld | 4176 | Autour | 6 | 0 | Aucun
Weld | 4175 | Autour | 6 | 0 | Aucun
Weld | 4174 | Autour | 6 | 0 | Aucun
Weld | 4172 | Autour | 6 | 0 | Aucun
Weld | 4171 | Autour | 6 | 0 | Aucun
Weld | 4170 | Autour | 6 | 0 | Aucun
Weld | 4169 | Autour | 6 | 0 | Aucun
Weld | 4164 | Autour | 6 | 0 | Aucun
Weld | 4163 | Autour | 6 | 0 | Aucun
Weld | 4162 | Autour | 6 | 0 | Aucun
Weld | 4161 | Autour | 6 | 0 | Aucun
Weld | 4160 | Autour | 6 | 0 | Aucun
Weld | 4159 | Autour | 6 | 0 | Aucun
Weld | 4158 | Autour | 6 | 0 | Aucun
Weld | 4157 | Autour | 6 | 0 | Aucun
Weld | 4156 | Autour | 6 | 0 | Aucun
Weld | 4155 | Autour | 6 | 0 | Aucun
Weld | 4154 | Autour | 6 | 0 | Aucun
Weld | 4153 | Autour | 6 | 0 | Aucun
Weld | 4151 | Autour | 6 | 0 | Aucun
Weld | 4150 | Autour | 6 | 0 | Aucun
Weld | 4147 | Autour | 6 | 0 | Aucun
Weld | 4146 | Autour | 6 | 0 | Aucun
Weld | 4145 | Autour | 6 | 0 | Aucun
Weld | 4144 | Autour | 6 | 0 | Aucun
Weld | 4143 | Autour | 6 | 0 | Aucun
Weld | 4142 | Autour | 6 | 0 | Aucun
Weld | 4141 | Autour | 6 | 0 | Aucun
Weld | 4140 | Autour | 6 | 0 | Aucun
Weld | 4139 | Autour | 6 | 0 | Aucun
Weld | 4138 | Autour | 6 | 0 | Aucun
Weld | 4136 | Autour | 6 | 0 | Aucun
Weld | 4135 | Autour | 6 | 0 | Aucun
Weld | 4132 | Autour | 6 | 0 | Aucun
Weld | 4131 | Autour | 6 | 0 | Aucun
Weld | 4130 | Autour | 6 | 0 | Aucun
Weld | 4129 | Autour | 6 | 0 | Aucun
Weld | 4128 | Autour | 6 | 0 | Aucun
Weld | 4127 | Autour | 6 | 0 | Aucun
Weld | 4126 | Autour | 6 | 0 | Aucun
Weld | 4125 | Autour | 6 | 0 | Aucun
Weld | 4124 | Autour | 6 | 0 | Aucun
Weld | 4123 | Autour | 6 | 0 | Aucun
Weld | 4121 | Autour | 6 | 0 | Aucun
Weld | 4120 | Autour | 6 | 0 | Aucun
Weld | 4117 | Autour | 6 | 0 | Aucun
Weld | 4116 | Autour | 6 | 0 | Aucun
Weld | 4115 | Autour | 6 | 0 | Aucun
Weld | 4114 | Autour | 6 | 0 | Aucun
Weld | 4113 | Autour | 6 | 0 | Aucun
Weld | 4112 | Autour | 6 | 0 | Aucun
Weld | 4111 | Autour | 6 | 0 | Aucun
Weld | 4110 | Autour | 6 | 0 | Aucun
Weld | 4109 | Autour | 6 | 0 | Aucun
Weld | 4108 | Autour | 6 | 0 | Aucun
Weld | 4106 | Autour | 6 | 0 | Aucun
Weld | 4105 | Autour | 6 | 0 | Aucun
Weld | 4104 | Autour | 6 | 0 | Aucun
Weld | 4103 | Autour | 6 | 0 | Aucun
Weld | 4102 | Autour | 6 | 0 | Aucun
Weld | 4101 | Autour | 6 | 0 | Aucun
Weld | 4100 | Autour | 6 | 0 | Aucun
Weld | 4098 | Autour | 6 | 0 | Aucun
Weld | 4096 | Autour | 6 | 0 | Aucun
Weld | 4095 | Autour | 6 | 0 | Aucun
Weld | 4094 | Autour | 6 | 0 | Aucun
Weld | 4093 | Autour | 6 | 0 | Aucun
Weld | 4091 | Autour | 6 | 0 | Aucun
Weld | 4090 | Autour | 6 | 0 | Aucun
Weld | 4089 | Autour | 6 | 0 | Aucun
Weld | 4088 | Autour | 6 | 0 | Aucun
Weld | 4081 | Autour | 6 | 0 | Aucun
Weld | 4080 | Autour | 6 | 0 | Aucun
Weld | 4032 | Autour | 6 | 0 | Aucun
Weld | 4031 | Autour | 6 | 0 | Aucun
Weld | 4030 | Autour | 6 | 0 | Aucun
Weld | 4026 | Droit | 5 | 0 | Aucun
Weld | 4025 | Droit | 5 | 0 | Aucun
Weld | 4023 | Droit | 5 | 0 | Aucun
Weld | 4019 | Droit | 5 | 0 | Aucun
Weld | 4009 | Droit | 5 | 0 | Aucun
Weld | 4008 | Droit | 5 | 0 | Aucun
Weld | 4007 | Droit | 5 | 0 | Aucun
Weld | 4006 | Droit | 5 | 0 | Aucun
Weld | 3947 | Autour | 6 | 0 | Aucun
Weld | 3946 | Autour | 6 | 0 | Aucun
Weld | 3945 | Autour | 6 | 0 | Aucun
Weld | 3944 | Autour | 6 | 0 | Aucun
Weld | 3943 | Autour | 6 | 0 | Aucun
Weld | 3942 | Autour | 6 | 0 | Aucun
Weld | 3941 | Autour | 6 | 0 | Aucun
Weld | 3940 | Autour | 6 | 0 | Aucun
Weld | 3939 | Autour | 6 | 0 | Aucun
Weld | 3938 | Autour | 6 | 0 | Aucun
Weld | 3937 | Autour | 6 | 0 | Aucun
Weld | 3936 | Autour | 6 | 0 | Aucun
Weld | 3935 | Autour | 6 | 0 | Aucun
Weld | 3934 | Autour | 6 | 0 | Aucun
Weld | 3933 | Autour | 6 | 0 | Aucun
Weld | 3932 | Autour | 6 | 0 | Aucun
Weld | 3931 | Autour | 6 | 0 | Aucun
Weld | 3930 | Autour | 6 | 0 | Aucun
Weld | 3929 | Autour | 6 | 0 | Aucun
Weld | 3928 | Autour | 6 | 0 | Aucun
Weld | 3927 | Autour | 6 | 0 | Aucun
Weld | 3926 | Autour | 6 | 0 | Aucun
Weld | 3925 | Autour | 6 | 0 | Aucun
Weld | 3924 | Autour | 6 | 0 | Aucun
Weld | 3923 | Autour | 6 | 0 | Aucun
Weld | 3922 | Autour | 6 | 0 | Aucun
Weld | 3921 | Autour | 6 | 0 | Aucun
Weld | 3920 | Autour | 6 | 0 | Aucun
Weld | 3919 | Autour | 6 | 0 | Aucun
Weld | 3918 | Autour | 6 | 0 | Aucun
Weld | 3917 | Autour | 6 | 0 | Aucun
Weld | 3916 | Autour | 6 | 0 | Aucun
Weld | 3915 | Autour | 6 | 0 | Aucun
Weld | 3914 | Autour | 6 | 0 | Aucun
Weld | 3913 | Autour | 6 | 0 | Aucun
Weld | 3912 | Autour | 6 | 0 | Aucun
Weld | 3911 | Autour | 6 | 0 | Aucun
Weld | 3910 | Autour | 6 | 0 | Aucun
Weld | 3909 | Autour | 6 | 0 | Aucun
Weld | 3908 | Autour | 6 | 0 | Aucun
Weld | 3907 | Autour | 6 | 0 | Aucun
Weld | 3906 | Autour | 6 | 0 | Aucun
Weld | 3903 | Autour | 6 | 0 | Aucun
Weld | 3902 | Autour | 6 | 0 | Aucun
Weld | 3901 | Autour | 6 | 0 | Aucun
Weld | 3900 | Autour | 6 | 0 | Aucun
Weld | 3899 | Autour | 6 | 0 | Aucun
Weld | 3898 | Autour | 6 | 0 | Aucun
Weld | 3897 | Autour | 6 | 0 | Aucun
Weld | 3896 | Autour | 6 | 0 | Aucun
Weld | 3895 | Autour | 6 | 0 | Aucun
Weld | 3894 | Autour | 6 | 0 | Aucun
Weld | 3893 | Autour | 6 | 0 | Aucun
Weld | 3892 | Autour | 6 | 0 | Aucun
Weld | 3891 | Autour | 6 | 0 | Aucun
Weld | 3890 | Autour | 6 | 0 | Aucun
Weld | 3889 | Autour | 6 | 0 | Aucun
Weld | 3888 | Autour | 6 | 0 | Aucun
Weld | 3887 | Autour | 6 | 0 | Aucun
Weld | 3886 | Autour | 6 | 0 | Aucun
Weld | 3884 | Autour | 6 | 0 | Aucun
Weld | 3883 | Autour | 6 | 0 | Aucun
Weld | 3882 | Autour | 6 | 0 | Aucun
Weld | 3881 | Autour | 6 | 0 | Aucun
Weld | 3880 | Autour | 6 | 0 | Aucun
Weld | 3879 | Autour | 6 | 0 | Aucun
Weld | 3827 | Autour | 6 | 0 | Aucun
Weld | 3826 | Droit | 6 | 6 | W10
Weld | 3825 | Droit | 6 | 6 | W10
Weld | 3824 | Droit | 6 | 6 | W10
Weld | 3823 | Droit | 6 | 6 | W10
Weld | 3822 | Droit | 6 | 6 | W10
Weld | 3821 | Droit | 6 | 6 | W10
Weld | 3813 | Droit | 6 | 6 | W10
Weld | 3812 | Droit | 6 | 6 | W10
Weld | 3811 | Droit | 6 | 6 | W10
Weld | 3810 | Droit | 6 | 6 | W10
Weld | 3809 | Droit | 6 | 6 | W10
Weld | 3808 | Droit | 6 | 6 | W10
Weld | 3807 | Droit | 5 | 0 | Aucun
Weld | 3806 | Droit | 4 | 4 | W10
Weld | 3805 | Droit | 6 | 6 | W10
Weld | 3804 | Droit | 6 | 6 | W10
Weld | 3803 | Droit | 4 | 4 | W10
Weld | 3802 | Droit | 6 | 6 | W10
Weld | 3801 | Droit | 6 | 6 | W10
Weld | 3800 | Droit | 4 | 4 | W10
Weld | 3799 | Droit | 6 | 6 | W10
Weld | 3798 | Droit | 6 | 6 | W10
Weld | 3797 | Droit | 4 | 4 | W10
Weld | 3796 | Droit | 6 | 6 | W10
Weld | 3795 | Droit | 6 | 6 | W10
Weld | 3792 | Droit | 5 | 0 | Aucun
Weld | 3791 | Autour | 6 | 0 | Aucun
Weld | 3790 | Autour | 6 | 0 | Aucun
Weld | 3789 | Autour | 6 | 0 | Aucun
Weld | 3788 | Autour | 6 | 0 | Aucun
Weld | 3787 | Autour | 6 | 0 | Aucun
Weld | 3786 | Autour | 6 | 0 | Aucun
Weld | 3784 | Autour | 6 | 0 | Aucun
Weld | 3782 | Autour | 6 | 0 | Aucun
Weld | 3781 | Autour | 6 | 0 | Aucun
Weld | 3777 | Autour | 6 | 0 | Aucun
Weld | 3775 | Autour | 6 | 0 | Aucun
Weld | 3774 | Autour | 6 | 0 | Aucun
Weld | 3773 | Autour | 6 | 0 | Aucun
Weld | 3771 | Droit | 3 | 3 | W10
Weld | 3770 | Droit | 5 | 5 | W10
Weld | 3769 | Droit | 5 | 5 | W10
Weld | 3768 | Droit | 3 | 3 | W10
Weld | 3767 | Droit | 5 | 5 | W10
Weld | 3766 | Droit | 5 | 5 | W10
Weld | 3759 | Droit | 3 | 3 | W10
Weld | 3758 | Droit | 5 | 5 | W10
Weld | 3757 | Droit | 5 | 5 | W10
Weld | 3753 | Droit | 3 | 3 | W10
Weld | 3752 | Droit | 5 | 5 | W10
Weld | 3751 | Droit | 5 | 5 | W10
Weld | 3746 | Droit | 3 | 3 | W10
Weld | 3745 | Droit | 5 | 5 | W10
Weld | 3744 | Droit | 5 | 5 | W10
Weld | 3743 | Autour | 6 | 0 | Aucun
Weld | 3741 | Autour | 6 | 0 | Aucun
Weld | 3740 | Autour | 6 | 0 | Aucun
Weld | 3725 | Autour | 6 | 0 | Aucun
Weld | 3724 | Autour | 6 | 0 | Aucun
Weld | 3723 | Autour | 6 | 0 | Aucun
Weld | 3721 | Autour | 6 | 0 | Aucun
Weld | 3719 | Autour | 6 | 0 | Aucun
Weld | 3718 | Autour | 6 | 0 | Aucun
Weld | 3716 | Autour | 6 | 0 | Aucun
Weld | 3715 | Autour | 6 | 0 | Aucun
Weld | 3712 | Autour | 6 | 0 | Aucun
Weld | 3710 | Autour | 6 | 0 | Aucun
Weld | 3709 | Autour | 6 | 0 | Aucun
Weld | 3707 | Autour | 6 | 0 | Aucun
Weld | 3705 | Autour | 6 | 0 | Aucun
Weld | 3703 | Droit | 2 | 2 | W10
Weld | 3702 | Droit | 2 | 2 | W10
Weld | 3700 | Droit | 2 | 2 | W10
Weld | 3699 | Droit | 2 | 2 | W10
Weld | 3697 | Autour | 6 | 0 | Aucun
Weld | 3311 | Autour | 6 | 0 | Aucun
Weld | 3307 | Droit | 2 | 2 | W10
Weld | 3306 | Droit | 2 | 2 | W10
Weld | 3305 | Autour | 6 | 0 | Aucun
Weld | 3304 | Autour | 6 | 0 | Aucun
Weld | 3301 | Droit | 2 | 2 | W10
Weld | 3300 | Droit | 2 | 2 | W10
Weld | 3298 | Droit | 2 | 2 | W10
Weld | 3297 | Droit | 2 | 2 | W10
Weld | 3294 | Autour | 6 | 0 | Aucun
Weld | 3287 | Droit | 2 | 2 | W10
Weld | 3286 | Droit | 2 | 2 | W10
Weld | 3282 | Droit | 2 | 2 | W10
Weld | 3281 | Droit | 2 | 2 | W10
Weld | 3279 | Autour | 6 | 0 | Aucun
Weld | 3277 | Autour | 6 | 0 | Aucun
Weld | 3238 | Autour | 6 | 0 | Aucun
Weld | 3208 | Autour | 6 | 0 | Aucun
Weld | 3207 | Autour | 6 | 0 | Aucun
Weld | 3206 | Autour | 6 | 0 | Aucun
Weld | 3205 | Autour | 6 | 0 | Aucun
Weld | 3203 | Autour | 6 | 0 | Aucun
Weld | 3202 | Autour | 6 | 0 | Aucun
Weld | 3201 | Autour | 6 | 0 | Aucun
Weld | 3199 | Autour | 6 | 0 | Aucun
Weld | 3198 | Autour | 6 | 0 | Aucun
Weld | 3197 | Autour | 6 | 0 | Aucun
Weld | 3192 | Autour | 6 | 0 | Aucun
Weld | 3191 | Autour | 6 | 0 | Aucun
Weld | 3190 | Autour | 6 | 0 | Aucun
Weld | 3189 | Autour | 6 | 0 | Aucun
Weld | 3181 | Autour | 6 | 0 | Aucun
Weld | 3180 | Autour | 6 | 0 | Aucun
Weld | 3173 | Autour | 6 | 0 | Aucun
Weld | 3165 | Autour | 6 | 0 | Aucun
Weld | 3163 | Autour | 6 | 0 | Aucun
Weld | 3162 | Autour | 6 | 0 | Aucun
Weld | 3160 | Autour | 6 | 0 | Aucun
Weld | 3152 | Autour | 6 | 0 | Aucun
2 x Weld | 3151 | Autour | 6 | 0 | Aucun
Weld | 3145 | Autour | 6 | 0 | Aucun
Weld | 3143 | Autour | 6 | 0 | Aucun
Weld | 3161 | Droit | 2 | 2 | W10
Weld | 3160 | Droit | 2 | 2 | W10
Weld | 3159 | Autour | 6 | 0 | Aucun
Weld | 3158 | Autour | 6 | 0 | Aucun
Weld | 3157 | Autour | 6 | 0 | Aucun
Weld | 3156 | Autour | 6 | 0 | Aucun
Weld | 3155 | Autour | 6 | 0 | Aucun
Weld | 3153 | Droit | 2 | 2 | W10
Weld | 3152 | Droit | 2 | 2 | W10
Weld | 3149 | Droit | 2 | 2 | W10
Weld | 3148 | Droit | 2 | 2 | W10
Weld | 3147 | Autour | 6 | 0 | Aucun
Weld | 3145 | Droit | 2 | 2 | W10
Weld | 3144 | Droit | 2 | 2 | W10
2 x Weld | 3142 | Droit | 5 | 5 | W10
2 x Weld | 3141 | Droit | 5 | 5 | W10
2 x Weld | 3140 | Droit | 5 | 5 | W10
2 x Weld | 3139 | Droit | 5 | 5 | W10
Weld | 3138 | Droit | 5 | 5 | W10
Weld | 3137 | Droit | 5 | 5 | W10
2 x Weld | 3136 | Droit | 5 | 5 | W10
2 x Weld | 3135 | Droit | 5 | 5 | W10
2 x Weld | 3134 | Droit | 5 | 5 | W10
2 x Weld | 3133 | Droit | 5 | 5 | W10
Weld | 3132 | Droit | 5 | 5 | W10
Weld | 3131 | Droit | 5 | 5 | W10
Weld | 8484 | Autour | 6 | 0 | Aucun
Weld | 8483 | Autour | 6 | 0 | Aucun
Weld | 8482 | Autour | 6 | 0 | Aucun
Weld | 8476 | Autour | 6 | 0 | Aucun
Weld | 8475 | Autour | 6 | 0 | Aucun
Weld | 8473 | Autour | 6 | 0 | Aucun
Weld | 8472 | Autour | 6 | 0 | Aucun
Weld | 8470 | Autour | 6 | 0 | Aucun
Weld | 8469 | Autour | 6 | 0 | Aucun
Weld | 8468 | Autour | 6 | 0 | Aucun
Weld | 8467 | Autour | 6 | 0 | Aucun
Weld | 8465 | Autour | 6 | 0 | Aucun
Weld | 8464 | Autour | 6 | 0 | Aucun
Weld | 8463 | Autour | 6 | 0 | Aucun
Weld | 8462 | Autour | 6 | 0 | Aucun
Weld | 8461 | Autour | 6 | 0 | Aucun
Weld | 8459 | Autour | 6 | 0 | Aucun
Weld | 8457 | Autour | 6 | 0 | Aucun
Weld | 8456 | Autour | 6 | 0 | Aucun
Weld | 8455 | Autour | 6 | 0 | Aucun
Weld | 8454 | Autour | 6 | 0 | Aucun
Weld | 8450 | Autour | 6 | 0 | Aucun
Weld | 8448 | Autour | 6 | 0 | Aucun
Weld | 8445 | Autour | 6 | 6 | Aucun
Weld | 8444 | Autour | 6 | 0 | Aucun
Weld | 8443 | Autour | 6 | 0 | Aucun
Weld | 8441 | Autour | 6 | 0 | Aucun
Weld | 8438 | Autour | 6 | 0 | Aucun
Weld | 8435 | Autour | 6 | 0 | Aucun
Weld | 8434 | Droit | 3 | 3 | W10
Weld | 8433 | Droit | 3 | 3 | W10
Weld | 8432 | Droit | 3 | 3 | W10
Weld | 8429 | Autour | 6 | 0 | Aucun
Weld | 8428 | Autour | 6 | 0 | Aucun
Weld | 8427 | Autour | 6 | 0 | Aucun
Weld | 8426 | Autour | 6 | 0 | Aucun
Weld | 8424 | Droit | 2 | 2 | W10
Weld | 8423 | Droit | 2 | 2 | W10
Weld | 8422 | Autour | 6 | 0 | Aucun
Weld | 8421 | Autour | 6 | 0 | Aucun
Weld | 8419 | Droit | 2 | 2 | W10
Weld | 8418 | Droit | 2 | 2 | W10
Weld | 8408 | Droit | 5 | 0 | Aucun
Weld | 8407 | Droit | 5 | 0 | Aucun
Weld | 8392 | Autour | 6 | 0 | Aucun
Weld | 8391 | Autour | 6 | 0 | Aucun
Weld | 8390 | Autour | 6 | 0 | Aucun
Weld | 8389 | Autour | 6 | 0 | Aucun
Weld | 8388 | Autour | 6 | 0 | Aucun
Weld | 8387 | Autour | 6 | 0 | Aucun
Weld | 8382 | Autour | 6 | 0 | Aucun
Weld | 8381 | Autour | 6 | 0 | Aucun
Weld | 8380 | Autour | 6 | 0 | Aucun
Weld | 8375 | Autour | 6 | 0 | Aucun
Weld | 8374 | Autour | 6 | 0 | Aucun
Weld | 8372 | Autour | 6 | 0 | Aucun
Weld | 8371 | Autour | 6 | 0 | Aucun
Weld | 8365 | Autour | 6 | 0 | Aucun
Weld | 8363 | Autour | 6 | 0 | Aucun
Weld | 8362 | Autour | 6 | 0 | Aucun
Weld | 8361 | Autour | 6 | 0 | Aucun
Weld | 8253 | Autour | 6 | 0 | Aucun
Weld | 8252 | Autour | 6 | 0 | Aucun
Weld | 8251 | Autour | 6 | 0 | Aucun
Weld | 8250 | Autour | 6 | 0 | Aucun
Weld | 8246 | Autour | 6 | 0 | Aucun
Weld | 8245 | Autour | 6 | 0 | Aucun
Weld | 8244 | Autour | 6 | 0 | Aucun
Weld | 8243 | Autour | 6 | 0 | Aucun
Weld | 8242 | Autour | 6 | 0 | Aucun
Weld | 8241 | Autour | 6 | 0 | Aucun
Weld | 8239 | Autour | 6 | 0 | Aucun
Weld | 8238 | Autour | 6 | 0 | Aucun
Weld | 8237 | Autour | 6 | 0 | Aucun
Weld | 8236 | Autour | 6 | 0 | Aucun
Weld | 8235 | Autour | 6 | 0 | Aucun
Weld | 8234 | Autour | 6 | 0 | Aucun
Weld | 8232 | Autour | 6 | 0 | Aucun
Weld | 8231 | Autour | 6 | 0 | Aucun
Weld | 8230 | Autour | 6 | 0 | Aucun
Weld | 8229 | Autour | 6 | 0 | Aucun
Weld | 8228 | Autour | 6 | 0 | Aucun
Weld | 8227 | Autour | 6 | 0 | Aucun
Weld | 8226 | Autour | 6 | 0 | Aucun
Weld | 8225 | Autour | 6 | 0 | Aucun
Weld | 8224 | Autour | 6 | 0 | Aucun
Weld | 8223 | Autour | 6 | 0 | Aucun
Weld | 8222 | Autour | 6 | 0 | Aucun
Weld | 8221 | Autour | 6 | 0 | Aucun
Weld | 8220 | Autour | 6 | 0 | Aucun
Weld | 8219 | Autour | 6 | 0 | Aucun
Weld | 8218 | Autour | 6 | 0 | Aucun
Weld | 8217 | Autour | 6 | 0 | Aucun
Weld | 8214 | Autour | 6 | 0 | Aucun
Weld | 8213 | Autour | 6 | 0 | Aucun
Weld | 8212 | Autour | 6 | 0 | Aucun
Weld | 8207 | Autour | 6 | 0 | Aucun
Weld | 8206 | Autour | 6 | 0 | Aucun
Weld | 8203 | Autour | 6 | 0 | Aucun
Weld | 8200 | Autour | 6 | 0 | Aucun
Weld | 8199 | Autour | 6 | 0 | Aucun
Weld | 8193 | Autour | 6 | 0 | Aucun
Weld | 8192 | Autour | 6 | 0 | Aucun
Weld | 8191 | Autour | 6 | 0 | Aucun
Weld | 8190 | Autour | 6 | 0 | Aucun
Weld | 8189 | Autour | 6 | 0 | Aucun
Weld | 8188 | Autour | 6 | 0 | Aucun
Weld | 8187 | Autour | 6 | 0 | Aucun
Weld | 8186 | Autour | 6 | 0 | Aucun
Weld | 8184 | Autour | 6 | 0 | Aucun
Weld | 8183 | Autour | 6 | 0 | Aucun
Weld | 8182 | Autour | 6 | 0 | Aucun
Weld | 8181 | Autour | 6 | 0 | Aucun
Weld | 8180 | Autour | 6 | 0 | Aucun
Weld | 8179 | Autour | 6 | 0 | Aucun
Weld | 8171 | Autour | 6 | 0 | Aucun
Weld | 8166 | Autour | 6 | 0 | Aucun
Weld | 8165 | Autour | 6 | 0 | Aucun
Weld | 8164 | Autour | 6 | 0 | Aucun
Weld | 8162 | Autour | 6 | 0 | Aucun
Weld | 8161 | Autour | 6 | 0 | Aucun
Weld | 8040 | Autour | 6 | 0 | Aucun
Weld | 8038 | Autour | 6 | 0 | Aucun
Weld | 8035 | Droit | 5 | 0 | Aucun
Weld | 8034 | Droit | 5 | 0 | Aucun
Weld | 8033 | Droit | 5 | 0 | Aucun
Weld | 8016 | Autour | 6 | 0 | Aucun
Weld | 8003 | Autour | 6 | 0 | Aucun
Weld | 8002 | Autour | 6 | 0 | Aucun
Weld | 8000 | Autour | 6 | 0 | Aucun
Weld | 7999 | Autour | 6 | 0 | Aucun
Weld | 7998 | Autour | 6 | 0 | Aucun
Weld | 7997 | Autour | 6 | 0 | Aucun
Weld | 7996 | Autour | 6 | 0 | Aucun
Weld | 7995 | Autour | 6 | 0 | Aucun
Weld | 7994 | Autour | 6 | 0 | Aucun
Weld | 7993 | Autour | 6 | 0 | Aucun
Weld | 7992 | Autour | 6 | 0 | Aucun
Weld | 7991 | Autour | 6 | 0 | Aucun
Weld | 7990 | Autour | 6 | 0 | Aucun
Weld | 7989 | Autour | 6 | 0 | Aucun
Weld | 7988 | Autour | 6 | 0 | Aucun
Weld | 7987 | Autour | 6 | 0 | Aucun
Weld | 7986 | Autour | 6 | 0 | Aucun
Weld | 7985 | Autour | 6 | 0 | Aucun
Weld | 7984 | Autour | 6 | 0 | Aucun
Weld | 7983 | Autour | 6 | 0 | Aucun
Weld | 7982 | Autour | 6 | 0 | Aucun
Weld | 7981 | Autour | 6 | 0 | Aucun
Weld | 7980 | Autour | 6 | 0 | Aucun
Weld | 7979 | Autour | 6 | 0 | Aucun
Weld | 7978 | Autour | 6 | 0 | Aucun
Weld | 7976 | Droit | 2 | 2 | W10
Weld | 7975 | Droit | 2 | 2 | W10
Weld | 7974 | Autour | 6 | 0 | Aucun
Weld | 7973 | Autour | 6 | 0 | Aucun
Weld | 7971 | Droit | 2 | 2 | W10
Weld | 7970 | Droit | 2 | 2 | W10
Weld | 7969 | Autour | 6 | 0 | Aucun
Weld | 7968 | Autour | 6 | 0 | Aucun
Weld | 7967 | Autour | 6 | 0 | Aucun
Weld | 7966 | Autour | 6 | 0 | Aucun
Weld | 7965 | Autour | 6 | 0 | Aucun
Weld | 7964 | Autour | 6 | 0 | Aucun
Weld | 7963 | Autour | 6 | 0 | Aucun
Weld | 7962 | Autour | 6 | 0 | Aucun
Weld | 7961 | Autour | 6 | 0 | Aucun
Weld | 7960 | Autour | 6 | 0 | Aucun
Weld | 7959 | Autour | 6 | 0 | Aucun
Weld | 7958 | Autour | 6 | 0 | Aucun
Weld | 7957 | Autour | 6 | 0 | Aucun
Weld | 7956 | Autour | 6 | 0 | Aucun
Weld | 7955 | Autour | 6 | 0 | Aucun
Weld | 7954 | Autour | 6 | 0 | Aucun
Weld | 7953 | Autour | 6 | 0 | Aucun
Weld | 7952 | Autour | 6 | 0 | Aucun
Weld | 7951 | Autour | 6 | 0 | Aucun
Weld | 7950 | Autour | 6 | 0 | Aucun
Weld | 7949 | Autour | 6 | 0 | Aucun
Weld | 7948 | Autour | 6 | 0 | Aucun
Weld | 7947 | Autour | 6 | 0 | Aucun
Weld | 7946 | Autour | 6 | 0 | Aucun
Weld | 7945 | Autour | 6 | 0 | Aucun
Weld | 7944 | Autour | 6 | 0 | Aucun
Weld | 7943 | Autour | 6 | 0 | Aucun
Weld | 7942 | Autour | 6 | 0 | Aucun
Weld | 7939 | Droit | 2 | 2 | W10
Weld | 7938 | Droit | 2 | 2 | W10
Weld | 7937 | Autour | 6 | 0 | Aucun
Weld | 7936 | Autour | 6 | 0 | Aucun
Weld | 7935 | Autour | 6 | 0 | Aucun
Weld | 7934 | Autour | 6 | 0 | Aucun
Weld | 7933 | Autour | 6 | 0 | Aucun
Weld | 7931 | Droit | 2 | 2 | W10
Weld | 7930 | Droit | 2 | 2 | W10
Weld | 7929 | Autour | 6 | 0 | Aucun
Weld | 7918 | Autour | 6 | 0 | Aucun
Weld | 7917 | Autour | 6 | 0 | Aucun
Weld | 7916 | Autour | 6 | 0 | Aucun
Weld | 7915 | Autour | 6 | 0 | Aucun
Weld | 7914 | Autour | 6 | 0 | Aucun
Weld | 7913 | Autour | 6 | 0 | Aucun
Weld | 7912 | Autour | 6 | 0 | Aucun
Weld | 7911 | Autour | 6 | 0 | Aucun
Weld | 7910 | Autour | 6 | 0 | Aucun
Weld | 7909 | Autour | 6 | 0 | Aucun
Weld | 7908 | Autour | 6 | 0 | Aucun
Weld | 7907 | Autour | 6 | 0 | Aucun
Weld | 7906 | Autour | 6 | 0 | Aucun
Weld | 7905 | Autour | 6 | 0 | Aucun
Weld | 7904 | Autour | 6 | 0 | Aucun
Weld | 7903 | Autour | 6 | 0 | Aucun
Weld | 7902 | Autour | 6 | 0 | Aucun
Weld | 7901 | Autour | 6 | 0 | Aucun
Weld | 7897 | Autour | 6 | 0 | Aucun
Weld | 7896 | Autour | 6 | 0 | Aucun
Weld | 7895 | Autour | 6 | 0 | Aucun
Weld | 7894 | Autour | 6 | 0 | Aucun
Weld | 7887 | Autour | 6 | 0 | Aucun
Weld | 7875 | Autour | 6 | 0 | Aucun
Weld | 7874 | Autour | 6 | 0 | Aucun
Weld | 7873 | Autour | 6 | 0 | Aucun
Weld | 7852 | Autour | 6 | 0 | Aucun
Weld | 7851 | Autour | 6 | 0 | Aucun
Weld | 7850 | Autour | 6 | 0 | Aucun
Weld | 7849 | Autour | 6 | 0 | Aucun
Weld | 7848 | Autour | 6 | 0 | Aucun
Weld | 7847 | Autour | 6 | 0 | Aucun
Weld | 7846 | Autour | 6 | 0 | Aucun
Weld | 7845 | Autour | 6 | 0 | Aucun
Weld | 7844 | Autour | 6 | 0 | Aucun
Weld | 7843 | Autour | 6 | 0 | Aucun
Weld | 7842 | Autour | 6 | 0 | Aucun
Weld | 7841 | Autour | 6 | 0 | Aucun
Weld | 7840 | Autour | 6 | 0 | Aucun
Weld | 7839 | Autour | 6 | 0 | Aucun
Weld | 7838 | Autour | 6 | 0 | Aucun
Weld | 7837 | Autour | 6 | 0 | Aucun
Weld | 7836 | Autour | 6 | 0 | Aucun
Weld | 7835 | Autour | 6 | 0 | Aucun
Weld | 7834 | Autour | 6 | 0 | Aucun
Weld | 7833 | Autour | 6 | 0 | Aucun
Weld | 7821 | Autour | 6 | 0 | Aucun
Weld | 7819 | Autour | 6 | 0 | Aucun
Weld | 7816 | Autour | 6 | 0 | Aucun
Weld | 7814 | Autour | 6 | 0 | Aucun
Weld | 7810 | Autour | 6 | 0 | Aucun
Weld | 7809 | Autour | 6 | 0 | Aucun
Weld | 7808 | Autour | 6 | 0 | Aucun
Weld | 7807 | Autour | 6 | 0 | Aucun
Weld | 7806 | Autour | 6 | 0 | Aucun
Weld | 7805 | Autour | 6 | 0 | Aucun
Weld | 7804 | Autour | 6 | 0 | Aucun
Weld | 7803 | Autour | 6 | 0 | Aucun
Weld | 7802 | Autour | 6 | 0 | Aucun
Weld | 7801 | Autour | 6 | 0 | Aucun
Weld | 7798 | Autour | 6 | 0 | Aucun
Weld | 7797 | Autour | 6 | 0 | Aucun
Weld | 7796 | Autour | 6 | 0 | Aucun
Weld | 7791 | Autour | 6 | 0 | Aucun
Weld | 7790 | Autour | 6 | 0 | Aucun
Weld | 7789 | Autour | 6 | 0 | Aucun
Weld | 7787 | Autour | 6 | 0 | Aucun
Weld | 7785 | Autour | 6 | 0 | Aucun
Weld | 7783 | Autour | 6 | 0 | Aucun
Weld | 7779 | Autour | 6 | 0 | Aucun
Weld | 7768 | Autour | 6 | 0 | Aucun
Weld | 7767 | Autour | 6 | 0 | Aucun
Weld | 7751 | Autour | 6 | 0 | Aucun
Weld | 7749 | Autour | 6 | 0 | Aucun
Weld | 7744 | Autour | 6 | 0 | Aucun
Weld | 7743 | Autour | 6 | 0 | Aucun
Weld | 7742 | Autour | 6 | 0 | Aucun
Weld | 7741 | Autour | 6 | 0 | Aucun
Weld | 7740 | Autour | 6 | 0 | Aucun
Weld | 7730 | Autour | 6 | 0 | Aucun
Weld | 7728 | Autour | 6 | 0 | Aucun
Weld | 7727 | Autour | 6 | 0 | Aucun
Weld | 7726 | Autour | 6 | 0 | Aucun
Weld | 7720 | Autour | 6 | 0 | Aucun
Weld | 7719 | Autour | 6 | 0 | Aucun
Weld | 7718 | Autour | 6 | 0 | Aucun
Weld | 7717 | Autour | 6 | 0 | Aucun
Weld | 7716 | Autour | 6 | 0 | Aucun
Weld | 7682 | Autour | 6 | 0 | Aucun
Weld | 7681 | Autour | 6 | 0 | Aucun
Weld | 7680 | Autour | 6 | 0 | Aucun
Weld | 7679 | Autour | 6 | 0 | Aucun
Weld | 7678 | Autour | 6 | 0 | Aucun
Weld | 7677 | Autour | 6 | 0 | Aucun
Weld | 7676 | Autour | 6 | 0 | Aucun
Weld | 7675 | Autour | 6 | 0 | Aucun
Weld | 7660 | Autour | 6 | 0 | Aucun
Weld | 7659 | Autour | 6 | 0 | Aucun
Weld | 7657 | Autour | 6 | 0 | Aucun
Weld | 7656 | Autour | 6 | 0 | Aucun
Weld | 7655 | Autour | 6 | 0 | Aucun
Weld | 7654 | Autour | 6 | 0 | Aucun
Weld | 7653 | Autour | 6 | 0 | Aucun
Weld | 7652 | Autour | 6 | 0 | Aucun
Weld | 7650 | Autour | 6 | 0 | Aucun
Weld | 7649 | Autour | 6 | 0 | Aucun
Weld | 7648 | Autour | 6 | 0 | Aucun
Weld | 7647 | Autour | 6 | 0 | Aucun
Weld | 7646 | Autour | 6 | 0 | Aucun
Weld | 7645 | Autour | 6 | 0 | Aucun
Weld | 7644 | Autour | 6 | 0 | Aucun
Weld | 7643 | Autour | 6 | 0 | Aucun
Weld | 7642 | Autour | 6 | 0 | Aucun
Weld | 7641 | Autour | 6 | 0 | Aucun
Weld | 7639 | Autour | 6 | 0 | Aucun
Weld | 7638 | Autour | 6 | 0 | Aucun
Weld | 7637 | Autour | 6 | 0 | Aucun
Weld | 7636 | Autour | 6 | 0 | Aucun
Weld | 7635 | Autour | 6 | 0 | Aucun
Weld | 7634 | Autour | 6 | 0 | Aucun
Weld | 7631 | Autour | 6 | 0 | Aucun
Weld | 7630 | Autour | 6 | 0 | Aucun
Weld | 7629 | Autour | 6 | 0 | Aucun
Weld | 7628 | Autour | 6 | 0 | Aucun
Weld | 7627 | Autour | 6 | 0 | Aucun
Weld | 7623 | Autour | 6 | 0 | Aucun
Weld | 7621 | Autour | 6 | 0 | Aucun
Weld | 7613 | Autour | 6 | 0 | Aucun
Weld | 7611 | Autour | 6 | 0 | Aucun
Weld | 7610 | Autour | 6 | 0 | Aucun
Weld | 7608 | Autour | 6 | 0 | Aucun
Weld | 7606 | Autour | 6 | 0 | Aucun
Weld | 7604 | Autour | 6 | 0 | Aucun
Weld | 7602 | Autour | 6 | 0 | Aucun
Weld | 7601 | Autour | 6 | 0 | Aucun
Weld | 7600 | Autour | 6 | 0 | Aucun
Weld | 7568 | Autour | 6 | 0 | Aucun
Weld | 7567 | Autour | 6 | 0 | Aucun
Weld | 7566 | Autour | 6 | 0 | Aucun
Weld | 7565 | Autour | 6 | 0 | Aucun
Weld | 7564 | Autour | 6 | 0 | Aucun
Weld | 7563 | Autour | 6 | 0 | Aucun
Weld | 7562 | Autour | 6 | 0 | Aucun
Weld | 7561 | Autour | 6 | 0 | Aucun
Weld | 7560 | Autour | 6 | 0 | Aucun
Weld | 7559 | Autour | 6 | 0 | Aucun
Weld | 7557 | Autour | 6 | 0 | Aucun
Weld | 7556 | Autour | 6 | 0 | Aucun
Weld | 7555 | Autour | 6 | 0 | Aucun
Weld | 7554 | Autour | 6 | 0 | Aucun
Weld | 7553 | Autour | 6 | 0 | Aucun
Weld | 7552 | Autour | 6 | 0 | Aucun
Weld | 7551 | Autour | 6 | 0 | Aucun
Weld | 7550 | Autour | 6 | 0 | Aucun
Weld | 7549 | Autour | 6 | 0 | Aucun
Weld | 7548 | Autour | 6 | 0 | Aucun
Weld | 7547 | Autour | 6 | 0 | Aucun
Weld | 7546 | Autour | 6 | 0 | Aucun
Weld | 7545 | Autour | 6 | 0 | Aucun
Weld | 7544 | Autour | 6 | 0 | Aucun
Weld | 7543 | Autour | 6 | 0 | Aucun
Weld | 7542 | Autour | 6 | 0 | Aucun
Weld | 7541 | Autour | 6 | 0 | Aucun
Weld | 7540 | Autour | 6 | 0 | Aucun
Weld | 7539 | Autour | 6 | 0 | Aucun
Weld | 7538 | Autour | 6 | 0 | Aucun
Weld | 7537 | Autour | 6 | 0 | Aucun
Weld | 7536 | Autour | 6 | 0 | Aucun
Weld | 7535 | Autour | 6 | 0 | Aucun
Weld | 7534 | Autour | 6 | 0 | Aucun
Weld | 7533 | Autour | 6 | 0 | Aucun
Weld | 7532 | Autour | 6 | 0 | Aucun
Weld | 7531 | Autour | 6 | 0 | Aucun
Weld | 7530 | Autour | 6 | 0 | Aucun
Weld | 7529 | Autour | 6 | 0 | Aucun
Weld | 7528 | Autour | 6 | 0 | Aucun
Weld | 7527 | Autour | 6 | 0 | Aucun
Weld | 7526 | Autour | 6 | 0 | Aucun
Weld | 7524 | Autour | 6 | 0 | Aucun
Weld | 7523 | Autour | 6 | 0 | Aucun
Weld | 7522 | Autour | 6 | 0 | Aucun
Weld | 7521 | Autour | 6 | 0 | Aucun
Weld | 7519 | Autour | 6 | 0 | Aucun
Weld | 7518 | Autour | 6 | 0 | Aucun
Weld | 7517 | Autour | 6 | 0 | Aucun
Weld | 7516 | Autour | 6 | 0 | Aucun
Weld | 7515 | Autour | 6 | 0 | Aucun
Weld | 7513 | Autour | 6 | 0 | Aucun
Weld | 7512 | Autour | 6 | 0 | Aucun
Weld | 7511 | Autour | 6 | 0 | Aucun
Weld | 7509 | Autour | 6 | 0 | Aucun
Weld | 7508 | Autour | 6 | 0 | Aucun
Weld | 7507 | Autour | 6 | 0 | Aucun
Weld | 7505 | Autour | 6 | 0 | Aucun
Weld | 7504 | Autour | 6 | 0 | Aucun
Weld | 7503 | Autour | 6 | 0 | Aucun
Weld | 7501 | Autour | 6 | 0 | Aucun
Weld | 7500 | Autour | 6 | 0 | Aucun
Weld | 7499 | Autour | 6 | 0 | Aucun
Weld | 7498 | Autour | 6 | 0 | Aucun
Weld | 7497 | Autour | 6 | 0 | Aucun
Weld | 7496 | Autour | 6 | 0 | Aucun
Weld | 7495 | Autour | 6 | 0 | Aucun
Weld | 7494 | Autour | 6 | 0 | Aucun
Weld | 7493 | Autour | 6 | 0 | Aucun
Weld | 7492 | Autour | 6 | 0 | Aucun
Weld | 7491 | Autour | 6 | 0 | Aucun
Weld | 7490 | Autour | 6 | 0 | Aucun
Weld | 7489 | Autour | 6 | 0 | Aucun
Weld | 7488 | Autour | 6 | 0 | Aucun
Weld | 7487 | Autour | 6 | 0 | Aucun
Weld | 7486 | Autour | 6 | 0 | Aucun
Weld | 7485 | Autour | 6 | 0 | Aucun
Weld | 7484 | Autour | 6 | 0 | Aucun
Weld | 7483 | Autour | 6 | 0 | Aucun
Weld | 7482 | Autour | 6 | 0 | Aucun
Weld | 7481 | Autour | 6 | 0 | Aucun
Weld | 7480 | Autour | 6 | 0 | Aucun
Weld | 7479 | Autour | 6 | 0 | Aucun
Weld | 7478 | Autour | 6 | 0 | Aucun
Weld | 7477 | Autour | 6 | 0 | Aucun
Weld | 7474 | Autour | 6 | 0 | Aucun
Weld | 7473 | Autour | 6 | 0 | Aucun
Weld | 7472 | Autour | 6 | 0 | Aucun
Weld | 7471 | Autour | 6 | 0 | Aucun
Weld | 7470 | Autour | 6 | 0 | Aucun
Weld | 7469 | Autour | 6 | 0 | Aucun
Weld | 7468 | Autour | 6 | 0 | Aucun
Weld | 7467 | Autour | 6 | 0 | Aucun
Weld | 7466 | Autour | 6 | 0 | Aucun
Weld | 7465 | Autour | 6 | 0 | Aucun
Weld | 7464 | Autour | 6 | 0 | Aucun
Weld | 7463 | Autour | 6 | 0 | Aucun
Weld | 7461 | Autour | 6 | 0 | Aucun
Weld | 7460 | Autour | 6 | 0 | Aucun
Weld | 7459 | Autour | 6 | 0 | Aucun
Weld | 7458 | Autour | 6 | 0 | Aucun
Weld | 7456 | Autour | 6 | 0 | Aucun
Weld | 7455 | Autour | 6 | 0 | Aucun
Weld | 7454 | Autour | 6 | 0 | Aucun
Weld | 7452 | Autour | 6 | 0 | Aucun
Weld | 7451 | Autour | 6 | 0 | Aucun
Weld | 7428 | Autour | 6 | 0 | Aucun
Weld | 7427 | Autour | 6 | 0 | Aucun
Weld | 7423 | Autour | 6 | 0 | Aucun
Weld | 7421 | Autour | 6 | 0 | Aucun
Weld | 7420 | Droit | 5 | 0 | Aucun
Weld | 7416 | Autour | 6 | 0 | Aucun
Weld | 7413 | Autour | 6 | 0 | Aucun
Weld | 7412 | Autour | 6 | 0 | Aucun
Weld | 7409 | Autour | 6 | 0 | Aucun
Weld | 7326 | Autour | 6 | 0 | Aucun
Weld | 7325 | Autour | 6 | 0 | Aucun
Weld | 7321 | Droit | 3 | 3 | W10
Weld | 7320 | Droit | 3 | 3 | W10
Weld | 7319 | Droit | 3 | 3 | W10
Weld | 7318 | Droit | 3 | 3 | W10
Weld | 7317 | Droit | 3 | 3 | W10
Weld | 7316 | Droit | 3 | 3 | W10
Weld | 7315 | Droit | 3 | 3 | W10
Weld | 7314 | Droit | 3 | 3 | W10
Weld | 7313 | Droit | 3 | 3 | W10
Weld | 7311 | Droit | 2 | 2 | W10
Weld | 7310 | Droit | 2 | 2 | W10
Weld | 7308 | Droit | 3 | 3 | W10
Weld | 7307 | Droit | 3 | 3 | W10
Weld | 7306 | Droit | 3 | 3 | W10
Weld | 7291 | Autour | 6 | 0 | Aucun
Weld | 7290 | Droit | 5 | 5 | W10
Weld | 7289 | Droit | 5 | 5 | W10
Weld | 7288 | Droit | 5 | 5 | W10
Weld | 7287 | Droit | 5 | 5 | W10
Weld | 7286 | Droit | 5 | 5 | W10
Weld | 7285 | Droit | 5 | 5 | W10
Weld | 7284 | Autour | 6 | 0 | Aucun
Weld | 7283 | Autour | 6 | 0 | Aucun
Weld | 7281 | Autour | 6 | 0 | Aucun
Weld | 7280 | Autour | 6 | 0 | Aucun
Weld | 7279 | Autour | 6 | 0 | Aucun
Weld | 7278 | Autour | 6 | 0 | Aucun
Weld | 7277 | Autour | 6 | 0 | Aucun
Weld | 7276 | Autour | 6 | 0 | Aucun
Weld | 7263 | Droit | 5 | 5 | W10
Weld | 7262 | Droit | 5 | 5 | W10
Weld | 7261 | Droit | 5 | 5 | W10
Weld | 7240 | Droit | 4 | 4 | W10
Weld | 7239 | Droit | 5 | 5 | W10
Weld | 7238 | Droit | 5 | 5 | W10
Weld | 7233 | Droit | 4 | 4 | W10
Weld | 7232 | Droit | 5 | 5 | W10
Weld | 7231 | Droit | 5 | 5 | W10
Weld | 7230 | Droit | 4 | 4 | W10
Weld | 7229 | Droit | 5 | 5 | W10
Weld | 7228 | Droit | 5 | 5 | W10
Weld | 7219 | Droit | 4 | 4 | W10
Weld | 7218 | Droit | 5 | 5 | W10
Weld | 7217 | Droit | 5 | 5 | W10
Weld | 7216 | Droit | 4 | 4 | W10
Weld | 7215 | Droit | 5 | 5 | W10
Weld | 7214 | Droit | 5 | 5 | W10
Weld | 7213 | Droit | 4 | 4 | W10
Weld | 7212 | Droit | 5 | 5 | W10
Weld | 7211 | Droit | 5 | 5 | W10
Weld | 7206 | Droit | 4 | 4 | W10
Weld | 7205 | Droit | 5 | 5 | W10
Weld | 7204 | Droit | 5 | 5 | W10
Weld | 7202 | Autour | 6 | 0 | Aucun
Weld | 7201 | Autour | 6 | 0 | Aucun
Weld | 7200 | Autour | 6 | 0 | Aucun
Weld | 7199 | Autour | 6 | 0 | Aucun
Weld | 7198 | Autour | 6 | 0 | Aucun
Weld | 7197 | Autour | 6 | 0 | Aucun
Weld | 7196 | Autour | 6 | 0 | Aucun
Weld | 7195 | Autour | 6 | 0 | Aucun
Weld | 7194 | Autour | 6 | 0 | Aucun
Weld | 7193 | Autour | 6 | 0 | Aucun
Weld | 7192 | Autour | 6 | 0 | Aucun
Weld | 7190 | Autour | 6 | 0 | Aucun
Weld | 7189 | Autour | 6 | 0 | Aucun
Weld | 7187 | Autour | 6 | 0 | Aucun
Weld | 7186 | Autour | 6 | 0 | Aucun
Weld | 7182 | Autour | 6 | 0 | Aucun
Weld | 7181 | Autour | 6 | 0 | Aucun
Weld | 7179 | Autour | 6 | 0 | Aucun
Weld | 7178 | Autour | 6 | 0 | Aucun
Weld | 7173 | Autour | 6 | 0 | Aucun
Weld | 7172 | Autour | 6 | 0 | Aucun
Weld | 7171 | Autour | 6 | 0 | Aucun
Weld | 7170 | Autour | 6 | 0 | Aucun
Weld | 7169 | Autour | 6 | 0 | Aucun
Weld | 7167 | Autour | 6 | 0 | Aucun
Weld | 7166 | Autour | 6 | 0 | Aucun
Weld | 7162 | Autour | 6 | 0 | Aucun
Weld | 7081 | Autour | 6 | 0 | Aucun
Weld | 7080 | Autour | 6 | 0 | Aucun
Weld | 7079 | Autour | 6 | 0 | Aucun
Weld | 7078 | Autour | 6 | 0 | Aucun
Weld | 7077 | Autour | 6 | 0 | Aucun
Weld | 7076 | Autour | 6 | 0 | Aucun
Weld | 7074 | Droit | 4 | 4 | W10
Weld | 7073 | Droit | 4 | 4 | W10
Weld | 7072 | Droit | 5 | 5 | W10
Weld | 7071 | Droit | 5 | 5 | W10
Weld | 7070 | Droit | 4 | 4 | W10
Weld | 7069 | Droit | 4 | 4 | W10
Weld | 7067 | Droit | 4 | 4 | W10
Weld | 7066 | Droit | 4 | 4 | W10
Weld | 7065 | Droit | 5 | 5 | W10
Weld | 7063 | Droit | 5 | 5 | W10
Weld | 7062 | Droit | 4 | 4 | W10
Weld | 7061 | Droit | 4 | 4 | W10
Weld | 7060 | Droit | 4 | 4 | W10
Weld | 7059 | Droit | 4 | 4 | W10
Weld | 7058 | Droit | 5 | 5 | W10
Weld | 7056 | Droit | 4 | 4 | W10
Weld | 7055 | Droit | 4 | 4 | W10
Weld | 7054 | Droit | 5 | 5 | W10
Weld | 7050 | Droit | 5 | 5 | W10
Weld | 7049 | Droit | 4 | 4 | W10
Weld | 7048 | Droit | 4 | 4 | W10
Weld | 7047 | Droit | 5 | 5 | W10
Weld | 7046 | Droit | 4 | 4 | W10
Weld | 7045 | Droit | 4 | 4 | W10
Weld | 7044 | Droit | 4 | 4 | W10
Weld | 7043 | Droit | 4 | 4 | W10
Weld | 7042 | Droit | 5 | 5 | W10
Weld | 7038 | Droit | 5 | 5 | W10
Weld | 7037 | Droit | 4 | 4 | W10
Weld | 7036 | Droit | 4 | 4 | W10
Weld | 7035 | Droit | 5 | 5 | W10
Weld | 7034 | Droit | 4 | 4 | W10
Weld | 7033 | Droit | 4 | 4 | W10
Weld | 7032 | Droit | 4 | 4 | W10
Weld | 7031 | Droit | 4 | 4 | W10
Weld | 7030 | Droit | 5 | 5 | W10
Weld | 7029 | Droit | 4 | 4 | W10
Weld | 7028 | Droit | 4 | 4 | W10
Weld | 7027 | Droit | 5 | 5 | W10
Weld | 7026 | Droit | 5 | 5 | W10
Weld | 7025 | Droit | 4 | 4 | W10
Weld | 7024 | Droit | 4 | 4 | W10
Weld | 7006 | Autour | 6 | 0 | Aucun
Weld | 7005 | Autour | 6 | 0 | Aucun
Weld | 7004 | Autour | 6 | 0 | Aucun
Weld | 6968 | Autour | 6 | 0 | Aucun
Weld | 6965 | Droit | 3 | 3 | W10
Weld | 6964 | Droit | 3 | 3 | W10
Weld | 6963 | Droit | 3 | 3 | W10
Weld | 6960 | Autour | 6 | 0 | Aucun
Weld | 6957 | Autour | 6 | 0 | Aucun
Weld | 6942 | Autour | 6 | 0 | Aucun
Weld | 6941 | Autour | 6 | 0 | Aucun
Weld | 6940 | Autour | 6 | 0 | Aucun
Weld | 6939 | Autour | 6 | 0 | Aucun
Weld | 6936 | Autour | 6 | 0 | Aucun
Weld | 6935 | Autour | 6 | 0 | Aucun
Weld | 6934 | Autour | 6 | 0 | Aucun
Weld | 6933 | Autour | 6 | 0 | Aucun
Weld | 6932 | Autour | 6 | 0 | Aucun
Weld | 6931 | Autour | 6 | 0 | Aucun
Weld | 6930 | Autour | 6 | 0 | Aucun
Weld | 6918 | Droit | 3 | 3 | W10
Weld | 6917 | Droit | 3 | 3 | W10
Weld | 6916 | Droit | 3 | 3 | W10
Weld | 6914 | Droit | 3 | 3 | W10
Weld | 6913 | Droit | 3 | 3 | W10
Weld | 6912 | Droit | 3 | 3 | W10
Weld | 6899 | Autour | 6 | 0 | Aucun
Weld | 6898 | Autour | 6 | 0 | Aucun
Weld | 6896 | Autour | 6 | 0 | Aucun
Weld | 6895 | Autour | 6 | 0 | Aucun
Weld | 6894 | Autour | 6 | 0 | Aucun
Weld | 6893 | Autour | 6 | 0 | Aucun
Weld | 6892 | Autour | 6 | 0 | Aucun
Weld | 6891 | Autour | 6 | 0 | Aucun
Weld | 6890 | Autour | 6 | 0 | Aucun
Weld | 6889 | Autour | 6 | 0 | Aucun
Weld | 6888 | Autour | 6 | 0 | Aucun
Weld | 6887 | Autour | 6 | 0 | Aucun
Weld | 6886 | Autour | 6 | 0 | Aucun
Weld | 6885 | Autour | 6 | 0 | Aucun
Weld | 6881 | Autour | 6 | 0 | Aucun
Weld | 6880 | Autour | 6 | 0 | Aucun
Weld | 6877 | Autour | 6 | 0 | Aucun
Weld | 6876 | Autour | 6 | 0 | Aucun
Weld | 6874 | Autour | 6 | 0 | Aucun
Weld | 6870 | Autour | 6 | 0 | Aucun
Weld | 6869 | Autour | 6 | 0 | Aucun
Weld | 6863 | Autour | 6 | 0 | Aucun
Weld | 6859 | Autour | 6 | 0 | Aucun
Weld | 6856 | Autour | 6 | 0 | Aucun
Weld | 6853 | Autour | 6 | 0 | Aucun
Weld | 6811 | Autour | 6 | 0 | Aucun
Weld | 6798 | Autour | 6 | 0 | Aucun
Weld | 6797 | Autour | 6 | 0 | Aucun
Weld | 6795 | Autour | 6 | 0 | Aucun
Weld | 6794 | Autour | 6 | 0 | Aucun
Weld | 6793 | Autour | 6 | 0 | Aucun
Weld | 6792 | Autour | 6 | 0 | Aucun
Weld | 6791 | Autour | 6 | 0 | Aucun
Weld | 6789 | Droit | 2 | 2 | W10
Weld | 6788 | Droit | 2 | 2 | W10
Weld | 6786 | Droit | 2 | 2 | W10
Weld | 6785 | Droit | 2 | 2 | W10
Weld | 6784 | Autour | 6 | 0 | Aucun
Weld | 6783 | Autour | 6 | 0 | Aucun
Weld | 6782 | Autour | 6 | 0 | Aucun
Weld | 6781 | Autour | 6 | 0 | Aucun
Weld | 6780 | Autour | 6 | 0 | Aucun
Weld | 6779 | Autour | 6 | 0 | Aucun
Weld | 6778 | Autour | 6 | 0 | Aucun
Weld | 6776 | Droit | 2 | 2 | W10
Weld | 6775 | Droit | 2 | 2 | W10
Weld | 6774 | Autour | 6 | 0 | Aucun
Weld | 6772 | Droit | 2 | 2 | W10
Weld | 6771 | Droit | 2 | 2 | W10
Weld | 6770 | Autour | 6 | 0 | Aucun
Weld | 6768 | Droit | 2 | 2 | W10
Weld | 6767 | Droit | 2 | 2 | W10
Weld | 6766 | Autour | 6 | 0 | Aucun
Weld | 6764 | Droit | 2 | 2 | W10
Weld | 6763 | Droit | 2 | 2 | W10
Weld | 6761 | Droit | 2 | 2 | W10
Weld | 6760 | Droit | 2 | 2 | W10
Weld | 6759 | Autour | 6 | 0 | Aucun
Weld | 6758 | Autour | 6 | 0 | Aucun
Weld | 6757 | Autour | 6 | 0 | Aucun
Weld | 6756 | Autour | 6 | 0 | Aucun
Weld | 6755 | Autour | 6 | 0 | Aucun
Weld | 6753 | Droit | 2 | 2 | W10
Weld | 6752 | Droit | 2 | 2 | W10
Weld | 6751 | Autour | 6 | 0 | Aucun
Weld | 6750 | Autour | 6 | 0 | Aucun
Weld | 6749 | Autour | 6 | 0 | Aucun
Weld | 6748 | Autour | 6 | 0 | Aucun
Weld | 6747 | Autour | 6 | 0 | Aucun
Weld | 6746 | Autour | 6 | 0 | Aucun
Weld | 6745 | Autour | 6 | 0 | Aucun
Weld | 6744 | Autour | 6 | 0 | Aucun
Weld | 6743 | Autour | 6 | 0 | Aucun
Weld | 6742 | Autour | 6 | 0 | Aucun
Weld | 6740 | Autour | 6 | 0 | Aucun
Weld | 6739 | Autour | 6 | 0 | Aucun
Weld | 6738 | Autour | 6 | 0 | Aucun
Weld | 6737 | Autour | 6 | 0 | Aucun
Weld | 6736 | Autour | 6 | 0 | Aucun
Weld | 6735 | Autour | 6 | 0 | Aucun
Weld | 6734 | Autour | 6 | 0 | Aucun
Weld | 6733 | Autour | 6 | 0 | Aucun
Weld | 6732 | Autour | 6 | 0 | Aucun
Weld | 6731 | Autour | 6 | 0 | Aucun
Weld | 6730 | Autour | 6 | 0 | Aucun
Weld | 6729 | Autour | 6 | 0 | Aucun
Weld | 6715 | Autour | 6 | 0 | Aucun
Weld | 6714 | Autour | 6 | 0 | Aucun
Weld | 6710 | Autour | 6 | 0 | Aucun
Weld | 6709 | Autour | 6 | 0 | Aucun
Weld | 6708 | Autour | 6 | 0 | Aucun
Weld | 6707 | Autour | 6 | 0 | Aucun
Weld | 6706 | Autour | 6 | 0 | Aucun
Weld | 6704 | Autour | 6 | 0 | Aucun
Weld | 6703 | Autour | 6 | 0 | Aucun
Weld | 6702 | Autour | 6 | 0 | Aucun
Weld | 6701 | Autour | 6 | 0 | Aucun
Weld | 6700 | Autour | 6 | 0 | Aucun
Weld | 6699 | Autour | 6 | 0 | Aucun
Weld | 6698 | Autour | 6 | 0 | Aucun
Weld | 6697 | Autour | 6 | 0 | Aucun
Weld | 6696 | Autour | 6 | 0 | Aucun
Weld | 6691 | Autour | 6 | 0 | Aucun
Weld | 6690 | Autour | 6 | 0 | Aucun
Weld | 6689 | Autour | 6 | 0 | Aucun
Weld | 6679 | Droit | 2 | 2 | W10
Weld | 6678 | Droit | 2 | 2 | W10
Weld | 6676 | Droit | 2 | 2 | W10
Weld | 6675 | Droit | 2 | 2 | W10
Weld | 6673 | Droit | 2 | 2 | W10
Weld | 6672 | Droit | 2 | 2 | W10
Weld | 6670 | Droit | 2 | 2 | W10
Weld | 6669 | Droit | 2 | 2 | W10
Weld | 6667 | Droit | 2 | 2 | W10
Weld | 6666 | Droit | 2 | 2 | W10
Weld | 6664 | Droit | 2 | 2 | W10
Weld | 6663 | Droit | 2 | 2 | W10
Weld | 6661 | Droit | 2 | 2 | W10
Weld | 6660 | Droit | 2 | 2 | W10
Weld | 6658 | Droit | 2 | 2 | W10
Weld | 6657 | Droit | 2 | 2 | W10
Weld | 6655 | Droit | 2 | 2 | W10
Weld | 6654 | Droit | 2 | 2 | W10
Weld | 6652 | Droit | 2 | 2 | W10
Weld | 6651 | Droit | 2 | 2 | W10
Weld | 6649 | Droit | 2 | 2 | W10
Weld | 6648 | Droit | 2 | 2 | W10
Weld | 6646 | Droit | 2 | 2 | W10
Weld | 6645 | Droit | 2 | 2 | W10
Weld | 6643 | Droit | 2 | 2 | W10
Weld | 6642 | Droit | 2 | 2 | W10
Weld | 6640 | Droit | 2 | 2 | W10
Weld | 6639 | Droit | 2 | 2 | W10
Weld | 6637 | Droit | 2 | 2 | W10
Weld | 6636 | Droit | 2 | 2 | W10
Weld | 6634 | Droit | 2 | 2 | W10
Weld | 6633 | Droit | 2 | 2 | W10
Weld | 6630 | Droit | 2 | 2 | W10
Weld | 6629 | Droit | 2 | 2 | W10
Weld | 6627 | Droit | 2 | 2 | W10
Weld | 6626 | Droit | 2 | 2 | W10
Weld | 6618 | Droit | 2 | 2 | W10
Weld | 6617 | Droit | 2 | 2 | W10
Weld | 6615 | Droit | 2 | 2 | W10
Weld | 6614 | Droit | 2 | 2 | W10
Weld | 6612 | Droit | 2 | 2 | W10
Weld | 6611 | Droit | 2 | 2 | W10
Weld | 6609 | Droit | 2 | 2 | W10
Weld | 6608 | Droit | 2 | 2 | W10
Weld | 6604 | Droit | 2 | 2 | W10
Weld | 6603 | Droit | 2 | 2 | W10
Weld | 6601 | Droit | 2 | 2 | W10
Weld | 6600 | Droit | 2 | 2 | W10
Weld | 6597 | Droit | 2 | 2 | W10
Weld | 6596 | Droit | 2 | 2 | W10
Weld | 6593 | Droit | 2 | 2 | W10
Weld | 6592 | Droit | 2 | 2 | W10
Weld | 6588 | Droit | 2 | 2 | W10
Weld | 6587 | Droit | 2 | 2 | W10
Weld | 6583 | Droit | 2 | 2 | W10
Weld | 6582 | Droit | 2 | 2 | W10
Weld | 6578 | Droit | 2 | 2 | W10
Weld | 6577 | Droit | 2 | 2 | W10
Weld | 6576 | Autour | 6 | 0 | Aucun
Weld | 6574 | Droit | 2 | 2 | W10
Weld | 6573 | Droit | 2 | 2 | W10
Weld | 6567 | Droit | 2 | 2 | W10
Weld | 6566 | Droit | 2 | 2 | W10
Weld | 6562 | Droit | 2 | 2 | W10
Weld | 6561 | Droit | 2 | 2 | W10
Weld | 6558 | Autour | 6 | 0 | Aucun
Weld | 6557 | Autour | 6 | 0 | Aucun
Weld | 6555 | Droit | 2 | 2 | W10
Weld | 6554 | Droit | 2 | 2 | W10
Weld | 6552 | Droit | 2 | 2 | W10
Weld | 6551 | Droit | 2 | 2 | W10
Weld | 6549 | Droit | 2 | 2 | W10
Weld | 6548 | Droit | 2 | 2 | W10
Weld | 6546 | Droit | 2 | 2 | W10
Weld | 6545 | Droit | 2 | 2 | W10
Weld | 6542 | Droit | 2 | 2 | W10
Weld | 6541 | Droit | 2 | 2 | W10
Weld | 6538 | Droit | 2 | 2 | W10
Weld | 6537 | Droit | 2 | 2 | W10
Weld | 6536 | Autour | 6 | 0 | Aucun
Weld | 6533 | Autour | 6 | 0 | Aucun
Weld | 6532 | Autour | 6 | 0 | Aucun
Weld | 6528 | Droit | 2 | 2 | W10
Weld | 6527 | Droit | 2 | 2 | W10
Weld | 6525 | Droit | 2 | 2 | W10
Weld | 6524 | Droit | 2 | 2 | W10
Weld | 6523 | Autour | 6 | 0 | Aucun
Weld | 6522 | Autour | 6 | 0 | Aucun
Weld | 6519 | Autour | 6 | 0 | Aucun
Weld | 6518 | Autour | 6 | 0 | Aucun
Weld | 6517 | Autour | 6 | 0 | Aucun
Weld | 6516 | Autour | 6 | 0 | Aucun
Weld | 6513 | Droit | 2 | 2 | W10
Weld | 6512 | Droit | 2 | 2 | W10
Weld | 6510 | Droit | 2 | 2 | W10
Weld | 6509 | Droit | 2 | 2 | W10
Weld | 6508 | Autour | 6 | 0 | Aucun
Weld | 6502 | Autour | 6 | 0 | Aucun
Weld | 6295 | Autour | 6 | 0 | Aucun
Weld | 6294 | Autour | 6 | 0 | Aucun
Weld | 6293 | Autour | 6 | 0 | Aucun
Weld | 6292 | Autour | 6 | 0 | Aucun
Weld | 6291 | Autour | 6 | 0 | Aucun
Weld | 6290 | Autour | 6 | 0 | Aucun
Weld | 6289 | Autour | 6 | 0 | Aucun
Weld | 6288 | Autour | 6 | 0 | Aucun
Weld | 6278 | Autour | 6 | 0 | Aucun
Weld | 6277 | Autour | 6 | 0 | Aucun
Weld | 6276 | Autour | 6 | 0 | Aucun
Weld | 6273 | Autour | 6 | 0 | Aucun
Weld | 6272 | Autour | 6 | 0 | Aucun
Weld | 6271 | Autour | 6 | 0 | Aucun
Weld | 6270 | Autour | 6 | 0 | Aucun
Weld | 6269 | Autour | 6 | 0 | Aucun
Weld | 6267 | Autour | 6 | 0 | Aucun
Weld | 6266 | Autour | 6 | 0 | Aucun
Weld | 6265 | Autour | 6 | 0 | Aucun
Weld | 6264 | Autour | 6 | 0 | Aucun
Weld | 6263 | Autour | 6 | 0 | Aucun
Weld | 6262 | Autour | 6 | 0 | Aucun
Weld | 6261 | Autour | 6 | 0 | Aucun
Weld | 6260 | Autour | 6 | 0 | Aucun
Weld | 6259 | Autour | 6 | 0 | Aucun
Weld | 6254 | Autour | 6 | 0 | Aucun
Weld | 6253 | Autour | 6 | 0 | Aucun
Weld | 6251 | Autour | 6 | 0 | Aucun
Weld | 6250 | Autour | 6 | 0 | Aucun
Weld | 6249 | Autour | 6 | 0 | Aucun
Weld | 6248 | Autour | 6 | 0 | Aucun
Weld | 6245 | Autour | 6 | 0 | Aucun
Weld | 6242 | Autour | 6 | 0 | Aucun
Weld | 6239 | Autour | 6 | 0 | Aucun
Weld | 6235 | Autour | 6 | 0 | Aucun
Weld | 6234 | Autour | 6 | 0 | Aucun
Weld | 6233 | Autour | 6 | 0 | Aucun
Weld | 6229 | Autour | 6 | 0 | Aucun
Weld | 6228 | Autour | 6 | 0 | Aucun
Weld | 6227 | Autour | 6 | 0 | Aucun
Weld | 6226 | Autour | 6 | 0 | Aucun
Weld | 6225 | Autour | 6 | 0 | Aucun
Weld | 6222 | Autour | 6 | 0 | Aucun
Weld | 6221 | Autour | 6 | 0 | Aucun
Weld | 6220 | Autour | 6 | 0 | Aucun
Weld | 6219 | Autour | 6 | 0 | Aucun
Weld | 6216 | Autour | 6 | 0 | Aucun
Weld | 6209 | Autour | 6 | 0 | Aucun
Weld | 6205 | Autour | 6 | 0 | Aucun
Weld | 6197 | Autour | 6 | 0 | Aucun
Weld | 6194 | Autour | 6 | 0 | Aucun
Weld | 6185 | Autour | 6 | 0 | Aucun
Weld | 6184 | Autour | 6 | 0 | Aucun
Weld | 6183 | Autour | 6 | 0 | Aucun
Weld | 6182 | Autour | 6 | 0 | Aucun
Weld | 6178 | Autour | 6 | 0 | Aucun
Weld | 6177 | Autour | 6 | 0 | Aucun
Weld | 6174 | Autour | 6 | 0 | Aucun
Weld | 6173 | Autour | 6 | 0 | Aucun
Weld | 6172 | Autour | 6 | 0 | Aucun
Weld | 6166 | Autour | 6 | 0 | Aucun
Weld | 6164 | Autour | 6 | 0 | Aucun
Weld | 6161 | Autour | 6 | 0 | Aucun
Weld | 6158 | Autour | 6 | 0 | Aucun
Weld | 6154 | Autour | 6 | 0 | Aucun
Weld | 6153 | Autour | 6 | 0 | Aucun
Weld | 6149 | Autour | 6 | 0 | Aucun
2 x Weld | 6148 | Autour | 6 | 0 | Aucun
2 x Weld | 6147 | Autour | 6 | 0 | Aucun
Weld | 6146 | Autour | 6 | 0 | Aucun
Weld | 6142 | Autour | 6 | 0 | Aucun
Weld | 6141 | Autour | 6 | 0 | Aucun
2 x Weld | 6140 | Autour | 6 | 0 | Aucun
Weld | 6139 | Autour | 6 | 0 | Aucun
Weld | 6138 | Autour | 6 | 0 | Aucun
2 x Weld | 6137 | Autour | 6 | 0 | Aucun
2 x Weld | 6136 | Autour | 6 | 0 | Aucun
2 x Weld | 6135 | Autour | 6 | 0 | Aucun
Weld | 6131 | Autour | 6 | 0 | Aucun
Weld | 6129 | Autour | 6 | 0 | Aucun
Weld | 6123 | Autour | 6 | 0 | Aucun
Weld | 6122 | Autour | 6 | 0 | Aucun
Weld | 6119 | Autour | 6 | 0 | Aucun
Weld | 6115 | Autour | 6 | 0 | Aucun
Weld | 6113 | Autour | 6 | 0 | Aucun
Weld | 6112 | Autour | 6 | 0 | Aucun
Weld | 6111 | Droit | 5 | 5 | W10
Weld | 6110 | Droit | 5 | 5 | W10
Weld | 6109 | Droit | 5 | 5 | W10
Weld | 6108 | Droit | 5 | 5 | W10
Weld | 6107 | Droit | 5 | 5 | W10
Weld | 6106 | Droit | 5 | 5 | W10
Weld | 6105 | Droit | 5 | 5 | W10
Weld | 6104 | Droit | 5 | 5 | W10
Weld | 6103 | Droit | 5 | 5 | W10
Weld | 6102 | Droit | 4 | 4 | W10
Weld | 6101 | Droit | 5 | 5 | W10
Weld | 6100 | Droit | 5 | 5 | W10
Weld | 6099 | Droit | 4 | 4 | W10
Weld | 6098 | Droit | 5 | 5 | W10
Weld | 6097 | Droit | 5 | 5 | W10
Weld | 6096 | Droit | 5 | 5 | W10
Weld | 6095 | Droit | 5 | 5 | W10
Weld | 6094 | Droit | 5 | 5 | W10
Weld | 6093 | Droit | 5 | 5 | W10
Weld | 6092 | Droit | 5 | 5 | W10
Weld | 6091 | Droit | 5 | 5 | W10
Weld | 6090 | Droit | 5 | 5 | W10
Weld | 6089 | Droit | 5 | 5 | W10
Weld | 6088 | Droit | 5 | 5 | W10
Weld | 6084 | Autour | 6 | 0 | Aucun
Weld | 3138 | Autour | 6 | 0 | Aucun
Weld | 3137 | Droit | 5 | 0 | Aucun
Weld | 3136 | Autour | 6 | 0 | Aucun
Weld | 3135 | Droit | 5 | 0 | Aucun
Weld | 3134 | Autour | 6 | 0 | Aucun
Weld | 3133 | Droit | 5 | 0 | Aucun
Weld | 3132 | Autour | 6 | 0 | Aucun
Weld | 3131 | Droit | 5 | 0 | Aucun
Weld | 3130 | Autour | 6 | 0 | Aucun
Weld | 3129 | Droit | 5 | 0 | Aucun
Weld | 3128 | Autour | 6 | 0 | Aucun
Weld | 3127 | Autour | 6 | 0 | Aucun
Weld | 3126 | Autour | 6 | 0 | Aucun
Weld | 3125 | Droit | 5 | 0 | Aucun
Weld | 3124 | Autour | 6 | 0 | Aucun
Weld | 3123 | Autour | 6 | 0 | Aucun
Weld | 3104 | Autour | 6 | 0 | Aucun
Weld | 3103 | Autour | 6 | 0 | Aucun
Weld | 3102 | Droit | 5 | 0 | Aucun
Weld | 3101 | Droit | 5 | 0 | Aucun
Weld | 3100 | Droit | 5 | 0 | Aucun
Weld | 3098 | Autour | 6 | 0 | Aucun
Weld | 3097 | Droit | 5 | 0 | Aucun
Weld | 3096 | Droit | 5 | 0 | Aucun
Weld | 3095 | Droit | 5 | 0 | Aucun
Weld | 3094 | Autour | 6 | 0 | Aucun
Weld | 3093 | Autour | 6 | 0 | Aucun
Weld | 3092 | Autour | 6 | 0 | Aucun
Weld | 3091 | Autour | 6 | 0 | Aucun
Weld | 3090 | Autour | 6 | 0 | Aucun
Weld | 3089 | Droit | 5 | 0 | Aucun
Weld | 3088 | Droit | 5 | 0 | Aucun
Weld | 3087 | Droit | 5 | 0 | Aucun
Weld | 3086 | Droit | 5 | 0 | Aucun
Weld | 3085 | Droit | 5 | 0 | Aucun
Weld | 3084 | Droit | 5 | 0 | Aucun
Weld | 3083 | Droit | 5 | 0 | Aucun
Weld | 3082 | Droit | 5 | 0 | Aucun
Weld | 3081 | Droit | 5 | 0 | Aucun
Weld | 3080 | Droit | 5 | 0 | Aucun
Weld | 3079 | Droit | 5 | 0 | Aucun
Weld | 3078 | Droit | 5 | 0 | Aucun
Weld | 3077 | Droit | 5 | 0 | Aucun
Weld | 3076 | Droit | 5 | 0 | Aucun
Weld | 3075 | Autour | 6 | 0 | Aucun
Weld | 3074 | Autour | 6 | 0 | Aucun
Weld | 3073 | Autour | 6 | 0 | Aucun
Weld | 3072 | Autour | 6 | 0 | Aucun
Weld | 3071 | Autour | 6 | 0 | Aucun
Weld | 3070 | Autour | 6 | 0 | Aucun
Weld | 3069 | Autour | 6 | 0 | Aucun
Weld | 3068 | Autour | 6 | 0 | Aucun
Weld | 3067 | Droit | 5 | 0 | Aucun
Weld | 3066 | Droit | 5 | 0 | Aucun
Weld | 3065 | Droit | 5 | 0 | Aucun
Weld | 3064 | Droit | 5 | 0 | Aucun
Weld | 3063 | Droit | 5 | 0 | Aucun
Weld | 3062 | Droit | 5 | 0 | Aucun
Weld | 3061 | Droit | 5 | 0 | Aucun
Weld | 3060 | Droit | 5 | 0 | Aucun
Weld | 3059 | Droit | 5 | 0 | Aucun
Weld | 3058 | Droit | 5 | 0 | Aucun
Weld | 3057 | Droit | 5 | 0 | Aucun
Weld | 3056 | Droit | 5 | 0 | Aucun
Weld | 3055 | Autour | 6 | 0 | Aucun
Weld | 3054 | Autour | 6 | 0 | Aucun
Weld | 3049 | Autour | 6 | 0 | Aucun
Weld | 3048 | Autour | 6 | 0 | Aucun
Weld | 3047 | Autour | 6 | 0 | Aucun
Weld | 3045 | Autour | 6 | 0 | Aucun
Weld | 3044 | Autour | 6 | 0 | Aucun
Weld | 3042 | Autour | 6 | 0 | Aucun
Weld | 3041 | Autour | 6 | 0 | Aucun
Weld | 3040 | Autour | 6 | 0 | Aucun
Weld | 3035 | Autour | 6 | 0 | Aucun
Weld | 3034 | Autour | 6 | 0 | Aucun
Weld | 3033 | Autour | 6 | 0 | Aucun
Weld | 3031 | Autour | 6 | 0 | Aucun
Weld | 3030 | Autour | 6 | 0 | Aucun
Weld | 3025 | Autour | 6 | 0 | Aucun
Weld | 3024 | Autour | 6 | 0 | Aucun
Weld | 3022 | Autour | 6 | 0 | Aucun
Weld | 3021 | Autour | 6 | 0 | Aucun
Weld | 3020 | Autour | 6 | 0 | Aucun
Weld | 3019 | Autour | 6 | 0 | Aucun
Weld | 3018 | Autour | 6 | 0 | Aucun
Weld | 3017 | Autour | 6 | 0 | Aucun
Weld | 3016 | Autour | 6 | 0 | Aucun
Weld | 3015 | Autour | 6 | 0 | Aucun
Weld | 3014 | Autour | 6 | 0 | Aucun
Weld | 3012 | Autour | 6 | 0 | Aucun
Weld | 3009 | Autour | 6 | 0 | Aucun
Weld | 3008 | Autour | 6 | 0 | Aucun
Weld | 3006 | Autour | 6 | 0 | Aucun
Weld | 3005 | Autour | 6 | 0 | Aucun
Weld | 3004 | Autour | 6 | 0 | Aucun
Weld | 3003 | Autour | 6 | 0 | Aucun
Weld | 3002 | Autour | 6 | 0 | Aucun
Weld | 3001 | Autour | 6 | 0 | Aucun
Weld | 2995 | Autour | 6 | 0 | Aucun
Weld | 2994 | Autour | 6 | 0 | Aucun
Weld | 2993 | Autour | 6 | 0 | Aucun
Weld | 2992 | Autour | 6 | 0 | Aucun
Weld | 2991 | Autour | 6 | 0 | Aucun
Weld | 2990 | Autour | 6 | 0 | Aucun
Weld | 2989 | Autour | 6 | 0 | Aucun
Weld | 2988 | Autour | 6 | 0 | Aucun
Weld | 2987 | Autour | 6 | 0 | Aucun
Weld | 2986 | Autour | 6 | 0 | Aucun
Weld | 2985 | Autour | 6 | 0 | Aucun
Weld | 2984 | Autour | 6 | 0 | Aucun
Weld | 2981 | Autour | 6 | 0 | Aucun
Weld | 2980 | Autour | 6 | 0 | Aucun
Weld | 2979 | Autour | 6 | 0 | Aucun
Weld | 2978 | Autour | 6 | 0 | Aucun
Weld | 2977 | Autour | 6 | 0 | Aucun
Weld | 2976 | Autour | 6 | 0 | Aucun
Weld | 2975 | Autour | 6 | 0 | Aucun
Weld | 2974 | Droit | 5 | 0 | Aucun
Weld | 2973 | Droit | 6 | 6 | W10
Weld | 2972 | Droit | 6 | 6 | W10
Weld | 2971 | Droit | 8 | 8 | W10
Weld | 2970 | Droit | 8 | 8 | W10
Weld | 2969 | Droit | 8 | 8 | W10
Weld | 2968 | Droit | 8 | 8 | W10
Weld | 2967 | Droit | 6 | 6 | W10
Weld | 2966 | Droit | 6 | 6 | W10
Weld | 2965 | Droit | 8 | 8 | W10
Weld | 2964 | Droit | 8 | 8 | W10
Weld | 2963 | Droit | 8 | 8 | W10
Weld | 2962 | Droit | 8 | 8 | W10
Weld | 2961 | Droit | 6 | 6 | W10
Weld | 2960 | Droit | 6 | 6 | W10
Weld | 2959 | Droit | 8 | 8 | W10
Weld | 2958 | Droit | 8 | 8 | W10
Weld | 2957 | Droit | 8 | 8 | W10
Weld | 2956 | Droit | 8 | 8 | W10
Weld | 2955 | Droit | 8 | 8 | W10
Weld | 2954 | Droit | 8 | 8 | W10
Weld | 2953 | Droit | 8 | 8 | W10
Weld | 2952 | Droit | 8 | 8 | W10
Weld | 2951 | Droit | 6 | 6 | W10
Weld | 2950 | Droit | 8 | 8 | W10
Weld | 2949 | Autour | 6 | 0 | Aucun
Weld | 2947 | Droit | 5 | 0 | Aucun
Weld | 2946 | Droit | 5 | 0 | Aucun
Weld | 2945 | Droit | 5 | 0 | Aucun
Weld | 2944 | Droit | 5 | 0 | Aucun
Weld | 2943 | Droit | 5 | 0 | Aucun
Weld | 2942 | Droit | 5 | 0 | Aucun
Weld | 2941 | Droit | 5 | 0 | Aucun
Weld | 2939 | Droit | 5 | 5 | W10
2 x Weld | 2938 | Droit | 5 | 5 | W10
2 x Weld | 2937 | Droit | 5 | 5 | W10
Weld | 2936 | Droit | 8 | 8 | W10
Weld | 2935 | Droit | 8 | 8 | W10
Weld | 2934 | Droit | 5 | 5 | W10
Weld | 2932 | Droit | 5 | 0 | Aucun
Weld | 2931 | Droit | 5 | 0 | Aucun
2 x Weld | 2929 | Droit | 5 | 5 | W10
Weld | 2928 | Droit | 5 | 5 | W10
Weld | 2927 | Droit | 5 | 5 | W10
Weld | 2926 | Droit | 8 | 8 | W10
Weld | 2925 | Droit | 8 | 8 | W10
2 x Weld | 2924 | Droit | 5 | 5 | W10
Weld | 2922 | Droit | 5 | 0 | Aucun
2 x Weld | 2920 | Droit | 5 | 5 | W10
2 x Weld | 2919 | Droit | 5 | 5 | W10
2 x Weld | 2918 | Droit | 5 | 5 | W10
Weld | 2917 | Droit | 8 | 8 | W10
Weld | 2916 | Droit | 8 | 8 | W10
Weld | 2915 | Droit | 5 | 5 | W10
Weld | 2913 | Droit | 5 | 0 | Aucun
Weld | 2912 | Droit | 5 | 0 | Aucun
Weld | 2911 | Droit | 5 | 0 | Aucun
Weld | 2910 | Droit | 5 | 0 | Aucun
Weld | 2909 | Droit | 5 | 0 | Aucun
Weld | 2908 | Droit | 5 | 0 | Aucun
2 x Weld | 2906 | Droit | 5 | 5 | W10
2 x Weld | 2905 | Droit | 5 | 5 | W10
Weld | 2904 | Droit | 5 | 5 | W10
Weld | 2903 | Droit | 8 | 8 | W10
Weld | 2902 | Droit | 8 | 8 | W10
2 x Weld | 2901 | Droit | 5 | 5 | W10
Weld | 2899 | Droit | 5 | 0 | Aucun
Weld | 2897 | Droit | 5 | 0 | Aucun
Weld | 2896 | Droit | 5 | 0 | Aucun
Weld | 2895 | Droit | 5 | 0 | Aucun
Weld | 2894 | Droit | 5 | 0 | Aucun
Weld | 2893 | Droit | 5 | 0 | Aucun
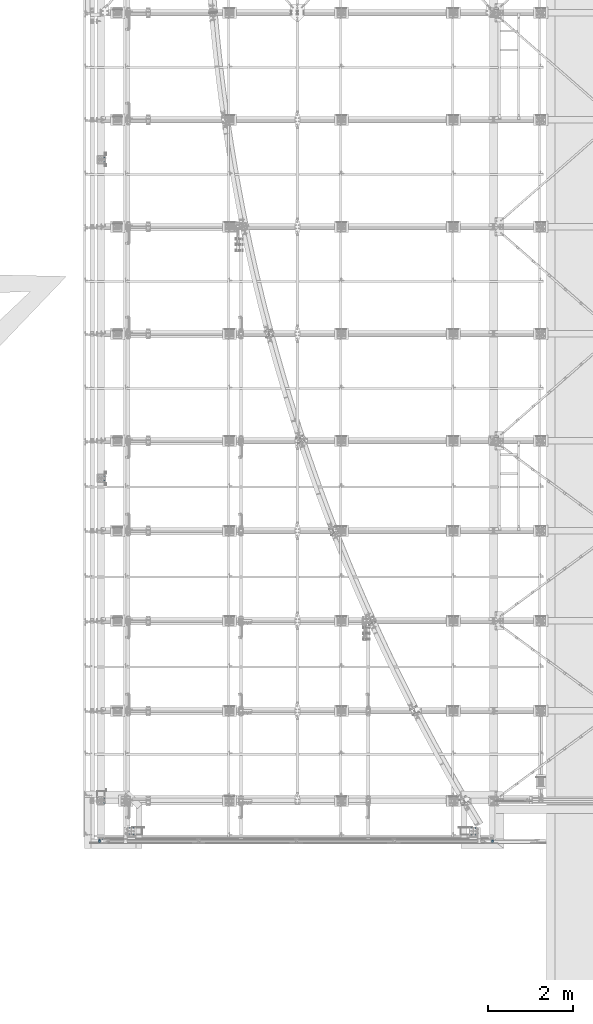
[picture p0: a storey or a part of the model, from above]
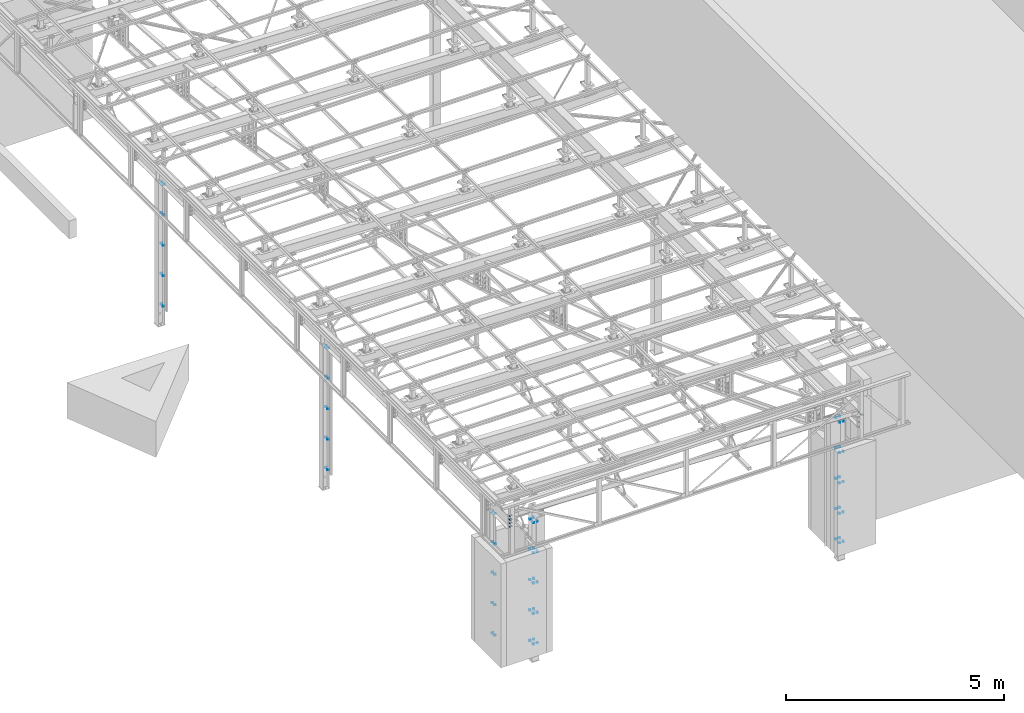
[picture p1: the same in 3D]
Properties of the parts of a building model (IFC2X3), part 9 of 13

# IfcFastener (6774)
Name | N° soudure | Linéaire/Périphérique | Dimension1 (mm) | Dimension2 (mm) | Type2
Weld | 2892 | Droit | 5 | 0 | Aucun
Weld | 2891 | Droit | 5 | 0 | Aucun
Weld | 2890 | Droit | 5 | 0 | Aucun
Weld | 2889 | Droit | 5 | 0 | Aucun
Weld | 2888 | Droit | 5 | 0 | Aucun
Weld | 2887 | Droit | 5 | 0 | Aucun
Weld | 2886 | Droit | 5 | 0 | Aucun
Weld | 2885 | Droit | 5 | 0 | Aucun
Weld | 2884 | Droit | 5 | 0 | Aucun
Weld | 2883 | Droit | 5 | 0 | Aucun
Weld | 2882 | Droit | 5 | 0 | Aucun
Weld | 2881 | Droit | 5 | 0 | Aucun
Weld | 2880 | Droit | 5 | 0 | Aucun
Weld | 2879 | Droit | 5 | 0 | Aucun
Weld | 2878 | Droit | 5 | 0 | Aucun
Weld | 2877 | Autour | 6 | 0 | Aucun
Weld | 2876 | Autour | 6 | 0 | Aucun
Weld | 2875 | Autour | 6 | 0 | Aucun
Weld | 2874 | Autour | 6 | 0 | Aucun
Weld | 2873 | Autour | 6 | 0 | Aucun
Weld | 2872 | Autour | 6 | 0 | Aucun
Weld | 2871 | Autour | 6 | 0 | Aucun
Weld | 2870 | Autour | 6 | 0 | Aucun
Weld | 2869 | Autour | 6 | 0 | Aucun
Weld | 2868 | Autour | 6 | 0 | Aucun
Weld | 2867 | Autour | 6 | 0 | Aucun
Weld | 2866 | Autour | 6 | 0 | Aucun
Weld | 2865 | Droit | 5 | 0 | Aucun
Weld | 2864 | Autour | 6 | 0 | Aucun
Weld | 2863 | Autour | 6 | 0 | Aucun
Weld | 2862 | Autour | 6 | 0 | Aucun
Weld | 2861 | Autour | 6 | 0 | Aucun
Weld | 2860 | Autour | 6 | 0 | Aucun
Weld | 2859 | Autour | 6 | 0 | Aucun
Weld | 2858 | Autour | 6 | 0 | Aucun
Weld | 2857 | Autour | 6 | 0 | Aucun
Weld | 2856 | Autour | 6 | 0 | Aucun
Weld | 2855 | Autour | 6 | 0 | Aucun
Weld | 2854 | Autour | 6 | 0 | Aucun
Weld | 2853 | Autour | 6 | 0 | Aucun
Weld | 2852 | Autour | 6 | 0 | Aucun
Weld | 2851 | Autour | 6 | 0 | Aucun
Weld | 2850 | Autour | 6 | 0 | Aucun
Weld | 2849 | Autour | 6 | 0 | Aucun
Weld | 2848 | Autour | 6 | 0 | Aucun
Weld | 2847 | Autour | 6 | 0 | Aucun
Weld | 2846 | Droit | 5 | 0 | Aucun
Weld | 2845 | Droit | 5 | 0 | Aucun
Weld | 2844 | Droit | 5 | 0 | Aucun
Weld | 2843 | Droit | 5 | 0 | Aucun
Weld | 2842 | Droit | 5 | 0 | Aucun
Weld | 2835 | Droit | 4 | 4 | W10
2 x Weld | 2834 | Droit | 5 | 5 | W10
2 x Weld | 2833 | Droit | 5 | 5 | W10
2 x Weld | 2832 | Droit | 4 | 4 | W10
Weld | 2831 | Droit | 5 | 5 | W10
2 x Weld | 2830 | Droit | 5 | 5 | W10
Weld | 2829 | Droit | 4 | 4 | W10
2 x Weld | 2828 | Droit | 5 | 5 | W10
2 x Weld | 2827 | Droit | 5 | 5 | W10
2 x Weld | 2826 | Droit | 4 | 4 | W10
Weld | 2825 | Droit | 5 | 5 | W10
2 x Weld | 2824 | Droit | 5 | 5 | W10
Weld | 2823 | Droit | 4 | 4 | W10
2 x Weld | 2822 | Droit | 5 | 5 | W10
2 x Weld | 2821 | Droit | 5 | 5 | W10
2 x Weld | 2820 | Droit | 4 | 4 | W10
Weld | 2819 | Droit | 5 | 5 | W10
2 x Weld | 2818 | Droit | 5 | 5 | W10
Weld | 2812 | Autour | 6 | 0 | Aucun
Weld | 2809 | Autour | 6 | 0 | Aucun
Weld | 2808 | Autour | 6 | 0 | Aucun
Weld | 2807 | Autour | 6 | 0 | Aucun
Weld | 2798 | Autour | 6 | 0 | Aucun
Weld | 2787 | Autour | 6 | 0 | Aucun
Weld | 2774 | Autour | 6 | 0 | Aucun
Weld | 2773 | Autour | 6 | 0 | Aucun
Weld | 2769 | Autour | 6 | 0 | Aucun
Weld | 2745 | Autour | 6 | 0 | Aucun
Weld | 2744 | Autour | 6 | 0 | Aucun
Weld | 2743 | Autour | 6 | 0 | Aucun
Weld | 2742 | Autour | 6 | 0 | Aucun
Weld | 2734 | Autour | 6 | 0 | Aucun
Weld | 2728 | Autour | 6 | 0 | Aucun
Weld | 2727 | Autour | 6 | 0 | Aucun
Weld | 2719 | Autour | 6 | 0 | Aucun
Weld | 2718 | Autour | 6 | 0 | Aucun
Weld | 2717 | Autour | 6 | 0 | Aucun
Weld | 2716 | Autour | 6 | 0 | Aucun
Weld | 2712 | Autour | 6 | 0 | Aucun
Weld | 2711 | Autour | 6 | 0 | Aucun
Weld | 2710 | Autour | 6 | 0 | Aucun
Weld | 2706 | Autour | 6 | 0 | Aucun
Weld | 2705 | Autour | 6 | 0 | Aucun
Weld | 2680 | Autour | 6 | 0 | Aucun
Weld | 2679 | Autour | 6 | 0 | Aucun
Weld | 2677 | Autour | 6 | 0 | Aucun
Weld | 2676 | Autour | 6 | 0 | Aucun
Weld | 2675 | Autour | 6 | 0 | Aucun
Weld | 2674 | Autour | 6 | 0 | Aucun
Weld | 2668 | Autour | 6 | 0 | Aucun
Weld | 2663 | Autour | 6 | 0 | Aucun
Weld | 2658 | Autour | 6 | 0 | Aucun
Weld | 2657 | Autour | 6 | 0 | Aucun
Weld | 2656 | Autour | 6 | 0 | Aucun
Weld | 2655 | Autour | 6 | 0 | Aucun
Weld | 2654 | Autour | 6 | 0 | Aucun
Weld | 2653 | Autour | 6 | 0 | Aucun
Weld | 2652 | Autour | 6 | 0 | Aucun
Weld | 2651 | Autour | 6 | 0 | Aucun
Weld | 2647 | Autour | 6 | 0 | Aucun
Weld | 2645 | Autour | 6 | 0 | Aucun
2 x Weld | 2632 | Droit | 5 | 5 | W10
Weld | 2631 | Droit | 5 | 5 | W10
Weld | 2630 | Droit | 5 | 5 | W10
2 x Weld | 2629 | Droit | 5 | 5 | W10
2 x Weld | 2628 | Droit | 5 | 5 | W10
2 x Weld | 2627 | Droit | 5 | 5 | W10
Weld | 2626 | Droit | 5 | 5 | W10
Weld | 2625 | Droit | 5 | 5 | W10
Weld | 2624 | Droit | 5 | 5 | W10
Weld | 2623 | Droit | 5 | 5 | W10
Weld | 2622 | Droit | 5 | 5 | W10
Weld | 2621 | Droit | 5 | 5 | W10
Weld | 2620 | Droit | 5 | 5 | W10
Weld | 2619 | Droit | 5 | 5 | W10
Weld | 2618 | Droit | 5 | 5 | W10
Weld | 2617 | Droit | 5 | 5 | W10
Weld | 2616 | Droit | 5 | 5 | W10
Weld | 2615 | Droit | 5 | 5 | W10
Weld | 2608 | Droit | 5 | 5 | W10
Weld | 2607 | Droit | 5 | 5 | W10
Weld | 2606 | Droit | 5 | 5 | W10
Weld | 2605 | Droit | 5 | 5 | W10
Weld | 2604 | Droit | 5 | 5 | W10
Weld | 2603 | Droit | 5 | 5 | W10
Weld | 2602 | Droit | 5 | 5 | W10
Weld | 2601 | Droit | 5 | 5 | W10
Weld | 2600 | Droit | 5 | 5 | W10
2 x Weld | 2599 | Droit | 5 | 5 | W10
Weld | 2598 | Droit | 5 | 5 | W10
Weld | 2597 | Droit | 5 | 5 | W10
2 x Weld | 2596 | Droit | 5 | 5 | W10
2 x Weld | 2595 | Droit | 5 | 5 | W10
2 x Weld | 2594 | Droit | 5 | 5 | W10
Weld | 2593 | Droit | 5 | 5 | W10
Weld | 2592 | Droit | 5 | 5 | W10
Weld | 2591 | Droit | 5 | 5 | W10
Weld | 2578 | Droit | 5 | 5 | W10
Weld | 2577 | Droit | 5 | 5 | W10
Weld | 2576 | Droit | 5 | 5 | W10
Weld | 2575 | Droit | 5 | 5 | W10
Weld | 2574 | Droit | 5 | 5 | W10
Weld | 2573 | Droit | 5 | 5 | W10
Weld | 2572 | Droit | 5 | 5 | W10
Weld | 2571 | Droit | 5 | 5 | W10
Weld | 2570 | Droit | 5 | 5 | W10
Weld | 2569 | Droit | 5 | 5 | W10
Weld | 2568 | Droit | 5 | 5 | W10
Weld | 2567 | Droit | 5 | 5 | W10
Weld | 2566 | Droit | 5 | 5 | W10
Weld | 2565 | Droit | 5 | 5 | W10
Weld | 2564 | Droit | 5 | 5 | W10
Weld | 2563 | Droit | 5 | 5 | W10
Weld | 2562 | Droit | 5 | 5 | W10
Weld | 2561 | Droit | 5 | 5 | W10
Weld | 2560 | Droit | 5 | 5 | W10
Weld | 2559 | Droit | 5 | 5 | W10
Weld | 2558 | Droit | 5 | 5 | W10
Weld | 2557 | Droit | 5 | 5 | W10
Weld | 2556 | Droit | 5 | 5 | W10
Weld | 2555 | Droit | 5 | 5 | W10
Weld | 2554 | Droit | 5 | 5 | W10
Weld | 2553 | Droit | 5 | 5 | W10
2 x Weld | 2552 | Droit | 5 | 5 | W10
Weld | 2551 | Droit | 5 | 5 | W10
Weld | 2550 | Droit | 5 | 5 | W10
2 x Weld | 2549 | Droit | 5 | 5 | W10
Weld | 2542 | Droit | 5 | 5 | W10
Weld | 2541 | Droit | 5 | 5 | W10
Weld | 2540 | Droit | 5 | 5 | W10
Weld | 2539 | Droit | 5 | 5 | W10
Weld | 2538 | Droit | 5 | 5 | W10
Weld | 2537 | Droit | 5 | 5 | W10
Weld | 2523 | Autour | 6 | 0 | Aucun
Weld | 2522 | Autour | 6 | 0 | Aucun
Weld | 2520 | Autour | 6 | 0 | Aucun
Weld | 2519 | Autour | 6 | 0 | Aucun
Weld | 2517 | Autour | 6 | 0 | Aucun
2 x Weld | 2516 | Droit | 8 | 8 | W10
2 x Weld | 2515 | Droit | 8 | 8 | W10
2 x Weld | 2514 | Droit | 8 | 8 | W10
2 x Weld | 2513 | Droit | 8 | 8 | W10
Weld | 2512 | Droit | 5 | 5 | W10
Weld | 2511 | Droit | 7 | 7 | W10
Weld | 2510 | Autour | 6 | 0 | Aucun
2 x Weld | 2509 | Droit | 8 | 8 | W10
Weld | 2508 | Droit | 8 | 8 | W10
Weld | 2507 | Droit | 8 | 8 | W10
2 x Weld | 2506 | Droit | 8 | 8 | W10
Weld | 2505 | Droit | 5 | 5 | W10
Weld | 2504 | Droit | 7 | 7 | W10
Weld | 2502 | Autour | 6 | 0 | Aucun
Weld | 2495 | Autour | 6 | 0 | Aucun
Weld | 2494 | Autour | 6 | 0 | Aucun
Weld | 2492 | Autour | 6 | 0 | Aucun
Weld | 2491 | Autour | 6 | 0 | Aucun
Weld | 2486 | Autour | 6 | 0 | Aucun
Weld | 2485 | Autour | 6 | 0 | Aucun
Weld | 2484 | Droit | 8 | 8 | W10
Weld | 2483 | Droit | 8 | 8 | W10
Weld | 2482 | Droit | 8 | 8 | W10
Weld | 2481 | Droit | 8 | 8 | W10
Weld | 2480 | Droit | 5 | 5 | W10
Weld | 2479 | Droit | 7 | 7 | W10
Weld | 6133 | Autour | 6 | 0 | Aucun
Weld | 6132 | Autour | 6 | 0 | Aucun
Weld | 6114 | Droit | 5 | 0 | Aucun
Weld | 6104 | Autour | 6 | 0 | Aucun
Weld | 6099 | Droit | 5 | 0 | Aucun
Weld | 6098 | Autour | 6 | 0 | Aucun
Weld | 6096 | Droit | 5 | 0 | Aucun
Weld | 6095 | Autour | 6 | 0 | Aucun
Weld | 6094 | Autour | 6 | 0 | Aucun
Weld | 6079 | Droit | 5 | 0 | Aucun
Weld | 6078 | Droit | 5 | 0 | Aucun
Weld | 6059 | Droit | 5 | 0 | Aucun
Weld | 6057 | Droit | 5 | 0 | Aucun
Weld | 6053 | Droit | 5 | 0 | Aucun
Weld | 6051 | Droit | 5 | 0 | Aucun
Weld | 6049 | Droit | 5 | 0 | Aucun
Weld | 6047 | Droit | 5 | 0 | Aucun
Weld | 6045 | Droit | 5 | 0 | Aucun
Weld | 5949 | Droit | 5 | 0 | Aucun
Weld | 5948 | Droit | 5 | 0 | Aucun
Weld | 5947 | Droit | 5 | 0 | Aucun
Weld | 5946 | Droit | 5 | 0 | Aucun
Weld | 5945 | Droit | 5 | 0 | Aucun
Weld | 5913 | Droit | 5 | 0 | Aucun
Weld | 5888 | Droit | 4 | 4 | W10
Weld | 5887 | Droit | 4 | 4 | W10
Weld | 5886 | Droit | 5 | 5 | W10
Weld | 5885 | Droit | 5 | 5 | W10
Weld | 5884 | Droit | 4 | 4 | W10
Weld | 5883 | Droit | 5 | 5 | W10
Weld | 5882 | Droit | 5 | 5 | W10
Weld | 5881 | Droit | 4 | 4 | W10
Weld | 5880 | Droit | 4 | 4 | W10
Weld | 5879 | Droit | 5 | 5 | W10
Weld | 5878 | Droit | 5 | 5 | W10
Weld | 5877 | Droit | 5 | 5 | W10
Weld | 5876 | Droit | 5 | 5 | W10
Weld | 5875 | Droit | 4 | 4 | W10
Weld | 5874 | Droit | 5 | 5 | W10
Weld | 5873 | Droit | 5 | 5 | W10
Weld | 5872 | Droit | 4 | 4 | W10
Weld | 5871 | Droit | 4 | 4 | W10
Weld | 5870 | Droit | 5 | 5 | W10
Weld | 5869 | Droit | 5 | 5 | W10
Weld | 5868 | Droit | 4 | 4 | W10
Weld | 5867 | Droit | 5 | 5 | W10
Weld | 5866 | Droit | 5 | 5 | W10
Weld | 5865 | Droit | 4 | 4 | W10
Weld | 5864 | Droit | 5 | 5 | W10
Weld | 5863 | Droit | 5 | 5 | W10
Weld | 5862 | Droit | 4 | 4 | W10
Weld | 5861 | Droit | 4 | 4 | W10
Weld | 5825 | Droit | 5 | 0 | Aucun
Weld | 5824 | Droit | 5 | 0 | Aucun
Weld | 5823 | Droit | 5 | 5 | W10
Weld | 5822 | Droit | 5 | 5 | W10
Weld | 5821 | Droit | 4 | 4 | W10
Weld | 5820 | Droit | 5 | 5 | W10
Weld | 5819 | Droit | 5 | 5 | W10
Weld | 5818 | Droit | 4 | 4 | W10
Weld | 5817 | Droit | 4 | 4 | W10
Weld | 5816 | Droit | 4 | 4 | W10
Weld | 5815 | Droit | 5 | 5 | W10
Weld | 5814 | Droit | 5 | 5 | W10
Weld | 5813 | Droit | 4 | 4 | W10
Weld | 5812 | Droit | 5 | 5 | W10
Weld | 5811 | Droit | 5 | 5 | W10
Weld | 5810 | Droit | 4 | 4 | W10
Weld | 5809 | Droit | 5 | 5 | W10
Weld | 5808 | Droit | 5 | 5 | W10
Weld | 5807 | Droit | 4 | 4 | W10
Weld | 5806 | Droit | 5 | 5 | W10
Weld | 5805 | Droit | 5 | 5 | W10
Weld | 5804 | Droit | 4 | 4 | W10
Weld | 5803 | Droit | 4 | 4 | W10
Weld | 5802 | Droit | 4 | 4 | W10
Weld | 5801 | Droit | 5 | 5 | W10
Weld | 5800 | Droit | 5 | 5 | W10
Weld | 5799 | Droit | 4 | 4 | W10
Weld | 5798 | Droit | 5 | 5 | W10
Weld | 5797 | Droit | 5 | 5 | W10
Weld | 5796 | Droit | 4 | 4 | W10
Weld | 5795 | Droit | 5 | 0 | Aucun
Weld | 5794 | Droit | 5 | 0 | Aucun
Weld | 5793 | Droit | 5 | 0 | Aucun
Weld | 5792 | Droit | 5 | 0 | Aucun
Weld | 5791 | Droit | 5 | 0 | Aucun
Weld | 5790 | Droit | 5 | 0 | Aucun
Weld | 5785 | Droit | 4 | 4 | W10
Weld | 5784 | Droit | 5 | 5 | W10
Weld | 5783 | Droit | 5 | 5 | W10
Weld | 5782 | Droit | 5 | 0 | Aucun
Weld | 5654 | Droit | 5 | 0 | Aucun
Weld | 5653 | Droit | 5 | 0 | Aucun
Weld | 5652 | Droit | 5 | 5 | W10
Weld | 5651 | Droit | 5 | 5 | W10
Weld | 5650 | Droit | 4 | 4 | W10
Weld | 5643 | Droit | 5 | 0 | Aucun
Weld | 5642 | Droit | 5 | 0 | Aucun
Weld | 5641 | Droit | 5 | 0 | Aucun
Weld | 5640 | Droit | 5 | 0 | Aucun
Weld | 5639 | Droit | 5 | 0 | Aucun
Weld | 5638 | Droit | 5 | 0 | Aucun
Weld | 5637 | Droit | 5 | 0 | Aucun
Weld | 5636 | Droit | 4 | 4 | W10
Weld | 5635 | Droit | 5 | 5 | W10
Weld | 5634 | Droit | 5 | 5 | W10
Weld | 5633 | Droit | 4 | 4 | W10
Weld | 5632 | Droit | 5 | 5 | W10
Weld | 5631 | Droit | 5 | 5 | W10
Weld | 5630 | Droit | 4 | 4 | W10
Weld | 5629 | Droit | 4 | 4 | W10
Weld | 5628 | Droit | 4 | 4 | W10
Weld | 5627 | Droit | 5 | 5 | W10
Weld | 5626 | Droit | 5 | 5 | W10
Weld | 5625 | Droit | 4 | 4 | W10
Weld | 5624 | Droit | 5 | 5 | W10
Weld | 5623 | Droit | 5 | 5 | W10
Weld | 5622 | Droit | 4 | 4 | W10
Weld | 5621 | Droit | 4 | 4 | W10
Weld | 5620 | Droit | 5 | 5 | W10
Weld | 5619 | Droit | 5 | 5 | W10
Weld | 5618 | Droit | 4 | 4 | W10
Weld | 5617 | Droit | 5 | 5 | W10
Weld | 5616 | Droit | 5 | 5 | W10
Weld | 5615 | Droit | 4 | 4 | W10
Weld | 5614 | Droit | 5 | 5 | W10
Weld | 5613 | Droit | 5 | 5 | W10
Weld | 5612 | Droit | 4 | 4 | W10
Weld | 5611 | Droit | 4 | 4 | W10
Weld | 5610 | Droit | 5 | 5 | W10
Weld | 5609 | Droit | 5 | 5 | W10
Weld | 5608 | Droit | 4 | 4 | W10
Weld | 5607 | Droit | 5 | 5 | W10
Weld | 5606 | Droit | 5 | 5 | W10
Weld | 5605 | Droit | 5 | 5 | W10
Weld | 5604 | Droit | 5 | 5 | W10
Weld | 5603 | Droit | 4 | 4 | W10
Weld | 5602 | Droit | 4 | 4 | W10
Weld | 5601 | Droit | 5 | 5 | W10
Weld | 5600 | Droit | 5 | 5 | W10
Weld | 5599 | Droit | 4 | 4 | W10
Weld | 5598 | Droit | 5 | 5 | W10
Weld | 5597 | Droit | 5 | 5 | W10
Weld | 5596 | Droit | 4 | 4 | W10
Weld | 5595 | Droit | 4 | 4 | W10
Weld | 5594 | Droit | 4 | 4 | W10
Weld | 5593 | Droit | 5 | 5 | W10
Weld | 5592 | Droit | 5 | 5 | W10
Weld | 5591 | Droit | 4 | 4 | W10
Weld | 5590 | Droit | 5 | 5 | W10
Weld | 5589 | Droit | 5 | 5 | W10
Weld | 5588 | Droit | 4 | 4 | W10
Weld | 5587 | Droit | 4 | 4 | W10
Weld | 5586 | Droit | 4 | 4 | W10
Weld | 5585 | Droit | 5 | 5 | W10
Weld | 5584 | Droit | 5 | 5 | W10
Weld | 5583 | Droit | 4 | 4 | W10
Weld | 5582 | Droit | 5 | 5 | W10
Weld | 5581 | Droit | 5 | 5 | W10
Weld | 5580 | Droit | 5 | 0 | Aucun
Weld | 5579 | Droit | 5 | 0 | Aucun
Weld | 5554 | Droit | 5 | 5 | W10
Weld | 5553 | Droit | 5 | 5 | W10
Weld | 5552 | Droit | 4 | 4 | W10
Weld | 5551 | Droit | 5 | 5 | W10
Weld | 5550 | Droit | 5 | 5 | W10
Weld | 5549 | Droit | 4 | 4 | W10
Weld | 5548 | Droit | 5 | 5 | W10
Weld | 5547 | Droit | 5 | 5 | W10
Weld | 5546 | Droit | 4 | 4 | W10
Weld | 5545 | Droit | 4 | 4 | W10
Weld | 5544 | Droit | 5 | 5 | W10
Weld | 5543 | Droit | 5 | 5 | W10
Weld | 5542 | Droit | 4 | 4 | W10
Weld | 5541 | Droit | 5 | 5 | W10
Weld | 5540 | Droit | 5 | 5 | W10
Weld | 5539 | Droit | 4 | 4 | W10
Weld | 5538 | Droit | 5 | 5 | W10
Weld | 5537 | Droit | 5 | 5 | W10
Weld | 5536 | Droit | 4 | 4 | W10
Weld | 5535 | Droit | 5 | 5 | W10
Weld | 5534 | Droit | 5 | 5 | W10
Weld | 5533 | Droit | 5 | 5 | W10
Weld | 5532 | Droit | 5 | 5 | W10
Weld | 5531 | Droit | 4 | 4 | W10
Weld | 5519 | Droit | 5 | 0 | Aucun
Weld | 5516 | Droit | 5 | 0 | Aucun
Weld | 5509 | Droit | 5 | 0 | Aucun
Weld | 5508 | Droit | 5 | 0 | Aucun
Weld | 5507 | Droit | 5 | 0 | Aucun
Weld | 5506 | Droit | 5 | 0 | Aucun
Weld | 5505 | Droit | 5 | 0 | Aucun
Weld | 5504 | Droit | 5 | 0 | Aucun
Weld | 5503 | Droit | 5 | 0 | Aucun
Weld | 5499 | Droit | 5 | 5 | W10
Weld | 5497 | Droit | 4 | 4 | W10
Weld | 5495 | Droit | 5 | 5 | W10
Weld | 5493 | Droit | 4 | 4 | W10
Weld | 5492 | Droit | 4 | 4 | W10
Weld | 5491 | Droit | 5 | 5 | W10
Weld | 5489 | Droit | 4 | 4 | W10
Weld | 5488 | Droit | 5 | 5 | W10
Weld | 5487 | Droit | 5 | 5 | W10
Weld | 5485 | Droit | 5 | 5 | W10
Weld | 5484 | Droit | 4 | 4 | W10
Weld | 5483 | Droit | 5 | 5 | W10
Weld | 5482 | Droit | 4 | 4 | W10
Weld | 5480 | Droit | 4 | 4 | W10
Weld | 5478 | Droit | 5 | 0 | Aucun
Weld | 5477 | Droit | 5 | 0 | Aucun
Weld | 5476 | Droit | 5 | 0 | Aucun
Weld | 5475 | Droit | 5 | 0 | Aucun
Weld | 5474 | Droit | 5 | 0 | Aucun
Weld | 5473 | Droit | 5 | 0 | Aucun
Weld | 5472 | Droit | 5 | 0 | Aucun
Weld | 5471 | Droit | 5 | 0 | Aucun
Weld | 5470 | Droit | 5 | 0 | Aucun
Weld | 5469 | Droit | 5 | 0 | Aucun
Weld | 5468 | Droit | 5 | 0 | Aucun
Weld | 5467 | Droit | 5 | 0 | Aucun
Weld | 5466 | Droit | 5 | 0 | Aucun
Weld | 5465 | Droit | 5 | 0 | Aucun
Weld | 5464 | Droit | 5 | 0 | Aucun
Weld | 5463 | Droit | 5 | 0 | Aucun
Weld | 5462 | Droit | 5 | 0 | Aucun
Weld | 5461 | Droit | 5 | 0 | Aucun
Weld | 5460 | Droit | 5 | 0 | Aucun
Weld | 5459 | Droit | 5 | 0 | Aucun
Weld | 5458 | Droit | 5 | 5 | W10
Weld | 5456 | Droit | 4 | 4 | W10
Weld | 5455 | Droit | 5 | 5 | W10
Weld | 5453 | Droit | 4 | 4 | W10
Weld | 5452 | Droit | 4 | 4 | W10
Weld | 5451 | Droit | 4 | 4 | W10
Weld | 5450 | Droit | 5 | 5 | W10
Weld | 5449 | Droit | 5 | 5 | W10
Weld | 5448 | Droit | 4 | 4 | W10
Weld | 5447 | Droit | 5 | 5 | W10
Weld | 5446 | Droit | 5 | 5 | W10
Weld | 5445 | Droit | 4 | 4 | W10
Weld | 5444 | Droit | 5 | 5 | W10
Weld | 5443 | Droit | 5 | 5 | W10
Weld | 5442 | Droit | 4 | 4 | W10
Weld | 5441 | Droit | 5 | 5 | W10
Weld | 5440 | Droit | 5 | 5 | W10
Weld | 5439 | Droit | 4 | 4 | W10
Weld | 5438 | Droit | 4 | 4 | W10
Weld | 5437 | Droit | 4 | 4 | W10
Weld | 5434 | Droit | 5 | 5 | W10
Weld | 5432 | Droit | 4 | 4 | W10
Weld | 5431 | Droit | 4 | 4 | W10
Weld | 5430 | Droit | 4 | 4 | W10
Weld | 5429 | Droit | 4 | 4 | W10
Weld | 5428 | Droit | 5 | 5 | W10
Weld | 5426 | Droit | 4 | 4 | W10
Weld | 5425 | Droit | 5 | 5 | W10
Weld | 5423 | Droit | 4 | 4 | W10
Weld | 5422 | Droit | 5 | 5 | W10
Weld | 5420 | Droit | 4 | 4 | W10
Weld | 5419 | Droit | 5 | 5 | W10
Weld | 5418 | Droit | 5 | 5 | W10
Weld | 5417 | Droit | 4 | 4 | W10
Weld | 5416 | Droit | 5 | 5 | W10
Weld | 5415 | Droit | 5 | 5 | W10
Weld | 5414 | Droit | 4 | 4 | W10
Weld | 5413 | Droit | 5 | 5 | W10
Weld | 5411 | Droit | 4 | 4 | W10
Weld | 5410 | Droit | 4 | 4 | W10
Weld | 5409 | Droit | 4 | 4 | W10
Weld | 5408 | Droit | 5 | 5 | W10
Weld | 5407 | Droit | 5 | 5 | W10
Weld | 5406 | Droit | 4 | 4 | W10
Weld | 5405 | Droit | 5 | 5 | W10
Weld | 5404 | Droit | 5 | 5 | W10
Weld | 5403 | Droit | 4 | 4 | W10
Weld | 5402 | Droit | 4 | 4 | W10
Weld | 5401 | Droit | 4 | 4 | W10
Weld | 5400 | Droit | 4 | 4 | W10
Weld | 5399 | Droit | 4 | 4 | W10
Weld | 5398 | Droit | 5 | 5 | W10
Weld | 5397 | Droit | 4 | 4 | W10
Weld | 5396 | Droit | 5 | 5 | W10
Weld | 5395 | Droit | 4 | 4 | W10
Weld | 5394 | Droit | 5 | 5 | W10
Weld | 5393 | Droit | 5 | 5 | W10
Weld | 5392 | Droit | 5 | 5 | W10
Weld | 5391 | Droit | 5 | 5 | W10
Weld | 5390 | Droit | 4 | 4 | W10
Weld | 5389 | Droit | 5 | 5 | W10
Weld | 5388 | Droit | 5 | 5 | W10
Weld | 5387 | Droit | 4 | 4 | W10
Weld | 5386 | Droit | 5 | 5 | W10
Weld | 5385 | Droit | 5 | 5 | W10
Weld | 5384 | Droit | 4 | 4 | W10
Weld | 5383 | Droit | 5 | 5 | W10
Weld | 5382 | Droit | 5 | 5 | W10
Weld | 5381 | Droit | 4 | 4 | W10
Weld | 5380 | Droit | 4 | 4 | W10
Weld | 5379 | Droit | 5 | 5 | W10
Weld | 5378 | Droit | 5 | 5 | W10
Weld | 5377 | Droit | 4 | 4 | W10
Weld | 5376 | Droit | 5 | 5 | W10
Weld | 5375 | Droit | 5 | 5 | W10
Weld | 5374 | Droit | 5 | 5 | W10
Weld | 5373 | Droit | 5 | 5 | W10
Weld | 5372 | Droit | 4 | 4 | W10
Weld | 5371 | Droit | 4 | 4 | W10
Weld | 5370 | Droit | 5 | 5 | W10
Weld | 5369 | Droit | 5 | 5 | W10
Weld | 5368 | Droit | 4 | 4 | W10
Weld | 5367 | Droit | 5 | 5 | W10
Weld | 5366 | Droit | 5 | 5 | W10
Weld | 5365 | Droit | 4 | 4 | W10
Weld | 5364 | Droit | 5 | 5 | W10
Weld | 5363 | Droit | 5 | 5 | W10
Weld | 5362 | Droit | 4 | 4 | W10
Weld | 5361 | Droit | 4 | 4 | W10
Weld | 5360 | Droit | 4 | 4 | W10
Weld | 5359 | Droit | 5 | 5 | W10
Weld | 5358 | Droit | 5 | 5 | W10
Weld | 5357 | Droit | 5 | 5 | W10
Weld | 5356 | Droit | 5 | 5 | W10
Weld | 5355 | Droit | 4 | 4 | W10
Weld | 5354 | Droit | 5 | 5 | W10
Weld | 5353 | Droit | 5 | 5 | W10
Weld | 5352 | Droit | 4 | 4 | W10
Weld | 5351 | Droit | 4 | 4 | W10
Weld | 5350 | Droit | 5 | 5 | W10
Weld | 5349 | Droit | 5 | 5 | W10
Weld | 5348 | Droit | 4 | 4 | W10
Weld | 5347 | Droit | 4 | 4 | W10
Weld | 5346 | Droit | 5 | 5 | W10
Weld | 5345 | Droit | 5 | 5 | W10
Weld | 5344 | Droit | 4 | 4 | W10
Weld | 5343 | Droit | 5 | 5 | W10
Weld | 5342 | Droit | 5 | 5 | W10
Weld | 5341 | Droit | 4 | 4 | W10
Weld | 5340 | Droit | 5 | 5 | W10
Weld | 5339 | Droit | 5 | 5 | W10
Weld | 5338 | Droit | 4 | 4 | W10
Weld | 5337 | Droit | 4 | 4 | W10
Weld | 5336 | Droit | 5 | 5 | W10
Weld | 5335 | Droit | 5 | 5 | W10
Weld | 5334 | Droit | 4 | 4 | W10
Weld | 5333 | Droit | 4 | 4 | W10
Weld | 5332 | Droit | 4 | 4 | W10
Weld | 5331 | Droit | 5 | 5 | W10
Weld | 5330 | Droit | 5 | 5 | W10
Weld | 5329 | Droit | 5 | 5 | W10
Weld | 5328 | Droit | 5 | 5 | W10
Weld | 5327 | Droit | 4 | 4 | W10
Weld | 5326 | Droit | 5 | 5 | W10
Weld | 5325 | Droit | 5 | 5 | W10
Weld | 5324 | Droit | 4 | 4 | W10
Weld | 5323 | Droit | 4 | 4 | W10
Weld | 5322 | Droit | 5 | 5 | W10
Weld | 5321 | Droit | 5 | 5 | W10
Weld | 5320 | Droit | 4 | 4 | W10
Weld | 5319 | Droit | 4 | 4 | W10
Weld | 5318 | Droit | 5 | 0 | Aucun
Weld | 5317 | Droit | 5 | 0 | Aucun
Weld | 5316 | Droit | 5 | 0 | Aucun
Weld | 5315 | Droit | 5 | 0 | Aucun
Weld | 5314 | Droit | 4 | 4 | W10
Weld | 5313 | Droit | 5 | 5 | W10
Weld | 5312 | Droit | 5 | 5 | W10
Weld | 5311 | Droit | 5 | 5 | W10
Weld | 5310 | Droit | 5 | 5 | W10
Weld | 5309 | Droit | 4 | 4 | W10
Weld | 5308 | Droit | 5 | 5 | W10
Weld | 5307 | Droit | 5 | 5 | W10
Weld | 5306 | Droit | 4 | 4 | W10
Weld | 5305 | Droit | 4 | 4 | W10
Weld | 5304 | Droit | 5 | 5 | W10
Weld | 5303 | Droit | 5 | 5 | W10
Weld | 5302 | Droit | 4 | 4 | W10
Weld | 5301 | Droit | 5 | 5 | W10
Weld | 5300 | Droit | 5 | 5 | W10
Weld | 5299 | Droit | 5 | 5 | W10
Weld | 5298 | Droit | 5 | 5 | W10
Weld | 5297 | Droit | 4 | 4 | W10
Weld | 5296 | Droit | 5 | 5 | W10
Weld | 5295 | Droit | 5 | 5 | W10
Weld | 5294 | Droit | 4 | 4 | W10
Weld | 5293 | Droit | 4 | 4 | W10
Weld | 5292 | Droit | 5 | 5 | W10
Weld | 5291 | Droit | 5 | 5 | W10
Weld | 5290 | Droit | 4 | 4 | W10
Weld | 5289 | Droit | 5 | 5 | W10
Weld | 5288 | Droit | 5 | 5 | W10
Weld | 5287 | Droit | 4 | 4 | W10
Weld | 5286 | Droit | 5 | 5 | W10
Weld | 5285 | Droit | 5 | 5 | W10
Weld | 5284 | Droit | 5 | 5 | W10
Weld | 5283 | Droit | 5 | 5 | W10
Weld | 5282 | Droit | 4 | 4 | W10
Weld | 5281 | Droit | 5 | 5 | W10
Weld | 5280 | Droit | 5 | 5 | W10
Weld | 5279 | Droit | 4 | 4 | W10
Weld | 5278 | Droit | 4 | 4 | W10
Weld | 5277 | Droit | 5 | 5 | W10
Weld | 5276 | Droit | 5 | 5 | W10
Weld | 5275 | Droit | 4 | 4 | W10
Weld | 5274 | Droit | 5 | 5 | W10
Weld | 5273 | Droit | 5 | 5 | W10
Weld | 5272 | Droit | 5 | 5 | W10
Weld | 5271 | Droit | 5 | 5 | W10
Weld | 5270 | Droit | 4 | 4 | W10
Weld | 5269 | Droit | 5 | 5 | W10
Weld | 5268 | Droit | 5 | 5 | W10
Weld | 5267 | Droit | 4 | 4 | W10
Weld | 5266 | Droit | 5 | 5 | W10
Weld | 5265 | Droit | 5 | 5 | W10
Weld | 5264 | Droit | 4 | 4 | W10
Weld | 5263 | Droit | 4 | 4 | W10
Weld | 5262 | Droit | 5 | 5 | W10
Weld | 5261 | Droit | 5 | 5 | W10
Weld | 5260 | Droit | 4 | 4 | W10
Weld | 5259 | Droit | 5 | 5 | W10
Weld | 5258 | Droit | 5 | 5 | W10
Weld | 5257 | Droit | 4 | 4 | W10
Weld | 5256 | Droit | 5 | 5 | W10
Weld | 5255 | Droit | 5 | 5 | W10
Weld | 5254 | Droit | 5 | 5 | W10
Weld | 5253 | Droit | 5 | 5 | W10
Weld | 5252 | Droit | 4 | 4 | W10
Weld | 5251 | Droit | 5 | 5 | W10
Weld | 5250 | Droit | 5 | 5 | W10
Weld | 5249 | Droit | 4 | 4 | W10
Weld | 5248 | Droit | 4 | 4 | W10
Weld | 5247 | Droit | 5 | 5 | W10
Weld | 5246 | Droit | 5 | 5 | W10
Weld | 5245 | Droit | 4 | 4 | W10
Weld | 5244 | Droit | 5 | 5 | W10
Weld | 5243 | Droit | 5 | 5 | W10
Weld | 5242 | Droit | 4 | 4 | W10
Weld | 5241 | Droit | 5 | 5 | W10
Weld | 5240 | Droit | 5 | 5 | W10
Weld | 5239 | Droit | 5 | 5 | W10
Weld | 5238 | Droit | 5 | 5 | W10
Weld | 5237 | Droit | 4 | 4 | W10
Weld | 5236 | Droit | 5 | 5 | W10
Weld | 5235 | Droit | 5 | 5 | W10
Weld | 5234 | Droit | 4 | 4 | W10
Weld | 5233 | Droit | 4 | 4 | W10
Weld | 5232 | Droit | 5 | 5 | W10
Weld | 5231 | Droit | 5 | 5 | W10
Weld | 5230 | Droit | 4 | 4 | W10
Weld | 5229 | Droit | 5 | 5 | W10
Weld | 5228 | Droit | 5 | 5 | W10
Weld | 5227 | Droit | 5 | 5 | W10
Weld | 5226 | Droit | 5 | 5 | W10
Weld | 5225 | Droit | 4 | 4 | W10
Weld | 5224 | Droit | 5 | 5 | W10
Weld | 5223 | Droit | 5 | 5 | W10
Weld | 5222 | Droit | 4 | 4 | W10
Weld | 5221 | Droit | 4 | 4 | W10
Weld | 5220 | Droit | 5 | 5 | W10
Weld | 5219 | Droit | 5 | 5 | W10
Weld | 5218 | Droit | 4 | 4 | W10
Weld | 5217 | Droit | 5 | 5 | W10
Weld | 5216 | Droit | 5 | 5 | W10
Weld | 5215 | Droit | 4 | 4 | W10
Weld | 5214 | Droit | 5 | 5 | W10
Weld | 5213 | Droit | 5 | 5 | W10
Weld | 5212 | Droit | 5 | 5 | W10
Weld | 5211 | Droit | 5 | 5 | W10
Weld | 5210 | Droit | 4 | 4 | W10
Weld | 5209 | Droit | 5 | 5 | W10
Weld | 5208 | Droit | 5 | 5 | W10
Weld | 5207 | Droit | 4 | 4 | W10
Weld | 5206 | Droit | 4 | 4 | W10
Weld | 5205 | Droit | 5 | 5 | W10
Weld | 5204 | Droit | 5 | 5 | W10
Weld | 5203 | Droit | 4 | 4 | W10
Weld | 5202 | Droit | 5 | 5 | W10
Weld | 5201 | Droit | 5 | 5 | W10
Weld | 5200 | Droit | 5 | 5 | W10
Weld | 5199 | Droit | 5 | 5 | W10
Weld | 5198 | Droit | 4 | 4 | W10
Weld | 5197 | Droit | 5 | 5 | W10
Weld | 5196 | Droit | 5 | 5 | W10
Weld | 5195 | Droit | 4 | 4 | W10
Weld | 5194 | Droit | 5 | 5 | W10
Weld | 5193 | Droit | 5 | 5 | W10
Weld | 5192 | Droit | 4 | 4 | W10
Weld | 5191 | Droit | 4 | 4 | W10
Weld | 5190 | Droit | 5 | 5 | W10
Weld | 5189 | Droit | 5 | 5 | W10
Weld | 5188 | Droit | 4 | 4 | W10
Weld | 5187 | Droit | 5 | 5 | W10
Weld | 5186 | Droit | 5 | 5 | W10
Weld | 5185 | Droit | 5 | 5 | W10
Weld | 5184 | Droit | 5 | 5 | W10
Weld | 5183 | Droit | 4 | 4 | W10
Weld | 5182 | Droit | 5 | 5 | W10
Weld | 5181 | Droit | 5 | 5 | W10
Weld | 5180 | Droit | 4 | 4 | W10
Weld | 5179 | Droit | 4 | 4 | W10
Weld | 5178 | Droit | 5 | 5 | W10
Weld | 5177 | Droit | 5 | 5 | W10
Weld | 5176 | Droit | 4 | 4 | W10
Weld | 5175 | Droit | 5 | 5 | W10
Weld | 5174 | Droit | 5 | 5 | W10
Weld | 5173 | Droit | 4 | 4 | W10
Weld | 5172 | Droit | 5 | 5 | W10
Weld | 5171 | Droit | 5 | 5 | W10
Weld | 5168 | Droit | 5 | 0 | Aucun
Weld | 5164 | Droit | 5 | 0 | Aucun
Weld | 5160 | Droit | 5 | 0 | Aucun
Weld | 5156 | Droit | 5 | 0 | Aucun
Weld | 5152 | Droit | 5 | 0 | Aucun
Weld | 5150 | Droit | 5 | 0 | Aucun
Weld | 5148 | Droit | 5 | 0 | Aucun
Weld | 5147 | Droit | 5 | 0 | Aucun
Weld | 5146 | Droit | 5 | 0 | Aucun
Weld | 5145 | Droit | 5 | 0 | Aucun
Weld | 5144 | Droit | 5 | 0 | Aucun
Weld | 5143 | Droit | 5 | 0 | Aucun
Weld | 5142 | Droit | 5 | 0 | Aucun
Weld | 5141 | Droit | 5 | 0 | Aucun
Weld | 5140 | Droit | 5 | 0 | Aucun
Weld | 5139 | Droit | 5 | 5 | W10
Weld | 5138 | Droit | 5 | 5 | W10
Weld | 5137 | Droit | 4 | 4 | W10
Weld | 5136 | Droit | 5 | 5 | W10
Weld | 5135 | Droit | 5 | 5 | W10
Weld | 5134 | Droit | 4 | 4 | W10
Weld | 5133 | Droit | 4 | 4 | W10
Weld | 5132 | Droit | 5 | 0 | Aucun
Weld | 5131 | Droit | 4 | 4 | W10
Weld | 5130 | Droit | 5 | 0 | Aucun
Weld | 5129 | Droit | 5 | 0 | Aucun
Weld | 5127 | Droit | 4 | 4 | W10
Weld | 5126 | Droit | 4 | 4 | W10
Weld | 5125 | Droit | 5 | 5 | W10
Weld | 5123 | Droit | 4 | 4 | W10
Weld | 5122 | Droit | 5 | 5 | W10
Weld | 5121 | Droit | 5 | 5 | W10
Weld | 5120 | Droit | 4 | 4 | W10
Weld | 5119 | Droit | 5 | 5 | W10
Weld | 5118 | Droit | 5 | 5 | W10
Weld | 5117 | Droit | 5 | 0 | Aucun
Weld | 5116 | Droit | 5 | 5 | W10
Weld | 5115 | Droit | 5 | 5 | W10
Weld | 5114 | Droit | 4 | 4 | W10
Weld | 5113 | Droit | 5 | 5 | W10
Weld | 5112 | Droit | 5 | 5 | W10
Weld | 5111 | Droit | 4 | 4 | W10
Weld | 5110 | Droit | 4 | 4 | W10
Weld | 5109 | Droit | 4 | 4 | W10
Weld | 5108 | Droit | 5 | 5 | W10
Weld | 5107 | Droit | 5 | 5 | W10
Weld | 5106 | Droit | 4 | 4 | W10
Weld | 5105 | Droit | 5 | 5 | W10
Weld | 5104 | Droit | 4 | 4 | W10
Weld | 5102 | Droit | 4 | 4 | W10
Weld | 5095 | Droit | 4 | 4 | W10
Weld | 5094 | Droit | 5 | 5 | W10
Weld | 5093 | Droit | 5 | 5 | W10
Weld | 5092 | Droit | 4 | 4 | W10
Weld | 5091 | Droit | 5 | 5 | W10
Weld | 5090 | Droit | 5 | 5 | W10
Weld | 5084 | Droit | 5 | 0 | Aucun
Weld | 5083 | Droit | 5 | 0 | Aucun
Weld | 5082 | Droit | 5 | 0 | Aucun
Weld | 5081 | Droit | 5 | 0 | Aucun
Weld | 5080 | Droit | 5 | 0 | Aucun
Weld | 5079 | Droit | 5 | 0 | Aucun
Weld | 5078 | Droit | 5 | 0 | Aucun
Weld | 5077 | Droit | 5 | 0 | Aucun
Weld | 5076 | Droit | 5 | 0 | Aucun
Weld | 5075 | Droit | 5 | 0 | Aucun
Weld | 5074 | Droit | 5 | 0 | Aucun
Weld | 5073 | Droit | 5 | 0 | Aucun
Weld | 5072 | Droit | 5 | 0 | Aucun
Weld | 5071 | Droit | 5 | 0 | Aucun
Weld | 5070 | Droit | 5 | 0 | Aucun
Weld | 5069 | Droit | 5 | 0 | Aucun
Weld | 5068 | Droit | 5 | 0 | Aucun
Weld | 5067 | Droit | 5 | 0 | Aucun
Weld | 5066 | Droit | 5 | 0 | Aucun
Weld | 5065 | Droit | 5 | 0 | Aucun
Weld | 5064 | Droit | 5 | 0 | Aucun
Weld | 5063 | Droit | 5 | 0 | Aucun
Weld | 5062 | Droit | 5 | 0 | Aucun
Weld | 5061 | Droit | 5 | 0 | Aucun
Weld | 5060 | Droit | 5 | 0 | Aucun
Weld | 5059 | Droit | 5 | 0 | Aucun
Weld | 5058 | Droit | 5 | 0 | Aucun
Weld | 5057 | Droit | 5 | 0 | Aucun
Weld | 5056 | Droit | 5 | 0 | Aucun
Weld | 5055 | Droit | 5 | 0 | Aucun
Weld | 5054 | Droit | 5 | 0 | Aucun
Weld | 5053 | Droit | 5 | 0 | Aucun
Weld | 5052 | Droit | 5 | 0 | Aucun
Weld | 5051 | Droit | 5 | 0 | Aucun
Weld | 5050 | Droit | 5 | 0 | Aucun
Weld | 5049 | Droit | 5 | 0 | Aucun
Weld | 5048 | Droit | 5 | 0 | Aucun
Weld | 5047 | Droit | 5 | 0 | Aucun
Weld | 5046 | Droit | 5 | 0 | Aucun
Weld | 5045 | Droit | 5 | 0 | Aucun
Weld | 5044 | Droit | 5 | 0 | Aucun
Weld | 5043 | Droit | 5 | 0 | Aucun
Weld | 5042 | Droit | 5 | 0 | Aucun
Weld | 5041 | Droit | 5 | 0 | Aucun
Weld | 5040 | Droit | 5 | 0 | Aucun
Weld | 5039 | Droit | 5 | 0 | Aucun
Weld | 5038 | Droit | 5 | 0 | Aucun
Weld | 5037 | Droit | 5 | 0 | Aucun
Weld | 5036 | Droit | 5 | 5 | W10
Weld | 5035 | Droit | 5 | 5 | W10
Weld | 5034 | Droit | 4 | 4 | W10
Weld | 5033 | Droit | 5 | 5 | W10
Weld | 5032 | Droit | 5 | 5 | W10
Weld | 5031 | Droit | 4 | 4 | W10
Weld | 5030 | Droit | 4 | 4 | W10
Weld | 5029 | Droit | 4 | 4 | W10
Weld | 5028 | Droit | 5 | 5 | W10
Weld | 5027 | Droit | 5 | 5 | W10
Weld | 5026 | Droit | 4 | 4 | W10
Weld | 5025 | Droit | 5 | 5 | W10
Weld | 5024 | Droit | 5 | 5 | W10
Weld | 5023 | Droit | 4 | 4 | W10
Weld | 5022 | Droit | 5 | 5 | W10
Weld | 5021 | Droit | 5 | 5 | W10
Weld | 5020 | Droit | 4 | 4 | W10
Weld | 5019 | Droit | 5 | 5 | W10
Weld | 5018 | Droit | 5 | 5 | W10
Weld | 5017 | Droit | 4 | 4 | W10
Weld | 5016 | Droit | 4 | 4 | W10
Weld | 5015 | Droit | 4 | 4 | W10
Weld | 5014 | Droit | 5 | 5 | W10
Weld | 5013 | Droit | 5 | 5 | W10
Weld | 5012 | Droit | 5 | 5 | W10
Weld | 5011 | Droit | 5 | 5 | W10
Weld | 5010 | Droit | 4 | 4 | W10
Weld | 5009 | Droit | 4 | 4 | W10
Weld | 5008 | Droit | 4 | 4 | W10
Weld | 5007 | Droit | 4 | 4 | W10
Weld | 5006 | Droit | 5 | 5 | W10
Weld | 5005 | Droit | 5 | 5 | W10
Weld | 5004 | Droit | 4 | 4 | W10
Weld | 5003 | Droit | 5 | 5 | W10
Weld | 5002 | Droit | 5 | 5 | W10
Weld | 5001 | Droit | 4 | 4 | W10
Weld | 5000 | Droit | 5 | 5 | W10
Weld | 4999 | Droit | 5 | 5 | W10
Weld | 4998 | Droit | 4 | 4 | W10
Weld | 4997 | Droit | 5 | 5 | W10
Weld | 4996 | Droit | 5 | 5 | W10
Weld | 4995 | Droit | 4 | 4 | W10
Weld | 4994 | Droit | 5 | 5 | W10
Weld | 4993 | Droit | 5 | 5 | W10
Weld | 4992 | Droit | 4 | 4 | W10
Weld | 4991 | Droit | 5 | 5 | W10
Weld | 4990 | Droit | 5 | 5 | W10
Weld | 4989 | Droit | 4 | 4 | W10
Weld | 4988 | Droit | 4 | 4 | W10
Weld | 4987 | Droit | 4 | 4 | W10
Weld | 4986 | Droit | 5 | 5 | W10
Weld | 4985 | Droit | 5 | 5 | W10
Weld | 4984 | Droit | 4 | 4 | W10
Weld | 4983 | Droit | 5 | 5 | W10
Weld | 4982 | Droit | 5 | 5 | W10
Weld | 4981 | Droit | 4 | 4 | W10
Weld | 4980 | Droit | 4 | 4 | W10
Weld | 4979 | Droit | 4 | 4 | W10
Weld | 4978 | Droit | 4 | 4 | W10
Weld | 4977 | Droit | 4 | 4 | W10
Weld | 4976 | Droit | 5 | 5 | W10
Weld | 4975 | Droit | 4 | 4 | W10
Weld | 4974 | Droit | 5 | 5 | W10
Weld | 4973 | Droit | 4 | 4 | W10
Weld | 4972 | Droit | 5 | 5 | W10
Weld | 4971 | Droit | 5 | 5 | W10
Weld | 4970 | Droit | 5 | 5 | W10
Weld | 4969 | Droit | 5 | 5 | W10
Weld | 4968 | Droit | 4 | 4 | W10
Weld | 4967 | Droit | 5 | 5 | W10
Weld | 4966 | Droit | 5 | 5 | W10
Weld | 4965 | Droit | 4 | 4 | W10
Weld | 4964 | Droit | 5 | 5 | W10
Weld | 4963 | Droit | 5 | 5 | W10
Weld | 4962 | Droit | 4 | 4 | W10
Weld | 4961 | Droit | 5 | 5 | W10
Weld | 4960 | Droit | 5 | 5 | W10
Weld | 4959 | Droit | 4 | 4 | W10
Weld | 4958 | Droit | 4 | 4 | W10
Weld | 4957 | Droit | 5 | 5 | W10
Weld | 4956 | Droit | 5 | 5 | W10
Weld | 4955 | Droit | 4 | 4 | W10
Weld | 4954 | Droit | 5 | 5 | W10
Weld | 4953 | Droit | 5 | 5 | W10
Weld | 4952 | Droit | 5 | 5 | W10
Weld | 4951 | Droit | 5 | 5 | W10
Weld | 4950 | Droit | 4 | 4 | W10
Weld | 4949 | Droit | 4 | 4 | W10
Weld | 4948 | Droit | 5 | 5 | W10
Weld | 4947 | Droit | 5 | 5 | W10
Weld | 4946 | Droit | 4 | 4 | W10
Weld | 4945 | Droit | 5 | 5 | W10
Weld | 4944 | Droit | 5 | 5 | W10
Weld | 4943 | Droit | 4 | 4 | W10
Weld | 4942 | Droit | 5 | 5 | W10
Weld | 4941 | Droit | 5 | 5 | W10
Weld | 4940 | Droit | 4 | 4 | W10
Weld | 4939 | Droit | 4 | 4 | W10
Weld | 4938 | Droit | 4 | 4 | W10
Weld | 4937 | Droit | 5 | 5 | W10
Weld | 4936 | Droit | 5 | 5 | W10
Weld | 4935 | Droit | 5 | 5 | W10
Weld | 4934 | Droit | 5 | 5 | W10
Weld | 4933 | Droit | 4 | 4 | W10
Weld | 4932 | Droit | 5 | 5 | W10
Weld | 4931 | Droit | 5 | 5 | W10
Weld | 4930 | Droit | 4 | 4 | W10
Weld | 4929 | Droit | 4 | 4 | W10
Weld | 4928 | Droit | 5 | 5 | W10
Weld | 4927 | Droit | 5 | 5 | W10
Weld | 4926 | Droit | 4 | 4 | W10
Weld | 4925 | Droit | 4 | 4 | W10
Weld | 4924 | Droit | 5 | 5 | W10
Weld | 4923 | Droit | 5 | 5 | W10
Weld | 4922 | Droit | 4 | 4 | W10
Weld | 4921 | Droit | 5 | 5 | W10
Weld | 4920 | Droit | 5 | 5 | W10
Weld | 4919 | Droit | 4 | 4 | W10
Weld | 4918 | Droit | 5 | 5 | W10
Weld | 4917 | Droit | 5 | 5 | W10
Weld | 4916 | Droit | 4 | 4 | W10
Weld | 4915 | Droit | 4 | 4 | W10
Weld | 4914 | Droit | 5 | 5 | W10
Weld | 4913 | Droit | 5 | 5 | W10
Weld | 4912 | Droit | 4 | 4 | W10
Weld | 4911 | Droit | 4 | 4 | W10
Weld | 4910 | Droit | 4 | 4 | W10
Weld | 4909 | Droit | 5 | 5 | W10
Weld | 4908 | Droit | 5 | 5 | W10
Weld | 4907 | Droit | 5 | 5 | W10
Weld | 4906 | Droit | 5 | 5 | W10
Weld | 4905 | Droit | 4 | 4 | W10
Weld | 4904 | Droit | 5 | 5 | W10
Weld | 4903 | Droit | 5 | 5 | W10
Weld | 4902 | Droit | 4 | 4 | W10
Weld | 4901 | Droit | 4 | 4 | W10
Weld | 4900 | Droit | 5 | 5 | W10
Weld | 4899 | Droit | 5 | 5 | W10
Weld | 4898 | Droit | 4 | 4 | W10
Weld | 4897 | Droit | 4 | 4 | W10
Weld | 4896 | Droit | 5 | 5 | W10
Weld | 4895 | Droit | 5 | 5 | W10
Weld | 4894 | Droit | 4 | 4 | W10
Weld | 4893 | Droit | 4 | 4 | W10
Weld | 4892 | Droit | 5 | 5 | W10
Weld | 4891 | Droit | 5 | 5 | W10
Weld | 4890 | Droit | 4 | 4 | W10
Weld | 4889 | Droit | 5 | 5 | W10
Weld | 4888 | Droit | 5 | 5 | W10
Weld | 4887 | Droit | 5 | 5 | W10
Weld | 4886 | Droit | 5 | 5 | W10
Weld | 4885 | Droit | 4 | 4 | W10
Weld | 4884 | Droit | 5 | 5 | W10
Weld | 4883 | Droit | 5 | 5 | W10
Weld | 4882 | Droit | 4 | 4 | W10
Weld | 4881 | Droit | 4 | 4 | W10
Weld | 4880 | Droit | 4 | 4 | W10
Weld | 4879 | Droit | 5 | 5 | W10
Weld | 4878 | Droit | 5 | 5 | W10
Weld | 4877 | Droit | 5 | 5 | W10
Weld | 4876 | Droit | 5 | 5 | W10
Weld | 4875 | Droit | 4 | 4 | W10
Weld | 4874 | Droit | 4 | 4 | W10
Weld | 4873 | Droit | 5 | 5 | W10
Weld | 4872 | Droit | 5 | 5 | W10
Weld | 4871 | Droit | 4 | 4 | W10
Weld | 4870 | Droit | 5 | 5 | W10
Weld | 4869 | Droit | 5 | 5 | W10
Weld | 4868 | Droit | 4 | 4 | W10
Weld | 4867 | Droit | 4 | 4 | W10
Weld | 4866 | Droit | 4 | 4 | W10
Weld | 4865 | Droit | 4 | 4 | W10
Weld | 4864 | Droit | 5 | 5 | W10
Weld | 4863 | Droit | 5 | 5 | W10
Weld | 4862 | Droit | 4 | 4 | W10
Weld | 4861 | Droit | 5 | 5 | W10
Weld | 4860 | Droit | 5 | 5 | W10
Weld | 4859 | Droit | 5 | 5 | W10
Weld | 4858 | Droit | 5 | 5 | W10
Weld | 4857 | Droit | 4 | 4 | W10
Weld | 4856 | Droit | 5 | 5 | W10
Weld | 4855 | Droit | 5 | 5 | W10
Weld | 4854 | Droit | 4 | 4 | W10
Weld | 4853 | Droit | 4 | 4 | W10
Weld | 4852 | Droit | 5 | 5 | W10
Weld | 4851 | Droit | 5 | 5 | W10
Weld | 4850 | Droit | 4 | 4 | W10
Weld | 4849 | Droit | 5 | 5 | W10
Weld | 4848 | Droit | 5 | 5 | W10
Weld | 4847 | Droit | 4 | 4 | W10
Weld | 4846 | Droit | 4 | 4 | W10
Weld | 4845 | Droit | 4 | 4 | W10
Weld | 4844 | Droit | 5 | 5 | W10
Weld | 4843 | Droit | 5 | 5 | W10
Weld | 4842 | Droit | 4 | 4 | W10
Weld | 4841 | Droit | 5 | 5 | W10
Weld | 4840 | Droit | 5 | 5 | W10
Weld | 4839 | Droit | 5 | 5 | W10
Weld | 4838 | Droit | 5 | 5 | W10
Weld | 4837 | Droit | 4 | 4 | W10
Weld | 4836 | Droit | 5 | 5 | W10
Weld | 4835 | Droit | 5 | 5 | W10
Weld | 4834 | Droit | 4 | 4 | W10
Weld | 4833 | Droit | 4 | 4 | W10
Weld | 4832 | Droit | 4 | 4 | W10
Weld | 4831 | Droit | 4 | 4 | W10
Weld | 4830 | Droit | 4 | 4 | W10
Weld | 4829 | Droit | 5 | 5 | W10
Weld | 4828 | Droit | 5 | 5 | W10
Weld | 4827 | Droit | 4 | 4 | W10
Weld | 4826 | Droit | 4 | 4 | W10
Weld | 4825 | Droit | 5 | 5 | W10
Weld | 4824 | Droit | 5 | 5 | W10
Weld | 4823 | Droit | 4 | 4 | W10
Weld | 4822 | Droit | 5 | 5 | W10
Weld | 4821 | Droit | 5 | 5 | W10
Weld | 4820 | Droit | 5 | 5 | W10
Weld | 4819 | Droit | 5 | 5 | W10
Weld | 4818 | Droit | 4 | 4 | W10
Weld | 4817 | Droit | 4 | 4 | W10
Weld | 4816 | Droit | 4 | 4 | W10
Weld | 4815 | Droit | 4 | 4 | W10
Weld | 4814 | Droit | 5 | 5 | W10
Weld | 4813 | Droit | 5 | 5 | W10
Weld | 4812 | Droit | 4 | 4 | W10
Weld | 4811 | Droit | 5 | 5 | W10
Weld | 4810 | Droit | 5 | 5 | W10
Weld | 4809 | Droit | 5 | 5 | W10
Weld | 4808 | Droit | 5 | 5 | W10
Weld | 4807 | Droit | 4 | 4 | W10
Weld | 4806 | Droit | 5 | 5 | W10
Weld | 4805 | Droit | 5 | 5 | W10
Weld | 4804 | Droit | 4 | 4 | W10
Weld | 4803 | Droit | 5 | 0 | Aucun
Weld | 4802 | Droit | 5 | 0 | Aucun
Weld | 4801 | Droit | 5 | 0 | Aucun
Weld | 4800 | Droit | 5 | 0 | Aucun
Weld | 4799 | Droit | 5 | 0 | Aucun
Weld | 4798 | Droit | 5 | 0 | Aucun
Weld | 4797 | Droit | 5 | 0 | Aucun
Weld | 4796 | Droit | 5 | 0 | Aucun
Weld | 4795 | Droit | 4 | 4 | W10
Weld | 4794 | Droit | 5 | 5 | W10
Weld | 4793 | Droit | 5 | 5 | W10
Weld | 4792 | Droit | 5 | 5 | W10
Weld | 4791 | Droit | 5 | 5 | W10
Weld | 4790 | Droit | 4 | 4 | W10
Weld | 4789 | Droit | 5 | 5 | W10
Weld | 4788 | Droit | 5 | 5 | W10
Weld | 4787 | Droit | 4 | 4 | W10
Weld | 4786 | Droit | 4 | 4 | W10
Weld | 4785 | Droit | 5 | 5 | W10
Weld | 4784 | Droit | 5 | 5 | W10
Weld | 4783 | Droit | 4 | 4 | W10
Weld | 4782 | Droit | 5 | 5 | W10
Weld | 4781 | Droit | 5 | 5 | W10
Weld | 4780 | Droit | 5 | 5 | W10
Weld | 4779 | Droit | 5 | 5 | W10
Weld | 4778 | Droit | 4 | 4 | W10
Weld | 4777 | Droit | 5 | 5 | W10
Weld | 4776 | Droit | 5 | 5 | W10
Weld | 4775 | Droit | 4 | 4 | W10
Weld | 4774 | Droit | 4 | 4 | W10
Weld | 4773 | Droit | 5 | 5 | W10
Weld | 4772 | Droit | 5 | 5 | W10
Weld | 4771 | Droit | 4 | 4 | W10
Weld | 4770 | Droit | 5 | 5 | W10
Weld | 4769 | Droit | 5 | 5 | W10
Weld | 4768 | Droit | 4 | 4 | W10
Weld | 4767 | Droit | 5 | 5 | W10
Weld | 4766 | Droit | 5 | 5 | W10
Weld | 4765 | Droit | 5 | 5 | W10
Weld | 4764 | Droit | 5 | 5 | W10
Weld | 4763 | Droit | 4 | 4 | W10
Weld | 4762 | Droit | 5 | 5 | W10
Weld | 4761 | Droit | 5 | 5 | W10
Weld | 4760 | Droit | 4 | 4 | W10
Weld | 4759 | Droit | 5 | 5 | W10
Weld | 4758 | Droit | 5 | 5 | W10
Weld | 4757 | Droit | 4 | 4 | W10
Weld | 4756 | Droit | 4 | 4 | W10
Weld | 4755 | Droit | 5 | 5 | W10
Weld | 4754 | Droit | 5 | 5 | W10
Weld | 4753 | Droit | 4 | 4 | W10
Weld | 4752 | Droit | 5 | 5 | W10
Weld | 4751 | Droit | 5 | 5 | W10
Weld | 4750 | Droit | 5 | 5 | W10
Weld | 4749 | Droit | 5 | 5 | W10
Weld | 4748 | Droit | 4 | 4 | W10
Weld | 4747 | Droit | 4 | 4 | W10
Weld | 4746 | Droit | 5 | 5 | W10
Weld | 4745 | Droit | 5 | 5 | W10
Weld | 4744 | Droit | 5 | 5 | W10
Weld | 4743 | Droit | 5 | 5 | W10
Weld | 4742 | Droit | 4 | 4 | W10
Weld | 4741 | Droit | 5 | 5 | W10
Weld | 4740 | Droit | 5 | 5 | W10
Weld | 4739 | Droit | 4 | 4 | W10
Weld | 4738 | Droit | 4 | 4 | W10
Weld | 4737 | Droit | 5 | 5 | W10
Weld | 4736 | Droit | 5 | 5 | W10
Weld | 4735 | Droit | 4 | 4 | W10
Weld | 4734 | Droit | 5 | 5 | W10
Weld | 4733 | Droit | 5 | 5 | W10
Weld | 4732 | Droit | 5 | 5 | W10
Weld | 4731 | Droit | 5 | 5 | W10
Weld | 4730 | Droit | 4 | 4 | W10
Weld | 4729 | Droit | 5 | 5 | W10
Weld | 4728 | Droit | 5 | 5 | W10
Weld | 4727 | Droit | 4 | 4 | W10
Weld | 4726 | Droit | 4 | 4 | W10
Weld | 4725 | Droit | 5 | 5 | W10
Weld | 4724 | Droit | 5 | 5 | W10
Weld | 4723 | Droit | 4 | 4 | W10
Weld | 4722 | Droit | 5 | 5 | W10
Weld | 4721 | Droit | 5 | 5 | W10
Weld | 4720 | Droit | 4 | 4 | W10
Weld | 4719 | Droit | 5 | 5 | W10
Weld | 4718 | Droit | 5 | 5 | W10
Weld | 4717 | Droit | 5 | 5 | W10
Weld | 4716 | Droit | 5 | 5 | W10
Weld | 4715 | Droit | 4 | 4 | W10
Weld | 4714 | Droit | 5 | 5 | W10
Weld | 4713 | Droit | 5 | 5 | W10
Weld | 4712 | Droit | 4 | 4 | W10
Weld | 4711 | Droit | 4 | 4 | W10
Weld | 4710 | Droit | 5 | 5 | W10
Weld | 4709 | Droit | 5 | 5 | W10
Weld | 4708 | Droit | 4 | 4 | W10
Weld | 4707 | Droit | 5 | 5 | W10
Weld | 4706 | Droit | 5 | 5 | W10
Weld | 4705 | Droit | 5 | 5 | W10
Weld | 4704 | Droit | 5 | 5 | W10
Weld | 4703 | Droit | 4 | 4 | W10
Weld | 4702 | Droit | 5 | 5 | W10
Weld | 4701 | Droit | 5 | 5 | W10
Weld | 4700 | Droit | 4 | 4 | W10
Weld | 4699 | Droit | 5 | 5 | W10
Weld | 4698 | Droit | 5 | 5 | W10
Weld | 4697 | Droit | 4 | 4 | W10
Weld | 4696 | Droit | 5 | 5 | W10
Weld | 4695 | Droit | 5 | 5 | W10
Weld | 4694 | Droit | 4 | 4 | W10
Weld | 4693 | Droit | 4 | 4 | W10
Weld | 4692 | Droit | 5 | 5 | W10
Weld | 4691 | Droit | 5 | 5 | W10
Weld | 4690 | Droit | 4 | 4 | W10
Weld | 4689 | Droit | 5 | 5 | W10
Weld | 4688 | Droit | 5 | 5 | W10
Weld | 4687 | Droit | 5 | 5 | W10
Weld | 4686 | Droit | 5 | 5 | W10
Weld | 4685 | Droit | 4 | 4 | W10
Weld | 4684 | Droit | 5 | 5 | W10
Weld | 4683 | Droit | 5 | 5 | W10
Weld | 4682 | Droit | 4 | 4 | W10
Weld | 4681 | Droit | 4 | 4 | W10
Weld | 4680 | Droit | 5 | 5 | W10
Weld | 4679 | Droit | 5 | 5 | W10
Weld | 4678 | Droit | 4 | 4 | W10
Weld | 4677 | Droit | 5 | 5 | W10
Weld | 4676 | Droit | 5 | 5 | W10
Weld | 4675 | Droit | 4 | 4 | W10
Weld | 4674 | Droit | 5 | 5 | W10
Weld | 4673 | Droit | 5 | 5 | W10
Weld | 4672 | Droit | 5 | 5 | W10
Weld | 4671 | Droit | 5 | 5 | W10
Weld | 4670 | Droit | 4 | 4 | W10
Weld | 4669 | Droit | 5 | 5 | W10
Weld | 4668 | Droit | 5 | 5 | W10
Weld | 4667 | Droit | 4 | 4 | W10
Weld | 4666 | Droit | 4 | 4 | W10
Weld | 4665 | Droit | 5 | 5 | W10
Weld | 4664 | Droit | 5 | 5 | W10
Weld | 4663 | Droit | 4 | 4 | W10
Weld | 4662 | Droit | 5 | 5 | W10
Weld | 4661 | Droit | 5 | 5 | W10
Weld | 4660 | Droit | 5 | 5 | W10
Weld | 4659 | Droit | 5 | 5 | W10
Weld | 4658 | Droit | 4 | 4 | W10
Weld | 4657 | Droit | 5 | 5 | W10
Weld | 4656 | Droit | 5 | 5 | W10
Weld | 4655 | Droit | 4 | 4 | W10
Weld | 4654 | Droit | 4 | 4 | W10
Weld | 4653 | Droit | 5 | 5 | W10
Weld | 4652 | Droit | 5 | 5 | W10
Weld | 4651 | Droit | 4 | 4 | W10
Weld | 4650 | Droit | 5 | 5 | W10
Weld | 4649 | Droit | 5 | 5 | W10
Weld | 4648 | Droit | 4 | 4 | W10
Weld | 4647 | Droit | 5 | 5 | W10
Weld | 4646 | Droit | 5 | 5 | W10
Weld | 4645 | Droit | 5 | 5 | W10
Weld | 4644 | Droit | 5 | 5 | W10
Weld | 4643 | Droit | 4 | 4 | W10
Weld | 4642 | Droit | 5 | 5 | W10
Weld | 4641 | Droit | 5 | 5 | W10
Weld | 4640 | Droit | 4 | 4 | W10
Weld | 4639 | Droit | 4 | 4 | W10
Weld | 4638 | Droit | 5 | 5 | W10
Weld | 4637 | Droit | 5 | 5 | W10
Weld | 4636 | Droit | 4 | 4 | W10
Weld | 4635 | Droit | 5 | 5 | W10
Weld | 4634 | Droit | 5 | 5 | W10
Weld | 4633 | Droit | 5 | 5 | W10
Weld | 4632 | Droit | 5 | 5 | W10
Weld | 4631 | Droit | 4 | 4 | W10
Weld | 4630 | Droit | 5 | 5 | W10
Weld | 4629 | Droit | 5 | 5 | W10
Weld | 4628 | Droit | 4 | 4 | W10
Weld | 4627 | Droit | 5 | 5 | W10
Weld | 4626 | Droit | 5 | 5 | W10
Weld | 4625 | Droit | 4 | 4 | W10
Weld | 4624 | Droit | 4 | 4 | W10
Weld | 4623 | Droit | 5 | 5 | W10
Weld | 4622 | Droit | 5 | 5 | W10
Weld | 4621 | Droit | 4 | 4 | W10
Weld | 4620 | Droit | 5 | 5 | W10
Weld | 4619 | Droit | 5 | 5 | W10
Weld | 4618 | Droit | 4 | 4 | W10
Weld | 4617 | Droit | 5 | 5 | W10
Weld | 4616 | Droit | 5 | 5 | W10
Weld | 4615 | Droit | 5 | 5 | W10
Weld | 4614 | Droit | 5 | 5 | W10
Weld | 4613 | Droit | 4 | 4 | W10
Weld | 4612 | Droit | 5 | 5 | W10
Weld | 4611 | Droit | 5 | 5 | W10
Weld | 4610 | Droit | 4 | 4 | W10
Weld | 4609 | Droit | 4 | 4 | W10
Weld | 4608 | Droit | 5 | 5 | W10
Weld | 4607 | Droit | 5 | 5 | W10
Weld | 4606 | Droit | 4 | 4 | W10
Weld | 4605 | Droit | 5 | 5 | W10
Weld | 4604 | Droit | 5 | 5 | W10
Weld | 4603 | Droit | 4 | 4 | W10
Weld | 4602 | Droit | 5 | 5 | W10
Weld | 4601 | Droit | 5 | 5 | W10
Weld | 4600 | Droit | 5 | 5 | W10
Weld | 4599 | Droit | 5 | 5 | W10
Weld | 4598 | Droit | 4 | 4 | W10
Weld | 4597 | Droit | 5 | 5 | W10
Weld | 4596 | Droit | 5 | 5 | W10
Weld | 4595 | Droit | 4 | 4 | W10
Weld | 4594 | Droit | 4 | 4 | W10
Weld | 4593 | Droit | 5 | 5 | W10
Weld | 4592 | Droit | 5 | 5 | W10
Weld | 4591 | Droit | 4 | 4 | W10
Weld | 4590 | Droit | 5 | 5 | W10
Weld | 4589 | Droit | 5 | 5 | W10
Weld | 4588 | Droit | 5 | 5 | W10
Weld | 4587 | Droit | 5 | 5 | W10
Weld | 4586 | Droit | 4 | 4 | W10
Weld | 4585 | Droit | 5 | 5 | W10
Weld | 4584 | Droit | 5 | 5 | W10
Weld | 4583 | Droit | 4 | 4 | W10
Weld | 4582 | Droit | 4 | 4 | W10
Weld | 4581 | Droit | 5 | 5 | W10
Weld | 4580 | Droit | 5 | 5 | W10
Weld | 4579 | Droit | 4 | 4 | W10
Weld | 4578 | Droit | 5 | 5 | W10
Weld | 4577 | Droit | 5 | 5 | W10
Weld | 4576 | Droit | 4 | 4 | W10
Weld | 4575 | Droit | 5 | 5 | W10
Weld | 4574 | Droit | 5 | 5 | W10
Weld | 4573 | Droit | 5 | 5 | W10
Weld | 4572 | Droit | 5 | 5 | W10
Weld | 4571 | Droit | 4 | 4 | W10
Weld | 4570 | Droit | 5 | 5 | W10
Weld | 4569 | Droit | 5 | 5 | W10
Weld | 4568 | Droit | 4 | 4 | W10
Weld | 4567 | Droit | 4 | 4 | W10
Weld | 4566 | Droit | 5 | 5 | W10
Weld | 4565 | Droit | 5 | 5 | W10
Weld | 4564 | Droit | 4 | 4 | W10
Weld | 4563 | Droit | 5 | 5 | W10
Weld | 4562 | Droit | 5 | 5 | W10
Weld | 4561 | Droit | 5 | 5 | W10
Weld | 4560 | Droit | 5 | 5 | W10
Weld | 4559 | Droit | 4 | 4 | W10
Weld | 4558 | Droit | 5 | 5 | W10
Weld | 4557 | Droit | 5 | 5 | W10
Weld | 4556 | Droit | 4 | 4 | W10
Weld | 4555 | Droit | 5 | 5 | W10
Weld | 4554 | Droit | 5 | 5 | W10
Weld | 4553 | Droit | 4 | 4 | W10
Weld | 4552 | Droit | 4 | 4 | W10
Weld | 4551 | Droit | 5 | 5 | W10
Weld | 4550 | Droit | 5 | 5 | W10
Weld | 4549 | Droit | 4 | 4 | W10
Weld | 4548 | Droit | 5 | 5 | W10
Weld | 4547 | Droit | 5 | 5 | W10
Weld | 4546 | Droit | 5 | 5 | W10
Weld | 4545 | Droit | 5 | 5 | W10
Weld | 4544 | Droit | 4 | 4 | W10
Weld | 4543 | Droit | 5 | 5 | W10
Weld | 4542 | Droit | 5 | 5 | W10
Weld | 4541 | Droit | 4 | 4 | W10
Weld | 4540 | Droit | 4 | 4 | W10
Weld | 4539 | Droit | 5 | 5 | W10
Weld | 4538 | Droit | 5 | 5 | W10
Weld | 4537 | Droit | 4 | 4 | W10
Weld | 4536 | Droit | 5 | 5 | W10
Weld | 4535 | Droit | 5 | 5 | W10
Weld | 4534 | Droit | 4 | 4 | W10
Weld | 4533 | Droit | 5 | 5 | W10
Weld | 4532 | Droit | 5 | 5 | W10
Weld | 4531 | Droit | 4 | 4 | W10
Weld | 4530 | Droit | 5 | 5 | W10
Weld | 4529 | Droit | 5 | 5 | W10
Weld | 4528 | Droit | 5 | 5 | W10
Weld | 4527 | Droit | 5 | 5 | W10
Weld | 4526 | Droit | 4 | 4 | W10
Weld | 4525 | Droit | 5 | 5 | W10
Weld | 4524 | Droit | 5 | 5 | W10
Weld | 4523 | Droit | 4 | 4 | W10
Weld | 4522 | Droit | 4 | 4 | W10
Weld | 4521 | Droit | 5 | 5 | W10
Weld | 4520 | Droit | 5 | 5 | W10
Weld | 4519 | Droit | 4 | 4 | W10
Weld | 4518 | Droit | 5 | 5 | W10
Weld | 4517 | Droit | 5 | 5 | W10
Weld | 4516 | Droit | 5 | 5 | W10
Weld | 4515 | Droit | 5 | 5 | W10
Weld | 4514 | Droit | 4 | 4 | W10
Weld | 4513 | Droit | 5 | 5 | W10
Weld | 4512 | Droit | 5 | 5 | W10
Weld | 4511 | Droit | 4 | 4 | W10
Weld | 4510 | Droit | 4 | 4 | W10
Weld | 4509 | Droit | 5 | 5 | W10
Weld | 4508 | Droit | 5 | 5 | W10
Weld | 4507 | Droit | 4 | 4 | W10
Weld | 4506 | Droit | 5 | 5 | W10
Weld | 4505 | Droit | 5 | 5 | W10
Weld | 4504 | Droit | 4 | 4 | W10
Weld | 4503 | Droit | 5 | 5 | W10
Weld | 4502 | Droit | 5 | 5 | W10
Weld | 4501 | Droit | 5 | 5 | W10
Weld | 4500 | Droit | 5 | 5 | W10
Weld | 4499 | Droit | 4 | 4 | W10
Weld | 4498 | Droit | 5 | 5 | W10
Weld | 4497 | Droit | 5 | 5 | W10
Weld | 4496 | Droit | 4 | 4 | W10
Weld | 4495 | Droit | 4 | 4 | W10
Weld | 4494 | Droit | 5 | 5 | W10
Weld | 4493 | Droit | 5 | 5 | W10
Weld | 4492 | Droit | 4 | 4 | W10
Weld | 4491 | Droit | 5 | 5 | W10
Weld | 4490 | Droit | 5 | 5 | W10
Weld | 4489 | Droit | 5 | 5 | W10
Weld | 4488 | Droit | 5 | 5 | W10
Weld | 4487 | Droit | 4 | 4 | W10
Weld | 4486 | Droit | 5 | 5 | W10
Weld | 4485 | Droit | 5 | 5 | W10
Weld | 4484 | Droit | 4 | 4 | W10
Weld | 4482 | Droit | 5 | 0 | Aucun
Weld | 4481 | Droit | 5 | 0 | Aucun
Weld | 4479 | Droit | 5 | 0 | Aucun
Weld | 4476 | Droit | 5 | 0 | Aucun
Weld | 4474 | Droit | 5 | 0 | Aucun
Weld | 4472 | Droit | 5 | 0 | Aucun
Weld | 4471 | Droit | 5 | 0 | Aucun
Weld | 4470 | Droit | 5 | 0 | Aucun
Weld | 4468 | Droit | 5 | 0 | Aucun
Weld | 4466 | Droit | 5 | 0 | Aucun
Weld | 4464 | Droit | 5 | 0 | Aucun
Weld | 4462 | Droit | 5 | 0 | Aucun
Weld | 4460 | Droit | 5 | 0 | Aucun
Weld | 4459 | Droit | 5 | 0 | Aucun
Weld | 4457 | Droit | 5 | 0 | Aucun
Weld | 4455 | Droit | 5 | 0 | Aucun
Weld | 4453 | Droit | 5 | 0 | Aucun
Weld | 4451 | Droit | 5 | 0 | Aucun
Weld | 4449 | Droit | 5 | 0 | Aucun
Weld | 4447 | Droit | 5 | 0 | Aucun
Weld | 4443 | Droit | 5 | 0 | Aucun
Weld | 4439 | Droit | 5 | 0 | Aucun
Weld | 4438 | Droit | 5 | 0 | Aucun
Weld | 4437 | Droit | 5 | 0 | Aucun
Weld | 4436 | Droit | 5 | 0 | Aucun
Weld | 4435 | Droit | 5 | 0 | Aucun
Weld | 4434 | Droit | 5 | 0 | Aucun
Weld | 4433 | Droit | 5 | 0 | Aucun
Weld | 4432 | Droit | 5 | 0 | Aucun
Weld | 4431 | Droit | 5 | 0 | Aucun
Weld | 4430 | Droit | 5 | 5 | W10
Weld | 4429 | Droit | 5 | 5 | W10
Weld | 4428 | Droit | 4 | 4 | W10
Weld | 4427 | Droit | 5 | 5 | W10
Weld | 4426 | Droit | 5 | 5 | W10
Weld | 4425 | Droit | 4 | 4 | W10
Weld | 4424 | Droit | 4 | 4 | W10
Weld | 4423 | Droit | 5 | 0 | Aucun
Weld | 4422 | Droit | 4 | 4 | W10
Weld | 4421 | Droit | 5 | 0 | Aucun
Weld | 4420 | Droit | 5 | 0 | Aucun
Weld | 4416 | Droit | 5 | 5 | W10
Weld | 4414 | Droit | 4 | 4 | W10
Weld | 4412 | Droit | 5 | 5 | W10
Weld | 4411 | Droit | 4 | 4 | W10
Weld | 4410 | Droit | 5 | 5 | W10
Weld | 4409 | Droit | 5 | 5 | W10
Weld | 4408 | Droit | 5 | 0 | Aucun
Weld | 4407 | Droit | 5 | 5 | W10
Weld | 4406 | Droit | 5 | 5 | W10
Weld | 4405 | Droit | 4 | 4 | W10
Weld | 4404 | Droit | 5 | 5 | W10
Weld | 4403 | Droit | 5 | 5 | W10
Weld | 4402 | Droit | 4 | 4 | W10
Weld | 4401 | Droit | 4 | 4 | W10
Weld | 4400 | Droit | 4 | 4 | W10
Weld | 4399 | Droit | 5 | 5 | W10
Weld | 4398 | Droit | 5 | 5 | W10
Weld | 4397 | Droit | 4 | 4 | W10
Weld | 4386 | Droit | 4 | 4 | W10
Weld | 4385 | Droit | 5 | 5 | W10
Weld | 4384 | Droit | 5 | 5 | W10
Weld | 4383 | Droit | 4 | 4 | W10
Weld | 4382 | Droit | 5 | 5 | W10
Weld | 4381 | Droit | 5 | 5 | W10
Weld | 4375 | Droit | 5 | 0 | Aucun
Weld | 4374 | Droit | 5 | 0 | Aucun
Weld | 4373 | Droit | 5 | 0 | Aucun
Weld | 4372 | Droit | 5 | 0 | Aucun
Weld | 4371 | Droit | 5 | 0 | Aucun
Weld | 4370 | Droit | 5 | 0 | Aucun
Weld | 4369 | Droit | 5 | 0 | Aucun
Weld | 4368 | Droit | 5 | 0 | Aucun
Weld | 4367 | Droit | 5 | 0 | Aucun
Weld | 4366 | Droit | 5 | 0 | Aucun
Weld | 4365 | Droit | 5 | 0 | Aucun
Weld | 4364 | Droit | 5 | 0 | Aucun
Weld | 4363 | Droit | 5 | 0 | Aucun
Weld | 4362 | Droit | 5 | 0 | Aucun
Weld | 4361 | Droit | 5 | 0 | Aucun
Weld | 4360 | Droit | 5 | 0 | Aucun
Weld | 4359 | Droit | 5 | 0 | Aucun
Weld | 4358 | Droit | 5 | 0 | Aucun
Weld | 4357 | Droit | 5 | 0 | Aucun
Weld | 4356 | Droit | 5 | 0 | Aucun
Weld | 4355 | Droit | 5 | 0 | Aucun
Weld | 4354 | Droit | 5 | 0 | Aucun
Weld | 4353 | Droit | 5 | 0 | Aucun
Weld | 4352 | Droit | 5 | 0 | Aucun
Weld | 4351 | Droit | 5 | 0 | Aucun
Weld | 4350 | Droit | 5 | 0 | Aucun
Weld | 4349 | Droit | 5 | 0 | Aucun
Weld | 4348 | Droit | 5 | 0 | Aucun
Weld | 4347 | Droit | 5 | 0 | Aucun
Weld | 4346 | Droit | 5 | 0 | Aucun
Weld | 4345 | Droit | 5 | 0 | Aucun
Weld | 4344 | Droit | 5 | 0 | Aucun
Weld | 4343 | Droit | 5 | 0 | Aucun
Weld | 4342 | Droit | 5 | 0 | Aucun
Weld | 4341 | Droit | 5 | 0 | Aucun
Weld | 4340 | Droit | 5 | 0 | Aucun
Weld | 4339 | Droit | 5 | 0 | Aucun
Weld | 4338 | Droit | 5 | 0 | Aucun
Weld | 4337 | Droit | 5 | 0 | Aucun
Weld | 4336 | Droit | 5 | 0 | Aucun
Weld | 4335 | Droit | 5 | 0 | Aucun
Weld | 4334 | Droit | 5 | 0 | Aucun
Weld | 4333 | Droit | 5 | 0 | Aucun
Weld | 4332 | Droit | 5 | 0 | Aucun
Weld | 4331 | Droit | 5 | 0 | Aucun
Weld | 4330 | Droit | 5 | 0 | Aucun
Weld | 4329 | Droit | 5 | 0 | Aucun
Weld | 4328 | Droit | 5 | 0 | Aucun
Weld | 4327 | Droit | 5 | 5 | W10
Weld | 4326 | Droit | 5 | 5 | W10
Weld | 4325 | Droit | 4 | 4 | W10
Weld | 4324 | Droit | 5 | 5 | W10
Weld | 4323 | Droit | 5 | 5 | W10
Weld | 4322 | Droit | 4 | 4 | W10
Weld | 4321 | Droit | 4 | 4 | W10
Weld | 4320 | Droit | 4 | 4 | W10
Weld | 4319 | Droit | 5 | 5 | W10
Weld | 4318 | Droit | 5 | 5 | W10
Weld | 4317 | Droit | 4 | 4 | W10
Weld | 4316 | Droit | 5 | 5 | W10
Weld | 4315 | Droit | 5 | 5 | W10
Weld | 4314 | Droit | 4 | 4 | W10
Weld | 4313 | Droit | 5 | 5 | W10
Weld | 4312 | Droit | 5 | 5 | W10
Weld | 4311 | Droit | 4 | 4 | W10
Weld | 4310 | Droit | 5 | 5 | W10
Weld | 4309 | Droit | 5 | 5 | W10
Weld | 4308 | Droit | 4 | 4 | W10
Weld | 4307 | Droit | 4 | 4 | W10
Weld | 4306 | Droit | 4 | 4 | W10
Weld | 4305 | Droit | 5 | 5 | W10
Weld | 4304 | Droit | 5 | 5 | W10
Weld | 4303 | Droit | 5 | 5 | W10
Weld | 4302 | Droit | 5 | 5 | W10
Weld | 4301 | Droit | 4 | 4 | W10
Weld | 4300 | Droit | 4 | 4 | W10
Weld | 4299 | Droit | 4 | 4 | W10
Weld | 4298 | Droit | 4 | 4 | W10
Weld | 4297 | Droit | 5 | 5 | W10
Weld | 4296 | Droit | 5 | 5 | W10
Weld | 4295 | Droit | 4 | 4 | W10
Weld | 4294 | Droit | 5 | 5 | W10
Weld | 4293 | Droit | 5 | 5 | W10
Weld | 4292 | Droit | 4 | 4 | W10
Weld | 4291 | Droit | 5 | 5 | W10
Weld | 4290 | Droit | 5 | 5 | W10
Weld | 4289 | Droit | 4 | 4 | W10
Weld | 4288 | Droit | 5 | 5 | W10
Weld | 4287 | Droit | 5 | 5 | W10
Weld | 4286 | Droit | 4 | 4 | W10
Weld | 4285 | Droit | 5 | 5 | W10
Weld | 4284 | Droit | 5 | 5 | W10
Weld | 4283 | Droit | 4 | 4 | W10
Weld | 4282 | Droit | 5 | 5 | W10
Weld | 4281 | Droit | 5 | 5 | W10
Weld | 4280 | Droit | 4 | 4 | W10
Weld | 4279 | Droit | 4 | 4 | W10
Weld | 4278 | Droit | 4 | 4 | W10
Weld | 4277 | Droit | 5 | 5 | W10
Weld | 4276 | Droit | 5 | 5 | W10
Weld | 4275 | Droit | 4 | 4 | W10
Weld | 4274 | Droit | 5 | 5 | W10
Weld | 4273 | Droit | 5 | 5 | W10
Weld | 4272 | Droit | 4 | 4 | W10
Weld | 4271 | Droit | 4 | 4 | W10
Weld | 4270 | Droit | 4 | 4 | W10
Weld | 4269 | Droit | 4 | 4 | W10
Weld | 4268 | Droit | 4 | 4 | W10
Weld | 4267 | Droit | 5 | 5 | W10
Weld | 4266 | Droit | 4 | 4 | W10
Weld | 4265 | Droit | 5 | 5 | W10
Weld | 4264 | Droit | 4 | 4 | W10
Weld | 4263 | Droit | 5 | 5 | W10
Weld | 4262 | Droit | 5 | 5 | W10
Weld | 4261 | Droit | 5 | 5 | W10
Weld | 4260 | Droit | 5 | 5 | W10
Weld | 4259 | Droit | 4 | 4 | W10
Weld | 4258 | Droit | 5 | 5 | W10
Weld | 4257 | Droit | 5 | 5 | W10
Weld | 4256 | Droit | 4 | 4 | W10
Weld | 4255 | Droit | 5 | 5 | W10
Weld | 4254 | Droit | 5 | 5 | W10
Weld | 4253 | Droit | 4 | 4 | W10
Weld | 4252 | Droit | 5 | 5 | W10
Weld | 4251 | Droit | 5 | 5 | W10
Weld | 4250 | Droit | 4 | 4 | W10
Weld | 4249 | Droit | 4 | 4 | W10
Weld | 4248 | Droit | 5 | 5 | W10
Weld | 4247 | Droit | 5 | 5 | W10
Weld | 4246 | Droit | 4 | 4 | W10
Weld | 4245 | Droit | 5 | 5 | W10
Weld | 4244 | Droit | 5 | 5 | W10
Weld | 4243 | Droit | 5 | 5 | W10
Weld | 4242 | Droit | 5 | 5 | W10
Weld | 4241 | Droit | 4 | 4 | W10
Weld | 4240 | Droit | 4 | 4 | W10
Weld | 4239 | Droit | 5 | 5 | W10
Weld | 4238 | Droit | 5 | 5 | W10
Weld | 4237 | Droit | 4 | 4 | W10
Weld | 4236 | Droit | 5 | 5 | W10
Weld | 4235 | Droit | 5 | 5 | W10
Weld | 4234 | Droit | 4 | 4 | W10
Weld | 4233 | Droit | 5 | 5 | W10
Weld | 4232 | Droit | 5 | 5 | W10
Weld | 4231 | Droit | 4 | 4 | W10
Weld | 4230 | Droit | 4 | 4 | W10
Weld | 4229 | Droit | 4 | 4 | W10
Weld | 4228 | Droit | 5 | 5 | W10
Weld | 4227 | Droit | 5 | 5 | W10
Weld | 4226 | Droit | 5 | 5 | W10
Weld | 4225 | Droit | 5 | 5 | W10
Weld | 4224 | Droit | 4 | 4 | W10
Weld | 4223 | Droit | 5 | 5 | W10
Weld | 4222 | Droit | 5 | 5 | W10
Weld | 4221 | Droit | 4 | 4 | W10
Weld | 4220 | Droit | 4 | 4 | W10
Weld | 4219 | Droit | 5 | 5 | W10
Weld | 4218 | Droit | 5 | 5 | W10
Weld | 4217 | Droit | 4 | 4 | W10
Weld | 4216 | Droit | 4 | 4 | W10
Weld | 4215 | Droit | 5 | 5 | W10
Weld | 4214 | Droit | 5 | 5 | W10
Weld | 4213 | Droit | 4 | 4 | W10
Weld | 4212 | Droit | 5 | 5 | W10
Weld | 4211 | Droit | 5 | 5 | W10
Weld | 4210 | Droit | 4 | 4 | W10
Weld | 4209 | Droit | 5 | 5 | W10
Weld | 4208 | Droit | 5 | 5 | W10
Weld | 4207 | Droit | 4 | 4 | W10
Weld | 4206 | Droit | 4 | 4 | W10
Weld | 4205 | Droit | 5 | 5 | W10
Weld | 4204 | Droit | 5 | 5 | W10
Weld | 4203 | Droit | 4 | 4 | W10
Weld | 4202 | Droit | 4 | 4 | W10
Weld | 4201 | Droit | 4 | 4 | W10
Weld | 4200 | Droit | 5 | 5 | W10
Weld | 4199 | Droit | 5 | 5 | W10
Weld | 4198 | Droit | 5 | 5 | W10
Weld | 4197 | Droit | 5 | 5 | W10
Weld | 4196 | Droit | 4 | 4 | W10
Weld | 4195 | Droit | 5 | 5 | W10
Weld | 4194 | Droit | 5 | 5 | W10
Weld | 4193 | Droit | 4 | 4 | W10
Weld | 4192 | Droit | 4 | 4 | W10
Weld | 4191 | Droit | 5 | 5 | W10
Weld | 4190 | Droit | 5 | 5 | W10
Weld | 4189 | Droit | 4 | 4 | W10
Weld | 4188 | Droit | 4 | 4 | W10
Weld | 4187 | Droit | 5 | 5 | W10
Weld | 4186 | Droit | 5 | 5 | W10
Weld | 4185 | Droit | 4 | 4 | W10
Weld | 4184 | Droit | 4 | 4 | W10
Weld | 4183 | Droit | 5 | 5 | W10
Weld | 4182 | Droit | 5 | 5 | W10
Weld | 4181 | Droit | 4 | 4 | W10
Weld | 4180 | Droit | 5 | 5 | W10
Weld | 4179 | Droit | 5 | 5 | W10
Weld | 4178 | Droit | 5 | 5 | W10
Weld | 4177 | Droit | 5 | 5 | W10
Weld | 4176 | Droit | 4 | 4 | W10
Weld | 4175 | Droit | 5 | 5 | W10
Weld | 4174 | Droit | 5 | 5 | W10
Weld | 4173 | Droit | 4 | 4 | W10
Weld | 4172 | Droit | 4 | 4 | W10
Weld | 4171 | Droit | 4 | 4 | W10
Weld | 4170 | Droit | 5 | 5 | W10
Weld | 4169 | Droit | 5 | 5 | W10
Weld | 4168 | Droit | 5 | 5 | W10
Weld | 4167 | Droit | 5 | 5 | W10
Weld | 4166 | Droit | 4 | 4 | W10
Weld | 4165 | Droit | 4 | 4 | W10
Weld | 4164 | Droit | 5 | 5 | W10
Weld | 4163 | Droit | 5 | 5 | W10
Weld | 4162 | Droit | 4 | 4 | W10
Weld | 4161 | Droit | 5 | 5 | W10
Weld | 4160 | Droit | 5 | 5 | W10
Weld | 4159 | Droit | 4 | 4 | W10
Weld | 4158 | Droit | 4 | 4 | W10
Weld | 4157 | Droit | 4 | 4 | W10
Weld | 4156 | Droit | 4 | 4 | W10
Weld | 4155 | Droit | 5 | 5 | W10
Weld | 4154 | Droit | 5 | 5 | W10
Weld | 4153 | Droit | 4 | 4 | W10
Weld | 4152 | Droit | 5 | 5 | W10
Weld | 4151 | Droit | 5 | 5 | W10
Weld | 4150 | Droit | 5 | 5 | W10
Weld | 4149 | Droit | 5 | 5 | W10
Weld | 4148 | Droit | 4 | 4 | W10
Weld | 4147 | Droit | 5 | 5 | W10
Weld | 4146 | Droit | 5 | 5 | W10
Weld | 4145 | Droit | 4 | 4 | W10
Weld | 4144 | Droit | 4 | 4 | W10
Weld | 4143 | Droit | 5 | 5 | W10
Weld | 4142 | Droit | 5 | 5 | W10
Weld | 4141 | Droit | 4 | 4 | W10
Weld | 4140 | Droit | 5 | 5 | W10
Weld | 4139 | Droit | 5 | 5 | W10
Weld | 4138 | Droit | 4 | 4 | W10
Weld | 4137 | Droit | 4 | 4 | W10
Weld | 4136 | Droit | 4 | 4 | W10
Weld | 4135 | Droit | 5 | 5 | W10
Weld | 4134 | Droit | 5 | 5 | W10
Weld | 4133 | Droit | 4 | 4 | W10
Weld | 4132 | Droit | 5 | 5 | W10
Weld | 4131 | Droit | 5 | 5 | W10
Weld | 4130 | Droit | 5 | 5 | W10
Weld | 4129 | Droit | 5 | 5 | W10
Weld | 4128 | Droit | 4 | 4 | W10
Weld | 4127 | Droit | 5 | 5 | W10
Weld | 4126 | Droit | 5 | 5 | W10
Weld | 4125 | Droit | 4 | 4 | W10
Weld | 4124 | Droit | 4 | 4 | W10
Weld | 4123 | Droit | 4 | 4 | W10
Weld | 4122 | Droit | 4 | 4 | W10
Weld | 4121 | Droit | 4 | 4 | W10
Weld | 4120 | Droit | 5 | 5 | W10
Weld | 4119 | Droit | 5 | 5 | W10
Weld | 4118 | Droit | 4 | 4 | W10
Weld | 4117 | Droit | 4 | 4 | W10
Weld | 4116 | Droit | 5 | 5 | W10
Weld | 4115 | Droit | 5 | 5 | W10
Weld | 4114 | Droit | 4 | 4 | W10
Weld | 4113 | Droit | 5 | 5 | W10
Weld | 4112 | Droit | 5 | 5 | W10
Weld | 4111 | Droit | 5 | 5 | W10
Weld | 4110 | Droit | 5 | 5 | W10
Weld | 4109 | Droit | 4 | 4 | W10
Weld | 4108 | Droit | 4 | 4 | W10
Weld | 4107 | Droit | 4 | 4 | W10
Weld | 4106 | Droit | 4 | 4 | W10
Weld | 4105 | Droit | 5 | 5 | W10
Weld | 4104 | Droit | 5 | 5 | W10
Weld | 4103 | Droit | 4 | 4 | W10
Weld | 4102 | Droit | 5 | 5 | W10
Weld | 4101 | Droit | 5 | 5 | W10
Weld | 4100 | Droit | 5 | 5 | W10
Weld | 4099 | Droit | 5 | 5 | W10
Weld | 4098 | Droit | 4 | 4 | W10
Weld | 4097 | Droit | 5 | 5 | W10
Weld | 4096 | Droit | 5 | 5 | W10
Weld | 4095 | Droit | 4 | 4 | W10
Weld | 4094 | Droit | 5 | 0 | Aucun
Weld | 4093 | Droit | 5 | 0 | Aucun
Weld | 4092 | Droit | 5 | 0 | Aucun
Weld | 4091 | Droit | 5 | 0 | Aucun
Weld | 4090 | Droit | 5 | 0 | Aucun
Weld | 4089 | Droit | 5 | 0 | Aucun
Weld | 4088 | Droit | 5 | 0 | Aucun
Weld | 4087 | Droit | 5 | 0 | Aucun
Weld | 4086 | Droit | 4 | 4 | W10
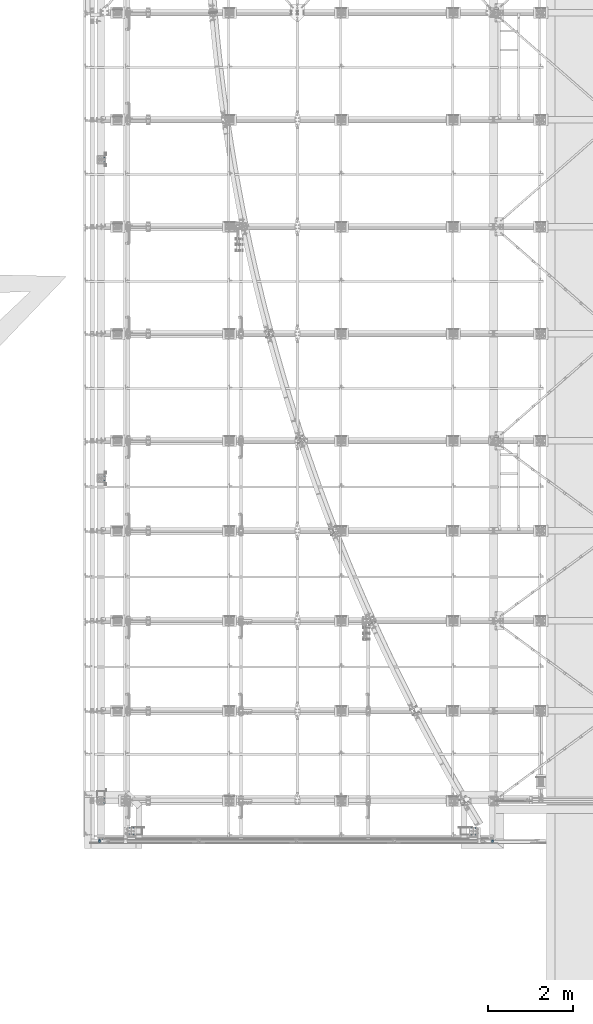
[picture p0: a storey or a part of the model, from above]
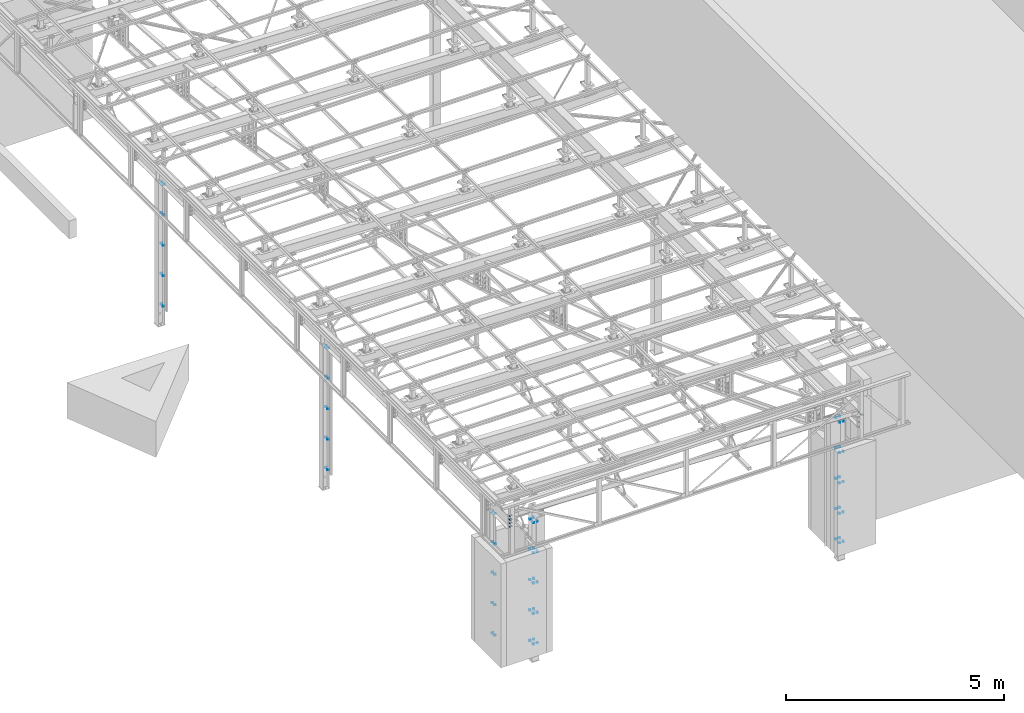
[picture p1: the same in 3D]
Properties of the parts of a building model (IFC2X3), part 10 of 13

# IfcFastener (6774)
Name | N° soudure | Linéaire/Périphérique | Dimension1 (mm) | Dimension2 (mm) | Type2
Weld | 4085 | Droit | 5 | 5 | W10
Weld | 4084 | Droit | 5 | 5 | W10
Weld | 4083 | Droit | 5 | 5 | W10
Weld | 4082 | Droit | 5 | 5 | W10
Weld | 4081 | Droit | 4 | 4 | W10
Weld | 4080 | Droit | 5 | 5 | W10
Weld | 4079 | Droit | 5 | 5 | W10
Weld | 4078 | Droit | 4 | 4 | W10
Weld | 4077 | Droit | 4 | 4 | W10
Weld | 4076 | Droit | 5 | 5 | W10
Weld | 4075 | Droit | 5 | 5 | W10
Weld | 4074 | Droit | 4 | 4 | W10
Weld | 4073 | Droit | 5 | 5 | W10
Weld | 4072 | Droit | 5 | 5 | W10
Weld | 4071 | Droit | 5 | 5 | W10
Weld | 4070 | Droit | 5 | 5 | W10
Weld | 4069 | Droit | 4 | 4 | W10
Weld | 4068 | Droit | 5 | 5 | W10
Weld | 4067 | Droit | 5 | 5 | W10
Weld | 4066 | Droit | 4 | 4 | W10
Weld | 4065 | Droit | 4 | 4 | W10
Weld | 4064 | Droit | 5 | 5 | W10
Weld | 4063 | Droit | 5 | 5 | W10
Weld | 4062 | Droit | 4 | 4 | W10
Weld | 4061 | Droit | 5 | 5 | W10
Weld | 4060 | Droit | 5 | 5 | W10
Weld | 4059 | Droit | 4 | 4 | W10
Weld | 4058 | Droit | 5 | 5 | W10
Weld | 4057 | Droit | 5 | 5 | W10
Weld | 4056 | Droit | 5 | 5 | W10
Weld | 4055 | Droit | 5 | 5 | W10
Weld | 4054 | Droit | 4 | 4 | W10
Weld | 4053 | Droit | 5 | 5 | W10
Weld | 4052 | Droit | 5 | 5 | W10
Weld | 4051 | Droit | 4 | 4 | W10
Weld | 4050 | Droit | 5 | 5 | W10
Weld | 4049 | Droit | 5 | 5 | W10
Weld | 4048 | Droit | 4 | 4 | W10
Weld | 4047 | Droit | 4 | 4 | W10
Weld | 4046 | Droit | 5 | 5 | W10
Weld | 4045 | Droit | 5 | 5 | W10
Weld | 4044 | Droit | 4 | 4 | W10
Weld | 4043 | Droit | 5 | 5 | W10
Weld | 4042 | Droit | 5 | 5 | W10
Weld | 4041 | Droit | 5 | 5 | W10
Weld | 4040 | Droit | 5 | 5 | W10
Weld | 4039 | Droit | 4 | 4 | W10
Weld | 4038 | Droit | 4 | 4 | W10
Weld | 4037 | Droit | 5 | 5 | W10
Weld | 4036 | Droit | 5 | 5 | W10
Weld | 4035 | Droit | 5 | 5 | W10
Weld | 4034 | Droit | 5 | 5 | W10
Weld | 4033 | Droit | 4 | 4 | W10
Weld | 4032 | Droit | 5 | 5 | W10
Weld | 4031 | Droit | 5 | 5 | W10
Weld | 4030 | Droit | 4 | 4 | W10
Weld | 4029 | Droit | 4 | 4 | W10
Weld | 4028 | Droit | 5 | 5 | W10
Weld | 4027 | Droit | 5 | 5 | W10
Weld | 4026 | Droit | 4 | 4 | W10
Weld | 4025 | Droit | 5 | 5 | W10
Weld | 4024 | Droit | 5 | 5 | W10
Weld | 4023 | Droit | 5 | 5 | W10
Weld | 4022 | Droit | 5 | 5 | W10
Weld | 4021 | Droit | 4 | 4 | W10
Weld | 4020 | Droit | 5 | 5 | W10
Weld | 4019 | Droit | 5 | 5 | W10
Weld | 4018 | Droit | 4 | 4 | W10
Weld | 4017 | Droit | 4 | 4 | W10
Weld | 4016 | Droit | 5 | 5 | W10
Weld | 4015 | Droit | 5 | 5 | W10
Weld | 4014 | Droit | 4 | 4 | W10
Weld | 4013 | Droit | 5 | 5 | W10
Weld | 4012 | Droit | 5 | 5 | W10
Weld | 4011 | Droit | 4 | 4 | W10
Weld | 4010 | Droit | 5 | 5 | W10
Weld | 4009 | Droit | 5 | 5 | W10
Weld | 4008 | Droit | 5 | 5 | W10
Weld | 4007 | Droit | 5 | 5 | W10
Weld | 4006 | Droit | 4 | 4 | W10
Weld | 4005 | Droit | 5 | 5 | W10
Weld | 4004 | Droit | 5 | 5 | W10
Weld | 4003 | Droit | 4 | 4 | W10
Weld | 4002 | Droit | 4 | 4 | W10
Weld | 4001 | Droit | 5 | 5 | W10
Weld | 4000 | Droit | 5 | 5 | W10
Weld | 3999 | Droit | 4 | 4 | W10
Weld | 3998 | Droit | 5 | 5 | W10
Weld | 3997 | Droit | 5 | 5 | W10
Weld | 3996 | Droit | 5 | 5 | W10
Weld | 3995 | Droit | 5 | 5 | W10
Weld | 3994 | Droit | 4 | 4 | W10
Weld | 3993 | Droit | 5 | 5 | W10
Weld | 3992 | Droit | 5 | 5 | W10
Weld | 3991 | Droit | 4 | 4 | W10
Weld | 3990 | Droit | 5 | 5 | W10
Weld | 3989 | Droit | 5 | 5 | W10
Weld | 3988 | Droit | 4 | 4 | W10
Weld | 3987 | Droit | 5 | 5 | W10
Weld | 3986 | Droit | 5 | 5 | W10
Weld | 3985 | Droit | 4 | 4 | W10
Weld | 3984 | Droit | 4 | 4 | W10
Weld | 3983 | Droit | 5 | 5 | W10
Weld | 3982 | Droit | 5 | 5 | W10
Weld | 3981 | Droit | 4 | 4 | W10
Weld | 3980 | Droit | 5 | 5 | W10
Weld | 3979 | Droit | 5 | 5 | W10
Weld | 3978 | Droit | 5 | 5 | W10
Weld | 3977 | Droit | 5 | 5 | W10
Weld | 3976 | Droit | 4 | 4 | W10
Weld | 3975 | Droit | 5 | 5 | W10
Weld | 3974 | Droit | 5 | 5 | W10
Weld | 3973 | Droit | 4 | 4 | W10
Weld | 3972 | Droit | 4 | 4 | W10
Weld | 3971 | Droit | 5 | 5 | W10
Weld | 3970 | Droit | 5 | 5 | W10
Weld | 3969 | Droit | 4 | 4 | W10
Weld | 3968 | Droit | 5 | 5 | W10
Weld | 3967 | Droit | 5 | 5 | W10
Weld | 3966 | Droit | 4 | 4 | W10
Weld | 3965 | Droit | 5 | 5 | W10
Weld | 3964 | Droit | 5 | 5 | W10
Weld | 3963 | Droit | 5 | 5 | W10
Weld | 3962 | Droit | 5 | 5 | W10
Weld | 3961 | Droit | 4 | 4 | W10
Weld | 3960 | Droit | 5 | 5 | W10
Weld | 3959 | Droit | 5 | 5 | W10
Weld | 3958 | Droit | 4 | 4 | W10
Weld | 3957 | Droit | 4 | 4 | W10
Weld | 3956 | Droit | 5 | 5 | W10
Weld | 3955 | Droit | 5 | 5 | W10
Weld | 3954 | Droit | 4 | 4 | W10
Weld | 3953 | Droit | 5 | 5 | W10
Weld | 3952 | Droit | 5 | 5 | W10
Weld | 3951 | Droit | 5 | 5 | W10
Weld | 3950 | Droit | 5 | 5 | W10
Weld | 3949 | Droit | 4 | 4 | W10
Weld | 3948 | Droit | 5 | 5 | W10
Weld | 3947 | Droit | 5 | 5 | W10
Weld | 3946 | Droit | 4 | 4 | W10
Weld | 3945 | Droit | 4 | 4 | W10
Weld | 3944 | Droit | 5 | 5 | W10
Weld | 3943 | Droit | 5 | 5 | W10
Weld | 3942 | Droit | 4 | 4 | W10
Weld | 3941 | Droit | 5 | 5 | W10
Weld | 3940 | Droit | 5 | 5 | W10
Weld | 3939 | Droit | 4 | 4 | W10
Weld | 3938 | Droit | 5 | 5 | W10
Weld | 3937 | Droit | 5 | 5 | W10
Weld | 3936 | Droit | 5 | 5 | W10
Weld | 3935 | Droit | 5 | 5 | W10
Weld | 3934 | Droit | 4 | 4 | W10
Weld | 3933 | Droit | 5 | 5 | W10
Weld | 3932 | Droit | 5 | 5 | W10
Weld | 3931 | Droit | 4 | 4 | W10
Weld | 3930 | Droit | 4 | 4 | W10
Weld | 3929 | Droit | 5 | 5 | W10
Weld | 3928 | Droit | 5 | 5 | W10
Weld | 3927 | Droit | 4 | 4 | W10
Weld | 3926 | Droit | 5 | 5 | W10
Weld | 3925 | Droit | 5 | 5 | W10
Weld | 3924 | Droit | 5 | 5 | W10
Weld | 3923 | Droit | 5 | 5 | W10
Weld | 3922 | Droit | 4 | 4 | W10
Weld | 3921 | Droit | 5 | 5 | W10
Weld | 3920 | Droit | 5 | 5 | W10
Weld | 3919 | Droit | 4 | 4 | W10
Weld | 3918 | Droit | 5 | 5 | W10
Weld | 3917 | Droit | 5 | 5 | W10
Weld | 3916 | Droit | 4 | 4 | W10
Weld | 3915 | Droit | 4 | 4 | W10
Weld | 3914 | Droit | 5 | 5 | W10
Weld | 3913 | Droit | 5 | 5 | W10
Weld | 3912 | Droit | 4 | 4 | W10
Weld | 3911 | Droit | 5 | 5 | W10
Weld | 3910 | Droit | 5 | 5 | W10
Weld | 3909 | Droit | 4 | 4 | W10
Weld | 3908 | Droit | 5 | 5 | W10
Weld | 3907 | Droit | 5 | 5 | W10
Weld | 3906 | Droit | 5 | 5 | W10
Weld | 3905 | Droit | 5 | 5 | W10
Weld | 3904 | Droit | 4 | 4 | W10
Weld | 3903 | Droit | 5 | 5 | W10
Weld | 3902 | Droit | 5 | 5 | W10
Weld | 3901 | Droit | 4 | 4 | W10
Weld | 3900 | Droit | 4 | 4 | W10
Weld | 3899 | Droit | 5 | 5 | W10
Weld | 3898 | Droit | 5 | 5 | W10
Weld | 3897 | Droit | 4 | 4 | W10
Weld | 3896 | Droit | 5 | 5 | W10
Weld | 3895 | Droit | 5 | 5 | W10
Weld | 3894 | Droit | 4 | 4 | W10
Weld | 3893 | Droit | 5 | 5 | W10
Weld | 3892 | Droit | 5 | 5 | W10
Weld | 3891 | Droit | 5 | 5 | W10
Weld | 3890 | Droit | 5 | 5 | W10
Weld | 3889 | Droit | 4 | 4 | W10
Weld | 3888 | Droit | 5 | 5 | W10
Weld | 3887 | Droit | 5 | 5 | W10
Weld | 3886 | Droit | 4 | 4 | W10
Weld | 3885 | Droit | 4 | 4 | W10
Weld | 3884 | Droit | 5 | 5 | W10
Weld | 3883 | Droit | 5 | 5 | W10
Weld | 3882 | Droit | 4 | 4 | W10
Weld | 3881 | Droit | 5 | 5 | W10
Weld | 3880 | Droit | 5 | 5 | W10
Weld | 3879 | Droit | 5 | 5 | W10
Weld | 3878 | Droit | 5 | 5 | W10
Weld | 3877 | Droit | 4 | 4 | W10
Weld | 3876 | Droit | 5 | 5 | W10
Weld | 3875 | Droit | 5 | 5 | W10
Weld | 3874 | Droit | 4 | 4 | W10
Weld | 3873 | Droit | 4 | 4 | W10
Weld | 3872 | Droit | 5 | 5 | W10
Weld | 3871 | Droit | 5 | 5 | W10
Weld | 3870 | Droit | 4 | 4 | W10
Weld | 3869 | Droit | 5 | 5 | W10
Weld | 3868 | Droit | 5 | 5 | W10
Weld | 3867 | Droit | 4 | 4 | W10
Weld | 3866 | Droit | 5 | 5 | W10
Weld | 3865 | Droit | 5 | 5 | W10
Weld | 3864 | Droit | 5 | 5 | W10
Weld | 3863 | Droit | 5 | 5 | W10
Weld | 3862 | Droit | 4 | 4 | W10
Weld | 3861 | Droit | 5 | 5 | W10
Weld | 3860 | Droit | 5 | 5 | W10
Weld | 3859 | Droit | 4 | 4 | W10
Weld | 3858 | Droit | 4 | 4 | W10
Weld | 3857 | Droit | 5 | 5 | W10
Weld | 3856 | Droit | 5 | 5 | W10
Weld | 3855 | Droit | 4 | 4 | W10
Weld | 3854 | Droit | 5 | 5 | W10
Weld | 3853 | Droit | 5 | 5 | W10
Weld | 3852 | Droit | 5 | 5 | W10
Weld | 3851 | Droit | 5 | 5 | W10
Weld | 3850 | Droit | 4 | 4 | W10
Weld | 3849 | Droit | 5 | 5 | W10
Weld | 3848 | Droit | 5 | 5 | W10
Weld | 3847 | Droit | 4 | 4 | W10
Weld | 3846 | Droit | 5 | 5 | W10
Weld | 3845 | Droit | 5 | 5 | W10
Weld | 3844 | Droit | 4 | 4 | W10
Weld | 3843 | Droit | 4 | 4 | W10
Weld | 3842 | Droit | 5 | 5 | W10
Weld | 3841 | Droit | 5 | 5 | W10
Weld | 3840 | Droit | 4 | 4 | W10
Weld | 3839 | Droit | 5 | 5 | W10
Weld | 3838 | Droit | 5 | 5 | W10
Weld | 3837 | Droit | 5 | 5 | W10
Weld | 3836 | Droit | 5 | 5 | W10
Weld | 3835 | Droit | 4 | 4 | W10
Weld | 3834 | Droit | 5 | 5 | W10
Weld | 3833 | Droit | 5 | 5 | W10
Weld | 3832 | Droit | 4 | 4 | W10
Weld | 3831 | Droit | 4 | 4 | W10
Weld | 3830 | Droit | 5 | 5 | W10
Weld | 3829 | Droit | 5 | 5 | W10
Weld | 3828 | Droit | 4 | 4 | W10
Weld | 3827 | Droit | 5 | 5 | W10
Weld | 3826 | Droit | 5 | 5 | W10
Weld | 3825 | Droit | 4 | 4 | W10
Weld | 3824 | Droit | 5 | 5 | W10
Weld | 3823 | Droit | 5 | 5 | W10
Weld | 3822 | Droit | 4 | 4 | W10
Weld | 3821 | Droit | 5 | 5 | W10
Weld | 3820 | Droit | 5 | 5 | W10
Weld | 3819 | Droit | 5 | 5 | W10
Weld | 3818 | Droit | 5 | 5 | W10
Weld | 3817 | Droit | 4 | 4 | W10
Weld | 3816 | Droit | 5 | 5 | W10
Weld | 3815 | Droit | 5 | 5 | W10
Weld | 3814 | Droit | 4 | 4 | W10
Weld | 3813 | Droit | 4 | 4 | W10
Weld | 3812 | Droit | 5 | 5 | W10
Weld | 3811 | Droit | 5 | 5 | W10
Weld | 3810 | Droit | 4 | 4 | W10
Weld | 3809 | Droit | 5 | 5 | W10
Weld | 3808 | Droit | 5 | 5 | W10
Weld | 3807 | Droit | 5 | 5 | W10
Weld | 3806 | Droit | 5 | 5 | W10
Weld | 3805 | Droit | 4 | 4 | W10
Weld | 3804 | Droit | 5 | 5 | W10
Weld | 3803 | Droit | 5 | 5 | W10
Weld | 3802 | Droit | 4 | 4 | W10
Weld | 3801 | Droit | 4 | 4 | W10
Weld | 3800 | Droit | 5 | 5 | W10
Weld | 3799 | Droit | 5 | 5 | W10
Weld | 3798 | Droit | 4 | 4 | W10
Weld | 3797 | Droit | 5 | 5 | W10
Weld | 3796 | Droit | 5 | 5 | W10
Weld | 3795 | Droit | 4 | 4 | W10
Weld | 3794 | Droit | 5 | 5 | W10
Weld | 3793 | Droit | 5 | 5 | W10
Weld | 3792 | Droit | 5 | 5 | W10
Weld | 3791 | Droit | 5 | 5 | W10
Weld | 3790 | Droit | 4 | 4 | W10
Weld | 3789 | Droit | 5 | 5 | W10
Weld | 3788 | Droit | 5 | 5 | W10
Weld | 3787 | Droit | 4 | 4 | W10
Weld | 3786 | Droit | 4 | 4 | W10
Weld | 3785 | Droit | 5 | 5 | W10
Weld | 3784 | Droit | 5 | 5 | W10
Weld | 3783 | Droit | 4 | 4 | W10
Weld | 3782 | Droit | 5 | 5 | W10
Weld | 3781 | Droit | 5 | 5 | W10
Weld | 3780 | Droit | 5 | 5 | W10
Weld | 3779 | Droit | 5 | 5 | W10
Weld | 3778 | Droit | 4 | 4 | W10
Weld | 3777 | Droit | 5 | 5 | W10
Weld | 3776 | Droit | 5 | 5 | W10
Weld | 3775 | Droit | 4 | 4 | W10
Weld | 3774 | Droit | 5 | 0 | Aucun
Weld | 3771 | Droit | 5 | 0 | Aucun
Weld | 3768 | Droit | 5 | 0 | Aucun
Weld | 3764 | Droit | 5 | 0 | Aucun
Weld | 3760 | Droit | 5 | 0 | Aucun
Weld | 3758 | Droit | 5 | 0 | Aucun
Weld | 3756 | Droit | 5 | 0 | Aucun
Weld | 3754 | Droit | 5 | 0 | Aucun
Weld | 3752 | Droit | 5 | 0 | Aucun
Weld | 3749 | Droit | 5 | 0 | Aucun
Weld | 3747 | Droit | 5 | 0 | Aucun
Weld | 3743 | Droit | 5 | 0 | Aucun
Weld | 3741 | Droit | 5 | 0 | Aucun
Weld | 3739 | Droit | 5 | 0 | Aucun
Weld | 3737 | Droit | 5 | 0 | Aucun
Weld | 3735 | Droit | 5 | 0 | Aucun
Weld | 3733 | Droit | 5 | 0 | Aucun
Weld | 3732 | Droit | 5 | 0 | Aucun
Weld | 3731 | Droit | 5 | 0 | Aucun
Weld | 3727 | Droit | 5 | 0 | Aucun
Weld | 3726 | Droit | 5 | 0 | Aucun
Weld | 3725 | Droit | 5 | 0 | Aucun
Weld | 3724 | Droit | 5 | 0 | Aucun
Weld | 3723 | Droit | 5 | 0 | Aucun
Weld | 3722 | Droit | 5 | 0 | Aucun
Weld | 3721 | Droit | 5 | 0 | Aucun
Weld | 3717 | Droit | 5 | 5 | W10
Weld | 3715 | Droit | 4 | 4 | W10
Weld | 3713 | Droit | 5 | 5 | W10
Weld | 3711 | Droit | 4 | 4 | W10
Weld | 3710 | Droit | 4 | 4 | W10
Weld | 3709 | Droit | 5 | 5 | W10
Weld | 3708 | Droit | 5 | 5 | W10
Weld | 3707 | Droit | 4 | 4 | W10
Weld | 3705 | Droit | 5 | 5 | W10
Weld | 3704 | Droit | 5 | 5 | W10
Weld | 3703 | Droit | 5 | 5 | W10
Weld | 3702 | Droit | 4 | 4 | W10
Weld | 3701 | Droit | 5 | 5 | W10
Weld | 3700 | Droit | 4 | 4 | W10
Weld | 3698 | Droit | 4 | 4 | W10
Weld | 3696 | Droit | 5 | 0 | Aucun
Weld | 3695 | Droit | 5 | 0 | Aucun
Weld | 3694 | Droit | 5 | 0 | Aucun
Weld | 3693 | Droit | 5 | 0 | Aucun
Weld | 3692 | Droit | 5 | 0 | Aucun
Weld | 3691 | Droit | 5 | 0 | Aucun
Weld | 3690 | Droit | 5 | 0 | Aucun
Weld | 3689 | Droit | 5 | 0 | Aucun
Weld | 3688 | Droit | 5 | 0 | Aucun
Weld | 3687 | Droit | 5 | 0 | Aucun
Weld | 3686 | Droit | 5 | 0 | Aucun
Weld | 3685 | Droit | 5 | 0 | Aucun
Weld | 3684 | Droit | 5 | 0 | Aucun
Weld | 3683 | Droit | 5 | 0 | Aucun
Weld | 3682 | Droit | 5 | 0 | Aucun
Weld | 3681 | Droit | 5 | 0 | Aucun
Weld | 3680 | Droit | 5 | 0 | Aucun
Weld | 3679 | Droit | 5 | 0 | Aucun
Weld | 3678 | Droit | 5 | 0 | Aucun
Weld | 3677 | Droit | 5 | 0 | Aucun
Weld | 3676 | Droit | 4 | 4 | W10
Weld | 3675 | Droit | 5 | 5 | W10
Weld | 3674 | Droit | 5 | 5 | W10
Weld | 3673 | Droit | 4 | 4 | W10
Weld | 3672 | Droit | 5 | 5 | W10
Weld | 3671 | Droit | 5 | 5 | W10
Weld | 3670 | Droit | 4 | 4 | W10
Weld | 3669 | Droit | 4 | 4 | W10
Weld | 3668 | Droit | 4 | 4 | W10
Weld | 3667 | Droit | 5 | 5 | W10
Weld | 3666 | Droit | 5 | 5 | W10
Weld | 3665 | Droit | 5 | 5 | W10
Weld | 3664 | Droit | 5 | 5 | W10
Weld | 3663 | Droit | 4 | 4 | W10
Weld | 3662 | Droit | 5 | 5 | W10
Weld | 3661 | Droit | 5 | 5 | W10
Weld | 3660 | Droit | 4 | 4 | W10
Weld | 3659 | Droit | 4 | 4 | W10
Weld | 3658 | Droit | 5 | 5 | W10
Weld | 3657 | Droit | 5 | 5 | W10
Weld | 3656 | Droit | 4 | 4 | W10
Weld | 3655 | Droit | 5 | 5 | W10
Weld | 3654 | Droit | 5 | 5 | W10
Weld | 3653 | Droit | 4 | 4 | W10
Weld | 3652 | Droit | 4 | 4 | W10
Weld | 3651 | Droit | 5 | 5 | W10
Weld | 3650 | Droit | 5 | 5 | W10
Weld | 3649 | Droit | 4 | 4 | W10
Weld | 3648 | Droit | 4 | 4 | W10
Weld | 3647 | Droit | 4 | 4 | W10
Weld | 3646 | Droit | 5 | 5 | W10
Weld | 3645 | Droit | 5 | 5 | W10
Weld | 3644 | Droit | 5 | 5 | W10
Weld | 3643 | Droit | 5 | 5 | W10
Weld | 3642 | Droit | 4 | 4 | W10
Weld | 3641 | Droit | 4 | 4 | W10
Weld | 3640 | Droit | 5 | 5 | W10
Weld | 3639 | Droit | 5 | 5 | W10
Weld | 3638 | Droit | 4 | 4 | W10
Weld | 3637 | Droit | 4 | 4 | W10
Weld | 3636 | Droit | 5 | 5 | W10
Weld | 3635 | Droit | 5 | 5 | W10
Weld | 3634 | Droit | 4 | 4 | W10
Weld | 3633 | Droit | 5 | 5 | W10
Weld | 3632 | Droit | 5 | 5 | W10
Weld | 3631 | Droit | 5 | 5 | W10
Weld | 3630 | Droit | 5 | 5 | W10
Weld | 3629 | Droit | 4 | 4 | W10
Weld | 3628 | Droit | 4 | 4 | W10
Weld | 3627 | Droit | 4 | 4 | W10
Weld | 3626 | Droit | 4 | 4 | W10
Weld | 3625 | Droit | 5 | 5 | W10
Weld | 3624 | Droit | 5 | 5 | W10
Weld | 3623 | Droit | 5 | 5 | W10
Weld | 3622 | Droit | 5 | 5 | W10
Weld | 3621 | Droit | 4 | 4 | W10
Weld | 3620 | Droit | 4 | 4 | W10
Weld | 3619 | Droit | 4 | 4 | W10
Weld | 3618 | Droit | 4 | 4 | W10
Weld | 3617 | Droit | 4 | 4 | W10
Weld | 3616 | Droit | 5 | 5 | W10
Weld | 3615 | Droit | 4 | 4 | W10
Weld | 3614 | Droit | 5 | 5 | W10
Weld | 3613 | Droit | 5 | 5 | W10
Weld | 3612 | Droit | 5 | 5 | W10
Weld | 3611 | Droit | 4 | 4 | W10
Weld | 3610 | Droit | 4 | 4 | W10
Weld | 3609 | Droit | 5 | 5 | W10
Weld | 3608 | Droit | 5 | 5 | W10
Weld | 3607 | Droit | 5 | 5 | W10
Weld | 3606 | Droit | 5 | 5 | W10
Weld | 3605 | Droit | 4 | 4 | W10
Weld | 3604 | Droit | 5 | 5 | W10
Weld | 3603 | Droit | 5 | 5 | W10
Weld | 3602 | Droit | 4 | 4 | W10
Weld | 3601 | Droit | 4 | 4 | W10
Weld | 3600 | Droit | 5 | 5 | W10
Weld | 3599 | Droit | 5 | 5 | W10
Weld | 3598 | Droit | 5 | 5 | W10
Weld | 3597 | Droit | 5 | 5 | W10
Weld | 3596 | Droit | 4 | 4 | W10
Weld | 3595 | Droit | 4 | 4 | W10
Weld | 3594 | Droit | 5 | 5 | W10
Weld | 3593 | Droit | 5 | 5 | W10
Weld | 3592 | Droit | 4 | 4 | W10
Weld | 3591 | Droit | 5 | 5 | W10
Weld | 3590 | Droit | 5 | 5 | W10
Weld | 3589 | Droit | 5 | 5 | W10
Weld | 3588 | Droit | 5 | 5 | W10
Weld | 3587 | Droit | 4 | 4 | W10
Weld | 3586 | Droit | 4 | 4 | W10
Weld | 3585 | Droit | 5 | 5 | W10
Weld | 3584 | Droit | 5 | 5 | W10
Weld | 3583 | Droit | 4 | 4 | W10
Weld | 3582 | Droit | 5 | 5 | W10
Weld | 3581 | Droit | 5 | 5 | W10
Weld | 3580 | Droit | 4 | 4 | W10
Weld | 3579 | Droit | 4 | 4 | W10
Weld | 3578 | Droit | 4 | 4 | W10
Weld | 3577 | Droit | 5 | 5 | W10
Weld | 3576 | Droit | 5 | 5 | W10
Weld | 3575 | Droit | 5 | 5 | W10
Weld | 3574 | Droit | 5 | 5 | W10
Weld | 3573 | Droit | 4 | 4 | W10
Weld | 3572 | Droit | 4 | 4 | W10
Weld | 3571 | Droit | 5 | 5 | W10
Weld | 3570 | Droit | 5 | 5 | W10
Weld | 3569 | Droit | 5 | 5 | W10
Weld | 3568 | Droit | 5 | 5 | W10
Weld | 3567 | Droit | 4 | 4 | W10
Weld | 3566 | Droit | 4 | 4 | W10
Weld | 3565 | Droit | 4 | 4 | W10
Weld | 3564 | Droit | 4 | 4 | W10
Weld | 3563 | Droit | 5 | 5 | W10
Weld | 3562 | Droit | 5 | 5 | W10
Weld | 3561 | Droit | 5 | 5 | W10
Weld | 3560 | Droit | 5 | 5 | W10
Weld | 3559 | Droit | 4 | 4 | W10
Weld | 3558 | Droit | 4 | 4 | W10
Weld | 3557 | Droit | 5 | 5 | W10
Weld | 3556 | Droit | 5 | 5 | W10
Weld | 3555 | Droit | 5 | 5 | W10
Weld | 3554 | Droit | 5 | 5 | W10
Weld | 3553 | Droit | 4 | 4 | W10
Weld | 3552 | Droit | 4 | 4 | W10
Weld | 3551 | Droit | 4 | 4 | W10
Weld | 3550 | Droit | 5 | 5 | W10
Weld | 3549 | Droit | 5 | 5 | W10
Weld | 3548 | Droit | 4 | 4 | W10
Weld | 3547 | Droit | 4 | 4 | W10
Weld | 3546 | Droit | 5 | 5 | W10
Weld | 3545 | Droit | 5 | 5 | W10
Weld | 3544 | Droit | 5 | 5 | W10
Weld | 3543 | Droit | 5 | 5 | W10
Weld | 3542 | Droit | 4 | 4 | W10
Weld | 3541 | Droit | 4 | 4 | W10
Weld | 3540 | Droit | 5 | 5 | W10
Weld | 3539 | Droit | 5 | 5 | W10
Weld | 3538 | Droit | 4 | 4 | W10
Weld | 3537 | Droit | 4 | 4 | W10
Weld | 3536 | Droit | 5 | 0 | Aucun
Weld | 3535 | Droit | 5 | 0 | Aucun
Weld | 3534 | Droit | 5 | 0 | Aucun
Weld | 3533 | Droit | 5 | 0 | Aucun
Weld | 3532 | Droit | 5 | 5 | W10
Weld | 3531 | Droit | 5 | 5 | W10
Weld | 3530 | Droit | 4 | 4 | W10
Weld | 3529 | Droit | 4 | 4 | W10
Weld | 3528 | Droit | 5 | 5 | W10
Weld | 3527 | Droit | 5 | 5 | W10
Weld | 3526 | Droit | 5 | 5 | W10
Weld | 3525 | Droit | 5 | 5 | W10
Weld | 3524 | Droit | 4 | 4 | W10
Weld | 3523 | Droit | 4 | 4 | W10
Weld | 3522 | Droit | 5 | 5 | W10
Weld | 3521 | Droit | 5 | 5 | W10
Weld | 3520 | Droit | 5 | 5 | W10
Weld | 3519 | Droit | 5 | 5 | W10
Weld | 3518 | Droit | 4 | 4 | W10
Weld | 3517 | Droit | 4 | 4 | W10
Weld | 3516 | Droit | 5 | 5 | W10
Weld | 3515 | Droit | 5 | 5 | W10
Weld | 3514 | Droit | 5 | 5 | W10
Weld | 3513 | Droit | 5 | 5 | W10
Weld | 3512 | Droit | 4 | 4 | W10
Weld | 3511 | Droit | 4 | 4 | W10
Weld | 3510 | Droit | 5 | 5 | W10
Weld | 3509 | Droit | 5 | 5 | W10
Weld | 3508 | Droit | 5 | 5 | W10
Weld | 3507 | Droit | 5 | 5 | W10
Weld | 3506 | Droit | 4 | 4 | W10
Weld | 3505 | Droit | 4 | 4 | W10
Weld | 3504 | Droit | 5 | 5 | W10
Weld | 3503 | Droit | 5 | 5 | W10
Weld | 3502 | Droit | 5 | 5 | W10
Weld | 3501 | Droit | 5 | 5 | W10
Weld | 3500 | Droit | 4 | 4 | W10
Weld | 3499 | Droit | 4 | 4 | W10
Weld | 3498 | Droit | 5 | 5 | W10
Weld | 3497 | Droit | 5 | 5 | W10
Weld | 3496 | Droit | 5 | 5 | W10
Weld | 3495 | Droit | 5 | 5 | W10
Weld | 3494 | Droit | 4 | 4 | W10
Weld | 3493 | Droit | 4 | 4 | W10
Weld | 3492 | Droit | 5 | 5 | W10
Weld | 3491 | Droit | 5 | 5 | W10
Weld | 3490 | Droit | 5 | 5 | W10
Weld | 3489 | Droit | 5 | 5 | W10
Weld | 3488 | Droit | 4 | 4 | W10
Weld | 3487 | Droit | 4 | 4 | W10
Weld | 3486 | Droit | 5 | 5 | W10
Weld | 3485 | Droit | 5 | 5 | W10
Weld | 3484 | Droit | 5 | 5 | W10
Weld | 3483 | Droit | 5 | 5 | W10
Weld | 3482 | Droit | 4 | 4 | W10
Weld | 3481 | Droit | 4 | 4 | W10
Weld | 3480 | Droit | 5 | 5 | W10
Weld | 3479 | Droit | 5 | 5 | W10
Weld | 3478 | Droit | 5 | 5 | W10
Weld | 3477 | Droit | 5 | 5 | W10
Weld | 3476 | Droit | 4 | 4 | W10
Weld | 3475 | Droit | 4 | 4 | W10
Weld | 3474 | Droit | 5 | 5 | W10
Weld | 3473 | Droit | 5 | 5 | W10
Weld | 3472 | Droit | 5 | 5 | W10
Weld | 3471 | Droit | 5 | 5 | W10
Weld | 3470 | Droit | 4 | 4 | W10
Weld | 3469 | Droit | 4 | 4 | W10
Weld | 3468 | Droit | 5 | 5 | W10
Weld | 3467 | Droit | 5 | 5 | W10
Weld | 3466 | Droit | 5 | 5 | W10
Weld | 3465 | Droit | 5 | 5 | W10
Weld | 3464 | Droit | 4 | 4 | W10
Weld | 3463 | Droit | 4 | 4 | W10
Weld | 3462 | Droit | 5 | 5 | W10
Weld | 3461 | Droit | 5 | 5 | W10
Weld | 3460 | Droit | 5 | 5 | W10
Weld | 3459 | Droit | 5 | 5 | W10
Weld | 3458 | Droit | 4 | 4 | W10
Weld | 3457 | Droit | 4 | 4 | W10
Weld | 3456 | Droit | 5 | 5 | W10
Weld | 3455 | Droit | 5 | 5 | W10
Weld | 3454 | Droit | 5 | 5 | W10
Weld | 3453 | Droit | 5 | 5 | W10
Weld | 3452 | Droit | 4 | 4 | W10
Weld | 3451 | Droit | 4 | 4 | W10
Weld | 3450 | Droit | 5 | 5 | W10
Weld | 3449 | Droit | 5 | 5 | W10
Weld | 3448 | Droit | 5 | 5 | W10
Weld | 3447 | Droit | 5 | 5 | W10
Weld | 3446 | Droit | 4 | 4 | W10
Weld | 3445 | Droit | 4 | 4 | W10
Weld | 3444 | Droit | 5 | 5 | W10
Weld | 3443 | Droit | 5 | 5 | W10
Weld | 3442 | Droit | 5 | 5 | W10
Weld | 3441 | Droit | 5 | 5 | W10
Weld | 3440 | Droit | 4 | 4 | W10
Weld | 3439 | Droit | 4 | 4 | W10
Weld | 3438 | Droit | 5 | 5 | W10
Weld | 3437 | Droit | 5 | 5 | W10
Weld | 3436 | Droit | 5 | 5 | W10
Weld | 3435 | Droit | 5 | 5 | W10
Weld | 3434 | Droit | 4 | 4 | W10
Weld | 3433 | Droit | 4 | 4 | W10
Weld | 3432 | Droit | 5 | 5 | W10
Weld | 3431 | Droit | 5 | 5 | W10
Weld | 3430 | Droit | 5 | 5 | W10
Weld | 3429 | Droit | 5 | 5 | W10
Weld | 3428 | Droit | 4 | 4 | W10
Weld | 3427 | Droit | 4 | 4 | W10
Weld | 3426 | Droit | 5 | 5 | W10
Weld | 3425 | Droit | 5 | 5 | W10
Weld | 3424 | Droit | 5 | 5 | W10
Weld | 3423 | Droit | 5 | 5 | W10
Weld | 3422 | Droit | 4 | 4 | W10
Weld | 3421 | Droit | 4 | 4 | W10
Weld | 3420 | Droit | 5 | 5 | W10
Weld | 3419 | Droit | 5 | 5 | W10
Weld | 3418 | Droit | 5 | 5 | W10
Weld | 3417 | Droit | 5 | 5 | W10
Weld | 3416 | Droit | 4 | 4 | W10
Weld | 3415 | Droit | 4 | 4 | W10
Weld | 3414 | Droit | 5 | 5 | W10
Weld | 3413 | Droit | 5 | 5 | W10
Weld | 3412 | Droit | 5 | 5 | W10
Weld | 3411 | Droit | 5 | 5 | W10
Weld | 3410 | Droit | 4 | 4 | W10
Weld | 3409 | Droit | 4 | 4 | W10
Weld | 3408 | Droit | 5 | 5 | W10
Weld | 3407 | Droit | 5 | 5 | W10
Weld | 3406 | Droit | 5 | 5 | W10
Weld | 3405 | Droit | 5 | 5 | W10
Weld | 3404 | Droit | 4 | 4 | W10
Weld | 3403 | Droit | 4 | 4 | W10
Weld | 3402 | Droit | 5 | 5 | W10
Weld | 3401 | Droit | 5 | 5 | W10
Weld | 3400 | Droit | 5 | 5 | W10
Weld | 3399 | Droit | 5 | 5 | W10
Weld | 3398 | Droit | 4 | 4 | W10
Weld | 3397 | Droit | 4 | 4 | W10
Weld | 3396 | Droit | 5 | 5 | W10
Weld | 3395 | Droit | 5 | 5 | W10
Weld | 3394 | Droit | 5 | 5 | W10
Weld | 3393 | Droit | 5 | 5 | W10
Weld | 3392 | Droit | 4 | 4 | W10
Weld | 3391 | Droit | 4 | 4 | W10
Weld | 3390 | Droit | 5 | 5 | W10
Weld | 3389 | Droit | 5 | 5 | W10
Weld | 3388 | Droit | 5 | 0 | Aucun
Weld | 3385 | Droit | 5 | 0 | Aucun
Weld | 3383 | Droit | 5 | 0 | Aucun
Weld | 3381 | Droit | 5 | 0 | Aucun
Weld | 3380 | Droit | 5 | 0 | Aucun
Weld | 3379 | Droit | 5 | 0 | Aucun
Weld | 3377 | Droit | 5 | 0 | Aucun
Weld | 3375 | Droit | 5 | 0 | Aucun
Weld | 3373 | Droit | 5 | 0 | Aucun
Weld | 3371 | Droit | 5 | 0 | Aucun
Weld | 3369 | Droit | 5 | 0 | Aucun
Weld | 3366 | Droit | 5 | 0 | Aucun
Weld | 3365 | Droit | 5 | 5 | W10
Weld | 3364 | Droit | 5 | 5 | W10
Weld | 3363 | Droit | 4 | 4 | W10
Weld | 3362 | Droit | 4 | 4 | W10
Weld | 3361 | Droit | 5 | 5 | W10
Weld | 3360 | Droit | 5 | 5 | W10
Weld | 3359 | Droit | 5 | 5 | W10
Weld | 3358 | Droit | 5 | 5 | W10
Weld | 3357 | Droit | 4 | 4 | W10
Weld | 3356 | Droit | 4 | 4 | W10
Weld | 3355 | Droit | 5 | 5 | W10
Weld | 3354 | Droit | 5 | 5 | W10
Weld | 3353 | Droit | 5 | 0 | Aucun
Weld | 3352 | Droit | 5 | 5 | W10
Weld | 3351 | Droit | 5 | 5 | W10
Weld | 3350 | Droit | 4 | 4 | W10
Weld | 3349 | Droit | 4 | 4 | W10
Weld | 3348 | Droit | 5 | 5 | W10
Weld | 3347 | Droit | 5 | 5 | W10
Weld | 3346 | Droit | 5 | 5 | W10
Weld | 3345 | Droit | 5 | 5 | W10
Weld | 3344 | Droit | 4 | 4 | W10
Weld | 3343 | Droit | 4 | 4 | W10
Weld | 3342 | Droit | 5 | 5 | W10
Weld | 3341 | Droit | 5 | 5 | W10
Weld | 3340 | Droit | 5 | 0 | Aucun
Weld | 3339 | Droit | 5 | 0 | Aucun
Weld | 3338 | Droit | 5 | 0 | Aucun
Weld | 3337 | Droit | 5 | 0 | Aucun
Weld | 3336 | Droit | 5 | 5 | W10
Weld | 3335 | Droit | 5 | 5 | W10
Weld | 3334 | Droit | 4 | 4 | W10
Weld | 3333 | Droit | 4 | 4 | W10
Weld | 3332 | Droit | 5 | 5 | W10
Weld | 3331 | Droit | 5 | 5 | W10
Weld | 3330 | Droit | 5 | 5 | W10
Weld | 3329 | Droit | 5 | 5 | W10
Weld | 3328 | Droit | 4 | 4 | W10
Weld | 3327 | Droit | 4 | 4 | W10
Weld | 3326 | Droit | 5 | 5 | W10
Weld | 3325 | Droit | 5 | 5 | W10
Weld | 3324 | Droit | 5 | 0 | Aucun
Weld | 3323 | Droit | 5 | 5 | W10
Weld | 3322 | Droit | 5 | 5 | W10
Weld | 3321 | Droit | 4 | 4 | W10
Weld | 3320 | Droit | 4 | 4 | W10
Weld | 3319 | Droit | 5 | 5 | W10
Weld | 3318 | Droit | 5 | 5 | W10
Weld | 3317 | Droit | 5 | 5 | W10
Weld | 3316 | Droit | 5 | 5 | W10
Weld | 3315 | Droit | 4 | 4 | W10
Weld | 3314 | Droit | 4 | 4 | W10
Weld | 3313 | Droit | 5 | 5 | W10
Weld | 3312 | Droit | 5 | 5 | W10
Weld | 3307 | Droit | 5 | 0 | Aucun
Weld | 3303 | Droit | 5 | 0 | Aucun
Weld | 3299 | Droit | 5 | 0 | Aucun
Weld | 3297 | Droit | 5 | 0 | Aucun
Weld | 3255 | Droit | 5 | 0 | Aucun
Weld | 3254 | Droit | 5 | 0 | Aucun
Weld | 3200 | Droit | 5 | 5 | W10
Weld | 3199 | Droit | 5 | 5 | W10
Weld | 3198 | Droit | 4 | 4 | W10
Weld | 3197 | Droit | 4 | 4 | W10
Weld | 3196 | Droit | 5 | 5 | W10
Weld | 3195 | Droit | 5 | 5 | W10
Weld | 3194 | Droit | 5 | 5 | W10
Weld | 3193 | Droit | 5 | 5 | W10
Weld | 3192 | Droit | 4 | 4 | W10
Weld | 3191 | Droit | 4 | 4 | W10
Weld | 3190 | Droit | 5 | 5 | W10
Weld | 3189 | Droit | 5 | 5 | W10
Weld | 3188 | Droit | 5 | 0 | Aucun
Weld | 3187 | Droit | 5 | 0 | Aucun
Weld | 3186 | Droit | 5 | 5 | W10
Weld | 3185 | Droit | 5 | 5 | W10
Weld | 3184 | Droit | 4 | 4 | W10
Weld | 3183 | Droit | 4 | 4 | W10
Weld | 3182 | Droit | 5 | 5 | W10
Weld | 3181 | Droit | 5 | 5 | W10
Weld | 3180 | Droit | 5 | 5 | W10
Weld | 3179 | Droit | 5 | 5 | W10
Weld | 3178 | Droit | 4 | 4 | W10
Weld | 3177 | Droit | 4 | 4 | W10
Weld | 3176 | Droit | 5 | 5 | W10
Weld | 3175 | Droit | 5 | 5 | W10
Weld | 3174 | Droit | 5 | 0 | Aucun
Weld | 3173 | Droit | 5 | 5 | W10
Weld | 3172 | Droit | 5 | 5 | W10
Weld | 3171 | Droit | 4 | 4 | W10
Weld | 3170 | Droit | 4 | 4 | W10
Weld | 3169 | Droit | 5 | 5 | W10
Weld | 3168 | Droit | 5 | 5 | W10
Weld | 3167 | Droit | 5 | 5 | W10
Weld | 3166 | Droit | 5 | 5 | W10
Weld | 3165 | Droit | 4 | 4 | W10
Weld | 3164 | Droit | 4 | 4 | W10
Weld | 3163 | Droit | 5 | 5 | W10
Weld | 3162 | Droit | 5 | 5 | W10
Weld | 3161 | Droit | 5 | 5 | W10
Weld | 3160 | Droit | 5 | 5 | W10
Weld | 3159 | Droit | 4 | 4 | W10
Weld | 3158 | Droit | 4 | 4 | W10
Weld | 3157 | Droit | 5 | 5 | W10
Weld | 3156 | Droit | 5 | 5 | W10
Weld | 3155 | Droit | 5 | 5 | W10
Weld | 3154 | Droit | 5 | 5 | W10
Weld | 3153 | Droit | 4 | 4 | W10
Weld | 3152 | Droit | 4 | 4 | W10
Weld | 3151 | Droit | 5 | 5 | W10
Weld | 3150 | Droit | 5 | 5 | W10
Weld | 3149 | Droit | 5 | 0 | Aucun
Weld | 3148 | Droit | 5 | 0 | Aucun
Weld | 3146 | Droit | 5 | 5 | W10
Weld | 3145 | Droit | 5 | 5 | W10
Weld | 3144 | Droit | 4 | 4 | W10
Weld | 3143 | Droit | 4 | 4 | W10
Weld | 3138 | Droit | 4 | 4 | W10
Weld | 3137 | Droit | 4 | 4 | W10
Weld | 3132 | Droit | 4 | 4 | W10
Weld | 3131 | Droit | 4 | 4 | W10
Weld | 3130 | Droit | 5 | 5 | W10
Weld | 3129 | Droit | 5 | 5 | W10
Weld | 3128 | Droit | 5 | 5 | W10
Weld | 3127 | Droit | 5 | 5 | W10
Weld | 3126 | Droit | 4 | 4 | W10
Weld | 3125 | Droit | 4 | 4 | W10
Weld | 3124 | Droit | 5 | 5 | W10
Weld | 3123 | Droit | 5 | 5 | W10
Weld | 3122 | Droit | 5 | 5 | W10
Weld | 3121 | Droit | 5 | 5 | W10
Weld | 3120 | Droit | 4 | 4 | W10
Weld | 3119 | Droit | 4 | 4 | W10
Weld | 3118 | Droit | 5 | 5 | W10
Weld | 3117 | Droit | 5 | 5 | W10
Weld | 3116 | Droit | 5 | 5 | W10
Weld | 3115 | Droit | 5 | 5 | W10
Weld | 3114 | Droit | 4 | 4 | W10
Weld | 3113 | Droit | 4 | 4 | W10
Weld | 3112 | Droit | 5 | 5 | W10
Weld | 3111 | Droit | 5 | 5 | W10
Weld | 3110 | Droit | 5 | 5 | W10
Weld | 3109 | Droit | 5 | 5 | W10
Weld | 3108 | Droit | 4 | 4 | W10
Weld | 3107 | Droit | 4 | 4 | W10
Weld | 3106 | Droit | 5 | 5 | W10
Weld | 3105 | Droit | 5 | 5 | W10
Weld | 3104 | Droit | 5 | 5 | W10
Weld | 3103 | Droit | 5 | 5 | W10
Weld | 3102 | Droit | 4 | 4 | W10
Weld | 3101 | Droit | 4 | 4 | W10
Weld | 3100 | Droit | 5 | 5 | W10
Weld | 3099 | Droit | 5 | 5 | W10
Weld | 3098 | Droit | 5 | 5 | W10
Weld | 3097 | Droit | 5 | 5 | W10
Weld | 3096 | Droit | 4 | 4 | W10
Weld | 3095 | Droit | 4 | 4 | W10
Weld | 3094 | Droit | 5 | 5 | W10
Weld | 3093 | Droit | 5 | 5 | W10
Weld | 3092 | Droit | 5 | 5 | W10
Weld | 3091 | Droit | 5 | 5 | W10
Weld | 3090 | Droit | 4 | 4 | W10
Weld | 3089 | Droit | 4 | 4 | W10
Weld | 3088 | Droit | 5 | 5 | W10
Weld | 3087 | Droit | 5 | 5 | W10
Weld | 3086 | Droit | 5 | 5 | W10
Weld | 3085 | Droit | 5 | 5 | W10
Weld | 3084 | Droit | 4 | 4 | W10
Weld | 3083 | Droit | 4 | 4 | W10
Weld | 3082 | Droit | 5 | 5 | W10
Weld | 3081 | Droit | 5 | 5 | W10
Weld | 3080 | Droit | 5 | 5 | W10
Weld | 3079 | Droit | 5 | 5 | W10
Weld | 3078 | Droit | 4 | 4 | W10
Weld | 3077 | Droit | 4 | 4 | W10
Weld | 3076 | Droit | 5 | 5 | W10
Weld | 3075 | Droit | 5 | 5 | W10
Weld | 3074 | Droit | 5 | 5 | W10
Weld | 3073 | Droit | 5 | 5 | W10
Weld | 3072 | Droit | 4 | 4 | W10
Weld | 3071 | Droit | 4 | 4 | W10
Weld | 3070 | Droit | 5 | 5 | W10
Weld | 3069 | Droit | 5 | 5 | W10
Weld | 3068 | Droit | 5 | 5 | W10
Weld | 3067 | Droit | 5 | 5 | W10
Weld | 3066 | Droit | 4 | 4 | W10
Weld | 3065 | Droit | 4 | 4 | W10
Weld | 3064 | Droit | 5 | 5 | W10
Weld | 3063 | Droit | 5 | 5 | W10
Weld | 3062 | Droit | 5 | 5 | W10
Weld | 3061 | Droit | 5 | 5 | W10
Weld | 3060 | Droit | 4 | 4 | W10
Weld | 3059 | Droit | 4 | 4 | W10
Weld | 3058 | Droit | 5 | 5 | W10
Weld | 3057 | Droit | 5 | 5 | W10
Weld | 3056 | Droit | 5 | 5 | W10
Weld | 3055 | Droit | 5 | 5 | W10
Weld | 3054 | Droit | 4 | 4 | W10
Weld | 3053 | Droit | 4 | 4 | W10
Weld | 3052 | Droit | 5 | 5 | W10
Weld | 3051 | Droit | 5 | 5 | W10
Weld | 3050 | Droit | 5 | 5 | W10
Weld | 3049 | Droit | 5 | 5 | W10
Weld | 3048 | Droit | 4 | 4 | W10
Weld | 3047 | Droit | 4 | 4 | W10
Weld | 3046 | Droit | 5 | 5 | W10
Weld | 3045 | Droit | 5 | 5 | W10
Weld | 3044 | Droit | 5 | 5 | W10
Weld | 3043 | Droit | 5 | 5 | W10
Weld | 3042 | Droit | 4 | 4 | W10
Weld | 3041 | Droit | 4 | 4 | W10
Weld | 3040 | Droit | 5 | 5 | W10
Weld | 3039 | Droit | 5 | 5 | W10
Weld | 3038 | Droit | 5 | 5 | W10
Weld | 3037 | Droit | 5 | 5 | W10
Weld | 3036 | Droit | 4 | 4 | W10
Weld | 3035 | Droit | 4 | 4 | W10
Weld | 3034 | Droit | 5 | 5 | W10
Weld | 3033 | Droit | 5 | 5 | W10
Weld | 3032 | Droit | 5 | 5 | W10
Weld | 3031 | Droit | 5 | 5 | W10
Weld | 3030 | Droit | 4 | 4 | W10
Weld | 3029 | Droit | 4 | 4 | W10
Weld | 3028 | Droit | 5 | 5 | W10
Weld | 3027 | Droit | 5 | 5 | W10
Weld | 3026 | Droit | 5 | 5 | W10
Weld | 3025 | Droit | 5 | 5 | W10
Weld | 3024 | Droit | 4 | 4 | W10
Weld | 3023 | Droit | 4 | 4 | W10
Weld | 3022 | Droit | 5 | 5 | W10
Weld | 3021 | Droit | 5 | 5 | W10
Weld | 3020 | Droit | 5 | 5 | W10
Weld | 3019 | Droit | 5 | 5 | W10
Weld | 3018 | Droit | 4 | 4 | W10
Weld | 3017 | Droit | 4 | 4 | W10
Weld | 3016 | Droit | 5 | 5 | W10
Weld | 3015 | Droit | 5 | 5 | W10
Weld | 3014 | Droit | 5 | 5 | W10
Weld | 3013 | Droit | 5 | 5 | W10
Weld | 3012 | Droit | 4 | 4 | W10
Weld | 3011 | Droit | 4 | 4 | W10
Weld | 3010 | Droit | 5 | 5 | W10
Weld | 3009 | Droit | 5 | 5 | W10
Weld | 3008 | Droit | 5 | 5 | W10
Weld | 3007 | Droit | 5 | 5 | W10
Weld | 3006 | Droit | 4 | 4 | W10
Weld | 3005 | Droit | 4 | 4 | W10
Weld | 3004 | Droit | 5 | 5 | W10
Weld | 3003 | Droit | 5 | 5 | W10
Weld | 3002 | Droit | 5 | 5 | W10
Weld | 3001 | Droit | 5 | 5 | W10
Weld | 3000 | Droit | 4 | 4 | W10
Weld | 2999 | Droit | 4 | 4 | W10
Weld | 2998 | Droit | 5 | 5 | W10
Weld | 2997 | Droit | 5 | 5 | W10
Weld | 2996 | Droit | 5 | 5 | W10
Weld | 2995 | Droit | 5 | 5 | W10
Weld | 2994 | Droit | 4 | 4 | W10
Weld | 2993 | Droit | 4 | 4 | W10
Weld | 2992 | Droit | 5 | 5 | W10
Weld | 2991 | Droit | 5 | 5 | W10
Weld | 2990 | Droit | 5 | 5 | W10
Weld | 2989 | Droit | 5 | 5 | W10
Weld | 2988 | Droit | 4 | 4 | W10
Weld | 2987 | Droit | 4 | 4 | W10
Weld | 2986 | Droit | 5 | 5 | W10
Weld | 2985 | Droit | 5 | 5 | W10
Weld | 2984 | Droit | 5 | 5 | W10
Weld | 2983 | Droit | 5 | 5 | W10
Weld | 2982 | Droit | 4 | 4 | W10
Weld | 2981 | Droit | 4 | 4 | W10
Weld | 2980 | Droit | 5 | 5 | W10
Weld | 2979 | Droit | 5 | 5 | W10
Weld | 2978 | Droit | 5 | 5 | W10
Weld | 2977 | Droit | 5 | 5 | W10
Weld | 2976 | Droit | 4 | 4 | W10
Weld | 2975 | Droit | 4 | 4 | W10
Weld | 2974 | Droit | 5 | 5 | W10
Weld | 2973 | Droit | 5 | 5 | W10
Weld | 2972 | Droit | 5 | 5 | W10
Weld | 2971 | Droit | 5 | 5 | W10
Weld | 2970 | Droit | 4 | 4 | W10
Weld | 2969 | Droit | 4 | 4 | W10
Weld | 2968 | Droit | 5 | 5 | W10
Weld | 2967 | Droit | 5 | 5 | W10
Weld | 2966 | Droit | 5 | 5 | W10
Weld | 2965 | Droit | 5 | 5 | W10
Weld | 2964 | Droit | 4 | 4 | W10
Weld | 2963 | Droit | 4 | 4 | W10
Weld | 2962 | Droit | 5 | 5 | W10
Weld | 2961 | Droit | 5 | 5 | W10
Weld | 2960 | Droit | 5 | 5 | W10
Weld | 2959 | Droit | 5 | 5 | W10
Weld | 2958 | Droit | 4 | 4 | W10
Weld | 2957 | Droit | 4 | 4 | W10
Weld | 2956 | Droit | 5 | 5 | W10
Weld | 2955 | Droit | 5 | 5 | W10
Weld | 2954 | Droit | 5 | 5 | W10
Weld | 2953 | Droit | 5 | 5 | W10
Weld | 2952 | Droit | 4 | 4 | W10
Weld | 2951 | Droit | 4 | 4 | W10
Weld | 2950 | Droit | 5 | 5 | W10
Weld | 2949 | Droit | 5 | 5 | W10
Weld | 2948 | Droit | 5 | 5 | W10
Weld | 2947 | Droit | 5 | 5 | W10
Weld | 2946 | Droit | 4 | 4 | W10
Weld | 2945 | Droit | 4 | 4 | W10
Weld | 2944 | Droit | 5 | 5 | W10
Weld | 2943 | Droit | 5 | 5 | W10
Weld | 2942 | Droit | 5 | 5 | W10
Weld | 2941 | Droit | 5 | 5 | W10
Weld | 2940 | Droit | 4 | 4 | W10
Weld | 2939 | Droit | 4 | 4 | W10
Weld | 2936 | Droit | 5 | 5 | W10
Weld | 2935 | Droit | 5 | 5 | W10
Weld | 2934 | Droit | 4 | 4 | W10
Weld | 2933 | Droit | 4 | 4 | W10
Weld | 2932 | Droit | 5 | 5 | W10
Weld | 2931 | Droit | 5 | 5 | W10
Weld | 2930 | Droit | 5 | 5 | W10
Weld | 2928 | Droit | 4 | 4 | W10
Weld | 2927 | Droit | 4 | 4 | W10
Weld | 2926 | Droit | 5 | 5 | W10
Weld | 2925 | Droit | 5 | 5 | W10
Weld | 2923 | Droit | 5 | 5 | W10
Weld | 2922 | Droit | 4 | 4 | W10
Weld | 2921 | Droit | 4 | 4 | W10
Weld | 2917 | Droit | 5 | 5 | W10
Weld | 2916 | Droit | 4 | 4 | W10
Weld | 2915 | Droit | 4 | 4 | W10
Weld | 2914 | Droit | 5 | 5 | W10
Weld | 2913 | Droit | 5 | 5 | W10
Weld | 2912 | Droit | 5 | 5 | W10
Weld | 2911 | Droit | 5 | 5 | W10
Weld | 2910 | Droit | 4 | 4 | W10
Weld | 2909 | Droit | 4 | 4 | W10
Weld | 2908 | Droit | 5 | 5 | W10
Weld | 2907 | Droit | 5 | 5 | W10
Weld | 2904 | Droit | 4 | 4 | W10
Weld | 2903 | Droit | 4 | 4 | W10
Weld | 2902 | Droit | 5 | 5 | W10
Weld | 2900 | Droit | 5 | 5 | W10
Weld | 2899 | Droit | 5 | 5 | W10
Weld | 2898 | Droit | 4 | 4 | W10
Weld | 2897 | Droit | 4 | 4 | W10
Weld | 2896 | Droit | 5 | 5 | W10
Weld | 2895 | Droit | 5 | 5 | W10
Weld | 2894 | Droit | 5 | 5 | W10
Weld | 2893 | Droit | 5 | 5 | W10
Weld | 2892 | Droit | 4 | 4 | W10
Weld | 2891 | Droit | 4 | 4 | W10
Weld | 2890 | Droit | 5 | 5 | W10
Weld | 2889 | Droit | 5 | 5 | W10
Weld | 2888 | Droit | 5 | 5 | W10
Weld | 2887 | Droit | 5 | 5 | W10
Weld | 2886 | Droit | 4 | 4 | W10
Weld | 2885 | Droit | 4 | 4 | W10
Weld | 2884 | Droit | 5 | 5 | W10
Weld | 2883 | Droit | 5 | 5 | W10
Weld | 2858 | Droit | 5 | 5 | W10
Weld | 2857 | Droit | 5 | 5 | W10
Weld | 2856 | Droit | 4 | 4 | W10
Weld | 2855 | Droit | 4 | 4 | W10
Weld | 2854 | Droit | 5 | 5 | W10
Weld | 2853 | Droit | 5 | 5 | W10
Weld | 2852 | Droit | 5 | 5 | W10
Weld | 2851 | Droit | 5 | 5 | W10
Weld | 2850 | Droit | 4 | 4 | W10
Weld | 2849 | Droit | 4 | 4 | W10
Weld | 2848 | Droit | 5 | 5 | W10
Weld | 2847 | Droit | 5 | 5 | W10
Weld | 2846 | Droit | 5 | 5 | W10
Weld | 2845 | Droit | 5 | 5 | W10
Weld | 2844 | Droit | 4 | 4 | W10
Weld | 2843 | Droit | 4 | 4 | W10
Weld | 2842 | Droit | 5 | 5 | W10
Weld | 2841 | Droit | 5 | 5 | W10
Weld | 2840 | Droit | 5 | 5 | W10
Weld | 2839 | Droit | 5 | 5 | W10
Weld | 2838 | Droit | 4 | 4 | W10
Weld | 2837 | Droit | 4 | 4 | W10
Weld | 2836 | Droit | 5 | 5 | W10
Weld | 2835 | Droit | 5 | 5 | W10
Weld | 2831 | Droit | 4 | 4 | W10
Weld | 2829 | Droit | 5 | 5 | W10
Weld | 2825 | Droit | 4 | 4 | W10
Weld | 2823 | Droit | 5 | 5 | W10
Weld | 2819 | Droit | 4 | 4 | W10
Weld | 2817 | Droit | 5 | 5 | W10
Weld | 2816 | Droit | 5 | 5 | W10
Weld | 2815 | Droit | 5 | 5 | W10
Weld | 2814 | Droit | 4 | 4 | W10
Weld | 2813 | Droit | 4 | 4 | W10
Weld | 2812 | Droit | 5 | 5 | W10
Weld | 2811 | Droit | 5 | 5 | W10
Weld | 2810 | Droit | 5 | 0 | Aucun
Weld | 2809 | Droit | 6 | 6 | W10
Weld | 2808 | Droit | 6 | 6 | W10
Weld | 2807 | Droit | 8 | 8 | W10
Weld | 2806 | Droit | 8 | 8 | W10
Weld | 2805 | Droit | 8 | 8 | W10
Weld | 2804 | Droit | 8 | 8 | W10
Weld | 2803 | Droit | 6 | 6 | W10
Weld | 2802 | Droit | 6 | 6 | W10
Weld | 2801 | Droit | 8 | 8 | W10
Weld | 2800 | Droit | 8 | 8 | W10
Weld | 2799 | Droit | 8 | 8 | W10
Weld | 2798 | Droit | 8 | 8 | W10
Weld | 2797 | Droit | 5 | 5 | W10
Weld | 2796 | Droit | 8 | 8 | W10
Weld | 2795 | Droit | 8 | 8 | W10
Weld | 2794 | Droit | 5 | 5 | W10
Weld | 2793 | Droit | 5 | 5 | W10
Weld | 2792 | Droit | 5 | 5 | W10
Weld | 2787 | Droit | 8 | 8 | W10
Weld | 2786 | Droit | 8 | 8 | W10
Weld | 2785 | Droit | 8 | 8 | W10
Weld | 2784 | Droit | 8 | 8 | W10
Weld | 2783 | Droit | 8 | 8 | W10
Weld | 2782 | Droit | 8 | 8 | W10
Weld | 2781 | Droit | 6 | 6 | W10
Weld | 2780 | Droit | 8 | 8 | W10
Weld | 2750 | Droit | 5 | 5 | W10
Weld | 2749 | Droit | 8 | 8 | W10
Weld | 2748 | Droit | 8 | 8 | W10
Weld | 2747 | Droit | 5 | 5 | W10
Weld | 2746 | Droit | 5 | 5 | W10
Weld | 2745 | Droit | 5 | 5 | W10
Weld | 2738 | Droit | 8 | 8 | W10
Weld | 2735 | Droit | 8 | 8 | W10
Weld | 2714 | Droit | 8 | 8 | W10
Weld | 2711 | Droit | 8 | 8 | W10
Weld | 2696 | Droit | 5 | 5 | W10
Weld | 2695 | Droit | 8 | 8 | W10
Weld | 2694 | Droit | 8 | 8 | W10
Weld | 2693 | Droit | 5 | 5 | W10
Weld | 2692 | Droit | 5 | 5 | W10
Weld | 2691 | Droit | 5 | 5 | W10
Weld | 2685 | Droit | 8 | 8 | W10
Weld | 2684 | Droit | 8 | 8 | W10
Weld | 2683 | Droit | 8 | 8 | W10
Weld | 2682 | Droit | 8 | 8 | W10
Weld | 2681 | Droit | 8 | 8 | W10
Weld | 2680 | Droit | 8 | 8 | W10
Weld | 2679 | Droit | 6 | 6 | W10
Weld | 2678 | Droit | 8 | 8 | W10
Weld | 2677 | Droit | 6 | 6 | W10
Weld | 2676 | Droit | 6 | 6 | W10
Weld | 2675 | Droit | 8 | 8 | W10
Weld | 2674 | Droit | 8 | 8 | W10
Weld | 2673 | Droit | 8 | 8 | W10
Weld | 2672 | Droit | 8 | 8 | W10
Weld | 2671 | Droit | 5 | 5 | W10
Weld | 2670 | Droit | 8 | 8 | W10
Weld | 2669 | Droit | 8 | 8 | W10
Weld | 2668 | Droit | 5 | 5 | W10
Weld | 2667 | Droit | 5 | 5 | W10
Weld | 2666 | Droit | 5 | 5 | W10
Weld | 2661 | Droit | 6 | 6 | W10
Weld | 2660 | Droit | 6 | 6 | W10
Weld | 2659 | Droit | 8 | 8 | W10
Weld | 2658 | Droit | 8 | 8 | W10
Weld | 2657 | Droit | 8 | 8 | W10
Weld | 2656 | Droit | 8 | 8 | W10
Weld | 2655 | Droit | 6 | 6 | W10
Weld | 2654 | Droit | 6 | 6 | W10
Weld | 2653 | Droit | 8 | 8 | W10
Weld | 2652 | Droit | 8 | 8 | W10
Weld | 2651 | Droit | 8 | 8 | W10
Weld | 2650 | Droit | 8 | 8 | W10
Weld | 2649 | Droit | 5 | 5 | W10
Weld | 2648 | Droit | 8 | 8 | W10
Weld | 2647 | Droit | 8 | 8 | W10
Weld | 2646 | Droit | 5 | 5 | W10
Weld | 2645 | Droit | 5 | 5 | W10
Weld | 2644 | Droit | 5 | 5 | W10
Weld | 2639 | Droit | 5 | 0 | Aucun
Weld | 2638 | Droit | 6 | 6 | W10
Weld | 2637 | Droit | 6 | 6 | W10
Weld | 2636 | Droit | 8 | 8 | W10
Weld | 2635 | Droit | 8 | 8 | W10
Weld | 2634 | Droit | 8 | 8 | W10
Weld | 2633 | Droit | 8 | 8 | W10
Weld | 2631 | Droit | 8 | 8 | W10
Weld | 2630 | Droit | 8 | 8 | W10
Weld | 2622 | Droit | 8 | 8 | W10
Weld | 2621 | Droit | 8 | 8 | W10
Weld | 2620 | Droit | 8 | 8 | W10
Weld | 2619 | Droit | 8 | 8 | W10
Weld | 2618 | Droit | 8 | 8 | W10
Weld | 2617 | Droit | 8 | 8 | W10
Weld | 2616 | Droit | 6 | 6 | W10
Weld | 2615 | Droit | 8 | 8 | W10
Weld | 2614 | Droit | 5 | 0 | Aucun
Weld | 2611 | Droit | 6 | 6 | W10
Weld | 2610 | Droit | 6 | 6 | W10
Weld | 2609 | Droit | 8 | 8 | W10
Weld | 2608 | Droit | 8 | 8 | W10
Weld | 2607 | Droit | 8 | 8 | W10
Weld | 2606 | Droit | 8 | 8 | W10
Weld | 2605 | Droit | 6 | 6 | W10
Weld | 2604 | Droit | 6 | 6 | W10
Weld | 2603 | Droit | 8 | 8 | W10
Weld | 2602 | Droit | 8 | 8 | W10
Weld | 2601 | Droit | 8 | 8 | W10
Weld | 2600 | Droit | 8 | 8 | W10
Weld | 2598 | Droit | 8 | 8 | W10
Weld | 2597 | Droit | 8 | 8 | W10
Weld | 2589 | Droit | 8 | 8 | W10
Weld | 2588 | Droit | 8 | 8 | W10
Weld | 2587 | Droit | 8 | 8 | W10
Weld | 2586 | Droit | 8 | 8 | W10
Weld | 2585 | Droit | 8 | 8 | W10
Weld | 2584 | Droit | 8 | 8 | W10
Weld | 2583 | Droit | 6 | 6 | W10
Weld | 2582 | Droit | 8 | 8 | W10
Weld | 2581 | Droit | 5 | 0 | Aucun
Weld | 2580 | Droit | 6 | 6 | W10
Weld | 2579 | Droit | 6 | 6 | W10
Weld | 2578 | Droit | 8 | 8 | W10
Weld | 2577 | Droit | 8 | 8 | W10
Weld | 2576 | Droit | 8 | 8 | W10
Weld | 2575 | Droit | 8 | 8 | W10
Weld | 2574 | Droit | 6 | 6 | W10
Weld | 2573 | Droit | 6 | 6 | W10
Weld | 2572 | Droit | 8 | 8 | W10
Weld | 2571 | Droit | 8 | 8 | W10
Weld | 2570 | Droit | 8 | 8 | W10
Weld | 2569 | Droit | 8 | 8 | W10
Weld | 2558 | Droit | 6 | 6 | W10
Weld | 2557 | Droit | 6 | 6 | W10
Weld | 2556 | Droit | 8 | 8 | W10
Weld | 2555 | Droit | 8 | 8 | W10
Weld | 2554 | Droit | 8 | 8 | W10
Weld | 2553 | Droit | 8 | 8 | W10
Weld | 2551 | Droit | 8 | 8 | W10
Weld | 2550 | Droit | 8 | 8 | W10
Weld | 2548 | Droit | 5 | 5 | W10
Weld | 2547 | Droit | 5 | 5 | W10
Weld | 2542 | Droit | 8 | 8 | W10
Weld | 2541 | Droit | 8 | 8 | W10
Weld | 2540 | Droit | 8 | 8 | W10
Weld | 2539 | Droit | 8 | 8 | W10
Weld | 2538 | Droit | 8 | 8 | W10
Weld | 2537 | Droit | 8 | 8 | W10
Weld | 2536 | Droit | 6 | 6 | W10
Weld | 2535 | Droit | 8 | 8 | W10
Weld | 2534 | Droit | 5 | 0 | Aucun
Weld | 2533 | Droit | 5 | 0 | Aucun
Weld | 2532 | Droit | 6 | 6 | W10
Weld | 2531 | Droit | 6 | 6 | W10
Weld | 2530 | Droit | 8 | 8 | W10
Weld | 2529 | Droit | 8 | 8 | W10
Weld | 2528 | Droit | 8 | 8 | W10
Weld | 2527 | Droit | 8 | 8 | W10
Weld | 2526 | Droit | 5 | 5 | W10
Weld | 2525 | Droit | 8 | 8 | W10
Weld | 2524 | Droit | 8 | 8 | W10
Weld | 2523 | Droit | 5 | 5 | W10
Weld | 2522 | Droit | 5 | 5 | W10
Weld | 2521 | Droit | 5 | 5 | W10
Weld | 2512 | Droit | 8 | 8 | W10
Weld | 2511 | Droit | 8 | 8 | W10
Weld | 2510 | Droit | 6 | 6 | W10
Weld | 2508 | Droit | 5 | 0 | Aucun
Weld | 2505 | Droit | 8 | 8 | W10
Weld | 2504 | Droit | 8 | 8 | W10
Weld | 2503 | Droit | 8 | 8 | W10
Weld | 2502 | Droit | 8 | 8 | W10
Weld | 2501 | Droit | 8 | 8 | W10
Weld | 2500 | Droit | 6 | 6 | W10
Weld | 2499 | Droit | 8 | 8 | W10
Weld | 2498 | Droit | 6 | 6 | W10
Weld | 2497 | Droit | 6 | 6 | W10
Weld | 2496 | Droit | 8 | 8 | W10
Weld | 2495 | Droit | 8 | 8 | W10
Weld | 2494 | Droit | 8 | 8 | W10
Weld | 2493 | Droit | 8 | 8 | W10
Weld | 2492 | Droit | 5 | 5 | W10
Weld | 2491 | Droit | 8 | 8 | W10
Weld | 2490 | Droit | 8 | 8 | W10
Weld | 2489 | Droit | 5 | 5 | W10
Weld | 2488 | Droit | 5 | 5 | W10
Weld | 2487 | Droit | 5 | 5 | W10
Weld | 2482 | Droit | 6 | 6 | W10
Weld | 2481 | Droit | 6 | 6 | W10
Weld | 2480 | Droit | 8 | 8 | W10
Weld | 2479 | Droit | 8 | 8 | W10
Weld | 2478 | Droit | 8 | 8 | W10
Weld | 2477 | Droit | 8 | 8 | W10
Weld | 2476 | Droit | 6 | 6 | W10
Weld | 2475 | Droit | 6 | 6 | W10
Weld | 2474 | Droit | 8 | 8 | W10
Weld | 2473 | Droit | 8 | 8 | W10
Weld | 2472 | Droit | 8 | 8 | W10
Weld | 2471 | Droit | 8 | 8 | W10
Weld | 2470 | Droit | 5 | 5 | W10
Weld | 2469 | Droit | 8 | 8 | W10
Weld | 2468 | Droit | 8 | 8 | W10
Weld | 2467 | Droit | 5 | 5 | W10
Weld | 2466 | Droit | 5 | 5 | W10
Weld | 2465 | Droit | 5 | 5 | W10
Weld | 2438 | Droit | 5 | 0 | Aucun
Weld | 2437 | Droit | 6 | 6 | W10
Weld | 2436 | Droit | 6 | 6 | W10
Weld | 2435 | Droit | 8 | 8 | W10
Weld | 2434 | Droit | 8 | 8 | W10
Weld | 2433 | Droit | 8 | 8 | W10
Weld | 2432 | Droit | 8 | 8 | W10
Weld | 2421 | Droit | 6 | 6 | W10
Weld | 2420 | Droit | 6 | 6 | W10
Weld | 2419 | Droit | 8 | 8 | W10
Weld | 2418 | Droit | 8 | 8 | W10
Weld | 2417 | Droit | 8 | 8 | W10
Weld | 2416 | Droit | 8 | 8 | W10
Weld | 2415 | Droit | 6 | 6 | W10
Weld | 2414 | Droit | 6 | 6 | W10
Weld | 2413 | Droit | 8 | 8 | W10
Weld | 2412 | Droit | 8 | 8 | W10
Weld | 2411 | Droit | 8 | 8 | W10
Weld | 2410 | Droit | 8 | 8 | W10
Weld | 2409 | Droit | 5 | 5 | W10
Weld | 2408 | Droit | 8 | 8 | W10
Weld | 2407 | Droit | 8 | 8 | W10
Weld | 2406 | Droit | 5 | 5 | W10
Weld | 2405 | Droit | 5 | 5 | W10
Weld | 2404 | Droit | 5 | 5 | W10
Weld | 2317 | Droit | 5 | 0 | Aucun
Weld | 2316 | Droit | 5 | 0 | Aucun
Weld | 2315 | Droit | 5 | 0 | Aucun
Weld | 2314 | Droit | 5 | 0 | Aucun
Weld | 2313 | Droit | 5 | 0 | Aucun
Weld | 2312 | Droit | 5 | 0 | Aucun
Weld | 2311 | Droit | 5 | 0 | Aucun
Weld | 2310 | Droit | 5 | 0 | Aucun
Weld | 2308 | Droit | 5 | 0 | Aucun
Weld | 2307 | Droit | 5 | 0 | Aucun
Weld | 2306 | Droit | 5 | 0 | Aucun
Weld | 2305 | Droit | 5 | 0 | Aucun
Weld | 2304 | Droit | 5 | 0 | Aucun
Weld | 2303 | Droit | 5 | 0 | Aucun
Weld | 2302 | Droit | 5 | 0 | Aucun
Weld | 2301 | Droit | 5 | 0 | Aucun
Weld | 2300 | Droit | 5 | 0 | Aucun
Weld | 2299 | Droit | 5 | 0 | Aucun
Weld | 2298 | Droit | 5 | 0 | Aucun
Weld | 2297 | Droit | 5 | 0 | Aucun
Weld | 2296 | Droit | 5 | 0 | Aucun
Weld | 2295 | Droit | 5 | 0 | Aucun
Weld | 2294 | Droit | 5 | 0 | Aucun
Weld | 2293 | Droit | 5 | 0 | Aucun
Weld | 2292 | Droit | 5 | 0 | Aucun
Weld | 2291 | Droit | 5 | 0 | Aucun
Weld | 2290 | Droit | 5 | 0 | Aucun
Weld | 2289 | Droit | 5 | 0 | Aucun
Weld | 2288 | Droit | 5 | 0 | Aucun
Weld | 2287 | Droit | 5 | 0 | Aucun
Weld | 2286 | Droit | 5 | 0 | Aucun
Weld | 2285 | Droit | 5 | 0 | Aucun
Weld | 2284 | Droit | 5 | 0 | Aucun
Weld | 2283 | Droit | 5 | 0 | Aucun
Weld | 2282 | Droit | 5 | 0 | Aucun
Weld | 2281 | Droit | 5 | 0 | Aucun
Weld | 2280 | Droit | 5 | 0 | Aucun
Weld | 2279 | Droit | 5 | 0 | Aucun
Weld | 2278 | Droit | 5 | 0 | Aucun
Weld | 2277 | Droit | 5 | 0 | Aucun
Weld | 2276 | Droit | 5 | 0 | Aucun
Weld | 2275 | Droit | 5 | 0 | Aucun
Weld | 2274 | Droit | 5 | 0 | Aucun
Weld | 2273 | Droit | 5 | 0 | Aucun
Weld | 2272 | Droit | 5 | 0 | Aucun
Weld | 2271 | Droit | 5 | 0 | Aucun
Weld | 2270 | Droit | 5 | 0 | Aucun
Weld | 2269 | Droit | 5 | 0 | Aucun
Weld | 2268 | Droit | 5 | 0 | Aucun
Weld | 2267 | Droit | 5 | 0 | Aucun
Weld | 2266 | Droit | 5 | 0 | Aucun
Weld | 2265 | Droit | 5 | 0 | Aucun
Weld | 2264 | Droit | 5 | 0 | Aucun
Weld | 2262 | Droit | 5 | 5 | W10
Weld | 2261 | Droit | 5 | 5 | W10
Weld | 2260 | Droit | 4 | 4 | W10
Weld | 2259 | Droit | 5 | 5 | W10
Weld | 2258 | Droit | 5 | 5 | W10
Weld | 2257 | Droit | 4 | 4 | W10
Weld | 2256 | Droit | 5 | 5 | W10
Weld | 2255 | Droit | 5 | 5 | W10
Weld | 2254 | Droit | 4 | 4 | W10
Weld | 2253 | Droit | 5 | 5 | W10
Weld | 2252 | Droit | 5 | 5 | W10
Weld | 2251 | Droit | 4 | 4 | W10
Weld | 2250 | Droit | 4 | 4 | W10
Weld | 2249 | Droit | 4 | 4 | W10
Weld | 2248 | Droit | 4 | 4 | W10
Weld | 2247 | Droit | 5 | 5 | W10
Weld | 2246 | Droit | 5 | 5 | W10
Weld | 2245 | Droit | 4 | 4 | W10
Weld | 2244 | Droit | 5 | 5 | W10
Weld | 2243 | Droit | 5 | 5 | W10
Weld | 2242 | Droit | 4 | 4 | W10
Weld | 2241 | Droit | 5 | 5 | W10
Weld | 2240 | Droit | 5 | 5 | W10
Weld | 2239 | Droit | 4 | 4 | W10
Weld | 2238 | Droit | 5 | 5 | W10
Weld | 2237 | Droit | 5 | 5 | W10
Weld | 2236 | Droit | 4 | 4 | W10
Weld | 2235 | Droit | 4 | 4 | W10
Weld | 2234 | Droit | 4 | 4 | W10
Weld | 2233 | Droit | 4 | 4 | W10
Weld | 2232 | Droit | 4 | 4 | W10
Weld | 2231 | Droit | 5 | 5 | W10
Weld | 2230 | Droit | 5 | 5 | W10
Weld | 2229 | Droit | 4 | 4 | W10
Weld | 2228 | Droit | 5 | 5 | W10
Weld | 2227 | Droit | 5 | 5 | W10
Weld | 2226 | Droit | 4 | 4 | W10
Weld | 2225 | Droit | 5 | 5 | W10
Weld | 2224 | Droit | 5 | 5 | W10
Weld | 2223 | Droit | 4 | 4 | W10
Weld | 2222 | Droit | 5 | 5 | W10
Weld | 2221 | Droit | 5 | 5 | W10
Weld | 2220 | Droit | 4 | 4 | W10
Weld | 2219 | Droit | 4 | 4 | W10
Weld | 2218 | Droit | 5 | 5 | W10
Weld | 2217 | Droit | 5 | 5 | W10
Weld | 2216 | Droit | 4 | 4 | W10
Weld | 2215 | Droit | 5 | 5 | W10
Weld | 2214 | Droit | 5 | 5 | W10
Weld | 2213 | Droit | 4 | 4 | W10
Weld | 2212 | Droit | 5 | 5 | W10
Weld | 2211 | Droit | 5 | 5 | W10
Weld | 2210 | Droit | 4 | 4 | W10
Weld | 2209 | Droit | 5 | 5 | W10
Weld | 2208 | Droit | 5 | 5 | W10
Weld | 2207 | Droit | 4 | 4 | W10
Weld | 2206 | Droit | 4 | 4 | W10
Weld | 2205 | Droit | 5 | 5 | W10
Weld | 2204 | Droit | 5 | 5 | W10
Weld | 2203 | Droit | 4 | 4 | W10
Weld | 2202 | Droit | 5 | 5 | W10
Weld | 2201 | Droit | 5 | 5 | W10
Weld | 2200 | Droit | 4 | 4 | W10
Weld | 2199 | Droit | 4 | 4 | W10
Weld | 2198 | Droit | 4 | 4 | W10
Weld | 2197 | Droit | 5 | 5 | W10
Weld | 2196 | Droit | 5 | 5 | W10
Weld | 2195 | Droit | 4 | 4 | W10
Weld | 2194 | Droit | 5 | 5 | W10
Weld | 2193 | Droit | 5 | 5 | W10
Weld | 2192 | Droit | 4 | 4 | W10
Weld | 2191 | Droit | 5 | 5 | W10
Weld | 2190 | Droit | 5 | 5 | W10
Weld | 2189 | Droit | 4 | 4 | W10
Weld | 2188 | Droit | 5 | 5 | W10
Weld | 2187 | Droit | 5 | 5 | W10
Weld | 2186 | Droit | 4 | 4 | W10
Weld | 2185 | Droit | 4 | 4 | W10
Weld | 2184 | Droit | 5 | 5 | W10
Weld | 2183 | Droit | 5 | 5 | W10
Weld | 2182 | Droit | 4 | 4 | W10
Weld | 2181 | Droit | 5 | 5 | W10
Weld | 2180 | Droit | 5 | 5 | W10
Weld | 2179 | Droit | 4 | 4 | W10
Weld | 2178 | Droit | 4 | 4 | W10
Weld | 2177 | Droit | 5 | 5 | W10
Weld | 2176 | Droit | 5 | 5 | W10
Weld | 2175 | Droit | 4 | 4 | W10
Weld | 2174 | Droit | 5 | 5 | W10
Weld | 2173 | Droit | 5 | 5 | W10
Weld | 2172 | Droit | 4 | 4 | W10
Weld | 2171 | Droit | 4 | 4 | W10
Weld | 2170 | Droit | 5 | 5 | W10
Weld | 2169 | Droit | 5 | 5 | W10
Weld | 2168 | Droit | 4 | 4 | W10
Weld | 2167 | Droit | 5 | 5 | W10
Weld | 2166 | Droit | 5 | 5 | W10
Weld | 2165 | Droit | 4 | 4 | W10
Weld | 2164 | Droit | 5 | 5 | W10
Weld | 2163 | Droit | 5 | 5 | W10
Weld | 2162 | Droit | 4 | 4 | W10
Weld | 2161 | Droit | 5 | 5 | W10
Weld | 2160 | Droit | 5 | 5 | W10
Weld | 2159 | Droit | 4 | 4 | W10
Weld | 2158 | Droit | 4 | 4 | W10
Weld | 2157 | Droit | 4 | 4 | W10
Weld | 2156 | Droit | 5 | 5 | W10
Weld | 2155 | Droit | 5 | 5 | W10
Weld | 2154 | Droit | 4 | 4 | W10
Weld | 2153 | Droit | 5 | 5 | W10
Weld | 2152 | Droit | 5 | 5 | W10
Weld | 2151 | Droit | 4 | 4 | W10
Weld | 2150 | Droit | 4 | 4 | W10
Weld | 2149 | Droit | 4 | 4 | W10
Weld | 2148 | Droit | 5 | 5 | W10
Weld | 2147 | Droit | 5 | 5 | W10
Weld | 2146 | Droit | 4 | 4 | W10
Weld | 2145 | Droit | 5 | 5 | W10
Weld | 2144 | Droit | 5 | 5 | W10
Weld | 2143 | Droit | 4 | 4 | W10
Weld | 2142 | Droit | 5 | 5 | W10
Weld | 2141 | Droit | 5 | 5 | W10
Weld | 2140 | Droit | 4 | 4 | W10
Weld | 2139 | Droit | 5 | 5 | W10
Weld | 2138 | Droit | 5 | 5 | W10
Weld | 2137 | Droit | 4 | 4 | W10
Weld | 2136 | Droit | 4 | 4 | W10
Weld | 2135 | Droit | 4 | 4 | W10
Weld | 2134 | Droit | 4 | 4 | W10
Weld | 2133 | Droit | 5 | 5 | W10
Weld | 2132 | Droit | 5 | 5 | W10
Weld | 2131 | Droit | 4 | 4 | W10
Weld | 2130 | Droit | 5 | 5 | W10
Weld | 2129 | Droit | 5 | 5 | W10
Weld | 2128 | Droit | 4 | 4 | W10
Weld | 2127 | Droit | 5 | 5 | W10
Weld | 2126 | Droit | 5 | 5 | W10
Weld | 2125 | Droit | 4 | 4 | W10
Weld | 2124 | Droit | 5 | 5 | W10
Weld | 2123 | Droit | 5 | 5 | W10
Weld | 2122 | Droit | 4 | 4 | W10
Weld | 2121 | Droit | 4 | 4 | W10
Weld | 2120 | Droit | 5 | 5 | W10
Weld | 2119 | Droit | 5 | 5 | W10
Weld | 2118 | Droit | 4 | 4 | W10
Weld | 2117 | Droit | 5 | 5 | W10
Weld | 2116 | Droit | 5 | 5 | W10
Weld | 2115 | Droit | 4 | 4 | W10
Weld | 2114 | Droit | 5 | 5 | W10
Weld | 2113 | Droit | 5 | 5 | W10
Weld | 2112 | Droit | 4 | 4 | W10
Weld | 2111 | Droit | 5 | 5 | W10
Weld | 2110 | Droit | 5 | 5 | W10
Weld | 2109 | Droit | 4 | 4 | W10
Weld | 2108 | Droit | 4 | 4 | W10
Weld | 2107 | Droit | 4 | 4 | W10
Weld | 2106 | Droit | 4 | 4 | W10
Weld | 2105 | Droit | 5 | 5 | W10
Weld | 2104 | Droit | 5 | 5 | W10
Weld | 2103 | Droit | 4 | 4 | W10
Weld | 2102 | Droit | 5 | 5 | W10
Weld | 2101 | Droit | 5 | 5 | W10
Weld | 2100 | Droit | 4 | 4 | W10
Weld | 2099 | Droit | 5 | 5 | W10
Weld | 2098 | Droit | 5 | 5 | W10
Weld | 2097 | Droit | 4 | 4 | W10
Weld | 2096 | Droit | 5 | 5 | W10
Weld | 2095 | Droit | 5 | 5 | W10
Weld | 2094 | Droit | 4 | 4 | W10
Weld | 2093 | Droit | 5 | 5 | W10
Weld | 2092 | Droit | 5 | 5 | W10
Weld | 2091 | Droit | 4 | 4 | W10
Weld | 2090 | Droit | 5 | 5 | W10
Weld | 2089 | Droit | 5 | 5 | W10
Weld | 2088 | Droit | 4 | 4 | W10
Weld | 2087 | Droit | 5 | 5 | W10
Weld | 2086 | Droit | 5 | 5 | W10
Weld | 2085 | Droit | 4 | 4 | W10
Weld | 2084 | Droit | 5 | 5 | W10
Weld | 2083 | Droit | 5 | 5 | W10
Weld | 2082 | Droit | 5 | 5 | W10
Weld | 2081 | Droit | 5 | 5 | W10
Weld | 2080 | Droit | 4 | 4 | W10
Weld | 2079 | Droit | 5 | 5 | W10
Weld | 2078 | Droit | 5 | 5 | W10
Weld | 2077 | Droit | 4 | 4 | W10
Weld | 2076 | Droit | 5 | 5 | W10
Weld | 2075 | Droit | 5 | 5 | W10
Weld | 2074 | Droit | 4 | 4 | W10
Weld | 2073 | Droit | 5 | 5 | W10
Weld | 2072 | Droit | 5 | 5 | W10
Weld | 2071 | Droit | 4 | 4 | W10
Weld | 2070 | Droit | 4 | 4 | W10
Weld | 2069 | Droit | 4 | 4 | W10
Weld | 2068 | Droit | 4 | 4 | W10
Weld | 2067 | Droit | 4 | 4 | W10
Weld | 2062 | Droit | 5 | 5 | W10
Weld | 2061 | Droit | 5 | 5 | W10
Weld | 2060 | Droit | 4 | 4 | W10
Weld | 2059 | Droit | 5 | 5 | W10
Weld | 2058 | Droit | 5 | 5 | W10
Weld | 2057 | Droit | 4 | 4 | W10
Weld | 2056 | Droit | 4 | 4 | W10
Weld | 2055 | Droit | 4 | 4 | W10
Weld | 2054 | Droit | 5 | 5 | W10
Weld | 2053 | Droit | 5 | 5 | W10
Weld | 2052 | Droit | 4 | 4 | W10
Weld | 2051 | Droit | 5 | 5 | W10
Weld | 2050 | Droit | 5 | 5 | W10
Weld | 2049 | Droit | 4 | 4 | W10
Weld | 2048 | Droit | 4 | 4 | W10
Weld | 2047 | Droit | 5 | 5 | W10
Weld | 2046 | Droit | 5 | 5 | W10
Weld | 2045 | Droit | 4 | 4 | W10
Weld | 2044 | Droit | 5 | 5 | W10
Weld | 2043 | Droit | 5 | 5 | W10
Weld | 2042 | Droit | 4 | 4 | W10
Weld | 2041 | Droit | 4 | 4 | W10
Weld | 2040 | Droit | 5 | 5 | W10
Weld | 2039 | Droit | 5 | 5 | W10
Weld | 2038 | Droit | 4 | 4 | W10
Weld | 2037 | Droit | 5 | 5 | W10
Weld | 2036 | Droit | 5 | 5 | W10
Weld | 2035 | Droit | 4 | 4 | W10
Weld | 2034 | Droit | 4 | 4 | W10
Weld | 2033 | Droit | 5 | 5 | W10
Weld | 2032 | Droit | 5 | 5 | W10
Weld | 2031 | Droit | 4 | 4 | W10
Weld | 2030 | Droit | 5 | 5 | W10
Weld | 2029 | Droit | 5 | 5 | W10
Weld | 2028 | Droit | 4 | 4 | W10
Weld | 2027 | Droit | 4 | 4 | W10
Weld | 2026 | Droit | 5 | 5 | W10
Weld | 2025 | Droit | 5 | 5 | W10
Weld | 2024 | Droit | 4 | 4 | W10
Weld | 2023 | Droit | 5 | 5 | W10
Weld | 2022 | Droit | 5 | 5 | W10
Weld | 2021 | Droit | 4 | 4 | W10
Weld | 2020 | Droit | 4 | 4 | W10
Weld | 2019 | Droit | 5 | 5 | W10
Weld | 2018 | Droit | 5 | 5 | W10
Weld | 2017 | Droit | 4 | 4 | W10
Weld | 2016 | Droit | 5 | 5 | W10
Weld | 2015 | Droit | 5 | 5 | W10
Weld | 2014 | Droit | 4 | 4 | W10
Weld | 2013 | Droit | 4 | 4 | W10
Weld | 2012 | Droit | 4 | 4 | W10
Weld | 2011 | Droit | 5 | 5 | W10
Weld | 2010 | Droit | 5 | 5 | W10
Weld | 2009 | Droit | 4 | 4 | W10
Weld | 2008 | Droit | 5 | 5 | W10
Weld | 2007 | Droit | 5 | 5 | W10
Weld | 1979 | Droit | 5 | 0 | Aucun
Weld | 1978 | Droit | 5 | 0 | Aucun
Weld | 1977 | Droit | 5 | 0 | Aucun
Weld | 1976 | Droit | 5 | 0 | Aucun
Weld | 1975 | Droit | 5 | 0 | Aucun
Weld | 1974 | Droit | 5 | 0 | Aucun
Weld | 1972 | Droit | 5 | 0 | Aucun
Weld | 1971 | Droit | 5 | 0 | Aucun
Weld | 1970 | Droit | 5 | 5 | W10
Weld | 1969 | Droit | 5 | 5 | W10
Weld | 1968 | Droit | 5 | 5 | W10
Weld | 1967 | Droit | 5 | 5 | W10
Weld | 1966 | Droit | 5 | 5 | W10
Weld | 1965 | Droit | 5 | 5 | W10
Weld | 1964 | Droit | 5 | 5 | W10
Weld | 1963 | Droit | 5 | 5 | W10
Weld | 1962 | Droit | 5 | 5 | W10
Weld | 1961 | Droit | 5 | 5 | W10
Weld | 1960 | Droit | 5 | 5 | W10
Weld | 1959 | Droit | 5 | 5 | W10
Weld | 1958 | Droit | 5 | 5 | W10
Weld | 1957 | Droit | 5 | 5 | W10
Weld | 1956 | Droit | 5 | 5 | W10
Weld | 1955 | Droit | 5 | 5 | W10
Weld | 1954 | Droit | 5 | 5 | W10
Weld | 1953 | Droit | 5 | 5 | W10
Weld | 1941 | Droit | 5 | 5 | W10
Weld | 1940 | Droit | 5 | 5 | W10
Weld | 1939 | Droit | 4 | 4 | W10
Weld | 1938 | Droit | 4 | 4 | W10
Weld | 1937 | Droit | 5 | 5 | W10
Weld | 1936 | Droit | 5 | 5 | W10
Weld | 1912 | Droit | 5 | 5 | W10
Weld | 1911 | Droit | 5 | 5 | W10
Weld | 1910 | Droit | 4 | 4 | W10
Weld | 1897 | Droit | 4 | 4 | W10
Weld | 1896 | Droit | 5 | 5 | W10
Weld | 1895 | Droit | 5 | 5 | W10
Weld | 1706 | Droit | 5 | 0 | Aucun
Weld | 1705 | Droit | 5 | 0 | Aucun
Weld | 1704 | Droit | 5 | 0 | Aucun
Weld | 1703 | Droit | 5 | 0 | Aucun
Weld | 1701 | Droit | 5 | 0 | Aucun
Weld | 1700 | Droit | 5 | 0 | Aucun
Weld | 1697 | Droit | 5 | 5 | W10
Weld | 1696 | Droit | 5 | 5 | W10
Weld | 1695 | Droit | 5 | 5 | W10
Weld | 1694 | Droit | 5 | 5 | W10
Weld | 1693 | Droit | 5 | 5 | W10
Weld | 1692 | Droit | 5 | 5 | W10
Weld | 1691 | Droit | 5 | 5 | W10
Weld | 1690 | Droit | 5 | 5 | W10
Weld | 1689 | Droit | 5 | 5 | W10
Weld | 1688 | Droit | 5 | 5 | W10
Weld | 1687 | Droit | 5 | 5 | W10
Weld | 1686 | Droit | 5 | 5 | W10
Weld | 1684 | Droit | 5 | 0 | Aucun
Weld | 1683 | Droit | 4 | 4 | W10
Weld | 1682 | Droit | 5 | 5 | W10
Weld | 1681 | Droit | 5 | 5 | W10
Weld | 1680 | Droit | 4 | 4 | W10
Weld | 1679 | Droit | 5 | 5 | W10
Weld | 1678 | Droit | 5 | 5 | W10
Weld | 1677 | Droit | 4 | 4 | W10
Weld | 1676 | Droit | 5 | 5 | W10
Weld | 1675 | Droit | 5 | 5 | W10
Weld | 1674 | Droit | 4 | 4 | W10
Weld | 1673 | Droit | 5 | 5 | W10
Weld | 1672 | Droit | 5 | 5 | W10
Weld | 1669 | Droit | 5 | 5 | W10
Weld | 1668 | Droit | 5 | 5 | W10
Weld | 1667 | Droit | 5 | 5 | W10
Weld | 1666 | Droit | 5 | 5 | W10
Weld | 1665 | Droit | 5 | 5 | W10
Weld | 1664 | Droit | 5 | 5 | W10
Weld | 1657 | Droit | 5 | 0 | Aucun
Weld | 1655 | Droit | 4 | 4 | W10
Weld | 1654 | Droit | 5 | 5 | W10
Weld | 1653 | Droit | 5 | 5 | W10
Weld | 1652 | Droit | 4 | 4 | W10
Weld | 1651 | Droit | 5 | 5 | W10
Weld | 1650 | Droit | 5 | 5 | W10
Weld | 596 | Droit | 5 | 0 | Aucun
Weld | 594 | Autour | 6 | 6 | Aucun
Weld | 593 | Autour | 6 | 6 | Aucun
Weld | 592 | Autour | 6 | 6 | Aucun
Weld | 591 | Autour | 6 | 6 | Aucun
Weld | 590 | Autour | 6 | 6 | Aucun
Weld | 589 | Autour | 6 | 6 | Aucun
Weld | 588 | Autour | 6 | 6 | Aucun
Weld | 587 | Autour | 6 | 6 | Aucun
Weld | 586 | Autour | 6 | 6 | Aucun
Weld | 585 | Autour | 6 | 6 | Aucun
Weld | 584 | Autour | 6 | 6 | Aucun
Weld | 583 | Droit | 5 | 0 | Aucun
Weld | 582 | Droit | 5 | 0 | Aucun
Weld | 581 | Droit | 5 | 0 | Aucun
Weld | 580 | Droit | 5 | 0 | Aucun
Weld | 579 | Droit | 5 | 0 | Aucun
Weld | 577 | Droit | 5 | 0 | Aucun
Weld | 576 | Droit | 5 | 0 | Aucun
Weld | 575 | Droit | 5 | 0 | Aucun
Weld | 574 | Droit | 5 | 0 | Aucun
Weld | 571 | Droit | 5 | 0 | Aucun
Weld | 567 | Droit | 5 | 0 | Aucun
Weld | 555 | Autour | 6 | 6 | Aucun
Weld | 438 | Droit | 8 | 8 | W10
Weld | 435 | Droit | 8 | 8 | W10
Weld | 432 | Droit | 8 | 8 | W10
Weld | 431 | Droit | 8 | 8 | W10
Weld | 430 | Droit | 8 | 8 | W10
Weld | 429 | Droit | 8 | 8 | W10
Weld | 428 | Droit | 8 | 8 | W10
Weld | 427 | Droit | 8 | 8 | W10
Weld | 426 | Droit | 5 | 5 | W10
Weld | 425 | Droit | 7 | 7 | W10
Weld | 424 | Droit | 8 | 8 | W10
Weld | 423 | Droit | 8 | 8 | W10
Weld | 422 | Droit | 8 | 8 | W10
Weld | 421 | Droit | 8 | 8 | W10
Weld | 420 | Droit | 8 | 8 | W10
Weld | 419 | Droit | 8 | 8 | W10
Weld | 418 | Droit | 5 | 5 | W10
Weld | 417 | Droit | 7 | 7 | W10
Weld | 314 | Droit | 8 | 8 | W10
Weld | 313 | Droit | 5 | 5 | W10
Weld | 312 | Droit | 7 | 7 | W10
Weld | 299 | Droit | 8 | 8 | W10
Weld | 298 | Droit | 8 | 8 | W10
Weld | 297 | Droit | 5 | 5 | W10
Weld | 296 | Droit | 7 | 7 | W10
Weld | 287 | Droit | 8 | 8 | W10
Weld | 286 | Droit | 8 | 8 | W10
Weld | 285 | Droit | 8 | 8 | W10
Weld | 284 | Droit | 8 | 8 | W10
Weld | 283 | Droit | 8 | 8 | W10
Weld | 282 | Droit | 8 | 8 | W10
Weld | 281 | Droit | 8 | 8 | W10
Weld | 280 | Droit | 8 | 8 | W10
Weld | 279 | Droit | 8 | 8 | W10
Weld | 278 | Droit | 8 | 8 | W10
Weld | 277 | Droit | 8 | 8 | W10
Weld | 276 | Droit | 6 | 6 | W10
Weld | 275 | Droit | 8 | 8 | W10
Weld | 274 | Droit | 8 | 8 | W10
Weld | 273 | Droit | 8 | 8 | W10
Weld | 272 | Droit | 8 | 8 | W10
Weld | 271 | Droit | 8 | 8 | W10
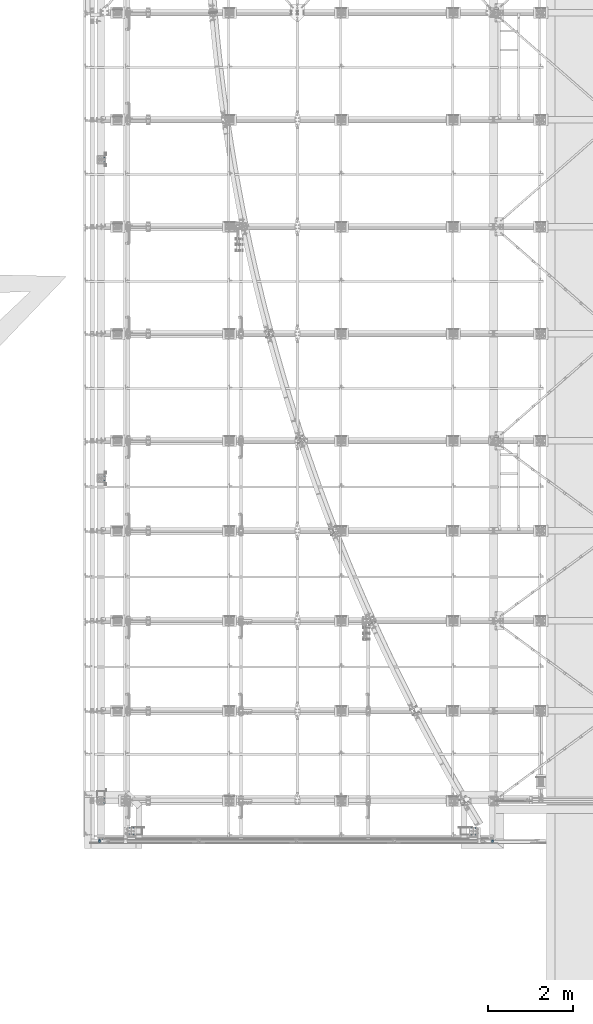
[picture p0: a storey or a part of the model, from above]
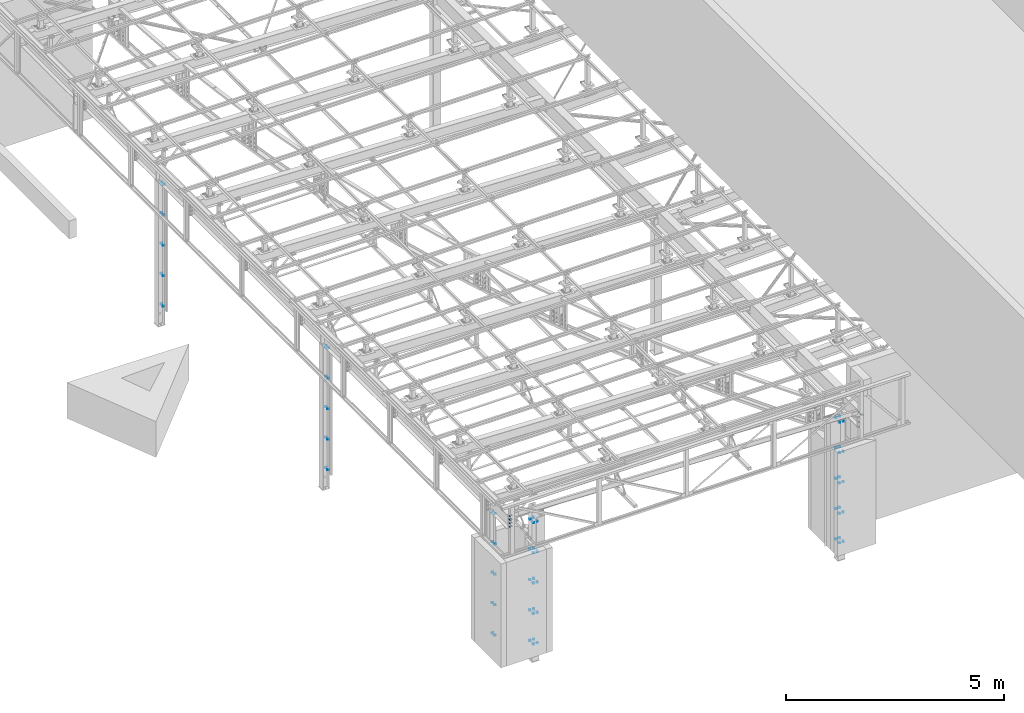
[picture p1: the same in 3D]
Properties of the parts of a building model (IFC2X3), part 11 of 13

# IfcFastener (6774)
Name | N° soudure | Linéaire/Périphérique | Dimension1 (mm) | Dimension2 (mm) | Type2
Weld | 270 | Droit | 8 | 8 | W10
Weld | 269 | Droit | 8 | 8 | W10
Weld | 268 | Droit | 8 | 8 | W10
Weld | 267 | Droit | 8 | 8 | W10
Weld | 266 | Droit | 8 | 8 | W10
Weld | 265 | Droit | 8 | 8 | W10
Weld | 264 | Droit | 8 | 8 | W10
Weld | 263 | Droit | 6 | 6 | W10
Weld | 262 | Droit | 8 | 8 | W10
Weld | 261 | Droit | 8 | 8 | W10
Weld | 260 | Droit | 8 | 8 | W10
Weld | 259 | Droit | 8 | 8 | W10
Weld | 258 | Droit | 8 | 8 | W10
Weld | 257 | Droit | 8 | 8 | W10
Weld | 256 | Droit | 8 | 8 | W10
Weld | 255 | Droit | 8 | 8 | W10
Weld | 254 | Droit | 8 | 8 | W10
Weld | 253 | Droit | 8 | 8 | W10
Weld | 252 | Droit | 8 | 8 | W10
Weld | 251 | Droit | 8 | 8 | W10
Weld | 238 | Droit | 6 | 6 | W10
Weld | 237 | Droit | 8 | 8 | W10
Weld | 236 | Droit | 8 | 8 | W10
Weld | 235 | Droit | 8 | 8 | W10
Weld | 234 | Droit | 8 | 8 | W10
Weld | 233 | Droit | 8 | 8 | W10
Weld | 232 | Droit | 8 | 8 | W10
Weld | 231 | Droit | 8 | 8 | W10
Weld | 230 | Droit | 8 | 8 | W10
Weld | 229 | Droit | 8 | 8 | W10
Weld | 228 | Droit | 8 | 8 | W10
Weld | 227 | Droit | 8 | 8 | W10
Weld | 226 | Droit | 8 | 8 | W10
Weld | 225 | Droit | 6 | 6 | W10
Weld | 224 | Droit | 8 | 8 | W10
Weld | 223 | Droit | 8 | 8 | W10
Weld | 222 | Droit | 8 | 8 | W10
Weld | 221 | Droit | 8 | 8 | W10
Weld | 220 | Droit | 8 | 8 | W10
Weld | 219 | Droit | 8 | 8 | W10
Weld | 218 | Droit | 8 | 8 | W10
Weld | 217 | Droit | 8 | 8 | W10
Weld | 216 | Droit | 8 | 8 | W10
Weld | 215 | Droit | 8 | 8 | W10
Weld | 214 | Droit | 8 | 8 | W10
Weld | 213 | Droit | 8 | 8 | W10
Weld | 212 | Droit | 6 | 6 | W10
Weld | 191 | Droit | 8 | 8 | W10
Weld | 188 | Droit | 8 | 8 | W10
Weld | 177 | Droit | 8 | 8 | W10
Weld | 176 | Droit | 8 | 8 | W10
Weld | 175 | Droit | 8 | 8 | W10
Weld | 174 | Droit | 8 | 8 | W10
Weld | 173 | Droit | 8 | 8 | W10
Weld | 172 | Droit | 8 | 8 | W10
Weld | 171 | Droit | 8 | 8 | W10
Weld | 170 | Droit | 8 | 8 | W10
Weld | 169 | Droit | 8 | 8 | W10
Weld | 168 | Droit | 8 | 8 | W10
Weld | 167 | Droit | 8 | 8 | W10
Weld | 166 | Droit | 8 | 8 | W10
Weld | 152 | Droit | 8 | 8 | W10
Weld | 151 | Droit | 8 | 8 | W10
Weld | 150 | Droit | 8 | 8 | W10
Weld | 149 | Droit | 8 | 8 | W10
Weld | 148 | Droit | 8 | 8 | W10
Weld | 147 | Droit | 8 | 8 | W10
Weld | 110 | Droit | 6 | 6 | W10
Weld | 97 | Droit | 8 | 8 | W10
Weld | 9 | Droit | 6 | 6 | W10

# IfcMechanicalFastener: Bolt assembly (8166)
In: Undefined
Tekla Boulons - sets with these values: 2
Name | NominalDiameter (mm) | NominalLength (mm) = Longueur (mm) | Material = Standard | Diamètre (mm) | Nom
17 x Bolt assembly | 20 | 75 | HR10.9 | 20 | Boulons HR tête H
229 x Bolt assembly | 12 | 40 | 8.8 | 12 | Boulons tête H
11 x Bolt assembly | 20 | 85 | HR10.9 | 20 | Boulons HR tête H
11 x Bolt assembly | 20 | 100 | HR10.9 | 20 | Boulons HR tête H
344 x Bolt assembly | 30 | 3 | 8.8 | 33 | Boulons tête H
15 x Bolt assembly | 12 | 100 | HILTI-HSA | 12
1417 x Bolt assembly | 12 | 25 | 8.8 | 12 | Boulons tête H
1301 x Bolt assembly | 12 | 30 | 8.8 | 12 | Boulons tête H
1233 x Bolt assembly | 12 | 35 | 8.8 | 12 | Boulons tête H
676 x Bolt assembly | 16 | 35 | 8.8 | 16 | Boulons tête H
2 x Bolt assembly | 30 | 10 | 8.8 | 33 | Boulons tête H
4 x Bolt assembly | 16 | 10 | 8.8 | 18 | Boulons tête H
6 x Bolt assembly | 20 | 45 | 8.8 | 20 | Boulons tête H
2 x Bolt assembly | 20 | 9.5 | 8.8 | 22 | Boulons tête H
15 x Bolt assembly | 12 | 45 | 8.8 | 12 | Boulons tête H
46 x Bolt assembly | 30 | 4 | 8.8 | 33 | Boulons tête H
2 x Bolt assembly | 12 | 100 | 8.8 | 12 | Boulons tête H
3 x Bolt assembly | 12 | 160 | HILTI-HAS | 12
100 x Bolt assembly | 16 | 45 | 8.8 | 16 | Boulons tête H
32 x Bolt assembly | 16 | 190 | HILTI-HAS | 16
555 x Bolt assembly | 16 | 40 | 8.8 | 16 | Boulons tête H
66 x Bolt assembly | 16 | 140 | HILTI-HSA | 16
9 x Bolt assembly | 20 | 65 | HR10.9 | 20 | Boulons HR tête H
180 x Bolt assembly | 16 | 50 | 8.8 | 16 | Boulons tête H
19 x Bolt assembly | 16 | 30 | 8.8 | 16 | Boulons tête H
2 x Bolt assembly | 12 | 8 | 8.8 | 14 | Boulons tête H
5 x Bolt assembly | 30 | 6.1 | 8.8 | 40 | Boulons tête H
14 x Bolt assembly | 12 | 8.5 | 8.8 | 14 | Boulons tête H
39 x Bolt assembly | 24 | 12 | 8.8 | 26 | Boulons tête H
2 x Bolt assembly | 20 | 55 | 8.8 | 20 | Boulons tête H
Bolt assembly | 20 | 70 | 8.8 | 20 | Boulons tête H
Bolt assembly | 24 | 60 | 8.8 | 24 | Boulons tête H
3 x Bolt assembly | 20 | 40 | 8.8 | 20 | Boulons tête H
6 x Bolt assembly | 30 | 6 | 8.8 | 40 | Boulons tête H
Bolt assembly | 30 | 5.6 | 8.8 | 40 | Boulons tête H
Bolt assembly | 30 | 8.6 | 8.8 | 40 | Boulons tête H
13 x Bolt assembly | 20 | 70 | HR10.9 | 20 | Boulons HR tête H
11 x Bolt assembly | 30 | 8 | 8.8 | 33 | Boulons tête H
11 x Bolt assembly | 16 | 6 | 8.8 | 18 | Boulons tête H
59 x Bolt assembly | 20 | 10 | 8.8 | 22 | Boulons tête H
Bolt assembly | 12 | 10 | 8.8 | 14 | Boulons tête H
2 x Bolt assembly | 24 | 20 | 8.8 | 26 | Boulons tête H
33 x Bolt assembly | 12 | 4 | 8.8 | 14 | Boulons tête H
342 x Bolt assembly | 20 | 8 | 8.8 | 22 | Boulons tête H
171 x Bolt assembly | 12 | 2 | 8.8 | 14 | Boulons tête H
171 x Bolt assembly | 16 | 100 | 8.8 | 18 | Boulons tête H
139 x Bolt assembly | 10 | 5 | 6.8 | 3 | Boulons tête H
732 x Bolt assembly | 10 | 5 | 6.8 | 10 | Boulons tête H
3 x Bolt assembly | 12 | 3 | 8.8 | 14 | Boulons tête H
6 x Bolt assembly | 16 | 8 | 8.8 | 18 | Boulons tête H
21 x Bolt assembly | 16 | 9.2 | 8.8 | 18 | Boulons tête H
2 x Bolt assembly | 16 | 25 | 8.8 | 16 | Boulons tête H
12 x Bolt assembly | 12 | 15 | 8.8 | 14 | Boulons tête H
Bolt assembly | 12 | 5 | 8.8 | 14 | Boulons tête H
8 x Bolt assembly | 16 | 9.8 | 8.8 | 18 | Boulons tête H
2 x Bolt assembly | 16 | 60 | 8.8 | 16 | Boulons tête H
4 x Bolt assembly | 16 | 10.2 | 8.8 | 18 | Boulons tête H
Bolt assembly | 16 | 21.2 | 8.8 | 18 | Boulons tête H
Bolt assembly | 16 | 55 | 8.8 | 16 | Boulons tête H
16 x Bolt assembly | 20 | 80 | HR10.9 | 20 | Boulons HR tête H
10 x Bolt assembly | 24 | 55 | 8.8 | 24 | Boulons tête H
16 x Bolt assembly | 30 | 25 | 8.8 | 33 | Boulons tête H
8 x Bolt assembly | 24 | 25 | 8.8 | 26 | Boulons tête H

# IfcMember: L100*10 (6)
In: Undefined
Description: L100*10; Material: STEEL/E24-2
Tekla Commun - Finition: GRENAILLE-PEINT; Repère de pièce: 1232; Phase: 1; Profil: L100*10; sets with these values: 2
Tekla Quantités - Poids: 1.7 kg; Volume: 0 m3; Surface supérieure totale: 0 m2; Surface par tonne: 187.1 m2; Surface nette: 0.1 m2; Hauteur: 100 mm; Largeur: 100 mm; Longueur: 120 mm; sets with these values: 2
Pset_MemberCommon - LoadBearing: no; Reference: 1232
BaseQuantities - Length: 119.998 mm; OuterSurfaceArea: 0.338396 m2; GrossSurfaceArea: 0.338396 m2; CrossSectionArea: 0.00192 m2; NetVolume: 0.000227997 m3; GrossVolume: 0.000230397 m3; NetWeight: 1.78978 kg; GrossWeight: 1.80862 kg
Name | Repère d'assemblage
2 x Unnamed | B17
4 x Unnamed | B16

# IfcMember: L150*15 (10)
In: Undefined
Description: L150*15; Material: STEEL/E24-2
Tekla Commun - Finition: GRENAILLE-PEINT; Repère de pièce: 883; Profil: L150*15; sets with these values: 2
Tekla Quantités - Poids: 5.5 kg; Volume: 0 m3; Surface supérieure totale: 0 m2; Surface par tonne: 19.5 m2; Surface nette: 0.1 m2; Hauteur: 150 mm; Largeur: 150 mm; Longueur: 160 mm; sets with these values: 2
Pset_MemberCommon - LoadBearing: no; Reference: 883
BaseQuantities - Length: 160.008 mm; OuterSurfaceArea: 0.104555 m2; GrossSurfaceArea: 0.104555 m2; CrossSectionArea: 0.00439378 m2; NetVolume: 0.000684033 m3; GrossVolume: 0.000684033 m3; NetWeight: 5.36966 kg; GrossWeight: 5.36966 kg
Name | Repère d'assemblage | Phase
2 x Unnamed | B5 | 1
4 x Unnamed | B7 | 3
2 x Unnamed | B8 | 1
2 x Unnamed | B7 | 1

# IfcMember: L40*4 (23)
In: Undefined
Description: L40*4; Material: STEEL/E24-2
Tekla Commun - Finition: GRENAILLE-PEINT; Profil: L40*4; sets with these values: 2
Tekla Quantités - Volume: 0 m3; Surface supérieure totale: 0 m2; Surface par tonne: 64.1 m2; Hauteur: 40 mm; Largeur: 40 mm; sets with these values: 2
Pset_MemberCommon - LoadBearing: no
BaseQuantities - CrossSectionArea: 0.000308 m2
Name | Repère de pièce = Repère d'assemblage = Reference | Phase | Nom | Poids (kg) | Surface nette (m2) | Longueur (mm) | Length (mm) | OuterSurfaceArea (m2) = GrossSurfaceArea (m2) | NetVolume (m3) | GrossVolume (m3) | NetWeight (kg) | GrossWeight (kg)
20 x BRACON | W5 | 6 | BRACON | 1.2 | 0.1 | 479.1 | 479.118 | 0.0742633 | 0.000145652 | 0.000147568 | 1.14337 | 1.15841
CV | W4 | 5 | CV | 3.9 | 0.3 | 1613.3 | 1613.26 | 0.250055 | 0.00049043 | 0.000496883 | 3.84987 | 3.90053
2 x CSV | C135 | 1 | CSV | 3.8 | 0.3 | 1572.5 | 1572.45 | 0.24373 | 0.000479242 | 0.000484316 | 3.76205 | 3.80188

# IfcMember: L50*5 (15)
In: Undefined
Description: L50*5; Material: STEEL/E24-2
Tekla Commun - Finition: GRENAILLE-PEINT; Profil: L50*5; sets with these values: 2
Tekla Quantités - Volume: 0 m3; Surface supérieure totale: 0 m2; Surface par tonne: 51.5 m2; Hauteur: 50 mm; Largeur: 50 mm; sets with these values: 2
Pset_MemberCommon - LoadBearing: no
BaseQuantities - CrossSectionArea: 0.00048 m2
Name | Repère de pièce = Reference | Repère d'assemblage | Phase | Nom | Poids (kg) | Surface nette (m2) | Longueur (mm) | Length (mm) | OuterSurfaceArea (m2) = GrossSurfaceArea (m2) | NetVolume (m3) | GrossVolume (m3) | NetWeight (kg) | GrossWeight (kg)
2 x ATTACHE | H34 | H34 | 4 | ATTACHE | 8.2 | 0.3 | 2199.1 | 2199.13 | 0.426632 | 0.00104459 | 0.00105558 | 8.20002 | 8.28633
Unnamed | 530 | L52 | 2 |  | 6 | 0.3 | 1581.2 | 1581.23 | 0.306759 | 0.000751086 | 0.000758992 | 5.89602 | 5.95809
Unnamed | 531 | L52 | 2 |  | 9.7 | 0.5 | 2590.9 | 2590.9 | 0.502635 | 0.00123068 | 0.00124363 | 9.66083 | 9.76252
3 x Unnamed | 532 | L52 | 2 |  | 9.7 | 0.5 | 2595.6 | 2595.6 | 0.503546 | 0.00123291 | 0.00124589 | 9.67834 | 9.78021
4 x STABILITE | V3 | V3 | 1 | STABILITE | 14.2 | 0.6 | 3735.3 | 3735.27 | 0.724642 | 0.00177615 | 0.00179293 | 13.9428 | 14.0745
4 x STABILITE | V2 | V2 | 1 | STABILITE | 13.9 | 0.6 | 3675.3 | 3675.27 | 0.713002 | 0.00174765 | 0.00176413 | 13.7191 | 13.8484

# IfcMember: L60*6 (34)
In: Undefined
Description: L60*6; Material: STEEL/E24-2
Tekla Commun - Finition: GRENAILLE-PEINT; Profil: L60*6; sets with these values: 2
Tekla Quantités - Volume: 0 m3; Surface supérieure totale: 0 m2; Surface par tonne: 43 m2; Hauteur: 60 mm; Largeur: 60 mm; sets with these values: 2
Pset_MemberCommon - LoadBearing: no
BaseQuantities - CrossSectionArea: 0.000691 m2
Name | Repère de pièce = Repère d'assemblage = Reference | Phase | Nom | Poids (kg) | Surface nette (m2) | Longueur (mm) | Length (mm) | OuterSurfaceArea (m2) = GrossSurfaceArea (m2) | NetVolume (m3) | GrossVolume (m3) | NetWeight (kg) | GrossWeight (kg)
10 x BRACON | W1 | 6 | BRACON | 3.2 | 0.1 | 588.4 | 588.439 | 0.137106 | 0.000402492 | 0.000406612 | 3.15957 | 3.1919
20 x ATTACHE | H19 | 3 | ATTACHE | 0.5 | 0 | 84 | 84 | 0.019572 | 0.000057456 | 0.000058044 | 0.451029 | 0.455645
4 x STABILITE | V1 | 2 | STABILITE | 23.9 | 1.1 | 4410.3 | 4410.27 | 1.02759 | 0.00301936 | 0.0030475 | 23.702 | 23.9229

# IfcMember: L70*7 (60)
In: Undefined
Description: L70*7
Tekla Commun - Finition: GRENAILLE-PEINT; Profil: L70*7; sets with these values: 2
Tekla Quantités - Volume: 0 m3; Surface supérieure totale: 0 m2; Surface par tonne: 36.9 m2; Hauteur: 70 mm; Largeur: 70 mm; sets with these values: 2
Pset_MemberCommon - LoadBearing: no
BaseQuantities - CrossSectionArea: 0.00094 m2
Name | Material | Repère de pièce = Reference | Repère d'assemblage | Phase | Nom | Poids (kg) | Surface nette (m2) | Longueur (mm) | Length (mm) | OuterSurfaceArea (m2) = GrossSurfaceArea (m2) | NetVolume (m3) | GrossVolume (m3) | NetWeight (kg) | GrossWeight (kg)
2 x POUTRES | STEEL/E24-2 | 619 | N43 | 3 | POUTRES | 13.3 | 0.5 | 1805.6 | 1805.57 | 0.491116 | 0.00168099 | 0.00169724 | 13.1958 | 13.3233
2 x STABILITE | STEEL/E24-2 | V15 | V15 | 1 | STABILITE | 45.5 | 1.7 | 6163.3 | 6163.29 | 1.67641 | 0.00574174 | 0.00579349 | 45.0727 | 45.4789
2 x STABILITE | STEEL/S235JR | V8 | V8 | 1 | STABILITE | 49.7 | 1.9 | 6739.2 | 6739.22 | 1.83307 | 0.00627794 | 0.00633486 | 49.2818 | 49.7287
2 x STABILITE | STEEL/S235JR | V9 | V9 | 1 | STABILITE | 37.3 | 1.5 | 5057.8 | 5057.78 | 1.37572 | 0.00471251 | 0.00475431 | 36.9932 | 37.3213
2 x STABILITE | STEEL/S235JR | V10 | V10 | 1 | STABILITE | 51.3 | 1.9 | 6945.4 | 6945.41 | 1.88915 | 0.0064699 | 0.00652868 | 50.7887 | 51.2502
2 x STABILITE | STEEL/S235JR | V11 | V11 | 1 | STABILITE | 38.3 | 1.5 | 5188.8 | 5188.85 | 1.41137 | 0.00483454 | 0.00487752 | 37.9511 | 38.2885
2 x STABILITE | STEEL/E24-2 | V7 | V7 | 1 | STABILITE | 47.2 | 1.7 | 6391.6 | 6391.56 | 1.7385 | 0.00595426 | 0.00600806 | 46.741 | 47.1633
2 x STABILITE | STEEL/E24-2 | V6 | V6 | 1 | STABILITE | 45.5 | 1.7 | 6163.3 | 6163.29 | 1.67641 | 0.00574174 | 0.00579349 | 45.0727 | 45.4789
2 x STABILITE | STEEL/E24-2 | V5 | V5 | 1 | STABILITE | 46 | 1.7 | 6236.8 | 6236.82 | 1.69642 | 0.0058102 | 0.00586261 | 45.6101 | 46.0215
2 x STABILITE | STEEL/E24-2 | V14 | V14 | 1 | STABILITE | 45.6 | 1.7 | 6183.3 | 6183.29 | 1.68185 | 0.00576036 | 0.00581229 | 45.2189 | 45.6265
2 x STABILITE | STEEL/E24-2 | V13 | V13 | 1 | STABILITE | 47.5 | 1.7 | 6436.9 | 6436.93 | 1.75085 | 0.00599651 | 0.00605072 | 47.0726 | 47.4981
2 x POUTRES | STEEL/E24-2 | 618 | N46 | 2 | POUTRES | 17.4 | 0.6 | 2371 | 2370.98 | 0.644905 | 0.00220738 | 0.00222872 | 17.3279 | 17.4954
2 x POUTRES | STEEL/E24-2 | 617 | N46 | 2 | POUTRES | 16 | 0.6 | 2171 | 2170.98 | 0.590505 | 0.00202118 | 0.00204072 | 15.8662 | 16.0196
2 x POUTRES | STEEL/E24-2 | 617 | N43 | 3 | POUTRES | 16 | 0.6 | 2171 | 2170.98 | 0.590505 | 0.00202118 | 0.00204072 | 15.8662 | 16.0196
2 x POUTRES | STEEL/E24-2 | 617 | N44 | 2 | POUTRES | 16 | 0.6 | 2171 | 2170.98 | 0.590505 | 0.00202118 | 0.00204072 | 15.8662 | 16.0196
2 x POUTRES | STEEL/E24-2 | 617 | N45 | 2 | POUTRES | 16 | 0.6 | 2171 | 2170.98 | 0.590505 | 0.00202118 | 0.00204072 | 15.8662 | 16.0196
2 x POUTRES | STEEL/E24-2 | 617 | N7 | 1 | POUTRES | 16 | 0.6 | 2171 | 2170.98 | 0.590505 | 0.00202118 | 0.00204072 | 15.8662 | 16.0196
2 x POUTRES | STEEL/E24-2 | 617 | N6 | 1 | POUTRES | 16 | 0.6 | 2171 | 2170.98 | 0.590505 | 0.00202118 | 0.00204072 | 15.8662 | 16.0196
4 x POUTRES | STEEL/E24-2 | 618 | N13 | 1 | POUTRES | 17.4 | 0.6 | 2371 | 2370.98 | 0.644905 | 0.00220738 | 0.00222872 | 17.3279 | 17.4954
2 x POUTRES | STEEL/E24-2 | 617 | N11 | 1 | POUTRES | 16 | 0.6 | 2171 | 2170.98 | 0.590505 | 0.00202118 | 0.00204072 | 15.8662 | 16.0196
4 x POUTRES | STEEL/E24-2 | 617 | N8 | 1 | POUTRES | 16 | 0.6 | 2171 | 2170.98 | 0.590505 | 0.00202118 | 0.00204072 | 15.8662 | 16.0196
4 x POUTRES | STEEL/E24-2 | 617 | N41 | 1 | POUTRES | 16 | 0.6 | 2171 | 2170.98 | 0.590505 | 0.00202118 | 0.00204072 | 15.8662 | 16.0196
4 x POUTRES | STEEL/E24-2 | 617 | N10 | 1 | POUTRES | 16 | 0.6 | 2171 | 2170.98 | 0.590505 | 0.00202118 | 0.00204072 | 15.8662 | 16.0196
2 x POUTRES | STEEL/E24-2 | 617 | N40 | 3 | POUTRES | 16 | 0.6 | 2171 | 2170.98 | 0.590505 | 0.00202118 | 0.00204072 | 15.8662 | 16.0196
2 x POUTRES | STEEL/E24-2 | 617 | N9 | 3 | POUTRES | 16 | 0.6 | 2171 | 2170.98 | 0.590505 | 0.00202118 | 0.00204072 | 15.8662 | 16.0196
2 x POUTRES | STEEL/E24-2 | 618 | N42 | 1 | POUTRES | 17.4 | 0.6 | 2371 | 2370.98 | 0.644905 | 0.00220738 | 0.00222872 | 17.3279 | 17.4954

# IfcMember: PL170*10, PLAT
In: Undefined
Description: PL170*10; Material: STEEL/E24-2
Tekla Commun - Finition: GRENAILLE-PEINT; Repère de pièce: 252; Repère d'assemblage: K99; Phase: 1; Profil: PL170*10; Nom: PLAT; sets with these values: 2
Tekla Quantités - Poids: 0.9 kg; Volume: 0 m3; Surface supérieure totale: 0 m2; Surface par tonne: 30.9 m2; Surface nette: 0 m2; Hauteur: 170 mm; Largeur: 10 mm; Longueur: 63 mm; sets with these values: 2
Pset_MemberCommon - LoadBearing: no; Reference: 252
BaseQuantities - Length: 63 mm; OuterSurfaceArea: 0.02608 m2; GrossSurfaceArea: 0.02608 m2; CrossSectionArea: 0.0017 m2; NetVolume: 0.0001071 m3; GrossVolume: 0.0001071 m3; NetWeight: 0.840735 kg; GrossWeight: 0.840735 kg

# IfcMember: PL180*12 (4)
In: Undefined
Description: PL180*12; Material: STEEL/E24-2
Tekla Quantités - Poids: 3.1 kg; Volume: 0 m3; Surface supérieure totale: 0 m2; Surface par tonne: 24.1 m2; Surface nette: 0.1 m2; Hauteur: 180 mm; Largeur: 12 mm; Longueur: 180 mm; sets with these values: 2
Tekla Commun - Finition: GRENAILLE-PEINT; Repère de pièce: 1268; Repère d'assemblage: B18; Phase: 2; Profil: PL180*12; Nom: ATTACHE; sets with these values: 2
Pset_MemberCommon - LoadBearing: no; Reference: 1268
BaseQuantities - Length: 180 mm; OuterSurfaceArea: 0.07344 m2; GrossSurfaceArea: 0.07344 m2; CrossSectionArea: 0.00216 m2; NetVolume: 0.0003888 m3; GrossVolume: 0.0003888 m3; NetWeight: 3.05208 kg; GrossWeight: 3.05208 kg

# IfcMember: PL3*66 (2)
In: Undefined
Description: PL3*66; Material: STEEL/S235JR
Tekla Commun - Finition: GRENAILLE-PEINT; Repère de pièce: 1250; Repère d'assemblage: L105; Phase: 1; Profil: PL3*66; Nom: TOLE; sets with these values: 2
Tekla Quantités - Poids: 0.1 kg; Volume: 0 m3; Surface supérieure totale: 0 m2; Surface par tonne: 92.6 m2; Surface nette: 0 m2; Hauteur: 66 mm; Largeur: 3 mm; Longueur: 66 mm; sets with these values: 2
Pset_MemberCommon - LoadBearing: no; Reference: 1250
BaseQuantities - Length: 66 mm; OuterSurfaceArea: 0.00950399 m2; GrossSurfaceArea: 0.00950399 m2; CrossSectionArea: 0.000198 m2; NetVolume: 0.000013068 m3; GrossVolume: 0.000013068 m3; NetWeight: 0.102584 kg; GrossWeight: 0.102584 kg

# IfcMember: PL3*86 (2)
In: Undefined
Description: PL3*86; Material: STEEL/S235JR
Tekla Quantités - Poids: 0.2 kg; Volume: 0 m3; Surface supérieure totale: 0 m2; Surface par tonne: 90.9 m2; Surface nette: 0 m2; Hauteur: 86 mm; Largeur: 3 mm; Longueur: 86 mm; sets with these values: 2
Tekla Commun - Finition: GRENAILLE-PEINT; Repère de pièce: 1247; Repère d'assemblage: L100; Phase: 1; Profil: PL3*86; Nom: TOLE; sets with these values: 2
Pset_MemberCommon - LoadBearing: no; Reference: 1247
BaseQuantities - Length: 86 mm; OuterSurfaceArea: 0.015824 m2; GrossSurfaceArea: 0.015824 m2; CrossSectionArea: 0.000258 m2; NetVolume: 0.000022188 m3; GrossVolume: 0.000022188 m3; NetWeight: 0.174176 kg; GrossWeight: 0.174176 kg

# IfcMember: PL50*10 (40)
In: Undefined
Description: PL50*10; Material: STEEL/E24-2
Tekla Commun - Finition: GRENAILLE-PEINT; Profil: PL50*10; Nom: PLATINE; sets with these values: 2
Tekla Quantités - Poids: 0.3 kg; Volume: 0 m3; Surface supérieure totale: 0 m2; Surface par tonne: 33.8 m2; Surface nette: 0 m2; Hauteur: 50 mm; Largeur: 10 mm; Longueur: 80 mm; sets with these values: 2
Pset_MemberCommon - LoadBearing: no
BaseQuantities - Length: 80 mm; OuterSurfaceArea: 0.0106 m2; GrossSurfaceArea: 0.0106 m2; CrossSectionArea: 0.0005 m2; NetVolume: 0.00004 m3; GrossVolume: 0.00004 m3; NetWeight: 0.314 kg; GrossWeight: 0.314 kg
Name | Repère de pièce = Reference | Repère d'assemblage | Phase
4 x PLATINE | 225 | N43 | 3
4 x PLATINE | 175 | N46 | 2
2 x PLATINE | 175 | N45 | 2
2 x PLATINE | 175 | N44 | 2
2 x PLATINE | 175 | N6 | 1
2 x PLATINE | 175 | N11 | 1
2 x PLATINE | 175 | N7 | 1
4 x PLATINE | 175 | N13 | 1
4 x PLATINE | 175 | N41 | 1
4 x PLATINE | 175 | N10 | 1
4 x PLATINE | 175 | N8 | 1
2 x PLATINE | 175 | N9 | 3
2 x PLATINE | 175 | N40 | 3
2 x PLATINE | 175 | N42 | 1

# IfcMember: PL50*8 (24)
In: Undefined
Description: PL50*8; Material: STEEL/E24-2
Tekla Commun - Finition: GRENAILLE-PEINT; Repère de pièce: Y3; Repère d'assemblage: Y3; Phase: 1; Profil: PL50*8; Nom: CALE; sets with these values: 2
Tekla Quantités - Poids: 0.2 kg; Volume: 0 m3; Surface supérieure totale: 0 m2; Surface par tonne: 42 m2; Surface nette: 0 m2; Hauteur: 50 mm; Largeur: 8 mm; Longueur: 50 mm; sets with these values: 2
Pset_MemberCommon - LoadBearing: no; Reference: Y3
BaseQuantities - Length: 50 mm; OuterSurfaceArea: 0.0066 m2; GrossSurfaceArea: 0.0066 m2; CrossSectionArea: 0.0004 m2; NetVolume: 0.00002 m3; GrossVolume: 0.00002 m3; NetWeight: 0.157 kg; GrossWeight: 0.157 kg

# IfcMember: PL60*8 (48)
In: Undefined
Description: PL60*8; Material: STEEL/E24-2
Tekla Commun - Finition: GRENAILLE-PEINT; Repère de pièce: Y2; Repère d'assemblage: Y2; Phase: 1; Profil: PL60*8; Nom: CALE; sets with these values: 2
Tekla Quantités - Poids: 0.2 kg; Volume: 0 m3; Surface supérieure totale: 0 m2; Surface par tonne: 40.3 m2; Surface nette: 0 m2; Hauteur: 60 mm; Largeur: 8 mm; Longueur: 60 mm; sets with these values: 2
Pset_MemberCommon - LoadBearing: no; Reference: Y2
BaseQuantities - Length: 60 mm; OuterSurfaceArea: 0.00912 m2; GrossSurfaceArea: 0.00912 m2; CrossSectionArea: 0.00048 m2; NetVolume: 0.0000288 m3; GrossVolume: 0.0000288 m3; NetWeight: 0.22608 kg; GrossWeight: 0.22608 kg

# IfcMember: PL66*3 (6)
In: Undefined
Description: PL66*3; Material: STEEL/E24-2
Tekla Commun - Finition: GRENAILLE-PEINT; Repère de pièce: 1242; Phase: 4; Profil: PL66*3; sets with these values: 2
Tekla Quantités - Poids: 0.1 kg; Volume: 0 m3; Surface supérieure totale: 0 m2; Surface par tonne: 92.6 m2; Surface nette: 0 m2; Hauteur: 66 mm; Largeur: 3 mm; Longueur: 66 mm; sets with these values: 2
Pset_MemberCommon - LoadBearing: no; Reference: 1242
BaseQuantities - Length: 66 mm; OuterSurfaceArea: 0.00950399 m2; GrossSurfaceArea: 0.00950399 m2; CrossSectionArea: 0.000198 m2; NetVolume: 0.000013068 m3; GrossVolume: 0.000013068 m3; NetWeight: 0.102584 kg; GrossWeight: 0.102584 kg
Name | Repère d'assemblage
4 x Unnamed | M20
Unnamed | M21
Unnamed | M22

# IfcMember: TUBE-C-100*100*3, BUTON
In: Undefined
Description: TUBE-C-100*100*3; Material: STEEL/E24-2
Tekla Commun - Finition: GRENAILLE-PEINT; Repère de pièce: 973; Repère d'assemblage: B17; Phase: 1; Profil: TUBE-C-100*100*3; Nom: BUTON; sets with these values: 2
Tekla Quantités - Poids: 24.2 kg; Volume: 0 m3; Surface supérieure totale: 0 m2; Surface par tonne: 43.1 m2; Surface nette: 1.1 m2; Hauteur: 100 mm; Largeur: 100 mm; Longueur: 2679.2 mm; sets with these values: 2
Pset_MemberCommon - LoadBearing: no; Reference: 973
BaseQuantities - Length: 2679.18 mm; OuterSurfaceArea: 1.0422 m2; GrossSurfaceArea: 1.0422 m2; CrossSectionArea: 0.001149 m2; NetVolume: 0.00311856 m3; GrossVolume: 0.00307838 m3; NetWeight: 24.4807 kg; GrossWeight: 24.1653 kg

# IfcPlate: PL10*130, PLATINE
In: Undefined
Description: PL10*130; Material: STEEL/E36-3
Tekla Commun - Finition: GRENAILLE-PEINT; Repère de pièce: 198; Repère d'assemblage: P119; Phase: 2; Profil: PL10*130; Nom: PLATINE; sets with these values: 2
Tekla Quantités - Poids: 2.4 kg; Volume: 0 m3; Surface supérieure totale: 0 m2; Surface par tonne: 28.5 m2; Surface nette: 0.1 m2; Hauteur: 130 mm; Largeur: 10 mm; Longueur: 277.6 mm; sets with these values: 2
Pset_PlateCommon - LoadBearing: no; Reference: 198
BaseQuantities - Width: 130 mm; NetArea: 0.0717388 m2; GrossArea: 0.036088 m2; CrossSectionArea: 0.0001 m2; NetVolume: 0.00032113 m3; GrossVolume: 0.00032113 m3

# IfcPlate: PL10*137 (3)
In: Undefined
Description: PL10*137; Material: STEEL/E24-2
Tekla Commun - Finition: GRENAILLE-PEINT; Profil: PL10*137; sets with these values: 2
Tekla Quantités - Volume: 0 m3; Surface supérieure totale: 0 m2; Largeur: 10 mm; sets with these values: 2
Pset_PlateCommon - LoadBearing: no
BaseQuantities - CrossSectionArea: 0.0001 m2
Name | Repère de pièce = Reference | Repère d'assemblage | Phase | Nom | Poids (kg) | Surface par tonne (m2) | Surface nette (m2) | Hauteur (mm) | Longueur (mm) | Width (mm) | NetArea (m2) | GrossArea (m2) | NetVolume (m3) = GrossVolume (m3)
PLAT | 189 | H2 | 3 | PLAT | 1.4 | 30 | 0 | 136.9 | 225 | 136.95 | 0.0432186 | 0.0308138 | 0.000184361
PLAT | 189 | H2 | 2 | PLAT | 1.4 | 30 | 0 | 136.9 | 225 | 136.95 | 0.0432186 | 0.0308138 | 0.000184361
Unnamed | 250 | K45 | 1 |  | 3.8 | 28.3 | 0.1 | 137.4 | 443.1 | 137.448 | 0.108105 | 0.0609021 | 0.000488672

# IfcPlate: PL10*140 (8)
In: Undefined
Description: PL10*140; Material: STEEL/S235JR
Tekla Commun - Finition: GALVANISE; Repère de pièce: 174; Phase: 2; Profil: PL10*140; Nom: PLAT; sets with these values: 2
Tekla Quantités - Poids: 1.4 kg; Volume: 0 m3; Surface supérieure totale: 0 m2; Surface par tonne: 29.2 m2; Surface nette: 0 m2; Hauteur: 140 mm; Largeur: 10 mm; Longueur: 136.4 mm; sets with these values: 2
Pset_PlateCommon - LoadBearing: no; Reference: 174
BaseQuantities - Width: 140 mm; NetArea: 0.0414032 m2; GrossArea: 0.0190949 m2; CrossSectionArea: 0.0001 m2; NetVolume: 0.000180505 m3; GrossVolume: 0.000180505 m3
Name | Repère d'assemblage
PLAT | S89
PLAT | S90
2 x PLAT | S91
2 x PLAT | S92
PLAT | S94
PLAT | S93

# IfcPlate: PL10*142 (7)
In: Undefined
Description: PL10*142; Material: STEEL/E24-2
Tekla Commun - Finition: GRENAILLE-PEINT; Phase: 2; Profil: PL10*142; Nom: PLAT; sets with these values: 2
Tekla Quantités - Poids: 1.7 kg; Volume: 0 m3; Surface supérieure totale: 0 m2; Surface par tonne: 28.9 m2; Surface nette: 0.1 m2; Hauteur: 142 mm; Largeur: 10 mm; Longueur: 160.2 mm; sets with these values: 2
Pset_PlateCommon - LoadBearing: no
BaseQuantities - CrossSectionArea: 0.0001 m2
Name | Repère de pièce = Reference | Repère d'assemblage | Width (mm) | NetArea (m2) | GrossArea (m2) | NetVolume (m3) = GrossVolume (m3)
PLAT | 272 | H85 | 142.016 | 0.0515101 | 0.022744 | 0.000227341
PLAT | 273 | H86 | 142.012 | 0.05151 | 0.022743 | 0.00022734
PLAT | 274 | H87 | 142.006 | 0.0515099 | 0.0227406 | 0.00022734
PLAT | 275 | H88 | 142.004 | 0.0515099 | 0.0227392 | 0.00022734
PLAT | 276 | H89 | 142.002 | 0.0515098 | 0.0227377 | 0.000227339
PLAT | 277 | H90 | 142.001 | 0.0515098 | 0.0227362 | 0.000227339
PLAT | 278 | H81 | 142 | 0.0515098 | 0.0227348 | 0.000227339

# IfcPlate: PL10*147 (176)
In: Undefined
Description: PL10*147; Material: STEEL/E24-2
Tekla Commun - Finition: GRENAILLE-PEINT; Profil: PL10*147; Nom: PLATINE; sets with these values: 2
Tekla Quantités - Volume: 0 m3; Surface supérieure totale: 0 m2; Surface nette: 0.1 m2; Hauteur: 146.9 mm; Largeur: 10 mm; sets with these values: 2
Pset_PlateCommon - LoadBearing: no
BaseQuantities - CrossSectionArea: 0.0001 m2
Name | Repère de pièce = Reference | Repère d'assemblage | Phase | Poids (kg) | Surface par tonne (m2) | Longueur (mm) | Width (mm) | NetArea (m2) | GrossArea (m2) | NetVolume (m3) | GrossVolume (m3)
3 x PLATINE | 186 | N42 | 1 | 2.6 | 28.9 | 230 | 146.95 | 0.0743392 | 0.0337985 | 0.000327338 | 0.000327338
PLATINE | 241 | N46 | 2 | 2.7 | 28.9 | 268.9 | 146.95 | 0.0784113 | 0.0395119 | 0.000344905 | 0.000370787
PLATINE | 241 | N44 | 2 | 2.7 | 28.9 | 268.9 | 146.95 | 0.0784113 | 0.0395119 | 0.000344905 | 0.000370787
PLATINE | 283 | N44 | 2 | 3 | 28.8 | 268.9 | 146.95 | 0.0835868 | 0.0395114 | 0.000370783 | 0.000370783
PLATINE | 241 | N45 | 2 | 2.7 | 28.9 | 268.9 | 146.95 | 0.0784103 | 0.0395113 | 0.0003449 | 0.000370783
2 x PLATINE | 283 | N49 | 2 | 3 | 28.8 | 268.9 | 146.95 | 0.0835868 | 0.0395114 | 0.000370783 | 0.000370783
PLATINE | 283 | N18 | 2 | 3 | 28.8 | 268.9 | 146.95 | 0.0835868 | 0.0395114 | 0.000370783 | 0.000370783
PLATINE | 287 | N15 | 3 | 3 | 28.8 | 277.1 | 146.953 | 0.0865197 | 0.0407156 | 0.000384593 | 0.000384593
PLATINE | 283 | P119 | 2 | 3 | 28.8 | 268.9 | 146.954 | 0.0835891 | 0.0395128 | 0.000370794 | 0.000370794
PLATINE | 187 | N46 | 2 | 2.6 | 28.9 | 230 | 146.95 | 0.0743392 | 0.0337985 | 0.000327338 | 0.000327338
PLATINE | 285 | N43 | 3 | 3 | 28.8 | 277.1 | 146.953 | 0.0865197 | 0.0407156 | 0.000384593 | 0.000384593
2 x PLATINE | 265 | N43 | 3 | 2.6 | 28.9 | 230 | 146.95 | 0.0743392 | 0.0337985 | 0.000327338 | 0.000327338
PLATINE | 199 | N46 | 2 | 2.4 | 29.2 | 230 | 146.95 | 0.0691627 | 0.0337985 | 0.000301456 | 0.000327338
PLATINE | 287 | N17 | 1 | 3 | 28.8 | 277.1 | 146.953 | 0.0865197 | 0.0407156 | 0.000384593 | 0.000384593
PLATINE | 287 | N38 | 1 | 3 | 28.8 | 277.1 | 146.953 | 0.0865197 | 0.0407156 | 0.000384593 | 0.000384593
PLATINE | 290 | N39 | 1 | 3.4 | 28.5 | 310.3 | 146.953 | 0.096957 | 0.0456018 | 0.000433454 | 0.000433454
2 x PLATINE | 253 | N11 | 1 | 2.7 | 28.9 | 268.9 | 146.95 | 0.0784103 | 0.0395113 | 0.0003449 | 0.000370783
PLATINE | 286 | N7 | 1 | 3 | 28.8 | 268.9 | 146.95 | 0.0835868 | 0.0395114 | 0.000370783 | 0.000370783
PLATINE | 253 | N7 | 1 | 2.7 | 28.9 | 268.9 | 146.95 | 0.0784113 | 0.0395119 | 0.000344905 | 0.000370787
PLATINE | 253 | N6 | 1 | 2.7 | 28.9 | 268.9 | 146.95 | 0.0784113 | 0.0395119 | 0.000344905 | 0.000370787
PLATINE | 286 | N6 | 1 | 3 | 28.8 | 268.9 | 146.95 | 0.0835868 | 0.0395114 | 0.000370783 | 0.000370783
2 x PLATINE | 253 | N13 | 1 | 2.7 | 28.9 | 268.9 | 146.95 | 0.0784113 | 0.0395119 | 0.000344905 | 0.000370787
PLATINE | 286 | N17 | 1 | 3 | 28.8 | 268.9 | 146.95 | 0.0835878 | 0.0395119 | 0.000370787 | 0.000370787
PLATINE | 283 | P113 | 3 | 3 | 28.8 | 268.9 | 146.954 | 0.0835891 | 0.0395128 | 0.000370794 | 0.000370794
PLATINE | 296 | N43 | 3 | 2.4 | 29.2 | 230 | 146.95 | 0.0691627 | 0.0337985 | 0.000301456 | 0.000327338
PLATINE | 241 | N43 | 3 | 2.7 | 28.9 | 268.9 | 146.95 | 0.0784113 | 0.0395119 | 0.000344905 | 0.000370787
PLATINE | 266 | N43 | 3 | 2.6 | 28.9 | 230 | 146.95 | 0.0743392 | 0.0337985 | 0.000327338 | 0.000327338
8 x PLATINE | 186 | N41 | 1 | 2.6 | 28.9 | 230 | 146.95 | 0.0743392 | 0.0337985 | 0.000327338 | 0.000327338
6 x PLATINE | 186 | N10 | 1 | 2.6 | 28.9 | 230 | 146.95 | 0.0743392 | 0.0337985 | 0.000327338 | 0.000327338
8 x PLATINE | 186 | N8 | 1 | 2.6 | 28.9 | 230 | 146.95 | 0.0743392 | 0.0337985 | 0.000327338 | 0.000327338
PLATINE | 286 | N40 | 3 | 3 | 28.8 | 268.9 | 146.95 | 0.0835868 | 0.0395114 | 0.000370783 | 0.000370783
PLATINE | 187 | N40 | 3 | 2.6 | 28.9 | 230 | 146.95 | 0.0743392 | 0.0337985 | 0.000327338 | 0.000327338
PLATINE | 199 | N40 | 3 | 2.4 | 29.2 | 230 | 146.95 | 0.0691627 | 0.0337985 | 0.000301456 | 0.000327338
PLATINE | 253 | N40 | 3 | 2.7 | 28.9 | 268.9 | 146.95 | 0.0784113 | 0.0395119 | 0.000344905 | 0.000370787
PLATINE | 187 | N9 | 3 | 2.6 | 28.9 | 230 | 146.95 | 0.0743392 | 0.0337985 | 0.000327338 | 0.000327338
PLATINE | 253 | N9 | 3 | 2.7 | 28.9 | 268.9 | 146.95 | 0.0784103 | 0.0395113 | 0.0003449 | 0.000370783
PLATINE | 199 | N9 | 3 | 2.4 | 29.2 | 230 | 146.95 | 0.0691627 | 0.0337985 | 0.000301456 | 0.000327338
2 x PLATINE | 186 | N16 | 1 | 2.6 | 28.9 | 230 | 146.95 | 0.0743392 | 0.0337985 | 0.000327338 | 0.000327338
2 x PLATINE | 287 | N16 | 1 | 3 | 28.8 | 277.1 | 146.953 | 0.0865197 | 0.0407156 | 0.000384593 | 0.000384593
8 x PLATINE | 186 | N47 | 1 | 2.6 | 28.9 | 230 | 146.95 | 0.0743392 | 0.0337985 | 0.000327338 | 0.000327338
PLATINE | 187 | N48 | 3 | 2.6 | 28.9 | 230 | 146.95 | 0.0743392 | 0.0337985 | 0.000327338 | 0.000327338
2 x PLATINE | 286 | N48 | 3 | 3 | 28.8 | 268.9 | 146.95 | 0.0835868 | 0.0395114 | 0.000370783 | 0.000370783
PLATINE | 199 | N48 | 3 | 2.4 | 29.2 | 230 | 146.95 | 0.0691627 | 0.0337985 | 0.000301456 | 0.000327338
PLATINE | 286 | N15 | 3 | 3 | 28.8 | 268.9 | 146.95 | 0.0835868 | 0.0395114 | 0.000370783 | 0.000370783
PLATINE | 187 | N15 | 3 | 2.6 | 28.9 | 230 | 146.95 | 0.0743392 | 0.0337985 | 0.000327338 | 0.000327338
2 x PLATINE | 286 | N41 | 1 | 3 | 28.8 | 268.9 | 146.95 | 0.0835868 | 0.0395114 | 0.000370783 | 0.000370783
2 x PLATINE | 187 | N16 | 1 | 2.6 | 28.9 | 230 | 146.95 | 0.0743392 | 0.0337985 | 0.000327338 | 0.000327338
2 x PLATINE | 286 | N16 | 1 | 3 | 28.8 | 268.9 | 146.95 | 0.0835868 | 0.0395114 | 0.000370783 | 0.000370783
PLATINE | 199 | N42 | 1 | 2.4 | 29.2 | 230 | 146.95 | 0.0691627 | 0.0337985 | 0.000301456 | 0.000327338
PLATINE | 253 | N42 | 1 | 2.7 | 28.9 | 268.9 | 146.95 | 0.0784113 | 0.0395119 | 0.000344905 | 0.000370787
2 x PLATINE | 199 | N47 | 1 | 2.4 | 29.2 | 230 | 146.95 | 0.0691627 | 0.0337985 | 0.000301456 | 0.000327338
4 x PLATINE | 286 | N47 | 1 | 3 | 28.8 | 268.9 | 146.95 | 0.0835868 | 0.0395114 | 0.000370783 | 0.000370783
2 x PLATINE | 187 | N47 | 1 | 2.6 | 28.9 | 230 | 146.95 | 0.0743392 | 0.0337985 | 0.000327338 | 0.000327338
2 x PLATINE | 199 | N10 | 1 | 2.4 | 29.2 | 230 | 146.95 | 0.0691627 | 0.0337985 | 0.000301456 | 0.000327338
2 x PLATINE | 253 | N10 | 1 | 2.7 | 28.9 | 268.9 | 146.95 | 0.0784103 | 0.0395113 | 0.0003449 | 0.000370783
2 x PLATINE | 187 | N10 | 1 | 2.6 | 28.9 | 230 | 146.95 | 0.0743392 | 0.0337985 | 0.000327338 | 0.000327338
2 x PLATINE | 253 | N8 | 1 | 2.7 | 28.9 | 268.9 | 146.95 | 0.0784113 | 0.0395119 | 0.000344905 | 0.000370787
2 x PLATINE | 199 | N8 | 1 | 2.4 | 29.2 | 230 | 146.95 | 0.0691627 | 0.0337985 | 0.000301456 | 0.000327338
2 x PLATINE | 187 | N8 | 1 | 2.6 | 28.9 | 230 | 146.95 | 0.0743392 | 0.0337985 | 0.000327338 | 0.000327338
2 x PLATINE | 286 | N8 | 1 | 3 | 28.8 | 268.9 | 146.95 | 0.0835868 | 0.0395114 | 0.000370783 | 0.000370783
PLATINE | 186 | N38 | 1 | 2.6 | 28.9 | 230 | 146.95 | 0.0743392 | 0.0337985 | 0.000327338 | 0.000327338
6 x PLATINE | 186 | N13 | 1 | 2.6 | 28.9 | 230 | 146.95 | 0.0743392 | 0.0337985 | 0.000327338 | 0.000327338
PLATINE | 187 | N42 | 1 | 2.6 | 28.9 | 230 | 146.95 | 0.0743392 | 0.0337985 | 0.000327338 | 0.000327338
PLATINE | 187 | N39 | 1 | 2.6 | 28.9 | 230 | 146.95 | 0.0743392 | 0.0337985 | 0.000327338 | 0.000327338
PLATINE | 286 | N39 | 1 | 3 | 28.8 | 268.9 | 146.95 | 0.0835878 | 0.0395119 | 0.000370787 | 0.000370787
2 x PLATINE | 187 | N41 | 1 | 2.6 | 28.9 | 230 | 146.95 | 0.0743392 | 0.0337985 | 0.000327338 | 0.000327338
2 x PLATINE | 253 | N41 | 1 | 2.7 | 28.9 | 268.9 | 146.95 | 0.0784113 | 0.0395119 | 0.000344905 | 0.000370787
2 x PLATINE | 199 | N41 | 1 | 2.4 | 29.2 | 230 | 146.95 | 0.0691627 | 0.0337985 | 0.000301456 | 0.000327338
PLATINE | 199 | N11 | 1 | 2.4 | 29.2 | 230 | 146.95 | 0.0691627 | 0.0337985 | 0.000301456 | 0.000327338
PLATINE | 199 | N7 | 1 | 2.4 | 29.2 | 230 | 146.95 | 0.0691627 | 0.0337985 | 0.000301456 | 0.000327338
PLATINE | 199 | N6 | 1 | 2.4 | 29.2 | 230 | 146.95 | 0.0691627 | 0.0337985 | 0.000301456 | 0.000327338
PLATINE | 187 | N6 | 1 | 2.6 | 28.9 | 230 | 146.95 | 0.0743392 | 0.0337985 | 0.000327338 | 0.000327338
2 x PLATINE | 187 | N13 | 1 | 2.6 | 28.9 | 230 | 146.95 | 0.0743392 | 0.0337985 | 0.000327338 | 0.000327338
2 x PLATINE | 199 | N13 | 1 | 2.4 | 29.2 | 230 | 146.95 | 0.0691627 | 0.0337985 | 0.000301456 | 0.000327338
PLATINE | 187 | N17 | 1 | 2.6 | 28.9 | 230 | 146.95 | 0.0743392 | 0.0337985 | 0.000327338 | 0.000327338
PLATINE | 187 | N18 | 2 | 2.6 | 28.9 | 230 | 146.95 | 0.0743392 | 0.0337985 | 0.000327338 | 0.000327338
PLATINE | 186 | N15 | 3 | 2.6 | 28.9 | 230 | 146.95 | 0.0743392 | 0.0337985 | 0.000327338 | 0.000327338
PLATINE | 187 | N49 | 2 | 2.6 | 28.9 | 230 | 146.95 | 0.0743392 | 0.0337985 | 0.000327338 | 0.000327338
PLATINE | 199 | N49 | 2 | 2.4 | 29.2 | 230 | 146.95 | 0.0691627 | 0.0337985 | 0.000301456 | 0.000327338
PLATINE | 187 | N45 | 2 | 2.6 | 28.9 | 230 | 146.95 | 0.0743392 | 0.0337985 | 0.000327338 | 0.000327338
PLATINE | 187 | N44 | 2 | 2.6 | 28.9 | 230 | 146.95 | 0.0743392 | 0.0337985 | 0.000327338 | 0.000327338
PLATINE | 199 | N44 | 2 | 2.4 | 29.2 | 230 | 146.95 | 0.0691627 | 0.0337985 | 0.000301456 | 0.000327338
PLATINE | 199 | N45 | 2 | 2.4 | 29.2 | 230 | 146.95 | 0.0691627 | 0.0337985 | 0.000301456 | 0.000327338
PLATINE | 186 | N14 | 1 | 2.6 | 28.9 | 230 | 146.95 | 0.0743392 | 0.0337985 | 0.000327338 | 0.000327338
PLATINE | 287 | N14 | 1 | 3 | 28.8 | 277.1 | 146.953 | 0.0865197 | 0.0407156 | 0.000384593 | 0.000384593
4 x PLATINE | 186 | N12 | 1 | 2.6 | 28.9 | 230 | 146.95 | 0.0743392 | 0.0337985 | 0.000327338 | 0.000327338
3 x PLATINE | 186 | N11 | 1 | 2.6 | 28.9 | 230 | 146.95 | 0.0743392 | 0.0337985 | 0.000327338 | 0.000327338
4 x PLATINE | 186 | N7 | 1 | 2.6 | 28.9 | 230 | 146.95 | 0.0743392 | 0.0337985 | 0.000327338 | 0.000327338
4 x PLATINE | 186 | N6 | 1 | 2.6 | 28.9 | 230 | 146.95 | 0.0743392 | 0.0337985 | 0.000327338 | 0.000327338
PLATINE | 186 | N17 | 1 | 2.6 | 28.9 | 230 | 146.95 | 0.0743392 | 0.0337985 | 0.000327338 | 0.000327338
PLATINE | 286 | N38 | 1 | 3 | 28.8 | 268.9 | 146.95 | 0.0835878 | 0.0395119 | 0.000370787 | 0.000370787
PLATINE | 187 | N38 | 1 | 2.6 | 28.9 | 230 | 146.95 | 0.0743392 | 0.0337985 | 0.000327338 | 0.000327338
4 x PLATINE | 186 | N48 | 3 | 2.6 | 28.9 | 230 | 146.95 | 0.0743392 | 0.0337985 | 0.000327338 | 0.000327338
3 x PLATINE | 186 | N9 | 3 | 2.6 | 28.9 | 230 | 146.95 | 0.0743392 | 0.0337985 | 0.000327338 | 0.000327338
4 x PLATINE | 186 | N40 | 3 | 2.6 | 28.9 | 230 | 146.95 | 0.0743392 | 0.0337985 | 0.000327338 | 0.000327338
PLATINE | 186 | N39 | 1 | 2.6 | 28.9 | 230 | 146.95 | 0.0743392 | 0.0337985 | 0.000327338 | 0.000327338
PLATINE | 193 | N42 | 1 | 2.6 | 28.9 | 230 | 146.95 | 0.0743392 | 0.0337985 | 0.000327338 | 0.000327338

# IfcPlate: PL10*152, PLATINE
In: Undefined
Description: PL10*152; Material: STEEL/E24-2
Tekla Commun - Finition: GRENAILLE-PEINT; Repère de pièce: 256; Repère d'assemblage: N7; Phase: 1; Profil: PL10*152; Nom: PLATINE; sets with these values: 2
Tekla Quantités - Poids: 3 kg; Volume: 0 m3; Surface supérieure totale: 0 m2; Surface par tonne: 28.6 m2; Surface nette: 0.1 m2; Hauteur: 152 mm; Largeur: 10 mm; Longueur: 268.9 mm; sets with these values: 2
Pset_PlateCommon - LoadBearing: no; Reference: 256
BaseQuantities - Width: 151.953 mm; NetArea: 0.0861899 m2; GrossArea: 0.0408572 m2; CrossSectionArea: 0.0001 m2; NetVolume: 0.000383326 m3; GrossVolume: 0.000383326 m3

# IfcPlate: PL10*156 (2)
In: Undefined
Description: PL10*156; Material: STEEL/E24-2
Tekla Commun - Finition: GRENAILLE-PEINT; Repère de pièce: 245; Phase: 1; Profil: PL10*156; sets with these values: 2
Tekla Quantités - Poids: 3.4 kg; Volume: 0 m3; Surface supérieure totale: 0 m2; Surface par tonne: 29.1 m2; Surface nette: 0.1 m2; Hauteur: 155.7 mm; Largeur: 10 mm; Longueur: 542.7 mm; sets with these values: 2
Pset_PlateCommon - LoadBearing: no; Reference: 245
BaseQuantities - Width: 155.652 mm; NetArea: 0.102611 m2; GrossArea: 0.0844788 m2; CrossSectionArea: 0.0001 m2; NetVolume: 0.00044954 m3; GrossVolume: 0.00044954 m3
Name | Repère d'assemblage
Unnamed | K54
Unnamed | K55

# IfcPlate: PL10*168, PLAT
In: Undefined
Description: PL10*168; Material: STEEL/E24-2
Tekla Commun - Finition: GRENAILLE-PEINT; Repère de pièce: 269; Repère d'assemblage: H91; Phase: 2; Profil: PL10*168; Nom: PLAT; sets with these values: 2
Tekla Quantités - Poids: 2.3 kg; Volume: 0 m3; Surface supérieure totale: 0 m2; Surface par tonne: 28.5 m2; Surface nette: 0.1 m2; Hauteur: 167.8 mm; Largeur: 10 mm; Longueur: 192.9 mm; sets with these values: 2
Pset_PlateCommon - LoadBearing: no; Reference: 269
BaseQuantities - Width: 167.77 mm; NetArea: 0.0656014 m2; GrossArea: 0.0323551 m2; CrossSectionArea: 0.0001 m2; NetVolume: 0.000294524 m3; GrossVolume: 0.000294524 m3

# IfcPlate: PL10*170 (11)
In: Undefined
Description: PL10*170; Material: STEEL/E24-2
Tekla Commun - Finition: GRENAILLE-PEINT; Phase: 1; Profil: PL10*170; Nom: PLATINE; sets with these values: 2
Tekla Quantités - Volume: 0 m3; Surface supérieure totale: 0 m2; Surface par tonne: 28.5 m2; Surface nette: 0.1 m2; Largeur: 10 mm; sets with these values: 2
Pset_PlateCommon - LoadBearing: no
BaseQuantities - CrossSectionArea: 0.0001 m2
Name | Repère de pièce = Reference | Repère d'assemblage | Poids (kg) | Hauteur (mm) | Longueur (mm) | Width (mm) | NetArea (m2) | GrossArea (m2) | NetVolume (m3) = GrossVolume (m3)
PLATINE | 289 | P26 | 3.4 | 170 | 279.9 | 169.89 | 0.0997588 | 0.0475465 | 0.000446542
PLATINE | 288 | P23 | 3.3 | 170 | 268.9 | 169.904 | 0.0953963 | 0.0456835 | 0.000425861
PLATINE | 289 | P22 | 3.4 | 170 | 279.9 | 169.89 | 0.0997588 | 0.0475465 | 0.000446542
PLATINE | 288 | P22 | 3.3 | 170 | 268.9 | 169.904 | 0.0953963 | 0.0456835 | 0.000425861
PLATINE | 289 | P25 | 3.4 | 170 | 279.9 | 169.89 | 0.0997588 | 0.0475465 | 0.000446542
PLATINE | 288 | P26 | 3.3 | 170 | 268.9 | 169.904 | 0.0953963 | 0.0456835 | 0.000425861
PLATINE | 289 | P27 | 3.4 | 170 | 279.9 | 169.89 | 0.0997588 | 0.0475465 | 0.000446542
PLATINE | 289 | P23 | 3.4 | 169.8 | 279.9 | 169.89 | 0.0997588 | 0.0475465 | 0.000446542
PLATINE | 288 | P27 | 3.3 | 169.8 | 268.9 | 169.904 | 0.0953963 | 0.0456835 | 0.000425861
PLATINE | 289 | P24 | 3.4 | 169.8 | 279.9 | 169.89 | 0.0997588 | 0.0475465 | 0.000446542
PLATINE | 288 | P25 | 3.3 | 169.8 | 268.9 | 169.904 | 0.0953963 | 0.0456835 | 0.000425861

# IfcPlate: PL10*172, PLATINE
In: Undefined
Description: PL10*172; Material: STEEL/E24-2
Tekla Commun - Finition: GRENAILLE-PEINT; Repère de pièce: 284; Repère d'assemblage: P113; Phase: 3; Profil: PL10*172; Nom: PLATINE; sets with these values: 2
Tekla Quantités - Poids: 3.6 kg; Volume: 0 m3; Surface supérieure totale: 0 m2; Surface par tonne: 28.3 m2; Surface nette: 0.1 m2; Hauteur: 172 mm; Largeur: 10 mm; Longueur: 280.1 mm; sets with these values: 2
Pset_PlateCommon - LoadBearing: no; Reference: 284
BaseQuantities - Width: 172.008 mm; NetArea: 0.101059 m2; GrossArea: 0.0481841 m2; CrossSectionArea: 0.0001 m2; NetVolume: 0.000454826 m3; GrossVolume: 0.000454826 m3

# IfcPlate: PL10*176 (2)
In: Undefined
Description: PL10*176; Material: STEEL/E24-2
Tekla Commun - Finition: GRENAILLE-PEINT; Repère de pièce: 248; Repère d'assemblage: K59; Phase: 1; Profil: PL10*176; sets with these values: 2
Tekla Quantités - Poids: 2 kg; Volume: 0 m3; Surface supérieure totale: 0 m2; Surface par tonne: 29.6 m2; Surface nette: 0.1 m2; Hauteur: 176.4 mm; Largeur: 10 mm; Longueur: 277.1 mm; sets with these values: 2
Pset_PlateCommon - LoadBearing: no; Reference: 248
BaseQuantities - CrossSectionArea: 0.0001 m2
Name | Width (mm) | NetArea (m2) | GrossArea (m2) | NetVolume (m3) = GrossVolume (m3)
Unnamed | 176.416 | 0.0567021 | 0.0488823 | 0.000244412
Unnamed | 176.415 | 0.0567009 | 0.0488812 | 0.000244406

# IfcPlate: PL10*178, GOUSSET
In: Undefined
Description: PL10*178; Material: STEEL/E24-2
Tekla Commun - Finition: GRENAILLE-PEINT; Repère de pièce: 254; Repère d'assemblage: N46; Phase: 2; Profil: PL10*178; Nom: GOUSSET; sets with these values: 2
Tekla Quantités - Poids: 3.9 kg; Volume: 0 m3; Surface supérieure totale: 0 m2; Surface par tonne: 28.5 m2; Surface nette: 0.1 m2; Hauteur: 178.3 mm; Largeur: 10 mm; Longueur: 512.8 mm; sets with these values: 2
Pset_PlateCommon - LoadBearing: no; Reference: 254
BaseQuantities - Width: 178.305 mm; NetArea: 0.113112 m2; GrossArea: 0.0914399 m2; CrossSectionArea: 0.0001 m2; NetVolume: 0.000504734 m3; GrossVolume: 0.000504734 m3

# IfcPlate: PL10*179 (19)
In: Undefined
Description: PL10*179; Material: STEEL/E24-2
Tekla Commun - Finition: GRENAILLE-PEINT; Repère de pièce: 263; Profil: PL10*179; Nom: GOUSSET; sets with these values: 2
Tekla Quantités - Poids: 5.2 kg; Volume: 0 m3; Surface supérieure totale: 0 m2; Surface par tonne: 27.6 m2; Surface nette: 0.1 m2; Hauteur: 179.3 mm; Largeur: 10 mm; Longueur: 367.9 mm; sets with these values: 2
Pset_PlateCommon - LoadBearing: no; Reference: 263
BaseQuantities - Width: 179.305 mm; NetArea: 0.14025 m2; GrossArea: 0.065974 m2; CrossSectionArea: 0.0001 m2; NetVolume: 0.000648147 m3; GrossVolume: 0.000648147 m3
Name | Repère d'assemblage | Phase
2 x GOUSSET | N46 | 2
GOUSSET | N43 | 3
GOUSSET | N44 | 2
GOUSSET | N45 | 2
GOUSSET | N7 | 1
GOUSSET | N6 | 1
2 x GOUSSET | N13 | 1
GOUSSET | N11 | 1
2 x GOUSSET | N8 | 1
2 x GOUSSET | N41 | 1
2 x GOUSSET | N10 | 1
GOUSSET | N40 | 3
GOUSSET | N9 | 3
GOUSSET | N42 | 1

# IfcPlate: PL10*181 (3)
In: Undefined
Description: PL10*181; Material: STEEL/E24-2
Tekla Commun - Finition: GRENAILLE-PEINT; Repère de pièce: 300; Phase: 1; Profil: PL10*181; Nom: GOUSSET; sets with these values: 2
Tekla Quantités - Poids: 2.7 kg; Volume: 0 m3; Surface supérieure totale: 0 m2; Surface par tonne: 28.8 m2; Surface nette: 0.1 m2; Hauteur: 180.6 mm; Largeur: 10 mm; Longueur: 348.1 mm; sets with these values: 2
Pset_PlateCommon - LoadBearing: no; Reference: 300
BaseQuantities - Width: 180.617 mm; NetArea: 0.0768227 m2; GrossArea: 0.0628658 m2; CrossSectionArea: 0.0001 m2; NetVolume: 0.000339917 m3; GrossVolume: 0.000339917 m3
Name | Repère d'assemblage
2 x GOUSSET | N13
GOUSSET | N42

# IfcPlate: PL10*200 (20)
In: Undefined
Description: PL10*200; Material: STEEL/E36-3
Tekla Commun - Finition: GRENAILLE-PEINT; Profil: PL10*200; Nom: PLAT; sets with these values: 2
Tekla Quantités - Poids: 6.3 kg; Volume: 0 m3; Surface supérieure totale: 0 m2; Surface par tonne: 28.3 m2; Surface nette: 0.2 m2; Hauteur: 200.2 mm; Largeur: 10 mm; Longueur: 770 mm; sets with these values: 2
Pset_PlateCommon - LoadBearing: no
BaseQuantities - CrossSectionArea: 0.0001 m2
Name | Repère de pièce = Reference | Repère d'assemblage | Phase | Width (mm) | NetArea (m2) | GrossArea (m2) | NetVolume (m3) = GrossVolume (m3)
PLAT | 219 | N46 | 2 | 200.192 | 0.177407 | 0.154148 | 0.000799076
PLAT | 219 | N44 | 2 | 200.19 | 0.17732 | 0.154147 | 0.000798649
2 x PLAT | 219 | N47 | 1 | 200.192 | 0.177407 | 0.154148 | 0.000799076
PLAT | 219 | N40 | 3 | 200.19 | 0.17732 | 0.154147 | 0.000798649
PLAT | 220 | N43 | 3 | 200.192 | 0.177407 | 0.154148 | 0.000799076
2 x PLAT | 219 | N41 | 1 | 200.192 | 0.177407 | 0.154148 | 0.000799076
2 x PLAT | 219 | N10 | 1 | 200.192 | 0.177407 | 0.154148 | 0.000799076
2 x PLAT | 219 | N8 | 1 | 200.192 | 0.177407 | 0.154148 | 0.000799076
PLAT | 223 | N12 | 1 | 200.192 | 0.177407 | 0.154148 | 0.000799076
PLAT | 219 | N11 | 1 | 200.192 | 0.177407 | 0.154148 | 0.000799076
PLAT | 219 | N45 | 2 | 200.192 | 0.177407 | 0.154148 | 0.000799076
PLAT | 219 | N49 | 2 | 200.19 | 0.17732 | 0.154147 | 0.000798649
PLAT | 219 | N7 | 1 | 200.192 | 0.177407 | 0.154148 | 0.000799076
PLAT | 219 | N6 | 1 | 200.192 | 0.177407 | 0.154148 | 0.000799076
PLAT | 219 | N9 | 3 | 200.192 | 0.177407 | 0.154148 | 0.000799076
PLAT | 219 | N48 | 3 | 200.19 | 0.17732 | 0.154147 | 0.000798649

# IfcPlate: PL10*205, GOUSSET
In: Undefined
Description: PL10*205; Material: STEEL/E24-2
Tekla Commun - Finition: GRENAILLE-PEINT; Repère de pièce: 264; Repère d'assemblage: N43; Phase: 3; Profil: PL10*205; Nom: GOUSSET; sets with these values: 2
Tekla Quantités - Poids: 4.5 kg; Volume: 0 m3; Surface supérieure totale: 0 m2; Surface par tonne: 27.8 m2; Surface nette: 0.1 m2; Hauteur: 205.1 mm; Largeur: 10 mm; Longueur: 367.9 mm; sets with these values: 2
Pset_PlateCommon - LoadBearing: no; Reference: 264
BaseQuantities - Width: 205.135 mm; NetArea: 0.124733 m2; GrossArea: 0.0754779 m2; CrossSectionArea: 0.0001 m2; NetVolume: 0.00057224 m3; GrossVolume: 0.00057224 m3

# IfcPlate: PL10*206, GOUSSET
In: Undefined
Description: PL10*206; Material: STEEL/E24-2
Tekla Commun - Finition: GRENAILLE-PEINT; Repère de pièce: 255; Repère d'assemblage: N43; Phase: 3; Profil: PL10*206; Nom: GOUSSET; sets with these values: 2
Tekla Quantités - Poids: 3.1 kg; Volume: 0 m3; Surface supérieure totale: 0 m2; Surface par tonne: 28.5 m2; Surface nette: 0.1 m2; Hauteur: 205.5 mm; Largeur: 10 mm; Longueur: 331.9 mm; sets with these values: 2
Pset_PlateCommon - LoadBearing: no; Reference: 255
BaseQuantities - Width: 205.525 mm; NetArea: 0.0889033 m2; GrossArea: 0.068204 m2; CrossSectionArea: 0.0001 m2; NetVolume: 0.000398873 m3; GrossVolume: 0.000398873 m3

# IfcPlate: PL10*209 (16)
In: Undefined
Description: PL10*209; Material: STEEL/E24-2
Tekla Commun - Finition: GRENAILLE-PEINT; Profil: PL10*209; sets with these values: 2
Tekla Quantités - Volume: 0 m3; Surface supérieure totale: 0 m2; Surface nette: 0.1 m2; Largeur: 10 mm; sets with these values: 2
Pset_PlateCommon - LoadBearing: no
BaseQuantities - CrossSectionArea: 0.0001 m2
Name | Repère de pièce = Reference | Repère d'assemblage | Phase | Nom | Poids (kg) | Surface par tonne (m2) | Hauteur (mm) | Longueur (mm) | Width (mm) | NetArea (m2) | GrossArea (m2) | NetVolume (m3) = GrossVolume (m3)
PLAT | 267 | H84 | 2 | PLAT | 3.1 | 28 | 209 | 258.8 | 208.868 | 0.0865421 | 0.0540574 | 0.000393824
GOUSSET | 299 | N46 | 2 | GOUSSET | 2.8 | 28.6 | 209.2 | 300 | 209.23 | 0.0795723 | 0.062769 | 0.000355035
GOUSSET | 299 | N43 | 3 | GOUSSET | 2.8 | 28.6 | 209.2 | 300 | 209.23 | 0.0795723 | 0.062769 | 0.000355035
GOUSSET | 299 | N44 | 2 | GOUSSET | 2.8 | 28.6 | 209.2 | 300 | 209.23 | 0.0795723 | 0.062769 | 0.000355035
GOUSSET | 299 | N45 | 2 | GOUSSET | 2.8 | 28.6 | 209.2 | 300 | 209.23 | 0.0795723 | 0.062769 | 0.000355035
GOUSSET | 299 | N7 | 1 | GOUSSET | 2.8 | 28.6 | 209.2 | 300 | 209.23 | 0.0795723 | 0.062769 | 0.000355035
GOUSSET | 299 | N6 | 1 | GOUSSET | 2.8 | 28.6 | 209.2 | 300 | 209.23 | 0.0795723 | 0.062769 | 0.000355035
GOUSSET | 299 | N11 | 1 | GOUSSET | 2.8 | 28.6 | 209.2 | 300 | 209.23 | 0.0795723 | 0.062769 | 0.000355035
2 x GOUSSET | 299 | N8 | 1 | GOUSSET | 2.8 | 28.6 | 209.2 | 300 | 209.23 | 0.0795723 | 0.062769 | 0.000355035
2 x GOUSSET | 299 | N41 | 1 | GOUSSET | 2.8 | 28.6 | 209.2 | 300 | 209.23 | 0.0795723 | 0.062769 | 0.000355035
2 x GOUSSET | 299 | N10 | 1 | GOUSSET | 2.8 | 28.6 | 209.2 | 300 | 209.23 | 0.0795723 | 0.062769 | 0.000355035
GOUSSET | 299 | N40 | 3 | GOUSSET | 2.8 | 28.6 | 209.2 | 300 | 209.23 | 0.0795723 | 0.062769 | 0.000355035
GOUSSET | 299 | N9 | 3 | GOUSSET | 2.8 | 28.6 | 209.2 | 300 | 209.23 | 0.0795723 | 0.062769 | 0.000355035

# IfcPlate: PL10*212, PLAT
In: Undefined
Description: PL10*212; Material: STEEL/E24-2
Tekla Commun - Finition: GRENAILLE-PEINT; Repère de pièce: 268; Repère d'assemblage: H83; Phase: 2; Profil: PL10*212; Nom: PLAT; sets with these values: 2
Tekla Quantités - Poids: 3 kg; Volume: 0 m3; Surface supérieure totale: 0 m2; Surface par tonne: 28 m2; Surface nette: 0.1 m2; Hauteur: 212.4 mm; Largeur: 10 mm; Longueur: 253.5 mm; sets with these values: 2
Pset_PlateCommon - LoadBearing: no; Reference: 268
BaseQuantities - Width: 212.401 mm; NetArea: 0.0853797 m2; GrossArea: 0.0538427 m2; CrossSectionArea: 0.0001 m2; NetVolume: 0.000388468 m3; GrossVolume: 0.000388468 m3

# IfcPlate: PL10*220 (2)
In: Undefined
Description: PL10*220; Material: STEEL/E24-2
Tekla Commun - Finition: GRENAILLE-PEINT; Repère de pièce: 188; Repère d'assemblage: H2; Profil: PL10*220; Nom: ATTACHE; sets with these values: 2
Tekla Quantités - Poids: 4.2 kg; Volume: 0 m3; Surface supérieure totale: 0 m2; Surface par tonne: 27.8 m2; Surface nette: 0.1 m2; Hauteur: 220 mm; Largeur: 10 mm; Longueur: 245 mm; sets with these values: 2
Pset_PlateCommon - LoadBearing: no; Reference: 188
BaseQuantities - Width: 220 mm; NetArea: 0.1171 m2; GrossArea: 0.0539 m2; CrossSectionArea: 0.0001 m2; NetVolume: 0.000539 m3; GrossVolume: 0.000539 m3
Name | Phase
ATTACHE | 3
ATTACHE | 2

# IfcPlate: PL10*265, Unnamed
In: Undefined
Description: PL10*265; Material: STEEL/E24-2
Tekla Commun - Finition: GRENAILLE-PEINT; Repère de pièce: 240; Repère d'assemblage: P115; Phase: 1; Profil: PL10*265; sets with these values: 2
Tekla Quantités - Poids: 8.2 kg; Volume: 0 m3; Surface supérieure totale: 0 m2; Surface par tonne: 27.1 m2; Surface nette: 0.2 m2; Hauteur: 264.7 mm; Largeur: 10 mm; Longueur: 400.1 mm; sets with these values: 2
Pset_PlateCommon - LoadBearing: no; Reference: 240
BaseQuantities - Width: 264.676 mm; NetArea: 0.224381 m2; GrossArea: 0.105898 m2; CrossSectionArea: 0.0001 m2; NetVolume: 0.00105606 m3; GrossVolume: 0.00105606 m3

# IfcPlate: PL10*286, Unnamed
In: Undefined
Description: PL10*286; Material: STEEL/E24-2
Tekla Commun - Finition: GRENAILLE-PEINT; Repère de pièce: 200; Repère d'assemblage: P115; Phase: 1; Profil: PL10*286; sets with these values: 2
Tekla Quantités - Poids: 7 kg; Volume: 0 m3; Surface supérieure totale: 0 m2; Surface par tonne: 27.3 m2; Surface nette: 0.2 m2; Hauteur: 286.1 mm; Largeur: 10 mm; Longueur: 400.1 mm; sets with these values: 2
Pset_PlateCommon - LoadBearing: no; Reference: 200
BaseQuantities - Width: 286.11 mm; NetArea: 0.190685 m2; GrossArea: 0.114476 m2; CrossSectionArea: 0.0001 m2; NetVolume: 0.000892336 m3; GrossVolume: 0.000892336 m3

# IfcPlate: PL10*308 (8)
In: Undefined
Description: PL10*308; Material: STEEL/E24-2
Tekla Commun - Finition: GRENAILLE-PEINT; Repère de pièce: 206; Profil: PL10*308; Nom: PLATINE; sets with these values: 2
Tekla Quantités - Poids: 24.2 kg; Volume: 0 m3; Surface supérieure totale: 0 m2; Surface par tonne: 27.3 m2; Surface nette: 0.6 m2; Hauteur: 307.8 mm; Largeur: 10 mm; Longueur: 1969 mm; sets with these values: 2
Pset_PlateCommon - LoadBearing: no; Reference: 206
BaseQuantities - Width: 307.764 mm; GrossArea: 0.605998 m2; CrossSectionArea: 0.0001 m2
Name | Repère d'assemblage | Phase | NetArea (m2) | NetVolume (m3) = GrossVolume (m3)
2 x PLATINE | K21 | 1 | 0.657588 | 0.00307652
PLATINE | K22 | 1 | 0.657588 | 0.00307652
PLATINE | K24 | 1 | 0.657588 | 0.00307652
PLATINE | K22 | 3 | 0.657588 | 0.00307652
PLATINE | K23 | 3 | 0.657588 | 0.00307652
PLATINE | K21 | 3 | 0.65758 | 0.00307647
PLATINE | K21 | 3 | 0.657588 | 0.00307652

# IfcPlate: PL10*50 (5)
In: Undefined
Description: PL10*50; Material: STEEL/S235JR
Tekla Commun - Finition: GRENAILLE-PEINT; Repère de pièce: 244; Phase: 1; Profil: PL10*50; Nom: TOLE; sets with these values: 2
Tekla Quantités - Poids: 0.6 kg; Volume: 0 m3; Surface supérieure totale: 0 m2; Surface par tonne: 31.9 m2; Surface nette: 0 m2; Hauteur: 50 mm; Largeur: 10 mm; Longueur: 180 mm; sets with these values: 2
Pset_PlateCommon - LoadBearing: no; Reference: 244
BaseQuantities - Width: 50 mm; NetArea: 0.0219743 m2; GrossArea: 0.009 m2; CrossSectionArea: 0.0001 m2; NetVolume: 0.00008775 m3; GrossVolume: 0.00008775 m3
Name | Repère d'assemblage
3 x TOLE | P8
2 x TOLE | P6

# IfcPlate: PL10*70 (973)
In: Undefined
Description: PL10*70
Tekla Commun - Profil: PL10*70; sets with these values: 2
Tekla Quantités - Volume: 0 m3; Surface supérieure totale: 0 m2; Hauteur: 70 mm; Largeur: 10 mm; sets with these values: 2
Pset_PlateCommon - LoadBearing: no
BaseQuantities - CrossSectionArea: 0.0001 m2
Name | Material | Finition | Repère de pièce = Reference | Repère d'assemblage | Phase | Nom | Poids (kg) | Surface par tonne (m2) | Surface nette (m2) | Longueur (mm) | Width (mm) | NetArea (m2) | GrossArea (m2) | NetVolume (m3) = GrossVolume (m3)
4 x PLATINE | STEEL/E36-3 | GRENAILLE-PEINT | 179 | P114 | 3 | PLATINE | 1.4 | 30 | 0 | 277.6 | 70 | 0.0451903 | 0.019432 | 0.00019207
PLATINE | STEEL/E36-3 | GRENAILLE-PEINT | 185 | P113 | 3 | PLATINE | 1.4 | 30 | 0 | 277.6 | 70 | 0.0451903 | 0.019432 | 0.00019207
9 x PLATINE | STEEL/E36-3 | GRENAILLE-PEINT | 179 | P113 | 3 | PLATINE | 1.4 | 30 | 0 | 277.6 | 70 | 0.0451903 | 0.019432 | 0.00019207
2 x PLATINE | STEEL/E36-3 | GRENAILLE-PEINT | 185 | P121 | 3 | PLATINE | 1.4 | 30 | 0 | 277.6 | 70 | 0.0451903 | 0.019432 | 0.00019207
2 x PLATINE | STEEL/E36-3 | GRENAILLE-PEINT | 179 | P121 | 3 | PLATINE | 1.4 | 30 | 0 | 277.6 | 70 | 0.0451903 | 0.019432 | 0.00019207
2 x PLATINE | STEEL/E36-3 | GRENAILLE-PEINT | 185 | P120 | 3 | PLATINE | 1.4 | 30 | 0 | 277.6 | 70 | 0.0451903 | 0.019432 | 0.00019207
2 x PLATINE | STEEL/E36-3 | GRENAILLE-PEINT | 179 | P120 | 3 | PLATINE | 1.4 | 30 | 0 | 277.6 | 70 | 0.0451903 | 0.019432 | 0.00019207
9 x PLATINE | STEEL/E36-3 | GRENAILLE-PEINT | 179 | P119 | 2 | PLATINE | 1.4 | 30 | 0 | 277.6 | 70 | 0.0451903 | 0.019432 | 0.00019207
PLAT | STEEL/E24-2 | GRENAILLE-PEINT | 196 | H82 | 2 | PLAT | 0.9 | 30.9 | 0 | 142 | 69.9057 | 0.0240913 | 0.00992692 | 0.0000992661
TOLE | STEEL/S235JR |  | 215 | K49 | 1 | TOLE | 1.4 | 30 | 0 | 276.4 | 70 | 0.0445408 | 0.0193514 | 0.000189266
8 x PLAT | STEEL/E36-3 | GRENAILLE-PEINT | 222 | N46 | 2 | PLAT | 2 | 29.8 | 0.1 | 380.1 | 70 | 0.0600752 | 0.0266101 | 0.000257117
16 x PLAT | STEEL/E36-3 | GRENAILLE-PEINT | 221 | N46 | 2 | PLAT | 1.4 | 30 | 0 | 276.6 | 70 | 0.0450302 | 0.019362 | 0.00019137
24 x PLAT | STEEL/E36-3 | GRENAILLE-PEINT | 302 | N43 | 3 | PLAT | 1.4 | 30 | 0 | 276.6 | 70 | 0.0450302 | 0.019362 | 0.00019137
8 x PLAT | STEEL/E36-3 | GRENAILLE-PEINT | 303 | N43 | 3 | PLAT | 2 | 29.8 | 0.1 | 380.1 | 70 | 0.0600752 | 0.0266101 | 0.000257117
24 x PLAT | STEEL/E36-3 | GRENAILLE-PEINT | 221 | N45 | 2 | PLAT | 1.4 | 30 | 0 | 276.6 | 70 | 0.0450302 | 0.019362 | 0.00019137
8 x PLAT | STEEL/E36-3 | GRENAILLE-PEINT | 222 | N45 | 2 | PLAT | 2 | 29.8 | 0.1 | 380.1 | 70 | 0.0600752 | 0.0266101 | 0.000257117
8 x PLAT | STEEL/E36-3 | GRENAILLE-PEINT | 222 | N44 | 2 | PLAT | 2 | 29.8 | 0.1 | 380.1 | 70 | 0.0600752 | 0.0266101 | 0.000257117
32 x PLAT | STEEL/E36-3 | GRENAILLE-PEINT | 221 | N44 | 2 | PLAT | 1.4 | 30 | 0 | 276.6 | 70 | 0.0450302 | 0.019362 | 0.00019137
32 x PLAT | STEEL/E36-3 | GRENAILLE-PEINT | 221 | N49 | 2 | PLAT | 1.4 | 30 | 0 | 276.6 | 70 | 0.0450302 | 0.019362 | 0.00019137
4 x PLAT | STEEL/E36-3 | GRENAILLE-PEINT | 222 | N49 | 2 | PLAT | 2 | 29.8 | 0.1 | 380.1 | 70 | 0.0600752 | 0.0266101 | 0.000257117
8 x PLAT | STEEL/E36-3 | GRENAILLE-PEINT | 222 | N6 | 1 | PLAT | 2 | 29.8 | 0.1 | 380.1 | 70 | 0.0600752 | 0.0266101 | 0.000257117
32 x PLAT | STEEL/E36-3 | GRENAILLE-PEINT | 221 | N6 | 1 | PLAT | 1.4 | 30 | 0 | 276.6 | 70 | 0.0450302 | 0.019362 | 0.00019137
24 x PLAT | STEEL/E36-3 | GRENAILLE-PEINT | 221 | N11 | 1 | PLAT | 1.4 | 30 | 0 | 276.6 | 70 | 0.0450302 | 0.019362 | 0.00019137
8 x PLAT | STEEL/E36-3 | GRENAILLE-PEINT | 222 | N11 | 1 | PLAT | 2 | 29.8 | 0.1 | 380.1 | 70 | 0.0600752 | 0.0266101 | 0.000257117
8 x PLAT | STEEL/E36-3 | GRENAILLE-PEINT | 222 | N7 | 1 | PLAT | 2 | 29.8 | 0.1 | 380.1 | 70 | 0.0600752 | 0.0266101 | 0.000257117
32 x PLAT | STEEL/E36-3 | GRENAILLE-PEINT | 221 | N7 | 1 | PLAT | 1.4 | 30 | 0 | 276.6 | 70 | 0.0450302 | 0.019362 | 0.00019137
32 x PLAT | STEEL/E36-3 | GRENAILLE-PEINT | 221 | N12 | 1 | PLAT | 1.4 | 30 | 0 | 276.6 | 70 | 0.0450302 | 0.019362 | 0.00019137
4 x PLAT | STEEL/E36-3 | GRENAILLE-PEINT | 222 | N12 | 1 | PLAT | 2 | 29.8 | 0.1 | 380.1 | 70 | 0.0600752 | 0.0266101 | 0.000257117
48 x PLAT | STEEL/E36-3 | GRENAILLE-PEINT | 221 | N13 | 1 | PLAT | 1.4 | 30 | 0 | 276.6 | 70 | 0.0450302 | 0.019362 | 0.00019137
16 x PLAT | STEEL/E36-3 | GRENAILLE-PEINT | 222 | N13 | 1 | PLAT | 2 | 29.8 | 0.1 | 380.1 | 70 | 0.0600752 | 0.0266101 | 0.000257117
16 x PLAT | STEEL/E36-3 | GRENAILLE-PEINT | 221 | N17 | 1 | PLAT | 1.4 | 30 | 0 | 276.6 | 70 | 0.0450302 | 0.019362 | 0.00019137
16 x PLAT | STEEL/E36-3 | GRENAILLE-PEINT | 221 | N14 | 1 | PLAT | 1.4 | 30 | 0 | 276.6 | 70 | 0.0450302 | 0.019362 | 0.00019137
16 x PLAT | STEEL/E36-3 | GRENAILLE-PEINT | 222 | N41 | 1 | PLAT | 2 | 29.8 | 0.1 | 380.1 | 70 | 0.0600752 | 0.0266101 | 0.000257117
64 x PLAT | STEEL/E36-3 | GRENAILLE-PEINT | 221 | N41 | 1 | PLAT | 1.4 | 30 | 0 | 276.6 | 70 | 0.0450302 | 0.019362 | 0.00019137
48 x PLAT | STEEL/E36-3 | GRENAILLE-PEINT | 221 | N10 | 1 | PLAT | 1.4 | 30 | 0 | 276.6 | 70 | 0.0450302 | 0.019362 | 0.00019137
16 x PLAT | STEEL/E36-3 | GRENAILLE-PEINT | 222 | N10 | 1 | PLAT | 2 | 29.8 | 0.1 | 380.1 | 70 | 0.0600752 | 0.0266101 | 0.000257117
16 x PLAT | STEEL/E36-3 | GRENAILLE-PEINT | 222 | N8 | 1 | PLAT | 2 | 29.8 | 0.1 | 380.1 | 70 | 0.0600752 | 0.0266101 | 0.000257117
64 x PLAT | STEEL/E36-3 | GRENAILLE-PEINT | 221 | N8 | 1 | PLAT | 1.4 | 30 | 0 | 276.6 | 70 | 0.0450302 | 0.019362 | 0.00019137
64 x PLAT | STEEL/E36-3 | GRENAILLE-PEINT | 221 | N47 | 1 | PLAT | 1.4 | 30 | 0 | 276.6 | 70 | 0.0450302 | 0.019362 | 0.00019137
8 x PLAT | STEEL/E36-3 | GRENAILLE-PEINT | 222 | N47 | 1 | PLAT | 2 | 29.8 | 0.1 | 380.1 | 70 | 0.0600752 | 0.0266101 | 0.000257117
16 x PLAT | STEEL/E36-3 | GRENAILLE-PEINT | 221 | N38 | 1 | PLAT | 1.4 | 30 | 0 | 276.6 | 70 | 0.0450302 | 0.019362 | 0.00019137
32 x PLAT | STEEL/E36-3 | GRENAILLE-PEINT | 221 | N16 | 1 | PLAT | 1.4 | 30 | 0 | 276.6 | 70 | 0.0450302 | 0.019362 | 0.00019137
24 x PLAT | STEEL/E36-3 | GRENAILLE-PEINT | 221 | N9 | 3 | PLAT | 1.4 | 30 | 0 | 276.6 | 70 | 0.0450302 | 0.019362 | 0.00019137
8 x PLAT | STEEL/E36-3 | GRENAILLE-PEINT | 222 | N9 | 3 | PLAT | 2 | 29.8 | 0.1 | 380.1 | 70 | 0.0600752 | 0.0266101 | 0.000257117
8 x PLAT | STEEL/E36-3 | GRENAILLE-PEINT | 222 | N40 | 3 | PLAT | 2 | 29.8 | 0.1 | 380.1 | 70 | 0.0600752 | 0.0266101 | 0.000257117
32 x PLAT | STEEL/E36-3 | GRENAILLE-PEINT | 221 | N40 | 3 | PLAT | 1.4 | 30 | 0 | 276.6 | 70 | 0.0450302 | 0.019362 | 0.00019137
32 x PLAT | STEEL/E36-3 | GRENAILLE-PEINT | 221 | N48 | 3 | PLAT | 1.4 | 30 | 0 | 276.6 | 70 | 0.0450302 | 0.019362 | 0.00019137
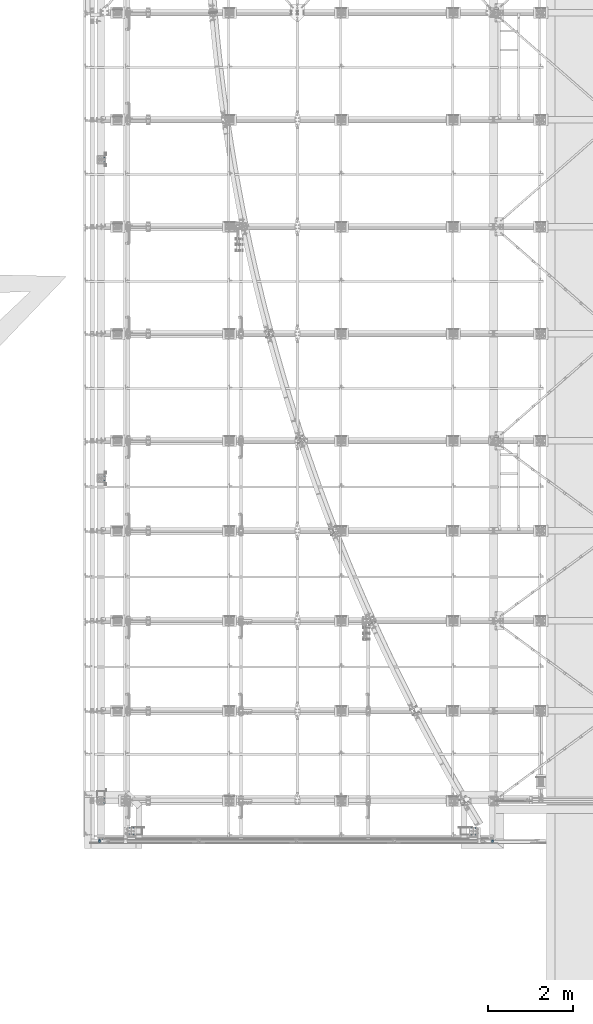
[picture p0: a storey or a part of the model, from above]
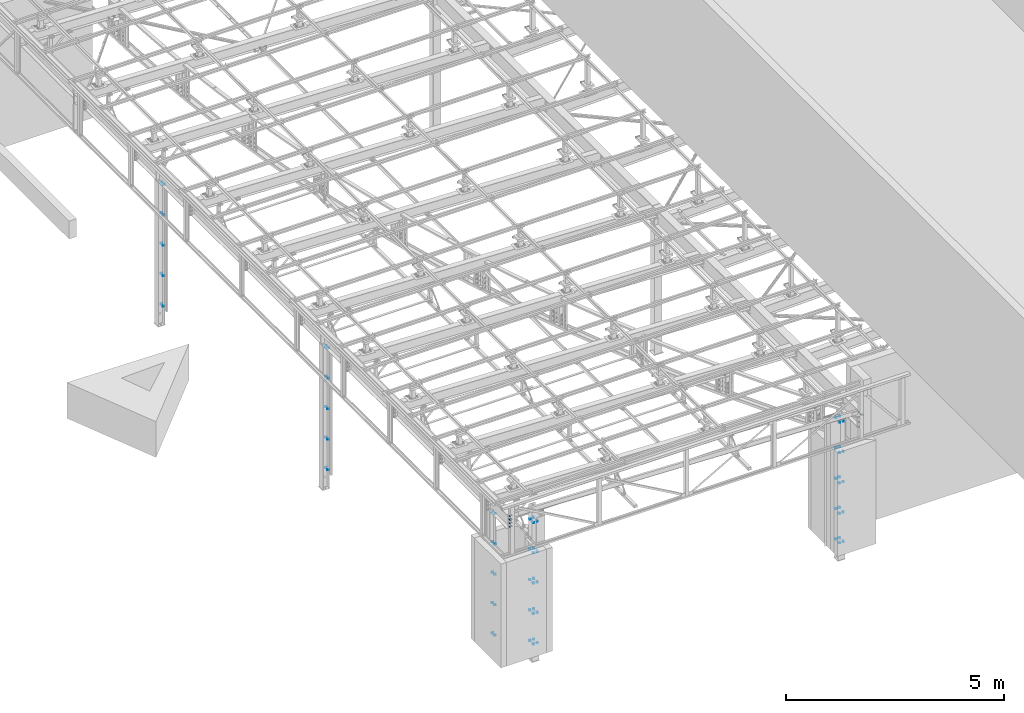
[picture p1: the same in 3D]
Properties of the parts of a building model (IFC2X3), part 12 of 13

# IfcPlate: PL10*70 (973)
Name | Material | Finition | Repère de pièce = Reference | Repère d'assemblage | Phase | Nom | Poids (kg) | Surface par tonne (m2) | Surface nette (m2) | Longueur (mm) | Width (mm) | NetArea (m2) | GrossArea (m2) | NetVolume (m3) = GrossVolume (m3)
4 x PLAT | STEEL/E36-3 | GRENAILLE-PEINT | 222 | N48 | 3 | PLAT | 2 | 29.8 | 0.1 | 380.1 | 70 | 0.0600752 | 0.0266101 | 0.000257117
16 x PLAT | STEEL/E36-3 | GRENAILLE-PEINT | 221 | N15 | 3 | PLAT | 1.4 | 30 | 0 | 276.6 | 70 | 0.0450302 | 0.019362 | 0.00019137
16 x PLAT | STEEL/E36-3 | GRENAILLE-PEINT | 221 | N18 | 2 | PLAT | 1.4 | 30 | 0 | 276.6 | 70 | 0.0450302 | 0.019362 | 0.00019137
24 x PLAT | STEEL/E36-3 | GRENAILLE-PEINT | 221 | N42 | 1 | PLAT | 1.4 | 30 | 0 | 276.6 | 70 | 0.0450302 | 0.019362 | 0.00019137
16 x PLAT | STEEL/E36-3 | GRENAILLE-PEINT | 221 | N39 | 1 | PLAT | 1.4 | 30 | 0 | 276.6 | 70 | 0.0450302 | 0.019362 | 0.00019137
8 x PLAT | STEEL/E36-3 | GRENAILLE-PEINT | 222 | N42 | 1 | PLAT | 2 | 29.8 | 0.1 | 380.1 | 70 | 0.0600752 | 0.0266101 | 0.000257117

# IfcPlate: PL10*75, TOLE
In: Undefined
Description: PL10*75; Material: STEEL/S235JR
Tekla Commun - Finition: GRENAILLE-PEINT; Repère de pièce: 282; Repère d'assemblage: N36; Phase: 1; Profil: PL10*75; Nom: TOLE; sets with these values: 2
Tekla Quantités - Poids: 1.6 kg; Volume: 0 m3; Surface supérieure totale: 0 m2; Surface par tonne: 29.8 m2; Surface nette: 0 m2; Hauteur: 75 mm; Largeur: 10 mm; Longueur: 269.1 mm; sets with these values: 2
Pset_PlateCommon - LoadBearing: no; Reference: 282
BaseQuantities - Width: 75 mm; NetArea: 0.0466213 m2; GrossArea: 0.0201825 m2; CrossSectionArea: 0.0001 m2; NetVolume: 0.000199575 m3; GrossVolume: 0.000199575 m3

# IfcPlate: PL10*80 (11)
In: Undefined
Description: PL10*80
Tekla Commun - Profil: PL10*80; Nom: TOLE; sets with these values: 2
Tekla Quantités - Volume: 0 m3; Surface supérieure totale: 0 m2; Hauteur: 80 mm; Largeur: 10 mm; sets with these values: 2
Pset_PlateCommon - LoadBearing: no
BaseQuantities - Width: 80 mm; CrossSectionArea: 0.0001 m2
Name | Material | Finition | Repère de pièce = Reference | Repère d'assemblage | Phase | Poids (kg) | Surface par tonne (m2) | Surface nette (m2) | Longueur (mm) | NetArea (m2) | GrossArea (m2) | NetVolume (m3) = GrossVolume (m3)
2 x TOLE | STEEL/E24-2 | GRENAILLE-PEINT | 197 | P127 | 2 | 0.9 | 30.3 | 0 | 150.9 | 0.0281543 | 0.01208 | 0.00011855
2 x TOLE | STEEL/E24-2 | GRENAILLE-PEINT | 197 | P126 | 2 | 0.9 | 30.3 | 0 | 150.9 | 0.0281543 | 0.01208 | 0.00011855
TOLE | STEEL/S235JR |  | 216 | K99 | 1 | 1.7 | 29.5 | 0.1 | 285.2 | 0.0518438 | 0.0228155 | 0.000223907
TOLE | STEEL/S235JR |  | 218 | K99 | 1 | 2.1 | 29.5 | 0.1 | 335.9 | 0.060965 | 0.0268694 | 0.000264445
TOLE | STEEL/S235JR |  | 217 | K49 | 1 | 1.7 | 29.5 | 0.1 | 276.4 | 0.0502698 | 0.0221159 | 0.000216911
4 x TOLE | STEEL/S235JR | GRENAILLE-PEINT | 281 | N36 | 1 | 1.7 | 29.5 | 0.1 | 275.6 | 0.0505823 | 0.022048 | 0.00021823

# IfcPlate: PL10*86 (2)
In: Undefined
Description: PL10*86; Material: STEEL/E24-2
Tekla Commun - Finition: GRENAILLE-PEINT; Repère de pièce: 295; Phase: 2; Profil: PL10*86; Nom: TOLE; sets with these values: 2
Tekla Quantités - Poids: 2.4 kg; Volume: 0 m3; Surface supérieure totale: 0 m2; Surface par tonne: 29.1 m2; Surface nette: 0.1 m2; Hauteur: 85.7 mm; Largeur: 10 mm; Longueur: 372 mm; sets with these values: 2
Pset_PlateCommon - LoadBearing: no; Reference: 295
BaseQuantities - Width: 85.7 mm; NetArea: 0.0713719 m2; GrossArea: 0.0318804 m2; CrossSectionArea: 0.0001 m2; NetVolume: 0.000312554 m3; GrossVolume: 0.000312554 m3
Name | Repère d'assemblage
TOLE | N20
TOLE | N22

# IfcPlate: PL10*89 (9)
In: Undefined
Description: PL10*89
Tekla Commun - Finition: GRENAILLE-PEINT; Profil: PL10*89; sets with these values: 2
Tekla Quantités - Volume: 0 m3; Surface supérieure totale: 0 m2; Largeur: 10 mm; sets with these values: 2
Pset_PlateCommon - LoadBearing: no
BaseQuantities - CrossSectionArea: 0.0001 m2
Name | Material | Repère de pièce = Reference | Repère d'assemblage | Phase | Nom | Poids (kg) | Surface par tonne (m2) | Surface nette (m2) | Hauteur (mm) | Longueur (mm) | Width (mm) | NetArea (m2) | GrossArea (m2) | NetVolume (m3) = GrossVolume (m3)
TOLE | STEEL/S235JR | 214 | N36 | 1 | TOLE | 0.9 | 30.1 | 0 | 89.3 | 138.7 | 89.32 | 0.0290189 | 0.012386 | 0.000122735
2 x PLATINE | STEEL/E24-2 | 205 | K21 | 1 | PLATINE | 1.7 | 31.3 | 0.1 | 88.8 | 487.7 | 88.8324 | 0.0564755 | 0.0433205 | 0.000230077
PLATINE | STEEL/E24-2 | 205 | K22 | 1 | PLATINE | 1.7 | 31.3 | 0.1 | 88.8 | 487.7 | 88.8319 | 0.0564714 | 0.0433206 | 0.000230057
PLATINE | STEEL/E24-2 | 205 | K24 | 1 | PLATINE | 1.7 | 31.3 | 0.1 | 88.8 | 487.7 | 88.8319 | 0.0564714 | 0.0433206 | 0.000230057
PLATINE | STEEL/E24-2 | 205 | K22 | 3 | PLATINE | 1.7 | 31.3 | 0.1 | 88.8 | 487.7 | 88.8319 | 0.0564714 | 0.0433206 | 0.000230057
PLATINE | STEEL/E24-2 | 205 | K23 | 3 | PLATINE | 1.7 | 31.3 | 0.1 | 88.8 | 487.7 | 88.8319 | 0.0564714 | 0.0433206 | 0.000230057
2 x PLATINE | STEEL/E24-2 | 205 | K21 | 3 | PLATINE | 1.7 | 31.3 | 0.1 | 88.8 | 487.7 | 88.8324 | 0.0564755 | 0.0433205 | 0.000230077

# IfcPlate: PL10*90 (53)
In: Undefined
Description: PL10*90
Tekla Commun - Finition: GRENAILLE-PEINT; Profil: PL10*90; sets with these values: 2
Tekla Quantités - Volume: 0 m3; Surface supérieure totale: 0 m2; Largeur: 10 mm; sets with these values: 2
Pset_PlateCommon - LoadBearing: no
BaseQuantities - CrossSectionArea: 0.0001 m2
Name | Material | Repère de pièce = Reference | Repère d'assemblage | Phase | Nom | Poids (kg) | Surface par tonne (m2) | Surface nette (m2) | Hauteur (mm) | Longueur (mm) | Width (mm) | NetArea (m2) | GrossArea (m2) | NetVolume (m3) = GrossVolume (m3)
PLAT | STEEL/E24-2 | 271 | H82 | 2 | PLAT | 0.9 | 30.1 | 0 | 90.2 | 142 | 90.1929 | 0.0302587 | 0.012808 | 0.000128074
Unnamed | STEEL/E24-2 | 247 | K57 | 1 |  | 1.4 | 30 | 0 | 90 | 300 | 89.9981 | 0.0445442 | 0.0269996 | 0.000188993
Unnamed | STEEL/E24-2 | 247 | K58 | 1 |  | 1.4 | 30 | 0 | 90 | 300 | 89.9981 | 0.0445442 | 0.0269996 | 0.000188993
Unnamed | STEEL/E24-2 | 247 | K56 | 1 |  | 1.4 | 30 | 0 | 90 | 300 | 89.9981 | 0.0445442 | 0.0269996 | 0.000188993
Unnamed | STEEL/E24-2 | 247 | K45 | 1 |  | 1.4 | 30 | 0 | 90 | 300 | 89.9981 | 0.0445442 | 0.0269996 | 0.000188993
TOLE | STEEL/S235JR | 251 | P123 | 1 | TOLE | 1.4 | 29.5 | 0 | 90.2 | 213.3 | 90.0955 | 0.0440436 | 0.0192168 | 0.000190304
10 x PLATINE | STEEL/E36-3 | 171 | P22 | 1 | PLATINE | 3.3 | 28.8 | 0.1 | 90 | 467 | 90 | 0.0936571 | 0.04203 | 0.00041405
3 x TOLE | STEEL/S235JR | 213 | N5 | 1 | TOLE | 1.4 | 29.6 | 0 | 90 | 198.3 | 90 | 0.0406786 | 0.0178425 | 0.0001753
PLATINE | STEEL/E24-2 | 180 | P24 | 1 | PLATINE | 2 | 29.2 | 0.1 | 90 | 265 | 90.0016 | 0.0543595 | 0.023848 | 0.00023672
PLATINE | STEEL/E24-2 | 181 | N14 | 1 | PLATINE | 2 | 29.2 | 0.1 | 90 | 265 | 90.0016 | 0.0543595 | 0.023848 | 0.00023672
2 x PLATINE | STEEL/E24-2 | 181 | N12 | 1 | PLATINE | 2 | 29.2 | 0.1 | 90 | 265 | 90.0016 | 0.0543595 | 0.023848 | 0.00023672
6 x TOLE | STEEL/E36-3 | 182 | P24 | 1 | TOLE | 3.2 | 28.8 | 0.1 | 90 | 465 | 90 | 0.0932571 | 0.04185 | 0.00041225
6 x TOLE | STEEL/E36-3 | 182 | P23 | 1 | TOLE | 3.2 | 28.8 | 0.1 | 90 | 465 | 90 | 0.0932571 | 0.04185 | 0.00041225
6 x TOLE | STEEL/E36-3 | 182 | P25 | 1 | TOLE | 3.2 | 28.8 | 0.1 | 90 | 465 | 90 | 0.0932571 | 0.04185 | 0.00041225
6 x TOLE | STEEL/E36-3 | 182 | P27 | 1 | TOLE | 3.2 | 28.8 | 0.1 | 90 | 465 | 90 | 0.0932571 | 0.04185 | 0.00041225
6 x PLATINE | STEEL/E36-3 | 171 | P26 | 1 | PLATINE | 3.3 | 28.8 | 0.1 | 90 | 467 | 90 | 0.0936571 | 0.04203 | 0.00041405

# IfcPlate: PL10*97 (2)
In: Undefined
Description: PL10*97; Material: STEEL/E24-2
Tekla Commun - Finition: GRENAILLE-PEINT; Repère de pièce: 239; Phase: 1; Profil: PL10*97; sets with these values: 2
Tekla Quantités - Poids: 2.1 kg; Volume: 0 m3; Surface supérieure totale: 0 m2; Surface par tonne: 28.9 m2; Surface nette: 0.1 m2; Hauteur: 97.2 mm; Largeur: 10 mm; Longueur: 277.4 mm; sets with these values: 2
Pset_PlateCommon - LoadBearing: no; Reference: 239
BaseQuantities - Width: 97.2196 mm; NetArea: 0.0611127 m2; GrossArea: 0.0269687 m2; CrossSectionArea: 0.0001 m2; NetVolume: 0.000268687 m3; GrossVolume: 0.000268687 m3
Name | Repère d'assemblage
Unnamed | P23
Unnamed | P27

# IfcPlate: PL12*100 (4)
In: Undefined
Description: PL12*100; Material: STEEL/E24-2
Tekla Commun - Finition: GRENAILLE-PEINT; Repère de pièce: 1264; Repère d'assemblage: N5; Phase: 1; Profil: PL12*100; Nom: TOLE; sets with these values: 2
Tekla Quantités - Poids: 1.7 kg; Volume: 0 m3; Surface supérieure totale: 0 m2; Surface par tonne: 25.1 m2; Surface nette: 0 m2; Hauteur: 100 mm; Largeur: 12 mm; Longueur: 185 mm; sets with these values: 2
Pset_PlateCommon - LoadBearing: no; Reference: 1264
BaseQuantities - Width: 100 mm; NetArea: 0.0427588 m2; GrossArea: 0.0185 m2; CrossSectionArea: 0.000144 m2; NetVolume: 0.0002172 m3; GrossVolume: 0.0002172 m3

# IfcPlate: PL12*215 (2)
In: Undefined
Description: PL12*215; Material: STEEL/E24-2
Tekla Commun - Finition: GRENAILLE-PEINT; Repère de pièce: 1266; Repère d'assemblage: H78; Phase: 2; Profil: PL12*215; Nom: ATTACHE; sets with these values: 2
Tekla Quantités - Poids: 7 kg; Volume: 0 m3; Surface supérieure totale: 0 m2; Surface par tonne: 23.4 m2; Surface nette: 0.2 m2; Hauteur: 214.6 mm; Largeur: 12 mm; Longueur: 496 mm; sets with these values: 2
Pset_PlateCommon - LoadBearing: no; Reference: 1266
BaseQuantities - Width: 214.611 mm; NetArea: 0.163936 m2; GrossArea: 0.106447 m2; CrossSectionArea: 0.000144 m2; NetVolume: 0.00089187 m3; GrossVolume: 0.00089187 m3

# IfcPlate: PL12*235 (2)
In: Undefined
Description: PL12*235; Material: STEEL/E24-2
Tekla Commun - Finition: GRENAILLE-PEINT; Repère de pièce: 1269; Phase: 2; Profil: PL12*235; Nom: ATTACHE; sets with these values: 2
Tekla Quantités - Poids: 7.3 kg; Volume: 0 m3; Surface supérieure totale: 0 m2; Surface par tonne: 23.9 m2; Surface nette: 0.2 m2; Hauteur: 235.2 mm; Largeur: 12 mm; Longueur: 661 mm; sets with these values: 2
Pset_PlateCommon - LoadBearing: no; Reference: 1269
BaseQuantities - Width: 235.152 mm; NetArea: 0.174604 m2; GrossArea: 0.155432 m2; CrossSectionArea: 0.000144 m2; NetVolume: 0.000932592 m3; GrossVolume: 0.000932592 m3
Name | Repère d'assemblage
ATTACHE | K101
ATTACHE | K102

# IfcPlate: PL12*70 (8)
In: Undefined
Description: PL12*70; Material: STEEL/S235JR
Tekla Commun - Finition: GALVANISE; Repère de pièce: 1259; Repère d'assemblage: E3; Phase: 4; Profil: PL12*70; Nom: SUPPORT; sets with these values: 2
Tekla Quantités - Poids: 0.9 kg; Volume: 0 m3; Surface supérieure totale: 0 m2; Surface par tonne: 26.7 m2; Surface nette: 0 m2; Hauteur: 70 mm; Largeur: 12 mm; Longueur: 133 mm; sets with these values: 2
Pset_PlateCommon - LoadBearing: no; Reference: 1259
BaseQuantities - Width: 70 mm; NetArea: 0.0228311 m2; GrossArea: 0.00931 m2; CrossSectionArea: 0.000144 m2; NetVolume: 0.00010902 m3; GrossVolume: 0.00010902 m3

# IfcPlate: PL12*90 (4)
In: Undefined
Description: PL12*90; Material: STEEL/E24-2
Tekla Commun - Finition: GRENAILLE-PEINT; Repère de pièce: 1263; Repère d'assemblage: N5; Phase: 1; Profil: PL12*90; Nom: TOLE; sets with these values: 2
Tekla Quantités - Poids: 3.9 kg; Volume: 0 m3; Surface supérieure totale: 0 m2; Surface par tonne: 24.6 m2; Surface nette: 0.1 m2; Hauteur: 90 mm; Largeur: 12 mm; Longueur: 465 mm; sets with these values: 2
Pset_PlateCommon - LoadBearing: no; Reference: 1263
BaseQuantities - Width: 90 mm; NetArea: 0.0954185 m2; GrossArea: 0.04185 m2; CrossSectionArea: 0.000144 m2; NetVolume: 0.0004947 m3; GrossVolume: 0.0004947 m3

# IfcPlate: PL1385*941, CONDENSEUR
In: Undefined
Description: PL1385*941; Material: STEEL/S235JR
Tekla Commun - Repère de pièce: Z64; Repère d'assemblage: Z64; Phase: 10; Profil: PL1385*941; Nom: CONDENSEUR; sets with these values: 2
Tekla Quantités - Poids: 41874.6 kg; Volume: 5.3 m3; Surface supérieure totale: 3.9 m2; Surface par tonne: 0.5 m2; Surface nette: 21.6 m2; Hauteur: 941 mm; Largeur: 1385 mm; Longueur: 4093 mm; sets with these values: 2
Pset_PlateCommon - LoadBearing: no; Reference: Z64
BaseQuantities - Width: 941 mm; NetArea: 21.6472 m2; GrossArea: 3.85151 m2; CrossSectionArea: 1.91823 m2; NetVolume: 5.33435 m3; GrossVolume: 5.33435 m3

# IfcPlate: PL15*151 (2)
In: Undefined
Description: PL15*151; Material: STEEL/E24-2
Tekla Commun - Finition: GRENAILLE-PEINT; Repère de pièce: 145; Phase: 1; Profil: PL15*151; sets with these values: 2
Tekla Quantités - Poids: 3.9 kg; Volume: 0 m3; Surface supérieure totale: 0 m2; Surface par tonne: 19.7 m2; Surface nette: 0.1 m2; Hauteur: 151.1 mm; Largeur: 15 mm; Longueur: 277 mm; sets with these values: 2
Pset_PlateCommon - LoadBearing: no; Reference: 145
BaseQuantities - Width: 151.121 mm; NetArea: 0.0769966 m2; GrossArea: 0.0418606 m2; CrossSectionArea: 0.000225 m2; NetVolume: 0.000494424 m3; GrossVolume: 0.000494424 m3
Name | Repère d'assemblage
Unnamed | P24
Unnamed | P25

# IfcPlate: PL15*153 (2)
In: Undefined
Description: PL15*153; Material: STEEL/E24-2
Tekla Commun - Finition: GRENAILLE-PEINT; Repère de pièce: 149; Profil: PL15*153; sets with these values: 2
Tekla Quantités - Poids: 3.9 kg; Volume: 0 m3; Surface supérieure totale: 0 m2; Surface par tonne: 19.7 m2; Surface nette: 0.1 m2; Hauteur: 153.2 mm; Largeur: 15 mm; Longueur: 277 mm; sets with these values: 2
Pset_PlateCommon - LoadBearing: no; Reference: 149
BaseQuantities - Width: 153.171 mm; NetArea: 0.0781938 m2; GrossArea: 0.0424284 m2; CrossSectionArea: 0.000225 m2; NetVolume: 0.000502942 m3; GrossVolume: 0.000502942 m3
Name | Repère d'assemblage | Phase
Unnamed | P113 | 3
Unnamed | P119 | 2

# IfcPlate: PL15*159, Unnamed
In: Undefined
Description: PL15*159; Material: STEEL/E24-2
Tekla Commun - Finition: GRENAILLE-PEINT; Repère de pièce: 144; Repère d'assemblage: P22; Phase: 1; Profil: PL15*159; sets with these values: 2
Tekla Quantités - Poids: 4.2 kg; Volume: 0 m3; Surface supérieure totale: 0 m2; Surface par tonne: 19.7 m2; Surface nette: 0.1 m2; Hauteur: 159.2 mm; Largeur: 15 mm; Longueur: 277 mm; sets with these values: 2
Pset_PlateCommon - LoadBearing: no; Reference: 144
BaseQuantities - Width: 159.163 mm; NetArea: 0.0827323 m2; GrossArea: 0.0440882 m2; CrossSectionArea: 0.000225 m2; NetVolume: 0.000534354 m3; GrossVolume: 0.000534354 m3

# IfcPlate: PL15*217 (3)
In: Undefined
Description: PL15*217; Material: STEEL/E24-2
Tekla Commun - Finition: GRENAILLE-PEINT; Profil: PL15*217; sets with these values: 2
Tekla Quantités - Volume: 0 m3; Surface supérieure totale: 0 m2; Surface nette: 0.1 m2; Hauteur: 216.6 mm; Largeur: 15 mm; sets with these values: 2
Pset_PlateCommon - LoadBearing: no
BaseQuantities - Width: 216.684 mm; CrossSectionArea: 0.000225 m2
Name | Repère de pièce = Reference | Repère d'assemblage | Phase | Poids (kg) | Surface par tonne (m2) | Longueur (mm) | NetArea (m2) | GrossArea (m2) | NetVolume (m3) = GrossVolume (m3)
Unnamed | 147 | K26 | 1 | 6.8 | 19.7 | 510.5 | 0.135034 | 0.110611 | 0.000867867
Unnamed | 147 | K27 | 3 | 6.8 | 19.7 | 510.5 | 0.135034 | 0.110611 | 0.000867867
Unnamed | 146 | K25 | 3 | 6.7 | 19.6 | 450.2 | 0.130408 | 0.0975582 | 0.000845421

# IfcPlate: PL15*221, Unnamed
In: Undefined
Description: PL15*221; Material: STEEL/E24-2
Tekla Commun - Finition: GRENAILLE-PEINT; Repère de pièce: 148; Repère d'assemblage: K28; Phase: 1; Profil: PL15*221; sets with these values: 2
Tekla Quantités - Poids: 9.4 kg; Volume: 0 m3; Surface supérieure totale: 0 m2; Surface par tonne: 19.6 m2; Surface nette: 0.2 m2; Hauteur: 221 mm; Largeur: 15 mm; Longueur: 677.7 mm; sets with these values: 2
Pset_PlateCommon - LoadBearing: no; Reference: 148
BaseQuantities - Width: 220.97 mm; NetArea: 0.184701 m2; GrossArea: 0.14975 m2; CrossSectionArea: 0.000225 m2; NetVolume: 0.00120274 m3; GrossVolume: 0.00120274 m3

# IfcPlate: PL15*86 (16)
In: Undefined
Description: PL15*86; Material: STEEL/E24-2
Tekla Commun - Finition: GRENAILLE-PEINT; Profil: PL15*86; sets with these values: 2
Tekla Quantités - Poids: 3.4 kg; Volume: 0 m3; Surface supérieure totale: 0 m2; Surface par tonne: 20.7 m2; Surface nette: 0.1 m2; Hauteur: 85.7 mm; Largeur: 15 mm; Longueur: 353 mm; sets with these values: 2
Pset_PlateCommon - LoadBearing: no
BaseQuantities - Width: 85.7 mm; NetArea: 0.0711701 m2; GrossArea: 0.0302521 m2; CrossSectionArea: 0.000225 m2; NetVolume: 0.000438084 m3; GrossVolume: 0.000438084 m3
Name | Repère de pièce = Reference | Repère d'assemblage | Phase | Nom
2 x PLATINE | 158 | P37 | 1 | PLATINE
2 x PLATINE | 158 | P2 | 1 | PLATINE
2 x PLATINE | 158 | P1 | 1 | PLATINE
2 x PLAT | 163 | P38 | 1 | PLAT
2 x PLATINE | 158 | P3 | 1 | PLATINE
2 x PLATINE | 159 | P5 | 3 | PLATINE
2 x PLATINE | 159 | P39 | 2 | PLATINE
2 x PLAT | 163 | P4 | 1 | PLAT

# IfcPlate: PL15*90 (48)
In: Undefined
Description: PL15*90; Material: STEEL/E24-2
Tekla Commun - Finition: GRENAILLE-PEINT; Profil: PL15*90; Nom: PLATINE; sets with these values: 2
Tekla Quantités - Poids: 4.8 kg; Volume: 0 m3; Surface supérieure totale: 0 m2; Surface par tonne: 20.3 m2; Surface nette: 0.1 m2; Hauteur: 90 mm; Largeur: 15 mm; Longueur: 468 mm; sets with these values: 2
Pset_PlateCommon - LoadBearing: no
BaseQuantities - Width: 90 mm; NetArea: 0.099729 m2; GrossArea: 0.04212 m2; CrossSectionArea: 0.000225 m2; NetVolume: 0.000625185 m3; GrossVolume: 0.000625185 m3
Name | Repère de pièce = Reference | Repère d'assemblage | Phase
4 x PLATINE | 154 | P33 | 1
12 x PLATINE | 154 | P35 | 1
6 x PLATINE | 161 | P31 | 3
2 x PLATINE | 161 | P30 | 2
4 x PLATINE | 154 | P28 | 1
12 x PLATINE | 154 | P36 | 1
2 x PLATINE | 161 | P29 | 2
6 x PLATINE | 161 | P32 | 3

# IfcPlate: PL15*95 (44)
In: Undefined
Description: PL15*95; Material: STEEL/E24-2
Tekla Commun - Finition: GRENAILLE-PEINT; Profil: PL15*95; Nom: PLATINE; sets with these values: 2
Tekla Quantités - Volume: 0 m3; Surface supérieure totale: 0 m2; Hauteur: 95 mm; Largeur: 15 mm; sets with these values: 2
Pset_PlateCommon - LoadBearing: no
BaseQuantities - Width: 94.9 mm; CrossSectionArea: 0.000225 m2
Name | Repère de pièce = Reference | Repère d'assemblage | Phase | Poids (kg) | Surface par tonne (m2) | Surface nette (m2) | Longueur (mm) | NetArea (m2) | GrossArea (m2) | NetVolume (m3) = GrossVolume (m3)
2 x PLATINE | 155 | P33 | 1 | 5.5 | 20.3 | 0.1 | 498 | 0.109812 | 0.0472602 | 0.000693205
4 x PLATINE | 155 | P35 | 1 | 5.5 | 20.3 | 0.1 | 498 | 0.109812 | 0.0472602 | 0.000693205
2 x PLATINE | 160 | P31 | 3 | 5.5 | 20.3 | 0.1 | 498 | 0.109812 | 0.0472602 | 0.000693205
2 x PLATINE | 160 | P30 | 2 | 5.5 | 20.3 | 0.1 | 498 | 0.109812 | 0.0472602 | 0.000693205
2 x PLATINE | 155 | P28 | 1 | 5.5 | 20.3 | 0.1 | 498 | 0.109812 | 0.0472602 | 0.000693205
4 x PLATINE | 155 | P36 | 1 | 5.5 | 20.3 | 0.1 | 498 | 0.109812 | 0.0472602 | 0.000693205
2 x PLATINE | 160 | P29 | 2 | 5.5 | 20.3 | 0.1 | 498 | 0.109812 | 0.0472602 | 0.000693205
2 x PLATINE | 160 | P32 | 3 | 5.5 | 20.3 | 0.1 | 498 | 0.109812 | 0.0472602 | 0.000693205
2 x PLATINE | 157 | P23 | 1 | 3 | 20.6 | 0.1 | 278 | 0.0614563 | 0.0263822 | 0.000380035
2 x PLATINE | 156 | P23 | 1 | 2 | 21.2 | 0 | 178 | 0.0394763 | 0.0168922 | 0.000237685
2 x PLATINE | 157 | P26 | 1 | 3 | 20.6 | 0.1 | 278 | 0.0614563 | 0.0263822 | 0.000380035
2 x PLATINE | 156 | P26 | 1 | 2 | 21.2 | 0 | 178 | 0.0394763 | 0.0168922 | 0.000237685
2 x PLATINE | 157 | P27 | 1 | 3 | 20.6 | 0.1 | 278 | 0.0614563 | 0.0263822 | 0.000380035
2 x PLATINE | 156 | P27 | 1 | 2 | 21.2 | 0 | 178 | 0.0394763 | 0.0168922 | 0.000237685
2 x PLATINE | 157 | P24 | 1 | 3 | 20.6 | 0.1 | 278 | 0.0614563 | 0.0263822 | 0.000380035
2 x PLATINE | 156 | P24 | 1 | 2 | 21.2 | 0 | 178 | 0.0394763 | 0.0168922 | 0.000237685
2 x PLATINE | 157 | P22 | 1 | 3 | 20.6 | 0.1 | 278 | 0.0614563 | 0.0263822 | 0.000380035
2 x PLATINE | 156 | P22 | 1 | 2 | 21.2 | 0 | 178 | 0.0394763 | 0.0168922 | 0.000237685
2 x PLATINE | 157 | P25 | 1 | 3 | 20.6 | 0.1 | 278 | 0.0614563 | 0.0263822 | 0.000380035
2 x PLATINE | 156 | P25 | 1 | 2 | 21.2 | 0 | 178 | 0.0394763 | 0.0168922 | 0.000237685

# IfcPlate: PL1520*1994 (2)
In: Undefined
Description: PL1520*1994; Material: STEEL/S235JR
Tekla Commun - Repère de pièce: Z63; Repère d'assemblage: Z63; Phase: 10; Profil: PL1520*1994; Nom: CONDENSEUR; sets with these values: 2
Tekla Quantités - Poids: 97382.3 kg; Volume: 12.4 m3; Surface supérieure totale: 8.2 m2; Surface par tonne: 0.5 m2; Surface nette: 34.8 m2; Hauteur: 1994 mm; Largeur: 1520 mm; Longueur: 4093 mm; sets with these values: 2
Pset_PlateCommon - LoadBearing: no; Reference: Z63
BaseQuantities - Width: 1994 mm; NetArea: 34.8274 m2; GrossArea: 8.16144 m2; CrossSectionArea: 2.3104 m2; NetVolume: 12.4054 m3; GrossVolume: 12.4054 m3

# IfcPlate: PL180*11681, BETON
In: Undefined
Description: PL180*11681; Material: STEEL/S235JR
Tekla Commun - Repère de pièce: Z8; Repère d'assemblage: Z8; Phase: 10; Profil: PL180*11681; Nom: BETON; sets with these values: 2
Tekla Quantités - Poids: 225949 kg; Volume: 28.8 m3; Surface supérieure totale: 0 m2; Surface par tonne: 1.5 m2; Surface nette: 328.9 m2; Hauteur: 11680.6 mm; Largeur: 180 mm; Longueur: 13690 mm; sets with these values: 2
Pset_PlateCommon - LoadBearing: no; Reference: Z8
BaseQuantities - Width: 11680.6 mm; NetArea: 328.948 m2; GrossArea: 159.908 m2; CrossSectionArea: 0.0324 m2; NetVolume: 28.7834 m3; GrossVolume: 28.7834 m3

# IfcPlate: PL180*11762, BETON
In: Undefined
Description: PL180*11762; Material: STEEL/S235JR
Tekla Commun - Repère de pièce: Z9; Repère d'assemblage: Z9; Phase: 10; Profil: PL180*11762; Nom: BETON; sets with these values: 2
Tekla Quantités - Poids: 619072 kg; Volume: 78.9 m3; Surface supérieure totale: 0 m2; Surface par tonne: 1.5 m2; Surface nette: 893.9 m2; Hauteur: 11761.8 mm; Largeur: 180 mm; Longueur: 37250 mm; sets with these values: 2
Pset_PlateCommon - LoadBearing: no; Reference: Z9
BaseQuantities - Width: 11761.8 mm; NetArea: 893.896 m2; GrossArea: 438.126 m2; CrossSectionArea: 0.0324 m2; NetVolume: 78.8626 m3; GrossVolume: 78.8626 m3

# IfcPlate: PL180*2231, BETON
In: Undefined
Description: PL180*2231; Material: STEEL/S235JR
Tekla Commun - Repère de pièce: Z10; Repère d'assemblage: Z10; Phase: 10; Profil: PL180*2231; Nom: BETON; sets with these values: 2
Tekla Quantités - Poids: 15103.1 kg; Volume: 1.9 m3; Surface supérieure totale: 0 m2; Surface par tonne: 1.6 m2; Surface nette: 23.9 m2; Hauteur: 2231.5 mm; Largeur: 180 mm; Longueur: 4790 mm; sets with these values: 2
Pset_PlateCommon - LoadBearing: no; Reference: Z10
BaseQuantities - Width: 2231.46 mm; NetArea: 23.9051 m2; GrossArea: 10.6887 m2; CrossSectionArea: 0.0324 m2; NetVolume: 1.92397 m3; GrossVolume: 1.92397 m3

# IfcPlate: PL180*4204, BETON
In: Undefined
Description: PL180*4204; Material: STEEL/S235JR
Tekla Commun - Repère de pièce: Z7; Repère d'assemblage: Z7; Phase: 10; Profil: PL180*4204; Nom: BETON; sets with these values: 2
Tekla Quantités - Poids: 34657.8 kg; Volume: 4.4 m3; Surface supérieure totale: 0 m2; Surface par tonne: 1.5 m2; Surface nette: 52.7 m2; Hauteur: 4204.4 mm; Largeur: 180 mm; Longueur: 5834 mm; sets with these values: 2
Pset_PlateCommon - LoadBearing: no; Reference: Z7
BaseQuantities - Width: 4204.44 mm; NetArea: 52.6694 m2; GrossArea: 24.5287 m2; CrossSectionArea: 0.0324 m2; NetVolume: 4.41501 m3; GrossVolume: 4.41501 m3

# IfcPlate: PL180*4217, BETON
In: Undefined
Description: PL180*4217; Material: STEEL/S235JR
Tekla Commun - Repère de pièce: Z11; Repère d'assemblage: Z11; Phase: 10; Profil: PL180*4217; Nom: BETON; sets with these values: 2
Tekla Quantités - Poids: 48125.1 kg; Volume: 6.1 m3; Surface supérieure totale: 0 m2; Surface par tonne: 1.5 m2; Surface nette: 72.5 m2; Hauteur: 4217.3 mm; Largeur: 180 mm; Longueur: 8076 mm; sets with these values: 2
Pset_PlateCommon - LoadBearing: no; Reference: Z11
BaseQuantities - Width: 4217.29 mm; NetArea: 72.5432 m2; GrossArea: 34.0588 m2; CrossSectionArea: 0.0324 m2; NetVolume: 6.13059 m3; GrossVolume: 6.13059 m3

# IfcPlate: PL180*5600, BETON
In: Undefined
Description: PL180*5600; Material: STEEL/S235JR
Tekla Commun - Repère de pièce: Z5; Repère d'assemblage: Z5; Phase: 10; Profil: PL180*5600; Nom: BETON; sets with these values: 2
Tekla Quantités - Poids: 73455.8 kg; Volume: 9.4 m3; Surface supérieure totale: 0 m2; Surface par tonne: 1.5 m2; Surface nette: 109.5 m2; Hauteur: 5600 mm; Largeur: 180 mm; Longueur: 9681.7 mm; sets with these values: 2
Pset_PlateCommon - LoadBearing: no; Reference: Z5
BaseQuantities - Width: 5600 mm; NetArea: 109.473 m2; GrossArea: 54.2174 m2; CrossSectionArea: 0.0324 m2; NetVolume: 9.35743 m3; GrossVolume: 9.35743 m3

# IfcPlate: PL180*7414, BETON
In: Undefined
Description: PL180*7414; Material: STEEL/S235JR
Tekla Commun - Repère de pièce: Z6; Repère d'assemblage: Z6; Phase: 10; Profil: PL180*7414; Nom: BETON; sets with these values: 2
Tekla Quantités - Poids: 131937 kg; Volume: 16.8 m3; Surface supérieure totale: 0 m2; Surface par tonne: 1.5 m2; Surface nette: 194 m2; Hauteur: 7413.6 mm; Largeur: 180 mm; Longueur: 12595 mm; sets with these values: 2
Pset_PlateCommon - LoadBearing: no; Reference: Z6
BaseQuantities - Width: 7413.56 mm; NetArea: 193.951 m2; GrossArea: 93.3738 m2; CrossSectionArea: 0.0324 m2; NetVolume: 16.8073 m3; GrossVolume: 16.8073 m3

# IfcPlate: PL3*130 (4)
In: Undefined
Description: PL3*130; Material: STEEL/S235JR
Tekla Commun - Finition: GALVANISE; Repère de pièce: 1240; Repère d'assemblage: E3; Phase: 4; Profil: PL3*130; Nom: CV; sets with these values: 2
Tekla Quantités - Poids: 1.2 kg; Volume: 0 m3; Surface supérieure totale: 0 m2; Surface par tonne: 88.4 m2; Surface nette: 0.1 m2; Hauteur: 130 mm; Largeur: 3 mm; Longueur: 430 mm; sets with these values: 2
Pset_PlateCommon - LoadBearing: no; Reference: 1240
BaseQuantities - Width: 130 mm; NetArea: 0.108238 m2; GrossArea: 0.0559 m2; CrossSectionArea: 0.000009 m2; NetVolume: 0.000155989 m3; GrossVolume: 0.000155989 m3

# IfcPlate: PL3*50, Unnamed
In: Undefined
Description: PL3*50; Material: STEEL/E24-2
Tekla Commun - Finition: GRENAILLE-PEINT; Repère de pièce: 1244; Repère d'assemblage: L80; Phase: 3; Profil: PL3*50; sets with these values: 2
Tekla Quantités - Poids: 0.1 kg; Volume: 0 m3; Surface supérieure totale: 0 m2; Surface par tonne: 92.3 m2; Surface nette: 0 m2; Hauteur: 50 mm; Largeur: 3 mm; Longueur: 111.1 mm; sets with these values: 2
Pset_PlateCommon - LoadBearing: no; Reference: 1244
BaseQuantities - Width: 50 mm; NetArea: 0.012075 m2; GrossArea: 0.00555425 m2; CrossSectionArea: 0.000009 m2; NetVolume: 0.0000166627 m3; GrossVolume: 0.0000166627 m3

# IfcPlate: PL6*104, ATTACHE
In: Undefined
Description: PL6*104; Material: STEEL/E24-2
Tekla Commun - Finition: GRENAILLE-PEINT; Repère de pièce: 353; Repère d'assemblage: P123; Phase: 1; Profil: PL6*104; Nom: ATTACHE; sets with these values: 2
Tekla Quantités - Poids: 0.9 kg; Volume: 0 m3; Surface supérieure totale: 0 m2; Surface par tonne: 46.4 m2; Surface nette: 0 m2; Hauteur: 104 mm; Largeur: 6 mm; Longueur: 176.5 mm; sets with these values: 2
Pset_PlateCommon - LoadBearing: no; Reference: 353
BaseQuantities - Width: 104 mm; NetArea: 0.0382726 m2; GrossArea: 0.018356 m2; CrossSectionArea: 0.000036 m2; NetVolume: 0.000104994 m3; GrossVolume: 0.000104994 m3

# IfcPlate: PL6*115, Unnamed
In: Undefined
Description: PL6*115; Material: STEEL/E24-2
Tekla Commun - Finition: GRENAILLE-PEINT; Repère de pièce: 337; Repère d'assemblage: P52; Phase: 7; Profil: PL6*115; sets with these values: 2
Tekla Quantités - Poids: 0.6 kg; Volume: 0 m3; Surface supérieure totale: 0 m2; Surface par tonne: 46.6 m2; Surface nette: 0 m2; Hauteur: 115 mm; Largeur: 6 mm; Longueur: 130 mm; sets with these values: 2
Pset_PlateCommon - LoadBearing: no; Reference: 337
BaseQuantities - Width: 115 mm; NetArea: 0.0318346 m2; GrossArea: 0.01495 m2; CrossSectionArea: 0.000036 m2; NetVolume: 0.000087 m3; GrossVolume: 0.000087 m3

# IfcPlate: PL6*117 (6)
In: Undefined
Description: PL6*117; Material: STEEL/S235JR
Tekla Commun - Finition: GRENAILLE-PEINT; Repère de pièce: 319; Phase: 1; Profil: PL6*117; Nom: TOLE; sets with these values: 2
Tekla Quantités - Poids: 0.9 kg; Volume: 0 m3; Surface supérieure totale: 0 m2; Surface par tonne: 46.1 m2; Surface nette: 0 m2; Hauteur: 117.2 mm; Largeur: 6 mm; Longueur: 171.5 mm; sets with these values: 2
Pset_PlateCommon - LoadBearing: no; Reference: 319
BaseQuantities - Width: 117.2 mm; NetArea: 0.0433863 m2; GrossArea: 0.0200998 m2; CrossSectionArea: 0.000036 m2; NetVolume: 0.000119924 m3; GrossVolume: 0.000119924 m3
Name | Repère d'assemblage
2 x TOLE | P15
2 x TOLE | P14
TOLE | P18
TOLE | P19

# IfcPlate: PL6*134 (22)
In: Undefined
Description: PL6*134; Material: STEEL/S235JR
Tekla Commun - Finition: GALVANISE; Repère de pièce: 358; Phase: 2; Profil: PL6*134; Nom: PLAT; sets with these values: 2
Tekla Quantités - Poids: 1.7 kg; Volume: 0 m3; Surface supérieure totale: 0 m2; Surface par tonne: 45.3 m2; Surface nette: 0.1 m2; Hauteur: 134 mm; Largeur: 6 mm; Longueur: 278.6 mm; sets with these values: 2
Pset_PlateCommon - LoadBearing: no; Reference: 358
BaseQuantities - Width: 134 mm; NetArea: 0.079616 m2; GrossArea: 0.0373324 m2; CrossSectionArea: 0.000036 m2; NetVolume: 0.000223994 m3; GrossVolume: 0.000223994 m3
Name | Repère d'assemblage
2 x PLAT | S2
20 x PLAT | S1

# IfcPlate: PL6*140, TOLE
In: Undefined
Description: PL6*140; Material: STEEL/S235JR
Tekla Commun - Finition: GRENAILLE-PEINT; Repère de pièce: 318; Repère d'assemblage: P116; Phase: 1; Profil: PL6*140; Nom: TOLE; sets with these values: 2
Tekla Quantités - Poids: 1.1 kg; Volume: 0 m3; Surface supérieure totale: 0 m2; Surface par tonne: 45.7 m2; Surface nette: 0.1 m2; Hauteur: 140 mm; Largeur: 6 mm; Longueur: 170.8 mm; sets with these values: 2
Pset_PlateCommon - LoadBearing: no; Reference: 318
BaseQuantities - Width: 140 mm; NetArea: 0.0512759 m2; GrossArea: 0.023912 m2; CrossSectionArea: 0.000036 m2; NetVolume: 0.000142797 m3; GrossVolume: 0.000142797 m3

# IfcPlate: PL6*160 (3)
In: Undefined
Description: PL6*160; Material: STEEL/S235JR
Tekla Commun - Finition: GRENAILLE-PEINT; Repère de pièce: 317; Phase: 1; Profil: PL6*160; Nom: TOLE; sets with these values: 2
Tekla Quantités - Poids: 1.2 kg; Volume: 0 m3; Surface supérieure totale: 0 m2; Surface par tonne: 45.6 m2; Surface nette: 0.1 m2; Hauteur: 160 mm; Largeur: 6 mm; Longueur: 164 mm; sets with these values: 2
Pset_PlateCommon - LoadBearing: no; Reference: 317
BaseQuantities - Width: 160 mm; NetArea: 0.0556551 m2; GrossArea: 0.02624 m2; CrossSectionArea: 0.000036 m2; NetVolume: 0.000155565 m3; GrossVolume: 0.000155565 m3
Name | Repère d'assemblage
TOLE | P23
TOLE | P27
TOLE | P25

# IfcPlate: PL6*165, CV
In: Undefined
Description: PL6*165; Material: STEEL/S235JR
Tekla Commun - Finition: GALVANISE; Repère de pièce: 325; Repère d'assemblage: L7; Phase: 4; Profil: PL6*165; Nom: CV; sets with these values: 2
Tekla Quantités - Poids: 1.4 kg; Volume: 0 m3; Surface supérieure totale: 0 m2; Surface par tonne: 45.5 m2; Surface nette: 0.1 m2; Hauteur: 165 mm; Largeur: 6 mm; Longueur: 238.7 mm; sets with these values: 2
Pset_PlateCommon - LoadBearing: no; Reference: 325
BaseQuantities - Width: 165 mm; NetArea: 0.0618605 m2; GrossArea: 0.0393808 m2; CrossSectionArea: 0.000036 m2; NetVolume: 0.000173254 m3; GrossVolume: 0.000173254 m3

# IfcPlate: PL6*60, Unnamed
In: Undefined
Description: PL6*60; Material: STEEL/E24-2
Tekla Commun - Finition: GRENAILLE-PEINT; Repère de pièce: 340; Repère d'assemblage: P53; Phase: 7; Profil: PL6*60; sets with these values: 2
Tekla Quantités - Poids: 0.5 kg; Volume: 0 m3; Surface supérieure totale: 0 m2; Surface par tonne: 48.1 m2; Surface nette: 0 m2; Hauteur: 60 mm; Largeur: 6 mm; Longueur: 190 mm; sets with these values: 2
Pset_PlateCommon - LoadBearing: no; Reference: 340
BaseQuantities - Width: 60 mm; NetArea: 0.0258 m2; GrossArea: 0.0114 m2; CrossSectionArea: 0.000036 m2; NetVolume: 0.0000684 m3; GrossVolume: 0.0000684 m3

# IfcPlate: PL6*65 (4)
In: Undefined
Description: PL6*65
Tekla Commun - Profil: PL6*65; sets with these values: 2
Tekla Quantités - Volume: 0 m3; Surface supérieure totale: 0 m2; Surface nette: 0 m2; Hauteur: 64.9 mm; Largeur: 6 mm; sets with these values: 2
Pset_PlateCommon - LoadBearing: no
BaseQuantities - CrossSectionArea: 0.000036 m2
Name | Material | Finition | Repère de pièce = Reference | Repère d'assemblage | Phase | Poids (kg) | Surface par tonne (m2) | Longueur (mm) | Width (mm) | NetArea (m2) | GrossArea (m2) | NetVolume (m3) = GrossVolume (m3)
2 x CV | STEEL/S235JR | GALVANISE | 324 | L6 | 4 | 0.5 | 48.6 | 199.3 | 64.9357 | 0.0230179 | 0.0129439 | 0.0000602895 | Tekla Commun - Nom: CV
2 x Unnamed | STEEL/E24-2 | GRENAILLE-PEINT | 349 | K28 | 1 | 0.3 | 49.2 | 89 | 65 | 0.0131338 | 0.00578203 | 0.0000340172

# IfcPlate: PL6*79 (4)
In: Undefined
Description: PL6*79; Material: STEEL/S235JR
Tekla Commun - Finition: GRENAILLE-PEINT; Repère de pièce: 359; Repère d'assemblage: N37; Phase: 1; Profil: PL6*79; Nom: TOLE; sets with these values: 2
Tekla Quantités - Poids: 0.3 kg; Volume: 0 m3; Surface supérieure totale: 0 m2; Surface par tonne: 48.7 m2; Surface nette: 0 m2; Hauteur: 79.2 mm; Largeur: 6 mm; Longueur: 84 mm; sets with these values: 2
Pset_PlateCommon - LoadBearing: no; Reference: 359
BaseQuantities - Width: 79.2025 mm; NetArea: 0.0142041 m2; GrossArea: 0.00665301 m2; CrossSectionArea: 0.000036 m2; NetVolume: 0.0000371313 m3; GrossVolume: 0.0000371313 m3

# IfcPlate: PL6*86 (19)
In: Undefined
Description: PL6*86; Material: STEEL/E24-2
Tekla Commun - Finition: GRENAILLE-PEINT; Repère de pièce: 360; Phase: 2; Profil: PL6*86; Nom: TOLE; sets with these values: 2
Tekla Quantités - Poids: 1.4 kg; Volume: 0 m3; Surface supérieure totale: 0 m2; Surface par tonne: 46.1 m2; Surface nette: 0.1 m2; Hauteur: 85.7 mm; Largeur: 6 mm; Longueur: 372 mm; sets with these values: 2
Pset_PlateCommon - LoadBearing: no; Reference: 360
BaseQuantities - Width: 85.7 mm; NetArea: 0.0678275 m2; GrossArea: 0.0318804 m2; CrossSectionArea: 0.000036 m2; NetVolume: 0.000187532 m3; GrossVolume: 0.000187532 m3
Name | Repère d'assemblage
6 x TOLE | N20
7 x TOLE | N19
5 x TOLE | N21
TOLE | N22

# IfcPlate: PL8*107 (5)
In: Undefined
Description: PL8*107
Tekla Commun - Finition: GRENAILLE-PEINT; Profil: PL8*107; Nom: GOUSSET; sets with these values: 2
Tekla Quantités - Volume: 0 m3; Surface supérieure totale: 0 m2; Largeur: 8 mm; sets with these values: 2
Pset_PlateCommon - LoadBearing: no
BaseQuantities - CrossSectionArea: 0.000064 m2
Name | Material | Repère de pièce = Reference | Repère d'assemblage | Phase | Poids (kg) | Surface par tonne (m2) | Surface nette (m2) | Hauteur (mm) | Longueur (mm) | Width (mm) | NetArea (m2) | GrossArea (m2) | NetVolume (m3) = GrossVolume (m3)
GOUSSET | STEEL/S235JR | 751 | K68(?) | 2 | 0.9 | 37.4 | 0 | 107 | 200 | 107.045 | 0.0290862 | 0.021409 | 0.0000991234
GOUSSET | STEEL/S235JR | 0(?) | 0(?) | 2 | 1.7 | 35.1 | 0.1 | 107 | 267.4 | 107.046 | 0.0622447 | 0.0286214 | 0.000225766
GOUSSET | STEEL/S235JR | 755 | K72 | 2 | 1.7 | 35.1 | 0.1 | 107 | 267.4 | 107.045 | 0.0622431 | 0.0286204 | 0.00022576
GOUSSET | STEEL/S235JR | 755 | K72 | 2 | 1.7 | 35.1 | 0.1 | 107 | 267.4 | 107.046 | 0.0622447 | 0.0286214 | 0.000225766
GOUSSET | STEEL/E24-2 | 715 | P28 | 1 | 1.4 | 35.5 | 0 | 106.8 | 220.3 | 106.767 | 0.0487952 | 0.023516 | 0.000175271

# IfcPlate: PL8*113, GOUSSET
In: Undefined
Description: PL8*113; Material: STEEL/S235JR
Tekla Commun - Finition: GRENAILLE-PEINT; Repère de pièce: 753; Repère d'assemblage: K67; Phase: 2; Profil: PL8*113; Nom: GOUSSET; sets with these values: 2
Tekla Quantités - Poids: 1.7 kg; Volume: 0 m3; Surface supérieure totale: 0 m2; Surface par tonne: 35.1 m2; Surface nette: 0.1 m2; Hauteur: 113.3 mm; Largeur: 8 mm; Longueur: 240.8 mm; sets with these values: 2
Pset_PlateCommon - LoadBearing: no; Reference: 753
BaseQuantities - Width: 113.255 mm; NetArea: 0.0592318 m2; GrossArea: 0.0272772 m2; CrossSectionArea: 0.000064 m2; NetVolume: 0.000215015 m3; GrossVolume: 0.000215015 m3

# IfcPlate: PL8*114 (3)
In: Undefined
Description: PL8*114; Material: STEEL/E24-2
Tekla Commun - Finition: GRENAILLE-PEINT; Repère de pièce: 716; Phase: 1; Profil: PL8*114; Nom: GOUSSET; sets with these values: 2
Tekla Quantités - Poids: 2.3 kg; Volume: 0 m3; Surface supérieure totale: 0 m2; Surface par tonne: 35 m2; Surface nette: 0.1 m2; Hauteur: 113.8 mm; Largeur: 8 mm; Longueur: 371.8 mm; sets with these values: 2
Pset_PlateCommon - LoadBearing: no; Reference: 716
BaseQuantities - Width: 113.792 mm; NetArea: 0.0805379 m2; GrossArea: 0.0423077 m2; CrossSectionArea: 0.000064 m2; NetVolume: 0.000293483 m3; GrossVolume: 0.000293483 m3
Name | Repère d'assemblage
GOUSSET | P37
GOUSSET | P1
GOUSSET | P2

# IfcPlate: PL8*115 (11)
In: Undefined
Description: PL8*115; Material: STEEL/S235JR
Tekla Commun - Finition: GRENAILLE-PEINT; Phase: 2; Profil: PL8*115; Nom: GOUSSET; sets with these values: 2
Tekla Quantités - Volume: 0 m3; Surface supérieure totale: 0 m2; Hauteur: 115 mm; Largeur: 8 mm; sets with these values: 2
Pset_PlateCommon - LoadBearing: no
BaseQuantities - CrossSectionArea: 0.000064 m2
Name | Repère de pièce = Reference | Repère d'assemblage | Poids (kg) | Surface par tonne (m2) | Surface nette (m2) | Longueur (mm) | Width (mm) | NetArea (m2) | GrossArea (m2) | NetVolume (m3) = GrossVolume (m3)
2 x GOUSSET | 754 | K71 | 1.7 | 35 | 0.1 | 251.7 | 114.935 | 0.0627381 | 0.02893 | 0.000228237
2 x GOUSSET | 754 | K71 | 1.7 | 35 | 0.1 | 251.7 | 114.936 | 0.0627397 | 0.0289312 | 0.000228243
2 x GOUSSET | 752 | K69 | 1.7 | 35 | 0.1 | 251.7 | 114.935 | 0.0627381 | 0.02893 | 0.000228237
2 x GOUSSET | 752 | K69 | 1.7 | 35 | 0.1 | 251.7 | 114.936 | 0.0627397 | 0.0289312 | 0.000228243
GOUSSET | 750 | K67 | 0.9 | 37 | 0 | 200 | 114.936 | 0.0316939 | 0.0229883 | 0.000109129
GOUSSET | 752 | K70 | 1.7 | 35 | 0.1 | 251.7 | 114.935 | 0.0627381 | 0.02893 | 0.000228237
GOUSSET | 752 | K70 | 1.7 | 35 | 0.1 | 251.7 | 114.936 | 0.0627397 | 0.0289312 | 0.000228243

# IfcPlate: PL8*120 (35)
In: Undefined
Description: PL8*120; Material: STEEL/E24-2
Tekla Commun - Finition: GRENAILLE-PEINT; Profil: PL8*120; Nom: GOUSSET; sets with these values: 2
Tekla Quantités - Volume: 0 m3; Surface supérieure totale: 0 m2; Surface nette: 0.1 m2; Hauteur: 120 mm; Largeur: 8 mm; sets with these values: 2
Pset_PlateCommon - LoadBearing: no
BaseQuantities - Width: 120 mm; CrossSectionArea: 0.000064 m2
Name | Repère de pièce = Repère d'assemblage = Reference | Phase | Poids (kg) | Surface par tonne (m2) | Longueur (mm) | NetArea (m2) | GrossArea (m2) | NetVolume (m3) = GrossVolume (m3)
3 x GOUSSET | G20 | 3 | 2.6 | 34.9 | 420 | 0.0915403 | 0.0504 | 0.00033504
GOUSSET | G19 | 3 | 2.6 | 34.9 | 420 | 0.0915403 | 0.0504 | 0.00033504
2 x GOUSSET | G18 | 3 | 2.6 | 34.9 | 410 | 0.0895839 | 0.0492 | 0.00032784
2 x GOUSSET | G60 | 2 | 1.7 | 35.1 | 273 | 0.0631599 | 0.03276 | 0.0002292
12 x GOUSSET | G18 | 2 | 2.6 | 34.9 | 410 | 0.0895839 | 0.0492 | 0.00032784
12 x GOUSSET | G18 | 1 | 2.6 | 34.9 | 410 | 0.0895839 | 0.0492 | 0.00032784
2 x GOUSSET | G27 | 1 | 2.6 | 34.9 | 410 | 0.089681 | 0.0492 | 0.00032784
GOUSSET | G60 | 1 | 1.7 | 35.1 | 273 | 0.0631599 | 0.03276 | 0.0002292

# IfcPlate: PL8*124 (6)
In: Undefined
Description: PL8*124; Material: STEEL/E24-2
Tekla Commun - Finition: GRENAILLE-PEINT; Repère de pièce: 802; Phase: 1; Profil: PL8*124; Nom: GOUSSET; sets with these values: 2
Tekla Quantités - Poids: 0.9 kg; Volume: 0 m3; Surface supérieure totale: 0 m2; Surface par tonne: 37.4 m2; Surface nette: 0 m2; Hauteur: 124.3 mm; Largeur: 8 mm; Longueur: 217 mm; sets with these values: 2
Pset_PlateCommon - LoadBearing: no; Reference: 802
BaseQuantities - Width: 124.298 mm; NetArea: 0.0317005 m2; GrossArea: 0.0269699 m2; CrossSectionArea: 0.000064 m2; NetVolume: 0.000107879 m3; GrossVolume: 0.000107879 m3
Name | Repère d'assemblage
GOUSSET | K87
GOUSSET | K57
2 x GOUSSET | K89
2 x GOUSSET | K88

# IfcPlate: PL8*125 (12)
In: Undefined
Description: PL8*125; Material: STEEL/S235JR
Tekla Commun - Finition: GRENAILLE-PEINT; Phase: 2; Profil: PL8*125; Nom: GOUSSET; sets with these values: 2
Tekla Quantités - Poids: 2.8 kg; Volume: 0 m3; Surface supérieure totale: 0 m2; Surface par tonne: 34.9 m2; Surface nette: 0.1 m2; Hauteur: 124.6 mm; Largeur: 8 mm; Longueur: 470.2 mm; sets with these values: 2
Pset_PlateCommon - LoadBearing: no
BaseQuantities - Width: 124.586 mm; NetArea: 0.0986458 m2; GrossArea: 0.0585823 m2; CrossSectionArea: 0.000064 m2; NetVolume: 0.000360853 m3; GrossVolume: 0.000360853 m3
Name | Repère de pièce = Reference | Repère d'assemblage
2 x GOUSSET | 731 | K35
2 x GOUSSET | 820 | K35
2 x GOUSSET | 820 | K36
2 x GOUSSET | 731 | K36
4 x GOUSSET | 731 | K34

# IfcPlate: PL8*127, GOUSSET
In: Undefined
Description: PL8*127; Material: STEEL/E24-2
Tekla Commun - Finition: GRENAILLE-PEINT; Repère de pièce: 796; Repère d'assemblage: P8; Phase: 1; Profil: PL8*127; Nom: GOUSSET; sets with these values: 2
Tekla Quantités - Poids: 1.2 kg; Volume: 0 m3; Surface supérieure totale: 0 m2; Surface par tonne: 35.5 m2; Surface nette: 0 m2; Hauteur: 126.6 mm; Largeur: 8 mm; Longueur: 220.7 mm; sets with these values: 2
Pset_PlateCommon - LoadBearing: no; Reference: 796
BaseQuantities - Width: 126.568 mm; NetArea: 0.0468452 m2; GrossArea: 0.0279369 m2; CrossSectionArea: 0.000064 m2; NetVolume: 0.000168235 m3; GrossVolume: 0.000168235 m3

# IfcPlate: PL8*130 (4)
In: Undefined
Description: PL8*130; Material: STEEL/E24-2
Tekla Commun - Finition: GRENAILLE-PEINT; Repère de pièce: 792; Repère d'assemblage: K21; Profil: PL8*130; Nom: GOUSSET; sets with these values: 2
Tekla Quantités - Poids: 2.1 kg; Volume: 0 m3; Surface supérieure totale: 0 m2; Surface par tonne: 35 m2; Surface nette: 0.1 m2; Hauteur: 130.3 mm; Largeur: 8 mm; Longueur: 332.7 mm; sets with these values: 2
Pset_PlateCommon - LoadBearing: no; Reference: 792
BaseQuantities - Width: 130.3 mm; NetArea: 0.0730937 m2; GrossArea: 0.043348 m2; CrossSectionArea: 0.000064 m2; NetVolume: 0.000266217 m3; GrossVolume: 0.000266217 m3
Name | Phase
2 x GOUSSET | 3
2 x GOUSSET | 1

# IfcPlate: PL8*132 (26)
In: Undefined
Description: PL8*132; Material: STEEL/S235JR
Tekla Commun - Finition: GRENAILLE-PEINT; Phase: 2; Profil: PL8*132; Nom: GOUSSET; sets with these values: 2
Tekla Quantités - Volume: 0 m3; Surface supérieure totale: 0 m2; Hauteur: 132 mm; Largeur: 8 mm; sets with these values: 2
Pset_PlateCommon - LoadBearing: no
BaseQuantities - CrossSectionArea: 0.000064 m2
Name | Repère de pièce = Reference | Repère d'assemblage | Poids (kg) | Surface par tonne (m2) | Surface nette (m2) | Longueur (mm) | Width (mm) | NetArea (m2) | GrossArea (m2) | NetVolume (m3) = GrossVolume (m3)
GOUSSET | 744 | K60 | 2 | 35 | 0.1 | 278.9 | 131.955 | 0.0673739 | 0.0368035 | 0.000245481
GOUSSET | 747 | K60 | 1.7 | 35 | 0.1 | 251.2 | 131.955 | 0.0627726 | 0.0331497 | 0.00022825
GOUSSET | 746 | K64 | 1.7 | 35 | 0.1 | 251.2 | 131.955 | 0.0627726 | 0.0331497 | 0.00022825
2 x GOUSSET | 745 | K63 | 1.7 | 35 | 0.1 | 251.2 | 131.955 | 0.0622789 | 0.0331497 | 0.00022665
GOUSSET | 748 | K102 | 1.7 | 35 | 0.1 | 251.2 | 131.955 | 0.0627726 | 0.0331497 | 0.00022825
GOUSSET | 756 | K68(?) | 1.1 | 36 | 0 | 200 | 131.956 | 0.0387784 | 0.0263911 | 0.000137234
GOUSSET | 756 | K72 | 1.1 | 36 | 0 | 200 | 131.956 | 0.0387784 | 0.0263911 | 0.000137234
GOUSSET | 756 | K72 | 1.1 | 36 | 0 | 200 | 131.955 | 0.0387782 | 0.0263909 | 0.000137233
GOUSSET | 749 | K66 | 1.7 | 35 | 0.1 | 251.2 | 131.955 | 0.0627726 | 0.0331497 | 0.00022825
2 x GOUSSET | 749 | K65 | 1.7 | 35 | 0.1 | 251.2 | 131.955 | 0.0627726 | 0.0331497 | 0.00022825
2 x GOUSSET | 756 | K71 | 1.1 | 36 | 0 | 200 | 131.956 | 0.0387784 | 0.0263911 | 0.000137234
2 x GOUSSET | 756 | K71 | 1.1 | 36 | 0 | 200 | 131.955 | 0.0387782 | 0.0263909 | 0.000137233
GOUSSET | 749 | K62 | 1.7 | 35 | 0.1 | 251.2 | 131.955 | 0.0627726 | 0.0331497 | 0.00022825
GOUSSET | 757 | K62 | 2.4 | 34.6 | 0.1 | 302.4 | 131.956 | 0.0864738 | 0.0399086 | 0.000318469
GOUSSET | 756 | K69 | 1.1 | 36 | 0 | 200 | 131.955 | 0.0387782 | 0.0263909 | 0.000137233
GOUSSET | 756 | K69 | 1.1 | 36 | 0 | 200 | 131.956 | 0.0387784 | 0.0263911 | 0.000137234
GOUSSET | 756 | K101 | 1.1 | 36 | 0 | 200 | 131.956 | 0.0387784 | 0.0263911 | 0.000137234
GOUSSET | 756 | K67 | 1.1 | 36 | 0 | 200 | 131.955 | 0.0387782 | 0.0263909 | 0.000137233
GOUSSET | 757 | K61 | 2.4 | 34.6 | 0.1 | 302.4 | 131.956 | 0.0864738 | 0.0399086 | 0.000318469
GOUSSET | 746 | K61 | 1.7 | 35 | 0.1 | 251.2 | 131.955 | 0.0627726 | 0.0331497 | 0.00022825
GOUSSET | 756 | K70 | 1.1 | 36 | 0 | 200 | 131.955 | 0.0387782 | 0.0263909 | 0.000137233
GOUSSET | 756 | K70 | 1.1 | 36 | 0 | 200 | 131.956 | 0.0387784 | 0.0263911 | 0.000137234

# IfcPlate: PL8*135 (12)
In: Undefined
Description: PL8*135; Material: STEEL/E24-2
Tekla Commun - Finition: GRENAILLE-PEINT; Profil: PL8*135; Nom: GOUSSET; sets with these values: 2
Tekla Quantités - Poids: 2.2 kg; Volume: 0 m3; Surface supérieure totale: 0 m2; Surface par tonne: 34.9 m2; Surface nette: 0.1 m2; Hauteur: 135.3 mm; Largeur: 8 mm; Longueur: 342.8 mm; sets with these values: 2
Pset_PlateCommon - LoadBearing: no
BaseQuantities - Width: 135.3 mm; NetArea: 0.0765411 m2; GrossArea: 0.046383 m2; CrossSectionArea: 0.000064 m2; NetVolume: 0.000279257 m3; GrossVolume: 0.000279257 m3
Name | Repère de pièce = Reference | Repère d'assemblage | Phase
2 x GOUSSET | 793 | K21 | 3
GOUSSET | 793 | K23 | 3
GOUSSET | 794 | K23 | 3
2 x GOUSSET | 793 | K22 | 3
2 x GOUSSET | 793 | K21 | 1
2 x GOUSSET | 793 | K22 | 1
2 x GOUSSET | 793 | K24 | 1

# IfcPlate: PL8*136 (11)
In: Undefined
Description: PL8*136; Material: STEEL/E24-2
Tekla Commun - Finition: GRENAILLE-PEINT; Profil: PL8*136; sets with these values: 2
Tekla Quantités - Poids: 1.2 kg; Volume: 0 m3; Surface supérieure totale: 0 m2; Surface nette: 0 m2; Largeur: 8 mm; sets with these values: 2
Pset_PlateCommon - LoadBearing: no
BaseQuantities - CrossSectionArea: 0.000064 m2
Name | Repère de pièce = Reference | Repère d'assemblage | Phase | Nom | Surface par tonne (m2) | Hauteur (mm) | Longueur (mm) | Width (mm) | NetArea (m2) | GrossArea (m2) | NetVolume (m3) = GrossVolume (m3)
3 x PLAT | 821 | K104 | 2 | PLAT | 35.6 | 136.4 | 182.5 | 136.393 | 0.0430138 | 0.0248918 | 0.000154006
5 x PLAT | 821 | K103 | 2 | PLAT | 35.6 | 136.4 | 182.5 | 136.393 | 0.0430138 | 0.0248918 | 0.000154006
2 x PLAT | 821 | K105 | 2 | PLAT | 35.6 | 136.4 | 182.5 | 136.393 | 0.0430138 | 0.0248918 | 0.000154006
GOUSSET | 813 | K38 | 1 | GOUSSET | 36.2 | 135.8 | 240 | 135.812 | 0.0422032 | 0.0325946 | 0.000148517

# IfcPlate: PL8*137 (8)
In: Undefined
Description: PL8*137; Material: STEEL/E24-2
Tekla Commun - Finition: GRENAILLE-PEINT; Repère de pièce: 818; Repère d'assemblage: B9; Phase: 2; Profil: PL8*137; Nom: GOUSSET; sets with these values: 2
Tekla Quantités - Poids: 1.2 kg; Volume: 0 m3; Surface supérieure totale: 0 m2; Surface par tonne: 35.8 m2; Surface nette: 0 m2; Hauteur: 136.9 mm; Largeur: 8 mm; Longueur: 264.4 mm; sets with these values: 2
Pset_PlateCommon - LoadBearing: no; Reference: 818
BaseQuantities - Width: 137.029 mm; NetArea: 0.0477938 m2; GrossArea: 0.0362296 m2; CrossSectionArea: 0.000064 m2; NetVolume: 0.000170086 m3; GrossVolume: 0.000170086 m3

# IfcPlate: PL8*143 (4)
In: Undefined
Description: PL8*143; Material: STEEL/S235JR
Tekla Commun - Finition: GRENAILLE-PEINT; Repère de pièce: 817; Repère d'assemblage: K33; Phase: 2; Profil: PL8*143; Nom: GOUSSET; sets with these values: 2
Tekla Quantités - Poids: 1.4 kg; Volume: 0 m3; Surface supérieure totale: 0 m2; Surface par tonne: 35.5 m2; Surface nette: 0 m2; Hauteur: 143.5 mm; Largeur: 8 mm; Longueur: 228.2 mm; sets with these values: 2
Pset_PlateCommon - LoadBearing: no; Reference: 817
BaseQuantities - Width: 143.456 mm; NetArea: 0.0486846 m2; GrossArea: 0.0327384 m2; CrossSectionArea: 0.000064 m2; NetVolume: 0.000174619 m3; GrossVolume: 0.000174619 m3

# IfcPlate: PL8*145 (2)
In: Undefined
Description: PL8*145; Material: STEEL/E24-2
Tekla Commun - Finition: GRENAILLE-PEINT; Repère de pièce: 795; Phase: 1; Profil: PL8*145; Nom: GOUSSET; sets with these values: 2
Tekla Quantités - Poids: 1.7 kg; Volume: 0 m3; Surface supérieure totale: 0 m2; Surface par tonne: 35.1 m2; Surface nette: 0.1 m2; Hauteur: 145 mm; Largeur: 8 mm; Longueur: 262.1 mm; sets with these values: 2
Pset_PlateCommon - LoadBearing: no; Reference: 795
BaseQuantities - Width: 145.013 mm; NetArea: 0.0630857 m2; GrossArea: 0.0380142 m2; CrossSectionArea: 0.000064 m2; NetVolume: 0.000229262 m3; GrossVolume: 0.000229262 m3
Name | Repère d'assemblage
GOUSSET | K28
GOUSSET | K3

# IfcPlate: PL8*148 (2)
In: Undefined
Description: PL8*148; Material: STEEL/S235JR
Tekla Commun - Finition: GRENAILLE-PEINT; Repère de pièce: 845; Phase: 2; Profil: PL8*148; Nom: GOUSSET; sets with these values: 2
Tekla Quantités - Poids: 1.1 kg; Volume: 0 m3; Surface supérieure totale: 0 m2; Surface par tonne: 36.9 m2; Surface nette: 0 m2; Hauteur: 148.3 mm; Largeur: 8 mm; Longueur: 197.1 mm; sets with these values: 2
Pset_PlateCommon - LoadBearing: no; Reference: 845
BaseQuantities - Width: 148.33 mm; NetArea: 0.039284 m2; GrossArea: 0.029232 m2; CrossSectionArea: 0.000064 m2; NetVolume: 0.000135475 m3; GrossVolume: 0.000135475 m3
Name | Repère d'assemblage
GOUSSET | K101
GOUSSET | K102

# IfcPlate: PL8*152, ATTACHE
In: Undefined
Description: PL8*152; Material: STEEL/E24-2
Tekla Commun - Finition: GRENAILLE-PEINT; Repère de pièce: 681; Repère d'assemblage: L52; Phase: 2; Profil: PL8*152; Nom: ATTACHE; sets with these values: 2
Tekla Quantités - Poids: 1.4 kg; Volume: 0 m3; Surface supérieure totale: 0 m2; Surface par tonne: 35.3 m2; Surface nette: 0.1 m2; Hauteur: 152.5 mm; Largeur: 8 mm; Longueur: 210.1 mm; sets with these values: 2
Pset_PlateCommon - LoadBearing: no; Reference: 681
BaseQuantities - Width: 152.498 mm; NetArea: 0.054038 m2; GrossArea: 0.0320349 m2; CrossSectionArea: 0.000064 m2; NetVolume: 0.000195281 m3; GrossVolume: 0.000195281 m3

# IfcPlate: PL8*160 (3)
In: Undefined
Description: PL8*160; Material: STEEL/E24-2
Tekla Commun - Finition: GRENAILLE-PEINT; Profil: PL8*160; Nom: GOUSSET; sets with these values: 2
Tekla Quantités - Volume: 0 m3; Surface supérieure totale: 0 m2; Surface nette: 0.1 m2; Largeur: 8 mm; sets with these values: 2
Pset_PlateCommon - LoadBearing: no
BaseQuantities - CrossSectionArea: 0.000064 m2
Name | Repère de pièce = Repère d'assemblage = Reference | Phase | Poids (kg) | Surface par tonne (m2) | Hauteur (mm) | Longueur (mm) | Width (mm) | NetArea (m2) | GrossArea (m2) | NetVolume (m3) = GrossVolume (m3)
GOUSSET | G63 | 3 | 2.2 | 34.5 | 160 | 237.8 | 160.001 | 0.0758783 | 0.0380494 | 0.000279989
2 x GOUSSET | G30 | 2 | 3.6 | 34.1 | 159.8 | 364.1 | 159.819 | 0.121393 | 0.058184 | 0.000453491

# IfcPlate: PL8*162 (2)
In: Undefined
Description: PL8*162; Material: STEEL/E24-2
Tekla Commun - Finition: GRENAILLE-PEINT; Repère de pièce: 798; Phase: 1; Profil: PL8*162; Nom: GOUSSET; sets with these values: 2
Tekla Quantités - Poids: 2 kg; Volume: 0 m3; Surface supérieure totale: 0 m2; Surface par tonne: 35 m2; Surface nette: 0.1 m2; Hauteur: 161.6 mm; Largeur: 8 mm; Longueur: 265.8 mm; sets with these values: 2
Pset_PlateCommon - LoadBearing: no; Reference: 798
BaseQuantities - Width: 161.561 mm; NetArea: 0.0650848 m2; GrossArea: 0.0429496 m2; CrossSectionArea: 0.000064 m2; NetVolume: 0.000236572 m3; GrossVolume: 0.000236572 m3
Name | Repère d'assemblage
GOUSSET | P8
GOUSSET | P6

# IfcPlate: PL8*163, GOUSSET
In: Undefined
Description: PL8*163; Material: STEEL/E24-2
Tekla Commun - Finition: GRENAILLE-PEINT; Repère de pièce: G53; Repère d'assemblage: G53; Phase: 1; Profil: PL8*163; Nom: GOUSSET; sets with these values: 2
Tekla Quantités - Poids: 2.4 kg; Volume: 0 m3; Surface supérieure totale: 0 m2; Surface par tonne: 34.3 m2; Surface nette: 0.1 m2; Hauteur: 162.7 mm; Largeur: 8 mm; Longueur: 295.8 mm; sets with these values: 2
Pset_PlateCommon - LoadBearing: no; Reference: G53
BaseQuantities - Width: 162.713 mm; NetArea: 0.0838812 m2; GrossArea: 0.0481361 m2; CrossSectionArea: 0.000064 m2; NetVolume: 0.000310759 m3; GrossVolume: 0.000310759 m3

# IfcPlate: PL8*169 (4)
In: Undefined
Description: PL8*169; Material: STEEL/E24-2
Tekla Commun - Finition: GRENAILLE-PEINT; Repère de pièce: G17; Repère d'assemblage: G17; Phase: 2; Profil: PL8*169; Nom: GOUSSET; sets with these values: 2
Tekla Quantités - Poids: 2.4 kg; Volume: 0 m3; Surface supérieure totale: 0 m2; Surface par tonne: 34.5 m2; Surface nette: 0.1 m2; Hauteur: 169.4 mm; Largeur: 8 mm; Longueur: 279.4 mm; sets with these values: 2
Pset_PlateCommon - LoadBearing: no; Reference: G17
BaseQuantities - Width: 169.397 mm; NetArea: 0.0832066 m2; GrossArea: 0.0473347 m2; CrossSectionArea: 0.000064 m2; NetVolume: 0.000307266 m3; GrossVolume: 0.000307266 m3

# IfcPlate: PL8*170 (6)
In: Undefined
Description: PL8*170; Material: STEEL/E24-2
Tekla Commun - Finition: GRENAILLE-PEINT; Phase: 1; Profil: PL8*170; Nom: GOUSSET; sets with these values: 2
Tekla Quantités - Volume: 0 m3; Surface supérieure totale: 0 m2; Surface nette: 0.1 m2; Largeur: 8 mm; sets with these values: 2
Pset_PlateCommon - LoadBearing: no
BaseQuantities - CrossSectionArea: 0.000064 m2
Name | Repère de pièce = Reference | Repère d'assemblage | Poids (kg) | Surface par tonne (m2) | Hauteur (mm) | Longueur (mm) | Width (mm) | NetArea (m2) | GrossArea (m2) | NetVolume (m3) = GrossVolume (m3)
GOUSSET | 772 | P24 | 2.1 | 34.6 | 169.8 | 210.8 | 169.752 | 0.0734676 | 0.0357855 | 0.000270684
2 x GOUSSET | G49 | G49 | 4.5 | 34 | 170 | 410 | 170 | 0.14868 | 0.0697 | 0.0005576
GOUSSET | 839 | N14 | 2.7 | 34.2 | 169.8 | 275.6 | 169.752 | 0.0917178 | 0.0467837 | 0.00034127
GOUSSET | 838 | N12 | 2.7 | 34.2 | 169.8 | 275.6 | 169.752 | 0.0917178 | 0.0467837 | 0.00034127
GOUSSET | 711 | N12 | 2.7 | 34.2 | 169.8 | 275.6 | 169.752 | 0.0917178 | 0.0467837 | 0.00034127

# IfcPlate: PL8*171, GOUSSET
In: Undefined
Description: PL8*171; Material: STEEL/E24-2
Tekla Commun - Finition: GRENAILLE-PEINT; Repère de pièce: 732; Repère d'assemblage: P123; Phase: 1; Profil: PL8*171; Nom: GOUSSET; sets with these values: 2
Tekla Quantités - Poids: 3.9 kg; Volume: 0 m3; Surface supérieure totale: 0 m2; Surface par tonne: 34.9 m2; Surface nette: 0.1 m2; Hauteur: 171.4 mm; Largeur: 8 mm; Longueur: 480 mm; sets with these values: 2
Pset_PlateCommon - LoadBearing: no; Reference: 732
BaseQuantities - Width: 171.374 mm; NetArea: 0.139591 m2; GrossArea: 0.0822597 m2; CrossSectionArea: 0.000064 m2; NetVolume: 0.000508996 m3; GrossVolume: 0.000508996 m3

# IfcPlate: PL8*172, GOUSSET
In: Undefined
Description: PL8*172; Material: STEEL/E24-2
Tekla Commun - Finition: GRENAILLE-PEINT; Repère de pièce: G55; Repère d'assemblage: G55; Phase: 1; Profil: PL8*172; Nom: GOUSSET; sets with these values: 2
Tekla Quantités - Poids: 2.4 kg; Volume: 0 m3; Surface supérieure totale: 0 m2; Surface par tonne: 34.3 m2; Surface nette: 0.1 m2; Hauteur: 171.6 mm; Largeur: 8 mm; Longueur: 293.2 mm; sets with these values: 2
Pset_PlateCommon - LoadBearing: no; Reference: G55
BaseQuantities - Width: 171.602 mm; NetArea: 0.085915 m2; GrossArea: 0.0503115 m2; CrossSectionArea: 0.000064 m2; NetVolume: 0.000318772 m3; GrossVolume: 0.000318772 m3

# IfcPlate: PL8*173 (4)
In: Undefined
Description: PL8*173
Tekla Commun - Finition: GRENAILLE-PEINT; Profil: PL8*173; Nom: GOUSSET; sets with these values: 2
Tekla Quantités - Poids: 1.7 kg; Volume: 0 m3; Surface supérieure totale: 0 m2; Surface nette: 0.1 m2; Hauteur: 172.8 mm; Largeur: 8 mm; sets with these values: 2
Pset_PlateCommon - LoadBearing: no
BaseQuantities - CrossSectionArea: 0.000064 m2
Name | Material | Repère de pièce = Reference | Repère d'assemblage | Phase | Surface par tonne (m2) | Longueur (mm) | Width (mm) | NetArea (m2) | GrossArea (m2) | NetVolume (m3) = GrossVolume (m3)
GOUSSET | STEEL/S235JR | 827 | K61 | 2 | 35.2 | 252.1 | 172.846 | 0.0594708 | 0.0435728 | 0.000215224
GOUSSET | STEEL/S235JR | 827 | K62 | 2 | 35.2 | 252.1 | 172.846 | 0.0594708 | 0.0435728 | 0.000215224
GOUSSET | STEEL/E24-2 | 797 | P8 | 1 | 34.9 | 207.1 | 172.874 | 0.059227 | 0.0358073 | 0.000215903
GOUSSET | STEEL/E24-2 | 797 | P6 | 1 | 34.9 | 207.1 | 172.874 | 0.059227 | 0.0358073 | 0.000215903

# IfcPlate: PL8*174 (2)
In: Undefined
Description: PL8*174; Material: STEEL/E24-2
Tekla Commun - Finition: GRENAILLE-PEINT; Phase: 1; Profil: PL8*174; sets with these values: 2
Tekla Quantités - Volume: 0 m3; Surface supérieure totale: 0 m2; Surface nette: 0.1 m2; Hauteur: 174.2 mm; Largeur: 8 mm; sets with these values: 2
Pset_PlateCommon - LoadBearing: no
BaseQuantities - Width: 174.161 mm; CrossSectionArea: 0.000064 m2
Name | Repère de pièce = Reference | Repère d'assemblage | Poids (kg) | Surface par tonne (m2) | Longueur (mm) | NetArea (m2) | GrossArea (m2) | NetVolume (m3) = GrossVolume (m3)
Unnamed | 764 | P26 | 2.4 | 34.5 | 245.4 | 0.0811223 | 0.0427397 | 0.000299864
Unnamed | 857 | P22 | 2.7 | 34.3 | 290 | 0.0919673 | 0.0505018 | 0.000341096

# IfcPlate: PL8*176 (6)
In: Undefined
Description: PL8*176; Material: STEEL/E24-2
Tekla Commun - Finition: GRENAILLE-PEINT; Profil: PL8*176; Nom: GOUSSET; sets with these values: 2
Tekla Quantités - Volume: 0 m3; Surface supérieure totale: 0 m2; Surface nette: 0.1 m2; Largeur: 8 mm; sets with these values: 2
Pset_PlateCommon - LoadBearing: no
BaseQuantities - CrossSectionArea: 0.000064 m2
Name | Repère de pièce = Repère d'assemblage = Reference | Phase | Poids (kg) | Surface par tonne (m2) | Hauteur (mm) | Longueur (mm) | Width (mm) | NetArea (m2) | GrossArea (m2) | NetVolume (m3) = GrossVolume (m3)
4 x GOUSSET | G29 | 2 | 1.4 | 35.2 | 176 | 184.5 | 176.027 | 0.0513962 | 0.0324726 | 0.000185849
GOUSSET | G51 | 1 | 2.4 | 34.3 | 176.2 | 281.1 | 176.165 | 0.0843863 | 0.0495213 | 0.000313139
GOUSSET | G50 | 1 | 2.4 | 34.3 | 176.2 | 281.1 | 176.165 | 0.0843863 | 0.0495213 | 0.000313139

# IfcPlate: PL8*182 (3)
In: Undefined
Description: PL8*182; Material: STEEL/E24-2
Tekla Commun - Finition: GRENAILLE-PEINT; Phase: 1; Profil: PL8*182; Nom: GOUSSET; sets with these values: 2
Tekla Quantités - Volume: 0 m3; Surface supérieure totale: 0 m2; Surface nette: 0.1 m2; Largeur: 8 mm; sets with these values: 2
Pset_PlateCommon - LoadBearing: no
BaseQuantities - CrossSectionArea: 0.000064 m2
Name | Repère de pièce = Repère d'assemblage = Reference | Poids (kg) | Surface par tonne (m2) | Hauteur (mm) | Longueur (mm) | Width (mm) | NetArea (m2) | GrossArea (m2) | NetVolume (m3) = GrossVolume (m3)
GOUSSET | G52 | 2.6 | 34.3 | 182.4 | 289.4 | 182.359 | 0.0877289 | 0.052773 | 0.000325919
2 x GOUSSET | G28 | 3.9 | 34 | 182.2 | 439 | 182.152 | 0.136113 | 0.0799612 | 0.000510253

# IfcPlate: PL8*183, GOUSSET
In: Undefined
Description: PL8*183; Material: STEEL/E24-2
Tekla Commun - Finition: GRENAILLE-PEINT; Repère de pièce: G5; Repère d'assemblage: G5; Phase: 1; Profil: PL8*183; Nom: GOUSSET; sets with these values: 2
Tekla Quantités - Poids: 4.6 kg; Volume: 0 m3; Surface supérieure totale: 0 m2; Surface par tonne: 33.8 m2; Surface nette: 0.2 m2; Hauteur: 183.3 mm; Largeur: 8 mm; Longueur: 410 mm; sets with these values: 2
Pset_PlateCommon - LoadBearing: no; Reference: G5
BaseQuantities - Width: 183.251 mm; NetArea: 0.156675 m2; GrossArea: 0.0751329 m2; CrossSectionArea: 0.000064 m2; NetVolume: 0.000589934 m3; GrossVolume: 0.000589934 m3

# IfcPlate: PL8*184, GOUSSET
In: Undefined
Description: PL8*184; Material: STEEL/E24-2
Tekla Commun - Finition: GRENAILLE-PEINT; Repère de pièce: G4; Repère d'assemblage: G4; Phase: 1; Profil: PL8*184; Nom: GOUSSET; sets with these values: 2
Tekla Quantités - Poids: 4.5 kg; Volume: 0 m3; Surface supérieure totale: 0 m2; Surface par tonne: 33.8 m2; Surface nette: 0.1 m2; Hauteur: 184.3 mm; Largeur: 8 mm; Longueur: 410 mm; sets with these values: 2
Pset_PlateCommon - LoadBearing: no; Reference: G4
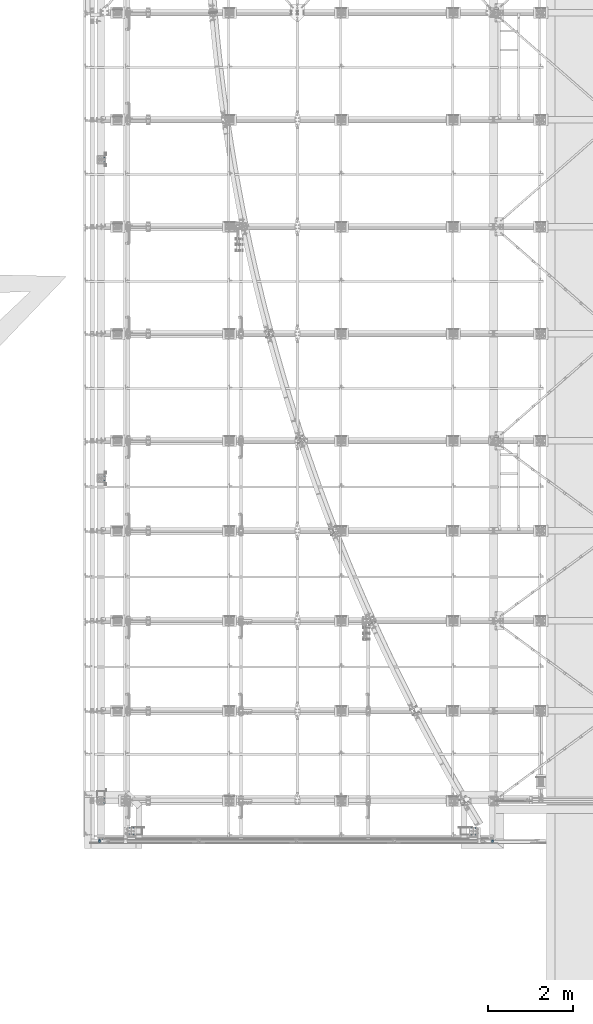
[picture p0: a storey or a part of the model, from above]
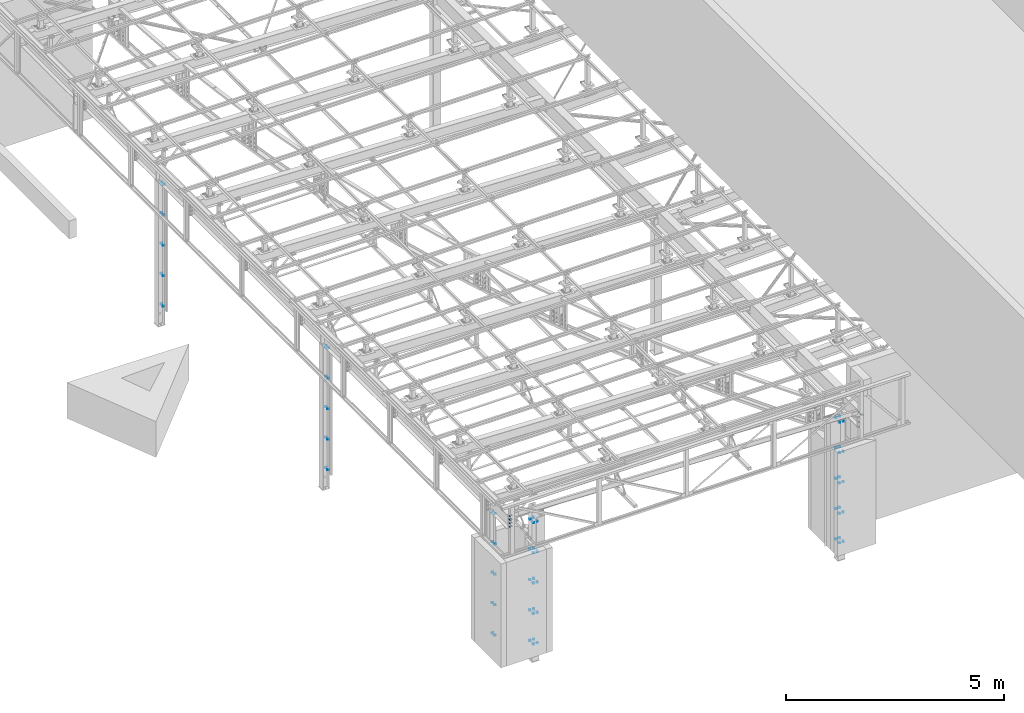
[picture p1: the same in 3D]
Properties of the parts of a building model (IFC2X3), part 13 of 13

# IfcPlate: PL8*184, GOUSSET
BaseQuantities - Width: 184.256 mm; NetArea: 0.148486 m2; GrossArea: 0.0755451 m2; CrossSectionArea: 0.000064 m2; NetVolume: 0.000557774 m3; GrossVolume: 0.000557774 m3

# IfcPlate: PL8*189 (4)
In: Undefined
Description: PL8*189; Material: STEEL/E24-2
Tekla Commun - Finition: GRENAILLE-PEINT; Profil: PL8*189; Nom: GOUSSET; sets with these values: 2
Tekla Quantités - Volume: 0 m3; Surface supérieure totale: 0 m2; Surface nette: 0.1 m2; Largeur: 8 mm; sets with these values: 2
Pset_PlateCommon - LoadBearing: no
BaseQuantities - CrossSectionArea: 0.000064 m2
Name | Repère de pièce = Reference | Repère d'assemblage | Phase | Poids (kg) | Surface par tonne (m2) | Hauteur (mm) | Longueur (mm) | Width (mm) | NetArea (m2) | GrossArea (m2) | NetVolume (m3) = GrossVolume (m3)
GOUSSET | 705 | K1 | 3 | 1.7 | 35.2 | 189.3 | 236.6 | 189.338 | 0.0590386 | 0.0447996 | 0.000213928
GOUSSET | 704 | K1 | 3 | 1.7 | 35.2 | 189.3 | 236.6 | 189.338 | 0.0590386 | 0.0447996 | 0.000213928
GOUSSET | G54 | G54 | 1 | 2.6 | 34.3 | 188.9 | 286.7 | 188.886 | 0.0880908 | 0.054163 | 0.000327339
GOUSSET | 814 | K99 | 1 | 1.7 | 35.3 | 189.1 | 250 | 189.13 | 0.062854 | 0.0472824 | 0.000226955

# IfcPlate: PL8*195 (4)
In: Undefined
Description: PL8*195; Material: STEEL/S235JR
Tekla Commun - Finition: GRENAILLE-PEINT; Repère de pièce: 730; Repère d'assemblage: K33; Phase: 2; Profil: PL8*195; Nom: GOUSSET; sets with these values: 2
Tekla Quantités - Poids: 1.4 kg; Volume: 0 m3; Surface supérieure totale: 0 m2; Surface par tonne: 36 m2; Surface nette: 0 m2; Hauteur: 195 mm; Largeur: 8 mm; Longueur: 224.6 mm; sets with these values: 2
Pset_PlateCommon - LoadBearing: no; Reference: 730
BaseQuantities - Width: 194.965 mm; NetArea: 0.049525 m2; GrossArea: 0.0437892 m2; CrossSectionArea: 0.000064 m2; NetVolume: 0.000175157 m3; GrossVolume: 0.000175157 m3

# IfcPlate: PL8*196, GOUSSET
In: Undefined
Description: PL8*196; Material: STEEL/E24-2
Tekla Commun - Finition: GRENAILLE-PEINT; Repère de pièce: 733; Repère d'assemblage: K38; Phase: 1; Profil: PL8*196; Nom: GOUSSET; sets with these values: 2
Tekla Quantités - Poids: 1.7 kg; Volume: 0 m3; Surface supérieure totale: 0 m2; Surface par tonne: 35.6 m2; Surface nette: 0.1 m2; Hauteur: 196.1 mm; Largeur: 8 mm; Longueur: 291.8 mm; sets with these values: 2
Pset_PlateCommon - LoadBearing: no; Reference: 733
BaseQuantities - Width: 196.074 mm; NetArea: 0.0637828 m2; GrossArea: 0.0572142 m2; CrossSectionArea: 0.000064 m2; NetVolume: 0.000228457 m3; GrossVolume: 0.000228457 m3

# IfcPlate: PL8*200 (3)
In: Undefined
Description: PL8*200; Material: STEEL/E24-2
Tekla Commun - Finition: GRENAILLE-PEINT; Phase: 1; Profil: PL8*200; Nom: GOUSSET; sets with these values: 2
Tekla Quantités - Volume: 0 m3; Surface supérieure totale: 0 m2; Surface nette: 0.1 m2; Hauteur: 200 mm; Largeur: 8 mm; sets with these values: 2
Pset_PlateCommon - LoadBearing: no
BaseQuantities - Width: 200 mm; CrossSectionArea: 0.000064 m2
Name | Repère de pièce = Repère d'assemblage = Reference | Poids (kg) | Surface par tonne (m2) | Longueur (mm) | NetArea (m2) | GrossArea (m2) | NetVolume (m3) = GrossVolume (m3)
GOUSSET | G14 | 2.2 | 34.6 | 212.4 | 0.0762024 | 0.042477 | 0.000280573
2 x GOUSSET | G64 | 3 | 34.3 | 304.8 | 0.0992875 | 0.0609551 | 0.000369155

# IfcPlate: PL8*203, GOUSSET
In: Undefined
Description: PL8*203; Material: STEEL/E24-2
Tekla Commun - Finition: GRENAILLE-PEINT; Repère de pièce: 804; Repère d'assemblage: N5; Phase: 1; Profil: PL8*203; Nom: GOUSSET; sets with these values: 2
Tekla Quantités - Poids: 3.7 kg; Volume: 0 m3; Surface supérieure totale: 0 m2; Surface par tonne: 34.3 m2; Surface nette: 0.1 m2; Hauteur: 203 mm; Largeur: 8 mm; Longueur: 359.3 mm; sets with these values: 2
Pset_PlateCommon - LoadBearing: no; Reference: 804
BaseQuantities - Width: 203.016 mm; NetArea: 0.125958 m2; GrossArea: 0.0729448 m2; CrossSectionArea: 0.000064 m2; NetVolume: 0.000466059 m3; GrossVolume: 0.000466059 m3

# IfcPlate: PL8*204, Unnamed
In: Undefined
Description: PL8*204; Material: STEEL/E24-2
Tekla Commun - Finition: GRENAILLE-PEINT; Repère de pièce: 856; Repère d'assemblage: P22; Phase: 1; Profil: PL8*204; sets with these values: 2
Tekla Quantités - Poids: 2 kg; Volume: 0 m3; Surface supérieure totale: 0 m2; Surface par tonne: 35.1 m2; Surface nette: 0.1 m2; Hauteur: 203.6 mm; Largeur: 8 mm; Longueur: 250 mm; sets with these values: 2
Pset_PlateCommon - LoadBearing: no; Reference: 856
BaseQuantities - Width: 203.601 mm; NetArea: 0.0669036 m2; GrossArea: 0.0509003 m2; CrossSectionArea: 0.000064 m2; NetVolume: 0.000242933 m3; GrossVolume: 0.000242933 m3

# IfcPlate: PL8*207 (4)
In: Undefined
Description: PL8*207; Material: STEEL/E24-2
Tekla Commun - Finition: GRENAILLE-PEINT; Repère de pièce: G26; Repère d'assemblage: G26; Phase: 1; Profil: PL8*207; Nom: GOUSSET; sets with these values: 2
Tekla Quantités - Poids: 2 kg; Volume: 0 m3; Surface supérieure totale: 0 m2; Surface par tonne: 34.7 m2; Surface nette: 0.1 m2; Hauteur: 206.7 mm; Largeur: 8 mm; Longueur: 220 mm; sets with these values: 2
Pset_PlateCommon - LoadBearing: no; Reference: G26
BaseQuantities - Width: 206.708 mm; NetArea: 0.0705873 m2; GrossArea: 0.0454758 m2; CrossSectionArea: 0.000064 m2; NetVolume: 0.000259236 m3; GrossVolume: 0.000259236 m3

# IfcPlate: PL8*208, GOUSSET
In: Undefined
Description: PL8*208; Material: STEEL/E24-2
Tekla Commun - Finition: GRENAILLE-PEINT; Repère de pièce: 815; Repère d'assemblage: K99; Phase: 1; Profil: PL8*208; Nom: GOUSSET; sets with these values: 2
Tekla Quantités - Poids: 5 kg; Volume: 0 m3; Surface supérieure totale: 0 m2; Surface par tonne: 33.7 m2; Surface nette: 0.2 m2; Hauteur: 208.2 mm; Largeur: 8 mm; Longueur: 411.1 mm; sets with these values: 2
Pset_PlateCommon - LoadBearing: no; Reference: 815
BaseQuantities - Width: 208.223 mm; NetArea: 0.169157 m2; GrossArea: 0.085605 m2; CrossSectionArea: 0.000064 m2; NetVolume: 0.000638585 m3; GrossVolume: 0.000638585 m3

# IfcPlate: PL8*209 (3)
In: Undefined
Description: PL8*209; Material: STEEL/E24-2
Tekla Commun - Finition: GRENAILLE-PEINT; Profil: PL8*209; Nom: GOUSSET; sets with these values: 2
Tekla Quantités - Volume: 0 m3; Surface supérieure totale: 0 m2; Largeur: 8 mm; sets with these values: 2
Pset_PlateCommon - LoadBearing: no
BaseQuantities - CrossSectionArea: 0.000064 m2
Name | Repère de pièce = Repère d'assemblage = Reference | Phase | Poids (kg) | Surface par tonne (m2) | Surface nette (m2) | Hauteur (mm) | Longueur (mm) | Width (mm) | NetArea (m2) | GrossArea (m2) | NetVolume (m3) = GrossVolume (m3)
2 x GOUSSET | G15 | 3 | 3 | 34.2 | 0.1 | 209 | 276 | 208.988 | 0.0990466 | 0.0576849 | 0.000368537
GOUSSET | G67 | 2 | 4.8 | 33.8 | 0.2 | 209.2 | 365.5 | 209.166 | 0.162109 | 0.076457 | 0.000611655

# IfcPlate: PL8*210 (11)
In: Undefined
Description: PL8*210; Material: STEEL/E24-2
Tekla Commun - Finition: GRENAILLE-PEINT; Profil: PL8*210; sets with these values: 2
Tekla Quantités - Volume: 0 m3; Surface supérieure totale: 0 m2; Surface nette: 0.1 m2; Largeur: 8 mm; sets with these values: 2
Pset_PlateCommon - LoadBearing: no
BaseQuantities - CrossSectionArea: 0.000064 m2
Name | Repère de pièce = Reference | Repère d'assemblage | Phase | Nom | Poids (kg) | Surface par tonne (m2) | Hauteur (mm) | Longueur (mm) | Width (mm) | NetArea (m2) | GrossArea (m2) | NetVolume (m3) = GrossVolume (m3)
ATTACHE | 680 | L52 | 2 | ATTACHE | 1.4 | 35.3 | 210 | 157.7 | 209.939 | 0.054168 | 0.033107 | 0.000195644
GOUSSET | 771 | P26 | 1 | GOUSSET | 3 | 34.1 | 210 | 239.7 | 210.009 | 0.101915 | 0.0503361 | 0.000380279
2 x GOUSSET | G25 | G25 | 1 | GOUSSET | 2.1 | 34.7 | 209.7 | 220 | 209.661 | 0.0712522 | 0.0461254 | 0.000261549
2 x GOUSSET | G25 | G25 | 1 | GOUSSET | 2.1 | 34.7 | 209.7 | 220 | 209.661 | 0.0712521 | 0.0461253 | 0.000261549
GOUSSET | 769 | P22 | 1 | GOUSSET | 3 | 34.1 | 210 | 239.7 | 210.009 | 0.101915 | 0.0503361 | 0.000380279
GOUSSET | 769 | P25 | 1 | GOUSSET | 3 | 34.1 | 210 | 239.7 | 210.009 | 0.101915 | 0.0503361 | 0.000380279
GOUSSET | 771 | P27 | 1 | GOUSSET | 3 | 34.1 | 210 | 239.7 | 210.009 | 0.101915 | 0.0503361 | 0.000380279
GOUSSET | 771 | P23 | 1 | GOUSSET | 3 | 34.1 | 210 | 239.7 | 210.009 | 0.101915 | 0.0503361 | 0.000380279
GOUSSET | 769 | P24 | 1 | GOUSSET | 3 | 34.1 | 210 | 239.7 | 210.009 | 0.101915 | 0.0503361 | 0.000380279

# IfcPlate: PL8*211, GOUSSET
In: Undefined
Description: PL8*211; Material: STEEL/E24-2
Tekla Commun - Finition: GRENAILLE-PEINT; Repère de pièce: G16; Repère d'assemblage: G16; Phase: 3; Profil: PL8*211; Nom: GOUSSET; sets with these values: 2
Tekla Quantités - Poids: 3 kg; Volume: 0 m3; Surface supérieure totale: 0 m2; Surface par tonne: 34.2 m2; Surface nette: 0.1 m2; Hauteur: 211.2 mm; Largeur: 8 mm; Longueur: 278.1 mm; sets with these values: 2
Pset_PlateCommon - LoadBearing: no; Reference: G16
BaseQuantities - Width: 211.158 mm; NetArea: 0.100537 m2; GrossArea: 0.058721 m2; CrossSectionArea: 0.000064 m2; NetVolume: 0.000374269 m3; GrossVolume: 0.000374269 m3

# IfcPlate: PL8*212 (5)
In: Undefined
Description: PL8*212; Material: STEEL/E24-2
Tekla Commun - Finition: GRENAILLE-PEINT; Phase: 1; Profil: PL8*212; Nom: GOUSSET; sets with these values: 2
Tekla Quantités - Poids: 3 kg; Volume: 0 m3; Surface supérieure totale: 0 m2; Surface par tonne: 34.1 m2; Surface nette: 0.1 m2; Hauteur: 211.6 mm; Largeur: 8 mm; Longueur: 239.7 mm; sets with these values: 2
Pset_PlateCommon - LoadBearing: no
BaseQuantities - Width: 211.603 mm; NetArea: 0.102714 m2; GrossArea: 0.0507216 m2; CrossSectionArea: 0.000064 m2; NetVolume: 0.00038337 m3; GrossVolume: 0.00038337 m3
Name | Repère de pièce = Reference | Repère d'assemblage
GOUSSET | 770 | P23
GOUSSET | 768 | P22
GOUSSET | 770 | P26
GOUSSET | 770 | P27
GOUSSET | 768 | P25

# IfcPlate: PL8*216, GOUSSET
In: Undefined
Description: PL8*216; Material: STEEL/E24-2
Tekla Commun - Finition: GRENAILLE-PEINT; Repère de pièce: 846; Repère d'assemblage: K99; Phase: 1; Profil: PL8*216; Nom: GOUSSET; sets with these values: 2
Tekla Quantités - Poids: 3.8 kg; Volume: 0 m3; Surface supérieure totale: 0 m2; Surface par tonne: 33.8 m2; Surface nette: 0.1 m2; Hauteur: 216 mm; Largeur: 8 mm; Longueur: 298.8 mm; sets with these values: 2
Pset_PlateCommon - LoadBearing: no; Reference: 846
BaseQuantities - Width: 216 mm; NetArea: 0.127546 m2; GrossArea: 0.064545 m2; CrossSectionArea: 0.000064 m2; NetVolume: 0.000478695 m3; GrossVolume: 0.000478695 m3

# IfcPlate: PL8*217 (52)
In: Undefined
Description: PL8*217; Material: STEEL/E24-2
Tekla Commun - Finition: GRENAILLE-PEINT; Profil: PL8*217; sets with these values: 2
Tekla Quantités - Volume: 0 m3; Surface supérieure totale: 0 m2; Surface nette: 0.1 m2; Largeur: 8 mm; sets with these values: 2
Pset_PlateCommon - LoadBearing: no
BaseQuantities - CrossSectionArea: 0.000064 m2
Name | Repère de pièce = Reference | Repère d'assemblage | Phase | Nom | Poids (kg) | Surface par tonne (m2) | Hauteur (mm) | Longueur (mm) | Width (mm) | NetArea (m2) | GrossArea (m2) | NetVolume (m3) = GrossVolume (m3)
GOUSSET | 832 | N43 | 3 | GOUSSET | 3.2 | 34 | 216.6 | 274 | 216.581 | 0.110165 | 0.0593453 | 0.000412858
GOUSSET | 844 | N46 | 2 | GOUSSET | 3.4 | 33.8 | 216.6 | 275.6 | 216.581 | 0.116209 | 0.0596908 | 0.000436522
2 x GOUSSET | 837 | N44 | 2 | GOUSSET | 3.4 | 33.8 | 216.6 | 275.6 | 216.581 | 0.116209 | 0.0596908 | 0.000436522
GOUSSET | 837 | N45 | 2 | GOUSSET | 3.4 | 33.8 | 216.6 | 275.6 | 216.581 | 0.116209 | 0.0596908 | 0.000436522
2 x GOUSSET | 836 | N49 | 2 | GOUSSET | 3.4 | 33.8 | 216.6 | 275.6 | 216.581 | 0.116209 | 0.0596908 | 0.000436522
GOUSSET | 835 | N18 | 2 | GOUSSET | 3.4 | 33.8 | 216.6 | 275.6 | 216.58 | 0.114765 | 0.0596903 | 0.00043092
GOUSSET | 830 | N15 | 3 | GOUSSET | 3.2 | 34 | 216.6 | 274 | 216.581 | 0.110165 | 0.0593453 | 0.000412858
2 x ATTACHE | 854 | P126 | 2 | ATTACHE | 1.7 | 35 | 216.8 | 200 | 216.845 | 0.062448 | 0.043369 | 0.000227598
2 x ATTACHE | 854 | P127 | 2 | ATTACHE | 1.7 | 35 | 216.8 | 200 | 216.845 | 0.062448 | 0.043369 | 0.000227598
GOUSSET | 831 | N39 | 1 | GOUSSET | 3.2 | 34 | 216.6 | 274 | 216.581 | 0.110165 | 0.0593453 | 0.000412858
GOUSSET | 843 | N7 | 1 | GOUSSET | 3.4 | 33.8 | 216.6 | 275.6 | 216.581 | 0.116209 | 0.0596908 | 0.000436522
GOUSSET | 842 | N11 | 1 | GOUSSET | 3.4 | 33.8 | 216.6 | 275.6 | 216.581 | 0.116209 | 0.0596908 | 0.000436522
GOUSSET | 840 | N7 | 1 | GOUSSET | 3.4 | 33.8 | 216.6 | 275.6 | 216.581 | 0.116209 | 0.0596908 | 0.000436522
GOUSSET | 841 | N7 | 1 | GOUSSET | 3.4 | 33.8 | 216.6 | 275.6 | 216.581 | 0.116209 | 0.0596908 | 0.000436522
2 x GOUSSET | 837 | N6 | 1 | GOUSSET | 3.4 | 33.8 | 216.6 | 275.6 | 216.581 | 0.116209 | 0.0596908 | 0.000436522
2 x GOUSSET | 837 | N13 | 1 | GOUSSET | 3.4 | 33.8 | 216.6 | 275.6 | 216.581 | 0.116209 | 0.0596908 | 0.000436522
GOUSSET | 837 | N43 | 3 | GOUSSET | 3.4 | 33.8 | 216.6 | 275.6 | 216.581 | 0.116209 | 0.0596908 | 0.000436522
2 x GOUSSET | 837 | N40 | 3 | GOUSSET | 3.4 | 33.8 | 216.6 | 275.6 | 216.581 | 0.116209 | 0.0596908 | 0.000436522
GOUSSET | 837 | N9 | 3 | GOUSSET | 3.4 | 33.8 | 216.6 | 275.6 | 216.581 | 0.116209 | 0.0596908 | 0.000436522
2 x GOUSSET | 830 | N16 | 1 | GOUSSET | 3.2 | 34 | 216.6 | 274 | 216.581 | 0.110165 | 0.0593453 | 0.000412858
2 x GOUSSET | 836 | N48 | 3 | GOUSSET | 3.4 | 33.8 | 216.6 | 275.6 | 216.581 | 0.116209 | 0.0596908 | 0.000436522
GOUSSET | 835 | N15 | 3 | GOUSSET | 3.4 | 33.8 | 216.6 | 275.6 | 216.58 | 0.114765 | 0.0596903 | 0.00043092
2 x GOUSSET | 835 | N16 | 1 | GOUSSET | 3.4 | 33.8 | 216.6 | 275.6 | 216.58 | 0.114765 | 0.0596903 | 0.00043092
4 x GOUSSET | 836 | N47 | 1 | GOUSSET | 3.4 | 33.8 | 216.6 | 275.6 | 216.581 | 0.116209 | 0.0596908 | 0.000436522
2 x GOUSSET | 837 | N10 | 1 | GOUSSET | 3.4 | 33.8 | 216.6 | 275.6 | 216.581 | 0.116209 | 0.0596908 | 0.000436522
4 x GOUSSET | 837 | N8 | 1 | GOUSSET | 3.4 | 33.8 | 216.6 | 275.6 | 216.581 | 0.116209 | 0.0596908 | 0.000436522
4 x GOUSSET | 837 | N41 | 1 | GOUSSET | 3.4 | 33.8 | 216.6 | 275.6 | 216.581 | 0.116209 | 0.0596908 | 0.000436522
GOUSSET | 837 | N42 | 1 | GOUSSET | 3.4 | 33.8 | 216.6 | 275.6 | 216.581 | 0.116209 | 0.0596908 | 0.000436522
GOUSSET | 831 | N38 | 1 | GOUSSET | 3.2 | 34 | 216.6 | 274 | 216.581 | 0.110165 | 0.0593453 | 0.000412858
GOUSSET | 840 | N11 | 1 | GOUSSET | 3.4 | 33.8 | 216.6 | 275.6 | 216.581 | 0.116209 | 0.0596908 | 0.000436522
GOUSSET | 831 | N17 | 1 | GOUSSET | 3.2 | 34 | 216.6 | 274 | 216.581 | 0.110165 | 0.0593453 | 0.000412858
GOUSSET | 830 | N14 | 1 | GOUSSET | 3.2 | 34 | 216.6 | 274 | 216.581 | 0.110165 | 0.0593453 | 0.000412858

# IfcPlate: PL8*219, GOUSSET
In: Undefined
Description: PL8*219; Material: STEEL/E24-2
Tekla Commun - Finition: GRENAILLE-PEINT; Repère de pièce: G61; Repère d'assemblage: G61; Phase: 1; Profil: PL8*219; Nom: GOUSSET; sets with these values: 2
Tekla Quantités - Poids: 2.4 kg; Volume: 0 m3; Surface supérieure totale: 0 m2; Surface par tonne: 34.5 m2; Surface nette: 0.1 m2; Hauteur: 219.4 mm; Largeur: 8 mm; Longueur: 240 mm; sets with these values: 2
Pset_PlateCommon - LoadBearing: no; Reference: G61
BaseQuantities - Width: 219.415 mm; NetArea: 0.0813768 m2; GrossArea: 0.0526596 m2; CrossSectionArea: 0.000064 m2; NetVolume: 0.00030051 m3; GrossVolume: 0.00030051 m3

# IfcPlate: PL8*220 (2)
In: Undefined
Description: PL8*220; Material: STEEL/E24-2
Tekla Commun - Finition: GRENAILLE-PEINT; Repère de pièce: G8; Repère d'assemblage: G8; Phase: 3; Profil: PL8*220; Nom: GOUSSET; sets with these values: 2
Tekla Quantités - Poids: 3.3 kg; Volume: 0 m3; Surface supérieure totale: 0 m2; Surface par tonne: 34.1 m2; Surface nette: 0.1 m2; Hauteur: 220 mm; Largeur: 8 mm; Longueur: 300.4 mm; sets with these values: 2
Pset_PlateCommon - LoadBearing: no; Reference: G8
BaseQuantities - Width: 220 mm; NetArea: 0.113769 m2; CrossSectionArea: 0.000064 m2
Name | GrossArea (m2) | NetVolume (m3) = GrossVolume (m3)
GOUSSET | 0.0660977 | 0.000425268
GOUSSET | 0.0660978 | 0.000425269

# IfcPlate: PL8*221 (2)
In: Undefined
Description: PL8*221; Material: STEEL/E24-2
Tekla Commun - Finition: GRENAILLE-PEINT; Phase: 1; Profil: PL8*221; Nom: GOUSSET; sets with these values: 2
Tekla Quantités - Volume: 0 m3; Surface supérieure totale: 0 m2; Surface par tonne: 34.3 m2; Surface nette: 0.1 m2; Largeur: 8 mm; sets with these values: 2
Pset_PlateCommon - LoadBearing: no
BaseQuantities - CrossSectionArea: 0.000064 m2
Name | Repère de pièce = Reference | Repère d'assemblage | Poids (kg) | Hauteur (mm) | Longueur (mm) | Width (mm) | NetArea (m2) | GrossArea (m2) | NetVolume (m3) = GrossVolume (m3)
GOUSSET | G62 | G62 | 2.6 | 220.5 | 270 | 220.511 | 0.090728 | 0.0595379 | 0.00033627
GOUSSET | 735 | K38 | 3.6 | 220.8 | 473.2 | 220.767 | 0.124912 | 0.104468 | 0.000462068

# IfcPlate: PL8*222, GOUSSET
In: Undefined
Description: PL8*222; Material: STEEL/E24-2
Tekla Commun - Finition: GRENAILLE-PEINT; Repère de pièce: G33; Repère d'assemblage: G33; Phase: 1; Profil: PL8*222; Nom: GOUSSET; sets with these values: 2
Tekla Quantités - Poids: 5.7 kg; Volume: 0 m3; Surface supérieure totale: 0 m2; Surface par tonne: 33.6 m2; Surface nette: 0.2 m2; Hauteur: 221.8 mm; Largeur: 8 mm; Longueur: 420.4 mm; sets with these values: 2
Pset_PlateCommon - LoadBearing: no; Reference: G33
BaseQuantities - Width: 221.821 mm; NetArea: 0.189987 m2; GrossArea: 0.0932438 m2; CrossSectionArea: 0.000064 m2; NetVolume: 0.000719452 m3; GrossVolume: 0.000719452 m3

# IfcPlate: PL8*226 (4)
In: Undefined
Description: PL8*226; Material: STEEL/E24-2
Tekla Commun - Finition: GRENAILLE-PEINT; Phase: 1; Profil: PL8*226; sets with these values: 2
Tekla Quantités - Volume: 0 m3; Surface supérieure totale: 0 m2; Surface nette: 0.1 m2; Largeur: 8 mm; sets with these values: 2
Pset_PlateCommon - LoadBearing: no
BaseQuantities - CrossSectionArea: 0.000064 m2
Name | Repère de pièce = Reference | Repère d'assemblage | Poids (kg) | Surface par tonne (m2) | Hauteur (mm) | Longueur (mm) | Width (mm) | NetArea (m2) | GrossArea (m2) | NetVolume (m3) = GrossVolume (m3) | Nom
Unnamed | 763 | P27 | 2 | 34.7 | 225.9 | 200 | 225.929 | 0.0684284 | 0.0451858 | 0.000250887
GOUSSET | 833 | N17 | 3.8 | 34.1 | 225.5 | 411.7 | 225.513 | 0.127967 | 0.0928391 | 0.000478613 | GOUSSET
GOUSSET | 833 | N39 | 3.8 | 34.1 | 225.5 | 411.7 | 225.513 | 0.127967 | 0.0928391 | 0.000478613 | GOUSSET
GOUSSET | 833 | N38 | 3.8 | 34.1 | 225.5 | 411.7 | 225.513 | 0.127967 | 0.0928391 | 0.000478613 | GOUSSET

# IfcPlate: PL8*227 (2)
In: Undefined
Description: PL8*227; Material: STEEL/E24-2
Tekla Commun - Finition: GRENAILLE-PEINT; Repère de pièce: 850; Profil: PL8*227; Nom: GOUSSET; sets with these values: 2
Tekla Quantités - Poids: 2.7 kg; Volume: 0 m3; Surface supérieure totale: 0 m2; Surface par tonne: 34.7 m2; Surface nette: 0.1 m2; Hauteur: 226.6 mm; Largeur: 8 mm; Longueur: 215.3 mm; sets with these values: 2
Pset_PlateCommon - LoadBearing: no; Reference: 850
BaseQuantities - Width: 226.604 mm; NetArea: 0.09245 m2; GrossArea: 0.0487921 m2; CrossSectionArea: 0.000064 m2; NetVolume: 0.000339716 m3; GrossVolume: 0.000339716 m3
Name | Repère d'assemblage | Phase
GOUSSET | P119 | 2
GOUSSET | P113 | 3

# IfcPlate: PL8*229 (18)
In: Undefined
Description: PL8*229; Material: STEEL/E24-2
Tekla Commun - Finition: GRENAILLE-PEINT; Profil: PL8*229; Nom: GOUSSET; sets with these values: 2
Tekla Quantités - Poids: 2 kg; Volume: 0 m3; Surface supérieure totale: 0 m2; Surface par tonne: 34.9 m2; Surface nette: 0.1 m2; Hauteur: 228.6 mm; Largeur: 8 mm; Longueur: 230 mm; sets with these values: 2
Pset_PlateCommon - LoadBearing: no
BaseQuantities - Width: 228.608 mm; NetArea: 0.0705625 m2; GrossArea: 0.0525571 m2; CrossSectionArea: 0.000064 m2; NetVolume: 0.000258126 m3; GrossVolume: 0.000258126 m3
Name | Repère de pièce = Repère d'assemblage = Reference | Phase
5 x GOUSSET | G34 | 3
2 x GOUSSET | G35 | 3
8 x GOUSSET | G34 | 1
2 x GOUSSET | G35 | 1
GOUSSET | G36 | 1

# IfcPlate: PL8*235, Unnamed
In: Undefined
Description: PL8*235; Material: STEEL/E24-2
Tekla Commun - Finition: GRENAILLE-PEINT; Repère de pièce: 765; Repère d'assemblage: P26; Phase: 1; Profil: PL8*235; sets with these values: 2
Tekla Quantités - Poids: 2.1 kg; Volume: 0 m3; Surface supérieure totale: 0 m2; Surface par tonne: 34.7 m2; Surface nette: 0.1 m2; Hauteur: 235 mm; Largeur: 8 mm; Longueur: 200 mm; sets with these values: 2
Pset_PlateCommon - LoadBearing: no; Reference: 765
BaseQuantities - Width: 235.036 mm; NetArea: 0.07148 m2; GrossArea: 0.0470072 m2; CrossSectionArea: 0.000064 m2; NetVolume: 0.000262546 m3; GrossVolume: 0.000262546 m3

# IfcPlate: PL8*237, GOUSSET
In: Undefined
Description: PL8*237; Material: STEEL/E24-2
Tekla Commun - Finition: GRENAILLE-PEINT; Repère de pièce: 710; Repère d'assemblage: K28; Phase: 1; Profil: PL8*237; Nom: GOUSSET; sets with these values: 2
Tekla Quantités - Poids: 3.7 kg; Volume: 0 m3; Surface supérieure totale: 0 m2; Surface par tonne: 34.1 m2; Surface nette: 0.1 m2; Hauteur: 236.9 mm; Largeur: 8 mm; Longueur: 383.6 mm; sets with these values: 2
Pset_PlateCommon - LoadBearing: no; Reference: 710
BaseQuantities - Width: 236.95 mm; NetArea: 0.126317 m2; GrossArea: 0.0908905 m2; CrossSectionArea: 0.000064 m2; NetVolume: 0.000471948 m3; GrossVolume: 0.000471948 m3

# IfcPlate: PL8*239, Unnamed
In: Undefined
Description: PL8*239; Material: STEEL/E24-2
Tekla Commun - Finition: GRENAILLE-PEINT; Repère de pièce: 766; Repère d'assemblage: P27; Phase: 1; Profil: PL8*239; sets with these values: 2
Tekla Quantités - Poids: 2 kg; Volume: 0 m3; Surface supérieure totale: 0 m2; Surface par tonne: 34.9 m2; Surface nette: 0.1 m2; Hauteur: 238.9 mm; Largeur: 8 mm; Longueur: 165.6 mm; sets with these values: 2
Pset_PlateCommon - LoadBearing: no; Reference: 766
BaseQuantities - Width: 238.877 mm; NetArea: 0.069587 m2; GrossArea: 0.0395488 m2; CrossSectionArea: 0.000064 m2; NetVolume: 0.00025501 m3; GrossVolume: 0.00025501 m3

# IfcPlate: PL8*242, GOUSSET
In: Undefined
Description: PL8*242; Material: STEEL/E24-2
Tekla Commun - Finition: GRENAILLE-PEINT; Repère de pièce: 773; Repère d'assemblage: P113; Phase: 3; Profil: PL8*242; Nom: GOUSSET; sets with these values: 2
Tekla Quantités - Poids: 3.9 kg; Volume: 0 m3; Surface supérieure totale: 0 m2; Surface par tonne: 34 m2; Surface nette: 0.1 m2; Hauteur: 241.8 mm; Largeur: 8 mm; Longueur: 408.6 mm; sets with these values: 2
Pset_PlateCommon - LoadBearing: no; Reference: 773
BaseQuantities - Width: 241.829 mm; NetArea: 0.136701 m2; GrossArea: 0.0988208 m2; CrossSectionArea: 0.000064 m2; NetVolume: 0.000511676 m3; GrossVolume: 0.000511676 m3

# IfcPlate: PL8*243, GOUSSET
In: Undefined
Description: PL8*243; Material: STEEL/E24-2
Tekla Commun - Finition: GRENAILLE-PEINT; Repère de pièce: G13; Repère d'assemblage: G13; Phase: 3; Profil: PL8*243; Nom: GOUSSET; sets with these values: 2
Tekla Quantités - Poids: 4.8 kg; Volume: 0 m3; Surface supérieure totale: 0 m2; Surface par tonne: 33.8 m2; Surface nette: 0.2 m2; Hauteur: 242.8 mm; Largeur: 8 mm; Longueur: 464.2 mm; sets with these values: 2
Pset_PlateCommon - LoadBearing: no; Reference: G13
BaseQuantities - Width: 242.764 mm; NetArea: 0.161485 m2; GrossArea: 0.112688 m2; CrossSectionArea: 0.000064 m2; NetVolume: 0.000608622 m3; GrossVolume: 0.000608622 m3

# IfcPlate: PL8*245 (2)
In: Undefined
Description: PL8*245; Material: STEEL/E24-2
Tekla Commun - Finition: GRENAILLE-PEINT; Repère de pièce: 803; Phase: 1; Profil: PL8*245; Nom: GOUSSET; sets with these values: 2
Tekla Quantités - Poids: 2 kg; Volume: 0 m3; Surface supérieure totale: 0 m2; Surface par tonne: 35.3 m2; Surface nette: 0.1 m2; Hauteur: 244.6 mm; Largeur: 8 mm; Longueur: 266.3 mm; sets with these values: 2
Pset_PlateCommon - LoadBearing: no; Reference: 803
BaseQuantities - CrossSectionArea: 0.000064 m2
Name | Repère d'assemblage | Width (mm) | NetArea (m2) | GrossArea (m2) | NetVolume (m3) = GrossVolume (m3)
GOUSSET | K8 | 244.559 | 0.0721149 | 0.0651351 | 0.00026054
GOUSSET | K54 | 244.557 | 0.0721141 | 0.0651343 | 0.000260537

# IfcPlate: PL8*248 (31)
In: Undefined
Description: PL8*248; Material: STEEL/E24-2
Tekla Commun - Finition: GRENAILLE-PEINT; Profil: PL8*248; Nom: GOUSSET; sets with these values: 2
Tekla Quantités - Volume: 0 m3; Surface supérieure totale: 0 m2; Surface par tonne: 33.5 m2; Surface nette: 0.2 m2; Hauteur: 247.5 mm; Largeur: 8 mm; Longueur: 410 mm; sets with these values: 2
Pset_PlateCommon - LoadBearing: no
BaseQuantities - Width: 247.54 mm; NetArea: 0.213503 m2; GrossArea: 0.101492 m2; CrossSectionArea: 0.000064 m2; NetVolume: 0.000811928 m3; GrossVolume: 0.000811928 m3
Name | Repère de pièce = Repère d'assemblage = Reference | Phase | Poids (kg)
3 x GOUSSET | G48 | 3 | 6.5
2 x GOUSSET | G47 | 3 | 6.5
16 x GOUSSET | G48 | 1 | 6.3
4 x GOUSSET | G48 | 3 | 6.3
2 x GOUSSET | G47 | 3 | 6.3
4 x GOUSSET | G47 | 1 | 6.3

# IfcPlate: PL8*262, GOUSSET
In: Undefined
Description: PL8*262; Material: STEEL/E24-2
Tekla Commun - Finition: GRENAILLE-PEINT; Repère de pièce: 805; Repère d'assemblage: P123; Phase: 1; Profil: PL8*262; Nom: GOUSSET; sets with these values: 2
Tekla Quantités - Poids: 2.6 kg; Volume: 0 m3; Surface supérieure totale: 0 m2; Surface par tonne: 34.5 m2; Surface nette: 0.1 m2; Hauteur: 261.7 mm; Largeur: 8 mm; Longueur: 262.7 mm; sets with these values: 2
Pset_PlateCommon - LoadBearing: no; Reference: 805
BaseQuantities - Width: 261.668 mm; NetArea: 0.0891965 m2; GrossArea: 0.0687357 m2; CrossSectionArea: 0.000064 m2; NetVolume: 0.000329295 m3; GrossVolume: 0.000329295 m3

# IfcPlate: PL8*275, GOUSSET
In: Undefined
Description: PL8*275; Material: STEEL/E24-2
Tekla Commun - Finition: GRENAILLE-PEINT; Repère de pièce: G31; Repère d'assemblage: G31; Phase: 1; Profil: PL8*275; Nom: GOUSSET; sets with these values: 2
Tekla Quantités - Poids: 6.7 kg; Volume: 0 m3; Surface supérieure totale: 0 m2; Surface par tonne: 33.4 m2; Surface nette: 0.2 m2; Hauteur: 275.4 mm; Largeur: 8 mm; Longueur: 410 mm; sets with these values: 2
Pset_PlateCommon - LoadBearing: no; Reference: G31
BaseQuantities - Width: 275.351 mm; NetArea: 0.219828 m2; GrossArea: 0.112894 m2; CrossSectionArea: 0.000064 m2; NetVolume: 0.000837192 m3; GrossVolume: 0.000837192 m3

# IfcPlate: PL8*276, GOUSSET
In: Undefined
Description: PL8*276; Material: STEEL/E24-2
Tekla Commun - Finition: GRENAILLE-PEINT; Repère de pièce: 734; Repère d'assemblage: K28; Phase: 1; Profil: PL8*276; Nom: GOUSSET; sets with these values: 2
Tekla Quantités - Poids: 2.6 kg; Volume: 0 m3; Surface supérieure totale: 0 m2; Surface par tonne: 34.9 m2; Surface nette: 0.1 m2; Hauteur: 276.3 mm; Largeur: 8 mm; Longueur: 294.4 mm; sets with these values: 2
Pset_PlateCommon - LoadBearing: no; Reference: 734
BaseQuantities - Width: 276.334 mm; NetArea: 0.0891424 m2; GrossArea: 0.0813473 m2; CrossSectionArea: 0.000064 m2; NetVolume: 0.000325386 m3; GrossVolume: 0.000325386 m3

# IfcPlate: PL8*278 (8)
In: Undefined
Description: PL8*278; Material: STEEL/E24-2
Tekla Commun - Finition: GRENAILLE-PEINT; Profil: PL8*278; Nom: GOUSSET; sets with these values: 2
Tekla Quantités - Poids: 6.8 kg; Volume: 0 m3; Surface supérieure totale: 0 m2; Surface par tonne: 33.4 m2; Surface nette: 0.2 m2; Hauteur: 278 mm; Largeur: 8 mm; Longueur: 405.1 mm; sets with these values: 2
Pset_PlateCommon - LoadBearing: no
BaseQuantities - Width: 278.009 mm; NetArea: 0.227791 m2; GrossArea: 0.112615 m2; CrossSectionArea: 0.000064 m2; NetVolume: 0.000868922 m3; GrossVolume: 0.000868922 m3
Name | Repère de pièce = Repère d'assemblage = Reference | Phase
GOUSSET | G7 | 3
2 x GOUSSET | G2 | 3
3 x GOUSSET | G3 | 1
2 x GOUSSET | G2 | 1

# IfcPlate: PL8*281, Unnamed
In: Undefined
Description: PL8*281; Material: STEEL/E24-2
Tekla Commun - Finition: GRENAILLE-PEINT; Repère de pièce: 858; Repère d'assemblage: P25; Phase: 1; Profil: PL8*281; sets with these values: 2
Tekla Quantités - Poids: 2.4 kg; Volume: 0 m3; Surface supérieure totale: 0 m2; Surface par tonne: 34.3 m2; Surface nette: 0.1 m2; Hauteur: 280.6 mm; Largeur: 8 mm; Longueur: 200 mm; sets with these values: 2
Pset_PlateCommon - LoadBearing: no; Reference: 858
BaseQuantities - Width: 280.589 mm; NetArea: 0.0867702 m2; GrossArea: 0.0561178 m2; CrossSectionArea: 0.000064 m2; NetVolume: 0.000320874 m3; GrossVolume: 0.000320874 m3

# IfcPlate: PL8*290, Unnamed
In: Undefined
Description: PL8*290; Material: STEEL/E24-2
Tekla Commun - Finition: GRENAILLE-PEINT; Repère de pièce: 859; Repère d'assemblage: P25; Phase: 1; Profil: PL8*290; sets with these values: 2
Tekla Quantités - Poids: 2.4 kg; Volume: 0 m3; Surface supérieure totale: 0 m2; Surface par tonne: 34.3 m2; Surface nette: 0.1 m2; Hauteur: 290.2 mm; Largeur: 8 mm; Longueur: 165.6 mm; sets with these values: 2
Pset_PlateCommon - LoadBearing: no; Reference: 859
BaseQuantities - Width: 290.193 mm; NetArea: 0.0851141 m2; GrossArea: 0.0480444 m2; CrossSectionArea: 0.000064 m2; NetVolume: 0.000314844 m3; GrossVolume: 0.000314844 m3

# IfcPlate: PL8*307, GOUSSET
In: Undefined
Description: PL8*307; Material: STEEL/E24-2
Tekla Commun - Finition: GRENAILLE-PEINT; Repère de pièce: G46; Repère d'assemblage: G46; Phase: 1; Profil: PL8*307; Nom: GOUSSET; sets with these values: 2
Tekla Quantités - Poids: 7.2 kg; Volume: 0 m3; Surface supérieure totale: 0 m2; Surface par tonne: 33.4 m2; Surface nette: 0.2 m2; Hauteur: 306.9 mm; Largeur: 8 mm; Longueur: 369.5 mm; sets with these values: 2
Pset_PlateCommon - LoadBearing: no; Reference: G46
BaseQuantities - Width: 306.901 mm; NetArea: 0.237644 m2; GrossArea: 0.11341 m2; CrossSectionArea: 0.000064 m2; NetVolume: 0.000907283 m3; GrossVolume: 0.000907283 m3

# IfcPlate: PL8*308 (4)
In: Undefined
Description: PL8*308; Material: STEEL/E24-2
Tekla Commun - Finition: GRENAILLE-PEINT; Phase: 1; Profil: PL8*308; Nom: GOUSSET; sets with these values: 2
Tekla Quantités - Volume: 0 m3; Surface supérieure totale: 0 m2; Largeur: 8 mm; sets with these values: 2
Pset_PlateCommon - LoadBearing: no
BaseQuantities - CrossSectionArea: 0.000064 m2
Name | Repère de pièce = Repère d'assemblage = Reference | Poids (kg) | Surface par tonne (m2) | Surface nette (m2) | Hauteur (mm) | Longueur (mm) | Width (mm) | NetArea (m2) | GrossArea (m2) | NetVolume (m3) = GrossVolume (m3)
GOUSSET | G12 | 4.5 | 33.7 | 0.1 | 307.8 | 314.3 | 307.839 | 0.148415 | 0.0967549 | 0.000560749
2 x GOUSSET | G21 | 9.7 | 33.2 | 0.3 | 308.5 | 501.2 | 308.482 | 0.322181 | 0.154614 | 0.0012369
GOUSSET | G66 | 11.8 | 33.1 | 0.3 | 308.5 | 707 | 308.482 | 0.395104 | 0.218066 | 0.00152027

# IfcPlate: PL8*310, GOUSSET
In: Undefined
Description: PL8*310; Material: STEEL/E24-2
Tekla Commun - Finition: GRENAILLE-PEINT; Repère de pièce: G24; Repère d'assemblage: G24; Phase: 1; Profil: PL8*310; Nom: GOUSSET; sets with these values: 2
Tekla Quantités - Poids: 6.2 kg; Volume: 0 m3; Surface supérieure totale: 0 m2; Surface par tonne: 33.5 m2; Surface nette: 0.2 m2; Hauteur: 310 mm; Largeur: 8 mm; Longueur: 367 mm; sets with these values: 2
Pset_PlateCommon - LoadBearing: no; Reference: G24
BaseQuantities - Width: 310.031 mm; NetArea: 0.204631 m2; GrossArea: 0.113779 m2; CrossSectionArea: 0.000064 m2; NetVolume: 0.000778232 m3; GrossVolume: 0.000778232 m3

# IfcPlate: PL8*315, GOUSSET
In: Undefined
Description: PL8*315; Material: STEEL/E24-2
Tekla Commun - Finition: GRENAILLE-PEINT; Repère de pièce: G56; Repère d'assemblage: G56; Phase: 1; Profil: PL8*315; Nom: GOUSSET; sets with these values: 2
Tekla Quantités - Poids: 5.5 kg; Volume: 0 m3; Surface supérieure totale: 0 m2; Surface par tonne: 33.6 m2; Surface nette: 0.2 m2; Hauteur: 314.9 mm; Largeur: 8 mm; Longueur: 397.4 mm; sets with these values: 2
Pset_PlateCommon - LoadBearing: no; Reference: G56
BaseQuantities - Width: 314.886 mm; NetArea: 0.184814 m2; GrossArea: 0.125122 m2; CrossSectionArea: 0.000064 m2; NetVolume: 0.00070058 m3; GrossVolume: 0.00070058 m3

# IfcPlate: PL8*332 (2)
In: Undefined
Description: PL8*332; Material: STEEL/E24-2
Tekla Commun - Finition: GRENAILLE-PEINT; Repère de pièce: G58; Repère d'assemblage: G58; Phase: 2; Profil: PL8*332; Nom: GOUSSET; sets with these values: 2
Tekla Quantités - Poids: 7.8 kg; Volume: 0 m3; Surface supérieure totale: 0 m2; Surface par tonne: 33.4 m2; Surface nette: 0.3 m2; Hauteur: 332.5 mm; Largeur: 8 mm; Longueur: 374.2 mm; sets with these values: 2
Pset_PlateCommon - LoadBearing: no; Reference: G58
BaseQuantities - Width: 332.47 mm; NetArea: 0.260133 m2; GrossArea: 0.124413 m2; CrossSectionArea: 0.000064 m2; NetVolume: 0.000995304 m3; GrossVolume: 0.000995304 m3

# IfcPlate: PL8*335 (2)
In: Undefined
Description: PL8*335; Material: STEEL/E24-2
Tekla Commun - Finition: GRENAILLE-PEINT; Phase: 1; Profil: PL8*335; Nom: GOUSSET; sets with these values: 2
Tekla Quantités - Poids: 7.8 kg; Volume: 0 m3; Surface supérieure totale: 0 m2; Surface par tonne: 33.4 m2; Surface nette: 0.3 m2; Hauteur: 335.4 mm; Largeur: 8 mm; sets with these values: 2
Pset_PlateCommon - LoadBearing: no
BaseQuantities - Width: 335.412 mm; CrossSectionArea: 0.000064 m2
Name | Repère de pièce = Repère d'assemblage = Reference | Longueur (mm) | NetArea (m2) | GrossArea (m2) | NetVolume (m3) = GrossVolume (m3)
GOUSSET | G45 | 376.6 | 0.264039 | 0.126323 | 0.00101059
GOUSSET | G44 | 371.6 | 0.260605 | 0.124646 | 0.00099717

# IfcPlate: PL8*345, GOUSSET
In: Undefined
Description: PL8*345; Material: STEEL/E24-2
Tekla Commun - Finition: GRENAILLE-PEINT; Repère de pièce: G57; Repère d'assemblage: G57; Phase: 1; Profil: PL8*345; Nom: GOUSSET; sets with these values: 2
Tekla Quantités - Poids: 5.2 kg; Volume: 0 m3; Surface supérieure totale: 0 m2; Surface par tonne: 33.6 m2; Surface nette: 0.2 m2; Hauteur: 345.3 mm; Largeur: 8 mm; Longueur: 394.8 mm; sets with these values: 2
Pset_PlateCommon - LoadBearing: no; Reference: G57
BaseQuantities - Width: 345.293 mm; NetArea: 0.175148 m2; GrossArea: 0.13632 m2; CrossSectionArea: 0.000064 m2; NetVolume: 0.000663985 m3; GrossVolume: 0.000663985 m3

# IfcPlate: PL8*358 (18)
In: Undefined
Description: PL8*358; Material: STEEL/E24-2
Tekla Commun - Finition: GRENAILLE-PEINT; Profil: PL8*358; Nom: GOUSSET; sets with these values: 2
Tekla Quantités - Volume: 0 m3; Surface supérieure totale: 0 m2; Surface nette: 0.3 m2; Hauteur: 357.9 mm; Largeur: 8 mm; sets with these values: 2
Pset_PlateCommon - LoadBearing: no
BaseQuantities - Width: 357.929 mm; CrossSectionArea: 0.000064 m2
Name | Repère de pièce = Repère d'assemblage = Reference | Phase | Poids (kg) | Surface par tonne (m2) | Longueur (mm) | NetArea (m2) | GrossArea (m2) | NetVolume (m3) = GrossVolume (m3)
4 x GOUSSET | G41 | 3 | 9.7 | 33.1 | 434.2 | 0.323513 | 0.155419 | 0.00124335
2 x GOUSSET | G40 | 3 | 9.4 | 33.2 | 434.2 | 0.312854 | 0.155419 | 0.00120163
2 x GOUSSET | G39 | 3 | 9 | 33.2 | 405.1 | 0.302186 | 0.144989 | 0.00115991
4 x GOUSSET | G39 | 1 | 9 | 33.2 | 405.1 | 0.302186 | 0.144989 | 0.00115991
2 x GOUSSET | G40 | 1 | 9.4 | 33.2 | 434.2 | 0.312854 | 0.155419 | 0.00120163
4 x GOUSSET | G41 | 1 | 9.7 | 33.1 | 434.2 | 0.323513 | 0.155419 | 0.00124335

# IfcPlate: PL8*360, GOUSSET
In: Undefined
Description: PL8*360; Material: STEEL/E24-2
Tekla Commun - Finition: GRENAILLE-PEINT; Repère de pièce: G38; Repère d'assemblage: G38; Phase: 1; Profil: PL8*360; Nom: GOUSSET; sets with these values: 2
Tekla Quantités - Poids: 9.7 kg; Volume: 0 m3; Surface supérieure totale: 0 m2; Surface par tonne: 33.4 m2; Surface nette: 0.3 m2; Hauteur: 359.7 mm; Largeur: 8 mm; Longueur: 693.9 mm; sets with these values: 2
Pset_PlateCommon - LoadBearing: no; Reference: G38
BaseQuantities - Width: 359.705 mm; NetArea: 0.323789 m2; GrossArea: 0.24959 m2; CrossSectionArea: 0.000064 m2; NetVolume: 0.00123987 m3; GrossVolume: 0.00123987 m3

# IfcPlate: PL8*361 (30)
In: Undefined
Description: PL8*361; Material: STEEL/E24-2
Tekla Commun - Finition: GRENAILLE-PEINT; Repère de pièce: G42; Repère d'assemblage: G42; Profil: PL8*361; Nom: GOUSSET; sets with these values: 2
Tekla Quantités - Poids: 9 kg; Volume: 0 m3; Surface supérieure totale: 0 m2; Surface par tonne: 33.2 m2; Surface nette: 0.3 m2; Hauteur: 361.3 mm; Largeur: 8 mm; Longueur: 402.1 mm; sets with these values: 2
Pset_PlateCommon - LoadBearing: no; Reference: G42
BaseQuantities - Width: 361.329 mm; NetArea: 0.302794 m2; GrossArea: 0.14529 m2; CrossSectionArea: 0.000064 m2; NetVolume: 0.00116232 m3; GrossVolume: 0.00116232 m3
Name | Phase
9 x GOUSSET | 3
21 x GOUSSET | 1

# IfcPlate: PL8*368 (9)
In: Undefined
Description: PL8*368; Material: STEEL/E24-2
Tekla Commun - Finition: GRENAILLE-PEINT; Phase: 1; Profil: PL8*368; Nom: GOUSSET; sets with these values: 2
Tekla Quantités - Volume: 0 m3; Surface supérieure totale: 0 m2; Surface nette: 0.3 m2; Largeur: 8 mm; sets with these values: 2
Pset_PlateCommon - LoadBearing: no
BaseQuantities - CrossSectionArea: 0.000064 m2
Name | Repère de pièce = Repère d'assemblage = Reference | Poids (kg) | Surface par tonne (m2) | Hauteur (mm) | Longueur (mm) | Width (mm) | NetArea (m2) | GrossArea (m2) | NetVolume (m3) = GrossVolume (m3)
3 x GOUSSET | G1 | 7.5 | 33.4 | 367.6 | 410 | 367.596 | 0.250421 | 0.150714 | 0.000957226
6 x GOUSSET | G43 | 9.2 | 33.2 | 367.9 | 396.2 | 367.889 | 0.303739 | 0.145757 | 0.00116605

# IfcPlate: PL8*375 (2)
In: Undefined
Description: PL8*375; Material: STEEL/E24-2
Tekla Commun - Finition: GRENAILLE-PEINT; Profil: PL8*375; Nom: GOUSSET; sets with these values: 2
Tekla Quantités - Volume: 0 m3; Surface supérieure totale: 0 m2; Surface nette: 0.3 m2; Hauteur: 374.6 mm; Largeur: 8 mm; sets with these values: 2
Pset_PlateCommon - LoadBearing: no
BaseQuantities - CrossSectionArea: 0.000064 m2
Name | Repère de pièce = Repère d'assemblage = Reference | Phase | Poids (kg) | Surface par tonne (m2) | Longueur (mm) | Width (mm) | NetArea (m2) | GrossArea (m2) | NetVolume (m3) = GrossVolume (m3)
GOUSSET | G23 | 3 | 9.4 | 33.2 | 403.7 | 374.648 | 0.314829 | 0.151234 | 0.00120951
GOUSSET | G65 | 1 | 10.6 | 33.1 | 475.3 | 374.621 | 0.351092 | 0.178058 | 0.00135247

# IfcPlate: PL8*376 (2)
In: Undefined
Description: PL8*376; Material: STEEL/E24-2
Tekla Commun - Finition: GRENAILLE-PEINT; Phase: 3; Profil: PL8*376; Nom: GOUSSET; sets with these values: 2
Tekla Quantités - Volume: 0 m3; Surface supérieure totale: 0 m2; Largeur: 8 mm; sets with these values: 2
Pset_PlateCommon - LoadBearing: no
BaseQuantities - CrossSectionArea: 0.000064 m2
Name | Repère de pièce = Repère d'assemblage = Reference | Poids (kg) | Surface par tonne (m2) | Surface nette (m2) | Hauteur (mm) | Longueur (mm) | Width (mm) | NetArea (m2) | GrossArea (m2) | NetVolume (m3) = GrossVolume (m3)
GOUSSET | G6 | 6.7 | 33.5 | 0.2 | 376 | 470.9 | 375.962 | 0.225094 | 0.177045 | 0.000856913
GOUSSET | G68 | 9.2 | 33.2 | 0.3 | 375.8 | 402.1 | 375.77 | 0.308649 | 0.151096 | 0.00118554

# IfcPlate: PL8*378, GOUSSET
In: Undefined
Description: PL8*378; Material: STEEL/E24-2
Tekla Commun - Finition: GRENAILLE-PEINT; Repère de pièce: 799; Repère d'assemblage: B4; Phase: 1; Profil: PL8*378; Nom: GOUSSET; sets with these values: 2
Tekla Quantités - Poids: 11.5 kg; Volume: 0 m3; Surface supérieure totale: 0 m2; Surface par tonne: 33 m2; Surface nette: 0.3 m2; Hauteur: 377.6 mm; Largeur: 8 mm; Longueur: 558.9 mm; sets with these values: 2
Pset_PlateCommon - LoadBearing: no; Reference: 799
BaseQuantities - Width: 377.635 mm; NetArea: 0.381126 m2; GrossArea: 0.211062 m2; CrossSectionArea: 0.000064 m2; NetVolume: 0.00146989 m3; GrossVolume: 0.00146989 m3

# IfcPlate: PL8*382, GOUSSET
In: Undefined
Description: PL8*382; Material: STEEL/E24-2
Tekla Commun - Finition: GRENAILLE-PEINT; Repère de pièce: G22; Repère d'assemblage: G22; Phase: 3; Profil: PL8*382; Nom: GOUSSET; sets with these values: 2
Tekla Quantités - Poids: 9.4 kg; Volume: 0 m3; Surface supérieure totale: 0 m2; Surface par tonne: 33.2 m2; Surface nette: 0.3 m2; Hauteur: 381.6 mm; Largeur: 8 mm; Longueur: 397.4 mm; sets with these values: 2
Pset_PlateCommon - LoadBearing: no; Reference: G22
BaseQuantities - Width: 381.602 mm; NetArea: 0.315472 m2; GrossArea: 0.151657 m2; CrossSectionArea: 0.000064 m2; NetVolume: 0.00121206 m3; GrossVolume: 0.00121206 m3

# IfcPlate: PL8*388 (3)
In: Undefined
Description: PL8*388; Material: STEEL/E24-2
Tekla Commun - Finition: GRENAILLE-PEINT; Repère de pièce: G32; Repère d'assemblage: G32; Phase: 1; Profil: PL8*388; Nom: GOUSSET; sets with these values: 2
Tekla Quantités - Poids: 10.1 kg; Volume: 0 m3; Surface supérieure totale: 0 m2; Surface par tonne: 33.1 m2; Surface nette: 0.3 m2; Hauteur: 388.1 mm; Largeur: 8 mm; Longueur: 571 mm; sets with these values: 2
Pset_PlateCommon - LoadBearing: no; Reference: G32
BaseQuantities - Width: 388.115 mm; NetArea: 0.3345 m2; GrossArea: 0.221605 m2; CrossSectionArea: 0.000064 m2; NetVolume: 0.00128668 m3; GrossVolume: 0.00128668 m3

# IfcPlate: PL8*404 (2)
In: Undefined
Description: PL8*404; Material: STEEL/E24-2
Tekla Commun - Finition: GRENAILLE-PEINT; Repère de pièce: G11; Repère d'assemblage: G11; Phase: 3; Profil: PL8*404; Nom: GOUSSET; sets with these values: 2
Tekla Quantités - Poids: 9.7 kg; Volume: 0 m3; Surface supérieure totale: 0 m2; Surface par tonne: 33.1 m2; Surface nette: 0.3 m2; Hauteur: 404.4 mm; Largeur: 8 mm; Longueur: 405.1 mm; sets with these values: 2
Pset_PlateCommon - LoadBearing: no; Reference: G11
BaseQuantities - Width: 404.409 mm; GrossArea: 0.163817 m2; CrossSectionArea: 0.000064 m2; NetVolume: 0.00123522 m3; GrossVolume: 0.00123522 m3
Name | NetArea (m2)
GOUSSET | 0.321105
GOUSSET | 0.321104

# IfcPlate: PL8*410 (8)
In: Undefined
Description: PL8*410; Material: STEEL/E24-2
Tekla Commun - Finition: GRENAILLE-PEINT; Profil: PL8*410; Nom: GOUSSET; sets with these values: 2
Tekla Quantités - Volume: 0 m3; Surface supérieure totale: 0 m2; Surface nette: 0.3 m2; Hauteur: 410 mm; Largeur: 8 mm; sets with these values: 2
Pset_PlateCommon - LoadBearing: no
BaseQuantities - Width: 410 mm; CrossSectionArea: 0.000064 m2
Name | Repère de pièce = Repère d'assemblage = Reference | Phase | Poids (kg) | Surface par tonne (m2) | Longueur (mm) | NetArea (m2) | GrossArea (m2) | NetVolume (m3) = GrossVolume (m3)
GOUSSET | G37 | 3 | 10.1 | 33.1 | 493.8 | 0.333443 | 0.202464 | 0.00128345
2 x GOUSSET | G9 | 3 | 8.4 | 33.4 | 417.3 | 0.280626 | 0.171086 | 0.00107489
2 x GOUSSET | G59 | 2 | 7.7 | 33.4 | 342.5 | 0.254875 | 0.140413 | 0.000976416
2 x GOUSSET | G9 | 1 | 8.4 | 33.4 | 417.3 | 0.280626 | 0.171086 | 0.00107489
GOUSSET | G10 | 1 | 7.8 | 33.4 | 429 | 0.264801 | 0.175873 | 0.00101196

# IfcPlate: PL8*45 (2)
In: Undefined
Description: PL8*45; Material: STEEL/S235JR
Tekla Commun - Finition: GRENAILLE-PEINT; Repère de pièce: 682; Repère d'assemblage: L52; Phase: 2; Profil: PL8*45; Nom: TOLE; sets with these values: 2
Tekla Quantités - Poids: 0.2 kg; Volume: 0 m3; Surface supérieure totale: 0 m2; Surface par tonne: 40.7 m2; Surface nette: 0 m2; Hauteur: 45 mm; Largeur: 8 mm; Longueur: 79 mm; sets with these values: 2
Pset_PlateCommon - LoadBearing: no; Reference: 682
BaseQuantities - Width: 45 mm; NetArea: 0.00850341 m2; GrossArea: 0.003555 m2; CrossSectionArea: 0.000064 m2; NetVolume: 0.00002664 m3; GrossVolume: 0.00002664 m3

# IfcPlate: PL8*49 (9)
In: Undefined
Description: PL8*49; Material: STEEL/E24-2
Tekla Commun - Finition: GRENAILLE-PEINT; Repère de pièce: 852; Repère d'assemblage: L118; Phase: 2; Profil: PL8*49; Nom: PLAT; sets with these values: 2
Tekla Quantités - Poids: 1.2 kg; Volume: 0 m3; Surface supérieure totale: 0 m2; Surface par tonne: 37.7 m2; Surface nette: 0 m2; Hauteur: 49 mm; Largeur: 8 mm; Longueur: 380 mm; sets with these values: 2
Pset_PlateCommon - LoadBearing: no; Reference: 852
BaseQuantities - Width: 49 mm; NetArea: 0.044104 m2; GrossArea: 0.01862 m2; CrossSectionArea: 0.000064 m2; NetVolume: 0.00014896 m3; GrossVolume: 0.00014896 m3

# IfcPlate: PL8*69 (10)
In: Undefined
Description: PL8*69
Tekla Commun - Finition: GRENAILLE-PEINT; Profil: PL8*69; Nom: ATTACHE; sets with these values: 2
Tekla Quantités - Poids: 0.6 kg; Volume: 0 m3; Surface supérieure totale: 0 m2; Surface par tonne: 37 m2; Surface nette: 0 m2; Hauteur: 68.9 mm; Largeur: 8 mm; Longueur: 170 mm; sets with these values: 2
Pset_PlateCommon - LoadBearing: no
BaseQuantities - Width: 68.95 mm; NetArea: 0.0272658 m2; GrossArea: 0.0117213 m2; CrossSectionArea: 0.000064 m2; NetVolume: 0.0000937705 m3; GrossVolume: 0.0000937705 m3
Name | Material | Repère de pièce = Reference | Repère d'assemblage | Phase
ATTACHE | STEEL/E24-2 | 713 | H1 | 3
6 x ATTACHE | STEEL/S235JR | 738 | H6 | 1
3 x ATTACHE | STEEL/S235JR | 724 | H5 | 3

# IfcPlate: PL8*79 (2)
In: Undefined
Description: PL8*79; Material: STEEL/S235JR
Tekla Commun - Finition: GRENAILLE-PEINT; Repère de pièce: 679; Repère d'assemblage: L52; Phase: 2; Profil: PL8*79; Nom: TOLE; sets with these values: 2
Tekla Quantités - Poids: 0.6 kg; Volume: 0 m3; Surface supérieure totale: 0 m2; Surface par tonne: 37.5 m2; Surface nette: 0 m2; Hauteur: 79 mm; Largeur: 8 mm; Longueur: 200 mm; sets with these values: 2
Pset_PlateCommon - LoadBearing: no; Reference: 679
BaseQuantities - Width: 79 mm; NetArea: 0.0260859 m2; GrossArea: 0.0158 m2; CrossSectionArea: 0.000064 m2; NetVolume: 0.0000886 m3; GrossVolume: 0.0000886 m3

# IfcPlate: PL8*80 (24)
In: Undefined
Description: PL8*80
Tekla Commun - Finition: GRENAILLE-PEINT; Profil: PL8*80; sets with these values: 2
Tekla Quantités - Volume: 0 m3; Surface supérieure totale: 0 m2; Surface nette: 0 m2; Hauteur: 80 mm; Largeur: 8 mm; sets with these values: 2
Pset_PlateCommon - LoadBearing: no
BaseQuantities - CrossSectionArea: 0.000064 m2
Name | Material | Repère de pièce = Reference | Repère d'assemblage | Phase | Nom | Poids (kg) | Surface par tonne (m2) | Longueur (mm) | Width (mm) | NetArea (m2) | GrossArea (m2) | NetVolume (m3) = GrossVolume (m3)
GOUSSET | STEEL/S235JR | 758 | K60 | 2 | GOUSSET | 0.6 | 36.7 | 148.1 | 80 | 0.0262899 | 0.0118473 | 0.0000912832
GOUSSET | STEEL/S235JR | 758 | K67 | 2 | GOUSSET | 0.6 | 36.7 | 148.1 | 80 | 0.0262899 | 0.0118473 | 0.0000912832
GOUSSET | STEEL/S235JR | 758 | K64 | 2 | GOUSSET | 0.6 | 36.7 | 148.1 | 80 | 0.0262899 | 0.0118473 | 0.0000912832
GOUSSET | STEEL/S235JR | 758 | K70 | 2 | GOUSSET | 0.6 | 36.7 | 148.1 | 80 | 0.0262899 | 0.0118473 | 0.0000912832
GOUSSET | STEEL/S235JR | 758 | K72 | 2 | GOUSSET | 0.6 | 36.7 | 148.1 | 80 | 0.0262899 | 0.0118473 | 0.0000912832
GOUSSET | STEEL/S235JR | 758 | K63 | 2 | GOUSSET | 0.6 | 36.7 | 148.1 | 80 | 0.0262899 | 0.0118473 | 0.0000912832
GOUSSET | STEEL/S235JR | 758 | K68(?) | 2 | GOUSSET | 0.6 | 36.7 | 148.1 | 80 | 0.0262899 | 0.0118473 | 0.0000912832
GOUSSET | STEEL/S235JR | 758 | K66 | 2 | GOUSSET | 0.6 | 36.7 | 148.1 | 80 | 0.0262899 | 0.0118473 | 0.0000912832
2 x GOUSSET | STEEL/S235JR | 758 | K71 | 2 | GOUSSET | 0.6 | 36.7 | 148.1 | 80 | 0.0262899 | 0.0118473 | 0.0000912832
GOUSSET | STEEL/S235JR | 758 | K65 | 2 | GOUSSET | 0.6 | 36.7 | 148.1 | 80 | 0.0262899 | 0.0118473 | 0.0000912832
GOUSSET | STEEL/S235JR | 758 | K69 | 2 | GOUSSET | 0.6 | 36.7 | 148.1 | 80 | 0.0262899 | 0.0118473 | 0.0000912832
GOUSSET | STEEL/S235JR | 758 | K61 | 2 | GOUSSET | 0.6 | 36.7 | 148.1 | 80 | 0.0262899 | 0.0118473 | 0.0000912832
GOUSSET | STEEL/S235JR | 758 | K62 | 2 | GOUSSET | 0.6 | 36.7 | 148.1 | 80 | 0.0262899 | 0.0118473 | 0.0000912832
2 x Unnamed | STEEL/E24-2 | 723 | B5 | 1 |  | 0.5 | 37.8 | 161 | 79.903 | 0.0205358 | 0.0128579 | 0.000069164
4 x Unnamed | STEEL/E24-2 | 723 | B7 | 3 |  | 0.5 | 37.8 | 161 | 79.903 | 0.0205358 | 0.0128579 | 0.000069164
2 x Unnamed | STEEL/E24-2 | 723 | B8 | 1 |  | 0.5 | 37.8 | 161 | 79.903 | 0.0205358 | 0.0128579 | 0.000069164
2 x Unnamed | STEEL/E24-2 | 723 | B7 | 1 |  | 0.5 | 37.8 | 161 | 79.903 | 0.0205358 | 0.0128579 | 0.000069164

# IfcPlate: PL8*90 (3)
In: Undefined
Description: PL8*90; Material: STEEL/E24-2
Tekla Commun - Finition: GRENAILLE-PEINT; Repère de pièce: 714; Phase: 1; Profil: PL8*90; Nom: GOUSSET; sets with these values: 2
Tekla Quantités - Poids: 2.1 kg; Volume: 0 m3; Surface supérieure totale: 0 m2; Surface par tonne: 35.3 m2; Surface nette: 0.1 m2; Hauteur: 90 mm; Largeur: 8 mm; Longueur: 371.8 mm; sets with these values: 2
Pset_PlateCommon - LoadBearing: no; Reference: 714
BaseQuantities - Width: 90.0093 mm; NetArea: 0.0733269 m2; GrossArea: 0.0334654 m2; CrossSectionArea: 0.000064 m2; NetVolume: 0.000264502 m3; GrossVolume: 0.000264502 m3
Name | Repère d'assemblage
GOUSSET | P37
GOUSSET | P1
GOUSSET | P2

# IfcPlate: PL8*95 (10)
In: Undefined
Description: PL8*95; Material: STEEL/S235JR
Tekla Commun - Finition: GRENAILLE-PEINT; Repère de pièce: 829; Phase: 2; Profil: PL8*95; Nom: TOLE; sets with these values: 2
Tekla Quantités - Poids: 0.9 kg; Volume: 0 m3; Surface supérieure totale: 0 m2; Surface par tonne: 36 m2; Surface nette: 0 m2; Hauteur: 95 mm; Largeur: 8 mm; Longueur: 168 mm; sets with these values: 2
Pset_PlateCommon - LoadBearing: no; Reference: 829
BaseQuantities - Width: 95 mm; NetArea: 0.0346437 m2; GrossArea: 0.01596 m2; CrossSectionArea: 0.000064 m2; NetVolume: 0.00012268 m3; GrossVolume: 0.00012268 m3
Name | Repère d'assemblage
3 x TOLE | N1
2 x TOLE | N2
3 x TOLE | N4
2 x TOLE | N3

# IfcSlab: PL180*5080, MACONNERIE
In: Undefined
Description: PL180*5080; PredefinedType: FLOOR; Material: CONCRETE/BETON COURANT
Tekla Commun - Repère de pièce: Z4; Repère d'assemblage: Z4; Phase: 10; Profil: PL180*5080; Nom: MACONNERIE; sets with these values: 2
Tekla Quantités - Poids: 38088 kg; Volume: 18.1 m3; Surface supérieure totale: 100.8 m2; Surface par tonne: 5.4 m2; Surface nette: 210.5 m2; Hauteur: 5080 mm; Largeur: 180 mm; Longueur: 19835 mm; sets with these values: 2
Pset_SlabCommon - LoadBearing: no; Reference: Z4
BaseQuantities - Width: 180 mm; NetVolume: 18.1371 m3; NetArea: 100.762 m2; NetWeight: 38088 kg

# IfcSlab: PL200*1595, MACONNERIE
In: Undefined
Description: PL200*1595; PredefinedType: FLOOR; Material: CONCRETE/BETON COURANT
Tekla Commun - Repère de pièce: Z25; Repère d'assemblage: Z25; Phase: 10; Profil: PL200*1595; Nom: MACONNERIE; sets with these values: 2
Tekla Quantités - Poids: 4893.7 kg; Volume: 2.3 m3; Surface supérieure totale: 11.7 m2; Surface par tonne: 5.4 m2; Surface nette: 26.9 m2; Hauteur: 1595 mm; Largeur: 200 mm; Longueur: 7305.1 mm; sets with these values: 2
Pset_SlabCommon - LoadBearing: no; Reference: Z25
BaseQuantities - Width: 200 mm; NetVolume: 2.33031 m3; NetArea: 11.6516 m2; NetWeight: 4893.65 kg

# IfcSlab: PL200*5600, MACONNERIE
In: Undefined
Description: PL200*5600; PredefinedType: FLOOR; Material: CONCRETE/BETON COURANT
Tekla Commun - Repère de pièce: Z43; Repère d'assemblage: Z43; Phase: 10; Profil: PL200*5600; Nom: MACONNERIE; sets with these values: 2
Tekla Quantités - Poids: 16981.4 kg; Volume: 8.1 m3; Surface supérieure totale: 40.4 m2; Surface par tonne: 5.1 m2; Surface nette: 86 m2; Hauteur: 5600 mm; Largeur: 200 mm; Longueur: 7220 mm; sets with these values: 2
Pset_SlabCommon - LoadBearing: no; Reference: Z43
BaseQuantities - Width: 200 mm; NetVolume: 8.0864 m3; NetArea: 40.432 m2; NetWeight: 16981.4 kg

# IfcSlab: PL200*8285, MACONNERIE
In: Undefined
Description: PL200*8285; PredefinedType: FLOOR; Material: CONCRETE/BETON COURANT
Tekla Commun - Repère de pièce: Z46; Repère d'assemblage: Z46; Phase: 10; Profil: PL200*8285; Nom: MACONNERIE; sets with these values: 2
Tekla Quantités - Poids: 64365.8 kg; Volume: 30.7 m3; Surface supérieure totale: 153.3 m2; Surface par tonne: 4.9 m2; Surface nette: 321.2 m2; Hauteur: 8285 mm; Largeur: 200 mm; Longueur: 19835 mm; sets with these values: 2
Pset_SlabCommon - LoadBearing: no; Reference: Z46
BaseQuantities - Width: 200 mm; NetVolume: 30.6504 m3; NetArea: 153.252 m2; NetWeight: 64365.8 kg

# IfcSlab: PL220*7305, MACONNERIE
In: Undefined
Description: PL220*7305; PredefinedType: FLOOR; Material: CONCRETE/BETON COURANT
Tekla Commun - Repère de pièce: Z62; Repère d'assemblage: Z62; Phase: 10; Profil: PL220*7305; Nom: MACONNERIE; sets with these values: 2
Tekla Quantités - Poids: 67546.4 kg; Volume: 32.2 m3; Surface supérieure totale: 146.2 m2; Surface par tonne: 4.6 m2; Surface nette: 308.7 m2; Hauteur: 7305.1 mm; Largeur: 220 mm; Longueur: 21430 mm; sets with these values: 2
Pset_SlabCommon - LoadBearing: no; Reference: Z62
BaseQuantities - Width: 220 mm; NetVolume: 32.165 m3; NetArea: 146.204 m2; NetWeight: 67546.4 kg

# IfcSlab: PL6140*600, MACONNERIE
In: Undefined
Description: PL6140*600; PredefinedType: FLOOR; Material: CONCRETE/BETON COURANT
Tekla Commun - Repère de pièce: Z66; Repère d'assemblage: Z66; Phase: 10; Profil: PL6140*600; Nom: MACONNERIE; sets with these values: 2
Tekla Quantités - Poids: 3842.4 kg; Volume: 1.8 m3; Surface supérieure totale: 0.4 m2; Surface par tonne: 4.3 m2; Surface nette: 16.4 m2; Hauteur: 600 mm; Largeur: 6140 mm; Longueur: 690 mm; sets with these values: 2
Pset_SlabCommon - LoadBearing: no; Reference: Z66
BaseQuantities - Width: 6140 mm; NetVolume: 1.82972 m3; NetArea: 0.298 m2; NetWeight: 3842.41 kg

# IfcSlab: PL6140*800, MACONNERIE
In: Undefined
Description: PL6140*800; PredefinedType: FLOOR; Material: CONCRETE/BETON COURANT
Tekla Commun - Repère de pièce: Z65; Repère d'assemblage: Z65; Phase: 10; Profil: PL6140*800; Nom: MACONNERIE; sets with these values: 2
Tekla Quantités - Poids: 5157.6 kg; Volume: 2.4 m3; Surface supérieure totale: 0.4 m2; Surface par tonne: 4 m2; Surface nette: 20.4 m2; Hauteur: 800 mm; Largeur: 6140 mm; Longueur: 800 mm; sets with these values: 2
Pset_SlabCommon - LoadBearing: no; Reference: Z65
BaseQuantities - Width: 6140 mm; NetVolume: 2.456 m3; NetArea: 0.4 m2; NetWeight: 5157.6 kg
